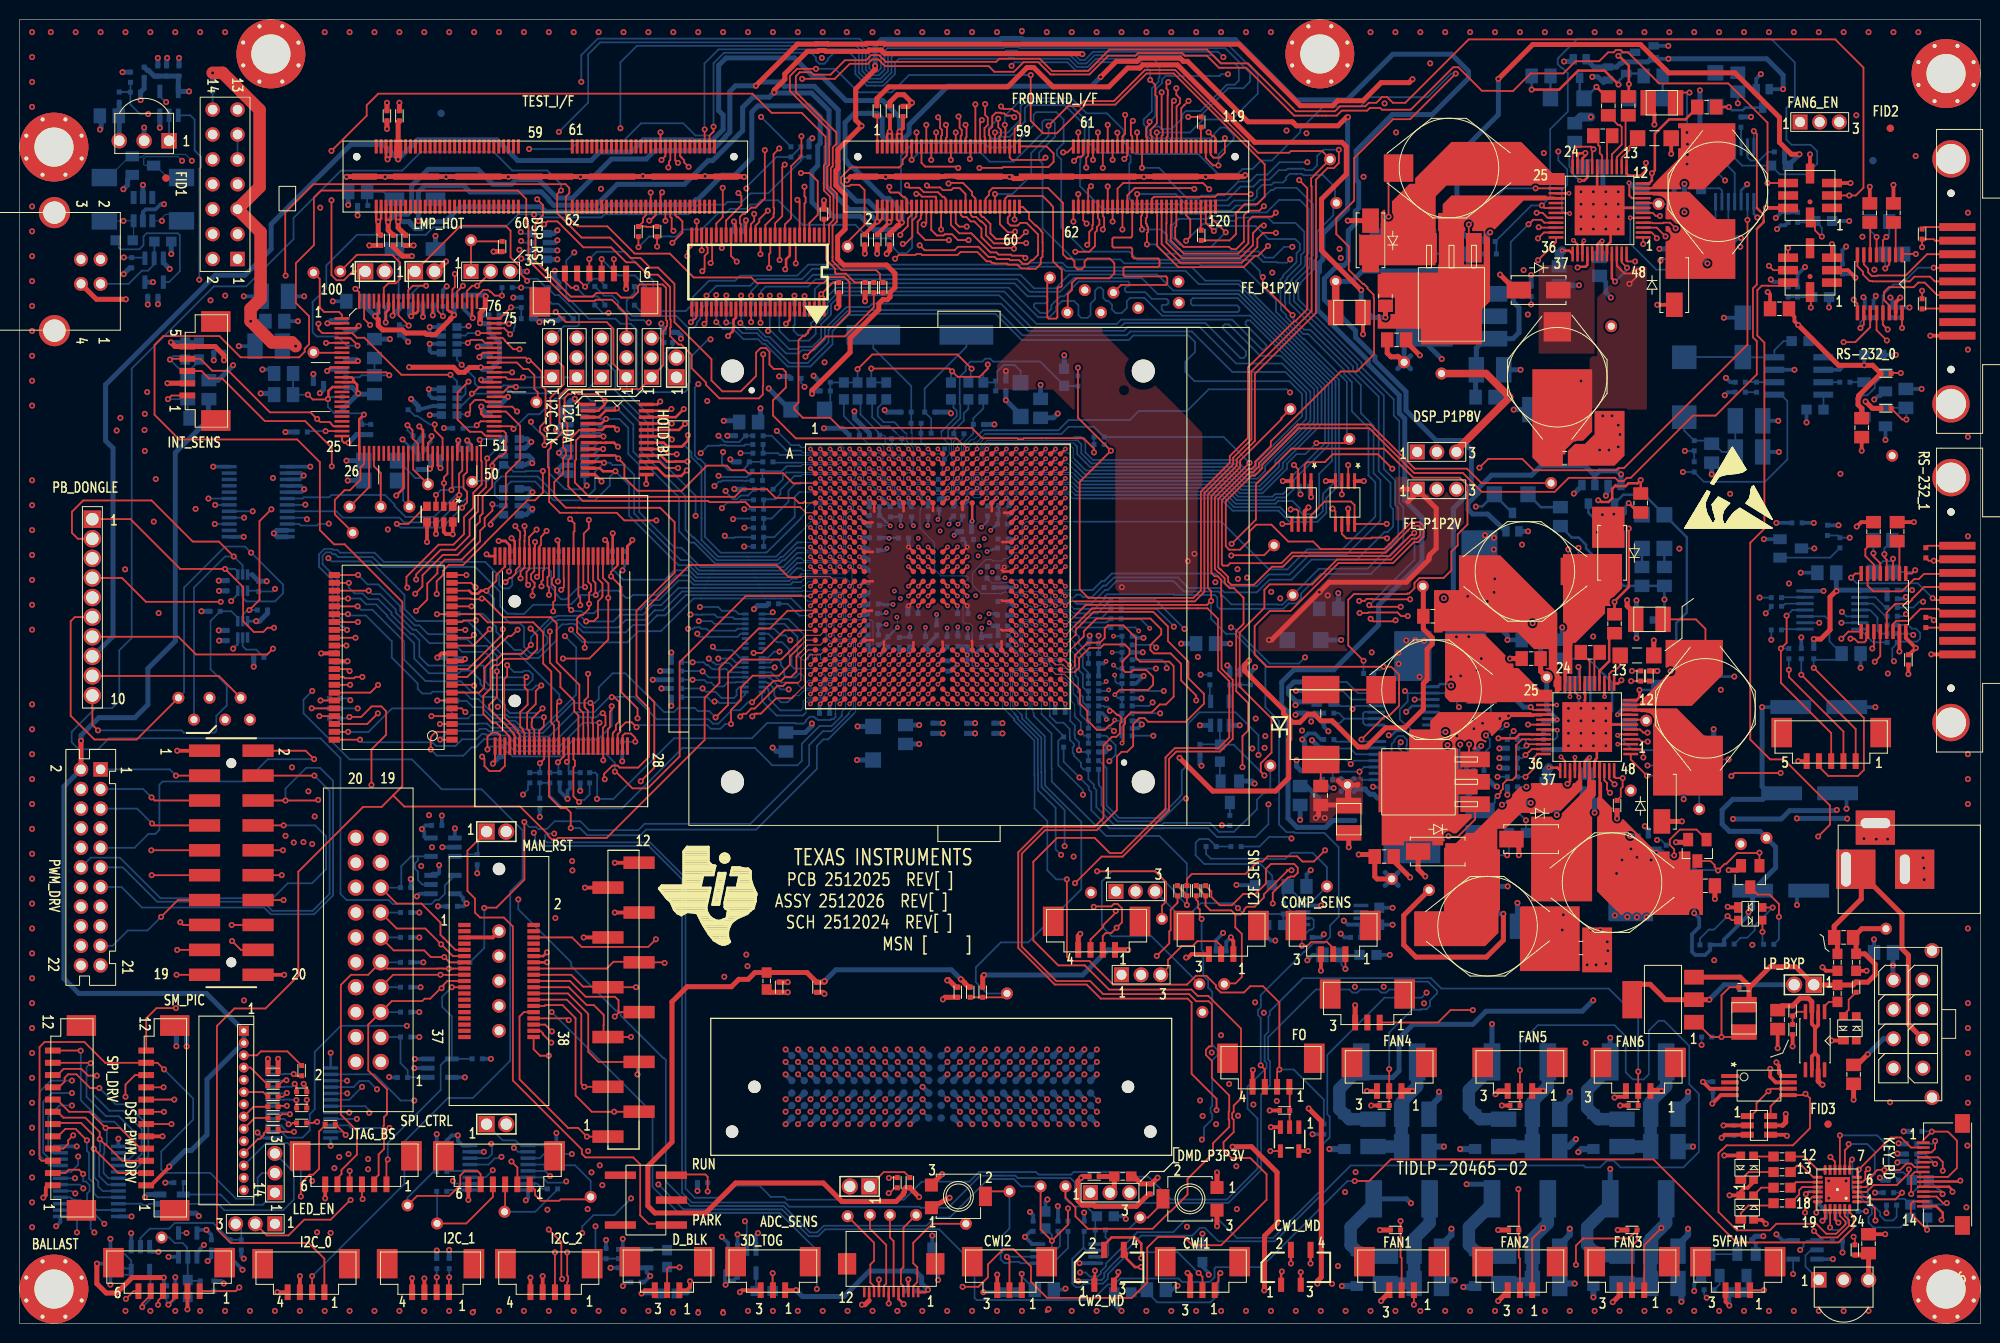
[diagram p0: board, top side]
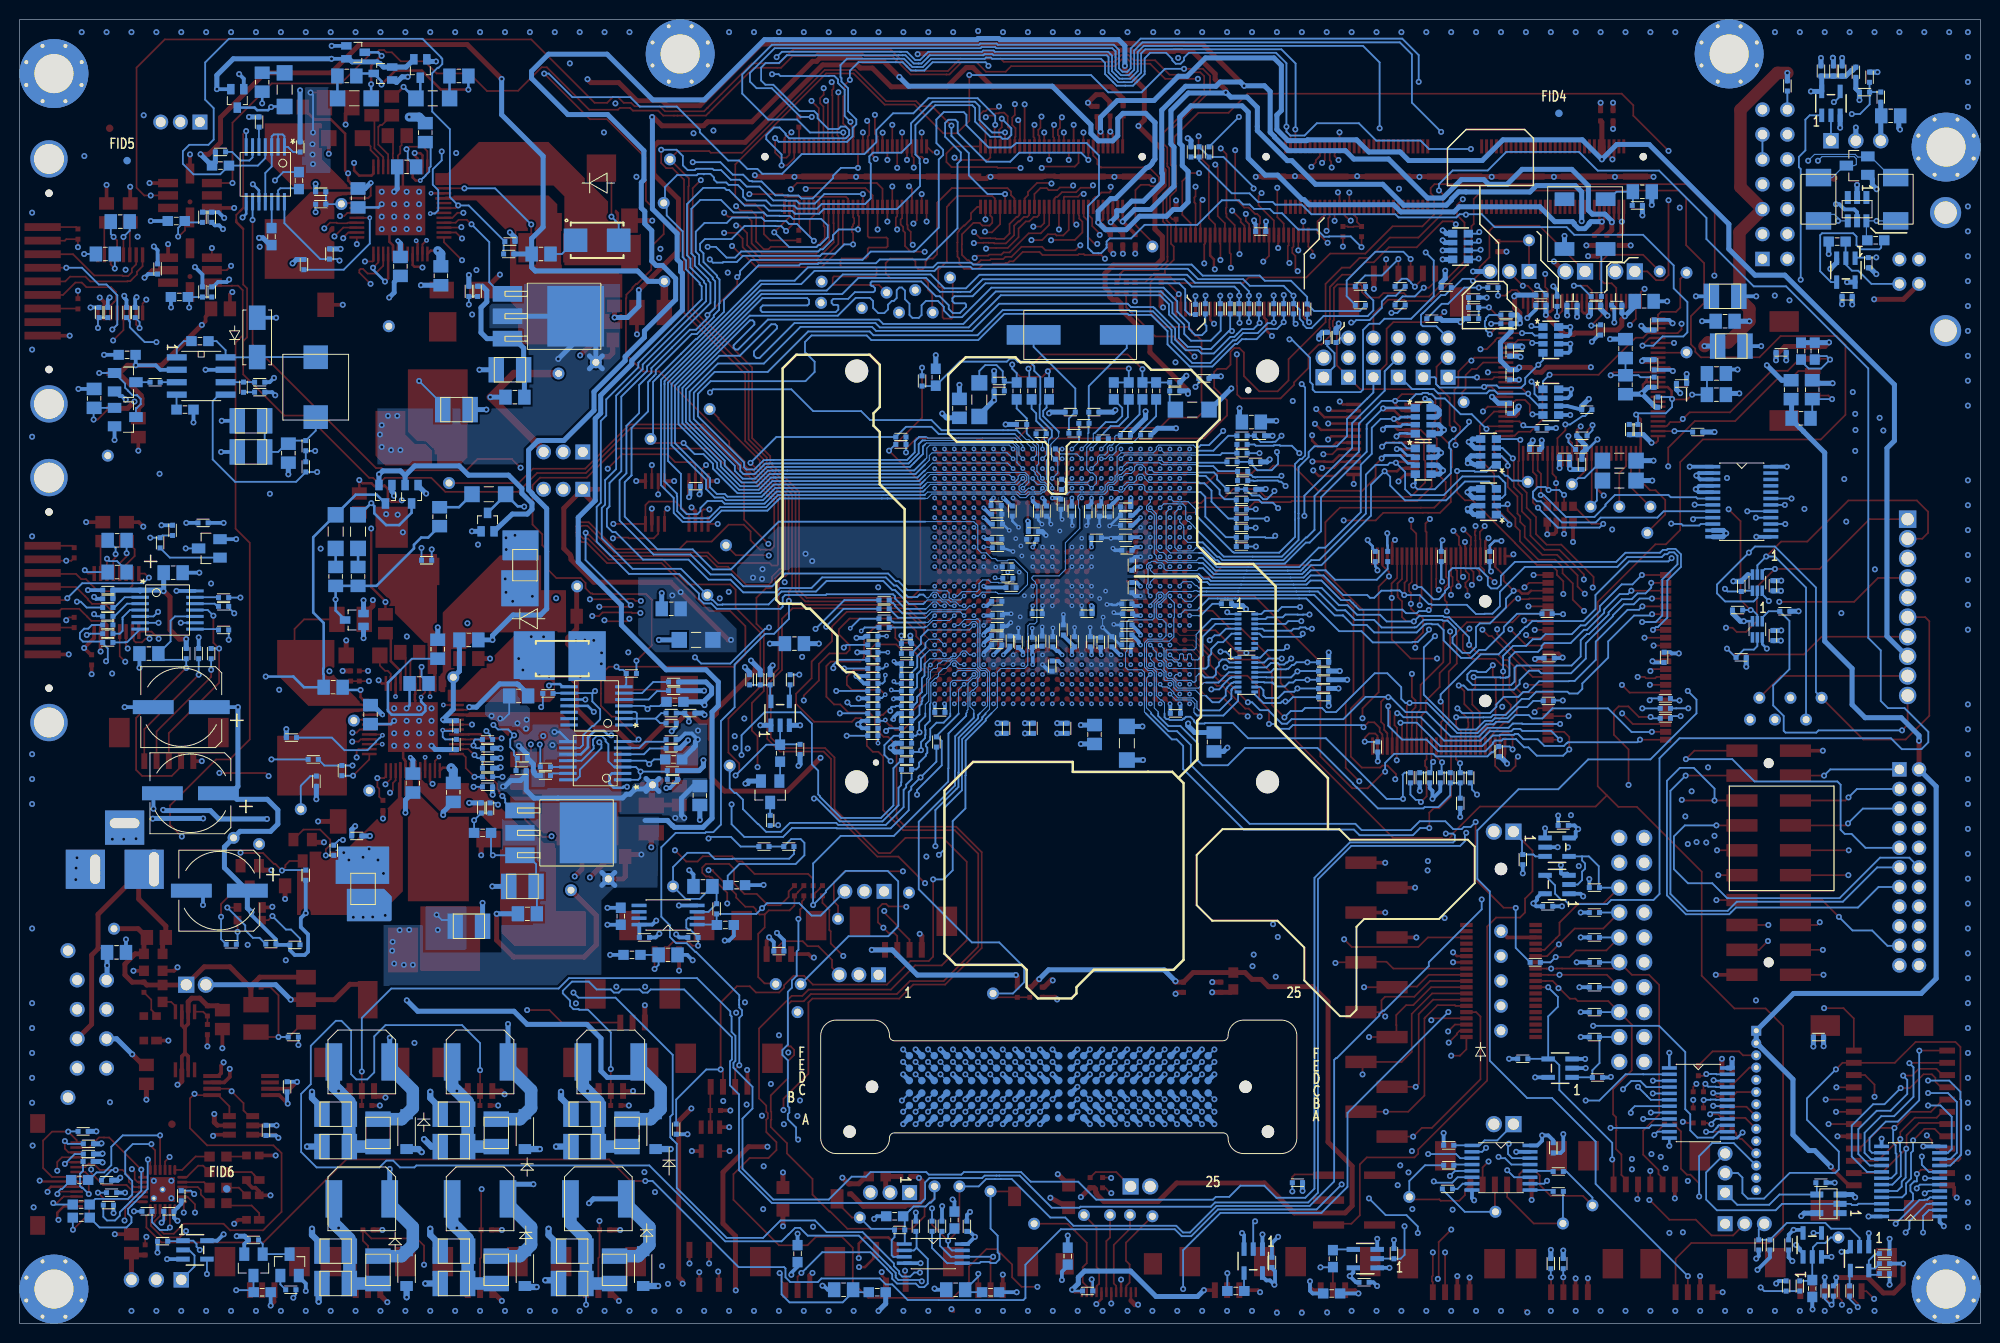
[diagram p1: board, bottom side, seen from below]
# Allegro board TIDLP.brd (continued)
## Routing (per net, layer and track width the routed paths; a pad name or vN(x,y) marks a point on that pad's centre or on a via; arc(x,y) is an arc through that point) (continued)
A1P8V_SENSE: length 52
  TOP w0.254: U15.29 v2(156.83,61.58)
  TOP w0.508: TP40.1 155.14,66.54 C23.2
  LY4 w0.508: v2(156.83,61.58) 154.54,63.88 148.84,63.88 147.83,62.87 147.83,62.85 147.57,62.59 147.57,62.55 147.12,62.1 146.49,62.1 146.49,62.1 145.15,62.1 145.15,62.1 142.19,62.1 142.19,62.06 141.74,61.61 141.12,61.61 140.82,61.92 140.66,62.08 140.66,62.1 140.64,62.1 138.5,64.24 135.68,64.24 134.51,63.07 v1(130.14,63.07)
  BOTTOM w0.508: R633.1 156.73,61.48 v2(156.83,61.58) 155.77,62.65 TP40.1 155.14,66.54 R620.2 ; R639.2 129.99,65.43 129.42,64.86 129.42,64.23 130.14,63.51 v1(130.14,63.07) 130.47,63.4 C642.2
A_BLU_PWM: length 101.3
  TOP w0.178: J24.7 13.7,50.8 v1(13.5,51)
  TOP w0.254: U8.21 v1(66.52,91.8)
  LY3 w0.171: v1(30.1,51.71) 30.1,51.98 29.85,52.23 29.85,53.84 30.05,54.03 30.05,54.53 29.36,55.21 29.36,57.88 29.94,58.45 31.68,58.45 32.49,59.26 32.49,67.39 32.42,67.46 32.42,74.47 32.89,74.95 33.97,74.95 34.29,75.26 34.69,75.26 35.05,75.62 35.05,76.05 35.07,76.05 35.12,76.1 35.12,76.59 34.62,77.1 34.62,77.62 36.08,79.08 37.91,79.08 38.85,80.02 40.38,80.02 40.63,80.27 41.49,81.13 44.51,81.13 44.87,80.77 48.9,80.77 50.61,82.49 53.33,82.49 55,84.16 59.25,84.16 61.07,85.98 61.16,85.98 62.06,86.88 62.06,88.62 62.34,88.89 62.34,88.98 63.08,89.72 63.08,90.41 64.46,91.8 v1(66.52,91.8)
  LY4 w0.171: v1(30.1,51.71) 20.74,51.71 20.02,51 v1(13.5,51)
  BOTTOM w0.178: J23.5 11.98,52.52 v1(13.5,51)
A_GRN_PWM: length 100.2
  TOP w0.178: J24.5 13.76,53.34 v1(13.45,53.65)
  TOP w0.254: v1(67.74,93.27) 66.92,92.45 U8.22
  LY3 w0.171: v1(29.45,54.28) 28.93,54.8 28.93,58.22 29.6,58.88 31.09,58.88 32.14,59.93 32.14,67.24 32.06,67.32 32.06,74.62 32.82,75.38 32.82,75.67 34.06,76.92 34.06,77.71 35.87,79.52 37.73,79.52 38.67,80.45 40.2,80.45 41.33,81.58 47.16,81.58 47.68,82.09 49.46,82.09 51.06,83.69 53.31,83.69 54.14,84.52 58.24,84.52 59.02,85.29 59.6,85.29 59.95,85.64 59.95,85.97 60.31,86.33 61.02,86.33 61.37,86.68 61.37,87.08 61.71,87.42 61.71,88.76 61.98,89.04 61.98,89.13 62.55,89.69 62.55,90.76 64.23,92.45 66.92,92.45 v1(67.74,93.27)
  LY4 w0.171: v1(29.45,54.28) 24.98,54.28 24.36,53.65 v1(13.45,53.65)
  BOTTOM w0.178: J23.3 12.59,54.52 v1(13.45,53.65)
A_LED4_PWM: length 104.1
  TOP w0.178: v1(30.04,57.56) 29.17,58.42 J24.2
  TOP w0.254: v1(67.88,91.77) 67.25,91.15 U8.20
  LY3 w0.171: v1(67.88,91.77) 67.25,91.15 65.01,91.15 62.69,88.83 62.69,88.74 62.42,88.47 62.42,86.73 61.31,85.62 61.22,85.62 59.4,83.81 57.9,83.81 56.75,82.65 56.75,81.63 56.55,81.44 55.19,81.44 54,80.25 52.89,80.25 52.82,80.31 52.03,80.31 51.2,79.49 49.94,79.49 49.31,78.87 48.13,78.87 47.88,79.12 39.17,79.12 38.27,78.22 36.93,78.22 35.83,77.12 35.83,76.39 35.83,76.1 35.83,75.8 35.76,75.73 35.76,75.34 35.85,75.34 36.2,74.99 36.2,74.5 35.85,74.15 35.35,74.15 35,74.5 35,73.73 35.17,73.57 35.17,68.71 34.6,68.14 33.2,68.14 32.85,67.79 32.85,67.3 32.86,67.29 32.86,58.52 31.78,57.44 30.15,57.44 v1(30.04,57.56)
  BOTTOM w0.178: 8.26,48.51 11.72,48.51 13.13,49.93 13.83,49.93 14.25,50.35 14.25,54.95 14.58,55.28 23.04,55.28 25.31,57.56 v1(30.04,57.56)
A_LED5_PWM: length 111.2
  TOP w0.178: J24.4 v1(30.06,55.88)
  TOP w0.254: v1(66.54,90.17) 66.21,90.5 U8.19
  LY3 w0.171: v1(30.06,55.88) 32,55.88 35.31,59.19 35.31,60.92 35.02,61.22 35.02,62.43 35.08,62.49 35.08,64.98 34.36,65.7 34.36,66.19 35.71,67.54 35.71,73.51 36.55,74.35 36.55,75.14 36.19,75.5 36.19,76.25 36.19,76.54 36.19,76.87 37.11,77.79 38.45,77.79 39.33,78.67 46.54,78.67 47.37,77.84 48.23,77.84 48.85,78.46 49.54,78.46 50.14,79.06 54.88,79.06 57.1,81.28 57.1,82.36 58.07,83.33 59.43,83.33 61.36,85.27 61.46,85.27 62.82,86.63 62.82,87.92 64.88,89.98 64.88,90.09 65.28,90.5 66.21,90.5 v1(66.54,90.17)
  BOTTOM w0.178: v1(30.06,55.88) 31.61,54.33 31.61,43.82 29.89,42.09 25.77,42.09 24.84,43.02 14.02,43.02 10.52,46.51 8.26,46.51
A_LED6_PWM: length 122.5
  TOP w0.178: J24.6 v1(27.11,53.34) 30.39,53.34 v1(30.46,53.4)
  TOP w0.254: v1(68.16,90.6) 68.16,90.06 67.54,89.44 66.1,89.44 65.7,89.84 U8.18
  LY3 w0.171: v1(68.16,90.6) 68.16,90.06 67.67,89.57 66.29,89.57 66.01,89.84 65.35,89.84 63.21,87.7 63.21,86.52 61.61,84.91 61.51,84.91 59.58,82.98 58.22,82.98 57.46,82.21 57.46,81.13 57.39,81.06 57.39,80.95 55.06,78.63 50.34,78.63 49.79,78.08 49.13,78.08 48.46,77.41 47.2,77.41 46.37,78.24 41.38,78.24 41.37,78.24 39.51,78.24 38.63,77.36 37.29,77.36 36.55,76.61 36.55,76.39 36.55,75.65 36.91,75.29 36.91,74.2 36.2,73.49 36.2,66.29 35.51,65.61 35.51,61.34 35.75,61.1 35.75,60.57 35.72,60.54 35.72,59.1 30.69,54.07 30.69,53.63 v1(30.46,53.4)
  BOTTOM w0.178: v1(27.11,53.34) 27.11,54.56 29.22,56.67 30.65,56.67 31.97,55.35 31.97,43.67 30.03,41.73 25.62,41.73 25.41,41.94 24.93,42.42 12.48,42.42 10.39,44.51 8.26,44.51
A_LED7_PWM: length 120.3
  TOP w0.178: J24.11 v1(13.46,45.72) ; v1(67.02,88.66) 66.1,88.66 65.57,89.19
  TOP w0.254: 65.57,89.19 U8.17
  LY3 w0.171: v1(67.02,88.66) 65.04,88.66 64,87.62 64,86.69 62.57,85.26 62.55,85.26 59.91,82.62 59.55,82.62 58.83,81.9 57.69,80.76 57.69,80.65 55.81,78.76 55.24,78.2 50.52,78.2 50.02,77.7 49.37,77.7 48.65,76.98 47.01,76.98 46.19,77.81 39.69,77.81 38.81,76.92 37.72,76.92 37.26,76.47 37.26,74.06 36.82,73.61 36.82,66.25 35.94,65.38 35.94,61.52 36.18,61.28 36.18,60.5 36.08,60.4 36.08,58.93 31.05,53.9 31.05,53.65 31.05,53.16 30.69,52.8 30.69,52.5 30.69,51.47 30.34,51.12 28.5,51.12 v1(27.12,49.74)
  LY4 w0.171: 8.26,40.52 11.68,40.52 12.8,39.4 16.72,39.4 17.36,40.03 17.36,41.14 16.74,41.75 16.08,41.75 15.2,40.87 13.47,40.87 12.85,41.49 12.85,45.11 v1(13.46,45.72) 16.07,45.72 17.06,44.73 23.67,44.73 25.82,42.58 27.17,42.58 27.52,42.93 27.52,48.44 27.12,48.84 v1(27.12,49.74)
A_LED8_PWM: length 108.3
  TOP w0.178: J24.13 16.14,43.18 v1(14.43,41.47)
  TOP w0.254: v1(68.13,87.92) 66.92,87.92 66.89,87.89 66.04,87.89 65.39,88.54 U8.16
  LY3 w0.171: v1(68.13,87.92) 68.07,87.98 65.99,87.98 64.61,86.6 64.61,85.41 64.11,84.9 62.7,84.9 60.06,82.27 59.7,82.27 59.19,81.75 58.05,80.61 58.05,80.39 56.24,78.58 55.42,77.76 50.7,77.76 50.25,77.32 49.6,77.32 48.83,76.55 46.84,76.55 46.01,77.37 39.87,77.37 38.99,76.49 37.97,76.49 37.62,76.14 37.62,74.2 37.62,73.91 37.17,73.46 37.17,61.78 36.73,61.34 36.73,60.54 36.43,60.25 36.43,58.78 31.41,53.75 31.41,53.01 31.05,52.65 31.05,50.61 31,50.56 28.67,50.56 27.96,49.85 v1(27.96,49.05)
  LY4 w0.171: v1(14.43,41.47) 17.08,44.12 23.55,44.12 25.45,42.23 27.32,42.23 27.96,42.87 v1(27.96,49.05)
  BOTTOM w0.178: 8.26,38.52 9.47,38.52 11.04,40.08 13.04,40.08 v1(14.43,41.47)
A_RED_PWM: length 92.2
  TOP w0.178: J24.3 v1(15.94,55.88)
  TOP w0.254: v1(66.48,93.28) 66.36,93.28 66.17,93.1 U8.23
  LY3 w0.171: v1(27.77,56.72) 28.46,57.4 28.46,58.24 29.51,59.3 30.94,59.3 31.78,60.14 31.78,67.09 31.71,67.17 31.71,74.77 32.46,75.52 32.46,75.82 33.71,77.07 33.71,77.95 35.7,79.95 37.55,79.95 38.5,80.89 39.83,80.89 40.61,81.67 40.61,81.69 40.96,82.04 46.06,82.04 46.57,82.55 49.3,82.55 50.88,84.12 53.07,84.12 53.82,84.87 58.1,84.87 58.45,85.22 58.45,86.3 58.66,86.51 58.66,86.86 59,87.2 59.86,87.2 60.21,87.55 60.21,88.22 60.82,88.83 61.27,88.83 61.63,89.19 61.63,89.27 62.11,89.76 62.11,90.94 62.14,90.96 62.14,91.1 63.98,92.94 66.15,92.94 v1(66.48,93.28)
  LY4 w0.171: v1(27.77,56.72) 27.7,56.72 27.14,56.16 26.25,56.16 25.11,55.01 16.8,55.01 v1(15.94,55.88)
  BOTTOM w0.178: v1(15.94,55.88) 15.3,56.52 J23.1
A_SPARE_1: length 38.1
  TOP w0.178: J38.2 4.65,15.33 4.99,15.67 6.06,15.67 6.39,15.34 6.39,15.33 v1(6.48,15.24)
  LY3 w0.171: v1(6.48,15.24) 5.79,15.93 5.43,15.93 4.79,16.56 4.79,19.35 5.21,19.77 5.28,19.77 6.46,20.96 6.46,26.39 5.28,27.58 5.28,39.55 6.24,40.52 J23.18
  BOTTOM w0.178: U519.23 7.88,11.55 6.87,12.56 6.87,13.24 7.13,13.5 7.13,14.1 6.74,14.48 6.48,14.48 v1(6.48,15.24)
A_SPARE_2: length 105.7
  TOP w0.178: v1(67.15,87.26) 65.9,87.26 65.27,87.89
  TOP w0.254: 65.27,87.89 U8.15
  LY3 w0.171: v1(67.15,87.26) 66.14,87.26 65.01,86.13 65.01,85.3 64.26,84.55 62.85,84.55 60.21,81.91 59.85,81.91 59.17,81.23 58.4,80.47 58.4,80.14 56.67,78.41 55.61,77.35 51.59,77.35 50.35,76.11 50.35,75.28 50.04,74.98 49.2,74.98 48.06,76.12 46.66,76.12 45.83,76.94 40.05,76.94 39.16,76.06 38.31,76.06 37.97,75.73 37.97,74.35 37.97,74.35 37.97,74.17 37.97,73.88 37.97,73.88 37.97,73.76 37.53,73.31 37.53,61.53 37.16,61.16 37.16,60.47 36.79,60.1 36.79,58.63 31.76,53.61 31.76,52.86 31.4,52.5 31.4,50.46 v1(29.84,48.9)
  LY4 w0.171: J23.22 6.87,36.51 7.85,37.49 9.88,37.49 10.69,36.68 17.54,36.68 18.39,37.53 18.39,40.78 20.23,42.62 22.81,42.62 23.91,41.52 27.61,41.52 29.84,43.75 v1(29.84,48.9)
A_SPARE_3: length 114.9
  TOP w0.254: v1(68.04,87.01) 67.48,86.45 65.84,86.45 65.04,87.24 U8.14
  LY3 w0.171: v1(68.04,87.01) 67.75,87.01 67.4,86.66 66.4,86.66 65.8,86.06 65.8,85.59 64.26,84.05 62.93,84.05 60.43,81.55 59.99,81.55 58.76,80.32 58.76,79.88 55.87,76.99 52.76,76.99 52.17,76.4 52.17,75.91 52.51,75.57 52.51,75.15 52.47,75.11 53.09,74.49 53.09,73.98 51.66,72.55 49.75,72.55 48.45,73.86 48.45,74.75 47.51,75.68 46.14,75.68 45.53,75.07 43.16,75.07 41.72,76.51 40.22,76.51 39.34,75.63 38.97,75.63 38.35,75 38.35,73.74 38.33,73.73 38.33,73.61 37.88,73.17 37.88,59.22 32.12,53.46 32.12,52.71 31.91,52.51 31.76,52.35 31.76,49.97 30.44,48.65 30.06,48.28 29.23,48.28 28.95,48.55 v1(28.95,49.1)
  LY4 w0.171: J23.20 6.87,38.52 7.85,39.49 11.69,39.49 14,37.19 17.34,37.19 17.82,37.67 17.82,41.75 19.5,43.43 23.55,43.43 24.64,42.35 25.11,41.87 27.47,41.87 28.95,43.36 v1(28.95,49.1)
A_SSP0_CLK: length 67.3
  TOP w0.178: R27.2 118.38,44.39 118.38,44.37 118.78,43.97 118.8,43.97 119.06,43.7 R28.2 v1(119.06,42.68) ; U11.AD4 v2(104.66,66.2)
  BOTTOM w0.102: 103.45,62.23 103.36,62.32 103.36,62.51 103.27,62.61 103.27,65.31 102.77,65.81 102.5,65.81 102.27,66.04 102.27,66.36 102.5,66.59 104.27,66.59 v2(104.66,66.2)
  BOTTOM w0.178: 103.45,62.23 103.45,61.98 105.26,60.17 105.26,56.64 105.28,56.62 105.28,55.28 110.83,49.73 116.25,49.73 119.06,46.92 v1(119.06,42.68) 117.77,43.97 117.77,44.13 115.74,46.16 111.46,46.16 110.38,45.09 110.38,40.51 111.4,39.49 115.45,39.49 TP56.1
A_SSP0_TXD: length 73.2
  TOP w0.178: 124,41.71 124,40.39 124.66,39.73 124.66,35.33 124.02,34.68 122.95,34.68 TP57.1 ; 124,41.71 124.54,41.71 124.91,42.09 124.91,42.24 125.17,42.5 125.98,42.5 126.91,43.44 126.91,43.76 129.29,46.14 129.29,46.23 v1(129.73,46.23) ; 124,41.71 123.59,42.13 121.46,42.13 120.97,42.62 R30.2 120.61,43.97 120.61,44.01 120.02,44.6 R29.2 ; U11.AB7 v2(102.66,69.2)
  LY3 w0.171: v1(129.73,46.23) 129.73,48.14 126.31,51.55 126.31,53.02 125.02,54.31 125.02,55.57 125.66,56.21 125.66,56.44 125.69,56.46 125.69,57.14 125.65,57.17 125.65,57.28 124.7,58.24 124.7,59.92 123.85,60.76 123.85,61.26 124.22,61.62 124.22,64.67 122.82,66.07 121.8,66.07 121.5,66.37 121.5,67.06 120.57,67.99 v1(120.18,67.99)
  LY4 w0.102: 107.3,72.25 106.95,72.59 105.5,72.59 105.27,72.36 105.27,72.25 104.83,71.81 104.5,71.81 104.49,71.81 104.18,71.81 103.96,71.59 103.5,71.59 103.19,71.28 103.19,69.72 102.66,69.2 v2(102.66,69.2)
  LY4 w0.171: 107.3,72.25 107.47,72.25 107.88,71.84 111.15,71.84 113.65,69.34 114.89,69.34 115.37,69.82 118.11,69.82 118.23,69.94 118.72,69.94 119.07,69.59 119.07,69.1 v1(120.18,67.99)
ADC_CSZ: length 149.5
  TOP w0.178: TP62.1 87.15,8.23 87.15,6.38 86.77,6 86.77,4.16 87.11,3.82 87.11,3.65 87.15,3.61 J59.10
  LY3 w0.171: v1(117.73,71.07) 118.55,70.25 119.06,70.25 119.58,69.73 119.58,68.88 119.21,68.51 119.21,68.08 120.51,66.78 120.72,66.78 121.07,66.43 121.07,66.19 121.62,65.64 122.64,65.64 123.78,64.49 123.78,61.69 123.49,61.41 123.49,60.62 124.34,59.77 124.34,57.98 125.28,57.04 125.33,56.99 125.33,56.61 125.31,56.58 125.31,56.47 124.66,55.83 124.66,54.06 125.88,52.84 125.88,51.37 126.14,51.12 129.13,48.12 129.13,47.76 129.13,45.98 129.48,45.63 129.98,45.63 130.33,45.98 130.33,48.32 131.38,49.36 133.76,49.36 135.63,47.5 135.63,47.43 137.03,46.04 137.03,44.42 139.77,41.68 140.54,41.68 141.62,40.6 141.62,32.25 141.8,32.07 141.8,24.89 141.04,24.13 141.04,23.26 131.17,13.39 125.9,13.39 v1(124.16,11.65)
  LY4 w0.171: v1(124.16,11.65) 121.36,11.65 119.67,9.96 119.67,9.61 119.32,9.26 116.23,9.26 115.7,8.73 106.43,8.73 105.53,9.63 104.36,9.63 103.9,10.09 97.65,10.09 96.87,9.31 96.17,9.31 95.3,10.18 85.2,10.18 TP62.1
  BOTTOM w0.178: R623.1 115.95,72.9 117.73,71.12 v1(117.73,71.07)
ADC_RST/COMP_PWM: length 141.8
  TOP w0.178: TP66.1 93.09,10.16 91.15,8.22 91.15,6.14 91.56,5.72 91.56,4.2 91.15,3.79 91.15,3.17
  LY3 w0.171: v1(119.07,9.86) 119.51,10.29 120.79,10.29 121.12,10.63 129.7,10.63 134.76,15.7 134.76,15.94 141.47,22.64 141.47,23.95 142.23,24.71 142.23,32.14 141.97,32.4 141.97,41.69 140.36,43.31 138.75,43.31 137.39,44.68 137.39,46.18 135.99,47.58 135.99,48.08 136.34,48.43 136.34,48.65 135.26,49.73 130.95,49.73 130.88,49.8 130.06,49.8 v1(129.73,49.47) 129.73,49.96 128.68,51.01 127.72,51.01 126.75,51.98 126.75,53.23 125.37,54.6 125.37,55.32 126.02,55.96 126.02,56.29 126.04,56.31 126.04,57.28 126.01,57.32 126.01,57.49 125.77,57.74 125.77,57.77 125.05,58.49 125.05,61.64 124.65,62.04 124.65,64.85 123,66.5 121.98,66.5 121.93,66.55 121.93,67.73 119.94,69.73 119.94,69.95 119.08,70.8 118.86,70.8 v1(118.82,70.85)
  LY4 w0.171: v1(119.07,9.86) 116.05,9.86 115.44,9.25 106.42,9.25 105.68,9.99 104.51,9.99 103.72,10.77 102.81,10.77 102.55,11.04 99.75,11.04 99.49,11.29 97.65,11.29 TP66.1
  BOTTOM w0.178: R708.2 126.45,48.64 127.44,49.62 129.57,49.62 v1(129.73,49.47) ; R622.1 115.87,73.79 118.81,70.85 v1(118.82,70.85)
ADC_SCLK: length 114.2
  TOP w0.178: J59.4 90.15,3.78 90.11,3.82 90.11,3.82 89.92,4.02 89.91,4.02 89.89,4.04 89.89,5.48 90.15,5.74 90.15,9.76 TP65.1
  LY3 w0.171: v2(115.27,70.91) 115.27,70.14 115.27,70.13 115.27,69.71 115.22,69.67 115.22,68.69 115.27,68.64 115.27,67.19 114.72,66.64 114.4,66.64 114.05,66.29 114.05,65.32 114.22,65.14 114.22,64.4 113.83,64 113.83,63.51 114.22,63.11 114.22,62.19 115.07,61.35 115.07,60.85 114.96,60.74 114.96,57.99 116.55,56.39 116.55,56.31 116.61,56.02 116.61,55.05 116.53,54.66 116.38,54.3 116.17,53.98 116.17,53.78 116.08,53.56 116.17,53.34 116.17,52.43 116.64,51.96 116.64,48.26 120.69,44.21 120.69,43.36 120.8,43.24 120.8,41.86 120.81,41.85 121.16,41.5 121.16,40.66 120.76,40.27 120.76,39.29 122.15,37.91 122.21,35.91 122.66,35.46 123.23,35.46 123.72,34.96 123.72,34.25 122.66,33.19 122.66,31.6 122.9,31.36 122.9,31.35 123.35,30.91 123.44,30.82 123.44,30.82 123.53,30.73 123.74,30.52 124.19,30.06 124.19,26.88 123.3,25.99 122.33,25.99 121.9,25.57 121.9,22.43 121.36,21.88 121.36,19.79 121.87,19.28 121.87,18.26 v1(124.11,16.02)
  LY4 w0.171: v1(124.11,16.02) 124.11,15.37 119.86,11.12 116.13,11.12 114.94,9.93 106.7,9.93 105.96,10.67 104.83,10.67 103.17,12.33 102.5,12.33 101.9,11.72 100.03,11.72 99.77,11.99 95.04,11.99 94.1,11.05 TP65.1
  BOTTOM w0.178: R624.1 114.3,71.88 v2(115.27,70.91)
ADC_SDIN: length 91.2
  TOP w0.178: J59.6 89.15,8.38 88.77,8.76 TP64.1
  LY3 w0.171: TP64.1 87.77,12.05 83.79,12.05 83.21,11.47 83.21,9.65 84.36,8.51 92.69,8.51 92.84,8.36 92.98,8.36 93.1,8.23 98.46,8.23 99.91,9.68 101.48,9.68 101.73,9.92 103.24,9.92 103.36,9.79 115.28,9.79 115.96,10.48 115.96,11.3 117.06,12.4 117.06,12.4 117.82,13.16 118.95,13.16 119.94,14.15 119.94,22.08 118.54,23.48 118.54,36.31 117.55,37.3 117.55,37.89 117.35,38.09 117.35,39.93 116.86,40.42 116.17,40.42 115.71,40.89 113.85,40.89 111.82,42.92 J26.1
ADC_SDO: length 74.9
  TOP w0.178: TP63.1 86.74,9.65 88.39,8 88.39,4.06 88.15,3.82 J59.8
  LY3 w0.171: TP63.1 88.12,9.67 93.22,9.67 93.84,9.05 97.08,9.05 98.56,10.53 109.24,10.53 110.36,11.65 115.8,11.65 117.51,13.36 117.67,13.52 118.45,13.52 119.58,14.65 119.58,21.94 118.19,23.34 118.19,36.16 117.2,37.15 117.2,37.74 116.63,38.3 115.14,38.3 J34.1
ADCINA0: length 26.1
  TOP w0.178: U7.23 32.01,91.52 31.78,91.75 31.78,91.79 31.62,91.95 30.67,91.95 v1(30.35,92.27) 30.33,92.27 29.65,92.94 25.53,92.94 21.29,97.18 19.65,97.18 18.42,98.41 J11.4 15.41,98.41 v1(15.33,98.32)
  BOTTOM w0.178: C539.1 16.54,98.68 15.68,98.68 v1(15.33,98.32) 16.24,97.41 17.51,97.41 18.29,98.18 R572.1
ADCLO: length 3.6
  TOP w0.178: U7.24 v1(31.2,91.02)
  BOTTOM w0.178: R586.2 29.44,91.02 v1(31.2,91.02)
ADCREFM: length 8.7
  TOP w0.178: U7.36 39.64,83.42 TP27.1
  BOTTOM w0.178: TP27.1 39.12,83.95 39.12,85.41 C575.1
ADCREFP: length 7.9
  TOP w0.178: U7.37 40.14,87.11 TP28.1
  BOTTOM w0.178: TP28.1 41.02,86.23 40.39,86.23 38.61,88.01 C574.1
ADCRESEXT: length 4.6
  TOP w0.178: v1(39.56,91.63) 40.07,91.12 40.07,90.3 40.64,89.73 U7.38
  BOTTOM w0.178: R583.1 39.56,91.11 v1(39.56,91.63)
AFE_CLK: length 8.1
  TOP w0.178: U11.AD12 v2(104.66,74.2)
  BOTTOM w0.102: R604.2 98.68,75.88 98.79,75.88 99.13,75.54 100.13,75.54 100.18,75.59 100.92,75.59 101.17,75.84 101.77,75.84 102.14,75.47 102.14,74.86 102.35,74.65 103.87,74.65 104.32,74.2 v2(104.66,74.2)
AFE_RSTZ: length 195.7
  TOP w0.178: v1(63.13,109.79) 63.13,109.8 63.12,109.8 R8.1 ; v1(126.81,106.74) 126.81,105.9 v1(129.84,102.86) ; U11.AC12 v2(103.66,74.2) ; v1(118.99,110.44) 119.4,110.86 119.4,112.62 118.99,113.04 J3.108
  BOTTOM w0.102: v2(103.66,74.2) 104.06,73.81 104.83,73.81 104.98,73.96 105.09,73.96 105.19,74.06 105.19,74.54 105.39,74.73 106.33,74.73 106.41,74.81 107.63,74.81
  BOTTOM w0.178: v1(118.99,110.44) 120.7,112.16 121.51,112.16 121.81,112.45 122.69,112.45 122.71,112.47 123.99,112.47 124.32,112.81 127.33,112.81 127.87,112.26 130.14,112.26 131.04,111.37 131.04,109.33 130.69,108.98 130.69,108.09 129.3,106.7 129.3,106.56 129.05,106.31 129.05,104.25 129.09,104.21 129.09,103.58 129.84,102.83 ; 129.84,102.83 129.84,102.54 130.6,101.78 131.01,101.37 131.63,101.37 133.46,99.55 135.56,97.44 135.56,96.98 136.81,95.73 136.81,92.86 138.11,91.56 138.11,86.72 138.8,86.03 138.8,81.89 135.34,78.43 131.56,78.43 129.52,76.4 127.39,76.4 126.18,75.19 123.23,75.19 122.77,75.65 121.93,76.49 111.41,76.49 110.62,75.71 110.36,75.71 109.45,74.81 107.63,74.81 ; 129.84,102.83 v1(129.84,102.86) ; v1(126.81,106.74) 126.78,106.74 126.51,107 126.51,107.35 125.37,108.49 118.68,108.49 118.67,108.5 114.02,108.5 113.19,109.34 108.79,109.34 108.73,109.39 108.64,109.39 106.25,111.78 106.25,118.74 105.8,119.19 105.8,119.72 106.49,120.41 106.49,122.15 106.49,122.16 106.49,122.81 105.74,123.56 103.7,123.56 103.42,123.29 103.42,122.23 101.16,119.96 98.88,119.96 98.33,120.41 91.17,120.41 89.9,119.14 89.9,115.11 91.03,113.98 91.03,109.73 90.68,109.38 90.47,109.17 89.98,109.17 89.68,109.17 89.13,109.73 89.13,109.77 89.13,110.37 88.81,110.68 86.64,110.68 85.25,112.07 79.87,112.07 77.37,114.57 75.62,114.57 75.19,114.14 74.54,114.14 74.09,113.7 72.49,113.7 72.04,113.25 71.23,113.25 69.57,111.59 67.67,111.59 66.93,110.86 66.44,110.86 66.41,110.89 64.23,110.89 v1(63.13,109.79)
ALF_CLAMP: length 102.5
  TOP w0.178: v1(121.82,111.44) 120.99,112.27 J3.116 ; U11.AB12 v2(102.66,74.2)
  BOTTOM w0.102: 107.63,81.79 102.68,81.79 102.43,81.53 102.4,81.53 102.3,81.43 102.3,81.39 102.27,81.36 102.27,78.99 102.26,78.98 102.26,78.95 101.91,78.6 101.4,78.6 100.82,78.02 100.47,78.02 100.33,77.88 100.26,77.79 99.27,77.79 99.16,77.9 98.53,77.9 97.19,76.57 97.19,75.37 98.12,74.44 100.18,74.44 100.19,74.44 100.26,74.51 100.32,74.55 100.39,74.58 100.42,74.59 100.44,74.59 100.46,74.59 100.46,74.59 101.83,74.59 102.22,74.2 102.32,74.2 102.35,74.2 102.35,74.2 v2(102.66,74.2)
  BOTTOM w0.178: v1(121.82,111.44) 122.31,111.93 122.9,111.93 122.92,111.95 126.06,111.95 127.39,110.61 130.12,110.61 130.59,110.14 130.59,109.51 130.25,109.17 130.25,108.27 128.86,106.89 128.86,106.74 128.61,106.49 128.61,104.06 128.65,104.02 128.65,103.39 129.2,102.84 129.2,102.65 130.93,100.92 131.45,100.92 135.11,97.26 135.11,96.84 135.29,96.67 135.29,96.65 135.74,96.2 135.74,96.17 135.9,96.01 135.9,93.04 137.59,91.35 137.59,86.51 138.28,85.81 138.28,82.3 134.93,78.95 131.34,78.95 129.31,76.92 127.44,76.92 122.57,81.79 107.63,81.79
ALF_COAST: length 106.5
  TOP w0.178: U11.AC11 v2(103.66,73.2) ; J3.118 121.49,112.84 v1(123.03,111.3)
  BOTTOM w0.102: v2(103.66,73.2) 104.11,73.2 104.51,73.6 105.02,73.6 105.22,73.81 105.83,73.81 106.27,74.25 106.27,74.36 106.5,74.59 106.83,74.59 107.06,74.36 107.06,74.28 107.32,74.02 107.49,74.02 107.63,74.16
  BOTTOM w0.178: v1(123.03,111.3) 123.01,111.3 121.5,109.8 118.72,109.8 118.51,110.01 118.36,110.01 117.57,110.81 117.57,112.01 118.24,112.68 121.12,112.68 121.41,112.97 122.47,112.97 122.49,113 123.77,113 124.1,113.33 127.18,113.33 128.46,114.61 130.57,114.61 131.48,113.7 131.48,109.14 131.13,108.8 131.13,107.9 129.75,106.52 129.75,106.37 129.54,106.17 129.54,104.09 136,97.63 136,97.16 138.63,94.54 138.63,86.94 139.83,85.73 139.83,83.34 140.1,83.08 140.1,81.3 139.53,80.73 139.22,80.73 136.41,77.91 131.77,77.91 129.73,75.87 127.49,75.87 126.19,74.57 122.88,74.57 122.44,75.01 119.23,75.01 118.14,76.1 111.64,76.1 110.81,75.27 110.54,75.27 109.37,74.1 108.45,74.1 108.2,74.35 107.82,74.35 107.63,74.16
ALF_CSYNC: length 133.2
  TOP w0.178: U11.AE11 v2(105.66,73.2) ; J3.49 v1(99.49,121.49)
  BOTTOM w0.102: 107.63,72.89 107.54,72.89 106.84,73.59 106.5,73.59 106.11,73.2 v2(105.66,73.2)
  BOTTOM w0.178: 107.63,72.89 109.64,72.89 110.71,73.95 110.71,74.18 110.91,74.38 117.7,74.38 117.77,74.3 121.91,74.3 122.17,74.05 122.17,73.13 122.4,72.9 128.91,72.9 129.45,73.44 130.21,73.44 130.71,73.94 130.71,74.45 132.72,76.46 137.85,76.46 141.14,79.75 141.14,83.29 140.72,83.71 140.72,92.06 140.16,92.62 140.16,94.26 136.89,97.53 136.89,98 130.43,104.46 130.43,105.8 130.64,106.01 130.64,106.15 132.02,107.54 132.02,108.43 132.37,108.77 132.37,111.4 134,113.03 134,113.99 TP2.1 134.17,114.43 134.17,115.91 132.94,117.14 132.09,117.14 132.07,117.13 130.93,117.13 130.79,117.27 130.26,117.27 130.21,117.22 130.16,117.27 129.54,117.27 129.17,116.89 129.17,116.68 128.87,116.39 127.93,116.39 127.68,116.15 126.75,116.15 126.21,115.6 126.21,114.93 125.83,114.56 123.86,114.56 123.34,114.04 122.06,114.04 122.04,114.01 120.98,114.01 120.69,113.72 118.67,113.72 118.2,114.19 113.76,114.19 113.18,114.77 113.18,118.32 113.33,118.46 113.33,119.06 112.95,119.43 110.07,119.43 109.07,120.43 109.07,122.43 106.87,124.63 102.55,124.63 102.09,124.17 102.09,122.78 100.8,121.49 v1(99.49,121.49)
ALF_HSYNC: length 132.4
  TOP w0.178: U11.AD11 v2(104.66,73.2) ; J3.51 99.94,120.11 99.94,121.09 100.1,121.24 100.1,121.74 99.82,122.02 v1(99.82,122.9)
  BOTTOM w0.102: 107.63,73.58 107.41,73.8 106.1,73.8 105.91,73.6 105.51,73.6 105.11,73.2 v2(104.66,73.2)
  BOTTOM w0.178: 107.63,73.58 107.82,73.39 109.29,73.39 110.73,74.82 110.99,74.82 111.91,75.74 117.69,75.74 118.77,74.66 122.29,74.66 123.61,73.34 128.3,73.34 128.32,73.32 128.82,73.32 129.3,73.8 129.36,73.8 TP32.1 132.54,76.98 137.48,76.98 140.62,80.12 140.62,83.18 140.28,83.53 140.28,86.02 139.15,87.15 139.15,94.64 136.45,97.35 136.45,97.81 129.98,104.27 129.98,105.98 130.19,106.19 130.19,106.33 131.58,107.72 131.58,108.61 131.92,108.96 131.92,114.18 130.27,115.84 128.11,115.84 127.9,115.62 127.64,115.62 126.05,114.03 124.07,114.03 123.56,113.52 122.28,113.52 122.25,113.49 121.2,113.49 120.9,113.2 118.46,113.2 117.98,113.67 110.5,113.67 108.16,116.02 108.16,118.29 108.2,118.33 108.2,118.82 108.63,119.25 108.63,122.24 106.6,124.27 102.83,124.27 102.54,123.98 102.54,122.6 100.99,121.05 99.95,121.05 99.75,120.85 99.22,120.85 98.85,121.23 98.85,121.92 v1(99.82,122.9)
ALF_VSYNC: length 111.6
  TOP w0.102: v2(106.66,73.2) 107.12,73.65 107.63,73.65
  TOP w0.178: U11.AF11 v2(106.66,73.2) ; 107.63,73.65 119.57,73.65 119.87,73.65 120.85,74.63 120.85,84.7 120.89,84.74 123.79,87.64 123.79,88.32 125.64,90.17 125.64,97.13 131.79,103.28 131.79,115.99 131.74,116.04 131.74,116.81 TP1.1 133.67,118.79 132.86,119.6 129.67,119.6 129.5,119.42 126.32,119.42 117.88,127.86 114.79,127.86 111.61,124.69 108.56,124.69 108.05,124.18 106.94,124.18 v1(104.96,122.19) ; J3.50 v1(99.49,115.21)
  BOTTOM w0.178: v1(99.49,115.21) 101.27,115.21 103.18,117.12 103.18,119.38 104.96,121.16 v1(104.96,122.19)
BLU_LED_EN: length 197.2
  TOP w0.178: U7.71 49.27,100.52 49.5,100.29 49.5,100.23 50.36,99.38 v1(50.99,99.38)
  LY3 w0.171: v1(50.99,99.38) 50.99,99.38 52.27,100.67 52.27,102.59 52.35,102.66 52.35,102.69 52.7,103.04 52.72,103.04 53.39,103.7 53.39,109.17 52.14,110.42 v1(51.15,110.42) ; J45.1 28.27,7.93 31.81,7.93 32.32,8.44 32.32,9.62 31.7,10.24 28.59,10.24 26.92,11.91 20.95,11.91 19.41,13.45 19.41,29.23 19.4,29.23 19.4,30.33 24.43,35.36 24.43,43.43 24.43,43.44 24.43,43.87 24.35,43.96 24.35,44.41 23.72,45.04 23.72,47.31 23.72,59.31 26.31,61.91 26.31,65.57 26.63,65.89 26.63,67.34 27.48,68.19 27.48,76.46 27.23,76.72 27.23,81.51 26.98,81.75 26.98,83.59 26.44,84.14 26.44,86.49 25.82,87.1 25.82,109.01 30.64,113.82 v1(30.66,113.82)
  LY4 w0.171: v1(30.66,113.82) 30.66,114.9 31.64,115.87 45.63,115.87 51.08,110.42 v1(51.15,110.42) ; J45.1 26.04,9.9 24.92,8.78 23.95,8.78 23.79,8.94 20.49,8.94 19.3,10.13 17.63,10.13 17.37,10.4 13.83,10.4 12.39,11.83 11.02,11.83 9.28,13.57 7.59,13.57 6.72,14.44 6.01,14.44 v1(5.64,14.8)
  BOTTOM w0.178: RN500.3 51.32,110.25 v1(51.15,110.42) ; U519.7 v1(5.64,14.8)
BLU_PWM: length 44
  TOP w0.178: U11.C20 v2(82.66,83.2)
  TOP w0.254: v1(59.82,92.27) 59.35,91.8 U8.4
  BOTTOM w0.102: 79.69,78.6 82.62,78.6 83.06,79.04 83.06,82.75 82.66,83.14 v2(82.66,83.2)
  BOTTOM w0.178: 79.69,78.6 79.34,78.6 77.89,77.15 74.68,77.15 74.68,77.15 70.8,77.15 69.47,77.15 67.49,79.13 66.82,79.13 63.2,82.75 63.2,87.58 62.08,88.71 62.08,91.36 61.17,92.27 v1(59.82,92.27)
  BOTTOM w0.254: v1(59.82,92.27) 59.31,92.27 59.12,92.46 58.45,92.46 58.43,92.47 RN502.2
BT656_A_CLK: length 99.9
  TOP w0.178: U4.5 80.05,111.03 80.05,114.24 80.17,114.36 80.17,114.86 80.05,114.98 v1(80.05,115.96) ; J3.94 115.49,114.71 115.71,114.93 121.94,114.93 122.21,115.2 v1(125.56,115.2)
  LY3 w0.171: v1(125.56,115.2) 125.63,115.26 125.63,118.88 124.47,120.04 124.14,120.04 124.11,120.05 123.81,120.05 123.79,120.04 122.31,120.04 121.96,120.4 121.96,121.77 120,123.72 120,124.15 120.17,124.32 120.33,124.49 120.74,124.49 124.17,121.06 124.8,121.06 125.06,121.31 125.06,121.74 123.84,122.96 123.84,122.97 117.89,128.92 108.69,128.92 108.65,128.88 108.16,128.88 107.93,129.11 85.53,129.11 79.54,123.11 79.54,122.3 79,121.76 79,117.7 78.32,117.02 78.32,114.38 78.83,113.87 79.59,113.87 80.05,114.33 v1(80.05,115.96)
BT656_A_D0: length 99.5
  TOP w0.178: v1(68.11,108.88) 68.11,109.4 68.55,109.84 68.55,111.01 U4.28 ; J3.105 118.49,123.97 118.81,124.29 118.81,124.29 v1(119.23,124.71)
  LY3 w0.171: v1(119.23,124.71) 119.23,126.26 117.62,127.87 103.45,127.87 103.38,127.94 102.88,127.94 102.81,127.87 101.61,127.87 101.43,127.69 100.93,127.69 100.75,127.87 88.7,127.87 88.11,127.28 85.1,127.28 81.46,123.63 81.46,117.49 80.99,117.02 80.99,113.92 78.45,111.38 78.06,111.38 77.38,112.07 76.99,112.07 76.71,111.79 76.71,111.4 77.4,110.72 77.4,110.33 77.18,110.11 75.1,110.11 74.54,109.55 74.54,108.66 75.01,108.18 75.01,106.29 74.43,105.71 73.09,105.71 72.76,105.38 72.76,103.96 72.5,103.71 68.11,103.71 67.37,104.44 67.37,105.23 67.91,105.77 70.59,105.77 71.77,106.95 73.23,106.95 74.17,107.89 74.17,108.74 73.57,109.35 72.72,109.35 72.05,108.68 71.14,108.68 70.88,108.94 70.3,108.94 70.04,108.68 68.8,108.68 68.59,108.88 v1(68.11,108.88)
BT656_A_D1: length 100.8
  TOP w0.178: v1(126.91,113.97) 126.46,113.52 125.35,113.52 124.88,113.04 124.88,110.37 124.09,109.58 123.61,109.58 123.37,109.83 118.73,109.83 117.88,110.69 117.88,111.85 117.99,111.96 J3.104 ; v1(69.57,109.46) 69.57,111.01 U4.26
  LY3 w0.171: v1(69.57,109.46) 71.02,109.46 71.38,109.11 71.87,109.11 72.22,109.46 72.22,109.9 73.7,111.38 75.47,111.38 77.28,113.18 77.28,118.16 76.85,118.59 76.85,121.77 85.16,130.08 86.29,130.08 86.31,130.06 87.68,130.06 87.7,130.08 88.83,130.08 88.85,130.06 90.22,130.06 90.24,130.08 91.37,130.08 91.39,130.06 92.76,130.06 92.78,130.08 93.91,130.08 93.93,130.06 95.3,130.06 95.32,130.08 96.45,130.08 96.47,130.06 97.84,130.06 97.86,130.08 98.99,130.08 99.01,130.06 100.38,130.06 100.4,130.08 104.07,130.08 104.09,130.06 105.46,130.06 105.48,130.08 106.61,130.08 106.63,130.06 108,130.06 108.02,130.08 108.65,130.08 108.84,129.89 118.25,129.89 126.91,121.23 v1(126.91,113.97)
BT656_A_D2: length 101.1
  TOP w0.178: J3.103 117.99,120.73 118.01,120.76 118.01,124.14 118.35,124.48 118.35,124.98 117.99,125.35 v1(117.99,126.01) ; v1(70.48,108.18) 70.64,108.34 70.64,109.91 70.56,109.99 70.56,111.02 U4.24
  LY3 w0.171: v1(70.48,108.18) 70.55,108.24 71.74,108.24 71.74,108.25 72.23,108.25 72.9,108.91 73.39,108.91 73.74,108.56 73.74,108.07 73.06,107.38 71.59,107.38 70.41,106.2 67.15,106.2 66.5,105.55 66.5,104.41 67.63,103.28 76.95,103.28 78.13,104.46 78.13,105.09 75.68,107.54 75.68,108.13 74.97,108.84 74.97,109.33 75.32,109.68 77.46,109.68 81.51,113.73 82.3,113.73 82.65,114.08 82.65,116.05 81.89,116.82 81.89,123.38 85.31,126.8 88.44,126.8 89.15,127.51 100.61,127.51 100.79,127.33 102.3,127.33 102.88,126.75 103.38,126.75 104.14,127.51 108.34,127.51 109.33,126.52 111.09,126.52 112.08,127.51 117.17,127.51 117.99,126.7 v1(117.99,126.01)
BT656_A_D3: length 100.6
  TOP w0.178: v1(71.63,109.71) 71.63,110.12 71.6,110.14 71.6,110.98 U4.22 ; v1(128.14,113.31) 127.73,112.9 125.77,112.9 125.34,112.47 125.34,110.18 124.28,109.13 118.76,109.13 117.42,110.47 117.42,112.04 117.49,112.1 J3.102
  LY3 w0.171: v1(128.14,113.31) 128.14,120.72 118.53,130.33 108.9,130.33 108.8,130.43 107.87,130.43 107.86,130.42 106.77,130.42 106.76,130.43 105.33,130.43 105.32,130.42 104.23,130.42 104.22,130.43 100.25,130.43 100.24,130.42 99.15,130.42 99.14,130.43 97.71,130.43 97.7,130.42 96.61,130.42 96.6,130.43 95.17,130.43 95.16,130.42 94.07,130.42 94.06,130.43 92.63,130.43 92.62,130.42 91.53,130.42 91.52,130.43 90.09,130.43 90.08,130.42 88.99,130.42 88.98,130.43 87.55,130.43 87.54,130.42 86.45,130.42 86.44,130.43 85.01,130.43 84.9,130.33 84.46,130.33 74.84,120.71 74.84,114.99 73.65,113.79 73.32,113.79 71.63,112.1 v1(71.63,109.71)
BT656_A_D4: length 100.9
  TOP w0.178: v1(117.74,124.73) 117.55,124.54 117.55,120.95 117.53,120.92 117.53,120.88 117.49,120.84 J3.101 ; U4.20 72.56,108.9 v1(73.15,108.32)
  LY3 w0.171: v1(117.74,124.73) 117.4,124.38 107.72,124.38 107.38,124.73 103.22,124.73 101.73,126.22 90.14,126.22 89.37,125.45 89.37,123.47 87.97,122.07 87.59,122.07 87.36,122.3 87.36,122.83 88.66,124.13 88.66,124.87 88.43,125.09 87.44,125.09 87.16,124.82 87.16,123.95 86.65,123.44 86.65,120.6 87.21,120.04 87.21,118.26 86.34,117.39 86.34,111.3 86.26,111.22 86.26,111.21 85.76,110.71 84.1,110.71 83.6,110.21 83.6,109.5 84.1,109 84.46,109 84.75,108.72 84.75,105.03 84.12,104.4 84.12,103.26 83.7,102.84 67.45,102.84 65.89,104.41 65.89,105.75 66.77,106.63 70.23,106.63 71.41,107.81 72.64,107.81 v1(73.15,108.32)
BT656_A_D5: length 101
  TOP w0.178: U4.16 74.57,111.04 74.57,111.71 74.58,111.73 74.58,112.13 74.92,112.47 v1(74.92,113.18) ; J3.100 116.99,112.25 116.96,112.23 116.96,110.28 118.57,108.67 124.47,108.67 125.79,109.99 125.79,111.22 126.57,112 v1(126.91,112)
  LY4 w0.171: v1(74.92,113.18) 75.25,112.86 76.7,112.86 79.13,115.29 80.38,115.29 81.47,116.38 81.47,120.73 87.96,127.21 102.42,127.21 102.88,126.75 103.38,126.75 103.84,127.21 109.34,127.21 109.88,127.75 110.51,127.75 110.86,127.4 110.86,127.33 113.74,127.33 114.99,126.07 115.54,126.07 116.8,127.33 121.2,127.33 129.3,119.23 129.3,110.87 127.72,109.3 127.1,109.3 126.74,109.66 126.74,110.15 126.89,110.3 126.89,111.97 v1(126.91,112)
BT656_A_D6: length 101.2
  TOP w0.178: U4.14 75.57,111.02 v1(75.57,109.08) ; J3.99 116.99,120.98 117.1,121.09 117.1,125.28 117.12,125.31 117.12,125.81 116.99,125.95 116.99,126.67 117.17,126.67 v1(117.17,126.63)
  LY3 w0.171: v1(75.57,109.08) 79.5,109.08 82.82,112.39 82.82,112.78 82.66,112.93 82.36,112.93 79.21,109.78 78.88,109.78 78.66,109.99 78.66,110.22 81.81,113.37 82.45,113.37 83.05,113.98 83.05,121.24 82.38,121.9 82.38,123.22 82.82,123.65 83.25,123.65 83.6,123.29 83.6,115.9 84.06,115.44 84.49,115.44 84.98,115.93 84.98,117.83 84.34,118.47 84.34,125.07 85.53,126.26 88.66,126.26 88.66,126.29 89.53,127.16 100.46,127.16 100.64,126.98 102.15,126.98 102.74,126.39 103.39,126.39 104.15,125.63 104.76,125.63 105.03,125.9 105.03,126.82 105.31,127.1 105.7,127.1 105.97,126.82 105.97,125.9 106.25,125.63 106.64,125.63 106.91,125.9 106.91,126.82 107.19,127.1 107.58,127.1 107.85,126.82 107.85,125.9 108.13,125.63 112.28,125.63 112.55,125.9 112.55,126.82 112.83,127.1 113.22,127.1 113.49,126.82 113.49,125.9 113.77,125.63 114.03,125.63 114.36,125.96 114.74,125.96 115.07,125.63 115.38,125.63 116.38,126.63 v1(117.17,126.63)
BT656_A_D7: length 101.4
  TOP w0.178: J3.98 116.49,110.11 118.38,108.21 124.66,108.21 126.25,109.8 126.25,110.65 126.85,111.25 v1(128.14,111.25) ; v1(76.45,107.68) 76.45,109.08 76.57,109.2 76.57,110.82 76.57,110.82 76.57,111.02 U4.12
  LY4 w0.171: v1(76.45,107.68) 77,107.68 78.07,106.6 78.78,106.6 79.06,106.88 79.06,107.31 78.7,107.67 78.7,107.75 78.57,107.89 78.57,107.92 78.35,108.14 78.31,108.14 78.31,108.42 78.62,108.74 78.62,110.13 82.81,114.32 82.81,121.19 88.38,126.76 102.37,126.76 102.74,126.39 103.53,126.39 103.89,126.76 109.53,126.76 109.53,126.73 109.7,126.55 110.65,126.55 110.86,126.76 113.33,126.76 115.1,124.99 116.73,124.99 117.07,125.33 122.49,125.33 128.82,119 128.82,112.56 128.14,111.88 v1(128.14,111.25)
BT656_A_D8: length 100.6
  TOP w0.178: U4.10 77.55,111.02 77.55,110.17 77.52,110.14 v1(77.52,108.48) ; v1(116.49,125.59) 116.49,121.85 116.6,121.74 116.6,121.24 116.49,121.13 J3.97
  LY3 w0.171: v1(116.49,125.59) 116.1,125.2 103.43,125.2 102.01,126.62 100.49,126.62 100.46,126.65 89.71,126.65 88.79,125.73 85.81,125.73 84.92,124.84 84.92,121.16 86.58,119.51 86.58,118.44 85.91,117.77 85.91,115.12 85.63,114.85 84.44,114.85 84.16,114.57 84.16,114.18 84.44,113.91 85.63,113.91 85.91,113.63 85.91,113.24 85.63,112.97 84.44,112.97 84.16,112.69 84.16,112.3 84.44,112.03 85.63,112.03 85.91,111.75 85.91,111.35 85.62,111.06 83.96,111.06 83.25,110.35 83.25,109.36 84.32,108.29 84.32,107.43 84.04,107.16 83.18,107.16 82.9,107.43 82.9,108.28 82.63,108.56 82.24,108.56 81.96,108.28 81.96,107.43 81.69,107.16 81.3,107.16 81.02,107.43 81.02,108.28 80.75,108.56 80.36,108.56 80.08,108.28 80.08,107.43 79.81,107.16 79.1,107.16 78.83,106.88 78.83,106.49 79.1,106.22 84.04,106.22 84.32,105.94 84.32,105.21 83.6,104.5 82.67,104.5 81.45,103.28 79.31,103.28 79.16,103.43 79.16,103.89 79.39,104.11 80.22,104.11 80.66,104.55 80.66,105.04 80.22,105.49 78.42,105.49 77.7,106.21 77.7,106.73 77.9,106.93 78.34,106.93 78.69,107.28 78.69,107.78 78.31,108.15 77.84,108.15 v1(77.52,108.48)
BT656_A_D9: length 100.1
  TOP w0.178: J3.96 116.03,113.86 116.03,109.92 118.19,107.75 124.85,107.75 126,108.9 126.31,108.9 127.32,109.91 v1(127.33,109.91) ; v1(79.17,108.14) 79.17,110.08 79.09,110.15 79.09,111 U4.7
  LY4 w0.171: v1(79.17,108.14) 79.17,109.34 79.62,109.8 80.01,109.8 80.95,108.86 81.34,108.86 81.62,109.14 81.62,109.53 80.68,110.46 80.68,110.85 83.44,113.61 83.44,114.77 83.72,115.05 85.46,115.05 85.74,115.32 85.74,115.71 85.46,115.99 83.72,115.99 83.44,116.26 83.44,120.56 87.25,124.37 87.25,124.52 88.92,126.2 102.43,126.2 102.59,126.04 103.67,126.04 103.83,126.2 113.34,126.2 115.43,124.1 122.55,124.1 127.51,119.14 127.51,111.75 127.33,111.57 v1(127.33,109.91)
BT656_B_CLK: length 27.3
  TOP w0.178: J2.94 v1(64.37,115.36) ; v1(79.69,117.35) 80.58,117.35 81.41,116.52 81.41,113.09 80.56,112.25 U4.4
  LY4 w0.171: v1(79.69,117.35) 79.36,117.02 76.77,117.02 75.93,117.86 72.12,117.86 68.77,114.5 68.14,114.5 67.7,114.95 66.73,114.95 66.28,114.5 65.23,114.5 v1(64.37,115.36)
BT656_B_D0: length 28.1
  TOP w0.178: U4.27 v1(69.06,112.42) ; J2.105 67.37,119.1 67.51,118.96 67.51,118.93 67.79,118.66 67.79,118.43 v1(68.24,117.98)
  LY3 w0.171: v1(69.06,112.42) 69.06,115.72 68.55,116.23 65.39,116.23 63.97,117.65 61.81,117.65 60.31,119.15 60.31,119.91 60.66,120.26 61.19,120.26 61.61,119.84 61.61,119.05 62.27,118.39 64.85,118.39 65.97,117.27 67.53,117.27 v1(68.24,117.98)
BT656_B_D1: length 28.9
  TOP w0.178: v1(66.59,110.24) 67.6,111.25 67.6,112.42 67.18,112.84 67.08,112.84 66.88,113.04 66.88,113.14 66.87,113.15 J2.104 ; v1(69.63,107.34) 69.87,107.58 69.87,108.9 70.18,109.21 70.18,109.72 70.06,109.84 U4.25
  LY4 w0.171: v1(66.59,110.24) 65.44,109.09 62.42,109.09 61.73,109.78 61.73,111.56 61.4,111.89 60.95,111.89 60.64,111.58 60.64,109.88 62.29,108.23 68.75,108.23 v1(69.63,107.34)
BT656_B_D2: length 28.3
  TOP w0.178: v1(71.72,115.85) 71.72,112.86 71.06,112.2 U4.23 ; J2.103 66.87,118.66 v1(67.14,118.39)
  LY3 w0.171: v1(71.72,115.85) 71.72,119.83 70.77,120.78 62.47,120.78 62.04,120.35 62.04,119.23 62.45,118.82 63.41,118.82 64.2,119.61 65.93,119.61 v1(67.14,118.39)
BT656_B_D3: length 27.3
  TOP w0.178: J2.102 66.37,112.89 66.51,112.74 66.51,111.63 v1(66.69,111.46) ; U4.21 72.06,112.51 73.62,114.07 73.62,115.01 v1(73.32,115.31)
  LY3 w0.171: v1(66.69,111.46) 67.03,111.79 69.41,111.79 69.81,112.19 69.81,116.13 69.1,116.84 69.1,119.44 69.71,120.05 70.47,120.05 71.12,119.39 71.12,115.6 71.47,115.25 71.96,115.25 72.02,115.31 v1(73.32,115.31)
BT656_B_D4: length 27.2
  TOP w0.178: v1(76.01,119.68) 76.01,114.76 75.08,113.83 74.62,113.83 73.98,113.18 73.77,113.18 73.47,112.88 73.47,112.23 73.56,112.14 U4.18 ; v1(66.17,117.92) 66.23,117.98 66.23,118.53 66.37,118.67 J2.101
  LY4 w0.171: v1(76.01,119.68) 72.53,123.16 69.35,123.16 67.33,121.14 67.33,120.81 66.83,120.31 66.5,120.31 66.15,119.96 66.15,117.93 v1(66.17,117.92)
BT656_B_D5: length 27.2
  TOP w0.178: v1(76.31,113.51) 75.45,112.64 75.45,112.36 75.06,111.98 U4.15 ; J2.100 v1(65.87,112.48)
  LY4 w0.171: v1(65.87,112.48) 66.7,113.31 69.39,113.31 69.88,113.8 70.33,113.8 70.82,113.31 71.27,113.31 71.76,113.8 72.21,113.8 72.7,113.31 73.8,113.31 74.16,113.66 74.16,114.27 73.79,114.64 73.37,114.64 73.36,114.66 73.06,114.66 72.33,115.39 72.33,116.61 72.63,116.92 73.12,116.92 73.67,116.37 76.09,116.37 76.38,116.08 77.64,116.08 77.86,115.85 77.86,115.06 v1(76.31,113.51)
BT656_B_D6: length 27.8
  TOP w0.178: v1(77.48,119.86) 76.9,119.28 76.9,113.84 76.96,113.78 76.96,113.25 76.9,113.19 76.9,112.88 76.06,112.04 U4.13 ; J2.99 65.87,119.08 v1(65.47,118.68)
  LY4 w0.171: v1(77.48,119.86) 73.6,123.75 68.69,123.75 65.47,120.52 v1(65.47,118.68)
BT656_B_D7: length 28.1
  TOP w0.178: J2.98 65.37,115.22 v1(65.53,115.38) ; v1(78.04,118.21) 77.79,117.96 77.79,112.95 77.06,112.23 U4.11
  LY4 w0.171: v1(65.53,115.38) 65.53,116.04 66.61,117.12 68.47,117.12 68.92,117.58 68.92,119.98 69.63,120.69 70.05,120.69 70.32,120.41 70.32,119.93 70.6,119.65 70.99,119.65 71.26,119.93 71.26,120.41 71.54,120.69 74.02,120.69 75.91,118.8 76.32,118.8 76.91,118.21 v1(78.04,118.21)
BT656_B_D8: length 29.1
  TOP w0.178: J2.97 v1(65.37,121.5) ; v1(79.74,121.11) 79.74,119.1 78.7,118.05 78.7,116.93 78.7,112.75 78.06,112.11 U4.9
  LY4 w0.171: v1(79.74,121.11) 76.47,124.38 68.25,124.38 v1(65.37,121.5)
BT656_B_D9: length 28.4
  TOP w0.178: v1(79.34,114.62) 79.56,114.4 U4.6 ; J2.96 64.87,113.05 64.66,112.84 64.65,112.84 64.3,112.5 v1(64.22,112.5)
  LY4 w0.171: v1(79.34,114.62) 79.34,112.9 77.76,111.33 67.82,111.33 67.06,112.09 66.33,112.09 65.06,110.82 63.23,110.82 62.83,111.23 62.83,112.65 63.13,112.95 63.77,112.95 v1(64.22,112.5)
BT656_CLK: length 2.2
  TOP w0.178: U4.52 v1(80.06,104.8)
  BOTTOM w0.178: v1(80.06,104.8) 80.07,104.79 R549.2
BT656_D0: length 2.5
  TOP w0.178: v1(68.47,102.13) 68.76,102.42 68.83,102.42 69.01,102.59 69.01,102.66 69.06,102.72 U4.30
  BOTTOM w0.178: R559.2 68.67,102.32 v1(68.47,102.13)
BT656_D1: length 2.7
  TOP w0.178: v1(69.84,101.97) 70.06,102.19 U4.32
  BOTTOM w0.178: R558.2 70.04,102.17 v1(69.84,101.97)
BT656_D2: length 2.3
  TOP w0.178: U4.34 71.06,104.9 v1(71.06,104.9)
  BOTTOM w0.178: R557.2 v1(71.06,104.9)
BT656_D3: length 2.2
  TOP w0.178: U4.36 72.06,104.83 v1(72.09,104.86)
  BOTTOM w0.178: v1(72.09,104.86) 72.07,104.84 R556.2
BT656_D4: length 2.2
  TOP w0.178: U4.39 73.56,104.81 v1(73.6,104.84)
  BOTTOM w0.178: v1(73.6,104.84) 73.6,104.84 R555.2
BT656_D5: length 2.2
  TOP w0.178: v1(74.61,102.15) 74.61,103.43 U4.41
  BOTTOM w0.178: R554.2 v1(74.61,102.15)
BT656_D6: length 2.3
  TOP w0.178: v1(75.57,102.07) 75.57,103.47 U4.43
  BOTTOM w0.178: v1(75.57,102.07) 75.57,102.92 R553.2
BT656_D7: length 2.2
  TOP w0.178: v1(76.52,104.84) 76.56,104.8 U4.45
  BOTTOM w0.178: R552.2 v1(76.52,104.84)
BT656_D8: length 2.2
  TOP w0.178: U4.47 77.56,104.81 v1(77.53,104.84)
  BOTTOM w0.178: R551.2 v1(77.53,104.84)
BT656_D9: length 2.2
  TOP w0.178: U4.50 79.06,104.81 v1(79.03,104.84)
  BOTTOM w0.178: R550.2 79.06,104.81 v1(79.03,104.84)
BUS_SELECT: length 217.3
  TOP w0.178: U20.16 182.41,13.4 v1(182.2,13.19) ; J3.89 114.49,120.07 v1(114.49,117.88)
  LY3 w0.171: v1(131.34,118.46) 134.38,121.5 v1(140.4,121.5) ; v1(187.35,123.25) 187.35,116.58 187.35,116.58 187.35,108.73 185.15,106.53 185.15,103.74 185.3,103.58 185.3,102.05 186.76,100.59 186.76,99.31 185.16,97.72 185.16,90.15 183.57,88.56 183.57,87.85 177.84,82.12 177.84,81.12 179.31,79.65 183.31,79.65 183.99,78.98 183.99,77.7 180.84,74.54 180.84,71.95 180.3,71.41 180.3,70.37 180.71,69.96 180.71,69.55 182.24,68.02 184.37,68.02 185.94,66.46 185.94,62.85 187.63,61.16 187.63,58.86 184.19,55.42 184.19,49.52 183.3,48.63 183.3,41.65 183.3,41.65 183.3,40.17 183.3,40.16 183.3,39.6 184.18,38.72 184.23,38.72 185.99,36.97 185.99,28.35 182.63,24.99 182.63,23.8 182.76,23.67 182.76,21.09 182.2,20.53 v1(182.2,13.19)
  LY4 w0.171: v1(140.4,121.5) 140.49,121.5 143.88,124.89 151.6,124.89 154.47,127.76 161.02,127.76 161.81,126.97 163.74,126.97 163.9,127.13 164.39,127.13 164.55,126.97 165.04,126.97 165.29,126.72 183.93,126.72 187.35,123.3 v1(187.35,123.25)
  BOTTOM w0.178: v1(131.34,118.46) 128.52,118.46 127.25,117.19 126.2,117.19 125.55,116.53 125.32,116.53 125.28,116.49 124.32,116.49 122.91,115.08 121.63,115.08 121.61,115.06 120.55,115.06 120.26,114.76 119.1,114.76 117.02,116.84 117.02,117.08 116.23,117.88 v1(114.49,117.88) ; v1(182.2,13.19) 182.55,13.54 R757.1
COMP_SENSE_INPUT: length 8.6
  TOP w0.178: v1(130.8,38.53) 131.37,38.53 131.75,38.91 133.35,38.91 133.99,38.28 J31.2
  BOTTOM w0.178: U515.2 131.82,41.33 132,41.15 132,40.36 131.8,40.17 131.59,40.17 R719.1 130.8,38.53 v1(130.8,38.53)
COMP_SENSE_VDD: length 5
  TOP w0.178: J31.1 v1(135.23,36.15)
  BOTTOM w0.178: C682.2 R718.1 134.82,36.57 v1(135.23,36.15)
COMP_SENSOR: length 18.2
  BOTTOM w0.178: 128.91,40.67 R720.1 124.85,41.77 v1(124.27,42.35) 123.76,42.86 120.48,42.86 119.22,41.61 118.29,41.61 J26.3 ; 128.91,40.67 R721.1 ; 128.91,40.67 128.92,40.68 U515.1
CSZ5_DAD2: length 12.2
  TOP w0.178: v1(88.66,14.83) 88.7,14.87 R57.1
  LY3 w0.171: v1(95.91,21.59) 95.17,20.85 95.17,20.24 91.57,16.64 90.47,16.64 v1(88.66,14.83)
  BOTTOM w0.178: J500.12B v1(95.91,21.59)
CW_INDEX1: length 131.5
  TOP w0.102: 107.63,70.16 107.62,70.16 v2(106.66,69.2)
  TOP w0.178: U11.AF7 v2(106.66,69.2) ; TP69.1 106.68,12.83 107.7,11.81 107.7,10.92 108.97,9.65 115.57,9.65 117.34,11.42 117.41,11.42 119.13,13.14 119.13,14.73 121.73,17.34 121.73,18.38 123.38,20.03 123.38,20.73 123.33,20.79 123.33,21.58 123.38,21.63 123.38,23.25 121.61,25.03 121.61,26.77 121,27.38 121,27.91 121.35,28.26 121.61,28.26 121.61,32.54 121.29,32.86 120.02,32.86 119.29,33.59 110.52,33.59 109.2,34.92 105.74,34.92 102.22,38.44 102.22,47.92 104.61,50.31 109.87,50.31 111.92,52.36 111.92,57.82 112.4,58.31 112.97,58.31 113.58,58.92 113.58,61.12 114.21,61.74 114.74,61.74 115.1,61.38 118.96,61.38 120.8,63.22 120.8,64.23 119.21,65.81 119.21,67.52 117.13,69.6 117.13,71.09 115.63,72.59 109.55,72.59 107.73,70.77 107.73,70.26 107.63,70.16
  BOTTOM w0.178: U521.1 109.72,8.14 R763.1 109.72,10.76 R762.1 109.81,10.92 109.18,11.55 108.81,11.92 107.58,11.92 107.18,12.32 107.05,12.32 106.68,12.69 TP69.1
CW_INDEX2: length 155.4
  TOP w0.178: v1(106.93,11.72) 106.93,10.07 v1(105.29,8.43) 104.14,9.58 TP68.1
  LY3 w0.171: v1(50.86,43.24) 51.56,43.94 51.69,43.94 52.08,44.33 52.08,45.01 52.08,46.45 52.07,46.46 52.07,48.01 53.39,49.33 53.39,50.84 53.65,51.09 53.65,54.94 54.22,55.51 55.9,55.51 57.13,56.74 57.13,63.16 59.73,65.76 59.73,67.64 59.99,68.03 60.87,68.91 60.87,70.48 60.91,70.52 62.18,71.79 63.58,73.19 63.58,75.52 64.22,76.16 65.38,76.16 66.08,76.85 67.58,76.85 67.99,77.27 69.45,77.27 70.88,78.71 71.13,78.71 72.38,79.96 73.1,79.96 73.66,80.52 74.42,80.52 75.44,81.53 75.44,87 73.66,88.77 v1(73.53,88.77)
  BOTTOM w0.178: R765.1 v1(106.93,11.72) ; TP68.1 102.17,13.97 101.42,14.72 100.51,14.72 98.79,14.72 94.87,10.79 93.34,10.79 92.51,9.96 82.02,9.96 81.34,9.27 80.62,9.27 77.91,11.98 68.41,11.98 67.71,12.69 65.91,14.48 65.91,26.87 65.74,27.05 65.66,27.05 61.3,31.41 61.3,31.55 60.95,31.9 60.81,31.9 56.26,36.45 56.26,36.84 50.86,42.23 v1(50.86,43.24) ; R767.1 105.29,9.03 v1(105.29,8.43) 105.29,7.83 104.9,7.44 U521.7 ; v1(73.53,88.77) R591.2
CW_PWM1: length 71.1
  TOP w0.178: R24.1 v1(164.46,66.56) ; U11.AD8 v2(104.66,70.2)
  LY3 w0.171: v1(123.56,71) 122.58,71.98 121.44,71.98 120.38,73.04 116.6,73.04 115.16,71.59 114.99,71.59 114.56,71.17 113.93,71.17 113.49,70.72 113.49,70.22 112.78,69.5 111.08,69.5 110.44,68.87 109.16,68.87 108.43,69.59 107.76,69.59 107.63,69.72 105.14,69.72 v2(104.66,70.2)
  LY4 w0.171: v1(131.11,67.94) 131.11,68 132.08,68.96 134.21,68.96 134.4,68.77 135.57,68.77 136,69.2 138.56,69.2 140.07,67.69 140.07,67.04 140.42,66.69 140.91,66.69 141.26,67.04 141.26,67.86 141.85,68.44 152.51,68.44 152.91,68.84 160.97,68.84 161.59,68.22 162.79,68.22 164.45,66.56 v1(164.46,66.56)
  BOTTOM w0.178: v1(123.56,71) 123.69,70.87 123.95,70.87 127.51,67.31 130.48,67.31 v1(131.11,67.94)
CW_PWM2/SPD4: length 268.4
  TOP w0.178: U11.H26 v2(87.66,89.2)
  LY3 w0.102: v2(87.66,89.2) 87.66,88.76 88.06,88.36 88.06,87.94 87.71,87.59 87.5,87.59 87.27,87.36 87.27,86.65 87.07,86.45 87.07,86.05 86.83,85.81 86.47,85.81 86.26,85.6 86.26,84.95 86.06,84.75 86.06,84.04 85.83,83.81 85.83,83.8 85.62,83.59 85.5,83.59 85.27,83.36 85.27,82.04 85.04,81.81 79.85,81.81
  LY3 w0.171: v1(35.66,21.48) 40.81,21.48 45.36,26.03 45.36,30.48 47.32,32.43 47.32,32.95 47.65,33.28 48.36,33.99 49.28,33.99 49.83,34.54 49.83,36.11 50.52,36.79 50.52,40.33 51.46,41.27 51.68,41.27 52.83,42.43 52.83,42.64 53.81,43.62 53.81,45.72 53.81,47.16 54.64,48 55.34,48 56.59,49.25 56.87,49.25 57.49,49.87 57.49,50.83 58.89,52.22 59.42,52.22 60.17,52.97 60.17,54.03 59.09,55.11 59.09,55.2 59.01,55.28 59.01,55.68 59.21,55.88 59.21,56.07 59.3,56.16 59.92,56.16 60.48,55.6 60.87,55.6 61.4,56.13 61.4,56.45 60.82,57.03 60.82,58.04 59.72,59.14 59.72,60.03 61.41,61.72 61.41,62.1 61.82,62.5 61.82,66.77 62.08,67.04 62.08,67.17 63.05,68.14 63.05,69.71 67.18,73.84 67.77,73.84 68.94,75.01 70.14,75.01 70.27,75.15 70.89,75.15 73.62,77.88 74.46,77.88 75.27,78.68 75.27,78.7 78.39,81.82 79.84,81.82 79.85,81.81
  LY4 w0.171: v1(169.81,113.36) 171.6,115.15 171.6,121.75 170.15,123.2 161.86,123.2 161.4,123.66 157.09,123.66 151.36,117.93 135.09,117.93 134.38,117.22 130.27,117.22 129.92,116.87 129.92,116.38 130.26,116.04 130.26,111.1 129.22,110.07 129.22,109.68 128.26,108.72 127.17,108.72 126.32,109.57 126.32,119.39 122.04,123.67 115.36,123.67 114.17,124.86 99.29,124.86 98.39,125.77 89.1,125.77 87.6,124.27 87.6,123.78 86.89,123.07 86.89,113.8 83.5,110.4 83.5,104.72 82.73,103.96 82.73,99.86 81.7,98.84 81.7,98.49 81.51,98.29 81.51,97.8 81.7,97.6 81.7,94.7 83.92,92.48 84.38,92.48 v2(87.66,89.2)
  BOTTOM w0.178: U517.7 35.25,22.15 35.66,21.75 v1(35.66,21.48) ; R514.1 v1(169.81,113.36)
CWCTR1: length 139.7
  TOP w0.254: v1(163.38,65.6) 163.06,65.28 U15.13 ; v1(128.75,5.29) 128.67,5.21 J63.1
  LY3 w0.254: v1(145.28,73.97) 145.28,73.79 145.41,73.65 145.41,73.49 145.38,73.46 145.38,68.42 143.57,66.61 143.57,63.96 142.61,62.99 141.73,62.99 141.7,63.02 140.91,63.02 140.06,62.17 140.06,60.49 140.29,60.26 140.29,59.73 140.06,59.5 140.06,57.83 141.17,56.72 141.17,52.58 146.63,47.12 146.63,20.89 134.34,8.61 129.74,8.61 128.75,7.62 v1(128.75,5.29) ; v1(167.78,73.85) 166.22,72.29 166.22,70.1 166.05,69.94 166.05,69.41 166.11,69.36 165.27,68.52 164.86,68.52 163.38,67.03 v1(163.38,65.6)
  LY4 w0.254: v1(167.78,73.85) 165.18,76.44 160.39,76.44 160.37,76.45 159.88,76.45 159.62,76.72 148.03,76.72 v1(145.28,73.97)
  BOTTOM w0.254: DN508.3 167.77,72.72 167.77,73.86 ; 167.77,73.86 v1(167.78,73.85) ; 167.77,73.86 C580.1 C581.1 163.6,75.23 159.78,79.06 159.78,79.43 159.04,80.16 158.33,80.16 C582.1
CWCTR2: length 237.1
  TOP w0.254: U2.13 163.92,117.29 164.11,117.09 165.37,117.09 165.89,117.62 v1(165.89,118.39) ; v1(154.23,125.86) 157.04,125.86 158.97,127.8 161.67,127.8 v1(163.09,126.38) ; v1(109.69,5.37) 109.69,4.88 109.62,4.81 J61.1
  LY3 w0.254: v1(109.69,5.37) 110.26,5.37 113.47,8.59 116.07,8.59 117.14,9.66 117.14,10.81 117.55,11.22 118.31,11.98 120.09,11.98 122.37,14.26 124.27,14.26 124.55,14.54 125.31,15.3 125.31,18.88 127.08,20.65 128.03,20.65 133.73,26.36 133.73,37.88 127.83,43.79 127.83,43.82 126.2,45.45 126.2,46.97 123.96,49.21 121.95,49.21 121.09,50.08 121.09,50.14 121.06,50.17 121.06,51.48 122.12,52.54 122.12,58.38 122.01,58.49 122.01,63.07 120.46,64.62 120.42,64.62 119.21,65.82 119.21,66.64 117.33,68.52 117.33,68.88 117.06,69.16 117.06,69.41 116.46,70.01 116.46,71.57 117.06,72.17 117.22,72.17 117.26,72.21 118.2,72.21 118.4,72.01 119.82,72.01 120.64,71.2 120.64,70.63 120.91,70.35 120.91,70.3 122.51,68.71 123.94,68.71 124.48,69.24 124.48,70.4 124.63,70.55 124.63,71.44 124.55,71.52 124.55,72.33 124.3,72.58 123.57,73.31 123.57,77.4 124.96,78.8 124.96,79.51 124.82,79.65 124.82,80.46 124.82,81.25 124.96,81.4 124.96,82.76 127.15,84.95 127.15,87.04 126.87,87.31 126.87,88.32 127.59,89.03 127.59,92.62 127.54,92.67 127.54,95.08 126.72,95.9 126.72,96.88 127.54,97.69 127.54,104.31 127.64,104.42 128.9,105.68 128.9,106.96 128.02,107.84 127.83,107.84 126.7,108.98 126.7,110.71 127.88,111.89 128.86,111.89 129.43,112.46 129.43,116.1 129.38,116.15 129.38,116.16 129.31,116.23 129.31,120.95 129.23,121.02 v1(129.23,121.69) ; v1(175.26,124.46) 175.26,123.09 174.62,122.46 169.07,122.46 166.99,124.54 164.93,124.54 v1(163.09,126.38) 162.4,125.68 162.4,121.87 v1(165.89,118.39)
  LY4 w0.254: v1(154.23,125.86) 154.23,122.47 150.62,118.87 141.09,118.87 139.84,120.12 135.07,120.12 134.83,120.36 134.3,120.36 134.06,120.12 130.8,120.12 v1(129.23,121.69)
  BOTTOM w0.254: C500.1 v1(175.26,124.46) ; v1(163.09,126.38) 163.09,126.72 DN502.3 165.4,127.51 C501.1 ; C502.1 v1(154.23,125.86)
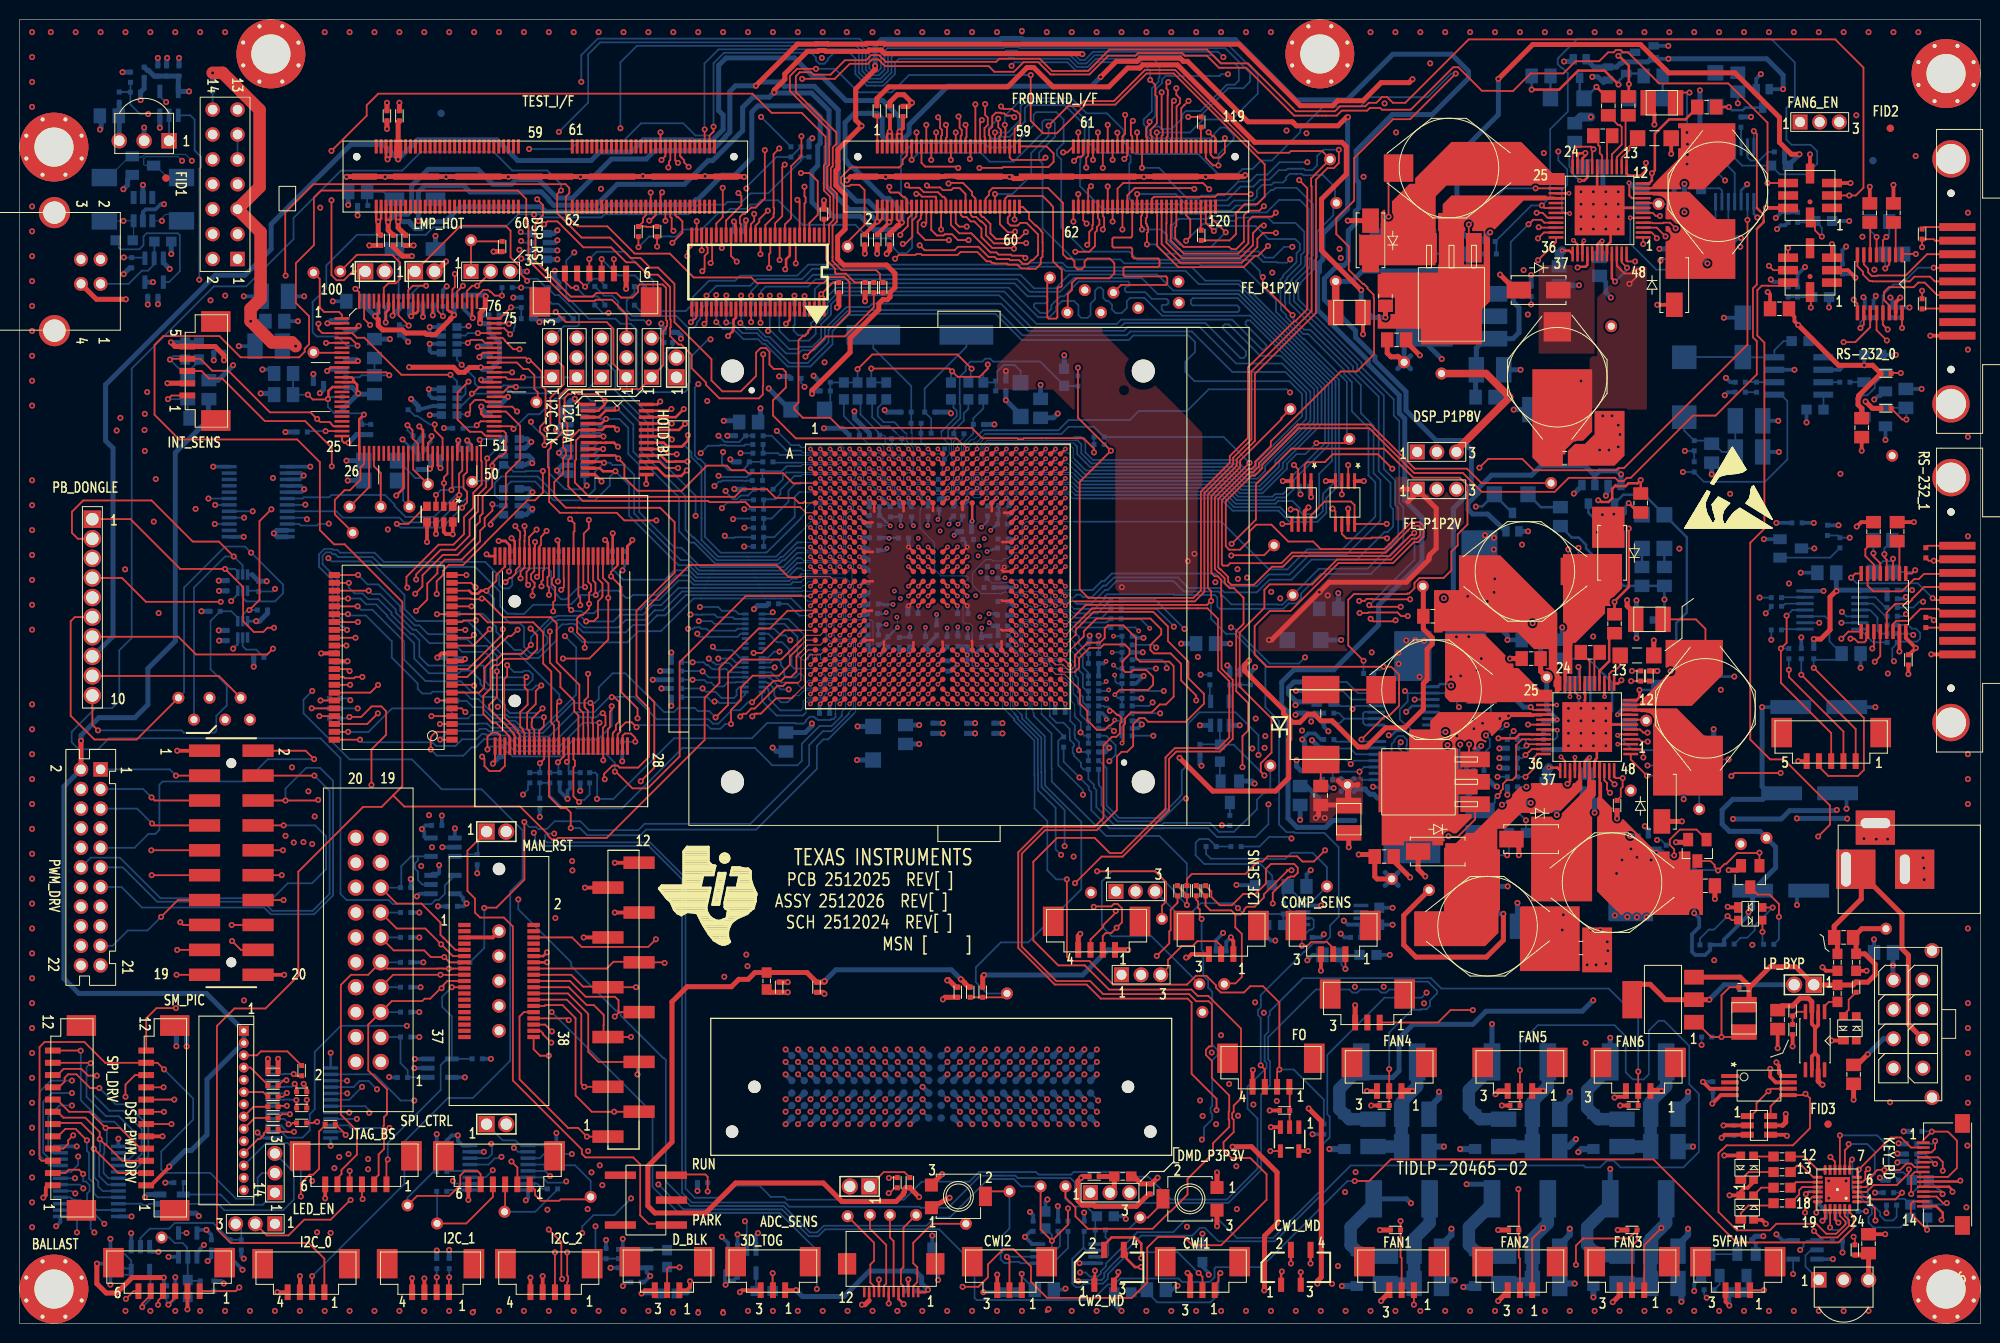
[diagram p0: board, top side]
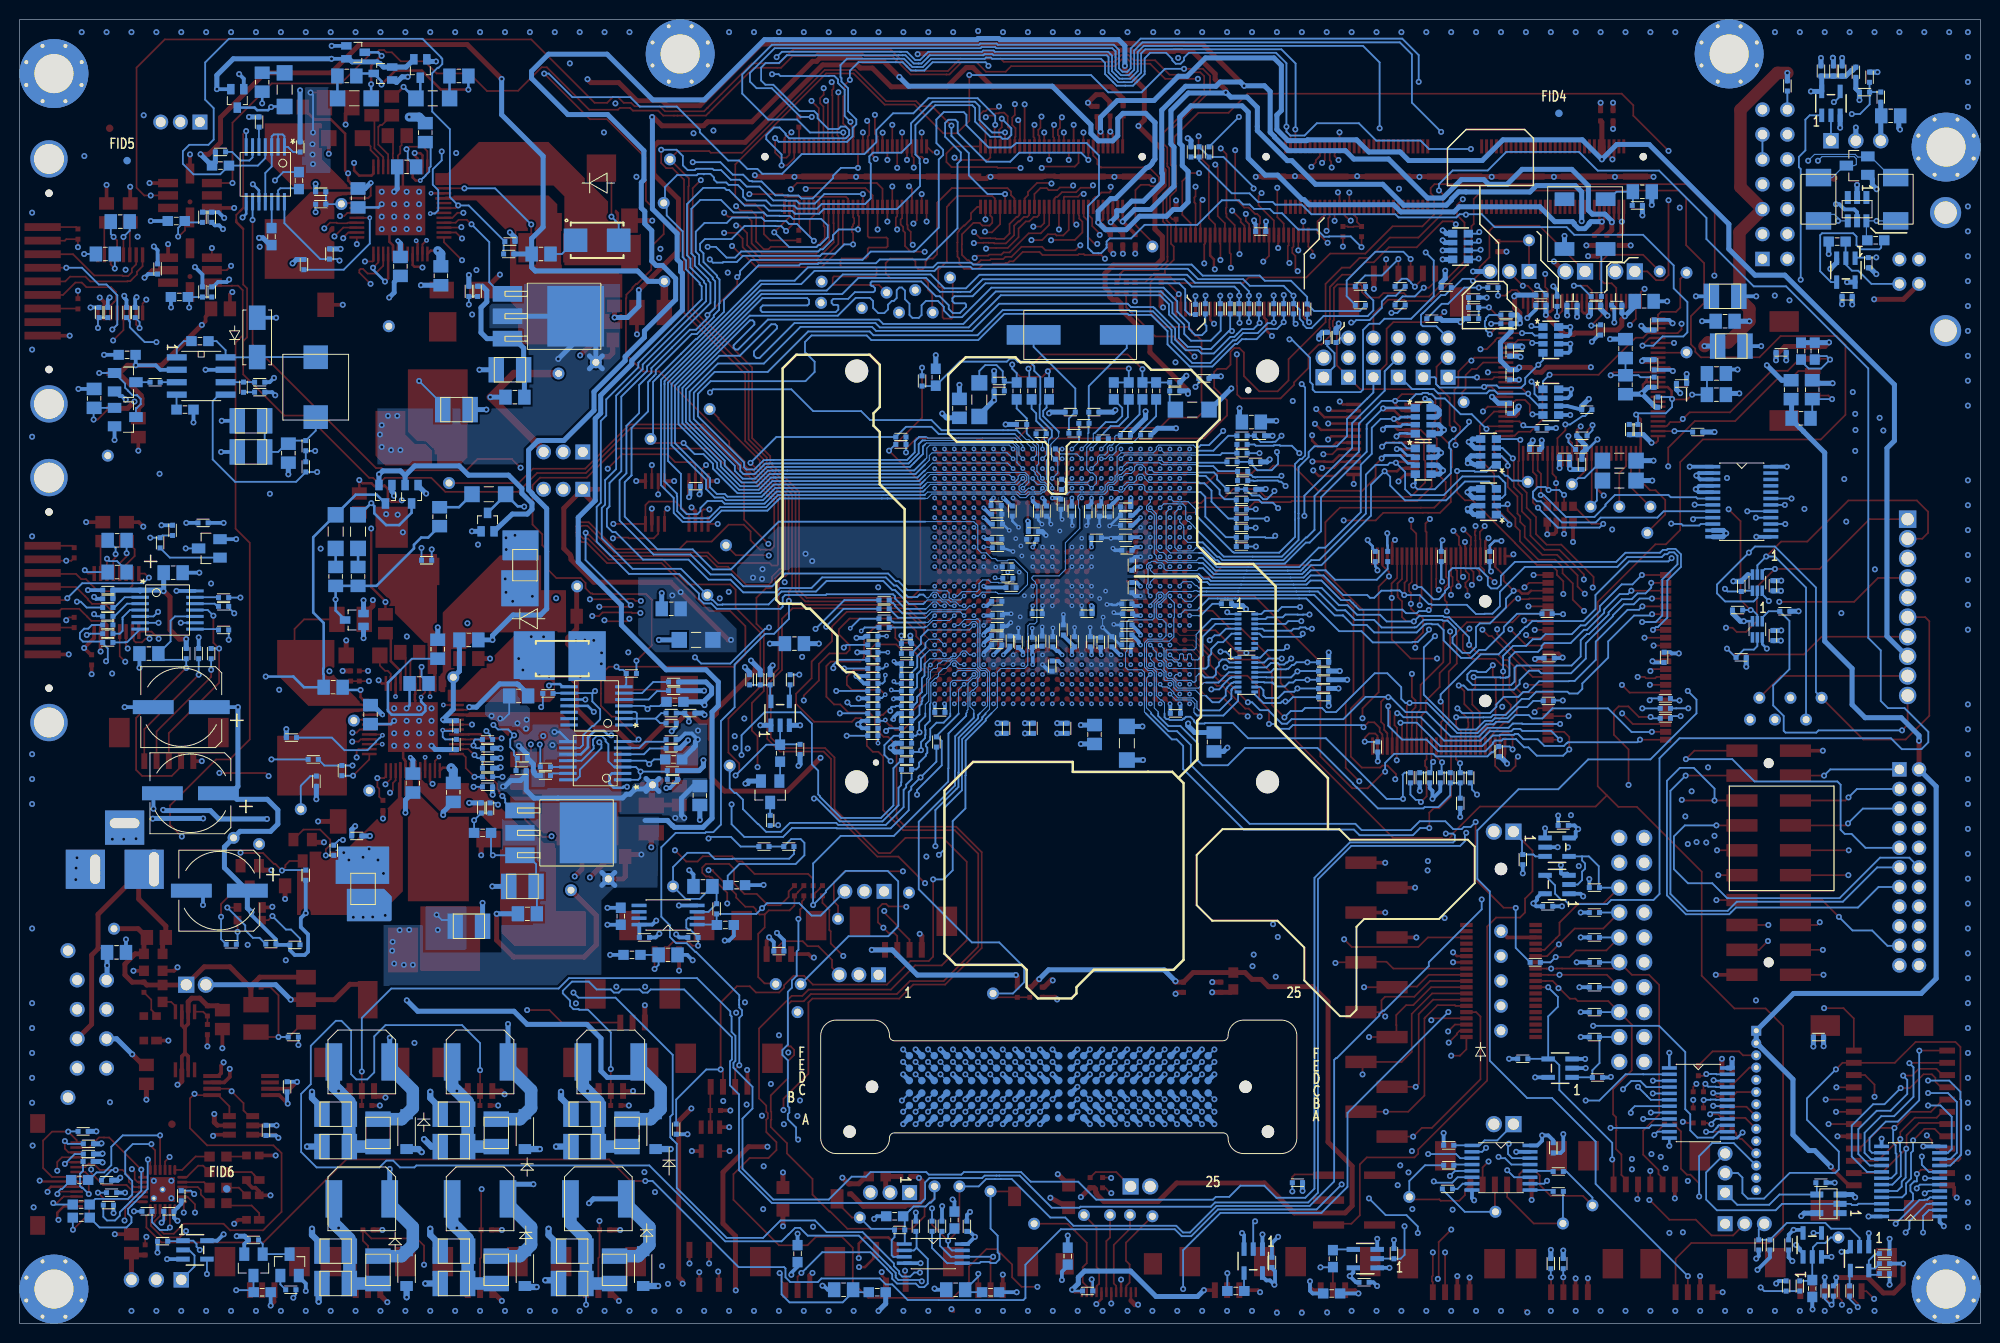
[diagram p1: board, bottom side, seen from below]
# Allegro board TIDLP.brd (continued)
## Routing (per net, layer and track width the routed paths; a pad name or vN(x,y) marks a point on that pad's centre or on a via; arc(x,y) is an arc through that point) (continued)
CWY1A: length 134.9
  TOP w0.254: J63.4 v1(131.68,6.11)
  LY3 w0.254: v1(174.9,65.98) 175.09,65.79 176.7,65.79 177.22,65.27 177.22,64.28 178.37,63.13 178.37,62.6 178,62.23 178,61.54 178.78,60.75 178.78,57.92 177.9,57.04 177.9,56.03 177.1,55.23 177.1,55.02 175.57,53.49 175.06,53.49 171.43,49.87 171.43,48.03 169.5,46.09 169.5,38.36 161.67,30.53 161.67,30.53 160.85,29.71 160.85,28.55 162.58,26.83 162.58,24.7 165.02,22.25 165.02,13.65 162.62,11.25 141.67,11.25 141.33,11.59 139.01,11.59 134.54,7.12 132.05,7.12 131.68,6.75 v1(131.68,6.11)
  BOTTOM w0.254: v1(174.9,65.98) 172.09,65.98 171,64.9 R632.2 168.99,66.21 169.04,66.26 169.04,66.79 168.99,66.84 168.99,71.45 170.06,72.52 170.06,80.2 R601.2 165.71,84.54 163.58,84.54 DN505.3
CWY1B: length 145.5
  TOP w0.254: J63.3 v1(130.68,5.22) ; R18.2 165.08,82.73 v1(164.13,83.68)
  LY3 w0.254: v1(174.48,84.63) 174.48,83.42 174.56,83.34 174.56,67.2 175.14,66.62 175.16,66.62 175.48,66.3 176.91,66.3 177.73,65.48 177.73,64.49 178.88,63.34 178.88,61.37 179.29,60.96 179.29,57.71 178.41,56.83 178.41,55.82 177.61,55.02 177.61,54.81 175.61,52.81 175.09,52.81 171.94,49.66 171.94,47.67 170.01,45.73 170.01,38.14 161.88,30.02 161.88,30.02 161.36,29.5 161.36,28.77 163.3,26.82 163.3,24.88 165.75,22.43 165.75,12.14 164.35,10.74 141.46,10.74 141.12,11.08 139.41,11.08 134.94,6.61 133.43,6.61 132.55,5.73 132.19,5.73 131.94,5.47 131.43,5.47 131.17,5.22 v1(130.68,5.22)
  LY4 w0.254: v1(174.48,84.63) 165.08,84.63 v1(164.13,83.68)
  BOTTOM w0.254: DN506.3 160.02,82.69 161.27,81.44 162.62,81.44 163.82,82.64 163.82,83.37 v1(164.13,83.68) 164.15,83.68 165.34,82.49 R602.2
CWY1C: length 126.2
  TOP w0.254: v1(164.14,81.09) 164.14,75.12 162.69,73.66 v1(162.69,73.59) R20.2 ; J63.2 v1(129.67,6.11)
  LY3 w0.254: v1(129.67,6.11) 129.67,7.04 130.29,7.66 134.11,7.66 138.55,12.1 140.35,12.1 147.52,19.27 147.52,48.29 146.75,49.06 145.48,49.06 145.11,49.43 145.11,51.08 141.8,54.39 141.8,60.46 141.8,61.2 144.34,63.73 144.34,66.66 145.88,68.21 145.88,73.25 146.82,74.18 146.82,81.61 v1(148.54,83.32)
  LY4 w0.254: v1(148.54,83.32) 148.56,83.35 159.13,83.35 161.01,81.47 162.1,81.47 162.49,81.09 v1(164.14,81.09)
  BOTTOM w0.254: v1(148.54,83.32) 148.56,83.35 149.2,83.35 R589.2 150.43,84.52 DN507.3
CWY2A: length 183.4
  TOP w0.254: v1(114.38,5.74) 113.77,5.74 112.92,6.59 112.92,7.2 J61.4 ; R6.2 174.36,124.08 174.37,124.08 v1(174.35,124.08)
  LY3 w0.254: v1(114.38,5.74) 114.66,6.02 114.67,6.02 114.84,6.19 116.22,6.19 118.16,8.13 122.35,8.13 123.85,9.62 133.92,9.62 145.52,21.22 145.52,46.54 140,52.05 140,55.26 138.38,56.88 138.38,63.16 140.84,65.62 140.84,66.32 142.15,67.63 142.55,67.63 143.93,69.02 143.93,72.82 141.92,74.83 141.92,78.98 148.46,85.52 148.46,86.84 148.27,87.03 148.27,87.56 148.58,87.87 148.58,98.97 148.46,99.1 148.46,116.26 160.08,127.89 161.12,127.89 161.38,127.63 165.23,127.63 168.78,124.08 v1(174.35,124.08)
  BOTTOM w0.254: DN500.3 176.03,124.03 175.77,123.77 174.66,123.77 v1(174.35,124.08) 174.28,124.14 R500.2
CWY2B: length 203.6
  TOP w0.254: v1(163.08,129.3) 163.08,129.37 164.15,128.3 v1(164.15,126.41) 164.15,125.23 R4.2 ; v1(112.07,5.23) 112.04,5.2 112.04,4.86 111.63,4.45 J61.3
  LY3 w0.254: v1(131.26,121.41) 129.89,120.03 129.89,116.36 130.26,115.99 130.28,115.99 130.31,115.97 130.31,112.29 128.49,110.47 128.49,108.1 130.07,106.51 130.07,106.13 129.78,105.83 128.15,104.21 128.15,97.56 127.23,96.63 127.23,96.11 128.15,95.19 128.15,88.82 128.15,88.82 128.15,85.12 125.47,82.44 125.47,81.19 125.32,81.04 125.32,80.25 125.32,79.87 126.38,78.81 126.38,76.35 125.53,75.51 125.53,75.42 125.09,74.98 125.05,74.98 124.81,74.73 124.81,72.79 125.06,72.54 125.06,72.16 125.06,72.16 125.06,72 125.09,71.97 125.13,71.65 125.13,70.34 124.98,70.19 124.98,69.03 124.15,68.2 122.3,68.2 120.41,70.09 120.41,70.14 120.13,70.42 120.13,70.62 119.25,71.51 118.19,71.51 117.99,71.7 117.47,71.7 116.99,71.23 116.99,70.19 117.56,69.62 117.56,69.37 117.84,69.09 117.84,68.78 119.01,67.61 119.84,66.79 119.84,65.92 120.63,65.13 120.67,65.13 122.52,63.28 122.52,58.7 122.63,58.59 122.63,52.33 121.56,51.27 121.56,50.38 122.23,49.72 124.17,49.72 126.71,47.18 126.71,45.66 128.33,44.03 128.33,44 131.72,40.61 133.24,40.61 133.68,40.17 133.68,39.31 134.24,38.75 134.24,25.65 130.16,21.57 130.16,21.23 128.31,19.38 126.95,19.38 125.82,18.25 125.82,15.51 125.82,15.51 125.82,15.09 124.48,13.75 122.58,13.75 120.3,11.47 118.52,11.47 117.76,10.71 117.76,10.71 117.65,10.6 117.65,9.45 116.28,8.08 113.68,8.08 112.39,6.79 112.39,5.55 v1(112.07,5.23)
  LY4 w0.254: v1(163.08,129.3) 163.08,129.37 162.98,129.47 147.12,129.47 144.24,126.59 144.24,125.98 140.85,122.59 140.24,122.59 139.06,121.41 v1(131.26,121.41)
  BOTTOM w0.254: v1(163.08,129.3) 163.44,129.67 DN501.3 ; v1(164.15,126.41) R501.2
CWY2C: length 171
  TOP w0.254: v1(114.41,6.66) 114.41,8.13 113.78,8.76 111.38,8.76 110.62,8.01 J61.2 ; v1(160.84,126.14) 161.81,125.17 R3.2
  LY3 w0.254: v1(160.84,126.14) 149.05,114.35 149.05,99.23 149.4,98.88 149.4,87.72 149.54,87.58 149.54,87.23 149.56,87.21 149.56,87.03 149.4,86.86 149.4,85.03 148.35,83.98 148.27,83.98 147.87,83.52 147.87,83.5 145.99,81.62 145.99,75.43 145.16,74.61 145.01,74.61 144.64,74.23 144.64,73.71 144.87,73.48 144.87,68.63 142.94,66.69 142.63,66.69 142.16,66.23 142.16,64.47 141.57,63.87 141.04,63.87 139.34,62.17 139.34,60.58 139.02,60.26 139.02,59.73 139.34,59.41 139.34,57.11 140.51,55.95 140.51,52.45 146.02,46.93 146.02,21 134.13,9.11 126.3,9.11 124.8,7.62 118.37,7.62 116.39,5.64 115.18,5.64 114.65,5.11 114.12,5.11 113.75,5.48 113.75,6.31 113.87,6.44 114.19,6.44 v1(114.41,6.66)
  BOTTOM w0.254: v1(160.84,126.14) 159.67,124.97 R502.2 159.13,125.41 DN503.3
D_PWM_0: length 91.4
  TOP w0.178: J24.17 v1(16.07,38.1) ; J39.6 v1(15.48,20.33)
  LY3 w0.171: v1(15.48,20.33) 15.47,20.35 14.72,20.35 13.54,21.52 13.54,24.44 ; v1(16.07,38.1) 16.07,37.87 14.67,36.47 14.67,28.96 13.54,27.83 13.54,24.44 ; v1(19.26,84.15) 19.26,83.31 15.01,79.05 15.01,72.25 12.1,69.34 12.1,25.28 12.09,25.27 12.09,24.88 12.53,24.44 13.54,24.44
  BOTTOM w0.178: U506.19 v1(19.26,84.15)
D_PWM_1: length 75.8
  TOP w0.178: J39.7 v1(14.72,21.58) ; J24.19 v1(16,35.56)
  LY3 w0.171: v1(14.72,21.58) 13.97,22.33 13.97,27.07 15.04,28.13 15.04,34.59 v1(16,35.56) 16.66,36.22 16.66,38.35 15.89,39.12 13.28,39.12 12.45,39.95 12.45,69.14 15.44,72.13 15.44,78.19 19.94,82.7 v1(19.94,83.49)
  BOTTOM w0.178: U506.18 v1(19.94,83.49)
D_PWM_2: length 78.7
  TOP w0.178: J24.16 v1(21.62,40.64) ; J39.8 v1(15.78,22.83)
  LY3 w0.171: v1(23.77,82.84) 23.8,82.84 23.8,81.93 23.47,81.6 22.63,81.6 17.6,76.57 17.6,66.51 17.55,66.46 17.55,63.03 16.65,62.13 16.65,61.15 18.23,59.56 18.23,44.03 v1(21.62,40.64)
  LY4 w0.171: v1(21.62,40.64) 18.99,38 18.99,36.93 13.53,31.47 13.53,23.55 14.25,22.83 v1(15.78,22.83)
  BOTTOM w0.178: U506.17 v1(23.77,82.84)
D_PWM_3: length 73.4
  TOP w0.178: J39.9 v1(14.68,24.08) ; J24.18 22.57,38.1 v1(21.67,39)
  LY3 w0.171: v1(22.9,82.19) 22.16,82.19 21.7,81.74 21.7,81.28 17.17,76.75 17.17,66.69 17.12,66.64 17.12,65.65 17.01,65.53 17.01,64.21 17.04,64.17 17.04,63.13 16.22,62.31 16.22,60.97 17.8,59.38 17.8,42.88 19.07,41.61 19.07,41.6 v1(21.67,39)
  LY4 w0.171: v1(14.68,24.08) 13.96,24.8 13.96,31.29 v1(21.67,39)
  BOTTOM w0.178: U506.16 v1(22.9,82.19)
D_SPARE_1: length 19
  TOP w0.178: v1(7.87,25.27) 6.97,25.27 6.29,25.96 4.48,25.96 3.85,25.33 J38.10
  BOTTOM w0.178: v1(7.87,25.27) 7.87,25.26 7.45,24.84 7.45,23.39 9.16,21.69 10.57,21.69 12.45,19.81 12.45,17.27 11.28,16.1 U519.16
D_SPARE_2: length 18
  TOP w0.178: J38.11 7.2,26.58 v1(7.24,26.54)
  BOTTOM w0.178: v1(7.24,26.54) 6.82,26.12 6.82,23.11 8.8,21.13 10.11,21.13 11.81,19.43 11.81,17.39 11.17,16.75 U519.15
DA0: length 17.7
  TOP w0.178: U11.AB8 v2(102.66,70.2)
  LY4 w0.102: 107.63,69.89 106.92,70.59 105.38,70.59 105.12,70.33 105.12,69 104.85,68.73 102.53,68.73 102.27,68.99 102.27,69.79 102.65,70.18 102.65,70.19 v2(102.66,70.2)
  LY4 w0.171: 107.63,69.89 109.09,68.43 109.09,67.72 110.4,66.41 110.49,66.41 110.5,66.42 111.24,66.42 111.62,66.04 111.7,66.11 v2(111.7,66.13)
  BOTTOM w0.178: v2(111.7,66.13) 111.7,66.11 111.76,66.05 111.76,65.49 111.97,65.28 C648.1 R646.1
DA1: length 21.9
  TOP w0.102: U11.AF4 106.42,66.44 107.6,66.44 107.63,66.47
  TOP w0.178: v2(111.71,64.13) 111.7,64.13 111.7,64.14 111.72,64.14 112.2,64.62 115.1,64.62 115.62,65.14 115.62,65.96 114.92,66.65 113.61,66.65 113.4,66.44 112.76,66.44 112.49,66.72 112.49,67.54 113.21,68.26 113.21,68.78 112.74,69.26 110.59,69.26 110.24,68.91 109.12,68.91 108.08,67.86 108.08,66.91 107.63,66.47
  BOTTOM w0.178: v2(111.71,64.13) 111.71,64.13 112.06,63.78 112.42,63.78 C649.1 R647.1
DA2: length 32.1
  TOP w0.102: 107.63,67.04 107.3,66.72 106.9,66.72 106.43,67.19 105.67,67.19 105.65,67.21
  TOP w0.178: v2(112.45,59.19) 112.6,59.35 112.6,61.03 112.75,61.18 112.75,61.72 113.35,62.32 115.48,62.32 116.3,63.14 116.93,63.14 117.71,63.93 117.71,67.05 117.26,67.51 114.28,67.51 113.86,67.93 113.86,69.94 112.59,71.21 111.01,71.21 110.68,70.88 110.68,69.93 110.19,69.44 108.93,69.44 107.63,68.14 107.63,67.04 ; 105.65,67.21 U11.AE5
  BOTTOM w0.178: C651.1 R689.1 v2(112.45,59.19)
DA3: length 9.8
  TOP w0.178: U11.AD6 v2(104.66,68.2)
  BOTTOM w0.102: 107.63,67.32 107.16,67.8 105.2,67.8 104.99,68 104.86,68 v2(104.66,68.2)
  BOTTOM w0.178: C654.1 R653.1 108.84,62.99 108.46,63.37 108.46,63.91 107.97,64.4 107.97,65.8 107.7,66.07 107.7,67.26 107.63,67.32
DADADD0: length 94.8
  LY3 w0.171: v1(126.91,31.69) 126.61,31.99 126.61,33.1 126.25,33.47 126.25,41.25 123.16,44.33 123.16,45.49 121.34,47.32 121.17,47.32 119.58,48.91 119.16,49.33 119.16,52.21 119.16,52.51 119.92,53.27 119.92,53.94 119.42,54.44 119.36,54.38 119.25,54.49 119.25,56.34 119.25,56.34 119.25,56.93 119.25,57.42 119.26,57.44 119.26,58.15 119.06,58.35 119.06,59.5 118.5,60.06 117.97,60.06 117.57,60.46 117.57,61.72 117.42,61.88 117.42,62.73 117.57,62.88 117.57,63.2 116.71,64.07 v1(116.71,64.52)
  LY4 w0.102: 97.64,19.61 97.64,25.66 97.23,26.06 95.25,26.06 v1(94.64,26.67)
  LY4 w0.171: v1(126.91,31.69) 125.77,31.69 125.67,31.79 123.82,31.79 121.83,29.81 119.54,29.81 117.86,28.12 117.86,18.7 117.55,18.39 117.55,18.38 116.76,17.59 114.95,17.59 114.54,17.18 111.28,17.18 110.02,18.44 102.67,18.44 100.31,18.44 99.74,17.87 98.81,17.87 98.24,18.44 98.03,18.44 97.62,18.85 97.64,18.86 97.64,19.61
  BOTTOM w0.178: J500.13E v1(94.64,26.67) ; R646.2 v1(116.71,64.52)
DADADD1: length 88.1
  LY3 w0.171: v1(115.57,63.35) 116.41,63.35 116.99,62.76 116.99,61.7 117.1,61.59 117.1,59.99 117.38,59.71 118.36,59.71 118.71,59.36 118.71,58.2 118.91,58 118.91,57.58 118.89,57.57 118.89,57.08 118.89,54.41 118.54,54.06 118.37,53.66 118.37,53.29 118.41,53.25 118.41,53.21 118.81,52.81 118.81,52.63 118.81,52.63 118.81,52.07 118.81,49.18 119.02,48.97 119.43,48.55 121.02,46.96 122.81,45.18 122.81,44.18 122.96,44.03 122.96,43.41 123.57,42.8 123.57,41.49 125.9,39.16 125.9,32.87 v1(126.02,32.75)
  LY4 w0.102: 99.16,19.61 98.98,19.79 98.98,27.16 98.7,27.45 95.13,27.45 v1(94.64,27.94)
  LY4 w0.171: v1(126.02,32.75) 123.52,32.75 121.48,30.7 118.36,30.7 117.14,29.48 117.14,23.42 114.45,20.73 113.87,20.73 112.38,19.24 99.38,19.24 99.16,19.46 99.16,19.61
  BOTTOM w0.178: J500.13F 94.34,27.64 ; v1(115.57,63.35) 115.21,62.99 R647.2
  BOTTOM w0.254: 94.34,27.64 v1(94.64,27.94)
DADADD2: length 87.5
  LY3 w0.171: v1(122.05,20.31) 122.81,21.08 122.81,23.17 122.59,23.39 122.59,24.76 123.14,25.31 123.58,25.31 124.87,26.6 124.87,30.35 124.77,30.45 124.22,31.01 123.86,31.36 123.83,31.39 123.68,31.55 123.59,31.64 123.51,31.71 123.34,31.88 123.34,32.91 124.41,33.97 124.41,35.24 124.01,35.65 123.89,35.76 123.89,37.14 121.45,39.58 121.45,39.98 121.85,40.38 121.85,41.79 121.49,42.14 121.49,43.53 121.37,43.64 121.37,44.5 117.33,48.54 117.33,52.24 117.06,52.51 116.86,52.71 116.86,53.48 116.82,53.56 116.86,53.64 116.86,53.77 116.99,53.98 117.19,54.46 117.26,54.8 117.3,54.83 117.3,54.98 117.34,55.19 117.3,55.26 117.3,56.38 117.24,56.67 115.64,58.27 v1(115.64,59.94)
  LY4 w0.171: v1(122.05,20.31) 121.81,20.08 121.49,20.08 120.94,20.09 119.99,19.14 119.99,17.81 118.47,16.28 118.47,15.66 118.26,15.46 115.83,15.46 115.42,15.05 110.39,15.05 109.34,16.1 109.14,16.31 101.79,16.31 101.2,16.31 100.63,15.74 99.43,15.74 99.42,15.74 98.25,15.74 97.93,15.74 97.51,16.15 97.36,16.31 95.28,16.31 95.07,16.51 94.59,17 94.59,17.83 93.3,19.12 93.3,20.68 92.39,21.59 v1(92.1,21.59)
  BOTTOM w0.178: R689.2 v1(115.64,59.94)
  BOTTOM w0.254: J500.14A v1(92.1,21.59)
DADADD3: length 106.4
  TOP w0.178: v1(122.09,21.76) 122.09,22.91 119.55,25.45 119.55,32.72 119.14,33.13 110.28,33.13 108.84,34.56 105.59,34.56 101.87,38.29 101.87,48.07 104.47,50.67 109.66,50.67 110.55,51.56 110.55,58.97 111.42,59.84 111.87,59.84 112.23,60.2 112.23,61.18 112.38,61.33 112.38,61.78 112.07,62.09 111.92,62.09 111.92,62.09 111.92,62.09 111.53,62.48 111.19,62.48 111.19,62.49 v1(111.19,62.49)
  LY4 w0.171: v1(122.09,21.76) 121.94,21.61 121.94,21.31 121.08,20.45 120.8,20.45 119.64,19.29 119.64,17.96 117.5,15.81 115.68,15.81 115.28,15.41 110.54,15.41 109.7,16.25 109.28,16.66 101.93,16.66 101.05,16.66 100.48,16.09 99.28,16.09 99.28,16.09 98.39,16.09 98.08,16.09 97.87,16.3 97.51,16.66 95.43,16.66 94.95,17.15 94.95,17.97 94.57,18.35 94.57,21.24 92.95,22.86 v1(92.1,22.86)
  BOTTOM w0.178: R653.2 110.58,62.99 110.67,62.9 111.04,62.9 111.12,62.82 111.12,62.81 111.12,62.48 111.19,62.48 111.19,62.49 v1(111.19,62.49)
  BOTTOM w0.254: J500.14B v1(92.1,22.86)
DADINTZ: length 123.3
  LY3 w0.171: v1(115.94,68.94) 116.17,68.71 116.17,68.5 117.23,67.44 117.25,67.44 117.6,67.09 117.6,66.59 118.39,65.8 118.39,65.38 119.19,64.58 119.19,63.02 119.48,62.73 119.48,61.88 119.19,61.59 119.19,60.88 120.25,59.82 120.25,58.67 121.29,57.62 121.29,52.88 120.23,51.82 120.23,49.77 121.61,48.39 123.2,48.39 125.37,46.21 125.37,43.88 129.14,40.11 129.14,36.03 130.49,34.68 130.49,25.66 130.49,25.07 130.04,24.63 129.14,23.72 129.14,23.59 v1(128.23,22.68)
  LY4 w0.171: v1(128.23,22.68) 127.32,22.68 126.87,22.23 126.87,18.92 124.66,16.71 122.6,16.71 121.16,15.27 121.16,14 119.03,11.87 117.2,11.87 117.15,11.83 114.35,11.83 114.16,11.65 113.95,11.65 113.78,11.48 112.35,11.48 111.51,10.64 106.96,10.64 106.25,11.36 105.24,11.36 103.49,13.1 102.31,13.1 101.61,12.41 100.32,12.41 98.85,13.87 92.9,13.87 91.64,15.13 91.64,16.22 90.42,17.44 88.69,17.44 86.4,19.73 86.4,23.37 87.47,24.44 89.6,24.44 90.19,25.03 90.19,26.07 90.79,26.67 v1(90.83,26.67)
  BOTTOM w0.178: v1(115.94,68.94) 115.66,69.22 R621.2
  BOTTOM w0.254: J500.15E v1(90.83,26.67)
DADMD0: length 93.9
  LY3 w0.171: v1(121.6,27.63) 121.6,27.94 120.33,29.2 119.84,29.2 118.9,30.14 118.9,34.71 119.2,35.01 119.2,36.33 119.61,36.74 119.61,37.54 119.23,37.91 118.07,37.91 117.71,38.28 117.71,40.23 117.37,40.56 117.37,41.63 117.28,41.72 117.28,45.14 111.02,51.4 111.02,54.06 109.78,55.31 109.78,63.84 110.55,64.62 v2(111.09,64.62)
  LY4 w0.171: v1(121.6,27.63) 122.09,27.14 122.09,23.45 122.68,22.85 122.68,20.05 121.19,18.55 121.19,18.5 118.82,16.13 118.82,14.97 118.06,14.21 114.56,14.21 114.07,14.69 110.24,14.69 108.99,15.95 101.64,15.95 101.34,15.95 100.78,15.38 99.57,15.38 99.57,15.38 98.1,15.38 97.78,15.38 97.21,15.95 95.14,15.95 94.72,16.37 94.2,16.89 94.2,17.71 92.93,18.99 92.93,19.93 91.26,21.59 v1(90.83,21.59)
  BOTTOM w0.178: v2(111.09,64.62) 110.99,64.52 R652.2
  BOTTOM w0.508: J500.15B v1(90.83,21.59)
DADMD1: length 104.9
  LY3 w0.171: v1(124.28,21.18) 125.09,22 125.09,22.83 126.88,24.62 129.03,24.62 129.33,24.92 129.78,25.37 129.78,32.74 127.19,35.33 127.19,37.83 126.61,38.41 126.61,38.87 126.61,38.87 126.61,39.46 126.61,41.39 123.52,44.48 123.52,44.97 124.07,45.53 124.07,46.5 122.9,47.68 121.32,47.68 119.73,49.26 119.52,49.47 119.52,52.36 120.28,53.12 120.28,54.08 119.6,54.76 119.6,56.49 119.6,57.28 119.62,57.29 119.62,58.29 119.42,58.49 119.42,59.65 118.12,60.95 118.12,61.79 117.85,62.06 117.85,62.55 118.12,62.81 118.12,64.16 115.91,66.37 v1(115.91,66.8)
  LY4 w0.171: v1(90.83,22.86) 90.14,22.17 90.14,21.12 90.36,20.9 91.37,20.9 92.22,20.05 92.22,19.06 93.85,17.44 93.85,17.03 93.85,16.74 94.36,16.22 94.78,15.8 94.99,15.6 97.06,15.6 97.63,15.03 97.66,15.03 97.95,15.03 97.95,15.02 99.72,15.02 99.72,15.03 100.92,15.03 101.49,15.6 107.04,15.6 107.21,15.43 108.51,15.43 108.94,15.01 109.43,15.01 110.1,14.33 110.8,14.33 110.8,14.34 113.93,14.34 114.41,13.86 118.21,13.86 119.18,14.82 119.18,15.98 123.04,19.85 123.04,19.94 v1(124.28,21.18)
  BOTTOM w0.178: R645.2 v1(115.91,66.8) ; J500.15C v1(90.83,22.86)
DADOEZ: length 101.2
  LY3 w0.171: v1(122.55,29.39) 122.54,29.39 122.52,29.42 120.62,29.42 120.48,29.56 120.3,29.56 119.25,30.6 119.25,33.03 119.98,33.76 120.69,33.76 121.18,34.25 121.18,34.96 120.75,35.39 120.75,37.33 120.14,37.94 119.71,37.94 118.06,39.58 118.06,40.38 118.02,40.42 118.02,43.6 117.64,43.98 117.64,45.29 111.82,51.11 111.82,54.8 110.31,56.3 110.31,62.45 110.95,63.09 111.44,63.09 111.87,62.66 112.78,62.66 112.91,62.79 112.91,64.45 111.87,65.49 v2(110.83,65.49)
  LY4 w0.102: 96.37,19.61 96.39,19.63 96.39,25.7 96.24,25.86 94.69,25.86 94.18,26.36 94.18,26.86 94.56,27.23 95.02,27.23 95.58,26.67 v1(95.91,26.67)
  LY4 w0.171: v1(122.55,29.39) 121.18,29.39 120.64,28.86 120.64,27.24 121,26.88 121,22.5 120.64,22.14 120.3,22.14 119.68,21.51 119.68,20.89 118.57,19.78 118.57,18.4 117.05,16.88 115.24,16.88 114.84,16.47 110.98,16.47 110.77,16.69 109.72,17.73 102.38,17.73 100.61,17.73 100.04,17.16 98.84,17.16 98.83,17.16 98.52,17.16 97.95,17.73 97.35,17.73 96.37,18.71 96.37,19.61
  BOTTOM w0.178: 95.28,26.04 v1(95.91,26.67) ; v2(110.83,65.49) 110.87,65.49 110.87,65.54 110.61,65.28 R651.2
DADSEL0: length 119.6
  LY3 w0.171: v1(117.01,66.84) 117.01,66.27 118.71,64.56 118.71,62.88 119.05,62.55 119.05,62.06 118.71,61.73 118.71,60.86 119.9,59.68 119.9,58.52 120.31,58.1 120.31,57.48 119.96,57.13 119.96,56.64 120.89,55.71 120.89,53.23 119.88,52.21 119.88,49.62 121.46,48.03 123.05,48.03 125.02,46.06 125.02,43.72 127.02,41.72 127.02,38.51 127.61,37.92 127.61,36.22 130.14,33.69 130.14,25.51 130.14,25.22 129.69,24.77 129.69,24.77 129.18,24.26 127.79,24.26 v1(125.85,22.32)
  LY4 w0.171: v1(92.1,25.4) 91.77,25.4 91.05,24.68 90.31,24.68 89.66,24.03 88.33,24.03 87.68,23.38 87.68,19.47 88.98,18.17 90.49,18.17 92,16.66 92,15.46 93.24,14.23 94.58,14.23 95.17,14.82 96.83,14.82 97.34,14.31 97.36,14.31 97.66,14.31 99.76,14.31 99.76,14.31 103.01,14.31 103.52,14.82 104.49,14.82 105.56,13.75 105.56,13.66 106.69,12.53 107.52,12.53 108.15,11.9 113.7,11.9 113.8,12 113.95,12 114.25,12.31 118.85,12.31 120.73,14.18 120.73,15.45 122.7,17.42 124.61,17.42 126.36,19.18 126.36,21.72 125.85,22.24 v1(125.85,22.32)
  BOTTOM w0.178: R644.2 116.48,67.69 117.01,67.17 v1(117.01,66.84)
  BOTTOM w0.254: J500.14D v1(92.1,25.4)
DADSEL1: length 111.3
  LY3 w0.171: v1(116.34,62.23) 116.34,58.32 117.67,56.99 117.73,56.7 117.73,54.74 117.58,54.59 117.54,54.36 117.31,53.81 117.21,53.66 117.21,53.57 117.21,53.56 117.21,53.55 117.21,52.86 117.73,52.34 117.73,48.65 121.73,44.65 121.73,43.79 121.92,43.6 121.92,42.22 122.32,41.82 122.32,40.35 121.98,40.01 121.98,39.7 124.37,37.31 124.37,35.79 124.56,35.6 124.76,35.39 124.76,33.82 123.94,33 123.94,31.79 124.09,31.64 124.2,31.53 124.51,31.22 124.57,31.16 124.57,31.16 125.02,30.7 125.23,30.5 125.44,30.29 125.44,30.28 125.63,30.09 125.63,26.66 124.88,25.91 124.88,24.9 124.4,24.42 v1(123.37,24.42)
  LY4 w0.171: v1(123.37,24.42) 123.37,23.64 124.44,22.57 124.76,22.57 125.41,21.92 125.41,21.91 125.86,21.46 125.86,19.56 124.91,18.62 123.28,18.62 120.29,15.63 120.29,14.36 118.67,12.74 114.04,12.74 113.64,12.33 108.36,12.33 107.82,12.87 107.82,14.26 106.9,15.18 103.37,15.18 102.87,14.67 99.87,14.67 97.8,14.67 97.49,14.67 96.98,15.18 94.91,15.18 94.35,14.62 93.86,14.62 93.51,14.97 93.51,15.15 92.45,16.21 92.45,17.27 90.71,19.02 89.66,19.02 88.98,19.7 88.98,23.18 89.39,23.59 92.41,23.59 92.85,24.03 92.85,26.31 92.49,26.67 v1(92.1,26.67)
  BOTTOM w0.178: R648.2 v1(116.34,62.23)
  BOTTOM w0.254: J500.14E v1(92.1,26.67)
DADSTB: length 87.3
  LY3 w0.171: v1(111.62,60.43) 112.33,60.43 113.59,59.17 113.59,57.08 112.62,56.12 112.62,51.31 119.8,44.13 119.8,39.28 120.44,38.65 120.44,38.65 121.46,37.62 121.46,35.69 121.89,35.25 121.89,32.99 TP55.1 120.65,30.76 121.06,30.34 122.94,30.34 123.26,30.03 123.5,29.78 123.5,27.3 122.88,26.68 122.15,26.68 122.12,26.68 121.62,26.68 121.15,26.21 121.15,22.64 120.63,22.13 120.63,21.17 120.65,21.15 v1(120.66,21.15)
  LY4 w0.171: v1(94.64,22.86) 94.77,22.86 95.4,22.23 95.4,17.8 96.18,17.02 97.65,17.02 97.81,16.86 98.22,16.45 98.25,16.45 98.54,16.45 99.13,16.45 99.13,16.45 100.33,16.45 100.9,17.02 102.08,17.02 109.43,17.02 110.05,16.39 110.69,15.76 115.13,15.76 115.54,16.17 117.35,16.17 119.28,18.1 119.28,19.44 119.93,20.08 120.63,20.78 120.63,21.12 v1(120.66,21.15)
  BOTTOM w0.178: v1(111.62,60.43) 111.35,60.71 R654.2
  BOTTOM w0.254: J500.13C v1(94.64,22.86)
DASYNC: length 7.1
  TOP w0.178: J9.4 v1(59.36,108.58)
  BOTTOM w0.178: R531.2 63.76,105.9 62.75,106.9 61.03,106.9 v1(59.36,108.58)
DB/RED_PWM: length 221.9
  TOP w0.178: v1(50.38,91.24) 50.38,91.39 50.25,91.52 U7.53 ; v1(59.68,55.51) 59.65,55.51 59.61,55.54 59.61,56.04 60.47,56.9 61,56.9 61.2,56.7 63.09,56.7 64.21,57.82 64.21,62.72 62.92,64.02 62.92,72.69 66.81,76.59 66.81,81.73 65.33,83.21 57.09,83.21 57.08,83.22 55.7,83.22 54.53,84.39 54.53,85.83 55.44,86.73 55.44,88.28 55.71,88.55 55.71,89.08 55.44,89.35 55.44,90.24 55.87,90.67 55.87,91.81 55.59,92.09 55.59,93.88 55.59,93.88 55.59,94.41 55.96,94.79 56.25,94.79 56.38,94.92 56.88,94.92 57.01,94.79 59.01,94.79 v1(59.69,94.11) ; U11.B19 v2(81.66,82.2)
  TOP w0.254: U8.2 59.03,93.1 59.69,93.76 v1(59.69,94.11)
  LY3 w0.171: v1(58.74,9.91) 58.51,10.13 54.25,10.13 54.22,10.17 53.72,10.17 53.69,10.13 52.95,10.13 52.63,10.46 44.7,10.46 37.13,18.03 37.13,18.27 36.63,18.77 36.63,19.69 37.89,20.95 42.56,20.95 46.76,25.14 46.76,31.36 47.68,32.28 47.68,32.8 48.01,33.13 48.5,33.63 49.43,33.63 50.19,34.39 50.19,34.89 51.21,35.91 51.21,37.56 52.58,38.93 52.58,41.67 53.19,42.28 53.19,42.49 54.16,43.47 54.16,45.87 54.16,46.91 54.9,47.64 55.49,47.64 56.74,48.89 57.02,48.89 57.85,49.72 57.85,49.85 57.85,50.59 59.12,51.86 59.56,51.86 60.52,52.82 60.52,54.18 59.68,55.02 v1(59.68,55.51) ; v1(50.38,91.24) 52.26,91.24 53.56,92.54 53.56,94.33 52.7,95.18 52.7,100.98 53.27,101.54 53.27,101.54 53.62,101.89 53.62,101.89 53.98,102.26 53.98,109.46 52.11,111.34 v1(51.11,111.34)
  BOTTOM w0.102: v2(81.66,82.2) 81.66,81.76 81.27,81.36 81.27,81.22 81.25,81.2 81.25,80.07 80.85,79.67 79.69,79.67
  BOTTOM w0.178: v1(50.38,91.24) 51.88,92.75 53.01,92.75 54.62,94.35 55.53,94.35 55.96,94.79 56.25,94.79 56.38,94.92 56.88,94.92 57.01,94.79 57.57,94.79 58.25,94.11 v1(59.69,94.11) 61.06,94.11 63.39,91.78 63.39,88.92 67.92,84.4 67.92,80.95 68.7,80.17 68.79,80.17 71.1,77.86 74.38,77.86 74.38,77.86 77.32,77.86 77.66,78.21 77.86,78.21 79.32,79.67 79.69,79.67 79.69,79.67 ; v1(51.11,111.34) 51.12,111.34 51.29,111.17 RN500.4 ; v1(58.74,9.91) 58.74,6.99 59.13,6.59 R769.2 59.83,6.6 U523.2
DCLKA_N: length 51.3
  TOP w0.178: U11.V3 v2(98.66,65.2)
  LY4 w0.102: v2(98.66,65.2) 98.59,65.27 98.59,65.49 98.73,65.64 98.91,65.64 99.06,65.48 99.06,62.8 99.04,62.78 99.04,62.75
  LY4 w0.105: v1(104.8,22.86) 104.68,22.74 104.68,22.48 104.88,22.29 105.14,22.29 105.28,22.43 105.28,30.09 105.91,30.72 105.91,35.32 105.81,35.42 105.39,35.42 105.01,35.81 105.01,36.38 105.31,36.68 105.62,36.68 105.62,36.68 105.87,36.68 106.01,36.82 106.01,37.22 105.03,38.2 105.03,38.2 104.88,38.35 104.88,41.16 101.75,44.28 101.75,57.33 99.26,59.82 99.26,61.87 99.04,62.09 99.04,62.75
  BOTTOM w0.178: 104.17,23.5 v1(104.8,22.86)
DCLKA_P: length 51.3
  TOP w0.178: U11.V4 v2(98.66,66.2)
  LY4 w0.102: v2(98.66,66.2) 99.27,65.59 99.27,62.8 99.29,62.78 99.29,62.75
  LY4 w0.105: 99.29,62.75 99.29,62.2 99.52,61.98 99.52,59.92 102.01,57.43 102.01,44.39 105.13,41.26 105.13,38.46 105.14,38.46 106.27,37.32 106.27,36.71 105.98,36.43 105.51,36.43 105.51,36.43 105.41,36.43 105.26,36.27 105.26,35.91 105.5,35.67 105.92,35.67 106.17,35.42 106.17,30.62 105.54,29.99 105.54,22.32 104.81,21.59 v1(104.8,21.59)
  BOTTOM w0.178: v1(104.8,21.59) J500.5B
DCLKB_N: length 49.4
  TOP w0.178: U11.J4 v2(88.66,66.2)
  LY3 w0.102: v2(88.66,66.2) 88.66,65.92 88.78,65.8 89.07,65.8 89.26,65.61 89.26,62.79 89.05,62.58 89.05,61.69
  LY3 w0.105: 82.72,22.51 82.71,22.51 82.71,28.73 85.93,31.94 85.93,31.94 86.08,32.09 86.08,32.17 86.08,32.17 86.08,55.25 88.38,57.55 88.38,60.73 88.38,60.74 88.38,61.02 89.05,61.69
  LY3 w0.108: 82.72,22.51 82.87,22.36 83.1,22.36 83.21,22.47 v1(83.21,22.86)
  BOTTOM w0.108: J500.21C v1(83.21,22.86)
DCLKB_P: length 49.5
  TOP w0.178: U11.J3 v2(88.66,65.2)
  LY3 w0.102: 88.85,61.84 88.85,61.84 88.85,62.66 89.06,62.88 89.06,65.52 88.98,65.6 88.76,65.6 88.66,65.5 v2(88.66,65.2)
  LY3 w0.105: 88.85,61.84 88.13,61.13 88.13,60.63 88.13,60.63 88.13,57.66 85.83,55.36 85.83,32.28 85.83,32.28 85.83,32.2 85.82,32.2 82.46,28.83 82.46,22.4
  LY3 w0.108: v1(83.21,21.59) 83.21,21.96 83.07,22.1 82.76,22.1 82.46,22.4
  BOTTOM w0.108: J500.21B v1(83.21,21.59)
DDA00_N: length 51.2
  TOP w0.178: U11.P3 v2(93.66,65.2)
  LY3 w0.102: v2(93.66,65.2) 93.61,65.26 93.61,65.56 93.72,65.67 93.92,65.67 94.06,65.52 94.06,62.87 94.04,62.84 94.04,62.82
  LY3 w0.105: v1(98.45,26.67) 98.45,26.16 98.52,26.09 98.71,26.09 98.95,26.33 98.95,28.24 98.96,28.24 98.96,28.36 98.76,28.55 98.76,28.55 93.48,28.55 90.96,31.08 90.96,53.47 94.74,57.25 94.74,61.84 94.04,62.55
  LY3 w0.108: 94.04,62.82 94.04,62.55
  BOTTOM w0.108: 97.82,26.04 v1(98.45,26.67)
DDA00_P: length 51.3
  TOP w0.178: U11.P4 v2(93.66,66.2)
  LY3 w0.102: v2(93.66,66.2) 93.67,66.2 93.72,66.14 93.73,66.14 94.26,65.61 94.26,62.87 94.29,62.84 94.29,62.82 94.29,62.82
  LY3 w0.105: v1(98.45,25.4) 98.89,25.84 98.89,25.91 99.21,26.23 99.21,28.14 99.21,28.14 99.21,28.46 98.87,28.81 98.65,28.81 98.65,28.81 93.59,28.81 91.21,31.18 91.21,53.36 94.99,57.14 94.99,61.95 94.29,62.65 94.29,62.65
  LY3 w0.108: 94.29,62.82 94.29,62.65
  BOTTOM w0.108: J500.10D v1(98.45,25.4)
DDA01_N: length 51.1
  TOP w0.178: U11.P1 v2(94.66,63.2)
  LY4 w0.102: v2(94.66,63.2) 94.59,63.27 94.59,63.55 94.67,63.63 94.9,63.63 95.06,63.46 95.06,62.79 95.04,62.76 95.04,62.75 95.03,62.75 95.03,62.74
  LY4 w0.105: 95.03,62.74 95.03,62.52 94.75,62.24 94.75,58.72 95.88,57.6 95.88,55.64 95.06,54.83 95.06,40.08 97.16,37.99 97.16,36.93 97.08,36.85 95.62,36.85 95.33,36.56 95.33,35.96 95.6,35.69 97.06,35.69 97.15,35.59 97.15,33.06 99.54,30.67 99.54,29.93 100.27,29.2 100.27,22.51 100.04,22.27 99.8,22.27 99.64,22.44 99.64,22.78 v1(99.72,22.86)
  BOTTOM w0.178: 99.09,23.5 v1(99.72,22.86)
DDA01_P: length 51.1
  TOP w0.178: U11.P2 v2(94.66,64.2)
  LY4 w0.102: 95.29,62.74 95.29,62.75 95.27,62.77 95.27,63.6 v2(94.66,64.2)
  LY4 w0.105: 95.29,62.74 95.29,62.41 95.01,62.13 95.01,58.83 96.13,57.71 96.13,55.54 95.32,54.72 95.32,40.19 97.41,38.09 97.41,36.82 97.18,36.6 95.72,36.6 95.58,36.45 95.58,36.07 95.7,35.94 97.16,35.94 97.41,35.7 97.41,33.16 99.79,30.78 99.79,30.04 100.53,29.3 100.53,22.4 100.14,22.02 100.14,22.01 v1(99.72,21.59)
  BOTTOM w0.178: v1(99.72,21.59) J500.9B
DDA02_N: length 52.2
  TOP w0.178: U11.R3 v2(95.66,65.2)
  LY3 w0.102: v2(95.66,65.2) 95.51,65.35 95.51,65.55 95.64,65.68 95.9,65.68 96.06,65.52 96.06,62.82 96.04,62.79 96.04,62.77 96.03,62.77
  LY3 w0.105: 100.12,27.45 100.22,27.55 100.22,28.51 100.47,28.75 100.47,29.26 100.29,29.44 94,29.44 91.83,31.61 91.83,32.57 92.13,32.87 92.61,32.87 92.8,33.06 92.8,33.33 92.61,33.52 92.13,33.52 91.87,33.77 91.87,52.95 95.71,56.78 95.71,62.15 95.76,62.21 95.76,62.21 96.03,62.48 96.03,62.77
  LY3 w0.108: 100.12,27.45 100.04,27.36 99.87,27.36 99.72,27.52 99.72,27.93 v1(99.72,27.94)
  BOTTOM w0.108: J500.9F v1(99.72,27.94)
DDA02_P: length 52.2
  TOP w0.178: U11.R4 v2(95.66,66.2)
  LY3 w0.102: v2(95.66,66.2) 95.69,66.2 96.07,65.82 96.07,65.82 96.26,65.62 96.26,62.82 96.29,62.79 96.29,62.77
  LY3 w0.105: 100.32,27.26 100.48,27.42 100.48,28.4 100.72,28.65 100.72,29.37 100.4,29.69 94.11,29.69 92.08,31.71 92.08,32.46 92.24,32.61 92.71,32.61 93.05,32.95 93.05,33.43 92.71,33.77 92.23,33.77 92.13,33.88 92.13,52.84 95.96,56.68 95.96,61.97 95.96,61.98 95.96,62.05 96.29,62.37 96.29,62.77
  LY3 w0.108: 100.32,27.26 99.73,26.67 v1(99.72,26.67)
  BOTTOM w0.108: 99.09,26.04 v1(99.72,26.67)
DDA03_N: length 50.6
  TOP w0.178: U11.R1 v2(95.66,63.2)
  LY4 w0.102: 96.04,62.79 96.04,62.8 96.06,62.83 96.06,63.46 95.89,63.64 95.72,63.64 95.6,63.52 95.6,63.27 v2(95.66,63.2)
  LY4 w0.105: v1(100.99,21.59) 100.97,21.57 100.97,21.1 101.11,20.96 101.27,20.96 101.51,21.2 101.51,30.43 99.14,32.8 99.14,40.36 98.92,40.57 98.1,40.57 97.81,40.86 97.81,41.43 98.09,41.71 98.99,41.71 99.14,41.85 99.14,42.28 97.51,43.91 97.51,55.12 97.17,55.47 97.17,55.48 97.17,55.48 97.17,57.82 95.76,59.23 95.76,61.98 95.76,61.99 95.76,62.08 96.04,62.35 96.04,62.79
  BOTTOM w0.108: J500.8B v1(100.99,21.59)
DDA03_P: length 50.7
  TOP w0.178: U11.R2 v2(95.66,64.2)
  LY4 w0.102: 96.29,62.79 96.29,62.81 96.27,62.84 96.27,63.6 v2(95.66,64.2)
  LY4 w0.105: 96.29,62.79 96.29,62.25 96.02,61.98 96.02,61.88 96.02,61.87 96.02,59.33 97.42,57.93 97.42,55.58 97.42,55.58 97.42,55.57 97.77,55.23 97.77,44.01 99.39,42.38 99.39,41.75 99.1,41.45 98.2,41.45 98.07,41.32 98.07,40.97 98.21,40.83 99.03,40.83 99.39,40.46 99.39,32.91 101.77,30.54 101.77,21.1 101.38,20.71 v1(100.99,20.32)
  BOTTOM w0.178: v1(100.99,20.32) J500.8A
DDA04_N: length 51.9
  TOP w0.178: U11.T3 v2(96.66,65.2)
  LY3 w0.102: 97.04,62.77 97.04,62.79 97.06,62.82 97.06,65.52 96.9,65.68 96.61,65.68 96.49,65.56 96.49,65.38 v2(96.66,65.2)
  LY3 w0.105: v1(100.99,26.67) 100.99,26.29 101.12,26.16 101.39,26.16 101.5,26.27 101.5,29.67 100.87,30.3 95.51,30.3 94.89,30.92 94.89,33.35 94.34,33.9 93.61,33.9 92.86,34.65 92.86,52.64 96.59,56.36 96.59,61.72 97.04,62.17 97.04,62.77
  BOTTOM w0.108: 100.36,26.04 v1(100.99,26.67)
DDA04_P: length 51.9
  TOP w0.178: U11.T4 v2(96.66,66.2)
  LY3 w0.102: 97.29,62.77 97.29,62.79 97.26,62.82 97.26,65.61 96.67,66.2 v2(96.66,66.2)
  LY3 w0.105: 97.29,62.77 97.29,62.06 96.84,61.61 96.84,56.26 93.11,52.53 93.11,34.75 93.71,34.15 94.44,34.15 95.14,33.45 95.14,31.03 95.62,30.55 100.97,30.55 101.75,29.77 101.75,26.16 v1(100.99,25.4)
  BOTTOM w0.108: J500.8D v1(100.99,25.4)
DDA05_N: length 51.3
  TOP w0.178: U11.T1 v2(96.66,63.2)
  LY4 w0.102: 97.04,62.74 97.04,62.76 97.06,62.79 97.06,63.49 96.93,63.63 96.65,63.63 96.58,63.56 96.58,63.28 v2(96.66,63.2)
  LY4 w0.105: 97.04,62.74 97.04,62.1 96.64,61.71 96.64,59.72 99.66,56.71 99.66,54.81 99.48,54.64 98.75,54.64 98.47,54.36 98.47,53.74 98.75,53.46 99.55,53.46 99.55,53.46 99.67,53.34 99.67,52.98 99.54,52.85 98.76,52.85 98.48,52.58 98.48,52 98.76,51.72 99.55,51.72 99.6,51.67 99.6,51.67 99.66,51.61 99.66,51.61 99.66,43.35 101.52,41.49 101.52,38.61 102.51,37.62 102.51,33.34 102.81,33.04 102.81,22.5 102.58,22.27 102.34,22.27 102.25,22.36 102.25,22.84 v1(102.26,22.86)
  BOTTOM w0.178: 101.63,23.5 v1(102.26,22.86)
DDA05_P: length 51.3
  TOP w0.178: U11.T2 v2(96.66,64.2)
  LY4 w0.102: 97.29,62.74 97.29,62.76 97.27,62.79 97.27,63.6 v2(96.66,64.2)
  LY4 w0.105: v1(102.26,21.59) 103.07,22.39 103.07,33.14 102.76,33.44 102.76,37.72 101.77,38.71 101.77,41.6 99.91,43.46 99.91,51.51 99.91,51.51 99.91,51.72 99.86,51.78 99.86,51.78 99.66,51.98 98.86,51.98 98.73,52.1 98.73,52.47 98.86,52.6 99.65,52.6 99.93,52.88 99.93,53.44 99.91,53.46 99.65,53.72 98.85,53.72 98.73,53.84 98.73,54.26 98.85,54.38 99.59,54.38 99.91,54.71 99.91,54.8 99.91,54.8 99.91,56.81 96.9,59.83 96.9,61.6 97.29,62 97.29,62.74
  BOTTOM w0.178: v1(102.26,21.59) J500.7B
DDA06_N: length 51.8
  TOP w0.178: U11.U3 v2(97.66,65.2)
  LY3 w0.102: v2(97.66,65.2) 97.58,65.28 97.58,65.59 97.69,65.7 97.88,65.7 98.06,65.52 98.06,62.82 98.04,62.79 98.04,62.77
  LY3 w0.105: 98.04,62.77 98.04,61.5 98.43,61.1 98.43,59.88 97.78,59.23 97.78,56.13 93.9,52.26 93.9,37.9 94.24,37.56 94.24,37.4 94.52,37.13 94.52,36.92 94.34,36.74 94.16,36.74 93.83,36.42 93.83,35.91 94.15,35.59 95,35.59 95.13,35.46 95.13,35.46 95.18,35.4 95.18,35.4 95.18,34.7 95.82,34.06 95.82,31.93 96.53,31.22 101.83,31.22 102.99,30.06 102.99,28.41 102.77,28.19 102.77,27.53 102.63,27.4 102.36,27.4 102.27,27.49 102.27,27.93 v1(102.26,27.94)
  BOTTOM w0.108: J500.7F v1(102.26,27.94)
DDA06_P: length 51.9
  TOP w0.178: U11.U4 v2(97.66,66.2)
  LY3 w0.102: v2(97.66,66.2) 97.67,66.2 97.72,66.14 97.73,66.14 98.26,65.61 98.26,62.82 98.29,62.79 98.29,62.78 98.29,62.78 98.29,62.77
  LY3 w0.105: 98.29,62.77 98.29,61.6 98.69,61.21 98.69,59.78 98.03,59.12 98.03,56.03 94.15,52.15 94.15,38.01 94.5,37.66 94.5,37.51 94.77,37.23 94.77,36.82 94.44,36.49 94.27,36.49 94.09,36.31 94.09,36.01 94.26,35.84 95.1,35.84 95.38,35.57 95.38,35.57 95.44,35.51 95.44,35.3 95.44,34.8 96.08,34.16 96.08,32.04 96.63,31.48 101.94,31.48 103.25,30.17 103.25,28.31 103.02,28.08 103.02,27.43 102.74,27.15 v1(102.26,26.67)
  BOTTOM w0.108: 101.63,26.04 v1(102.26,26.67)
DDA07_N: length 51
  TOP w0.178: U11.U1 v2(97.66,63.2)
  LY4 w0.102: 98.04,62.77 98.06,62.79 98.06,63.49 97.93,63.62 97.77,63.62 97.66,63.51 v2(97.66,63.2)
  LY4 w0.105: 98.04,62.77 98.04,61.73 98.1,61.66 98.1,59.57 100.57,57.1 100.57,43.84 103.68,40.74 103.68,40.36 103.47,40.15 102.73,40.15 102.41,39.83 102.41,39.27 102.72,38.96 103.51,38.96 103.6,38.87 103.6,35.45 104.7,34.35 104.7,34.35 104.75,34.29 104.75,34.29 104.75,31.18 104.06,30.48 104.06,21.21 103.8,20.94 103.63,20.94 103.45,21.12 103.45,21.51 v1(103.53,21.59)
  BOTTOM w0.108: J500.6B v1(103.53,21.59)
DDA07_P: length 51.1
  TOP w0.178: U11.U2 v2(97.66,64.2)
  LY4 w0.102: 98.3,62.74 98.3,62.75 98.29,62.75 98.29,62.76 98.27,62.79 98.27,63.6 v2(97.66,64.2)
  LY4 w0.105: 98.3,62.74 98.29,62.74 98.29,61.83 98.36,61.77 98.36,59.67 100.83,57.21 100.83,43.95 103.93,40.84 103.93,40.25 103.58,39.9 102.84,39.9 102.66,39.72 102.66,39.37 102.82,39.21 103.62,39.21 103.85,38.98 103.85,35.56 104.95,34.46 104.95,34.45 105.01,34.4 105.01,34.19 105.01,34.18 105.01,31.07 104.31,30.38 104.31,21.1 103.9,20.69 103.9,20.69 103.9,20.69 v1(103.53,20.32)
  BOTTOM w0.178: v1(103.53,20.32) J500.6A
DDA08_N: length 52.2
  TOP w0.178: U11.W3 v2(99.66,65.2)
  LY3 w0.102: v2(99.66,65.2) 99.54,65.32 99.54,65.6 99.65,65.71 99.88,65.71 100.06,65.52 100.06,62.82 100.04,62.79 100.04,62.77
  LY3 w0.105: 100.04,62.26 100.83,61.47 100.83,59.54 99.78,58.49 99.78,55.34 95.76,51.32 95.76,43.29 96.47,42.58 96.47,42.27 96.47,42.27 96.47,42.15 95.76,41.44 95.76,41.08 95.82,41.02 95.82,41.02 96.05,40.79 96.82,40.79 97.07,40.53 97.07,38.93 96.34,38.2 96.34,36.91 96.49,36.76 96.49,36.75 97.48,35.77 97.48,35.25 98,34.72 98.04,34.72 98.04,34.72 98.38,34.72 99.07,34.03 99.67,34.03 100.11,34.47 101.17,34.47 104.46,31.18 104.89,31.18 105.49,30.58 105.49,28.37 105.31,28.19 105.31,27.54 105.19,27.42 104.92,27.42 104.82,27.51 104.82,27.92 v1(104.8,27.94)
  LY3 w0.108: 100.04,62.26 100.04,62.77
  BOTTOM w0.108: J500.5F v1(104.8,27.94)
DDA08_P: length 52.2
  TOP w0.178: U11.W4 v2(99.66,66.2)
  LY3 w0.102: 100.29,62.77 100.29,62.77 100.29,62.79 100.26,62.82 100.26,65.61 100.07,65.8 100.07,65.81 99.68,66.2 v2(99.66,66.2)
  LY3 w0.105: v1(104.8,26.67) 105.56,27.43 105.56,28.08 105.74,28.27 105.74,30.69 105,31.43 104.56,31.43 101.27,34.73 101.16,34.73 101.15,34.73 100.94,34.73 100.94,34.73 100.01,34.73 99.57,34.29 99.17,34.29 98.48,34.97 98.15,34.97 98.14,34.98 98.11,34.98 97.73,35.35 97.73,35.87 96.74,36.86 96.74,36.86 96.59,37.01 96.59,38.1 97.33,38.83 97.33,40.64 96.92,41.04 96.16,41.04 96.07,41.13 96.07,41.13 96.02,41.18 96.02,41.34 96.72,42.04 96.72,42.38 96.72,42.38 96.72,42.69 96.01,43.39 96.01,51.22 100.03,55.24 100.03,58.39 101.08,59.44 101.08,61.36 101.09,61.36 101.09,61.57 101.03,61.63 101.03,61.63 100.29,62.37
  LY3 w0.108: 100.29,62.37 100.29,62.77
  BOTTOM w0.108: 104.17,26.04 v1(104.8,26.67)
DDA09_N: length 51.5
  TOP w0.178: U11.W1 v2(99.66,63.2)
  LY4 w0.102: v2(99.66,63.2) 99.6,63.26 99.6,63.48 99.75,63.63 99.89,63.63 100.06,63.46 100.06,62.79 100.04,62.76 100.04,62.74
  LY4 w0.105: v1(106.07,21.59) 106.01,21.53 106.01,21.1 106.13,20.98 106.37,20.98 106.58,21.19 106.58,29.7 107.72,30.84 107.72,31.99 107.1,32.6 107.1,38.74 106.97,38.87 106.27,38.87 105.99,39.15 105.99,39.71 106.12,39.84 106.12,39.84 106.27,39.99 106.35,39.99 106.35,40 107,40 107.14,40.14 107.14,40.73 103.14,44.72 103.05,44.72 102.9,44.87 102.9,59.52 100.04,62.38 100.04,62.74
  BOTTOM w0.108: J500.4B v1(106.07,21.59)
DDA09_P: length 51.6
  TOP w0.178: U11.W2 v2(99.66,64.2)
  LY4 w0.102: v2(99.66,64.2) 100.27,63.6 100.27,62.79 100.29,62.76 100.29,62.74
  LY4 w0.105: v1(106.07,20.32) 106.83,21.08 106.83,29.59 107.97,30.73 107.97,32.09 107.36,32.71 107.36,38.84 107.07,39.13 106.38,39.13 106.25,39.26 106.25,39.61 106.38,39.74 106.38,39.74 106.46,39.74 106.46,39.74 107.1,39.74 107.39,40.03 107.39,40.83 103.25,44.98 103.16,44.98 103.16,59.62 100.29,62.49 100.29,62.74
  BOTTOM w0.178: v1(106.07,20.32) J500.4A
DDA10_N: length 52
  TOP w0.178: U11.Y1 v2(100.66,63.2)
  LY3 w0.102: 101.04,62.86 101.04,62.88 101.07,62.91 101.07,63.47 100.8,63.73 100.66,63.73 100.52,63.6 100.52,63.34 v2(100.66,63.2)
  LY3 w0.105: 101.04,62.49 101.74,61.79 101.74,58.94 100.82,58.01 100.82,54.96 96.72,50.87 96.72,50.07 96.96,49.83 97.96,49.83 98.07,49.73 98.07,49.31 97.96,49.21 96.99,49.21 96.72,48.94 96.72,43.7 97.59,42.83 97.59,41.45 98.11,40.93 98.11,38.53 98.11,38.53 98.06,38.47 98.06,38.47 97.97,38.39 97.97,36.94 99.41,35.51 101.53,35.51 101.59,35.45 101.59,35.45 104.86,32.18 106.22,32.18 106.79,31.6 106.79,28.59 106.59,28.39 106.59,26.29 106.5,26.2 106.2,26.2 106.07,26.32 v1(106.07,26.67)
  LY3 w0.108: 101.04,62.86 101.04,62.49
  BOTTOM w0.108: 105.44,26.04 v1(106.07,26.67)
DDA10_P: length 52
  TOP w0.178: U11.Y2 v2(100.66,64.2)
  LY3 w0.102: 101.3,62.86 101.29,62.86 101.29,62.88 101.27,62.91 101.27,63.59 v2(100.66,64.2)
  LY3 w0.105: v1(106.07,25.4) 106.6,25.93 106.6,25.94 106.85,26.18 106.85,28.29 107.05,28.49 107.05,31.7 106.32,32.43 104.97,32.43 101.7,35.7 101.7,35.7 101.63,35.77 99.51,35.77 98.23,37.05 98.23,38.29 98.31,38.37 98.31,38.37 98.37,38.43 98.37,38.64 98.36,38.64 98.36,41.03 97.85,41.55 97.85,42.93 96.97,43.81 96.97,48.84 97.09,48.95 98.07,48.95 98.32,49.21 98.32,49.83 98.07,50.08 97.07,50.08 96.97,50.18 96.97,50.76 101.07,54.85 101.07,57.91 101.99,58.83 101.99,61.89 101.94,61.95 101.94,61.95 101.3,62.59
  LY3 w0.108: 101.3,62.86 101.3,62.59
  BOTTOM w0.108: J500.4D v1(106.07,25.4)
DDA11_N: length 50.9
  TOP w0.178: U11.Y3 v2(100.66,65.2)
  LY4 w0.102: 101.33,62.32 101.06,62.59 101.06,65.49 100.92,65.63 100.77,65.63 100.66,65.52 v2(100.66,65.2)
  LY4 w0.105: v1(107.34,22.86) 107.25,22.77 107.25,22.34 107.34,22.26 107.65,22.26 107.82,22.43 107.82,28.77 107.83,28.77 107.83,29.3 108.67,30.15 108.67,32.92 108.11,33.48 108.11,36.18 108.9,36.97 108.9,40.4 103.87,45.43 103.87,59.78 101.33,62.32
  BOTTOM w0.178: 106.71,23.5 v1(107.34,22.86)
DDA11_P: length 50.9
  TOP w0.178: U11.Y4 v2(100.66,66.2)
  LY4 w0.102: 101.51,62.5 101.27,62.74 101.27,65.59 v2(100.66,66.2)
  LY4 w0.105: 101.51,62.5 104.12,59.89 104.12,45.53 109.15,40.51 109.15,36.86 108.36,36.08 108.36,33.59 108.93,33.03 108.93,30.04 108.08,29.2 108.08,28.67 108.08,28.66 108.08,22.33 v1(107.34,21.59)
  BOTTOM w0.178: v1(107.34,21.59) J500.3B
DDA12_N: length 52.1
  TOP w0.178: U11.AA1 v2(101.66,63.2)
  LY3 w0.102: v2(101.66,63.2) 101.54,63.33 101.54,63.6 101.66,63.72 101.83,63.72 102.07,63.49 102.07,62.91
  LY3 w0.105: v1(107.34,27.94) 107.34,27.58 107.47,27.45 107.76,27.45 107.88,27.58 107.88,31.88 106.75,33.01 105.5,33.01 101.98,36.53 99.66,36.53 99.13,37.06 99.13,37.43 99.13,37.43 99.13,41.25 98.71,41.67 98.71,41.72 98.7,41.72 98.7,41.94 98.7,43.2 97.65,44.25 97.65,46.37 97.91,46.63 99.24,46.63 99.4,46.8 99.4,47.14 99.3,47.25 97.91,47.25 97.65,47.51 97.65,47.99 97.99,48.33 98.54,48.33 98.88,48.67 99.06,48.67 99.2,48.81 99.2,50.14 98.72,50.62 98.72,51.36 101.85,54.49 101.85,57.36 102.63,58.13 102.63,58.41 102.63,58.41 102.63,62.09 102.07,62.66 102.07,62.91
  BOTTOM w0.108: J500.3F v1(107.34,27.94)
DDA12_P: length 52.2
  TOP w0.178: U11.AA2 v2(101.66,64.2)
  LY3 w0.102: v2(101.66,64.2) 102.27,63.59 102.27,62.99 102.27,62.99 102.27,62.97 102.32,62.92 102.32,62.91
  LY3 w0.105: 102.32,62.91 102.32,62.76 102.88,62.2 102.88,58.52 102.89,58.51 102.89,58.03 102.11,57.25 102.11,54.39 98.97,51.25 98.97,50.72 99.45,50.25 99.45,48.7 99.16,48.42 98.99,48.42 98.65,48.08 98.1,48.08 97.91,47.89 97.91,47.61 98.01,47.5 99.4,47.5 99.66,47.25 99.66,46.69 99.34,46.38 98.02,46.38 97.91,46.27 97.91,44.36 98.96,43.31 98.96,41.83 98.96,41.83 98.96,41.78 99.39,41.35 99.39,37.33 99.38,37.33 99.38,37.17 99.77,36.79 102.08,36.79 105.6,33.27 106.86,33.27 108.14,31.99 108.14,27.47 107.86,27.2 107.86,27.19 v1(107.34,26.67)
  BOTTOM w0.108: 106.71,26.04 v1(107.34,26.67)
DDA13_N: length 52.2
  TOP w0.178: U11.AA3 v2(101.66,65.2)
  LY4 w0.102: 103.03,62.9 103.03,62.92 103.06,62.95 103.06,63.41 102.87,63.6 102.34,63.6 102.06,63.88 102.06,65.49 101.91,65.64 101.71,65.64 101.66,65.6 v2(101.66,65.2)
  LY4 w0.105: 103.03,62.76 105.03,60.77 105.03,45.91 105.03,45.91 105.03,45.83 105.18,45.68 105.18,45.68 110.22,40.64 110.22,30.14 109.11,29.03 109.11,21.22 108.91,21.01 108.64,21.01 108.51,21.14 108.51,21.49 v1(108.61,21.59)
  LY4 w0.108: 103.03,62.9 103.03,62.76
  BOTTOM w0.108: J500.2B v1(108.61,21.59)
DDA13_P: length 52.3
  TOP w0.178: U11.AA4 v2(101.66,66.2)
  LY4 w0.102: 103.29,62.9 103.29,62.9 103.29,62.92 103.26,62.95 103.26,63.5 102.96,63.8 102.43,63.8 102.27,63.96 102.27,65.59 v2(101.66,66.2)
  LY4 w0.105: v1(108.61,20.32) 108.62,20.33 108.62,20.36 109.01,20.75 109.01,20.76 109.37,21.11 109.37,28.93 110.47,30.03 110.47,40.75 105.28,45.93 ; 105.28,45.93 105.28,45.93 105.28,45.93 ; 105.28,45.93 105.28,45.93 105.28,45.91 105.28,45.91 105.28,60.87 103.29,62.86 103.29,62.87
  LY4 w0.108: 103.29,62.87 103.29,62.9
  BOTTOM w0.178: v1(108.61,20.32) J500.2A
DDA14_N: length 52
  TOP w0.178: U11.AB1 v2(102.66,63.2)
  LY3 w0.102: 103.04,62.87 103.04,62.88 103.07,62.91 103.07,63.48 102.82,63.72 102.64,63.72 102.53,63.61 102.53,63.33 v2(102.66,63.2)
  LY3 w0.105: v1(108.61,26.67) 108.61,26.31 108.74,26.18 109.03,26.18 109.14,26.29 109.14,32.09 107.28,33.94 105.96,33.94 102.34,37.57 102.33,37.57 102.25,37.57 100.8,37.57 100.28,38.09 100.28,38.57 100.68,38.97 101.48,38.97 101.64,39.13 101.64,39.35 101.48,39.51 100.61,39.51 100.22,39.91 100.22,40.31 100.62,40.71 101.45,40.71 101.61,40.87 101.61,41.06 101.36,41.32 100.65,41.32 100.28,41.69 100.28,51.26 102.99,53.98 102.99,57.3 103.52,57.82 103.52,62.28 103.52,62.28
  LY3 w0.108: 103.52,62.28 103.04,62.76 103.04,62.87
  BOTTOM w0.108: 107.98,26.04 v1(108.61,26.67)
DDA14_P: length 52
  TOP w0.178: U11.AB2 v2(102.66,64.2)
  LY3 w0.102: 103.29,62.87 103.29,62.88 103.27,62.91 103.27,63.59 v2(102.66,64.2)
  LY3 w0.105: v1(108.61,25.4) 109.13,25.92 109.13,25.93 109.39,26.18 109.39,32.19 107.39,34.2 106.07,34.2 102.59,37.68 102.59,37.68 102.44,37.83 102.36,37.83 102.36,37.83 100.9,37.83 100.54,38.19 100.54,38.46 100.79,38.72 101.59,38.72 101.9,39.02 101.9,39.46 101.59,39.77 100.72,39.77 100.47,40.01 100.47,40.2 100.73,40.46 101.56,40.46 101.86,40.76 101.86,41.17 101.46,41.57 100.75,41.57 100.53,41.79 100.53,51.16 103.25,53.87 103.25,57.19 103.77,57.72 103.77,62.39 103.72,62.44 103.72,62.45 103.7,62.46
  LY3 w0.108: 103.29,62.87 103.7,62.46
  BOTTOM w0.108: J500.2D v1(108.61,25.4)
DDA15_N: length 52.6
  TOP w0.178: U11.AC1 v2(103.66,63.2)
  LY3 w0.102: v2(103.66,63.2) 103.53,63.33 103.53,63.61 103.65,63.73 103.84,63.73 103.98,63.6 104.92,63.6 105.06,63.46 105.06,62.97 105.03,62.94 105.03,62.61
  LY3 w0.105: 105.03,62.61 105.03,61.71 104.67,61.35 104.67,53.15 103.13,51.61 103.13,47.82 103.13,47.82 103.07,47.76 103.07,47.76 102.88,47.57 101.94,47.57 101.53,47.16 101.53,46.59 101.94,46.19 102.87,46.19 103.14,45.91 103.14,45.59 102.88,45.33 101.95,45.33 101.68,45.06 101.68,45.06 101.53,44.92 101.53,44.34 101.93,43.94 102.87,43.94 103.13,43.68 103.13,38.63 103.13,38.63 106.54,35.22 109.12,35.22 111.94,32.39 111.94,28.26 111.11,27.43 109.99,27.43 109.88,27.54 v1(109.88,27.94)
  BOTTOM w0.178: v1(109.88,27.94) J500.1F
DDA15_P: length 52.6
  TOP w0.178: U11.AC2 v2(103.66,64.2)
  LY3 w0.102: 105.29,62.61 105.29,62.64 105.29,62.94 105.26,62.97 105.26,63.54 105,63.8 104.06,63.8 v2(103.66,64.2)
  LY3 w0.105: v1(109.88,26.67) 110.39,27.18 111.22,27.18 112.2,28.16 112.2,32.5 109.22,35.47 106.65,35.47 103.38,38.74 103.38,38.74 103.38,43.79 102.98,44.2 102.04,44.2 101.78,44.45 101.78,44.81 101.79,44.81 102.05,45.08 103,45.08 103.07,45.15 103.07,45.16 103.13,45.21 103.13,45.22 103.4,45.49 103.4,46.02 102.97,46.44 102.04,46.44 101.79,46.7 101.79,47.06 102.05,47.32 102.99,47.32 103.33,47.66 103.33,47.66 103.38,47.72 103.38,47.93 103.38,47.93 103.38,51.51 104.92,53.05 104.92,61.24 105.29,61.6 105.29,62.61
  BOTTOM w0.178: 109.25,26.04 v1(109.88,26.67)
DDB00_N: length 48.8
  TOP w0.178: U11.N2 v2(92.66,64.2)
  LY4 w0.102: v2(92.66,64.2) 92.66,63.9 92.76,63.8 93.01,63.8 93.26,63.55 93.26,62.9 93.28,62.89 93.28,62.88 93.28,62.87 93.28,62.85 93.33,62.8 93.33,62.79
  LY4 w0.105: 93.33,62.79 93.33,62.45 93.47,62.31 93.47,62.06 93.59,61.93 93.59,57.73 93.47,57.61 93.47,53.19 91.97,51.69 88.89,51.69 88.6,51.4 88.6,44.21 88.09,43.7 87.41,43.7 87.35,43.64 87.35,32.21 88.01,31.55 89.68,31.55 90.32,30.91 90.32,27.61 90.09,27.38 90.09,27.37 89.94,27.22 89.44,27.22 89.05,26.84 89.05,26.37 89.26,26.16 89.43,26.16 89.56,26.29 v1(89.56,26.67)
  BOTTOM w0.178: J500.16E v1(89.56,26.67)
DDB00_P: length 48.9
  TOP w0.178: U11.N1 v2(92.66,63.2)
  LY4 w0.102: 93.07,62.79 93.07,62.8 93.06,62.81 93.06,63.47 92.93,63.6 92.75,63.6 92.66,63.51 v2(92.66,63.2)
  LY4 w0.105: 93.07,62.79 93.07,62.34 93.21,62.2 93.21,61.95 93.34,61.83 93.34,57.84 93.21,57.71 93.21,53.29 91.86,51.94 88.78,51.94 88.35,51.5 88.35,44.32 87.98,43.95 87.3,43.95 87.1,43.75 87.1,32.11 87.91,31.3 89.57,31.3 90.07,30.8 90.07,27.71 89.84,27.48 89.84,27.48 89.33,27.48 88.8,26.94 88.8,26.26 89.15,25.91 89.4,25.91 89.56,25.75 v1(89.56,25.4)
  BOTTOM w0.178: J500.16D v1(89.56,25.4)
DDB01_N: length 49.2
  TOP w0.178: U11.N4 v2(92.66,66.2)
  LY3 w0.102: v2(92.66,66.2) 92.66,65.92 92.78,65.8 93.07,65.8 93.26,65.61 93.26,62.87 93.29,62.84 93.29,62.82 93.29,62.82
  LY3 w0.105: 87.82,28.25 87.82,28.26 90.19,30.63 90.19,53.65 93.56,57.02 93.56,61.85 93.56,61.85 93.56,62.29 93.56,62.29 93.56,62.34 93.29,62.61 93.29,62.61
  LY3 w0.108: 87.82,28.25 87.82,22.49 87.95,22.36 88.18,22.36 88.29,22.47 v1(88.29,22.86) ; 93.29,62.82 93.29,62.61
  BOTTOM w0.108: J500.17C v1(88.29,22.86)
DDB01_P: length 49.3
  TOP w0.178: U11.N3 v2(92.66,65.2)
  LY3 w0.102: v2(92.66,65.2) 92.66,65.5 92.76,65.6 92.98,65.6 93.06,65.52 93.06,62.87 93.04,62.84 93.04,62.82
  LY3 w0.105: 87.56,28.36 89.93,30.73 89.93,53.75 93.31,57.13 93.31,61.96 93.31,61.96 93.31,62.18 93.31,62.19 93.31,62.23 93.04,62.5
  LY3 w0.108: 93.04,62.82 93.04,62.5 ; 87.56,28.36 87.56,22.38 87.84,22.1 88.2,22.1 88.29,22 v1(88.29,21.59)
  BOTTOM w0.108: J500.17B v1(88.29,21.59)
DDB02_N: length 49
  TOP w0.178: U11.M1 v2(91.66,63.2)
  LY4 w0.102: v2(91.66,63.2) 91.54,63.32 91.54,63.66 91.6,63.72 91.84,63.72 92.06,63.5 92.06,62.84 92.04,62.81 92.04,62.79
  LY4 w0.105: v1(88.29,27.94) 88.29,27.55 88.38,27.46 88.59,27.46 88.81,27.67 88.81,28.74 85.71,31.83 85.71,44.77 85.97,45.02 87.23,45.02 87.34,45.13 87.34,45.55 87.23,45.66 86.15,45.66 85.75,46.06 85.75,46.67 86.15,47.07 87.03,47.07 87.18,47.23 87.18,52.64 87.64,53.1 91.13,53.1 92.07,54.04 92.07,57.76 92.07,57.76 92.07,58.15 92.34,58.43 92.34,61.57 92.04,61.87 92.04,62.79
  BOTTOM w0.178: J500.17F v1(88.29,27.94)
DDB02_P: length 49.1
  TOP w0.178: U11.M2 v2(91.66,64.2)
  LY4 w0.102: v2(91.66,64.2) 91.66,64.2 92.27,63.6 92.27,62.84 92.29,62.81 92.29,62.79
  LY4 w0.105: v1(88.29,26.67) 88.29,26.8 88.69,27.2 88.7,27.2 88.7,27.21 89.06,27.57 89.06,28.84 85.97,31.93 85.97,44.66 86.07,44.77 87.34,44.77 87.59,45.02 87.59,45.66 87.34,45.91 86.25,45.91 86,46.17 86,46.56 86.25,46.82 87.13,46.82 87.43,47.12 87.43,52.54 87.75,52.85 91.24,52.85 92.33,53.94 92.33,57.86 92.32,57.86 92.32,58.05 92.6,58.32 92.6,61.67 92.29,61.98 92.29,62.79
  BOTTOM w0.178: J500.17E v1(88.29,26.67)
DDB03_N: length 50.7
  TOP w0.178: U11.M4 v2(91.66,66.2)
  LY3 w0.102: v2(91.66,66.2) 91.66,65.92 91.78,65.8 92.07,65.8 92.26,65.61 92.26,62.87 92.29,62.84 92.29,62.82
  LY3 w0.105: 92.29,62.82 92.29,62.04 92.67,61.66 92.67,57.4 89.26,53.99 89.26,30.98 86.55,28.27 86.55,28.27
  LY3 w0.108: 86.55,28.27 86.55,21.22 86.68,21.09 86.91,21.09 87.02,21.2 v1(87.02,21.59)
  BOTTOM w0.108: J500.18B v1(87.02,21.59)
DDB03_P: length 50.8
  TOP w0.178: U11.M3 v2(91.66,65.2)
  LY3 w0.102: 92.04,62.82 92.04,62.84 92.06,62.87 92.06,65.52 91.98,65.6 91.76,65.6 91.66,65.5 v2(91.66,65.2)
  LY3 w0.105: 86.29,28.37 89,31.08 89,54.09 92.41,57.5 92.41,61.56 92.04,61.93 92.04,62.82
  LY3 w0.108: v1(87.02,20.32) 87.02,20.73 86.93,20.83 86.57,20.83 86.29,21.11 86.29,28.37
  BOTTOM w0.108: J500.18A v1(87.02,20.32)
DDB04_N: length 48.9
  TOP w0.178: U11.L2 v2(90.66,64.2)
  LY4 w0.102: 91.29,62.79 91.29,62.81 91.27,62.84 91.27,63.55 91.01,63.8 90.76,63.8 90.66,63.9 v2(90.66,64.2)
  LY4 w0.105: 91.29,62.79 91.29,61.52 91.14,61.37 91.14,55.13 89.73,53.71 86.59,53.71 86.37,53.49 86.37,50.06 86.12,49.81 85.18,49.81 85.08,49.7 85.08,49.1 85.18,49 86.09,49 86.35,48.74 86.35,48.12 86.09,47.87 85.2,47.87 85.06,47.73 85.06,36.79 84.67,36.4 84.67,34.04 85.09,33.62 85.09,31.49 86.52,30.06 86.52,26.37 86.72,26.17 86.89,26.17 87.02,26.29 v1(87.02,26.67)
  BOTTOM w0.178: J500.18E v1(87.02,26.67)
DDB04_P: length 48.9
  TOP w0.178: U11.L1 v2(90.66,63.2)
  LY4 w0.102: v2(90.66,63.2) 90.66,63.51 90.75,63.6 90.93,63.6 91.06,63.46 91.06,62.84 91.04,62.81 91.04,62.79
  LY4 w0.105: v1(87.02,25.4) 87.02,25.75 86.86,25.91 86.61,25.91 86.26,26.26 86.26,29.95 84.83,31.38 84.83,33.52 84.42,33.93 84.42,36.5 84.81,36.89 84.81,47.84 85.09,48.12 85.99,48.12 86.09,48.23 86.09,48.64 85.99,48.74 85.08,48.74 84.82,49 84.82,49.81 85.08,50.06 86.01,50.06 86.12,50.17 86.12,53.59 86.49,53.96 89.62,53.96 90.89,55.23 90.89,61.48 91.04,61.62 91.04,62.79
  BOTTOM w0.178: J500.18D v1(87.02,25.4)
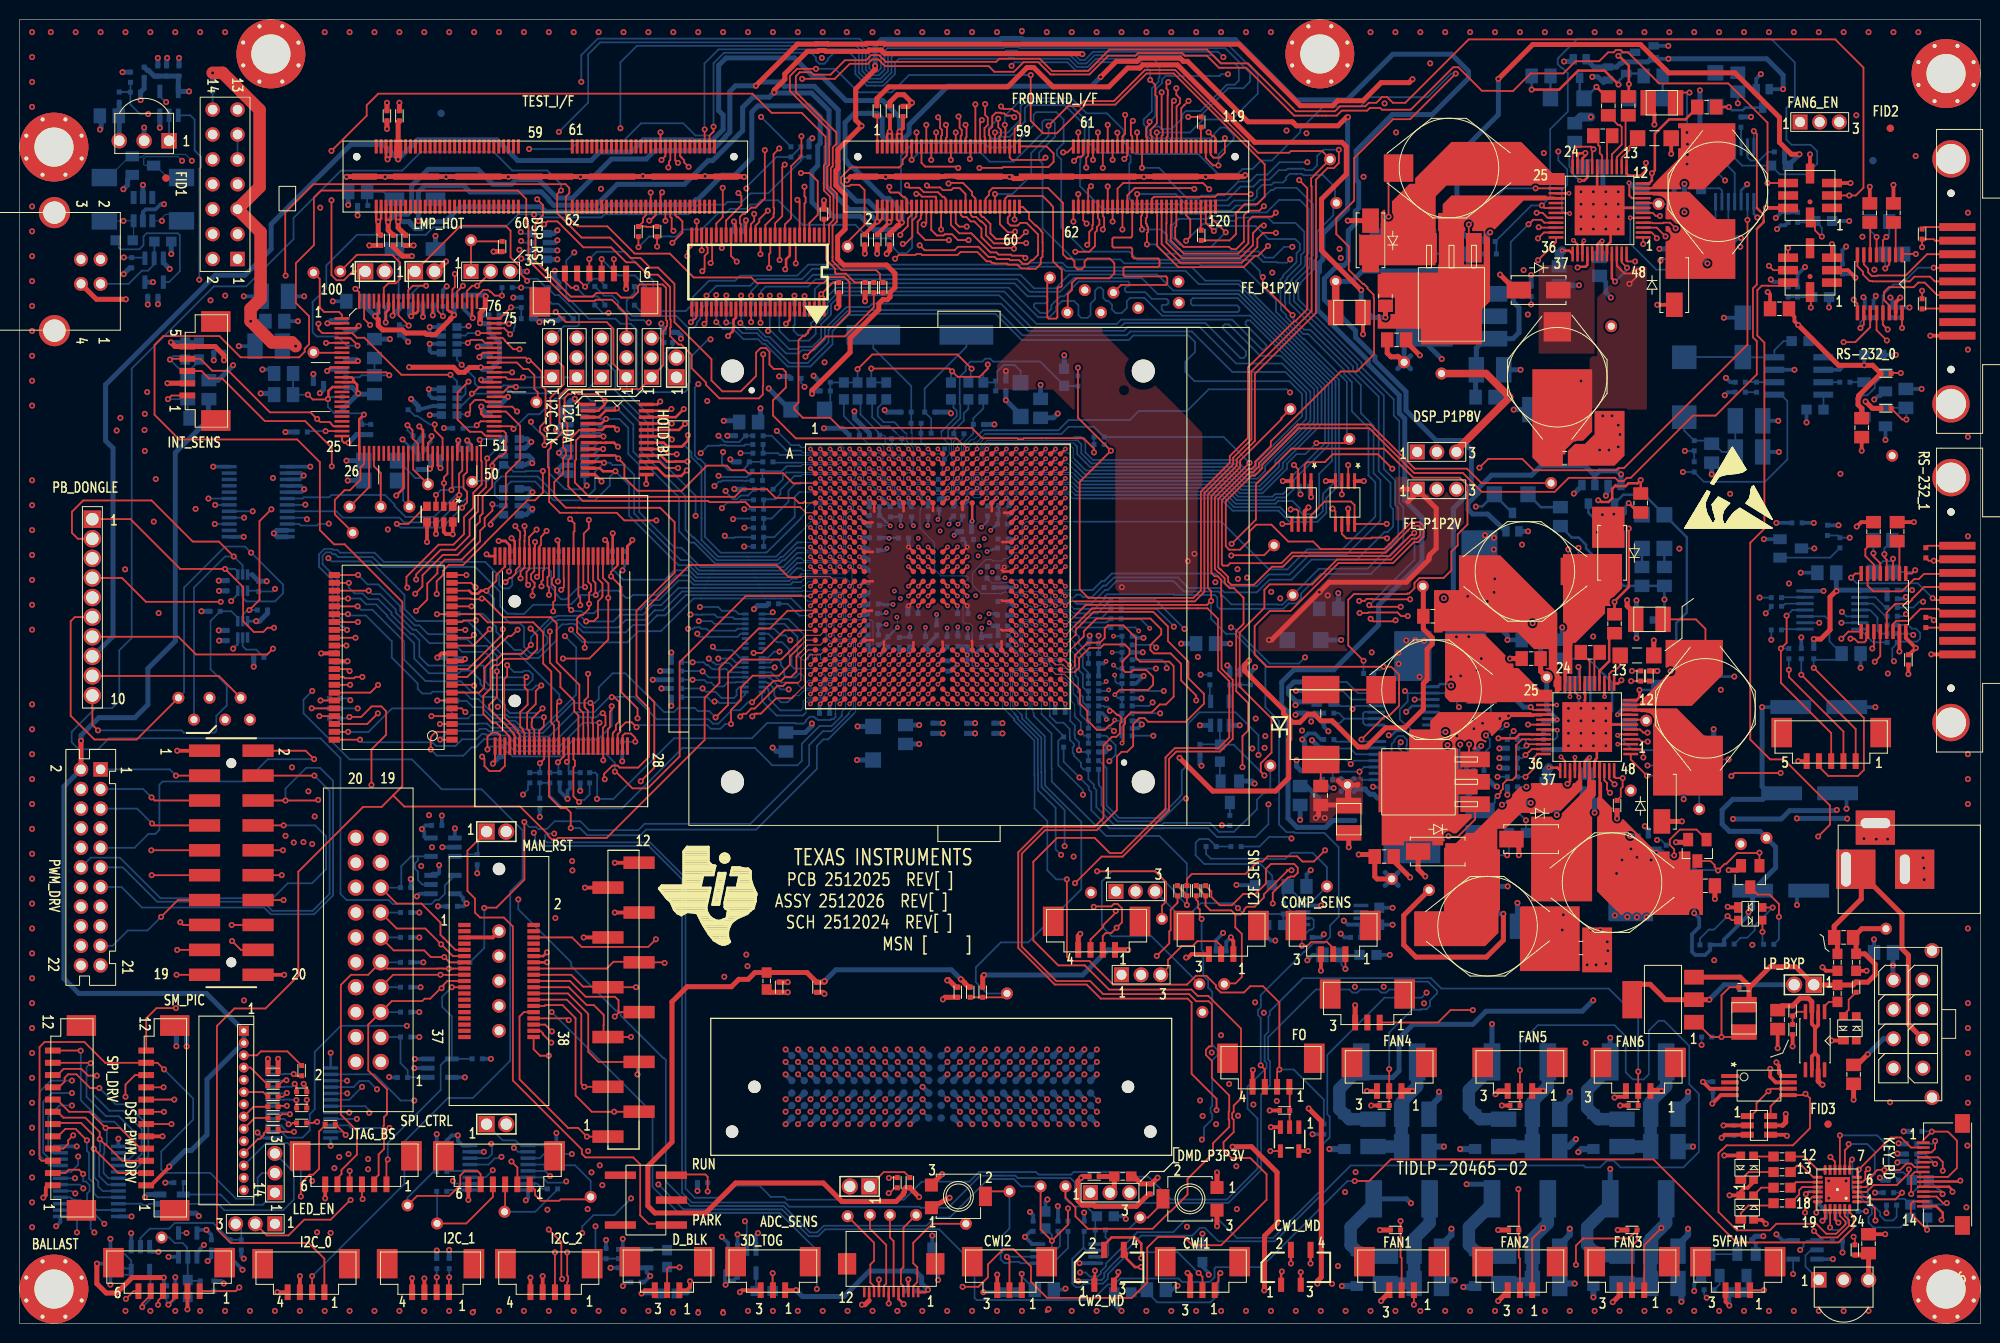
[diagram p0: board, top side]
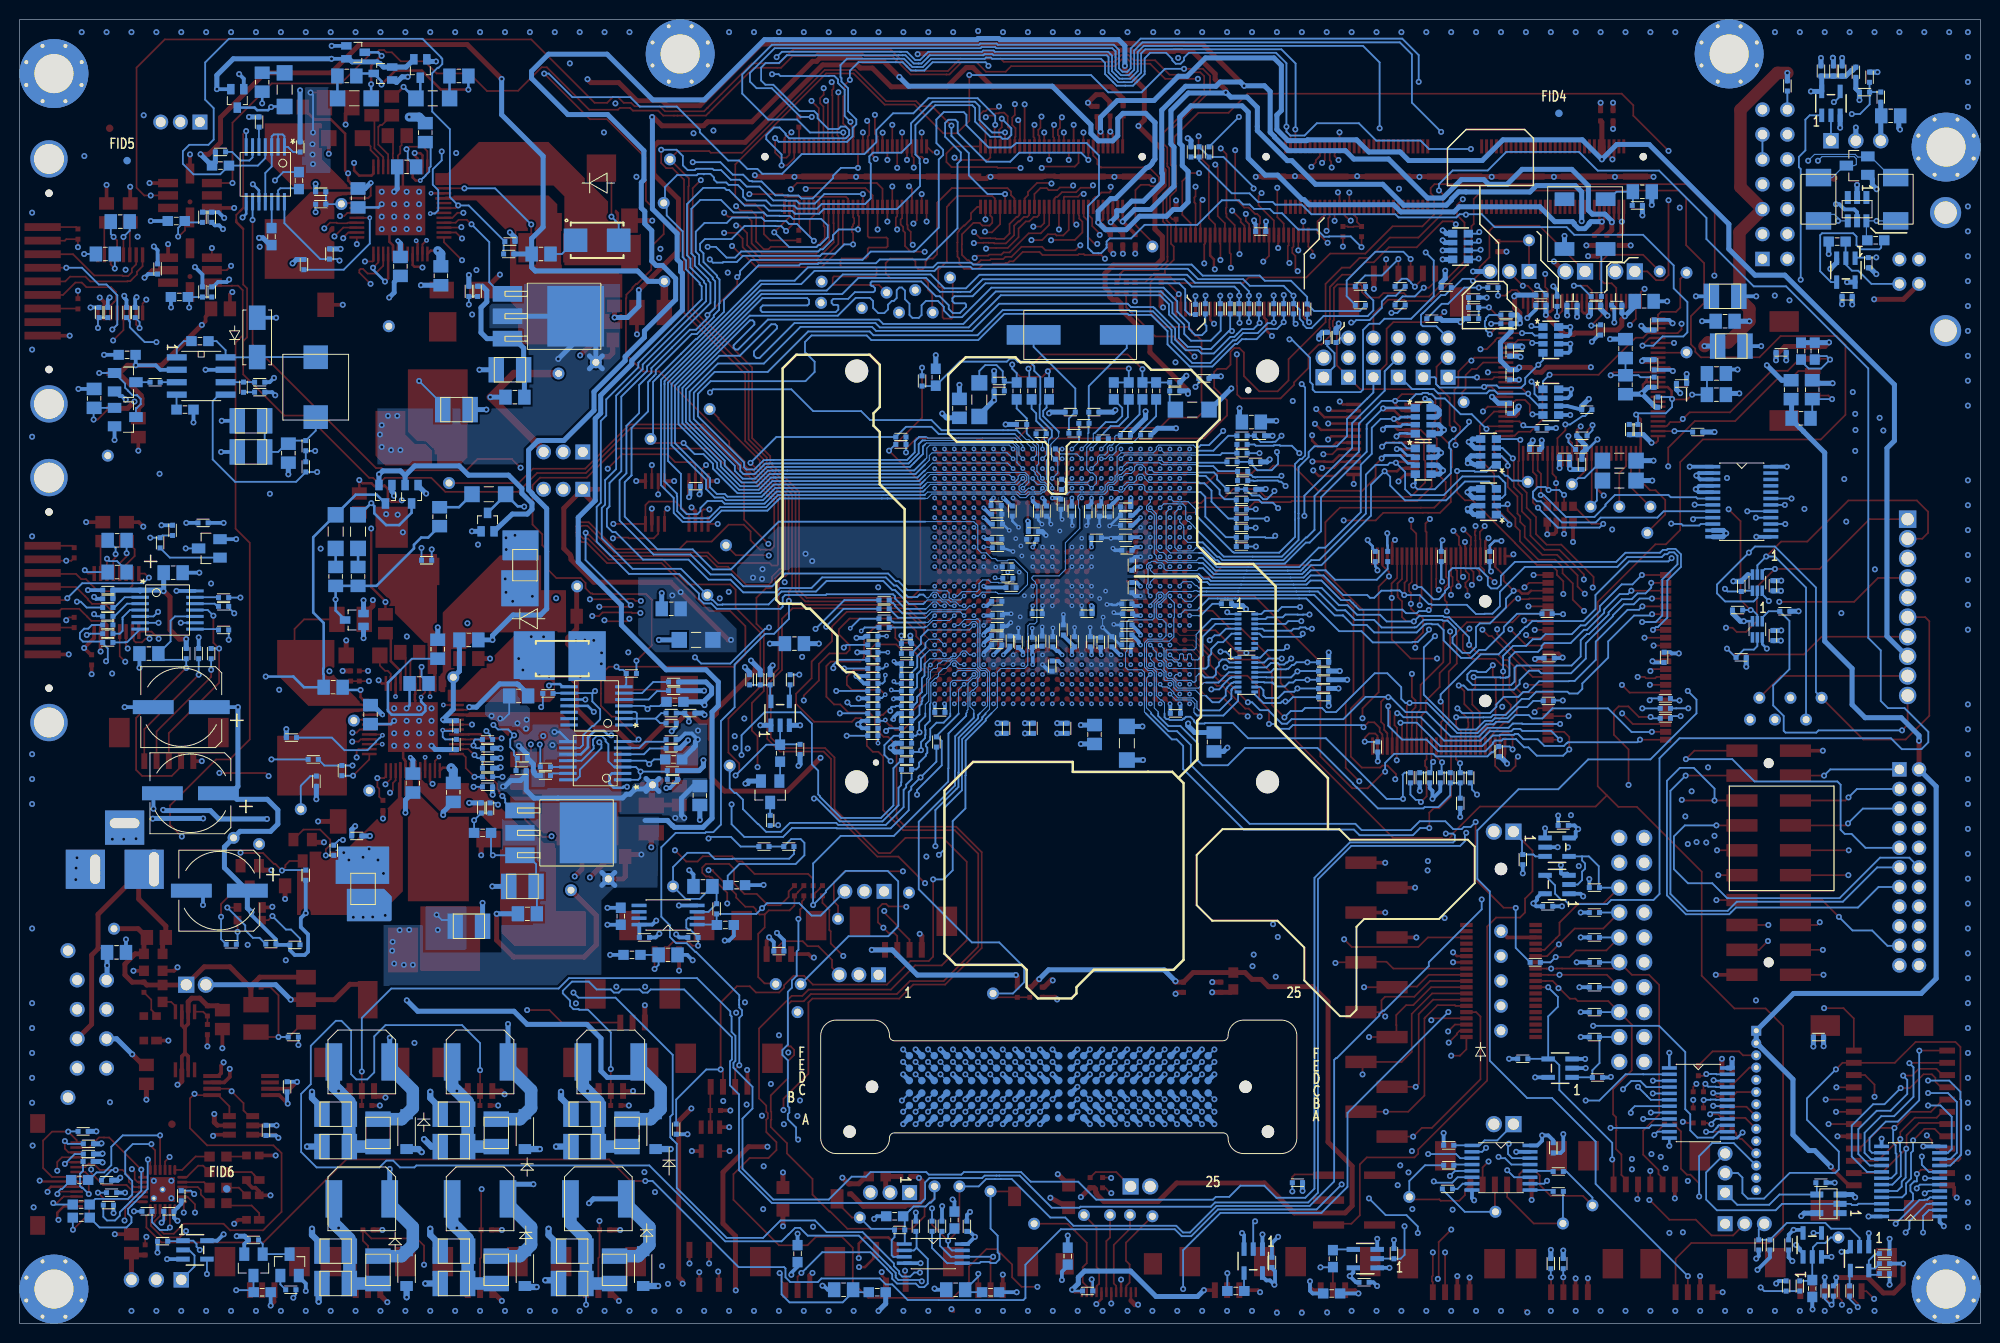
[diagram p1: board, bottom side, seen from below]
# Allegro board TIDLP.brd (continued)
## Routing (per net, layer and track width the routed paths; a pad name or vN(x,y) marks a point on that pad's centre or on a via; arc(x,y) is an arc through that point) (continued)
DDB05_N: length 49.2
  TOP w0.178: U11.L4 v2(90.66,66.2)
  LY3 w0.102: 91.29,62.82 91.29,62.84 91.26,62.87 91.26,65.61 91.07,65.8 90.78,65.8 90.66,65.92 v2(90.66,66.2)
  LY3 w0.105: 91.29,62.82 91.29,62.06 91.23,62 91.23,61.56 91.23,61.56 91.23,61.35 91.17,61.29 91.17,57.34 88.28,54.45 88.28,31.3 85.28,28.3 85.28,28.3
  LY3 w0.108: v1(85.75,22.86) 85.75,22.47 85.64,22.36 85.41,22.36 85.28,22.49 85.28,28.3
  BOTTOM w0.108: J500.19C v1(85.75,22.86)
DDB05_P: length 49.3
  TOP w0.178: U11.L3 v2(90.66,65.2)
  LY3 w0.102: v2(90.66,65.2) 90.66,65.5 90.76,65.6 90.98,65.6 91.06,65.52 91.06,62.95 91.04,62.92 91.04,62.82
  LY3 w0.105: 91.04,62.82 91.04,62.17 90.98,62.11 90.98,61.45 90.92,61.39 90.92,57.44 88.03,54.55 88.03,31.41 85.02,28.4
  LY3 w0.108: v1(85.75,21.59) 85.75,22 85.66,22.1 85.3,22.1 85.02,22.38 85.02,28.4
  BOTTOM w0.108: J500.19B v1(85.75,21.59)
DDB06_N: length 49
  TOP w0.178: U11.K2 v2(89.66,64.2)
  LY4 w0.102: 90.29,62.79 90.29,62.81 90.27,62.84 90.27,63.55 90.01,63.8 89.76,63.8 89.66,63.9 v2(89.66,64.2)
  LY4 w0.105: 90.29,62.79 90.29,56.06 88.94,54.71 84.66,54.71 84.66,54.71 84.6,54.65 84.6,54.65 84.17,54.22 84.17,53.68 84.28,53.56 85.01,53.56 85.34,53.24 85.34,52.78 85.01,52.45 84.36,52.45 84.18,52.27 84.18,52.01 84.36,51.83 85.08,51.83 85.34,51.58 85.34,51.05 85.08,50.8 84.36,50.8 84.22,50.66 84.22,50.66 84.17,50.6 84.17,37.58 83.78,37.19 83.78,32.56 83.99,32.34 83.99,31.18 85.25,29.92 85.25,27.63 85.45,27.43 85.62,27.43 85.75,27.56 v1(85.75,27.94)
  BOTTOM w0.178: J500.19F v1(85.75,27.94)
DDB06_P: length 49.1
  TOP w0.178: U11.K1 v2(89.66,63.2)
  LY4 w0.102: 90.04,62.79 90.04,62.81 90.06,62.84 90.06,63.46 89.93,63.6 89.75,63.6 89.66,63.51 v2(89.66,63.2)
  LY4 w0.105: 90.04,62.79 90.04,56.16 88.84,54.96 84.77,54.96 84.77,54.96 84.56,54.96 84.5,54.91 84.5,54.91 83.91,54.32 83.91,53.58 84.18,53.31 84.91,53.31 85.09,53.13 85.09,52.88 84.91,52.7 84.26,52.7 83.93,52.37 83.93,51.91 84.26,51.58 84.98,51.58 85.08,51.47 85.08,51.16 84.98,51.05 84.26,51.05 83.97,50.77 83.97,50.76 83.91,50.71 83.91,37.69 83.52,37.3 83.52,32.45 83.74,32.24 83.74,31.07 85,29.81 85,27.53 85.34,27.18 85.59,27.18 85.75,27.02 v1(85.75,26.67)
  BOTTOM w0.178: J500.19E v1(85.75,26.67)
DDB07_N: length 50.6
  TOP w0.178: U11.K4 v2(89.66,66.2)
  LY3 w0.102: 90.18,62.47 90.18,62.47 90.27,62.55 90.27,63.36 90.26,63.36 90.26,65.61 90.07,65.8 89.78,65.8 89.66,65.92 v2(89.66,66.2)
  LY3 w0.105: 90.18,62.47 90.18,61.17 89.55,60.53 89.55,60.27 89.55,60.27 89.55,57.1 87.24,54.79 87.24,31.71 87.24,31.71 87.24,31.63 87.09,31.48 87.08,31.48 83.98,28.38 83.98,21.24 83.98,21.24
  LY3 w0.108: 83.98,21.24 84.14,21.09 84.37,21.09 84.48,21.2 v1(84.48,21.59)
  BOTTOM w0.108: J500.20B v1(84.48,21.59)
DDB07_P: length 50.7
  TOP w0.178: U11.K3 v2(89.66,65.2)
  LY3 w0.102: 89.93,62.5 90.07,62.64 90.07,63.27 90.06,63.28 90.06,65.52 89.98,65.6 89.76,65.6 89.66,65.5 v2(89.66,65.2)
  LY3 w0.105: 83.73,21.13 83.73,28.48 86.98,31.73 86.98,31.73 86.98,31.81 86.98,31.82 86.98,54.89 89.29,57.2 89.29,60.17 89.29,60.17 89.29,60.64 89.93,61.27 89.93,62.5
  LY3 w0.108: 83.73,21.13 84.03,20.83 84.38,20.83 84.48,20.72 v1(84.48,20.32)
  BOTTOM w0.178: v1(84.48,20.32) J500.20A
DDB08_N: length 48.8
  TOP w0.178: U11.H2 v2(87.66,64.2)
  LY3 w0.102: 87.66,61.92 87.67,61.93 87.67,62.08 88.07,62.48 88.07,62.69 88.27,62.89 88.27,63.61 88.07,63.8 87.79,63.8 87.66,63.93 v2(87.66,64.2)
  LY3 w0.105: 87.66,61.92 87.19,61.45 87.19,57.98 84.88,55.68 84.88,32.54 81.46,29.12 81.46,21.22
  LY3 w0.108: 81.46,21.22 81.6,21.08 81.83,21.08 81.94,21.19 v1(81.94,21.59)
  BOTTOM w0.108: J500.22B v1(81.94,21.59)
DDB08_P: length 48.9
  TOP w0.178: U11.H1 v2(87.66,63.2)
  LY3 w0.102: 87.47,62.09 87.47,62.09 87.47,62.17 87.86,62.56 87.86,62.78 88.06,62.98 88.06,63.52 87.98,63.6 87.82,63.6 87.66,63.44 v2(87.66,63.2)
  LY3 w0.105: 81.28,21.03 81.26,21.05 81.26,21.05 81.21,21.11 81.21,21.32 81.21,21.32 81.21,29.23 84.63,32.65 84.63,55.78 86.93,58.09 86.93,61.55 87.47,62.09
  LY3 w0.108: v1(81.94,20.32) 81.94,20.71 81.82,20.82 81.49,20.82 81.28,21.03
  BOTTOM w0.178: v1(81.94,20.32) J500.22A
DDB09_N: length 48.9
  TOP w0.178: U11.H4 v2(87.66,66.2)
  LY4 w0.102: 88.29,62.76 88.29,62.79 88.27,62.81 88.27,65.55 88.01,65.8 87.76,65.8 87.66,65.9 v2(87.66,66.2)
  LY4 w0.105: 88.29,62.76 88.29,58.26 87.17,57.14 86.81,57.14 86.29,56.62 83.67,56.62 81.96,54.9 81.96,43.64 80.78,42.47 80.78,41.95 80.89,41.84 81.53,41.84 81.85,41.52 81.85,41.07 81.53,40.75 80.93,40.75 80.78,40.6 80.78,40.6 80.78,36.12 81.25,35.65 81.25,32.69 81.79,32.15 81.79,30.23 82.7,29.32 82.7,27.64 82.91,27.43 83.08,27.43 83.21,27.56 v1(83.21,27.94)
  BOTTOM w0.178: J500.21F v1(83.21,27.94)
DDB09_P: length 48.9
  TOP w0.178: U11.H3 v2(87.66,65.2)
  LY4 w0.102: v2(87.66,65.2) 87.66,65.51 87.75,65.6 87.93,65.6 88.06,65.46 88.06,62.81 88.04,62.79 88.04,62.76
  LY4 w0.105: 88.04,62.76 88.04,58.36 87.07,57.39 86.7,57.39 86.18,56.87 83.56,56.87 81.7,55.01 81.7,43.75 80.53,42.57 80.53,41.84 80.78,41.58 81.42,41.58 81.59,41.41 81.59,41.17 81.42,41 80.82,41 80.53,40.71 80.53,40.5 80.53,36.01 81,35.54 81,32.58 81.53,32.04 81.53,30.13 82.45,29.22 82.45,27.54 82.8,27.18 83.05,27.18 83.21,27.02 v1(83.21,26.67)
  BOTTOM w0.178: J500.21E v1(83.21,26.67)
DDB10_N: length 49
  TOP w0.178: U11.G2 v2(86.66,64.2)
  LY4 w0.102: v2(86.66,64.2) 86.66,63.9 86.76,63.8 87.01,63.8 87.27,63.55 87.27,62.84 87.29,62.81 87.29,62.79
  LY4 w0.105: 87.29,62.79 87.29,59.14 86.56,58.41 83.87,58.41 80.48,55.02 80.48,49.8 80.91,49.37 80.91,45.51 80.48,45.09 79.76,45.09 79.6,44.92 79.6,44.69 79.76,44.53 80.17,44.53 80.5,44.19 80.5,43.69 80.25,43.44 79.72,43.44 79.62,43.34 79.62,35.94 80.16,35.4 80.16,32.94 79.54,32.32 79.54,30.73 81.28,28.98 81.29,28.98 81.43,28.84 81.43,26.37 81.64,26.17 81.81,26.17 81.94,26.29 v1(81.94,26.67)
  BOTTOM w0.178: J500.22E v1(81.94,26.67)
DDB10_P: length 49
  TOP w0.178: U11.G1 v2(86.66,63.2)
  LY4 w0.102: v2(86.66,63.2) 86.66,63.51 86.75,63.6 86.93,63.6 87.06,63.46 87.06,62.84 87.04,62.81 87.04,62.79
  LY4 w0.105: 87.04,62.79 87.04,59.24 86.45,58.66 83.77,58.66 80.23,55.12 80.23,49.69 80.66,49.27 80.66,45.62 80.38,45.34 79.66,45.34 79.35,45.03 79.35,44.58 79.66,44.27 80.06,44.27 80.25,44.09 80.25,43.8 80.14,43.69 79.62,43.69 79.37,43.44 79.37,35.84 79.91,35.3 79.91,33.05 79.29,32.43 79.29,30.62 81.18,28.73 81.18,26.27 81.54,25.91 81.77,25.91 81.94,25.75 v1(81.94,25.4)
  BOTTOM w0.178: J500.22D v1(81.94,25.4)
DDB11_N: length 49.7
  TOP w0.178: U11.G4 v2(86.66,66.2)
  LY3 w0.102: v2(86.66,66.2) 86.66,65.92 86.78,65.8 87.07,65.8 87.27,65.61 87.27,62.68
  LY3 w0.105: 87.27,62.68 87.05,62.46 87.05,62.46 86.95,62.36 86.95,62.2 86.3,61.54 86.3,60.55 83.8,58.06 83.8,32.92 80.2,29.31 80.2,22.49
  LY3 w0.108: v1(80.67,22.86) 80.67,22.4 80.63,22.36 80.33,22.36 80.2,22.49
  BOTTOM w0.108: J500.23C v1(80.67,22.86)
DDB11_P: length 49.8
  TOP w0.178: U11.G3 v2(86.66,65.2)
  LY3 w0.102: v2(86.66,65.2) 86.66,65.5 86.76,65.6 86.98,65.6 87.06,65.52 87.06,63.03 87.03,62.99 87.03,62.8
  LY3 w0.105: 87.03,62.8 86.7,62.47 86.7,62.3 86.04,61.65 86.04,60.66 83.55,58.16 83.55,33.02 79.94,29.41 79.94,22.6 79.94,22.6 79.94,22.38 80,22.33 80,22.32 80.01,22.31
  LY3 w0.108: v1(80.67,21.59) 80.67,22 80.58,22.1 80.22,22.1 80.01,22.31
  BOTTOM w0.108: J500.23B v1(80.67,21.59)
DDB12_N: length 49.6
  TOP w0.178: U11.F2 v2(85.66,64.2)
  LY4 w0.102: v2(85.66,64.2) 85.66,63.9 85.76,63.8 86.01,63.8 86.27,63.55 86.27,62.84 86.29,62.81 86.29,62.79
  LY4 w0.105: 86.29,62.79 86.29,60.06 85.79,59.56 83.6,59.56 79.57,55.53 79.57,50.78 78.7,49.91 78.7,49.27 78.7,49.27 78.8,49.17 79.67,49.17 80,48.84 80,48.37 79.67,48.04 78.67,48.04 78.56,47.93 78.56,47.53 78.67,47.42 79.66,47.42 79.99,47.09 79.99,46.55 79.74,46.3 78.81,46.3 78.62,46.11 78.62,35.69 79.17,35.14 79.17,33.18 78.6,32.61 78.6,30.23 80.01,28.81 80.02,28.81 80.17,28.66 80.17,27.64 80.37,27.44 80.54,27.44 80.67,27.56 v1(80.67,27.94)
  BOTTOM w0.178: J500.23F v1(80.67,27.94)
DDB12_P: length 49.7
  TOP w0.178: U11.F1 v2(85.66,63.2)
  LY4 w0.102: v2(85.66,63.2) 85.66,63.51 85.75,63.6 85.93,63.6 86.06,63.46 86.06,62.84 86.04,62.81 86.04,62.79
  LY4 w0.105: v1(80.67,26.67) 80.67,27.02 80.5,27.18 80.27,27.18 79.91,27.53 79.91,28.56 79.91,28.56 78.35,30.12 78.35,32.72 78.92,33.29 78.92,35.03 78.36,35.59 78.36,46.21 78.7,46.55 79.63,46.55 79.74,46.66 79.74,46.99 79.55,47.17 78.56,47.17 78.31,47.42 78.31,48.04 78.56,48.29 79.56,48.29 79.74,48.48 79.74,48.73 79.56,48.92 78.69,48.92 78.45,49.17 78.45,49.38 78.45,49.38 78.45,50.02 79.31,50.88 79.31,55.63 83.5,59.82 85.69,59.82 86.04,60.17 86.04,62.79
  BOTTOM w0.178: J500.23E v1(80.67,26.67)
DDB13_N: length 51
  TOP w0.178: U11.F4 v2(85.66,66.2)
  LY3 w0.102: 86.27,62.7 86.27,65.61 86.07,65.8 85.8,65.8 85.66,65.94 v2(85.66,66.2)
  LY3 w0.105: 86.27,62.7 86.26,62.7 82.91,59.34 82.91,33.25 78.92,29.27 78.92,21.22 78.92,21.22
  LY3 w0.108: v1(79.4,21.59) 79.4,21.2 79.29,21.09 79.06,21.09 78.92,21.22
  BOTTOM w0.108: J500.24B v1(79.4,21.59)
DDB13_P: length 51.1
  TOP w0.178: U11.F3 v2(85.66,65.2)
  LY3 w0.102: v2(85.66,65.2) 85.66,65.45 85.82,65.6 85.98,65.6 86.06,65.52 86.06,62.91 85.87,62.72 85.87,62.66
  LY3 w0.105: 85.87,62.66 82.65,59.45 82.65,33.36 78.67,29.37 78.67,21.11
  LY3 w0.108: 78.67,21.11 78.95,20.83 79.31,20.83 79.4,20.73 v1(79.4,20.32)
  BOTTOM w0.178: v1(79.4,20.32) J500.24A
DDB14_N: length 49
  TOP w0.178: U11.E2 v2(84.66,64.2)
  LY4 w0.102: v2(84.66,64.2) 84.66,63.9 84.76,63.8 85.01,63.8 85.27,63.55 85.27,62.84 85.29,62.81 85.29,62.79
  LY4 w0.105: v1(79.4,26.67) 79.4,26.29 79.27,26.17 79.22,26.17 78.9,26.49 78.9,28.58 77.38,30.1 77.38,50.93 77.53,51.07 78.22,51.07 78.55,51.4 78.55,51.87 78.22,52.2 77.42,52.2 77.31,52.3 77.31,52.63 77.39,52.72 77.39,52.72 77.49,52.81 78.23,52.81 78.56,53.14 78.56,53.61 78.23,53.94 77.58,53.94 77.38,54.14 77.38,55.18 83.52,61.32 84.65,61.32 85.29,61.96 85.29,62.79
  BOTTOM w0.178: J500.24E v1(79.4,26.67)
DDB14_P: length 49.1
  TOP w0.178: U11.E1 v2(84.66,63.2)
  LY4 w0.102: 85.04,62.79 85.04,62.81 85.06,62.84 85.06,63.46 84.93,63.6 84.75,63.6 84.66,63.51 v2(84.66,63.2)
  LY4 w0.105: v1(79.4,25.4) 79.4,25.75 79.23,25.91 79.12,25.91 78.64,26.38 78.64,28.48 78.64,28.48 77.13,29.99 77.13,51.03 77.42,51.33 78.11,51.33 78.29,51.51 78.29,51.76 78.11,51.94 77.31,51.94 77.06,52.2 77.06,52.74 77.31,52.99 77.38,53.07 78.12,53.07 78.3,53.25 78.3,53.5 78.12,53.68 77.48,53.68 77.13,54.03 77.13,55.29 83.41,61.57 84.55,61.57 85.04,62.06 85.04,62.79
  BOTTOM w0.178: J500.24D v1(79.4,25.4)
DDB15_N: length 49.7
  TOP w0.178: U11.D2 v2(83.66,64.2)
  LY4 w0.102: 83.03,62.85 83.03,62.85 83.03,62.87 83.06,62.9 83.06,63.56 83.31,63.81 83.57,63.81 83.66,63.9 v2(83.66,64.2)
  LY4 w0.105: 83.03,62.85 83.03,62.48 75.43,54.88 75.37,54.83 75.37,54.62 75.37,54.61 75.37,28.19 77.64,25.92 77.72,25.92 77.72,25.92 78.27,25.92 78.66,25.53 78.66,22.5 78.62,22.46 78.51,22.35 78.25,22.35 78.13,22.47 v1(78.13,22.86)
  BOTTOM w0.108: J500.25C v1(78.13,22.86)
DDB15_P: length 49.8
  TOP w0.178: U11.D1 v2(83.66,63.2)
  LY4 w0.102: 83.66,63.21 83.66,63.52 83.58,63.61 83.4,63.61 83.26,63.47 83.26,62.88 83.28,62.86 83.28,62.85
  LY4 w0.105: 83.28,62.85 83.28,62.38 75.68,54.78 75.68,54.78 75.63,54.72 75.63,54.72 75.63,28.29 77.75,26.17 77.83,26.17 77.83,26.17 78.38,26.17 78.92,25.63 78.92,22.4 78.87,22.35 78.62,22.1 78.62,22.09 78.24,22.09 78.13,21.99 v1(78.13,21.59)
  LY4 w0.108: v2(83.66,63.2) 83.66,63.21
  BOTTOM w0.108: J500.25B v1(78.13,21.59)
DINTZ: length 12.1
  TOP w0.178: U11.AC8 v2(103.66,70.2)
  LY4 w0.102: 107.63,71.48 107.3,71.81 105.11,71.81 104.9,71.59 104.5,71.59 104.06,71.15 104.06,71.04 103.66,70.64 v2(103.66,70.2)
  LY4 w0.171: 107.63,71.48 107.7,71.4 110.27,71.4 v2(111.57,70.1)
  BOTTOM w0.178: R621.1 C611.1 v2(111.57,70.1)
DM0: length 8.2
  TOP w0.178: U11.AE6 v2(105.66,68.2)
  BOTTOM w0.102: v2(105.66,68.2) 106.16,68.7 107.18,68.7 107.63,68.24
  BOTTOM w0.178: C653.1 R652.1 108.84,64.52 108.46,64.9 108.46,66.23 108.07,66.62 108.07,67.8 107.63,68.24
DM1: length 13.3
  TOP w0.178: U11.AD7 v2(104.66,69.2)
  LY4 w0.102: v2(104.66,69.2) 104.66,69.21 104.27,69.61 104.27,70.46 104.42,70.6 104.91,70.6 105.11,70.81 107.2,70.81 107.2,70.79 107.45,70.54 107.63,70.54
  LY4 w0.171: 107.63,70.54 108.08,70.1 108.08,70.05 110.28,67.85 110.28,67.32 110.6,67.01 111.04,67.01 111.18,67.15 v2(111.58,67.15)
  BOTTOM w0.178: C647.1 R645.1 111.93,66.8 v2(111.58,67.15)
DMD_P3P3V: length 111.8
  TOP w0.508: R35.1 96.81,34.3 96.41,34.71 96.41,34.75 96.14,35.01 96.1,35.01 v1(96,35.11) ; C35.2 FB10.1 111.66,13.77 J51.2 ; v1(82.09,34.9) 82.17,34.9 82.17,34.87 82.11,34.81 C31.2 80.3,35.79 FB9.1 75,35.79 74.3,35.09 73.36,35.09 72.61,34.34 68.08,34.34 66.54,32.8 66.54,18.49 64.08,16.03 64.08,11.98 64.8,11.26 69.98,11.26 73.03,14.32 81.98,14.32 83.87,12.42 89.4,12.42 90.14,13.16 90.14,13.28 90.25,13.39 90.25,13.69 90.39,13.83 R58.1 90.81,13.83 v1(91.76,12.88)
  LY3 w0.508: J51.2 109.66,14.9 109.28,14.9 108.58,15.6 106.81,15.6 106.4,16 100.97,16 98.79,13.83 92.7,13.83 v1(91.76,12.88)
  BOTTOM w0.508: v1(96,35.11) 95.04,36.07 83.26,36.07 v1(82.09,34.9)
DMDP3P3VA: length 15.7
  TOP w0.508: FB10.2 113.67,14.99 114.41,14.24 C36.2 115.46,14.24 v1(116.08,14.86)
  LY3 w0.102: v1(110.01,22.73) 109.88,22.61 v1(109.88,21.59) 110.87,20.6
  LY3 w0.508: v1(116.08,14.86) 113.79,17.14 113.79,17.68 110.87,20.6
  BOTTOM w0.178: v1(109.88,21.59) J500.1B ; v1(110.01,22.73) 109.25,23.5
DMDP3P3VB: length 11.8
  TOP w0.508: v1(78.36,33.77) C30.2 76.49,33.77 FB9.2
  LY3 w0.102: v1(78.13,26.67) v1(78.13,27.94) 77.6,28.47
  LY3 w0.508: 77.6,28.47 77.47,28.6 77.47,32.88 v1(78.36,33.77)
  BOTTOM w0.178: J500.25F v1(78.13,27.94) ; J500.25E v1(78.13,26.67)
DMDSPARE0: length 13.6
  TOP w0.508: R34.1 94.39,33.26 v1(94.17,33.05)
  LY4 w0.508: v1(95.91,25.4) 95.02,24.51 94.49,24.51 93.47,25.53 93.47,32.36 94.16,33.05 v1(94.17,33.05)
  BOTTOM w0.508: J500.12D v1(95.91,25.4)
DOEZ: length 7.8
  TOP w0.178: U11.AE7 v2(105.66,69.2)
  BOTTOM w0.102: 107.61,69.43 107.25,69.79 106.25,69.79 v2(105.66,69.2)
  BOTTOM w0.178: 107.61,69.43 107.61,68.91 108.44,68.08 108.44,66.94 109.02,66.37 C652.1 R651.1
DRV_RST: length 64.3
  TOP w0.178: J39.12 12.91,31.11 13.96,32.16 v1(15.94,32.16)
  LY3 w0.171: v1(15.94,32.16) 17.09,33.31 17.09,38.42 16.03,39.48 13.42,39.48 12.81,40.09 12.81,68.51 15.87,71.57 15.87,77.52 v1(19.9,81.54)
  BOTTOM w0.178: U506.15 v1(19.9,81.54)
DRV_RST/SSP2_CSZ_1: length 109.6
  TOP w0.178: U11.K22 v2(89.66,85.2)
  LY3 w0.102: v2(89.66,85.2) 89.66,85.04 90.26,84.45 90.26,83.95 89.91,83.6 89.25,83.6 89.01,83.36 88.3,83.36 88.09,83.16 87.96,83.16 87.52,82.72 87.52,80.08 86.03,78.59 80.46,78.59 79.69,77.83 79.69,77.63
  LY3 w0.171: 79.69,77.63 78.64,76.58 76.8,74.74 75.33,73.27 75.15,73.46 74.65,73.46 74.35,73.16 73.47,73.16 73.16,72.85 73.16,71.4 75.46,69.1 75.46,68.15 75.11,67.8 75.01,67.8 74.53,67.32 74.53,65 76.45,63.08 76.45,61.51 77.44,60.52 77.44,59.55 77.83,59.16 77.83,58.31 77.68,58.15 77.68,53.13 76.31,51.77 76.31,46.32 76.31,45.4 74.03,43.12 74.03,40.17 74.03,39.01 73.08,38.05 73.08,35.66 71.92,34.5 71.92,29.4 71.79,29.27 71.79,29.19 64.98,22.38 64.98,20.02 61.09,16.12 v1(59.17,16.12)
  LY4 w0.171: v1(49.15,16.98) 49.47,17.31 55.24,17.31 56.1,18.17 58.23,18.17 59.17,17.23 v1(59.17,16.12)
  BOTTOM w0.178: U518.13 47.83,16.2 48.48,16.85 49.01,16.85 v1(49.15,16.98)
DS0: length 13.9
  TOP w0.178: U11.AC7 v2(103.66,69.2)
  LY4 w0.102: 107.2,71.3 107.2,71.3 107.12,71.3 106.83,71.59 105.45,71.59 105.06,71.2 105.06,71.04 104.83,70.81 104.24,70.81 104.06,70.62 104.06,69.59 v2(103.66,69.2)
  LY4 w0.171: v2(111.44,68.45) 111.44,69.48 111.04,69.88 111.04,70.03 110.09,70.97 107.53,70.97 107.2,71.3
  BOTTOM w0.178: R644.1 C646.1 v2(111.44,68.45)
DS1: length 12.5
  TOP w0.102: U11.AE4 105.2,66.7 105.69,66.22 106.57,66.22 107.63,65.16
  TOP w0.178: 107.63,65.16 108.15,64.64 108.15,63.23 108.92,62.46 108.92,61.51 109.89,60.54 110.68,60.54 111.12,60.99 111.25,60.99 111.61,61.34 111.61,61.47 111.7,61.56 v2(111.7,61.55)
  BOTTOM w0.178: v2(111.7,61.55) 111.7,61.55 111.79,61.47 C650.1 R648.1
DSP_A1P8V: length 28.2
  TOP w0.178: U7.40 41.64,89.8 42.02,90.18 v1(42.02,90.51) ; v1(37.71,96.72) 37.41,97.02 U7.12
  LY3 w0.171: v1(37.71,96.72) 37.71,94.57 38.96,93.32 40.79,93.32 41.37,93.89 42.9,93.89 43.88,92.9 43.88,91.09 43.53,90.74 43.31,90.51 v1(42.02,90.51)
  BOTTOM w0.178: v1(42.02,90.51) 42.02,89.88 C573.1 ; C561.1 33.29,96.52 34.67,96.52 34.87,96.72 C558.1 ; C558.1 v1(37.71,96.72) ; C558.1 FB501.1
DSP_A3P3V: length 20.8
  TOP w0.178: v1(29.4,94.74) 29.89,94.25 31.4,94.25 v1(31.44,94.3)
  TOP w0.254: U7.26 34.64,92.23 v1(35.12,92.71) ; v1(31.44,94.3) 31.5,94.35 31.5,95.12 31.89,95.52 U7.15
  BOTTOM w0.178: C562.1 31.65,94.5 v1(31.44,94.3) 31.44,93.49 32.09,92.84 34.99,92.84 v1(35.12,92.71) 34.92,92.52 C560.1 C559.1 ; v1(29.4,94.74) C563.1 FB503.1
DSP_EMU0: length 39.7
  TOP w0.178: U7.80 44.64,105.28 v1(45.21,105.85)
  LY4 w0.171: v1(45.21,105.85) 45.03,106.03 45.03,110.95 41.17,114.81 33.29,114.81 31.52,113.04 30.1,113.04 25.29,117.85 25.29,120.83 22.3,123.83 J1.13
  BOTTOM w0.178: R535.2 44.31,104.95 v1(45.21,105.85)
DSP_EMU1: length 41.5
  TOP w0.178: v1(44.39,107.06) 44.39,105.73 44.14,105.48 U7.81
  LY4 w0.171: v1(44.39,107.06) 44.39,110.49 40.88,114 34.38,114 32.91,112.53 29.57,112.53 24.47,117.63 24.47,120.8 22.78,122.49 21.02,122.49 19.68,123.83
  BOTTOM w0.178: R503.2 19.68,123.83
DSP_GPIO11: length 4.1
  TOP w0.178: v1(45.71,100.02) 46.01,100.32 47.16,100.32 47.46,100.02 U7.70
  BOTTOM w0.178: RN501.3 44.7,100.02 v1(45.71,100.02)
DSP_GPIO12: length 6.8
  TOP w0.178: U7.1 32.88,102.89 32.58,103.19 31.05,103.19 30.61,103.63 30.61,106.55 TP4.1
DSP_GPIO13: length 12.2
  TOP w0.178: U7.95 37.14,105.64 37.15,105.64 37.61,106.1 38.36,106.1 38.79,106.53 38.79,108.22 38,109.01 34.4,109.01 TP5.1
DSP_GPIO14: length 2.9
  TOP w0.178: U7.8 30.01,99.02 TP18.1
DSP_GPIO23: length 137.4
  TOP w0.178: U7.72 v1(46.74,101.02)
  LY3 w0.171: v1(20.97,104.85) 16.9,100.79 16.9,98.45 14.96,96.5 14.82,96.5 14.47,96.15 14.47,94.37 13.64,93.54 5.78,93.54 4.05,91.8 4.05,27.18 5.33,25.9 v1(5.33,24.77)
  LY4 w0.171: v1(20.97,104.85) 21.49,105.37 27.23,105.37 28.97,103.63 31.89,103.63 33.99,101.54 33.99,101.52 34.33,101.17 37.1,101.17 37.2,101.27 38.27,101.27 38.8,100.74 39.87,100.74 39.99,100.62 42.79,100.62 43.27,101.1 45.87,101.1 45.95,101.02 v1(46.74,101.02)
  BOTTOM w0.178: RN501.2 44.66,100.77 45.47,100.77 45.71,101.02 v1(46.74,101.02) ; v1(5.33,24.77) 3.17,24.77 2.03,23.62 2.03,22.85 1.96,22.78 1.96,17.22 2.03,17.15 2.03,17.12 3.05,16.1 U519.9
DSP_GPIO26: length 139.4
  TOP w0.178: v1(35.75,101.85) 35.14,102.46 U7.99
  LY3 w0.171: v1(19.47,104.37) 18.33,104.37 13.61,99.65 13.61,94.76 12.97,94.12 5.86,94.12 3.52,91.77 3.52,26.95 4.48,25.98 4.48,24.31 5.3,23.5 v1(5.33,23.5)
  LY4 w0.171: v1(19.47,104.37) 21.15,106.05 31.1,106.05 33.62,103.53 34.07,103.53 v1(35.75,101.85) 36.23,101.85 37.81,103.43 38.49,103.43 38.9,103.02 38.9,101.63 39.33,101.19 40.47,101.19 40.65,101.02 42.48,101.02 43.68,102.21 45.35,102.21 45.79,101.77 v1(45.79,101.75)
  BOTTOM w0.178: v1(45.79,101.75) 45.74,101.75 45.64,101.64 RN501.1 ; U519.10 3.05,16.75 2.4,17.41 2.4,22.59 3.3,23.5 v1(5.33,23.5)
DSP_INTZ: length 18.9
  TOP w0.178: U7.61 46.88,95.52 46.2,94.84 v1(46.12,94.84)
  BOTTOM w0.178: RN503.3 45.04,93.58 46.12,94.66 v1(46.12,94.84) 49.23,94.84 49.55,95.16 50.08,95.16 50.37,94.88 55.31,94.88 55.75,95.31 57.96,95.31 59.17,96.52 J14.1
DSP_P1P8V: length 263.4
  TOP w0.203: v1(46.9,98.58) 46.9,98.65 47.27,99.02 U7.68
  TOP w0.254: v1(34.51,98.17) 34.35,98.02 U7.10 ; U7.59 v1(49.82,94.52) ; J2.6 37.37,112.55 v1(37.59,112.33) 37.87,112.61 J2.8 ; U7.42 42.64,87.54 v1(42.93,87.25) ; J3.6 88.49,112.55 v1(88.71,112.33) 88.99,112.61 J3.8 ; U7.85 v1(42.14,102.83) ; v1(38.04,102.81) 38.14,102.91 U7.93
  TOP w0.381: v1(88.71,112.33) 87.48,111.1 C13.1
  TOP w0.508: v1(37.59,112.33) 37.59,111.52 C10.1 ; v1(142.08,126.92) 141.73,126.58 138.88,126.58 137.03,124.73 134.44,124.73 133.94,124.22 130.63,124.22 124.35,130.5 88.24,130.5 88.16,130.59 86.37,130.59 86.29,130.5 82.47,130.5 82.43,130.55 81.23,130.55 81.19,130.5 79.34,130.5 v1(75.09,126.25)
  LY3 w0.508: J18.2 144.56,93.74 146.58,95.76 146.58,98.36 145.76,99.19 145.76,123.24 v1(142.08,126.92) ; v1(38.04,102.81) 38.04,102.49 38.1,102.42 38.1,100.74 v1(37.77,100.41) 35.53,98.17 v1(34.51,98.17) ; v1(38.04,102.81) 38.04,105.88 38.69,106.54 38.69,109.88 37.59,110.98 v1(37.59,112.33) ; v1(38.04,102.81) 38.93,102.81 39.63,103.5 41.4,103.5 42.07,102.83 v1(42.14,102.83) 42.42,102.55 42.42,102.25 44.95,99.72 44.95,99.7 45.39,99.26 45.41,99.26 45.81,98.86 46.62,98.86 v1(46.9,98.58) 47.95,98.58 48.31,98.22 48.31,96.08 49.82,94.57 v1(49.82,94.52) 48.46,93.16 48.46,89.28 48.18,89 48.01,89 48,89.01 47.46,89.01 47.45,89 47.33,89 45.58,87.25 v1(42.93,87.25)
  BOTTOM w0.508: v1(88.71,112.33) 88.1,112.94 88.1,113.51 87.53,113.51 86.56,114.48 85.36,114.48 83.44,116.4 83.44,117.28 83.5,117.35 83.5,123.77 81.07,126.2 77.97,126.2 77.53,126.64 75.48,126.64 v1(75.09,126.25) 73.03,126.25 72.44,125.67 72.44,121.51 71.99,121.06 71.99,121.02 70.61,119.63 64.76,119.63 63.91,118.78 60.36,118.78 56.38,114.8 54.81,114.8 52.94,116.68 50.64,116.68 50.16,116.2 48.27,116.2 46.74,117.73 41.67,117.73 39.98,116.04 39.98,113.56 39.58,113.16 38.29,113.16 37.59,112.46 v1(37.59,112.33) ; C530.1 46.99,98.67 v1(46.9,98.58) ; v1(38.04,102.81) 38.72,103.49 C533.1 ; C537.1 34.37,98.31 v1(34.51,98.17) ; v1(42.14,102.83) 42.18,102.87 C532.1 ; FB501.2 v1(37.77,100.41) ; v1(42.93,87.25) 42.94,87.26 C572.1 ; C557.1 49.16,93.87 v1(49.82,94.52)
DSP_P3P3V: length 123.2
  TOP w0.254: v1(44.32,102.87) 44.01,103.18 43.94,103.18 43.93,103.19 43.88,103.19 43.68,103.38 43.68,103.39 43.64,103.39 U7.82 ; v1(36.26,102.74) 36.64,103.12 U7.96 ; U7.46 44.64,89.6 44.68,89.65 44.68,89.66 44.74,89.72 v1(44.74,90.08) ; U7.3 34.34,101.52 v1(34.58,101.77) ; U7.65 v1(47.04,97.52)
  TOP w0.508: v1(44.32,102.87) 43.94,102.49 43.94,102.43 42.4,100.88 41.51,100.88 41.36,101.03 39.37,101.03 39.05,101.35 37.02,101.35 36.58,101.79 36.58,102.43 v1(36.26,102.74) ; v1(47.04,97.52) 45.89,97.52 45.4,97.03 44.77,97.03 44.25,97.54 v1(39.73,97.54) ; v1(46.96,102.04) 46.96,102.23 46.97,102.25 46.97,103.08 47.5,103.6 47.5,104.73 v1(47.54,104.78)
  TOP w1.27: v1(28.14,99.69) 27.76,100.08 25.72,100.08 v1(23.56,102.23) 23.56,103.5 24.57,104.52 24.57,111.32 J1.5 24.47,115.91 24.47,123.8 20.7,127.57 v1(19.68,127.57)
  LY3 w0.508: v1(44.32,102.87) 46.23,104.78 v1(47.54,104.78) ; v1(44.74,90.08) 44.74,90.04 44.82,90.12 44.82,92.89 42.86,94.84 42.86,95.38 42.08,96.16 41.11,96.16 v1(39.73,97.54) ; v1(36.26,102.74) 35.56,102.74 v1(34.58,101.77) 32.97,103.38 30.67,103.38 28.14,100.85 v1(28.14,99.69)
  LY4 w0.508: v1(53.02,102.14) 51.02,100.14 48.86,100.14 v1(46.96,102.04)
  BOTTOM w0.508: R566.1 52.67,102.49 v1(53.02,102.14) 53.2,102.31 54.88,102.31 55.06,102.49 R564.1 ; FB502.1 v1(23.56,102.23) ; C535.1 35.26,103.75 v1(36.26,102.74) 36.56,103.05 C534.1 ; C536.1 34.15,101.33 v1(34.58,101.77) ; C571.1 44.74,89.36 v1(44.74,90.08) ; R535.1 47.42,104.9 v1(47.54,104.78) ; v1(44.32,102.87) 44.31,102.88 C531.1 ; v1(47.04,97.52) 47.26,97.29 C556.1 48.96,98.24 48.96,100.09 47.87,101.18 R568.1 47.02,101.98 v1(46.96,102.04) 46.97,102.05 46.97,102.61 47.24,102.87 R567.1 ; R503.1 v1(19.68,127.57) ; C538.1 v1(28.14,99.69)
DSP_PWM_0: length 25.5
  TOP w0.178: RN1.1 44.18,83.84 v1(44.84,84.5) 44.82,84.53 44.82,86.68 45.15,87.01 45.15,88.75 U7.47
  BOTTOM w0.178: v1(44.84,84.5) 44.51,84.5 42.28,82.27 39.36,82.27 38.24,83.39 38.24,83.54 37.27,84.51 31.81,84.51 31.58,84.28 28.99,84.28 28.86,84.15 U506.6
DSP_PWM_1: length 26.2
  TOP w0.178: U7.44 43.64,86.67 43.28,86.31 v1(43.28,85.72) 43.26,85.7 RN1.2
  LY4 w0.171: v1(29.14,83.52) 29.66,83.01 29.68,83.01 30.75,81.94 30.75,81.33 31.09,80.99 32.12,80.99 32.93,81.79 35.49,81.79 36.09,82.4 37.25,82.4 37.62,82.77 38.89,82.77 39.31,82.35 40.27,82.35 41.52,83.59 42.79,83.59 43.28,84.08 v1(43.28,85.72)
  BOTTOM w0.178: U506.7 29.12,83.49 v1(29.14,83.52)
DSP_PWM_2: length 29.1
  TOP w0.178: v1(44.04,85.02) 44.14,85.12 U7.45 ; RN1.3 v1(42.46,84.52)
  BOTTOM w0.178: v1(42.46,84.52) 42.96,85.02 v1(44.04,85.02) 44.06,85.02 44.36,85.32 45.15,85.32 45.63,84.84 45.63,84.25 45.24,83.86 44.83,83.86 42.68,81.71 39.22,81.71 38.73,82.2 32.95,82.2 32.31,82.84 U506.8
DSP_PWM_3: length 31.7
  TOP w0.178: v1(38.47,81.56) 39.65,81.56 41.45,83.35 RN1.4 ; v1(45.13,83.21) 45.13,83.24 45.64,83.75 45.64,84.84 45.28,85.2 45.28,86.49 45.64,86.85 U7.48
  LY4 w0.171: v1(29.3,82.03) 29.93,81.4 29.93,80.11 30.34,79.7 32.17,79.7 32.59,79.28 32.6,79.28 32.71,79.17 34.37,79.17 36.79,81.59 38.44,81.59 v1(38.47,81.56)
  BOTTOM w0.178: v1(29.3,82.03) 29.14,82.19 U506.9 ; v1(38.47,81.56) 38.85,81.18 43.1,81.18 v1(45.13,83.21)
DSP_RDY: length 17.9
  TOP w0.178: U7.60 49.36,95.02 49.88,95.53 v1(50.62,95.53)
  BOTTOM w0.178: J13.1 55.66,96.52 55.53,96.39 55.53,95.83 55.34,95.64 55.17,95.47 50.68,95.47 v1(50.62,95.53) 50.44,95.53 50.3,95.68 49.33,95.68 49.09,95.44 46.84,95.44 46.42,95.86 46.42,96.45 v1(45.09,97.79) 44.62,98.26 RN501.4
DSP_RSTZ: length 4.3
  TOP w0.178: J8.2 48.04,107.22 v1(46.67,105.85) 46.16,105.85 45.64,105.33 U7.78
DSP_TCK: length 46
  TOP w0.178: v1(50.12,103.65) 49.92,103.44 49.91,103.44 48.99,102.52 U7.75
  LY4 w0.171: v1(50.12,103.65) 47.71,103.65 46.66,104.7 43.31,104.7 43.1,104.9 40.35,104.9 38.6,106.65 38.6,108.5 36.36,110.74 26.8,110.74 22.64,114.9 21.45,114.9 20.8,115.55 20.8,117.3 22.23,118.73 J1.9
  BOTTOM w0.178: J1.11 J1.9 ; R566.2 R565.1 50.14,103.63 v1(50.12,103.65)
DSP_TDI: length 42.2
  TOP w0.178: v1(50.04,100.9) 49.42,101.52 U7.73
  LY4 w0.171: J1.3 23.47,109.88 32.37,109.88 33.79,108.46 33.79,106.68 33.15,106.03 33.15,105.66 34.04,104.78 34.92,104.78 35.61,105.46 38.09,105.46 38.52,105.46 39.79,104.19 42.81,104.19 42.87,104.13 43.01,103.99 46.36,103.99 47.73,102.62 50.11,102.62 50.69,102.04 50.69,101.55 v1(50.04,100.9)
  BOTTOM w0.178: R567.2 50.1,102.87 50.42,102.55 50.42,102.36 50.54,102.23 50.54,101.7 50.42,101.58 50.42,101.28 v1(50.04,100.9)
DSP_TDO: length 4.4
  TOP w0.178: U7.76 46.64,104.78 47.28,105.42 47.81,105.42 47.98,105.25 48.06,105.25 48.45,104.85 v1(49.2,104.85)
  BOTTOM w0.178: R534.1 v1(49.2,104.85)
DSP_TDO_OUT: length 42.8
  LY4 w0.171: v1(51.16,105.66) 47.35,105.66 46.74,105.05 43.45,105.05 43.25,105.26 40.63,105.26 39.03,106.85 39.03,109.35 36.83,111.56 26.87,111.56 J1.7
  BOTTOM w0.178: R534.2 v1(51.16,105.66) 52.64,105.66 54.29,104.01 54.94,104.01 R564.2
DSP_TMS: length 34.7
  TOP w0.178: v1(49.9,101.97) 49.85,102.02 U7.74
  LY4 w0.171: J1.1 22.29,108.58 23,109.3 30.01,109.3 31.69,107.62 31.69,106.93 32.79,105.83 32.79,105.52 33.89,104.42 35.07,104.42 35.4,104.75 35.9,104.75 36.26,105.11 38.24,105.11 39.51,103.84 42.66,103.84 42.72,103.77 42.86,103.63 46.22,103.63 46.69,103.16 46.69,103.16 47.83,102.02 49.85,102.02 v1(49.9,101.97)
  BOTTOM w0.178: v1(49.9,101.97) 49.85,102.02 48.95,102.02 R568.2
DSP_TRSTZ: length 30.3
  TOP w0.178: U7.84 42.64,103.28 v1(43.18,102.74)
  LY4 w0.171: v1(43.18,102.74) 42.44,103.48 39.26,103.48 38.44,104.29 35.45,104.29 35.22,104.06 33.74,104.06 31.05,106.75 31.05,107.57 30.26,108.36 25.31,108.36 24.12,107.16 21.18,107.16 19.76,108.58 19.68,108.58
  BOTTOM w0.178: R569.1 v1(43.18,102.74)
DSTB: length 8.5
  TOP w0.178: v2(107.1,67.17) 106.56,67.7 U11.AF5
  BOTTOM w0.102: v2(107.1,67.17) 107.1,67.17 107.33,66.95 107.33,65.88 107.47,65.74 107.47,64.25 107.63,64.09
  BOTTOM w0.178: R654.1 C655.1 108.84,61.47 108.21,62.1 108.21,62.97 108,63.18 108,63.43 107.92,63.51 107.92,63.8 107.63,64.09
DYN_BLK_BUF: length 2.1
  BOTTOM w0.178: R768.2 65.96,7.54 U523.4
EXT_ARSTZ: length 483.2
  TOP w0.178: U11.T24 v2(96.66,87.2) ; J8.1 TP6.1 46.15,110.38 R7.2 ; R9.1 v1(65.02,109.86)
  LY3 w0.171: J8.1 46.06,107.31 47.27,106.1 47.27,106.08 48.31,105.05 48.31,104.47 49.01,103.76 49.01,97.05 50.02,96.05 50.02,95.29 50.37,94.94 51.13,94.94 51.44,94.62 51.44,92.89 50.98,92.43 50.22,92.43 49.42,91.64 49.42,87.79 45.91,84.28 45.46,84.28 45.09,83.91 44.6,83.91 44.25,84.26 43.04,84.26 42.71,83.92 42.13,83.92 40.81,85.25 40.81,85.27 40.04,86.04 37.35,86.04 35.47,84.16 33.3,84.16 32.8,83.66 32.8,79.71 33.35,79.16 33.35,77.21 32.41,76.27 31.22,76.27 29.76,74.81 29.76,68.33 29.76,67.45 29.62,67.31 28.76,66.45 28.76,61.16 28.55,60.95 25.85,58.25 25.85,48.19 25.87,48.18 27.59,46.45 27.59,45.78 27.59,45.78 27.59,34.45 24.32,31.18 24.32,21.14 25.64,19.82 26.74,19.82 30.13,16.43 32.35,16.43 32.85,15.93 32.85,15.11 33.16,14.81 33.16,13.64 32.81,13.29 32.81,12.19 33.49,11.5 36.84,11.5 37.15,11.81 37.84,11.81 40.52,9.13 53.25,9.13 53.33,9.21 53.48,9.21 53.72,8.97 54.22,8.97 54.46,9.21 v1(57.38,9.21) ; v1(65.02,109.86) 65.02,108.16 64.13,107.27 64.13,104.4 65.31,103.22 65.82,103.22 69.26,99.78 69.32,99.78 69.32,97.4 75.67,91.05 v1(77.23,91.05) ; v1(97.18,27.94) 96.52,27.28 96.52,24.64 95.25,23.37 95.25,21.8 90.81,17.36 81.45,17.36 80.1,16 69.44,16 66.19,12.75 v1(62.36,12.75)
  LY4 w0.102: 99.52,19.61 99.19,19.94 99.19,28.19 98.91,28.47 ; v1(97.18,27.94) 97.18,27.97 97.69,28.47
  LY4 w0.171: 99.52,19.61 99.53,19.6 112.05,19.6 113.54,21.08 114.3,21.08 116.71,23.5 116.71,31.2 119.03,33.52 140.1,33.52 141.28,34.69 143.9,34.69 144.46,34.13 144.46,28.49 145.92,27.03 154.61,27.03 157.31,29.73 165.85,29.73 168.55,27.03 174.9,27.03 177.04,24.89 183.6,24.89 183.65,24.94 189.81,24.94 193.68,21.08 195.58,21.08 196.6,20.07 196.6,18.54 195.05,16.99 192.96,16.99 192.14,16.17 192.14,16.16 191.79,15.81 191.78,15.81 191.39,15.42 191.39,12.33 192.42,11.3 192.42,6.24 188.8,2.62 v1(172.09,2.62) ; TP6.1 48.34,110.49 50.95,107.88 51.51,107.88 52.2,108.57 52.2,111.25 48.6,114.85 48.6,119.31 50.39,121.1 53.15,121.1 53.57,120.68 53.57,116.3 52.2,114.92 52.2,114.43 52.55,114.08 53.04,114.08 53.07,114.11 54.57,114.11 54.94,113.74 60.45,113.74 62.4,111.79 62.4,111.05 63.05,110.39 64.49,110.39 v1(65.02,109.86) ; 97.69,28.47 97.82,28.6 98.78,28.6 98.91,28.47
  BOTTOM w0.102: 79.69,89.42 79.74,89.36 80.03,89.36 80.26,89.59 83.83,89.59 84.06,89.36 84.06,89.12 84.37,88.81 87.65,88.81 88.06,88.4 88.06,86.65 88.26,86.45 88.26,86.02 88.49,85.8 88.98,85.8 89.27,85.51 89.27,85.04 89.5,84.81 91.5,84.81 91.5,84.81 91.83,84.81 92.95,84.81 93.16,84.59 94.39,84.59 94.56,84.76 94.78,84.76 95.06,85.04 95.06,85.21 95.07,85.22 95.07,85.45 95.42,85.81 95.83,85.81 96.15,86.13 96.15,86.36 96.41,86.63 96.41,86.8 96.66,87.04 v2(96.66,87.2)
  BOTTOM w0.178: J500.11F v1(97.18,27.94) ; v1(77.23,91.05) 78.68,89.59 79.51,89.59 79.69,89.42 ; v1(57.38,9.21) 57.38,9.89 58.54,11.04 60.66,11.04 v1(62.36,12.75) ; R776.1 171.82,2.93 172.09,2.67 v1(172.09,2.62)
EXT_CLK: length 69.5
  TOP w0.178: J3.52 99.99,112.13 100.82,111.3 101.46,111.3 v1(101.54,111.38)
  LY3 w0.102: 107.43,81.03 107.21,80.81 106.45,80.81 106.27,80.98 106.27,86.16 106.26,86.17 106.26,86.45 105.9,86.81 105.5,86.81 105.5,86.81 104.39,86.81 104.27,86.68 104.27,80.72 104.14,80.6 103.19,80.6 103.07,80.47 103.07,76.6 102.54,76.07 100.52,76.07 v2(100.51,76.06)
  LY3 w0.171: v1(101.54,111.38) 102.05,110.87 102.05,109.78 102.42,109.42 103.13,109.42 104,108.55 104,107.8 104.22,107.58 104.22,105.87 105.92,104.16 105.92,103.07 106.02,102.97 106.02,102.77 106.52,102.27 107.82,102.27 108.56,101.53 109.26,100.83 110.28,100.83 111.54,99.58 111.54,95.99 111.9,95.62 111.9,94.58 112.08,94.4 113.12,94.4 113.55,93.98 114,93.98 114.24,93.74 114.24,86.19 109.08,81.03 107.43,81.03
  BOTTOM w0.102: R604.1 100.39,75.95 v2(100.51,76.06)
FAN1_LOCKD: length 314.4
  TOP w0.178: J64.2 140.97,6.65 140.86,6.77 R63.1 v1(140.86,10.45) ; U11.B24 v2(81.66,87.2) ; v1(53.51,112.12) 53.51,112.09 53.84,112.42 54.85,112.42 57.5,109.77 60.34,109.77 61.87,108.24 62.82,108.24 64.08,106.98 65.09,106.98 66.08,105.99 66.35,105.73 66.35,102.45 66.4,102.39 66.4,101.6 66.35,101.55 66.35,100.72 67.21,99.86 67.49,99.86 68.54,98.81 68.54,97.45 70.01,95.98 70.01,95.74 71.39,94.36 75.41,94.36 75.81,94.75 75.81,95.62 75.85,95.66 v1(75.85,98.86)
  LY3 w0.171: v1(81.32,3.5) 81.44,3.62 91.54,3.62 92.93,5.02 93.94,5.02 94.49,4.46 98.83,4.46 99.87,3.42 105.71,3.42 106.43,4.14 106.93,4.14 107.41,3.66 112.93,3.66 113.04,3.55 113.35,3.24 114.56,3.24 115.42,3.24 115.95,3.77 117.2,3.77 117.86,4.44 120.96,4.44 121.04,4.36 121.53,4.36 121.61,4.44 126.72,4.44 127.39,3.77 127.8,3.29 127.99,3.1 135.37,3.1 140.86,8.58 v1(140.86,10.45) ; v1(22.89,32.95) 24.79,34.85 24.79,43.29 24.79,43.58 24.79,43.58 24.79,44.02 24.71,44.1 24.71,45.46 24.07,46.09 24.07,47.46 24.07,59.05 26.67,61.65 26.67,65.43 26.98,65.74 26.98,67.19 27.63,67.84 27.84,68.04 27.84,78.89 27.58,79.15 27.58,81.66 27.34,81.9 27.34,83.74 26.8,84.28 26.8,86.64 26.18,87.25 26.18,107.78 30.92,112.52 32.96,112.52 34.47,114.03 48.06,114.03 49.97,112.12 v1(53.51,112.12) ; v2(81.66,87.2) 81.16,87.71 81.16,90.06 81.05,90.17 81.05,90.46 80.73,90.77 80.73,90.85 76.8,94.78 76.16,94.78 75.81,95.13 75.81,98.82 v1(75.85,98.86)
  LY4 w0.171: v1(22.89,32.95) 25.19,30.64 38.56,30.64 38.87,30.95 52.09,30.95 52.9,31.76 v1(54.27,31.76)
  BOTTOM w0.178: v1(81.32,3.5) 81.32,7.46 79.86,8.92 78.37,10.41 77.51,11.27 67.21,11.27 64.55,13.93 64.55,21.47 v1(54.27,31.76)
FAN1_SW: length 86
  TOP w0.254: U15.40 v2(158.64,57.75)
  LY3 w0.508: v1(141.93,12.25) 160.59,12.25 163.7,15.37 163.7,18.67 161.42,20.95 161.42,25.27 155.96,30.73 155.96,41.78 159.51,45.34 159.51,52.58 159.96,53.02 159.96,56.45 158.68,57.73 158.62,57.73 v2(158.64,57.75)
  BOTTOM w0.508: v1(141.93,12.25) 141.48,12.7 L506.2
  BOTTOM w1.27: L506.2 138.12,12.18 135.76,9.82 135.76,8 D508.1 136.91,6.86 R779.1
FAN2_LOCKD: length 149.5
  TOP w0.178: U11.D21 v2(83.66,84.2) ; J65.2 153.03,6.61 152.92,6.72 R64.1 152.92,13.65 v1(152.87,13.69)
  LY3 w0.171: v1(136.27,15.43) 143.09,22.25 143.09,31.19 143.6,31.69 143.65,31.69 144.21,32.25 144.21,32.3 144.54,32.63 144.54,35.17 143.59,36.12 143.59,42.48 141.24,44.83 141.24,45.87 139.09,48.02 139.09,48.48 135.58,51.99 134.84,51.99 132.75,54.08 132.75,54.25 131.95,55.06 130.16,55.06 128.85,56.36 128.85,57.43 128.54,57.74 128.54,73.96 v1(128.59,73.96)
  LY4 w0.102: v2(83.66,84.2) 84,84.2 84.61,83.59 84.83,83.59 85.06,83.36 85.06,83.14 85.61,82.59 85.83,82.59 86.06,82.36 86.06,82.07 88.49,79.63 88.6,79.63 89.38,78.85 89.38,78.64 90.34,77.69 96.73,77.69 97.06,77.36 97.06,76.65 98.67,75.04 99.2,75.04 99.43,74.81 107.15,74.81 107.4,74.56
  LY4 w0.171: v1(128.59,73.96) 128.54,73.96 128.54,73.99 128.21,73.99 128.04,73.81 127.54,73.81 127.37,73.99 122.12,73.99 122.12,74.03 121.77,74.38 121.28,74.38 120.93,74.03 120.93,73.99 119.61,73.99 119.04,74.56 114.11,74.56 113.56,74 111.93,74 111.37,74.56 107.4,74.56 ; v1(152.87,13.69) 151.14,15.43 v1(136.27,15.43)
FAN2_SW: length 60
  TOP w0.254: U15.39 158.14,55.3 v1(157.88,55.04)
  LY3 w0.508: v1(157.88,55.04) 154.56,51.72 154.56,45.97 153.8,45.21 153.8,20.4 v1(147.59,14.19)
  BOTTOM w0.508: v1(147.59,14.19) 149.61,14.19 150.19,13.61 L505.2
  BOTTOM w1.27: L505.2 150.19,12.18 147.83,9.82 147.83,8 D507.1 148.97,6.86 R778.1
FAN3_LOCKD: length 259.1
  TOP w0.102: U11.C23 v2(82.66,86.2)
  TOP w0.178: v1(158.75,5.98) 158.75,7.92 159.48,8.66 164.12,8.66 R65.1 164.99,8.44 164.47,7.91 J66.2
  LY3 w0.171: v1(57.94,11.65) 57.28,11 53.59,11 53.18,11.41 53.18,12.88 54.17,13.87 55.99,13.87 56.35,14.23 56.35,14.73 56,15.07 55.42,15.07 54.86,15.64 53.64,15.64 52.52,16.76 52.52,19.95 50.61,21.86 50.17,21.86 49.43,22.61 49.43,27 51.24,28.81 51.24,33.66 53.81,36.23 54.03,36.23 54.38,36.58 54.38,38.09 54.1,38.37 54.1,40.3 54.65,40.84 v1(54.65,41.35) ; v2(82.66,86.2) 83.19,85.68 83.19,84.96 82.93,84.71 80.13,84.71 79.69,85.15 79.52,85.15 74.77,89.89 72.19,89.89 72.15,89.85 71.36,89.85 70.8,89.29 70.8,87.52 70.24,86.96 70.24,86.75 69.42,85.93 69.42,85.92 68.64,85.14 67.51,85.14 64.94,82.58 64.24,82.58 62.52,80.87 62.1,80.87 61.84,80.61 61.84,79.22 61.54,78.92 60.56,78.92 59.86,78.22 59.49,78.22 58.31,77.04 58.31,74.9 57.92,74.51 57.16,74.51 55.66,73.02 55.66,72.19 56.84,71.02 56.84,70.53 56.22,69.91 56.22,69.86 55.39,69.02 54.42,69.02 53.34,67.94 51.44,67.94 47.48,63.99 47.48,62.23 49.23,60.48 49.23,56.34 46.66,53.77 45.9,53.77 42.47,50.34 42.47,49.96 40.96,48.46 v1(40.96,46.65)
  LY4 w0.171: v1(40.96,46.65) 43.68,43.93 52.06,43.93 v1(54.65,41.35) ; v1(158.75,5.98) 158.29,6.44 145.32,6.44 142.83,8.93 122.51,8.93 121.06,7.48 104.9,7.48 104.5,7.87 92.82,7.87 92.44,8.26 91.59,9.11 85.89,9.11 85.88,9.11 81.74,9.11 78.86,11.99 58.27,11.99 v1(57.94,11.65)
FAN3_SW: length 61.7
  TOP w0.178: U15.38 157.64,57.37 v2(157.23,57.78)
  LY3 w0.508: v1(162.25,15.75) 162.25,15.8 160.02,18.03 160.02,23.75 154.94,28.83 154.94,43.48 156.63,45.17 156.63,50.08 157.73,51.18 157.73,52.45 158.9,53.62 158.9,55.6 157.23,57.28 v2(157.23,57.78)
  BOTTOM w0.508: L504.2 v1(162.25,15.75)
  BOTTOM w1.27: R777.1 161.04,6.86 D506.1 159.89,8 159.89,9.82 162.25,12.18 L504.2
FAN4_LOCKD: length 209.5
  TOP w0.178: R49.1 139.7,22.24 J42.2 v1(139.7,25.94)
  LY3 w0.171: v1(73.93,81.17) 71.57,81.17 70.01,79.61 67.76,79.61 66.12,77.97 66.12,77.9 65.08,76.87 63.92,76.87 62.43,75.37 62.43,73.05 62.02,72.63 60.2,70.81 60.16,70.77 60.16,69.2 59.3,68.35 59.3,68.28 59.18,68.09 59.02,67.93 59.02,66.06 56.13,63.17 56.13,57.81 56.42,57.53 56.42,57.03 56.07,56.68 55.2,56.68 54.75,56.23 53.23,56.23 52.08,55.08 52.08,50.54 52.44,50.18 v1(52.44,50.05)
  BOTTOM w0.178: v1(139.7,25.94) 139.7,29.67 142.02,31.99 142.92,31.99 143,32.07 143.01,32.05 143.51,32.05 143.86,32.4 143.86,32.89 143.84,32.91 144.6,33.67 144.6,33.92 143.66,34.86 141.94,34.86 141.15,34.06 139.7,34.06 139.38,33.74 138.89,33.74 138.57,34.06 136.77,34.06 136.45,33.74 135.95,33.74 135.63,34.06 132.22,34.06 127.35,29.19 127.35,26.92 127.54,26.72 127.54,24.28 126.62,23.36 126.62,15.62 123.28,12.28 108.08,12.28 107.64,12.72 107.64,14.38 107.2,14.82 101.82,14.82 101.57,15.07 100.36,15.07 100.07,15.07 100.07,15.07 97.99,15.07 94.71,11.79 91.9,11.79 91.79,11.9 78.49,11.9 78.06,12.33 68.56,12.33 67.57,13.33 67.57,45.3 64.16,48.71 53.06,48.71 52.58,49.19 52.58,49.91 v1(52.44,50.05) ; v1(73.93,81.17) 73.95,81.15 R605.2
FAN4_SW: length 148.3
  TOP w0.254: U2.40 159.91,107.98 159.73,107.8 159.06,107.8 159.05,107.79 158.98,107.79 v1(158.91,107.72)
  LY3 w0.508: v1(160.51,32.96) 168.55,40.99 168.55,46.41 170.55,48.41 170.55,50.24 174.69,54.38 175.2,54.38 176.21,55.39 176.21,55.6 177.01,56.4 177.01,57.4 177.89,58.29 177.89,60.38 176.33,61.95 176.33,64.4 175.82,64.9 174.48,64.9 174.15,65.49 173.77,65.86 173.77,65.9 173.67,66 173.67,82.97 173.59,83.05 173.59,85.73 174.47,86.62 174.47,90.47 175.75,91.74 175.75,109.6 v1(175.51,109.83)
  LY4 w0.508: v1(158.91,107.72) 158.94,107.68 159.81,107.68 160.84,106.64 162.02,106.64 162.42,107.04 163.05,107.04 163.45,106.64 163.73,106.64 163.89,106.81 164.52,106.81 164.69,106.64 172.22,106.64 175.5,109.92 175.5,109.83 v1(175.51,109.83)
  BOTTOM w0.508: 136.85,26.15 136.85,25.57 137.33,25.09 140.05,25.09 140.7,25.74 140.7,29.07 142.13,30.5 148.24,30.5 149.57,31.84 159.4,31.84 v1(160.51,32.96)
  BOTTOM w1.27: L503.2 136.85,26.15 134.62,23.92 134.62,21.85 D505.1 135.64,20.83 R744.1
FAN5_LOCKD: length 313.3
  TOP w0.178: v1(153.03,25.83) J43.2 153.03,22.24 R50.1 ; v1(55.34,4.53) 55.25,4.62 55.25,8.28 v1(53.97,9.57)
  LY3 w0.171: v1(55.34,4.53) 60.19,4.53 60.31,4.41 61.78,4.41 62.14,4.05 63.52,4.05 65,2.56 66.85,2.56 67.04,2.36 72.32,2.36 72.53,2.58 73.72,2.58 74.83,3.69 77.59,3.69 79.27,5.38 96.11,5.38 96.67,4.81 98.98,4.81 100.02,3.77 104.78,3.77 105.51,4.5 107.07,4.5 107.28,4.3 107.97,4.3 v1(107.98,4.29) ; v1(53.97,9.57) 53.01,9.57 52.48,10.1 44.27,10.1 40.7,13.68 38.51,13.68 36.7,11.86 33.8,11.86 33.68,11.99 33.51,11.99 33.16,12.34 33.16,13.14 34.54,14.52 35.44,14.52 36.42,15.5 36.42,17.98 33.49,20.91 33.37,20.91 32.1,22.17 32.1,23.29 32.05,23.34 32.05,24.26 33.12,25.33 33.14,25.33 33.15,25.35 33.81,25.35 34.29,24.87 34.29,24.29 34.06,24.05 33.11,24.05 32.82,23.75 32.82,23.15 33.11,22.86 34.65,22.86 34.93,23.14 36.97,23.14 39.26,25.44 40.51,25.44 40.86,25.79 40.86,26.68 41.58,27.4 41.58,36.38 41.78,36.58 41.78,37.48 42.36,38.06 43.67,38.06 44.58,38.97 44.58,43.03 45.46,43.92 49.53,43.92 50.17,44.57 50.4,44.57 51.01,45.18 51.01,46.01 50.89,46.14 50.89,46.55 50.81,46.94 50.73,47.14 50.73,50.56 50.53,50.76 50.53,51.82 49.78,52.57 49.78,53.79 52.12,56.12 52.12,57.53 52.4,57.82 52.4,60.68 52.96,61.24 53.72,61.24 54.07,61.59 54.07,63.77 57.51,67.21 57.67,67.21 58.31,67.86 58.31,68.23 58.59,68.51 58.59,68.64 59.45,69.5 59.45,71.07 59.78,71.4 59.78,72.02 60.09,72.33 60.71,72.33 61.72,73.34 61.72,76.22 61.75,76.22 62.1,76.57 62.1,76.76 63.23,77.89 63.33,77.89 63.26,77.92 65.02,77.92 68.06,80.96 70.36,80.96 72.45,83.06 v1(73.91,83.06)
  BOTTOM w0.178: v1(153.03,25.83) 153.03,28.58 154.87,30.42 162.69,30.42 163.83,29.28 163.83,25.61 164.55,24.89 165.66,24.89 166.19,25.41 166.19,29.88 167.18,30.87 167.75,30.87 170.3,28.31 170.3,24.39 171.28,23.41 171.28,17.48 169.71,15.91 163.3,15.91 162.6,16.6 161.9,16.6 161.2,15.91 159.73,15.91 159.54,16.11 135.77,16.11 128.03,8.36 122.28,8.36 121.57,9.07 121.56,9.07 120.9,9.74 120.4,9.74 119.61,8.95 114.4,8.95 111.18,5.73 111.18,5.69 110.64,5.15 110.64,4.86 110.64,4.7 110.36,4.42 108.11,4.42 107.98,4.29 v1(107.98,4.29) ; R595.2 v1(73.91,83.06)
FAN5_SW: length 157.3
  TOP w0.254: U2.39 159.41,110.17 159.5,110.26 159.5,110.4 v2(159.55,110.45)
  LY3 w0.508: v1(150.19,30.54) 150.19,47.26 142.69,54.75 142.69,60.83 144.71,62.84 145.23,63.36 145.23,66.29 148.66,69.72 148.66,75.5 148.53,75.63 148.53,81.31 149.64,82.43 149.64,83.43 151.21,85 151.21,90.96 153.16,92.9 153.16,95.44 151.29,97.31 151.29,105.33 v1(153.41,107.45)
  LY4 w0.508: J4.1 176.02,116.97 175.9,116.97 175.45,116.52 175.45,116.4 172.54,113.48 172.54,112.32 173.36,111.5 175.89,111.5 176.53,110.87 176.53,109.41 175.94,108.81 175.82,108.81 172.53,105.52 164.76,105.52 164.52,105.29 163.89,105.29 163.66,105.52 160.53,105.52 159.38,106.67 158.75,106.67 158.13,106.05 153.81,106.05 153.33,106.53 153.33,107.37 v1(153.41,107.45) 153.33,107.53 153.33,108.82 154.09,109.58 154.81,109.58 155.17,109.22 155.19,109.22 155.76,108.65 157.91,108.65 159.55,110.29 v2(159.55,110.45)
  BOTTOM w0.508: L502.2 v1(150.19,30.54)
  BOTTOM w1.27: L502.2 150.19,26.15 147.83,23.79 147.83,21.97 D504.1 148.97,20.83 R743.1
FAN6_LOCKD: length 220.3
  TOP w0.178: R51.1 165.1,22.24 J44.2 v1(165.1,25.69)
  LY3 w0.171: v1(73.9,79.25) 72.67,79.25 72.37,78.94 72.37,78.69 71.63,77.95 71.13,77.95 69.57,76.38 68.18,76.38 67.94,76.14 67.54,76.14 63.85,72.46 61.58,70.18 61.58,68.62 60.71,67.74 60.71,67.6 60.44,67.34 60.44,64.77 59.31,63.63 59.31,62.92 58.88,62.49 58.88,61.88 58.35,61.34 58.35,57.15 57.84,56.64 57.84,56.44 54.53,53.13 v1(54.53,49.96)
  BOTTOM w0.178: v1(165.1,25.69) 165.1,31.15 162.1,34.15 145.02,34.15 143.96,35.22 130.91,35.22 127.51,31.82 127.51,31.44 127.38,31.31 127.38,29.73 126.99,29.34 126.99,26.77 127.19,26.57 127.19,26.08 125.25,24.14 125.25,21.91 126.27,20.89 126.27,15.77 123.13,12.63 117.46,12.63 115.13,14.96 113.67,14.96 113.21,15.43 107.52,15.43 107.26,15.18 103.94,15.18 103.69,15.43 97.84,15.43 96.87,14.45 92.02,14.45 90.19,12.62 78.28,12.62 77.99,12.9 76.62,12.9 75.47,14.05 73.04,14.05 71.81,12.81 68.86,12.81 67.92,13.75 67.92,45.45 64.31,49.06 53.78,49.06 53.6,49.24 53.6,49.79 53.78,49.96 v1(54.53,49.96) ; R607.2 v1(73.9,79.25)
FAN6_SW: length 122.6
  LY3 w0.508: J4.3 185.61,119.2 182.52,116.11 182.52,110.21 183.65,109.09 183.65,91.47 175.45,83.27 175.45,67.6 175.85,67.19 177.28,67.19 178.62,65.85 178.62,64.86 179.77,63.71 179.77,61.74 180.18,61.33 180.18,57.1 180.82,56.46 180.82,56.09 180.02,55.29 179.41,55.29 178.5,54.38 178.5,53.66 175.5,50.66 174.2,50.66 172.83,49.29 172.83,47.14 172,46.31 172,43.89 172,43.88 172,38.88 162.25,29.13 v1(162.25,29.13)
  BOTTOM w0.508: L501.2 v1(162.25,29.13)
  BOTTOM w1.27: R742.1 161.04,20.83 D503.1 159.89,21.97 159.89,23.79 162.25,26.15 L501.2
FAN6_SW_JUMP: length 40.6
  TOP w0.203: U2.38 158.91,110.07 v2(158.5,110.49)
  LY3 w0.508: v2(158.5,110.49) 158.79,110.2 158.79,110.13 159.56,109.36 162.51,109.36 165.2,112.05 165.2,114.21 168.21,117.22 172.07,117.22 174.31,119.46 176.14,119.46 178.47,121.79 178.47,125.98 179.41,126.92 180.3,126.92 181.41,125.81 181.41,124.75 J4.2
FE_P1P2V: length 205.7
  TOP w0.254: J3.2 v1(87.49,112.4) 87.7,112.4 87.99,112.69 J3.4 ; J2.2 36.37,112.6 v1(36.58,112.39) 36.87,112.69 J2.4
  TOP w0.381: v1(87.49,112.4) 86.21,111.12 C12.1
  TOP w0.508: v1(36.58,112.39) 36.58,111.26 C9.1 ; v1(76.97,125.57) 76.97,125.83 78.05,126.91 78.05,127.47 80.35,129.76 81.41,129.76 81.51,129.86 82.14,129.86 82.24,129.76 86.52,129.76 86.65,129.9 87.87,129.9 87.96,129.82 88.24,129.54 108.35,129.54 v1(108.4,129.48)
  LY3 w0.508: v1(143.88,128.54) 143.88,127.15 146.98,124.05 146.98,99.68 147.95,98.71 147.95,88.13 146.84,87.02 145.15,87.02 144.56,86.43 J19.2
  LY4 w0.508: v1(36.58,112.39) 36.58,112.51 37.37,113.3 39.8,113.3 v1(40.67,112.44) ; v1(143.88,128.54) 143.25,127.91 143.25,126.39 140.44,123.58 136.05,123.58 135.81,123.82 135.18,123.82 134.63,123.27 130.1,123.27 123.34,130.03 121.98,130.03 121.43,129.48 v1(108.4,129.48)
  BOTTOM w0.508: v1(40.67,112.44) 40.67,115.42 41.31,116.07 45.29,116.07 45.94,115.42 52.46,115.42 52.48,115.44 53.21,115.44 53.96,114.69 53.96,114.58 54.47,114.07 58.82,114.07 60.95,116.2 67.82,116.2 70.23,118.62 70.69,118.62 73.75,121.68 73.75,122.11 73.75,122.11 73.75,124.04 74.8,125.09 76.45,125.09 76.93,125.57 ; 76.93,125.57 v1(76.97,125.57) ; 76.93,125.57 76.98,125.52 80.78,125.52 82.56,123.74 82.56,120.3 82.25,120 82.25,116 84.62,113.63 86.26,113.63 v1(87.49,112.4)
FE_RST: length 4.1
  TOP w0.178: U18.2 129.54,21.7 R48.2 129.55,24.09 J41.1
FIELD: length 172
  TOP w0.102: 107.63,72.17 v2(106.66,71.2)
  TOP w0.178: v1(126.59,26.33) 127.01,25.91 J41.3 ; U11.AF9 v2(106.66,71.2) ; v1(134.56,119.73) 134.56,118.37 134.04,117.85 133.4,117.85 132.23,116.68 132.23,103.09 126,96.85 126,90.02 124.15,88.17 124.15,87.49 121.21,84.55 121.21,75.03 121.54,74.69 v1(121.54,73.71) 121.13,73.3 120.02,73.3 108.76,73.3 107.63,72.17 ; J3.88 113.99,114.24 113.99,114.24 v1(113.99,115.21)
  LY3 w0.171: v1(121.54,73.71) 121.53,73.71 121.53,73.78 117.33,73.78 117.18,73.62 116.15,73.62 114.09,71.56 109.73,71.56 109.37,71.2 v2(106.66,71.2)
  BOTTOM w0.178: v1(121.54,73.71) 121.53,73.71 121.53,71.87 123.05,70.34 123.94,70.34 127.07,67.22 127.07,62.85 128.47,61.45 128.47,50.88 129.24,50.11 129.99,50.11 130.07,50.03 133.09,50.03 134.55,48.57 134.55,41.47 133.67,40.6 133.67,39.42 133.03,38.78 131.96,38.78 131.07,37.89 131,37.89 126.59,33.48 126.59,33.02 126.61,32.99 126.61,32.5 126.59,32.48 126.59,32.21 126.32,31.94 126.32,31.44 126.59,31.17 v1(126.59,26.33) ; v1(113.99,115.21) 117.92,115.21 118.89,114.24 120.47,114.24 120.77,114.53 121.82,114.53 121.85,114.56 123.13,114.56 124.54,115.97 125.84,115.97 126.54,116.67 127.47,116.67 128.45,117.65 129.19,117.65 129.33,117.79 131,117.79 131.14,117.65 131.85,117.65 132.35,118.14 132.35,119.08 133,119.73 v1(134.56,119.73)
FLASH_A19_A21: length 3.9
  TOP w0.178: U14.11 53.49,57.56 v1(53.07,57.14)
  BOTTOM w0.178: v1(53.07,57.14) 53.07,56.19 R702.2 R704.2
FLASH_A21_VPP: length 4.1
  TOP w0.178: U14.15 55.49,57.82 v1(54.91,57.24)
  BOTTOM w0.178: R701.2 R700.1 54.96,56.31 54.96,57.21 54.93,57.24 v1(54.91,57.24)
FLASH_CSSZ: length 4.2
  TOP w0.254: v1(60.49,80.6) U14.32
  BOTTOM w0.254: v1(60.49,80.6) 60.49,79.38 60.45,79.34 R609.2
FLASH_CSZ: length 31.9
  TOP w0.178: U11.E12 v2(84.66,74.2)
  BOTTOM w0.102: v2(84.66,74.2) 84.66,74.27 84.9,74.51 84.9,74.88 85.06,75.04 85.06,75.36 84.9,75.52 84.9,76.88 85.06,77.04 85.06,77.36 84.83,77.59 84.69,77.59 84.55,77.73 84.15,77.73 84.01,77.59 83.5,77.59 83.27,77.36 83.27,77.03 83.05,76.81 79.92,76.81 79.69,77.03
  BOTTOM w0.178: R609.1 60.45,76.97 61.56,75.86 65.81,75.86 66.78,76.82 68.29,76.82 68.4,76.71 68.61,76.5 69.03,76.09 70.36,76.09 70.36,76.08 75.12,76.08 75.12,76.09 78.34,76.09 79.28,77.03 79.69,77.03
FLASH_RSTZ: length 206.3
  TOP w0.178: v1(109.59,88.85) 109.59,89.23 108.52,90.3 104.76,90.3 104.76,90.29 104.26,90.29 104.26,90.3 102.44,90.3 102.36,90.21 101.86,90.21 101.77,90.3 98.17,90.3 97.11,91.36 83.71,91.36 82.68,92.39 79.89,92.39 79.02,93.26 79.02,93.51 79.44,93.94 79.44,100.29 79.88,100.73 80.08,100.73 80.43,101.08 80.43,101.09 80.43,101.28 80.81,101.65 83.22,101.65 84.66,103.09 84.66,106.21 84.14,106.73 83.94,106.73 83.94,106.73 82.6,106.73 82,106.13 75.2,106.13 74.63,106.7 68.76,106.7 66.32,109.13 62.74,109.13 59.96,111.91 56.92,111.91 55.71,113.12 55.71,114.94 56.07,115.29 56.07,115.82 55.68,116.21 29.97,116.21 27.09,113.34 27.09,106.93 v1(27.13,106.89) ; U14.14 55,61.34 54.8,61.53 54.8,63.18 v1(55.05,63.44)
  LY3 w0.171: v1(31.49,78.06) 29.38,78.06 28.91,78.53 28.91,79.62 28.65,79.88 28.65,82.1 28.41,82.34 28.41,84.18 27.86,84.72 27.86,87.08 27.25,87.69 27.25,88.96 28.21,89.92 28.21,90.17 28.42,90.39 28.42,94.61 28.68,94.86 28.68,98.26 29.12,98.71 29.12,99.41 30.25,100.54 30.25,100.6 30.84,101.19 32.15,101.19 32.73,100.62 35.85,100.62 36.74,101.51 36.74,102.38 36.86,102.5 36.86,103.26 35.31,104.81 35.31,105.54 34.53,106.32 27.7,106.32 v1(27.13,106.89)
  BOTTOM w0.178: R577.1 R578.1 v1(109.59,88.85) ; v1(55.05,63.44) 55.05,64.15 50.95,68.25 49.15,68.25 46.97,70.43 46.97,70.5 46.4,71.07 46.28,71.07 45.7,71.65 40.48,71.65 39.26,72.87 39.26,74.31 35.84,77.73 31.82,77.73 v1(31.49,78.06)
FREQ_SENSOR: length 9.1
  TOP w0.178: J30.2 122.56,38.51 122.08,38.99 120.13,38.99 119.62,38.48 118.53,38.48 117.13,37.08 117.13,36.3 J34.3
FSD12: length 12.4
  TOP w0.178: J9.3 v1(58.11,108.58)
  BOTTOM w0.178: R562.2 63.76,103.91 64.64,104.79 64.64,106.39 61.7,109.32 58.86,109.32 v1(58.11,108.58)
GPIO_09: length 34.5
  TOP w0.178: U11.B21 v2(81.66,84.2)
  LY4 w0.171: v1(68.95,82.38) 72.26,82.38 72.52,82.64 73.02,82.64 73.28,82.38 74.08,82.38 75.42,83.72 81.18,83.72 v2(81.66,84.2)
  BOTTOM w0.178: J14.2 60.76,97.13 60.76,95.15 64.08,91.82 64.08,89.3 68.95,84.43 v1(68.95,82.38)
GPIO_10: length 44.8
  TOP w0.178: U11.A22 v2(80.66,85.2)
  LY3 w0.171: v2(80.66,85.2) 80.26,85.2 78.98,86.47 78.98,86.5 72.77,92.71 72.77,92.94 70.48,95.23 66.7,95.23 65.93,96 65.93,100.68 64.78,101.83 64.78,102.46 64.4,102.85 63.76,102.85 63.25,102.33 63.25,95.63 62.32,94.7 59.31,94.7 58.13,95.89 58.13,97.23 J13.2
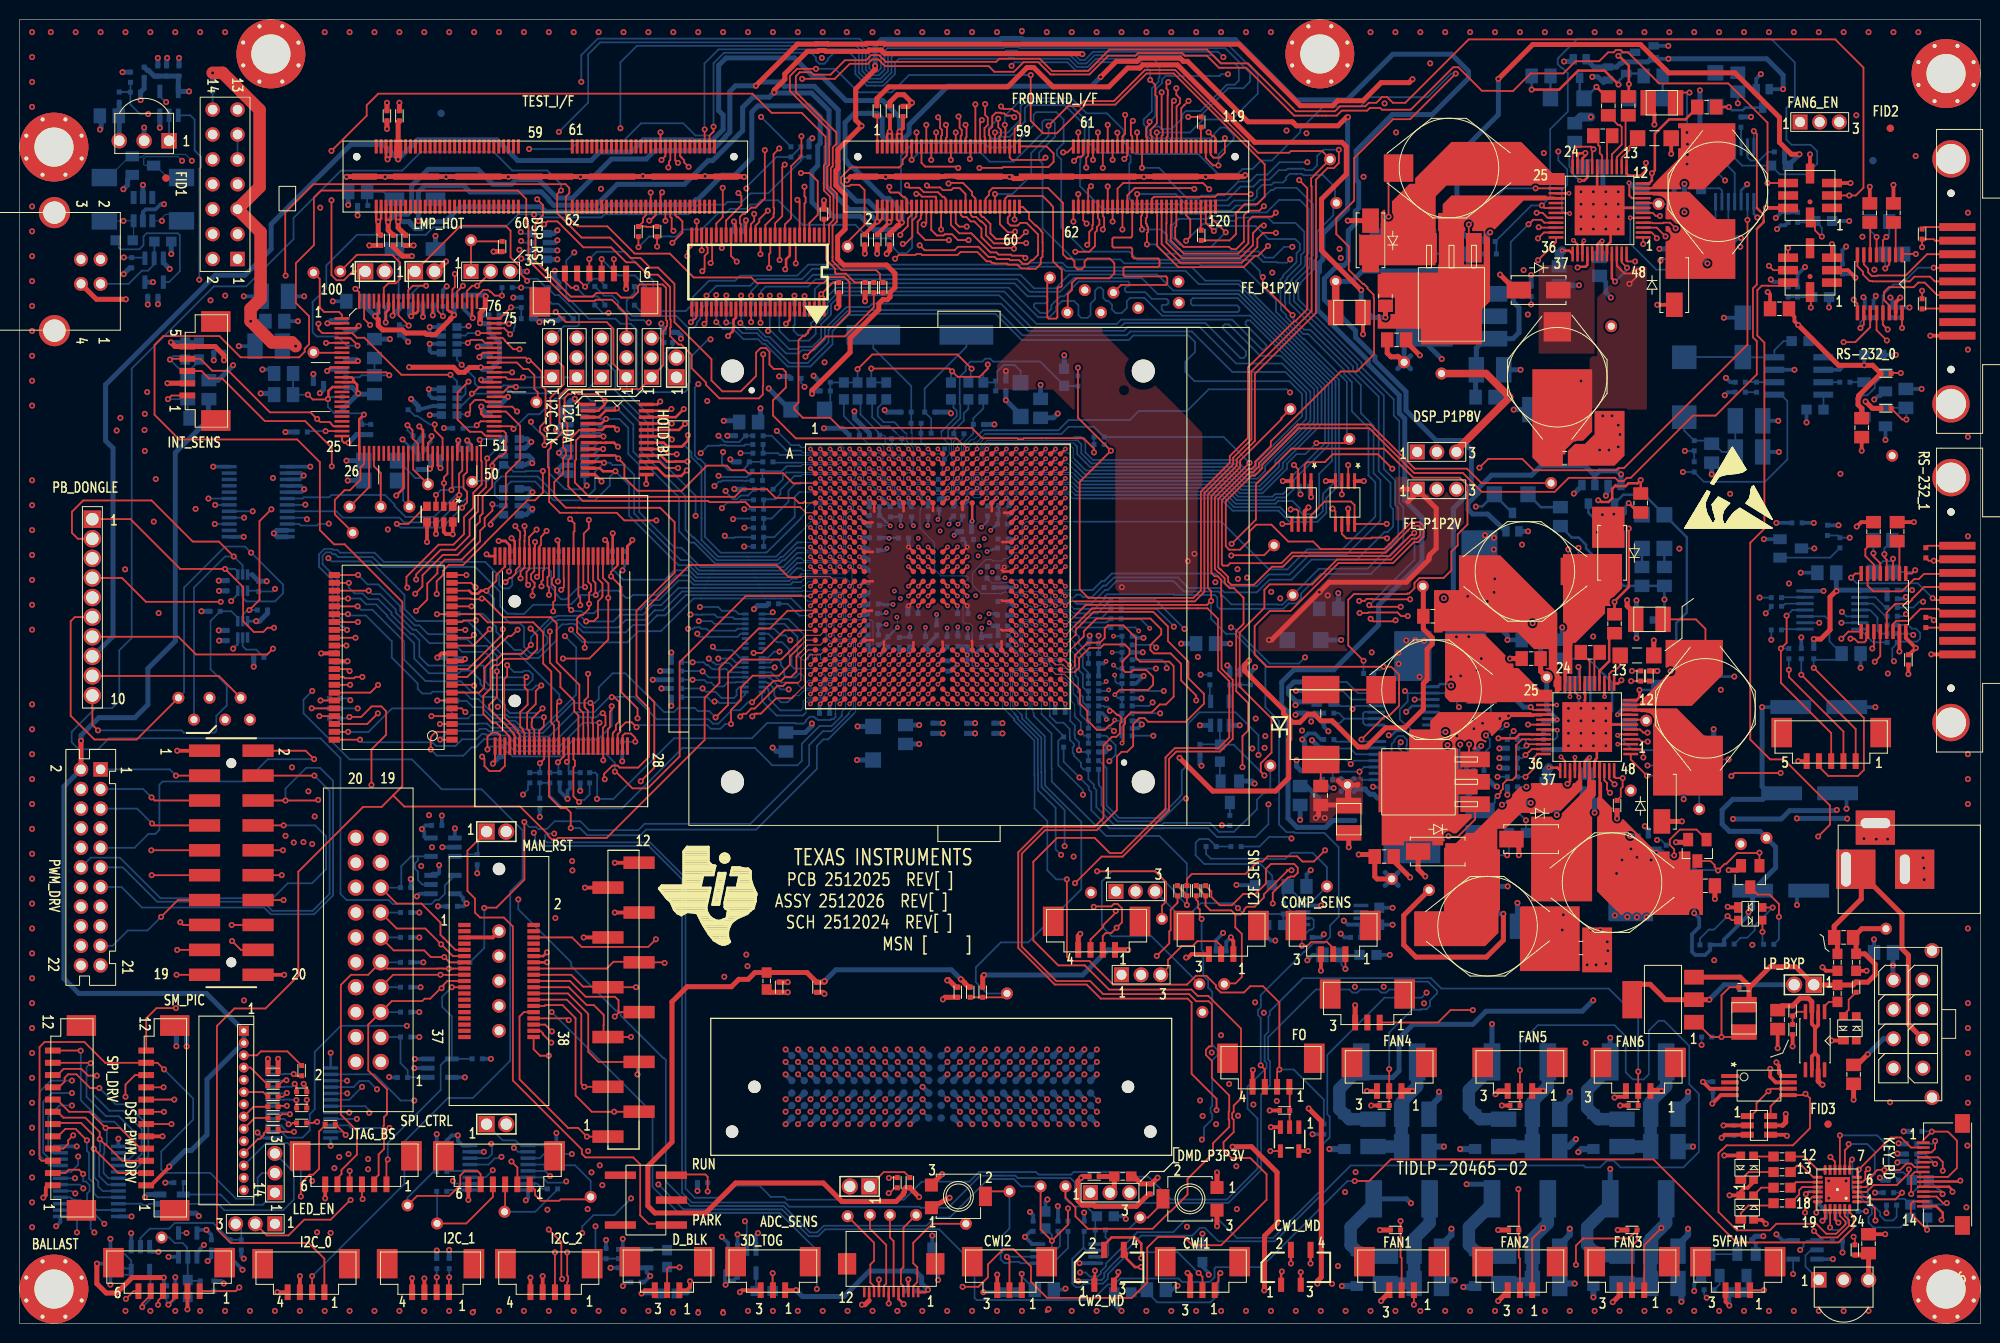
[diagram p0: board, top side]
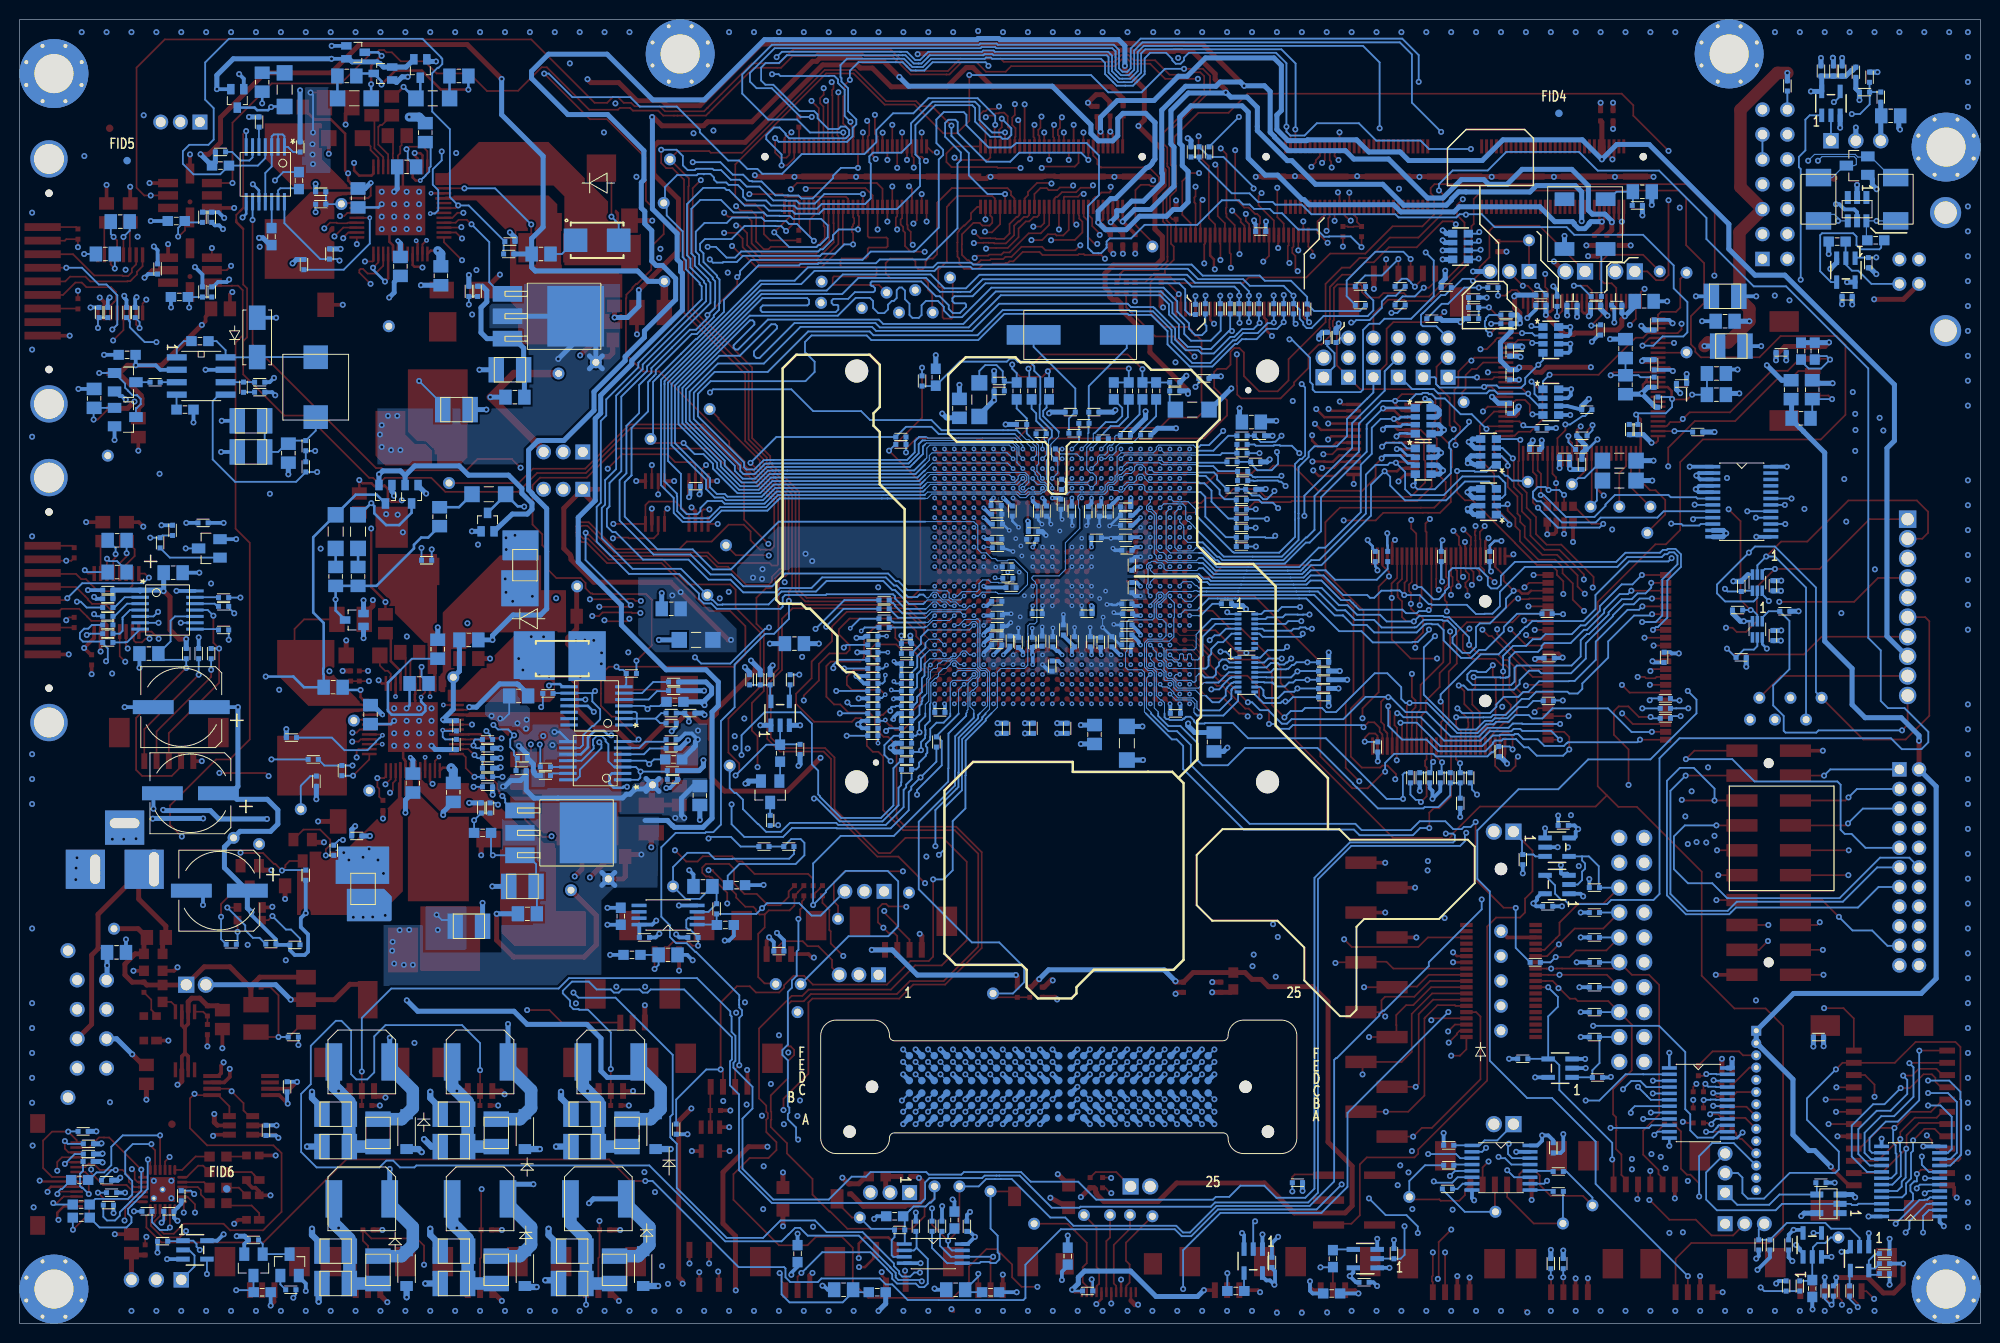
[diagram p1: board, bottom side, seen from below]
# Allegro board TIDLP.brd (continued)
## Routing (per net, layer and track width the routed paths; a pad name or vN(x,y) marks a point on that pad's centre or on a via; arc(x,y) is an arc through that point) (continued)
GPIO_12: length 56.2
  TOP w0.178: U11.B22 v2(81.66,85.2)
  LY3 w0.102: 81.53,90.17 81.53,89.92 82.06,89.39 82.06,85.61 81.66,85.22 v2(81.66,85.2)
  LY3 w0.171: 81.53,90.17 81.53,90.47 81.09,90.92 81.09,91 77.43,94.65 77.43,95.31 76.33,96.41 76.33,97.54 76.57,97.78 76.57,99.05 76.16,99.45 75.6,99.45 75.59,99.44 70.61,99.44 70.27,99.79 70.23,99.79 69.88,100.14 69.41,100.14 65.97,103.58 65.46,103.58 64.77,104.27 64.77,106.23 65.52,106.98 67.11,106.98 67.69,107.57 67.69,107.95 67.31,108.33 67.31,109.35 68.33,110.36 69.22,110.36 70.87,112.01 70.87,112.39 72.9,114.43 73.66,114.43 74.13,114.9 v1(74.13,115.77)
  BOTTOM w0.178: R545.1 78.68,119.01 R528.1 77.2,118.99 74.13,115.91 v1(74.13,115.77)
GPIO_13: length 58.8
  TOP w0.178: R529.1 R546.1 87.12,103.64 84.17,100.69 82.27,100.69 80.21,98.63 v1(80.16,98.63) ; U11.C21 v2(82.66,84.2)
  LY4 w0.171: v1(69.23,95.82) 69.23,97.58 71.57,99.92 78.06,99.92 79.35,98.63 v1(80.16,98.63)
  BOTTOM w0.102: v2(82.66,84.2) 82.28,83.82 81.84,83.82 81.83,83.81 81.5,83.81 81.49,83.82 80.8,83.82 80.04,83.06 80.04,82.54 79.69,82.19 79.69,82.12
  BOTTOM w0.178: v1(69.23,95.82) 68.87,95.47 68.87,88.53 69.22,88.18 69.4,88.18 69.9,87.67 69.9,82.77 69.9,82.77 69.9,81.98 69.9,81.98 69.9,80.23 71.51,78.62 76.12,78.62 76.2,78.7 76.27,78.7 79.69,82.12
GPIO_21: length 56.3
  TOP w0.178: U11.E20 v2(84.66,83.2)
  TOP w0.254: v1(59.62,87.8) 59.52,87.89 U8.10
  BOTTOM w0.102: v2(84.66,83.2) 84.06,82.59 84.06,78.97 83.73,78.64 83.34,78.64 83.06,78.36 83.06,78.04 82.83,77.81 79.97,77.81 79.69,78.08
  BOTTOM w0.178: 79.69,78.08 79.33,78.08 78.25,77.01 78.04,76.8 74.82,76.8 70.66,76.8 69.32,76.8 69.11,77 68.25,77.86 67.43,77.86 62.68,82.61 62.68,86.58 61.69,87.57 60.45,87.57 60.22,87.8 v1(59.62,87.8) 58.67,86.86 58.67,85.09 58.08,84.5 54.74,84.5 52.83,86.4 49.13,86.4 48.68,85.95 48.67,85.95 48.45,85.73 48.45,84.55 48.79,84.22 RN506.3
GPIO_23: length 54.9
  TOP w0.178: U11.E21 v2(84.66,84.2)
  TOP w0.254: v1(60.77,86.93) 59.5,86.93 59.19,87.24 U8.11
  BOTTOM w0.102: 79.69,77.56 79.73,77.6 82.91,77.6 83.11,77.81 83.83,77.81 84.06,78.04 84.06,78.3 84.26,78.51 84.26,82.45 84.62,82.81 84.83,82.81 85.06,83.04 85.06,83.36 84.66,83.76 v2(84.66,84.2)
  BOTTOM w0.178: RN506.4 50.11,85.88 52.58,85.88 54.49,83.96 58.69,83.96 60.2,85.47 60.2,86.36 v1(60.77,86.93) 62.16,85.54 62.16,82.4 67.22,77.34 68.27,77.34 68.76,76.86 68.96,76.65 69.17,76.44 70.51,76.44 70.51,76.44 74.97,76.44 74.97,76.44 78.19,76.44 78.4,76.65 78.6,76.86 79.31,77.56 79.69,77.56
GPIO_24: length 40.5
  TOP w0.178: v1(53.72,91.2) 54.14,91.62 54.14,94.43 55.47,95.77 55.47,97.58 54.53,98.52 J12.2 ; U11.B26 v2(81.66,89.2)
  LY4 w0.171: v1(53.72,91.2) 54.58,92.07 59.15,92.07 59.55,91.67 60.06,91.67 60.18,91.78 61.19,91.78 61.78,91.19 66.96,91.19 67.56,90.59 67.56,90.35 67.91,90 68.41,90 68.76,90.35 68.76,90.41 68.78,90.44 69.99,90.44 70.71,91.15 72.89,91.15 73.39,91.65 77.64,91.65 78.77,90.52 80.34,90.52 v2(81.66,89.2)
GPIO_26: length 122.7
  TOP w0.178: U11.D24 v2(83.66,87.2) ; v1(33.76,12.58) 33.73,12.58 31.72,10.58 29.02,10.58 27.42,8.97 25.23,8.97 J45.2
  LY3 w0.102: 79.69,83.28 79.98,83.28 80.01,83.25 81.06,83.25 81.5,82.81 84.01,82.81 84.27,83.07 84.27,83.36 84.5,83.59 84.69,83.59 85.06,83.96 85.06,84.63 85.23,84.8 85.23,85.32 85.71,85.81 85.83,85.81 86.06,86.04 86.06,86.36 85.61,86.81 84.06,86.81 v2(83.66,87.2)
  LY3 w0.171: v1(33.76,12.58) 35.34,14.16 35.58,14.16 36.77,15.35 36.77,18.13 35.06,19.84 35.06,21.76 35.37,22.07 37.41,22.07 37.67,22.34 38.84,22.34 40.46,23.95 41.08,23.95 43.66,26.53 43.66,30.71 45.95,33 45.95,33.52 46.28,33.85 46.28,36.2 46.33,36.25 46.33,39.22 49.68,42.57 50.82,42.57 50.9,42.65 51.11,42.65 51.46,43 51.46,43.21 52.44,44.19 52.44,45.16 52.44,45.16 52.44,46.6 52.43,46.61 52.43,47.86 54.04,49.47 54.04,49.56 53.75,49.85 53.75,50.69 54.14,51.08 54.14,53.24 57.48,56.59 57.48,61.71 58.82,63.05 58.82,64.35 60.09,65.62 60.09,67.49 60.35,67.75 60.35,67.89 61.23,68.76 61.23,70.33 61.27,70.37 62.33,71.44 64.63,73.73 64.63,74.9 66.22,76.5 67.72,76.5 68.14,76.92 69.6,76.92 70.99,78.3 71.23,78.3 72.53,79.6 73.41,79.6 73.65,79.84 74.43,79.84 77.86,83.28 79.69,83.28
GPIO_30: length 7.7
  TOP w0.178: U11.D25 v2(83.66,88.2)
  BOTTOM w0.102: v2(83.66,88.2) 83.27,87.81 79.69,87.81
  BOTTOM w0.178: 79.69,87.81 76.93,87.81 R796.2
GPIO_32: length 9.6
  TOP w0.178: U11.E24 v2(84.66,87.2)
  BOTTOM w0.102: 79.69,86.81 84.27,86.81 v2(84.66,87.2)
  BOTTOM w0.178: 79.69,86.81 78.17,86.81 77.85,86.49 77.85,86.09 R795.2
GPIO_33: length 9.4
  TOP w0.178: U11.D26 v2(83.66,89.2)
  BOTTOM w0.102: v2(83.66,89.2) 83.27,88.81 79.91,88.81 79.69,89.03
  BOTTOM w0.178: 79.69,89.03 78.23,89.03 76.71,90.55 R794.2
GPIO_40: length 136.5
  TOP w0.178: U11.T23 v2(96.66,86.2)
  BOTTOM w0.102: 107.63,84.15 107.41,84.15 106.96,84.6 99.91,84.6 99.91,84.6 99.41,84.6 99.41,84.6 98.3,84.6 97.94,84.24 97.36,84.24 97,84.6 96.42,84.6 96.4,84.62 95.83,84.62 95.64,84.81 95.5,84.81 95.27,85.04 95.27,85.36 95.5,85.59 96.19,85.59 96.66,86.07 v2(96.66,86.2)
  BOTTOM w0.178: 107.63,84.15 111.47,84.15 122.48,84.15 122.68,83.95 123.72,82.91 128.4,82.91 129.55,81.77 132.37,81.77 133.28,82.68 133.28,84.21 134.58,85.5 134.58,95.68 134.58,96.27 124.47,106.37 120.94,106.37 119.58,107.73 106.83,107.73 106.36,108.2 102.93,108.2 102.74,108.01 80.45,108.01 79.32,106.89 73.51,106.89 72.99,106.37 70.32,106.37 68.67,104.71 R559.1 67.94,103.27 63.31,103.27 R562.1
GPIO_41: length 138
  TOP w0.178: U11.R22 v2(95.66,85.2)
  BOTTOM w0.102: 107.63,84.56 107.39,84.81 99.83,84.81 98.18,84.81 97.95,84.57 97.38,84.57 97.14,84.81 96.5,84.81 96.48,84.82 95.91,84.82 95.81,84.93 95.81,85.06 v2(95.66,85.2)
  BOTTOM w0.178: R531.1 62.72,105.15 61.92,104.36 61.92,103.33 62.5,102.76 67,102.76 68.22,101.53 68.72,101.53 69.07,101.88 69.07,102.11 69.43,102.47 69.43,103.41 R558.1 70.04,104.82 v1(70.06,104.84) 71.07,105.85 74.52,105.85 75.19,106.52 79.79,106.52 80.85,107.58 102.82,107.58 103.03,107.79 106.26,107.79 106.68,107.37 118.92,107.37 120.28,106.02 124.33,106.02 134.22,96.12 134.22,95.83 134.22,95.83 134.22,85.91 132.97,84.65 132.97,84.39 132.93,84.35 132.93,82.87 132.2,82.14 129.68,82.14 128.55,83.27 123.87,83.27 123.04,84.1 122.63,84.51 111.91,84.51 107.69,84.51 107.63,84.56
GPIO_42: length 113.9
  TOP w0.178: U11.U26 v2(97.66,89.2)
  BOTTOM w0.102: 107.63,90.43 107.49,90.43 107.37,90.32 98.44,90.32 97.66,89.54 v2(97.66,89.2)
  BOTTOM w0.178: 107.63,90.43 108.25,90.43 108.7,89.98 108.7,88.85 109.47,88.08 123.1,88.08 123.4,88.08 123.77,88.08 123.79,88.06 124.1,88.06 125.06,87.11 125.86,87.11 126.1,87.35 126.1,87.83 130.81,92.54 130.81,94.83 129.52,96.12 119.85,96.12 118.91,97.06 118.91,98.11 119.89,99.09 119.89,100.11 119.22,100.78 113.59,100.78 113.13,100.31 102.22,100.31 99.54,102.99 86.99,102.99 86.87,102.87 84.57,102.87 82.91,101.22 82.91,99.88 80.65,97.61 78.33,97.61 76.02,99.93 75.8,99.93 75.32,100.4 74.91,100.4 73.83,100.4 72.77,101.46 71.74,101.46 v1(71.06,102.14) 71.06,102.15 R557.1
GPIO_43: length 127.5
  TOP w0.178: U11.U25 v2(97.66,88.2)
  LY4 w0.171: v1(64.17,102.1) 65.08,103.01 71.17,103.01 v1(72.07,102.11)
  BOTTOM w0.102: 107.63,90.08 98.69,90.08 98.07,89.45 98.07,88.6 v2(97.66,88.2)
  BOTTOM w0.178: R532.1 59.61,104.84 60.45,104.84 61.05,104.23 61.05,103.59 62.31,102.34 63.66,102.34 63.91,102.1 v1(64.17,102.1) ; 107.63,90.08 107.9,90.08 108.29,89.69 108.29,88.76 109.12,87.93 109.32,87.73 123.25,87.73 123.54,87.73 123.56,87.71 123.96,87.71 125.02,86.64 126.17,86.64 126.5,86.96 126.5,87.52 131.23,92.25 131.23,94.94 129.12,97.06 123.69,97.06 119.56,101.19 113.29,101.19 112.9,100.8 102.3,100.8 99.73,103.37 86.84,103.37 86.72,103.24 84.4,103.24 82.5,101.35 82.5,100.09 80.4,97.98 78.53,97.98 76.23,100.28 75.95,100.28 75.21,101.02 73.71,101.02 72.7,102.03 72.15,102.03 v1(72.07,102.11) R556.1
GPIO_44: length 127.8
  TOP w0.178: U11.U24 v2(97.66,87.2)
  LY4 w0.171: v1(73.52,102.06) 71.82,103.76 60.71,103.76 60.07,103.12 v1(60.07,103.09)
  BOTTOM w0.102: v2(97.66,87.2) 98.27,87.81 98.27,89.36 98.71,89.81 107.5,89.81 107.63,89.68
  BOTTOM w0.178: 107.63,89.68 107.86,89.45 107.86,88.69 108.76,87.79 109.18,87.37 123.4,87.37 123.42,87.35 123.81,87.35 124.99,86.17 126.24,86.17 127.05,86.98 127.05,87.49 131.66,92.1 131.66,95.04 128.78,97.92 124.08,97.92 120.35,101.66 113.05,101.66 112.64,101.25 102.87,101.25 100.1,104.02 86.97,104.02 86.63,103.68 86.49,103.68 86.48,103.67 85.99,103.67 85.98,103.68 84.36,103.68 84.27,103.6 84.25,103.6 82.15,101.49 82.15,101.47 82.14,101.46 82.14,100.36 81.05,99.27 79.78,99.27 79.45,98.94 78.19,98.94 76.5,100.64 76.09,100.64 75.83,100.9 75.3,101.43 74.15,101.43 v1(73.52,102.06) 73.6,102.14 R555.1 ; v1(60.07,103.09) 59.46,103.09 R563.1
GPIO_45: length 118.1
  TOP w0.178: U11.U23 v2(97.66,86.2)
  BOTTOM w0.102: 107.63,85.06 107.1,85.59 98.27,85.59 v2(97.66,86.2)
  BOTTOM w0.178: 107.63,85.06 107.83,84.86 122.78,84.86 123.39,84.25 124.02,83.62 128.09,83.62 128.37,83.9 129.83,83.9 130.56,83.17 130.56,82.86 130.87,82.55 131.96,82.55 132.55,83.15 132.55,86.67 133.87,87.98 133.87,95.97 124.48,105.36 117.67,105.36 116.03,107 107.07,107 105.65,105.59 103.47,105.59 102.09,106.97 80.92,106.97 80.11,106.16 75.48,106.16 74.61,105.29 v1(74.61,104.84) R554.1
GPIO_46: length 116
  TOP w0.178: U11.T22 v2(96.66,85.2)
  BOTTOM w0.102: 107.63,85.57 107.56,85.63 107.4,85.8 98.51,85.8 98.5,85.81 98.27,86.04 98.27,86.04 98.15,86.16 98.15,86.39 97.95,86.59 97.5,86.59 97.27,86.36 97.27,86.04 97.5,85.81 97.51,85.81 97.73,85.59 97.83,85.59 98.06,85.36 98.06,85.04 97.83,84.81 97.5,84.81 97.4,84.9 97.4,84.9 97.1,85.2 v2(96.66,85.2)
  BOTTOM w0.178: 107.63,85.57 107.77,85.43 107.98,85.22 122.92,85.22 123.75,84.39 124.16,83.98 127.95,83.98 128.22,84.25 129.11,84.25 129.98,85.13 129.98,86.05 133.51,89.58 133.51,95.83 124.33,105.01 117.82,105.01 116.09,105.01 114.45,106.65 107.53,106.65 106.12,105.23 104.33,105.23 103.05,105.23 101.77,106.51 81.18,106.51 80.43,105.76 76.09,105.76 75.6,105.28 v1(75.6,104.84) 75.6,104.05 R553.1
GPIO_47: length 116.8
  TOP w0.178: U11.V26 v2(98.66,89.2)
  BOTTOM w0.102: v2(98.66,89.2) 99.07,89.6 107.15,89.6 107.47,89.28 107.47,88.3 107.63,88.14
  BOTTOM w0.178: R552.1 76.52,101.41 v1(76.34,101.23) 76.65,101.23 78.48,99.4 79.36,99.4 79.58,99.62 80.85,99.62 81.75,100.53 81.75,101.91 82.77,102.92 82.77,103.21 82.77,103.96 83.68,104.88 99.92,104.88 103.19,101.6 112.26,101.6 112.7,102.04 120.97,102.04 124.53,98.48 124.85,98.48 125.1,98.74 125.1,99.15 122.75,101.5 122.75,101.74 122.92,101.92 123.33,101.92 126.54,98.71 128.61,98.71 132.04,95.28 132.04,91.98 128.08,88.02 128.08,87.51 126.36,85.79 124.87,85.79 123.66,87 123.18,87 123.17,87.01 122.88,87.01 122.58,87.01 121.7,87.01 108.76,87.01 107.63,88.14
GPIO_48: length 114.7
  TOP w0.178: U11.V25 v2(98.66,88.2)
  BOTTOM w0.102: 107.63,87.63 107.21,88.06 107.21,88.53 106.93,88.81 99.27,88.81 v2(98.66,88.2)
  BOTTOM w0.178: 107.63,87.63 108.61,86.65 121.85,86.65 122.73,86.65 123.02,86.65 123.04,86.64 123.51,86.64 124.75,85.4 126.48,85.4 128.49,87.41 128.49,87.92 132.4,91.83 132.4,95.43 125.5,102.32 125.23,102.32 125.06,102.15 125.06,101.9 127.17,99.78 127.17,99.53 126.99,99.35 126.73,99.35 123.67,102.4 112.36,102.4 111.92,101.96 103.73,101.96 100.43,105.27 83.57,105.27 82.41,104.11 82.41,103.07 81.21,101.86 81.21,100.94 80.52,100.25 78.5,100.25 77.49,101.26 77.49,102.94 R551.1
GPIO_49: length 114.4
  TOP w0.178: U11.V24 v2(98.66,87.2)
  BOTTOM w0.102: v2(98.66,87.2) 99.22,87.76 106.9,87.76 107.63,87.03
  BOTTOM w0.178: 107.63,87.03 107.73,86.93 107.78,86.93 108.41,86.3 121.99,86.3 122.88,86.3 122.89,86.28 123.07,86.28 123.37,86.28 124.61,85.04 126.62,85.04 128.85,87.27 128.85,87.77 132.8,91.73 132.8,95.53 125.53,102.8 116.53,102.8 114.72,104.62 113.27,104.62 112.94,104.3 112.94,103.59 112.41,103.06 111.8,103.06 111.43,103.44 111.43,103.92 111.04,104.31 110.83,104.31 110.54,104.6 110.54,105.41 110.28,105.67 110,105.67 109.69,105.36 109.69,104.48 109.23,104.02 109.23,102.87 108.93,102.58 108.29,102.58 108,102.86 108,103.86 107.55,104.31 106.33,104.31 105.73,103.7 105.73,103.34 105.04,102.65 103.89,102.65 100.87,105.66 83.31,105.66 81.92,104.27 81.92,103.23 80.72,102.02 80.72,101.46 80.07,100.81 79.4,100.81 78.95,101.26 78.95,101.77 79.06,101.88 R550.1
GPIO_50: length 125.3
  TOP w0.178: U11.V23 v2(98.66,86.2)
  BOTTOM w0.102: v2(98.66,86.2) 99.07,86.6 103.41,86.6 103.41,86.6 103.91,86.6 103.91,86.6 105.41,86.6 105.41,86.6 105.91,86.6 105.91,86.6 107.1,86.6 107.63,86.07
  BOTTOM w0.178: R549.1 80.68,102.92 81.11,103.35 81.11,105.49 81.72,106.1 101.48,106.1 102.8,104.78 104.66,104.78 104.86,104.58 104.86,104.28 104.64,104.06 103.58,104.06 103.45,103.94 103.45,103.71 104.09,103.08 104.81,103.08 105.23,103.49 105.23,103.86 106.14,104.78 106.52,104.78 108.04,106.29 113.07,106.29 113.2,106.17 113.2,105.91 113.09,105.81 112.95,105.81 112.75,105.61 112.75,105.36 112.91,105.2 114.81,105.2 115.49,104.51 117,104.51 117.17,104.34 117.17,104.09 116.99,103.9 116.58,103.9 116.49,103.81 116.49,103.43 116.75,103.17 124.24,103.17 124.42,103.34 124.42,103.63 124.2,103.85 119.65,103.85 119.47,104.02 119.47,104.4 119.66,104.59 124.24,104.59 133.15,95.68 133.15,89.8 129.58,86.22 129.58,85.31 128.88,84.61 128.07,84.61 127.8,84.33 124.31,84.33 124.1,84.54 123.07,85.57 108.13,85.57 107.92,85.78 107.63,86.07
GPIO_54: length 201.9
  TOP w0.178: U11.F26 v2(85.66,89.2)
  LY3 w0.171: v1(17.95,83.08) 17.95,83.74 18.94,84.73 19.01,84.73 19.01,84.74 19.75,84.74 20.54,83.95 20.54,81.34 16.3,77.11 16.3,67.58 14.75,66.03 14.75,63.15 14.99,62.91 14.99,60.82 16.91,58.9 16.91,41.93 18.21,40.64 18.21,33.49 15.39,30.68 15.39,23.29 15.18,23.08 15.18,22.27 16.37,21.08 16.37,19.36 13.96,16.94 13.96,15.04 9.34,10.43 9.34,9.85 9.06,9.56 8.39,9.56 7.79,10.16 6.74,10.16 5.85,9.27 v1(5.84,9.27) ; v1(57.85,85.47) 51.61,85.47 49.07,82.93 46.44,82.93 45.99,82.47 42.31,82.47 40.45,84.33 39.37,84.33 38.35,83.31 38.35,82.55 37.55,81.75 v1(37.55,80.99)
  LY4 w0.102: v2(85.66,89.2) 85.62,89.2 85.23,88.81 84.5,88.81 84.26,89.05 84.26,89.53 83.62,90.17
  LY4 w0.171: 83.62,90.17 83.62,90.18 82.64,91.16 82.64,91.56 82.29,91.91 81.89,91.91 81.57,92.24 78.79,92.24 78.28,92.74 74.49,92.74 73.78,93.46 71.35,93.46 70.6,92.7 69.65,92.7 68.13,94.22 66.7,94.22 66.28,94.64 63.58,94.64 63.48,94.54 60.62,94.54 60.36,94.79 58.63,94.79 58.35,95.08 55.26,95.08 52.17,91.98 v1(52.16,91.98) ; v1(17.95,83.08) 18.45,82.58 20.4,82.58 24.66,86.84 26.09,86.84 26.81,86.12 26.81,85.07 25.08,83.34 25.08,82.8 25.43,82.45 26.42,82.45 27.01,81.86 27.01,80.92 28.11,79.83 29.35,79.83 29.84,79.34 32.02,79.34 32.44,78.92 32.46,78.92 32.59,78.79 36.21,78.79 37.55,80.14 v1(37.55,80.99)
  BOTTOM w0.178: v1(57.85,85.47) 57.78,85.47 57.4,85.09 55.65,85.09 54.02,86.72 54.02,89.17 54.18,89.33 54.18,89.86 53.8,90.24 53.67,90.24 52.16,91.75 v1(52.16,91.98) ; v1(5.84,9.27) 5.84,10.96 5.25,11.55 U519.2
  BOTTOM w0.254: RN504.4 57.63,85.69 v1(57.85,85.47)
GPIO_60: length 16.9
  TOP w0.178: U11.H22 v2(87.66,85.2)
  BOTTOM w0.102: 79.69,85.79 79.7,85.8 84.82,85.8 85.23,86.21 85.23,86.38 85.48,86.63 85.84,86.63 86.09,86.38 86.09,86.02 86.32,85.8 87.07,85.8 v2(87.66,85.2)
  BOTTOM w0.178: 79.69,85.79 79.6,85.7 79.16,85.7 78.43,84.96 78.43,83.82 76.71,82.11 R596.1 R605.1
GPIO_61: length 16.2
  TOP w0.178: U11.H23 v2(87.66,86.2)
  BOTTOM w0.102: 79.69,86.45 79.84,86.6 84.96,86.6 85.15,86.79 85.15,87.24 85.5,87.59 86.05,87.59 86.27,87.37 86.27,87.04 86.61,86.7 87.16,86.7 v2(87.66,86.2)
  BOTTOM w0.178: 79.69,86.45 79.02,86.45 77.6,85.03 77.6,84.58 77.09,84.07 75.96,84.07 R594.1 R595.1
GPIO_62: length 14.2
  TOP w0.178: U11.H24 v2(87.66,87.2)
  BOTTOM w0.102: 79.69,87.45 79.84,87.6 83.51,87.6 83.71,87.8 87.07,87.8 v2(87.66,87.2)
  BOTTOM w0.178: 79.69,87.45 78.24,87.45 77.72,86.93 R592.1 R593.1
GPIO_63: length 13.7
  TOP w0.178: U11.H25 v2(87.66,88.2)
  BOTTOM w0.102: 79.69,88.59 79.72,88.57 80.48,88.57 80.5,88.59 87.27,88.59 v2(87.66,88.2)
  BOTTOM w0.178: 79.69,88.59 77.52,88.59 77.34,88.77 R591.1 R590.1
GPIO_65: length 18.6
  TOP w0.178: U11.J22 v2(88.66,85.2)
  BOTTOM w0.102: v2(88.66,85.2) 88.43,84.96 87.98,84.96 87.83,84.81 87.5,84.81 87.27,85.04 87.27,85.15 86.83,85.59 85.45,85.59 85.23,85.38 85.23,85 85.04,84.81 79.69,84.81
  BOTTOM w0.178: 79.69,84.81 79.54,84.81 79.06,84.32 79.06,82.3 76.96,80.2 R606.1 R607.1
GPIO_74: length 47.8
  TOP w0.178: U11.AE10 v2(105.66,72.2)
  LY3 w0.102: 106.94,68.8 104.45,68.8 104.27,68.98 104.27,70.36 104.5,70.59 106.11,70.59 106.29,70.77 106.29,71.02 106.27,71.04 106.27,71.4 106.08,71.59 102.56,71.59 102.27,71.89 102.27,72.36 102.5,72.59 104.83,72.59 105.22,72.2 v2(105.66,72.2)
  LY3 w0.171: v1(107.51,47.62) 107.6,47.53 107.85,47.53 108.62,48.31 108.62,51.78 106.59,53.81 106.59,59.07 106.59,59.28 106.8,59.49 106.8,59.87 108.19,61.26 108.19,67.55 106.94,68.8
  LY4 w0.171: J26.2 110.27,47.62 v1(107.51,47.62)
GPIO_75: length 48.6
  LY3 w0.171: J34.2 113.28,34.45 111.91,34.45 111.37,34.99 111.37,38.59 110.17,39.78 110.17,41.67 110.61,42.11 110.61,42.96 110.17,43.4 110.17,44.49 109.31,45.36 109.31,46.66 109.97,47.32 109.97,47.34 109.99,47.36 109.99,52.06 109.74,52.32 109.23,52.83 109.23,54.08 108.75,54.56 108.75,57.16 108.04,57.87 107.81,57.87 107.46,58.22 107.46,58.71 107.88,59.14 108.61,59.14 108.98,59.5 108.98,64.72 110.28,66.02 110.28,68.1 111.26,69.07 113.71,69.07 113.92,69.29 113.92,70.4 v2(114.15,70.63)
  BOTTOM w0.178: R625.1 113.79,70.99 v2(114.15,70.63)
GPIOX_11: length 4.1
  TOP w0.178: U20.12 183.42,15.65 182.05,17.02 R59.1
GPIOX_12: length 3.5
  TOP w0.178: R60.1 181.29,16.08 181.79,16.08 182.97,14.9 U20.13
GPIOX_13: length 3
  TOP w0.178: U20.14 181.19,14.4 R61.1
GPIOX_14: length 3.7
  TOP w0.178: U20.15 181.84,13.9 181.52,13.58 181.52,13.14 R62.1
GPIOX_INT: length 203.4
  TOP w0.178: U20.24 186.67,11.32 187.07,10.92 187.07,9.78 185.55,8.26 175.13,8.26 166.66,16.72 139.87,16.72 137.66,14.52 v1(136.18,14.52) ; U11.E3 v2(84.66,65.2)
  LY3 w0.102: 81.25,62.23 82.06,63.04 82.06,63.75 82.26,63.95 82.26,64.42 82.44,64.6 82.91,64.6 83.11,64.81 84.27,64.81 v2(84.66,65.2)
  LY3 w0.171: 81.25,62.23 81.1,62.08 81.1,61.74 81.4,61.44 81.4,60.86 80.29,59.75 80.29,52.67 78.49,50.87 78.49,44.02 76.94,42.46 76.94,37.73 73.14,33.93 73.14,28.89 73.08,28.83 73.08,28.29 66.54,21.76 66.54,18.82 65.15,17.43 v1(65.15,14.17)
  BOTTOM w0.178: v1(136.18,14.52) 135.44,14.52 126.66,5.73 122.02,5.73 121.88,5.6 121.88,4.71 121.39,4.21 118.59,4.21 118.22,4.58 112.26,4.58 111.65,3.98 111,3.98 109.41,2.38 106.25,2.38 106.24,2.37 97.62,2.37 97.41,2.59 97.41,5.98 93.79,9.6 82.17,9.6 81.46,8.89 80.5,8.89 77.77,11.62 67.7,11.62 v1(65.15,14.17)
GPIOX_RST: length 180.4
  TOP w0.178: U20.20 v1(184.67,9.78) ; U11.G22 v2(86.66,85.2)
  LY3 w0.171: v1(127.67,74.62) 127.67,73.82 128.06,73.42 128.06,57.61 128.42,57.25 128.42,55.82 129.69,54.54 131.79,54.54 132.4,53.94 132.4,53.93 135.33,51 135.96,51 138.44,48.52 138.44,48.06 140.8,45.69 140.8,44.65 143.16,42.3 143.16,35.65 144.11,34.7 144.11,32.81 143.86,32.56 143.86,32.4 143.51,32.05 143.35,32.05 142.66,31.36 142.66,23.23 135.2,15.76 v1(135.2,13.39)
  LY4 w0.102: v2(86.66,85.2) 86.66,84.76 87.06,84.36 87.06,84.04 86.98,83.96 86.98,82.08 88.51,80.54 88.87,80.54 89.14,80.28 89.14,79.91 90.26,78.79 96.64,78.79 96.78,78.66 96.85,78.66 97.12,78.39 97.12,78.01 97.12,78.01 97.5,77.63 97.5,76.51 98.72,75.28 100.83,75.28 101.14,75.59 106.83,75.59 107.43,74.99
  LY4 w0.171: v1(184.67,9.78) 184.67,11.42 183.75,12.33 144.77,12.33 143.71,13.39 v1(135.2,13.39) ; v1(127.67,74.62) 127.6,74.69 122.07,74.69 121.95,74.81 121.1,74.81 120.98,74.69 119.85,74.69 119.52,75.02 118.86,75.02 118.83,74.99 114.04,74.99 113.41,74.36 112.08,74.36 111.44,74.99 107.43,74.99
  BOTTOM w0.178: R755.1 186.49,10.32 185.69,9.53 184.91,9.53 184.67,9.77 v1(184.67,9.78)
GRN_LED_EN: length 187.8
  TOP w0.178: v1(53.54,89.6) 53.54,90.5 53.08,90.96 53.08,91.47 53.65,92.04 53.65,95.24 53.24,95.64 53.24,97.09 52.12,98.21 v1(51.92,98.21) 51.61,98.52 U7.67 ; U11.C25 v2(82.66,88.2)
  LY3 w0.171: v1(50.98,109.52) 51.89,109.52 52.89,108.53 52.89,104.07 51.82,103 51.82,101.2 50.11,99.5 50.11,99.09 50.71,98.49 51.64,98.49 v1(51.92,98.21) ; v1(6.49,13.77) 6.57,13.84 8.07,13.84 12.1,17.88 12.1,23.32 11.03,24.39 11.03,75.2 12.1,76.27 12.1,78.89 13.68,80.47 v1(13.68,81.79)
  LY4 w0.171: v1(13.68,81.79) 13.68,81.79 17.15,85.26 19.59,85.26 21.52,87.19 25.94,87.19 26.24,87.19 27.17,86.27 27.17,84.77 27.82,84.12 29.53,84.12 31.47,82.19 35.04,82.19 35.9,83.04 35.9,83.75 37.62,85.48 38.93,85.48 41.57,88.11 46.72,88.11 47.44,88.84 47.69,88.84 47.97,89.13 49.97,89.13 50.17,89.33 52.86,89.33 53.1,89.57 53.51,89.57 v1(53.54,89.6) 53.97,89.6 54.32,89.94 54.88,89.94 55.04,90.1 55.8,90.1 56.3,89.6 59.08,89.6 59.27,89.79 59.74,89.79 60.01,90.07 61.65,90.07 62.5,89.21 65.63,89.21 66.77,88.07 67.27,88.07 67.62,88.41 67.62,88.91 68,89.29 68.7,89.29 69.14,89.73 69.86,89.73 70.08,89.51 70.12,89.56 70.31,89.56 70.66,89.92 71.3,89.92 71.32,89.94 72.18,89.94 72.21,89.92 72.88,89.92 73.96,91 76.3,91 78.36,88.94 79.55,88.94 79.82,88.67 82.19,88.67 82.66,88.2 v2(82.66,88.2)
  BOTTOM w0.178: U519.6 6.17,14.15 6.49,13.83 v1(6.49,13.77) ; v1(50.98,109.52) 51.05,109.46 RN500.2
GRN_PWM: length 44
  TOP w0.178: U11.B20 v2(81.66,83.2)
  TOP w0.254: v1(60.92,93.34) 60.7,93.12 59.78,93.12 59.1,92.45 U8.3
  BOTTOM w0.102: v2(81.66,83.2) 81.69,83.2 82.16,82.73 82.16,79.14 81.83,78.81 80.31,78.81 79.99,79.13 79.84,79.13 79.69,79.13
  BOTTOM w0.178: 79.69,79.13 79.28,79.13 78.21,78.06 78,77.85 77.81,77.85 77.67,77.72 77.46,77.51 74.53,77.51 70.95,77.51 68.8,79.65 68.41,79.65 67.26,80.8 67.26,84.26 62.6,88.92 62.6,91.25 62.6,91.68 60.94,93.34 v1(60.92,93.34)
  BOTTOM w0.254: v1(60.92,93.34) 60.88,93.39 RN502.1
HBT_CLK_IN1: length 6.1
  TOP w0.178: J9.1 55.56,107.06 55.56,106.33 56.24,105.65 56.8,105.65 56.8,105.65 v1(56.77,105.65)
  BOTTOM w0.178: v1(56.77,105.65) 56.8,105.65 56.8,105.65 57.68,104.77 58.93,104.77 59.7,104 R563.2
HBT_DI1: length 4.4
  TOP w0.178: J9.2 56.86,106.58 v1(57.68,105.76)
  BOTTOM w0.178: v1(57.68,105.76) 58.07,106.15 58.07,106.18 58.27,106.38 58.3,106.38 58.49,106.57 59.02,106.57 59.7,105.88 R532.2
HDMI_CEC: length 47.4
  TOP w0.178: J3.13 90.49,119.13 90.07,118.71 90.07,118.27 89.73,117.93 89.69,117.92 85.36,117.92 85.32,117.93 84.8,117.93 83.78,116.91 83.78,116.36 84.13,116.01 84.63,116.01 84.77,116.15 85.64,116.15 86.18,115.61 86.18,112.05 84.45,110.32 TP7.1 ; U11.G23 v2(86.66,86.2)
  LY3 w0.102: 85.07,90.17 85.28,89.96 87.04,89.96 87.27,89.73 87.27,87.65 87.07,87.45 87.07,86.73 86.66,86.33 v2(86.66,86.2)
  LY3 w0.171: v1(82.1,98.04) 82.1,93.14 85.07,90.17
  LY4 w0.171: TP7.1 84.45,100.4 v1(82.1,98.04)
HDMI_HPD: length 200.3
  TOP w0.178: U20.10 185.17,16.51 v1(184.71,16.97) ; J3.90 114.49,113.9 114.49,113.03 114.39,112.93 114.39,112.02 114.49,111.92 v1(114.49,111.59)
  LY3 w0.171: v1(184.71,16.97) 183.13,18.54 183.13,24.86 183.2,24.93 183.21,24.93 186.58,28.3 186.58,36.99 184.41,39.15 184.38,39.15 183.73,39.81 183.73,40.34 183.73,40.34 183.73,41.47 183.73,41.47 183.73,48.52 184.66,49.46 184.66,55.11 188.06,58.51 188.06,61.34 186.37,63.03 186.37,66.64 184.55,68.45 182.42,68.45 181.14,69.73 181.14,71.64 181.27,71.77 181.27,74.18 184.43,77.34 184.43,79.5 183.84,80.09 179.49,80.09 178.27,81.3 178.27,81.95 183.93,87.6 183.93,88.42 185.52,90.01 185.52,97.37 187.52,99.37 187.52,100.78 185.66,102.64 185.66,103.73 185.5,103.88 185.5,106.27 187.97,108.74 v1(187.97,110.86) ; v1(129.82,109.82) 132.32,109.82 132.52,109.62 v1(134.64,109.62)
  LY4 w0.171: v1(187.97,110.86) 184.77,110.86 183.92,110.01 181.81,110.01 181.21,110.6 179,110.6 177.57,109.17 177.5,109.17 176.29,107.96 176.17,107.96 173.38,105.17 172.88,104.67 165.11,104.67 164.88,104.44 163.54,104.44 163.44,104.53 162.96,104.05 157.02,104.05 155.89,105.18 140.14,105.18 135.71,109.62 v1(134.64,109.62)
  BOTTOM w0.178: v1(114.49,111.59) 116.45,111.59 117.05,111 117.05,110.59 118.07,109.57 118.32,109.57 118.54,109.35 126.4,109.35 127.02,108.73 127.89,108.73 128.98,109.82 v1(129.82,109.82)
HDMI_INT: length 169.3
  TOP w0.178: J3.91 114.99,120.07 114.99,120.96 114.9,121.04 114.9,121.94 115.26,122.3 v1(115.26,122.57) ; U11.AB13 v2(102.66,75.2) ; v1(107.65,44.9) 110.36,47.62 112.52,47.62 117.24,52.34 117.24,57.58 117.99,58.33 122.44,58.33 123.74,59.63 123.74,65.66 122.6,66.8 122.6,74.16 122.56,74.2 122.56,75.86 122.21,76.21 121.9,76.21 121.56,76.55 121.56,84.41 124.5,87.35 124.5,87.64 124.5,88.03 128.71,92.24 128.71,92.36 TP20.1
  LY3 w0.171: TP20.1 128.65,94.23 128.65,96.28 128.79,96.41 128.79,96.91 128.65,97.04 128.65,104.05 129.97,105.36 130.54,105.94 130.54,106.7 128.96,108.29 128.96,110.27 131.12,112.43 131.12,116.97 130.58,117.51 130.58,118.62 131.08,119.12 131.08,119.75 132.01,120.69 132.01,122.16 131.19,122.98 127.71,122.98 v1(123.25,127.43) ; v2(102.66,75.2) 102.66,75.08 102.24,74.66 101.37,74.66 101.05,74.34 101.05,68.59 101.13,68.51 101.13,67 101.42,66.71 105.4,66.71 106.22,65.89 106.22,62.89 105.94,62.61 105.94,59.85 105.73,59.64 105.73,59.43 105.52,59.22 105.52,48.54 105.2,48.22 105.2,47.37 105.52,47.05 105.52,44.76 108.65,41.63 109.54,41.63 109.8,41.9 109.81,41.9 110.16,42.25 110.16,42.25 110.18,42.28 110.18,42.78 109.87,43.09 108.73,43.09 108.24,43.59 108.24,44.28 107.61,44.9 v1(107.65,44.9)
  BOTTOM w0.178: v1(123.25,127.43) 122.58,127.43 122.4,127.25 117.45,127.25 117.43,127.27 116.9,127.27 116.53,126.89 116.53,126.53 115.85,125.85 115.85,123.16 v1(115.26,122.57)
HOLD_BOOTZ: length 30.3
  TOP w0.178: U11.F24 v2(85.66,87.2)
  LY4 w0.102: 85.22,90.17 85.8,89.59 85.83,89.59 86.06,89.36 86.06,89.04 85.99,88.97 85.99,88.43 86.06,88.36 86.06,88.04 85.66,87.64 v2(85.66,87.2)
  LY4 w0.171: J17.1 68.33,95.18 68.33,95.03 68.43,94.93 69.95,93.42 70.3,93.42 71.06,94.17 72.86,94.17 73.02,94.33 77.92,94.33 78.78,93.46 79.15,93.1 82.3,93.1 85.22,90.17
  BOTTOM w0.178: J17.1 65.88,97.63 65.88,98.98 66.61,99.71 R560.2
I2C_BUSY: length 107.4
  TOP w0.178: v1(106.82,45.29) 106.82,37.41 107.27,36.96 109.13,36.96 111.53,34.56 119.08,34.56 119.98,35.46 121.05,35.46 122.02,34.49 122.02,34.25 122.52,33.76 124.89,33.76 125.52,34.39 126.83,34.39 128.5,32.73 v1(128.5,25.9) 128.26,25.66 J41.2 ; U11.G24 v2(86.66,87.2)
  BOTTOM w0.102: 100.88,62.23 100.27,62.84 100.27,66.46 99.93,66.81 97.5,66.81 97.17,67.14 97.17,69.29 97.16,69.29 97.16,69.65 97.17,69.65 97.17,70.33 97.16,70.33 97.16,71.15 96.95,71.37 96.45,71.37 96.24,71.57 96.24,75.34 96.38,75.48 96.38,75.6 96.75,75.96 96.75,76.11 96.6,76.25 93.98,76.25 93.33,76.9 93.33,79.63 92.37,80.59 91.86,81.09 91.86,81.14 91.86,81.14 91.86,82.99 91.88,83 91.88,83.03 91.92,83.13 91.99,83.22 92,83.24 92,83.98 92.06,84.04 92.06,84.36 92,84.42 92,84.43 91.83,84.59 89.33,84.59 89.06,84.86 89.06,85.36 88.83,85.59 88.37,85.59 88.06,85.9 88.06,86.36 87.83,86.59 87.66,86.59 87.06,87.2 v2(86.66,87.2)
  BOTTOM w0.178: R745.2 133.03,20.4 133.03,20.4 133.03,22.83 129.96,25.9 v1(128.5,25.9) ; 100.88,62.23 101.45,61.66 101.45,61.5 103.5,59.45 103.5,55.91 103.53,55.89 103.53,52.54 104.83,51.24 104.83,46.21 105.75,45.29 v1(106.82,45.29)
ICE_RSTZ: length 23.8
  TOP w0.178: J32.9 44.46,38.1 43.64,38.92 43.64,38.93 43.26,39.3 43.25,39.3 42.93,39.63 42.93,40.88 40.99,42.82 38.46,42.82 J28.15
  BOTTOM w0.178: U513.2 41.07,44.77 40.63,45.21 40.63,46.08 40.32,46.38 40.32,46.92 40.63,47.22 40.63,47.64 ; J28.15 R712.1 38.93,44.53 38.93,46.63 39.93,47.64 40.63,47.64 ; 40.63,47.64 U514.4
ICTSEN: length 24.2
  TOP w0.178: U11.M24 v2(91.66,87.2)
  LY3 w0.102: 91.07,90.17 91.27,89.97 91.27,87.59 v2(91.66,87.2)
  LY3 w0.171: 91.07,90.17 90.93,90.32 86.21,90.32 82.7,93.83 82.7,98.42 82.48,98.64 81.86,98.64 80.06,96.84 v1(80.06,95.54)
  BOTTOM w0.178: v1(80.06,95.54) 80.06,95.6 79.71,95.95 R597.1
INDEX1_SENSE_INPUT: length 24.8
  TOP w0.178: v1(120.26,5.14) 120.65,4.75 J62.2
  BOTTOM w0.178: 108.51,7.71 108.51,9.31 R764.1 ; 108.51,7.71 107.37,6.57 107.37,4.06 107.73,3.69 108.23,3.69 108.59,4.06 110.5,4.06 111,4.55 111,5.01 111.53,5.54 111.53,5.58 113.21,7.25 118.13,7.25 119.81,5.58 120.24,5.14 v1(120.26,5.14) ; 108.51,7.71 108.78,7.44 U521.2
INDEX2_SENSE_INPUT: length 11
  TOP w0.178: J60.2 100.97,6.53 v1(100.7,6.79)
  BOTTOM w0.178: R766.1 105.92,9.28 106.12,9.08 106.12,7.92 104.99,6.79 U521.6 103.84,6.79 v1(100.7,6.79)
IR0: length 121
  TOP w0.178: U11.C26 v2(82.66,89.2)
  LY3 w0.171: v1(13.01,95.01) 9.61,98.4 9.61,109.02 11.67,111.07 11.67,122.99 13.28,124.59 v1(14.94,124.59)
  LY4 w0.171: v2(82.66,89.2) 80.91,90.95 79.46,90.95 78.85,90.95 77.78,92.02 73.82,92.02 73.12,92.72 71.62,92.72 70.89,91.99 68.5,91.99 67.93,92.56 66.44,92.56 66.27,92.38 60.54,92.38 60.06,92.86 54.45,92.86 53.19,91.6 53.19,91.48 52.66,90.95 51.65,90.95 51.12,90.42 48.15,90.42 47.28,89.55 47.15,89.55 47.13,89.54 46.52,89.54 46.25,89.8 46.25,90.33 45.9,90.68 45.33,90.68 42.28,93.73 41.47,93.73 39.15,96.04 37.45,96.04 37.25,96.24 28.64,96.24 24.59,100.29 21.83,100.29 21.54,100.29 20.33,101.5 13.6,101.5 13.01,100.91 v1(13.01,95.01)
  BOTTOM w0.178: U500.4 14.3,125.18 14.89,124.59 v1(14.94,124.59)
IR1: length 272.4
  TOP w0.178: U11.E23 v2(84.66,86.2)
  LY3 w0.171: v1(42.06,48.57) 42.96,49.47 42.96,50.14 46.1,53.28 47.06,53.28 49.61,55.83 49.61,60.88 48.13,62.36 48.13,64.01 51.56,67.44 53.59,67.44 54.83,68.67 55.53,68.67 56.57,69.71 56.57,69.76 57.19,70.38 57.19,71.17 56.98,71.38 56.98,72.16 57.39,72.56 58.09,72.56 59.36,73.84 59.36,74.54 58.66,75.25 58.66,76.89 59.64,77.86 60,77.86 60.71,78.57 61.89,78.57 62.67,79.34 62.77,79.34 63.41,79.34 65.69,81.62 65.69,82.58 67.82,84.71 68.71,84.71 70.59,86.6 70.59,86.81 71.15,87.37 71.15,89.15 71.5,89.49 74.66,89.49 80.41,83.75 83.86,83.75 84.12,84.01 84.12,85.66 v2(84.66,86.2) ; v1(53.84,11.6) 54.23,11.99 54.23,13.12 54.54,13.44 56.17,13.44 56.78,14.05 56.78,14.9 56.18,15.51 55.6,15.51 54.97,16.14 53.89,16.14 52.95,17.08 52.95,20.13 50.79,22.3 50.35,22.3 50,22.65 50,26.96 51.67,28.63 51.67,33.1 54.74,36.17 54.74,38.24 54.53,38.44 54.53,40.12 55.24,40.83 55.24,41.6 54.92,41.92 54.92,42.72 55.23,43.03 55.23,45.05 v1(56.38,46.21)
  LY4 w0.171: v1(180.9,5.03) 180.15,5.78 159.4,5.78 159,5.38 151.59,5.38 150.96,6.01 145.14,6.01 142.65,8.5 122.58,8.5 121.2,7.12 116.8,7.12 115.09,5.41 114.89,5.41 114.63,5.15 114.14,5.15 113.79,5.49 113.79,5.65 112.31,7.12 104.75,7.12 104.35,7.52 92.68,7.52 92.19,8.01 91.44,8.75 85.74,8.75 85.74,8.76 81.59,8.76 78.71,11.63 59.42,11.63 58.84,11.05 56.67,11.05 56.13,11.6 v1(53.84,11.6) ; v1(56.38,46.21) 53.9,46.21 51.57,48.53 47.88,48.53 47.33,47.98 42.65,47.98 v1(42.06,48.57)
  BOTTOM w0.178: U520.4 v1(180.9,5.03)
KEYPD_DOWN: length 14
  TOP w0.178: J52.4 195.68,16.94 196.16,16.46 v1(196.16,15.57) ; v1(192.02,13.33) 191.33,12.64 188.92,12.64 188.66,12.9 U20.2
  LY4 w0.171: v1(196.16,15.57) 195.88,15.29 193.9,15.29 192.79,14.19 192.79,14.11 v1(192.02,13.33)
  BOTTOM w0.178: R741.1 191.97,13.33 191.97,13.33 v1(192.02,13.33)
KEYPD_LED_HOT: length 13.9
  TOP w0.178: U20.9 v1(185.67,19.18)
  BOTTOM w0.178: R739.2 192.92,14.63 192.15,15.4 191.38,15.4 190.65,16.13 190.65,18.01 189.48,19.18 v1(185.67,19.18)
KEYPD_LED_LMP: length 15.2
  TOP w0.178: U20.8 186.18,15.66 186.18,17.65 186.56,18.03 v1(186.56,18.29)
  BOTTOM w0.178: R738.2 192.28,12.7 188.95,12.7 188.52,13.13 188.52,14.53 189.23,15.24 189.23,17.53 188.47,18.29 v1(186.56,18.29)
KEYPD_LED_PWR: length 13.5
  TOP w0.178: v1(186.92,16.71) 186.67,16.46 U20.7
  BOTTOM w0.178: v1(186.92,16.71) 186.94,16.69 186.94,13.72 187.24,13.42 187.24,13.37 188.58,12.03 188.59,12.03 188.94,11.68 188.94,11.18 188.59,10.84 188.59,10.29 189.1,9.78 191.84,9.78 R737.2
KEYPD_LEFT: length 13
  TOP w0.178: J52.5 195.07,16.44 195.24,16.27 v1(195.39,16.27) ; U20.3 188.39,13.4 189.1,14.11 191.48,14.11 192.71,15.34 v1(192.71,15.7)
  LY4 w0.171: v1(195.39,16.27) 195.35,16.27 195.35,16.29 195.1,16.05 193.06,16.05 v1(192.71,15.7)
  BOTTOM w0.178: R736.1 194.38,17.27 v1(195.39,16.27)
KEYPD_PWR: length 82.8
  TOP w0.178: U20.1 188.56,12.4 189.24,11.72 189.24,10.56 v1(189.3,10.49) ; v1(192.95,13.19) 192.95,15.08 193.31,15.44 J52.7
  LY3 w0.171: v1(194.16,73.62) 193.87,73.33 193.87,70.97 194.46,70.38 194.46,68.83 193.98,68.35 193.98,55.81 197.11,52.68 197.11,19.44 196.39,18.72 196.39,18.71 193.57,15.9 193.57,13.82 v1(192.95,13.19) 192.16,12.4 190.02,12.4 189.3,11.68 v1(189.3,10.49)
  BOTTOM w0.178: R735.1 193.54,15.56 193.84,15.26 193.84,14 193.67,13.83 193.58,13.83 v1(192.95,13.19) ; v1(194.16,73.62) 193.76,73.62 193.17,73.03 R612.1
KEYPD_RIGHT: length 10.1
  TOP w0.178: J52.6 193.31,15.94 193.31,15.94 192.96,16.29 192.46,16.29 191.81,15.64 v1(190.21,15.64) 190.19,15.66 189.51,15.66 188.92,15.07 188.86,15.01 188.86,14.45 188.31,13.9 U20.4
  BOTTOM w0.178: v1(190.21,15.64) 190.62,15.64 R740.1
KEYPD_SEL: length 18.1
  TOP w0.178: J52.2 192.92,17.94 191.9,18.96 191.41,18.96 191.4,18.95 190.86,18.95 v1(187.59,15.68) 187.42,15.51 U20.6
  BOTTOM w0.178: R754.1 191.47,10.87 191.09,10.49 190.27,10.49 189.78,10.99 189.78,11.33 189.29,11.82 189.29,11.82 188.74,12.38 188.73,12.38 187.59,13.52 v1(187.59,15.68)
KEYPD_UP: length 15.1
  TOP w0.178: J52.3 195.01,17.44 195.39,17.82 v1(195.39,18.59) ; U20.5 187.42,14.41 187.98,14.41 188.26,14.7 188.26,15.44 v1(188.55,15.73)
  LY4 w0.171: v1(188.55,15.73) 190.17,17.35 190.17,18.08 191.06,18.97 194.9,18.97 195.33,18.55 195.33,18.59 v1(195.39,18.59)
  BOTTOM w0.178: R752.1 195.11,18.31 v1(195.39,18.59)
LAMPLITZ: length 59.9
  TOP w0.178: J53.1 22.03,3.28 v1(22.41,3.66) ; J39.10 11.77,25.33 10.79,24.35 v1(10.79,23.11) ; J38.4 4.46,17.83 4.95,18.33 4.95,18.67 v1(5.46,19.18)
  LY3 w0.171: v1(10.79,23.11) 11.67,22.24 11.67,18.06 9.98,16.36 7.57,16.36 ; v1(5.46,19.18) 5.46,18.54 5.23,18.3 5.23,16.74 5.6,16.36 7.57,16.36 ; 7.57,16.36 7.57,15.19 7.02,14.64 6.33,14.64 5.89,14.21 5.74,14.21 4.99,13.46 4.99,9.04 5.63,8.4 8.03,8.4 12.37,4.06 16.98,4.06 18.31,5.4 19.57,5.4 19.61,5.44 20.61,5.44 22.39,3.66 v1(22.41,3.66)
  BOTTOM w0.178: R784.1 R783.1 22.04,3.29 v1(22.41,3.66)
LAMPLITZ_FLTR: length 7.7
  BOTTOM w0.178: TP71.1 15.25,8.76 15.81,8.2 16.63,8.2 17.08,7.75 17.08,6.85 U524.2 C708.2 17.23,4.33 R784.2
LED1_GRN: length 3.7
  TOP w0.178: D11.1 176.08,15.14 176.08,15.16 176.35,15.43 R60.2
LED1_RED: length 2.1
  TOP w0.178: D11.4 176.97,17.02 R59.2
LED2_GRN: length 4.4
  TOP w0.178: D12.1 175.56,11.24 176.34,12.02 178.67,12.02 R62.2
LED2_RED: length 2.4
  TOP w0.178: D12.4 177.64,13.84 R61.2
LED4_PWM: length 40.2
  TOP w0.102: 79.69,83.2 80.19,82.7 U11.A20
  TOP w0.178: 79.69,83.2 79.62,83.27 74.51,83.27 74.51,83.31 74.03,83.78 70.35,83.78 70.24,83.9 57.44,83.9 55.96,85.38 55.96,88.06 56.23,88.33 56.23,90.29 57.08,91.15 U8.5
  TOP w0.254: U8.5 59.42,91.15 59.77,91.5 60.63,91.5 v1(60.94,91.19)
  BOTTOM w0.254: RN502.3 58.43,91.68 58.45,91.69 58.93,91.69 59.12,91.5 60.63,91.5 v1(60.94,91.19)
LED5_PWM: length 35.6
  TOP w0.102: 80.06,83.83 80.19,83.7 U11.A21
  TOP w0.178: 80.06,83.83 79.91,83.68 79.5,83.68 78.98,84.2 77.12,84.2 76.22,85.1 73.73,85.1 72.95,84.32 58.09,84.32 56.63,85.78 56.63,88 56.75,88.12 56.75,90.08 57.17,90.49 58,90.49 U8.6
  TOP w0.254: v1(59.55,90.48) 59.54,90.5 U8.6
  BOTTOM w0.254: RN502.4 58.43,90.76 58.48,90.81 59.2,90.81 59.55,90.45 v1(59.55,90.48)
LED6_PWM: length 31.6
  TOP w0.254: U8.7 59.26,89.84 59.28,89.83 59.79,89.83 59.8,89.82 59.82,89.82 59.84,89.84 60.62,89.84 v1(61.03,89.43)
  LY3 w0.171: J14.3 58.33,100.52 57.16,101.69 53.96,101.69 53.14,100.86 53.14,95.25 56.27,92.12 56.27,90.7 58.45,88.53 59.87,88.53 60.77,89.43 v1(61.03,89.43)
  BOTTOM w0.178: v1(61.03,89.43) 60.63,89.84 59.26,89.84 59.25,89.84 59.05,89.84 58.47,89.26 RN504.1
LED7_PWM: length 17.3
  TOP w0.254: U8.8 v1(59.52,89.19)
  LY3 w0.171: J13.3 55.64,99.33 55.64,95.88 56.6,94.92 56.88,94.92 57.23,94.57 57.23,94.3 57.32,94.21 57.32,91.4 v1(59.52,89.19)
  BOTTOM w0.254: RN504.2 57.82,88.54 58.47,88.54 59.13,89.19 v1(59.52,89.19)
LED8_PWM: length 31.3
  TOP w0.102: U11.A23 79.69,85.7
  TOP w0.178: 61.07,88.22 60.75,88.54 60.49,88.54 ; 61.07,88.22 v1(61.07,88.23) ; 61.07,88.22 61.07,88.22 61.68,87.6 61.68,86.28 63.03,84.94 67.54,84.94 70.11,87.5 72.14,87.5 72.58,87.06 72.58,87.03 74.01,87.03 74.32,86.72 77.87,86.72 78.89,85.7 79.69,85.7
  TOP w0.254: U8.9 60.49,88.54
  BOTTOM w0.254: v1(61.07,88.23) 61.07,88.22 60.75,88.54 59.2,88.54 58.39,87.74 57.82,87.74 RN504.3
LED_DIR: length 15.5
  TOP w0.178: J49.5 47.02,15.22 46.72,15.52 45.38,15.52 44.95,15.09 44.95,14.12 43.83,13 40.54,13 TP58.1
  BOTTOM w0.178: TP58.1 39.57,12.84 42.23,15.49 R749.2
LED_DOUT: length 9.2
  TOP w0.178: TP60.1 49.52,11.44 J49.3
  BOTTOM w0.178: R746.2 54.88,13.67 52.59,11.38 TP60.1
LED_DRV_DIR: length 140
  TOP w0.178: v1(39.54,75.07) 39.45,75.15 39.45,76.15 42.74,79.44 44.24,79.44 45.33,80.52 45.33,82.25 46.27,83.2 46.27,84.74 47.13,85.6 47.13,87.94 47.07,88 47.07,89.99 v1(46.93,90.13) ; U7.6 v1(31.25,100.02)
  LY3 w0.171: v1(46.93,90.13) 46.93,90.93 47.26,91.26 47.26,91.92 46.55,92.63 46.55,93.21 46.2,93.56 45.59,93.56 44.84,94.31 44.84,94.96 40.86,98.93 37.6,98.93 36.02,97.35 33.92,97.35 v1(31.25,100.02) ; v1(39.54,75.07) 40.51,75.07 40.55,75.03 40.6,75.03 41.02,74.61 41.02,73.79 40.51,73.28 39,73.28 38.59,72.87 38.59,58.93 38.18,58.51 32.83,53.16 32.83,52.36 32.47,52 32.47,49.65 28.3,45.48 28.3,34.06 25.04,30.79 25.04,27.96 25.41,27.59 26.61,27.59 26.96,27.24 26.96,26.74 26.52,26.3 26.52,24.65 27.07,24.1 27.5,24.1 27.78,23.82 29.61,23.82 30.24,23.19 30.24,22.4 29.68,21.84 29.67,21.84 29.55,21.72 29.55,18.3 30.33,17.51 32.29,17.51 32.35,17.57 33.25,17.57 v1(33.55,17.27)
  LY4 w0.171: v1(48.1,18.32) 34.6,18.32 v1(33.55,17.27)
  BOTTOM w0.178: RN505.4 47.01,90.21 v1(46.93,90.13) ; U518.14 47.75,16.85 48.18,17.28 48.18,18.24 v1(48.1,18.32)
LED_DRV_DOUT: length 124.9
  TOP w0.178: U7.52 49.38,91.02 49.59,90.81 49.59,88.9 49.15,88.46 48.9,88.46 48.21,87.77 v1(48.21,87.49) 48.2,87.48 48.2,85.32 47.22,84.34 47.22,82.61 46.94,82.33 46.94,81.77 46.48,81.31 46.48,80.2 44.67,78.4 43.17,78.4 41.09,76.31 41.09,75.17 v1(40.35,74.43)
  LY3 w0.171: v1(32.6,16.98) 30.22,16.98 28.57,18.62 28.57,20.01 28.16,20.42 28.16,21.88 28.48,22.2 29.53,22.2 29.88,22.55 29.88,23.04 29.53,23.39 27.99,23.39 27.39,22.79 25.28,22.79 24.68,23.39 24.68,30.94 27.94,34.2 27.94,45.65 30.21,47.92 32.11,49.82 32.11,52.17 32.47,52.53 32.47,53.31 38.03,58.87 38.24,59.07 38.24,73.02 38.68,73.47 38.68,73.58 38.74,73.63 39.55,73.63 v1(40.35,74.43)
  LY4 w0.171: v1(32.6,16.98) 33.43,16.15 33.91,16.15 35.27,14.79 40.13,14.79 40.67,15.33 41.71,15.33 42.91,14.13 43.77,14.13 43.95,13.94 44.44,13.94 44.63,14.13 46.87,14.13 47.33,14.59 49.87,14.59 50.31,15.03 v1(54.1,15.03)
  BOTTOM w0.178: U518.5 53.3,15.55 53.31,15.54 53.61,15.54 54.1,15.05 v1(54.1,15.03) ; v1(48.21,87.49) 48.21,87.86 48.85,88.5 RN505.2
LED_DRV_OE: length 118
  TOP w0.178: v1(47.69,88.24) 47.59,88.14 47.59,85.34 46.76,84.52 46.76,82.84 45.9,81.97 45.9,80.36 44.46,78.92 42.96,78.92 40.44,76.41 v1(40.44,75.89) ; v1(50.74,93.03) 50.24,93.52 U7.57
  LY3 w0.171: v1(35.54,15.71) 35.54,15.7 34.34,16.9 34.34,17.32 33.8,17.87 33.79,17.87 33.46,18.2 32.49,18.2 30.94,19.75 30.94,23.3 27.32,26.93 27.32,27.38 26.76,27.94 26.3,27.94 25.39,28.85 25.39,30.65 28.66,33.91 28.66,45.33 32.83,49.5 32.83,51.85 33.19,52.21 33.19,53.02 34.5,54.33 36.13,54.33 36.48,54.68 36.48,56.02 36.48,56.31 38.32,58.16 38.95,58.78 38.95,70 41.61,72.66 41.61,72.74 41.94,73.07 41.94,75.18 41.24,75.89 v1(40.44,75.89) ; v1(50.74,93.03) 49.77,93.03 48.98,92.23 48.98,88.67 48.55,88.24 v1(47.69,88.24)
  LY4 w0.171: v1(35.54,15.71) 35.87,15.38 40.04,15.38 40.6,15.95 42.76,15.95 43.1,15.62 v1(48.26,15.62)
  BOTTOM w0.178: v1(48.26,15.62) 47.54,14.9 U518.11 ; RN505.3 48.75,89.3 v1(47.69,88.24)
LED_DRV_SCLK: length 208.8
  TOP w0.178: v1(46.62,91.62) 47.02,92.02 U7.54
  LY3 w0.171: v1(12.74,91.14) 17.39,86.49 18.89,86.49 21.03,84.35 21.03,81.22 16.74,76.93 16.74,66.87 15.18,65.31 15.18,63.32 15.61,62.89 15.61,60.96 17.37,59.2 17.37,42.7 18.64,41.43 18.64,32.24 17.62,31.22 17.62,28.5 17.63,28.49 17.63,28 17.62,27.99 17.62,26.58 16.81,25.76 16.81,12.79 17.46,12.14 17.46,10.05 18.88,8.63 19.33,8.63 19.71,8.25 25.01,8.25 27.58,5.68 39.95,5.68 40.63,5 40.63,4.35 41.06,3.93 44.48,3.93 47.19,6.64 56.1,6.64 58.01,8.55 58.23,8.55 59.33,9.66 59.33,10.15 58.98,10.5 58.07,10.5 58.01,10.57 53.02,10.57 52.77,10.81 51.93,10.81 50.42,12.33 50.42,15.92 50.76,16.26 50.76,16.76 50.42,17.1 v1(50.42,17.91)
  LY4 w0.171: v1(12.74,91.14) 12.06,91.81 12.06,100.32 12.06,100.96 13.31,102.21 13.6,102.21 20.97,102.21 22.17,101 25.3,101 28.16,98.15 33.52,98.15 34.25,97.41 35.22,97.41 35.6,97.79 38.47,97.79 39.38,96.88 41.01,96.88 45.09,92.8 45.09,92.49 45.96,91.62 v1(46.62,91.62)
  BOTTOM w0.178: v1(46.62,91.62) 46.44,91.44 45.35,91.44 R582.1 ; U518.2 50.83,17.5 v1(50.42,17.91)
LED_EN: length 54.5
  TOP w0.178: J38.3 2.25,16.58 2.03,16.79 2.03,28.19 2.54,28.7 6.6,28.7 8.73,26.58 J39.11 14.06,26.58 v1(14.73,25.91)
  BOTTOM w0.178: v1(14.73,25.91) 17.69,22.95 17.69,20.78 14.44,17.53 14.44,15.7 14.79,15.35 15.11,15.35 15.11,15.35 19.44,15.35 22.06,12.73 23.72,12.73 24.27,13.27 24.27,14.87 24.73,15.33 J46.2
LED_OE: length 11.4
  TOP w0.178: TP59.1 45.56,10.19 48.27,12.9 J49.4
  BOTTOM w0.178: R750.2 42.58,13.42 TP59.1
LED_SCLK: length 13.2
  TOP w0.178: TP61.1 57.99,12.64 55.18,12.64 55.05,12.51 53.15,12.51 52.58,13.08 52.58,13.62 J49.1
  BOTTOM w0.178: R748.2 56.64,16.13 58.25,14.52 TP61.1
LMP_HOT: length 29
  TOP w0.178: v1(51.76,106.35) 51.76,106.4 51.09,107.08 51.09,107.75 50.55,108.28 50.08,108.76 50.08,111.46 49.56,111.98 44.99,111.98 J7.1
  BOTTOM w0.178: v1(51.76,106.35) 51.97,106.56 52.81,106.56 53.71,105.66 R533.2 53.96,105.53 54.6,104.9 55.02,104.9 56.84,103.08 56.86,103.08 57.05,102.88 57.05,101.9 56.88,101.72 55.49,101.72 J12.3
LMP_TXD: length 14.4
  BOTTOM w0.178: U526.2 12.32,8.7 13.28,9.66 15.23,9.66 15.81,10.24 19.74,10.24 R773.2 R772.1 22.61,9.59 J45.3
LMP_TXD_BUF: length 3.5
  TOP w0.178: v1(12.5,1.65) 12.5,2.03 13.36,2.89 J53.5
  BOTTOM w0.178: v1(12.5,1.65) 12.51,1.65 12.51,1.65 13.34,2.48 R787.1
LMPCTRL: length 379.4
  TOP w0.178: v1(126.97,55.89) 126.6,56.27 126.6,57.13 127.7,58.23 127.7,61.71 124.45,64.96 124.45,66.34 124.45,66.34 124.45,66.89 124.45,70.47 126.97,72.99 126.97,74.84 127.51,75.39 131.84,75.39 134.38,77.92 139.9,77.92 142.03,80.05 142.51,80.05 142.86,80.4 142.86,80.88 142.87,80.89 142.87,81.19 142.68,81.37 142.09,81.37 141.59,80.86 141.59,80.86 140.44,79.72 140.44,79.69 139.88,79.13 139.85,79.13 139.36,78.63 129.79,78.63 128.7,77.55 123.48,77.55 123.24,77.3 122.74,77.3 122.63,77.42 122.63,83.96 125.5,86.84 125.84,86.84 126.4,87.4 126.4,87.74 130.13,91.46 130.37,91.7 137.75,91.7 137.78,91.67 137.82,91.67 142.3,87.19 147.64,87.19 149.11,85.72 TP31.1 ; U11.AC9 v2(103.66,71.2)
  LY3 w0.171: v1(108.16,5.19) 107.87,4.89 105.01,4.89 104.25,4.14 101.05,4.14 100.31,4.88 100.31,5.22 99.96,5.57 96.42,5.57 96.26,5.73 93.68,5.73 93.52,5.89 79.27,5.89 77.58,4.21 73.66,4.21 72.17,2.72 67.19,2.72 66.13,3.78 64.28,3.78 63.61,4.46 63.61,5.47 62.56,6.52 59.01,6.52 57.95,5.46 47.94,5.46 45.06,2.58 26.04,2.58 25.69,2.93 25.69,3.42 24.49,4.63 22.37,4.63 20.64,6.36 20.03,6.36 19.42,5.75 18.93,5.75 18.58,6.1 17.47,6.1 17.04,5.67 11.37,5.67 7.77,9.27 v1(7.62,9.27) ; v1(143.51,33.74) 142.73,34.52 142.73,42.12 140.74,44.11 139.51,44.11 139.1,44.52 139.1,44.94 138.1,45.95 138.1,47.9 138.01,47.99 138.01,48.35 135.79,50.57 131.7,50.57 131.22,51.05 131.22,51.61 130.87,51.96 130.86,51.96 126.97,55.85 v1(126.97,55.89)
  LY4 w0.171: v1(126.97,55.89) 126.89,55.81 126.89,54.71 124.39,52.22 124.39,49.13 124.14,48.88 124.14,48.77 122.49,47.12 118.19,47.12 116.62,48.68 v1(106.59,48.68)
  BOTTOM w0.102: 102.05,62.23 101.27,63.01 101.27,66.36 101.5,66.59 101.92,66.59 102.27,66.94 102.27,71.36 102.5,71.59 102.83,71.59 103.22,71.2 v2(103.66,71.2)
  BOTTOM w0.178: U519.3 5.17,12.2 5.17,12.2 5.2,12.2 5.23,12.17 5.48,12.17 7.24,10.41 7.24,9.65 v1(7.62,9.27) ; R687.2 122.39,59.07 R688.1 ; R687.2 U511.2 ; R687.2 123.83,59.03 v1(126.97,55.89) ; v1(143.51,33.74) 143,33.23 139.22,33.23 133.39,27.39 133.39,21.34 133.63,21.09 133.63,18.98 133.58,18.93 133.58,18.92 133.41,18.75 133.4,18.75 132.97,18.32 132.97,13.81 127.88,8.72 124.16,8.72 122.38,10.5 118.87,10.5 117.67,9.3 114.01,9.3 110.82,6.11 110.82,5.84 110.28,5.3 110.28,5.08 109.98,4.78 109.16,4.78 108.75,5.19 v1(108.16,5.19) ; v1(106.59,48.68) 106.59,52.37 104.45,54.51 104.24,54.72 104.24,56.19 104.22,56.21 104.22,59.74 102.23,61.73 102.23,62.05 102.05,62.23
LMPCTRL_BUF: length 246.2
  TOP w0.178: J53.6 11.62,3.28 10.84,2.5 v1(10.84,2.5)
  LY3 w0.171: v1(133.87,4.03) 133.25,4.65 132.62,4.65 132.62,4.65 132.13,4.65 132.13,4.65 131.87,4.65 131.49,4.27 130.28,4.27 130.23,4.32 128.34,4.32 125.86,6.79 118.71,6.79 116.73,4.81 115.52,4.81 114.99,4.28 113.78,4.28 112.86,5.2 112.86,6.59 113.88,7.61 116.47,7.61 118.12,9.26 118.12,10.41 118.72,11 120.49,11 122.77,13.28 124.68,13.28 126.29,14.89 126.29,15.7 126.29,18.06 126.5,18.26 127.14,18.91 128.85,18.91 130.36,20.42 131.53,20.42 134.71,23.61 134.71,34.79 135.83,35.91 135.83,36.4 134.71,37.52 134.71,38.94 134.15,39.5 134.15,40.36 133.43,41.08 131.92,41.08 128.8,44.19 128.8,44.23 127.18,45.85 127.18,48.16 125.14,50.19 122.42,50.19 122.03,50.58 122.03,51.07 123.1,52.13 123.1,58.78 122.99,58.89 122.99,61.62 123.35,61.98 123.35,64.32 122.46,65.21 121.44,65.21 v1(120.47,66.18)
  LY4 w0.171: v1(133.87,4.03) 133.01,4.89 132.11,4.89 131.25,4.03 125.51,4.03 123.78,2.3 98.88,2.3 98.72,2.15 97.87,2.15 97.72,2.3 91.6,2.3 90.73,3.18 90.42,3.18 81.84,3.18 81.56,2.9 81.07,2.9 80.72,3.25 80.72,3.32 79.63,4.41 72.99,4.41 72.44,4.97 72.08,4.97 71.32,4.97 70.05,3.69 67.11,3.69 65.21,5.59 63.6,5.59 62.42,4.41 61.28,4.41 60.37,3.5 51.01,3.5 50,4.51 45.8,4.51 44.78,3.5 27.42,3.5 26.72,4.2 25.71,4.2 25.22,4.69 22.02,4.69 19.51,7.2 18.85,7.2 17.78,6.14 13.11,6.14 10.84,3.87 v1(10.84,2.5)
  BOTTOM w0.178: R643.1 v1(120.47,66.18)
LMPCTRL_Z: length 228.5
  TOP w0.178: v1(14.12,1.89) 14.12,2.32 14.61,2.82 J53.4
  LY3 w0.171: v1(122.63,50.82) 125.12,50.82 128.37,47.57 128.37,45.52 132.37,41.51 133.61,41.51 134.78,40.35 134.99,40.35 135.34,40 135.34,37.5 136.26,36.58 136.26,35.73 135.14,34.61 135.14,23.43 131.78,20.07 131.06,20.07 129.55,18.55 127.29,18.55 126.64,17.91 126.64,15.85 126.64,14.75 124.83,12.93 122.92,12.93 120.64,10.65 118.87,10.65 118.48,10.26 118.48,9.11 117.96,8.6 116.62,7.25 114.02,7.25 113.28,6.51 113.28,5.28 113.92,4.64 114.84,4.64 115.37,5.17 116.58,5.17 118.56,7.15 126.05,7.15 128.5,4.69 128.86,4.69 128.86,4.69 130.36,4.69 130.43,4.62 131.32,4.62 131.7,5 131.98,5 131.98,5 132.93,5 133.77,5.84 v1(134.48,5.84)
  LY4 w0.171: v1(134.48,5.84) 135.53,4.79 135.53,3.57 133.83,1.87 107.07,1.87 106.05,0.85 104.53,0.85 103.51,1.87 99.06,1.87 98.9,1.71 97.69,1.71 97.54,1.87 91.12,1.87 90.24,2.75 82.02,2.75 81.74,2.47 80.89,2.47 80.29,3.07 80.29,3.14 79.45,3.98 74.51,3.98 74.47,3.94 72.85,3.94 72.56,4.23 72.26,4.53 71.5,4.53 70.3,3.33 65.44,3.33 64.94,3.83 62.77,3.83 62,3.07 50.32,3.07 49.36,4.02 46.2,4.02 45.24,3.07 27.24,3.07 26.54,3.77 25.53,3.77 25.05,4.26 21.47,4.26 21.08,4.66 19.42,4.66 18.37,5.71 14.67,5.71 14.11,5.15 14.11,4.42 14.12,4.41 v1(14.12,1.89)
  BOTTOM w0.178: v1(122.63,50.82) 122.66,50.82 122.7,50.79 R686.1
LMPSTAT: length 243.3
  TOP w0.102: v2(106.66,70.2) 107.63,71.17
  TOP w0.178: U11.AF8 v2(106.66,70.2) ; v1(96.18,3.73) 97.8,3.73 98.77,4.7 98.77,6.01 100.33,7.57 101.38,7.57 103.16,5.79 103.16,4.24 104.81,2.6 113.44,2.6 115.02,4.18 115.02,7.72 116.12,8.82 118.78,8.82 119.63,7.96 122.55,7.96 127.19,12.6 127.19,15.21 125.54,16.87 123.62,16.87 122.8,17.68 122.8,18.48 123.84,19.52 123.84,20.78 123.68,20.94 123.68,21.43 123.84,21.59 123.84,22.21 124.58,22.95 124.58,30.07 121.24,33.41 120.16,33.41 119.52,34.05 111.12,34.05 108.65,36.52 105.94,36.52 103.4,39.07 103.4,47.1 105.83,49.53 109.65,49.53 111.2,47.97 112.37,47.97 116.88,52.49 116.88,57.73 117.84,58.69 122.3,58.69 123.38,59.77 123.38,65.51 122.24,66.65 122.24,71.87 121.17,72.94 120.16,72.94 120.16,72.94 119.28,72.94 109.4,72.94 107.63,71.17
  LY4 w0.171: v1(96.18,3.73) 93.19,3.73 92.89,4.03 92.4,4.03 92.1,3.73 87.05,3.73 83.93,6.85 64.06,6.85 62.18,4.96 61.02,4.96 60.04,3.99 55.64,3.99 55.59,3.94 55.09,3.94 55.05,3.99 51.18,3.99 50.16,5.01 45.44,5.01 44.42,3.99 39.81,3.99 39.75,4.04 28.07,4.04 23.61,8.51 19.71,8.51 19.28,8.94 18.8,8.94 18.52,9.22 v1(17.02,9.22)
  BOTTOM w0.178: U524.4 v1(17.02,9.22)
LP_DRIVE: length 12.9
  LY3 w0.171: v1(185.88,72.59) 185.88,72.59 187.41,74.12 187.41,76.32 187.26,76.48 187.26,79.57 v1(186.68,80.15)
  BOTTOM w0.178: U508.5 186.34,72.12 v1(185.88,72.59) ; v1(186.68,80.15) R599.1 185.45,80.38 R600.2
LP_IR0: length 265.4
  LY3 w0.171: v1(193.4,119.09) 193.4,115.46 196.03,112.83 196.03,104.26 193.98,102.21 193.98,99.87 194.73,99.13 194.73,95.81 194.6,95.68 194.6,95.08 194.35,94.83 194.35,77.29 194.39,77.26 194.39,74.69 193.43,73.74 193.43,72.78 193.44,72.78 193.44,70.79 193.75,70.48 193.75,69.98 193.4,69.63 193.19,69.63 192.34,68.79 192.34,68.3 191.99,67.95 191.59,67.95 v1(191.19,67.54)
  LY4 w0.171: U1.1 15.24,121.86 18.7,125.32 22.63,125.32 24.2,123.75 31.62,123.75 36.41,128.54 73.81,128.54 75.54,130.28 106.07,130.28 107.53,128.81 120.99,128.81 121.26,128.54 122.52,128.54 122.63,128.44 123.12,128.44 123.22,128.54 123.4,128.54 129.53,122.41 139.04,122.41 139.69,123.06 140.65,123.06 143.77,126.18 143.77,127.14 146.9,130.26 164.59,130.26 167.43,127.42 172.02,127.42 173.31,128.7 186.97,128.7 193.4,122.27 v1(193.4,119.09)
  BOTTOM w0.178: U500.2 U1.1 ; v1(191.19,67.54) 191.1,67.54 191.01,67.63 191.01,68.85 191.53,69.37 R616.1 191.61,69.55 193.54,69.55 193.86,69.87 193.86,70.44 193.42,70.87 193,70.87 192.63,71.25 R614.1
LP_IR1: length 101.7
  LY3 w0.171: v1(178.68,69.74) 179.06,69.35 179.06,68.6 179.41,68.25 179.9,68.25 181.14,67.01 181.14,65.92 181.49,65.57 182.68,65.57 183.2,65.05 183.2,51.28 179.93,48.01 179.93,42.5 182.04,40.39 182.04,38.95 182.44,38.55 182.44,36.9 184.21,35.12 184.21,29.78 181.21,26.78 179.89,26.78 179.44,27.23 178.87,27.23 177.44,25.8 177.44,23.24 177.8,22.88 177.8,13.04 180.8,10.04 180.8,7.16 U21.1
  LY4 w0.171: v1(193.16,70.23) 189.44,70.23 188.77,70.9 186.72,70.9 186.26,70.44 185.16,70.44 183.9,69.19 182.57,69.19 182.38,69.38 181.49,69.38 180.75,70.12 179.06,70.12 v1(178.68,69.74)
  BOTTOM w0.178: R619.1 v1(178.68,69.74) ; U21.1 182.16,5.8 182.16,6.93 182.73,7.49 U520.2 ; R615.1 192.78,70.36 192.79,70.35 193.05,70.35 193.16,70.24 v1(193.16,70.23)
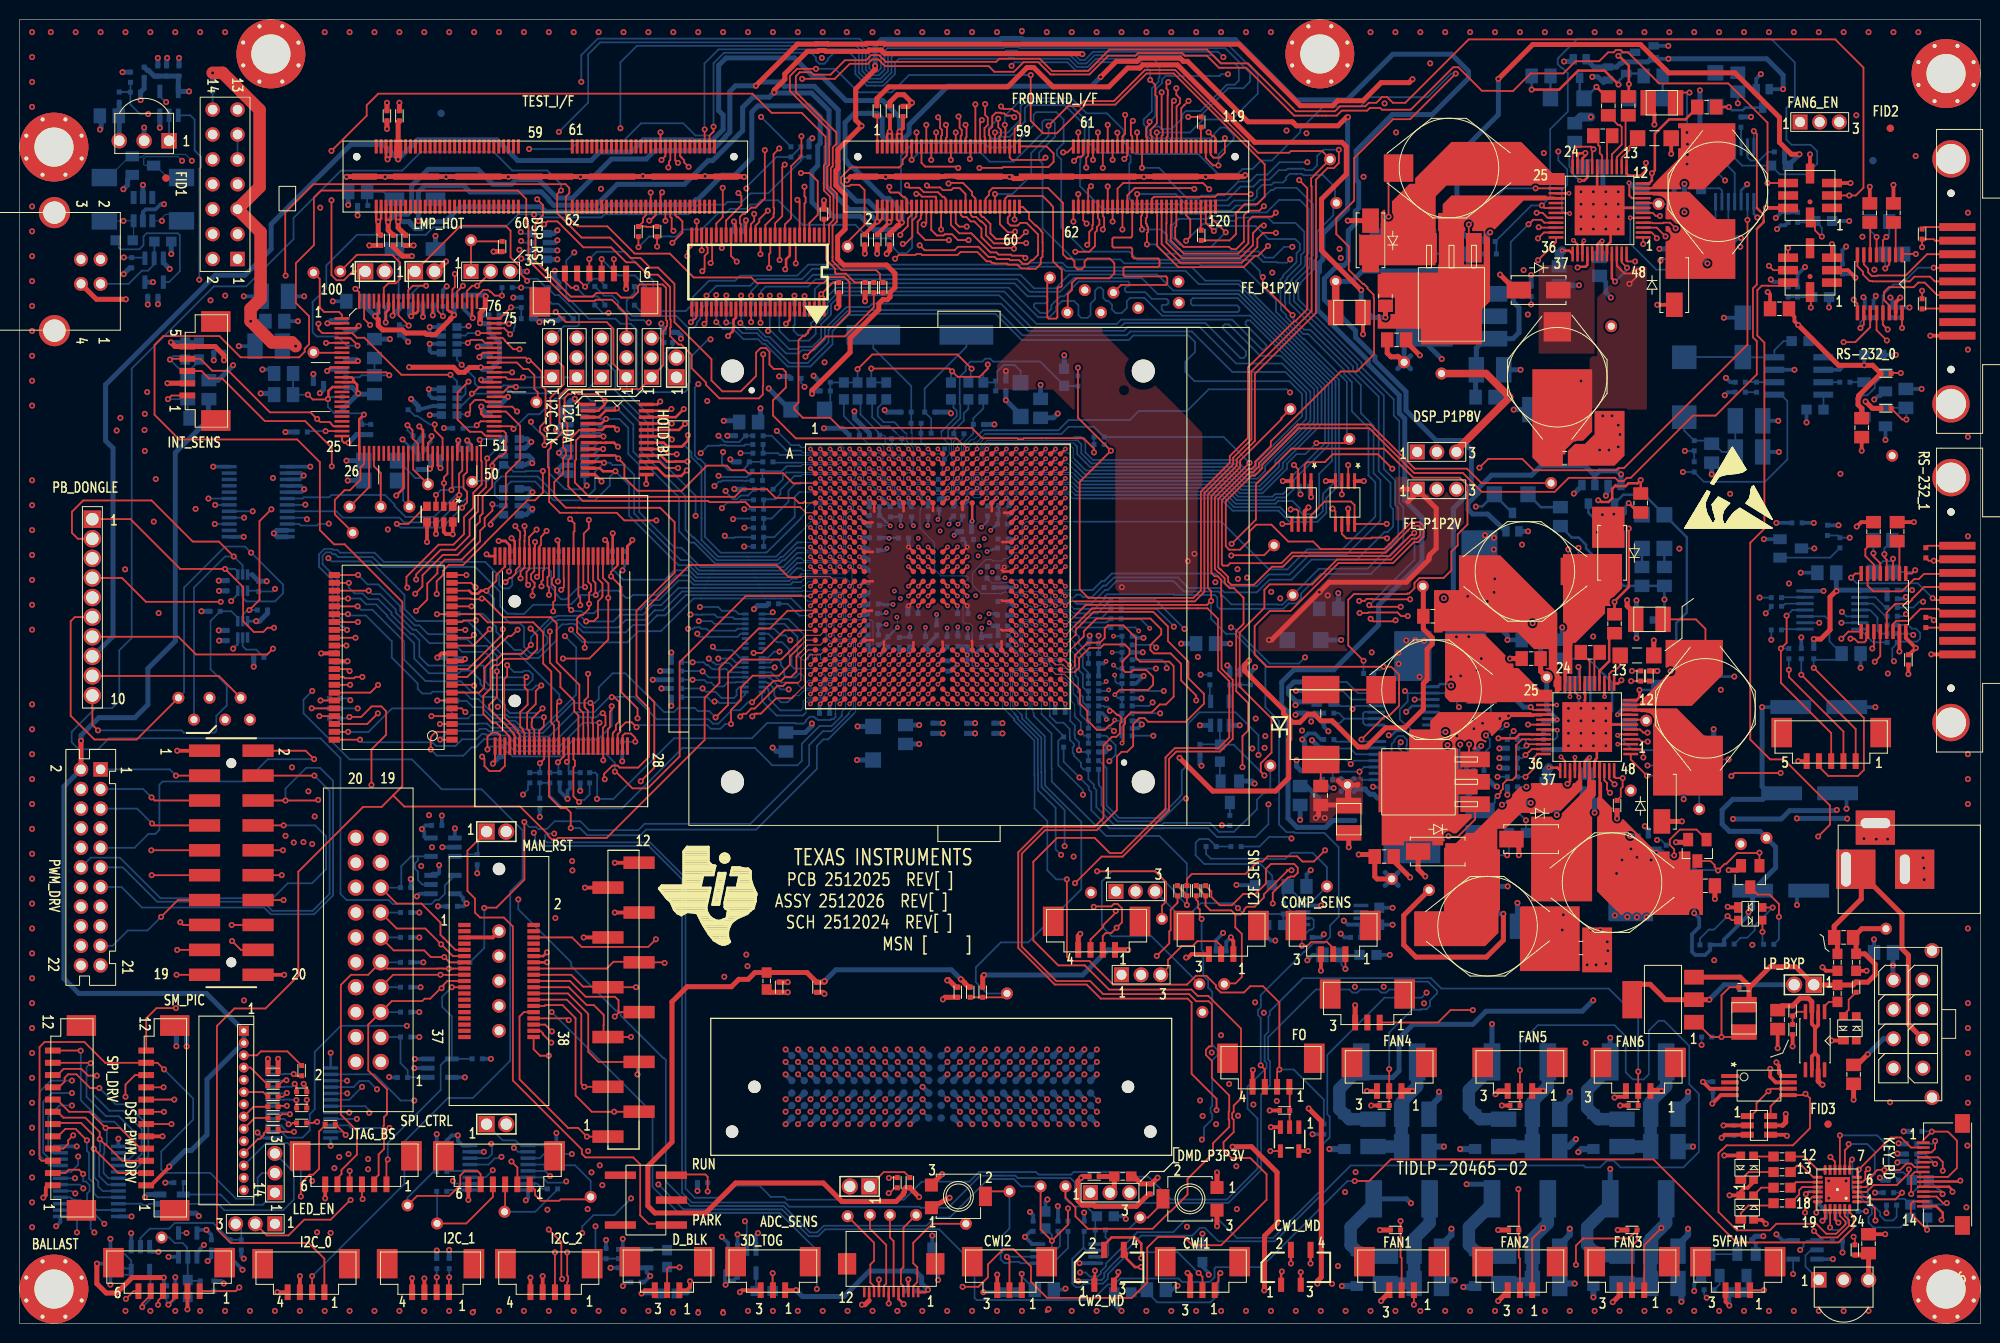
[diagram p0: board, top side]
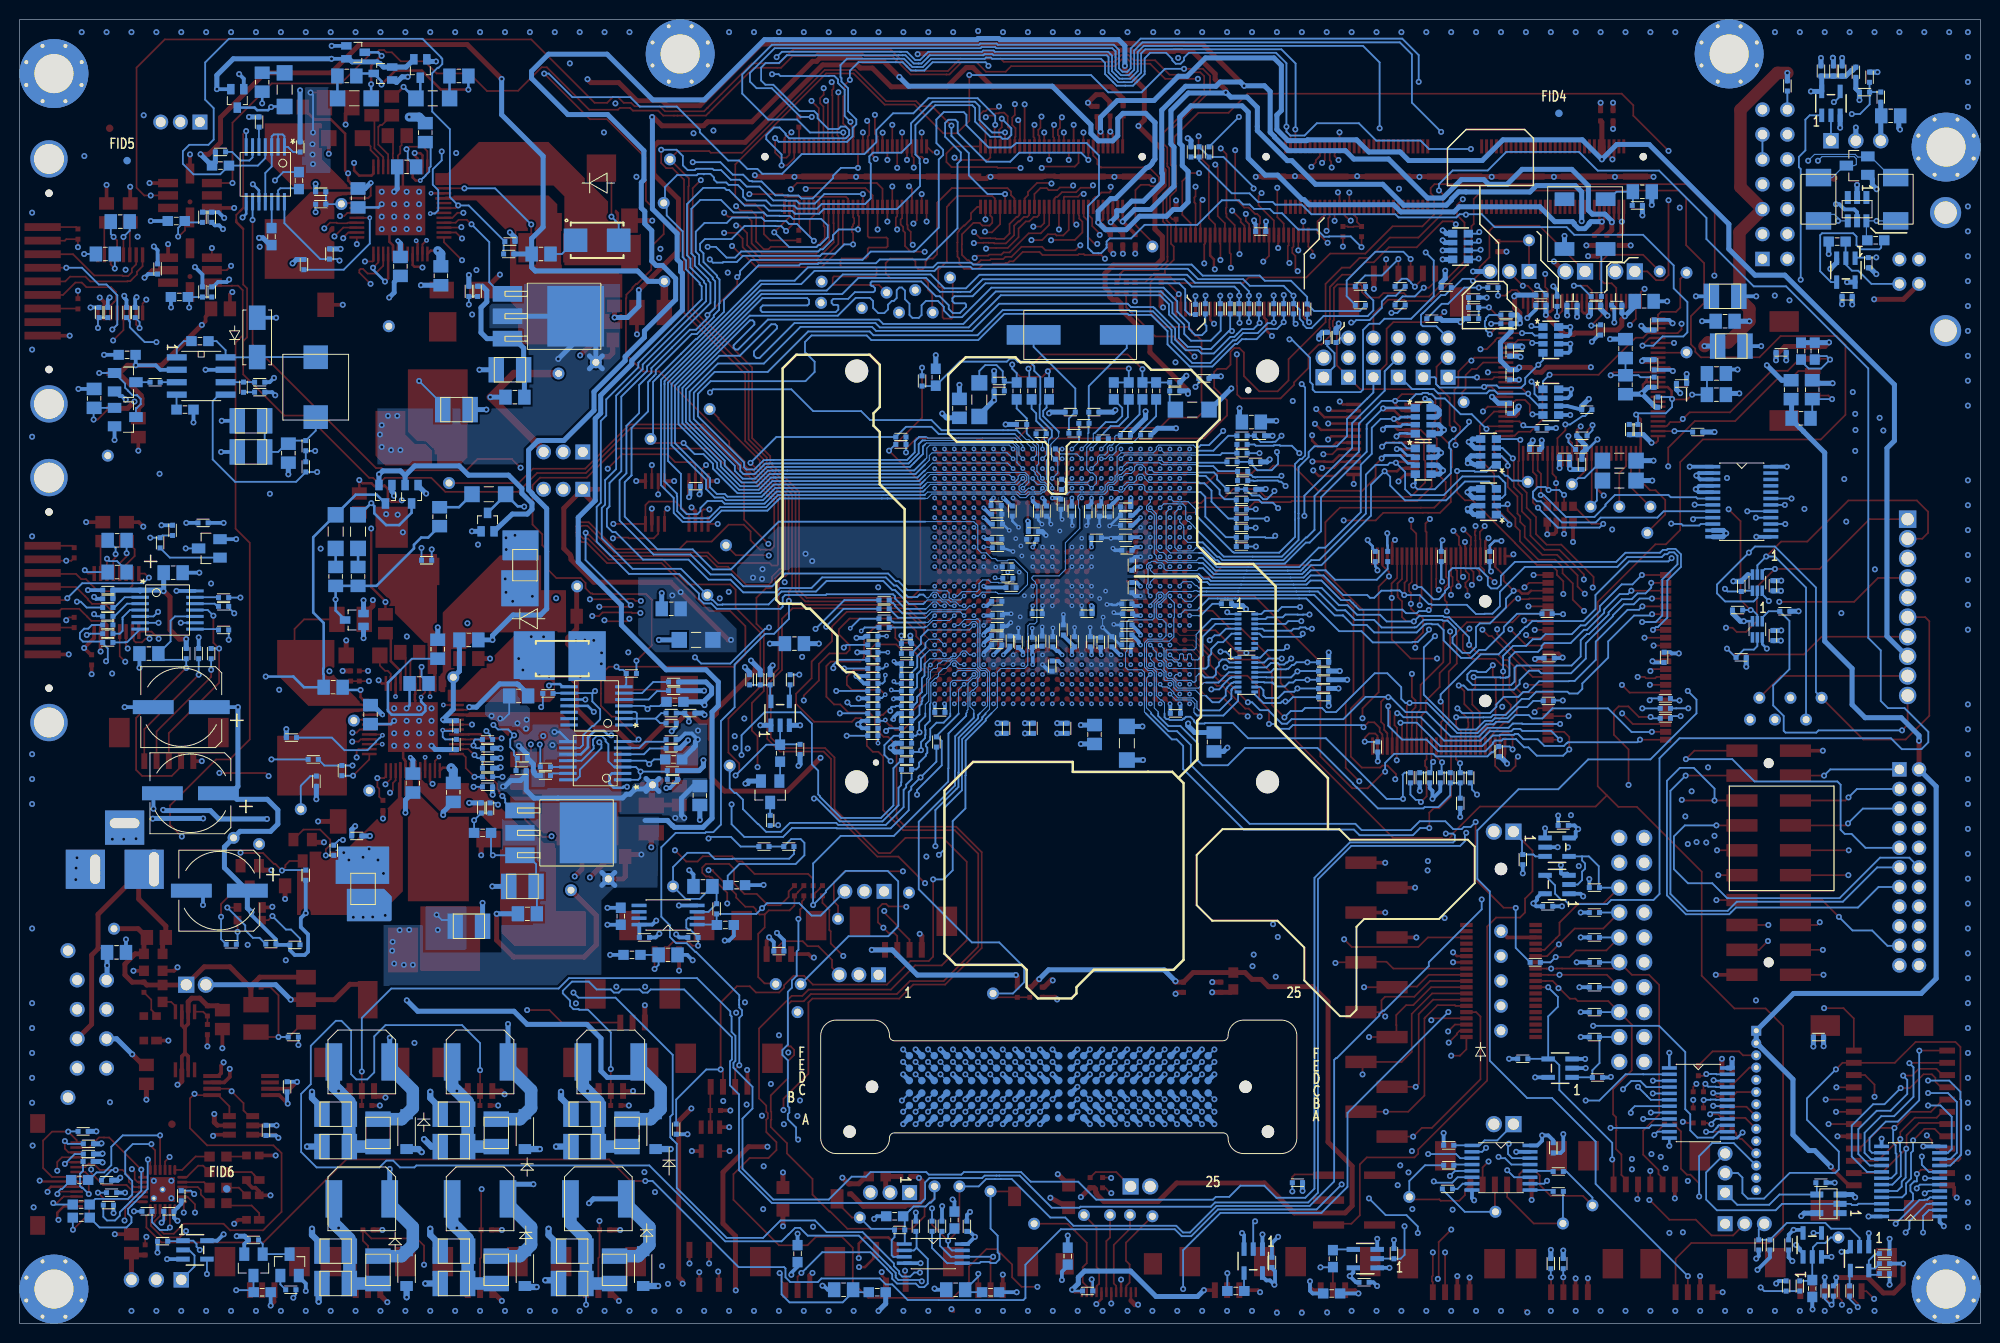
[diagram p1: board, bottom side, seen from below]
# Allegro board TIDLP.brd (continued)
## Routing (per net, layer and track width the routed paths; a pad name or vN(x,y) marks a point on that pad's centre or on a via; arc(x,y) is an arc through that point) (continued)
LP_P1_0: length 3.2
  BOTTOM w0.178: R612.2 190.33,73.03 189.29,74.07 U508.2
LP_P1_5: length 3.3
  BOTTOM w0.178: R616.2 189.25,69.47 189.23,69.49 189.04,69.49 U508.7
LP_P1_6: length 2.4
  BOTTOM w0.178: R619.2 179.8,70.82 U508.8
LP_P2_6: length 2.4
  BOTTOM w0.178: R617.2 179.75,74.07 U508.13
LP_P2_7: length 2.5
  BOTTOM w0.178: R618.2 179.85,73.15 180.12,73.42 U508.12
LP_P3P3V: length 321.3
  LY3 w0.508: v1(17.28,125.68) 11.4,125.68 9.63,123.91 9.63,121.81 8.97,121.14 8.97,121.14 8.88,121.05 8.88,114.7 4.96,110.78 4.96,104.49 6.22,103.23 6.22,99.19 2.62,95.59 2.62,22.98 3.88,21.72 3.88,12.13 2.74,11 2.74,9.38 4.18,7.94 5.25,7.94 5.39,7.8 7.73,7.8 12.39,3.14 21.02,3.14 22.13,2.04 66.63,2.04 66.83,1.84 72.53,1.84 72.73,2.04 81.22,2.04 82.28,3.1 90.64,3.1 91.64,2.1 104.53,2.1 104.64,2.21 105.27,2.21 105.38,2.1 112.78,2.1 112.85,2.03 115.92,2.03 116.16,2.28 137.79,2.28 143.27,7.76 161.08,7.76 161.84,7 178.3,7 179.19,7.89 179.19,9.07 v1(179.2,9.08)
  BOTTOM w0.381: v1(179.2,9.08) 179.84,8.43 U520.5
  BOTTOM w0.508: v1(17.28,125.68) U500.5 16.18,127.17 C503.2 R504.1 C504.2 13.73,127.24 13.14,127.83 13.03,127.83 R505.1
LP_TA0: length 4.2
  BOTTOM w0.178: R614.2 R613.2 190.33,72.14 189.04,73.42 U508.3
LP_TA1: length 4.6
  BOTTOM w0.178: U508.4 188.74,72.77 189.51,72.01 189.51,71.84 189.5,71.83 189.5,70.64 189.79,70.36 R615.2
LP_TCK: length 12.8
  TOP w0.178: J22.2 186.03,60.38 180.47,65.95 v1(180.47,66.67)
  BOTTOM w0.178: R631.1 v1(180.47,66.67)
LP_TDO_TDI: length 29
  TOP w0.178: J22.4 183.53,56.8 184.49,55.85 187.51,55.85 188.12,56.46 188.12,61.76 183.02,66.87 v1(183.01,66.87)
  BOTTOM w0.178: v1(183.01,66.87) R629.1 183.12,67.69 185.29,67.69 185.85,68.25 C637.2 184.6,69.57 184.6,71.67 184.16,72.12 U508.10
LP_TEST_VPP: length 20.1
  TOP w0.178: J22.3 184.78,60.22 179.65,65.35 v1(179.65,68.85) 180.24,69.43 v1(180.24,72.19)
  BOTTOM w0.178: v1(180.24,72.19) 180.81,72.77 U508.11 ; R631.2 v1(179.65,68.85)
M_FUT_0: length 43.6
  TOP w0.178: v1(45.68,92.74) 45.96,93.01 45.96,93.71 46.45,94.2 47.23,94.2 47.24,94.19 47.36,94.19 47.5,94.06 47.56,94.06 47.59,94.02 U7.58
  LY3 w0.171: v1(31.54,81.59) 31.05,81.59 30.26,82.38 30.26,83.76 29.65,84.36 29.65,86.19 29.99,86.53 29.99,86.89 30.25,87.15 30.25,89.03 29.13,90.14 29.13,92.36 30.32,93.55 31.79,93.55 35.24,96.99 36.17,96.99 36.18,97 36.67,97 37.97,98.3 40.86,98.3 44.48,94.67 44.48,94.16 45.68,92.96 v1(45.68,92.74)
  BOTTOM w0.178: U506.10 28.53,81.54 28.68,81.39 30.34,81.39 30.49,81.54 31.49,81.54 v1(31.54,81.59) ; v1(45.68,92.74) 44.68,92.74 RN503.4
MAN_RSTZ: length 60.2
  TOP w0.178: J25.1 45.68,48.22 45.68,44.09 46.44,43.33 46.44,41.91 46.95,41.4 49.39,41.4 50.31,40.49 50.31,24.78 57.34,17.74 57.34,17.31 57.72,16.93 62.58,16.93 63.3,16.22 63.3,11.02 64.16,10.16 66.34,10.16 66.48,10.03
  BOTTOM w0.178: U514.3 45.39,47.64 45.58,47.83 R711.1 46.75,47.9 46.75,49.23 47.62,50.1 J25.1
MC_VCC: length 15.4
  TOP w0.508: v1(183.01,69.81) 183.73,69.81 184.66,70.75 184.66,74.1 185.33,74.76 v1(185.33,74.7)
  BOTTOM w0.508: C578.1 185.31,74.72 v1(185.33,74.7) 185.43,74.8 187.62,74.8 U508.1 187.79,74.8 C607.2 R611.2 ; R629.2 v1(183.01,69.81)
MODEB: length 20
  TOP w0.178: R58.2 90.25,15.43 88.14,15.43 J50.1
  LY3 w0.171: J50.1 88.18,13.97 88.27,13.88 89.82,13.88 91.66,15.72 92.02,15.72 96.61,20.31 96.61,21.05 v1(97.16,21.59)
  BOTTOM w0.178: J500.11B 96.55,22.2 v1(97.16,21.59)
MTR_ARSTZ: length 147.7
  TOP w0.178: U2.48 163.92,108.39 163.98,108.33 v1(164.78,108.33) ; U11.T25 v2(96.66,88.2) ; R26.2 162.95,53.35 163.32,53.72 163.32,54.54 163.51,54.73 v1(163.51,55.63) 162.83,55.63 162.65,55.81 U15.48
  LY3 w0.171: v1(163.51,55.63) 163.51,56.27 164.51,57.26 164.51,58.2 164.53,58.22 164.53,61.51 165.22,62.19 165.22,62.76 163.93,64.04 163.93,64.52 163.44,65.01 163.14,65.01 162.79,65.36 162.79,67.79 163.37,68.38 163.37,85 164.39,86.02 164.39,92.5 162.33,94.56 162.33,101.71 TP17.1 163.18,102.56 163.18,102.61 164.78,104.22 164.78,105.78 164.8,105.8 164.8,106.3 164.78,106.32 v1(164.78,108.33)
  LY4 w0.171: TP17.1 143.13,101.73 141.35,103.5 136.98,103.5 135.8,104.69 135.8,106.41 134.79,107.42 132.25,107.42 131.46,106.63 131.46,96.85 v1(129.58,94.97)
  BOTTOM w0.102: 97.99,90.83 97.3,90.14 97.05,90.14 96.27,89.36 96.27,88.59 v2(96.66,88.2)
  BOTTOM w0.178: v1(129.58,94.97) 129.26,95.29 121.28,95.29 119.06,93.06 114.16,93.06 113.25,92.15 106.99,92.15 105.96,91.11 99.68,91.11 99.68,91.11 99.18,91.11 99.18,91.11 98.27,91.11 97.99,90.83
NC0198: length 0.7
  TOP w0.178: U11.A13 v2(80.66,75.2)
OCLKA: length 74.6
  TOP w0.178: U2.6 166.57,113.29 166.89,112.97 v1(167.32,112.97) ; U15.6 165.3,60.58 165.62,60.26 v1(166.05,60.26)
  LY3 w0.171: v1(166.05,60.26) 166.52,60.26 166.78,60.52 166.78,66 166.46,66.31 166.46,67.44 169.3,70.28 v1(169.3,79.03) ; v1(167.32,112.97) 158.37,104.01 158.37,95.63 160.01,93.99 160.01,81.71 160.04,81.68 160.04,80.14 v1(159.01,79.11)
  LY4 w0.171: v1(159.01,79.11) 169.22,79.11 v1(169.3,79.03)
  BOTTOM w0.178: R603.1 v1(159.01,79.11)
OCLKA_RES: length 79.7
  TOP w0.102: v2(106.66,68.2) 107.63,69.17
  TOP w0.178: 107.63,69.17 108.55,70.08 108.55,70.61 108.99,71.05 109.84,71.9 115.35,71.9 116.45,70.8 116.45,70.3 115.34,69.19 115.34,68.7 115.69,68.35 117.41,68.35 118.47,67.28 118.47,65.59 120.01,64.04 v1(120.01,63.55) ; U11.AF6 v2(106.66,68.2)
  LY3 w0.171: v1(157.97,78.95) 157.97,72.61 159.02,71.57 159.02,70.63 159.58,70.07 v1(160.51,70.07)
  LY4 w0.171: v1(160.51,70.07) 159.5,70.07 159.29,70.28 153.45,70.28 153.41,70.32 148.39,70.32 148.06,70.65 147.57,70.65 147.56,70.64 146.31,70.64 146.12,70.44 138.68,70.44 138.48,70.24 137.13,70.24 136.96,70.41 135.67,70.41 134.9,71.17 134.08,71.17 133.07,70.15 131.29,70.15 129.62,68.48 129.62,68.11 128.67,67.16 127.08,67.16 126.27,66.35 124.54,66.35 121.74,63.55 v1(120.01,63.55)
  BOTTOM w0.178: R603.2 v1(157.97,78.95)
OUT1A: length 3.7
  TOP w0.254: v1(165.23,64.62) 165.23,63.88 164.93,63.59 U15.12
  BOTTOM w0.254: v1(165.23,64.62) 166.78,64.62 R632.1
OUT1A_SNUB: length 1.9
  BOTTOM w0.254: R601.1 C580.2
OUT1B: length 29.3
  TOP w0.254: U15.15 161.64,63.96 v2(161.66,63.94) ; v1(161.02,83.97) 161.12,83.97 161.12,84.03 161.35,83.79 162.07,83.79 162.44,84.17 162.44,85.14 162.79,85.49 162.87,85.42 163.83,85.42 164.11,85.7 165.03,85.7 v1(165.35,86.03) R18.1
  LY3 w0.254: v2(161.66,63.94) 161.66,81.08 160.74,82.01 160.74,83.6 161.05,83.97 v1(161.02,83.97)
OUT1B_SNUB: length 1.9
  BOTTOM w0.254: R602.1 C581.2
OUT1C: length 5.8
  TOP w0.254: U15.16 161.14,66.56 162.14,67.55 162.14,69.86 R20.1
OUT1C_SNUB: length 3.8
  BOTTOM w0.254: R589.1 155.18,83.26 157.16,83.26 C582.2
OUT2A: length 11.4
  TOP w0.254: R6.1 171.12,124.02 169.92,122.82 168.26,122.82 166.8,121.37 166.8,117.62 v1(166.5,117.32) 166.5,116.59 166.2,116.29 U2.12
OUT2A_SNUB: length 2.3
  BOTTOM w0.254: C500.2 175.25,127.57 R500.1
OUT2B: length 5.7
  TOP w0.178: U2.15 162.91,118.97 163.81,119.87 163.81,122.97 R4.1
OUT2B_SNUB: length 2.3
  BOTTOM w0.254: R501.1 167.59,124.98 C501.2
OUT2C: length 6.3
  TOP w0.178: R3.1 163.04,122.26 163.22,122.26 163.42,122.06 163.42,120.26 162.41,119.25 U2.16
OUT2C_SNUB: length 2.3
  BOTTOM w0.254: R502.1 156.15,127.24 C502.2
P1_A0: length 77.8
  TOP w0.178: J3.85 113.49,121.09 113.35,121.23 113.35,122.48 v1(113.55,122.68) ; U11.AE12 v2(105.66,74.2)
  LY3 w0.102: 107.63,73.33 107.15,73.33 106.82,73.66 106.2,73.66 v2(105.66,74.2)
  LY3 w0.171: 107.63,73.33 113.28,73.33 124.52,84.58 124.52,91.8 123.94,92.38 123.94,94.05 125.62,95.73 125.62,102.01 124.57,103.06 124.57,114.25 124.19,114.63 124.19,114.69 123.97,114.91 123.97,116.64 123.08,117.53 122.04,117.53 121.69,117.88 121.69,118.07 121.56,118.19 121.56,118.86 118.49,121.93 116.4,121.93 116.27,122.06 116.27,122.38 116.4,122.51 117.43,122.51 117.56,122.64 117.56,122.86 117.23,123.19 114.49,123.19 113.98,122.68 v1(113.55,122.68)
P1_A1: length 78.4
  TOP w0.178: J3.84 112.99,115.07 113.73,115.82 119.6,115.82 119.69,115.73 v1(119.82,115.73) ; U11.AF12 v2(106.66,74.2)
  LY3 w0.102: v2(106.66,74.2) 107.1,73.76 107.63,73.76
  LY3 w0.171: 107.63,73.76 113.21,73.76 124.17,84.72 124.17,91.47 123.51,92.13 123.51,94.23 125.26,95.98 125.26,101.86 124.13,102.99 124.13,109.2 123.28,110.06 123.28,110.55 124.13,111.41 124.13,114.08 123.92,114.29 123.75,114.29 123.53,114.07 123.53,112.31 123.41,112.19 123.15,112.19 123.02,112.31 123.02,114.42 123.54,114.94 123.54,116.46 122.9,117.1 121.86,117.1 121.13,117.83 121.13,118.56 120.77,118.92 120.25,118.92 119.87,118.54 119.87,115.78 v1(119.82,115.73)
P1_A2: length 78
  TOP w0.178: v1(112.68,118.79) 112.68,118.8 112.67,118.8 112.99,119.12 J3.83 ; U11.AF13 v2(106.66,75.2)
  LY3 w0.102: 107.45,74.83 107.08,75.2 v2(106.66,75.2)
  LY3 w0.171: 107.45,74.83 110.5,74.83 111.37,75.69 113.63,75.69 120.05,82.12 123.1,85.17 123.1,90.66 121.38,92.39 121.38,93.29 122.21,94.12 122.21,94.81 123.02,95.62 123.02,100.38 122.36,101.04 122.36,101.54 122.97,102.14 122.97,102.65 122.68,102.94 121.94,102.94 121.78,103.1 121.78,103.33 121.94,103.5 122.68,103.5 122.84,103.66 122.84,103.89 122.68,104.06 121.94,104.06 121.78,104.22 121.78,104.45 121.94,104.61 122.68,104.61 122.84,104.78 122.84,105.29 121.82,106.31 121.82,109.99 120.79,111.02 120.79,112.32 121.4,112.93 121.4,114.12 120.97,114.54 119.55,114.54 118.79,115.3 118.79,119.08 119.12,119.41 119.12,119.99 118.65,120.46 115.13,120.46 114.74,120.85 113.59,120.85 113.29,121.15 113.29,121.45 113.11,121.63 112.85,121.63 112.7,121.47 112.7,121.17 112.53,121 112.53,120.38 112.7,120.21 113.29,120.21 113.45,120.05 113.45,119.82 113.29,119.65 112.7,119.65 112.53,119.49 112.53,118.94 v1(112.68,118.79)
P1_A3: length 77.9
  TOP w0.178: v1(112.49,111.59) 112.49,113.9 J3.82 ; U11.AF14 v2(106.66,77.2)
  LY3 w0.102: v2(106.66,77.2) 106.38,77.2 105.83,76.65 105.83,76.5 106,76.33 107.41,76.33 107.63,76.56
  LY3 w0.171: 107.63,76.56 109.66,76.56 110.22,77.11 112.85,77.11 118.33,82.59 118.33,84.09 119.69,85.45 120.13,85.45 120.47,85.79 120.47,90.85 119.65,91.67 119.65,94 120.47,94.82 120.47,95.63 121.11,96.27 121.11,100.28 120.94,100.45 120.94,101.5 120.05,102.39 120.05,108.85 119.58,109.32 118.55,109.32 117.89,109.98 117.89,111.84 118.42,112.37 118.42,113.12 117.54,114.01 117.12,114.42 114.94,114.42 114.78,114.26 114.76,114.26 114.53,114.03 112.83,114.03 112.7,114.15 112.7,114.49 112.83,114.61 113.74,114.61 113.74,114.61 114.23,114.61 114.63,115 116.8,115 117.07,115.26 117.07,115.7 116.94,115.83 112.98,115.83 112.05,114.9 112.05,113.68 112.22,113.51 113.59,113.51 113.72,113.38 113.72,113.1 113.62,113 113.24,113 113.21,112.97 112.41,112.97 112.08,112.65 112.08,112 v1(112.49,111.59)
P1_A4: length 79.6
  TOP w0.178: v1(112.76,123.29) 112.76,121.36 112.49,121.08 J3.81 ; U11.AC13 v2(103.66,75.2)
  LY3 w0.102: 107.61,72.8 105.51,72.8 105.27,73.04 105.27,73.14 105.06,73.35 105.06,73.36 104.83,73.59 104.82,73.59 104.6,73.81 104.5,73.81 104.27,74.04 104.27,74.53 103.66,75.14 v2(103.66,75.2)
  LY3 w0.171: v1(112.76,123.29) 113.98,123.29 114.29,123.6 117.44,123.6 121.02,120.02 121.02,120.01 121.92,119.1 122.16,119.1 124.43,116.82 124.43,116.78 124.63,116.59 124.63,114.81 125,114.43 125,107.75 126.04,106.71 126.04,85.6 113.22,72.77 107.63,72.77 107.61,72.8
P1_A5: length 78.6
  TOP w0.178: v1(121.34,115.7) 120.7,116.34 112.57,116.34 111.99,115.76 J3.80 ; U11.AD13 v2(104.66,75.2)
  LY3 w0.102: 107.47,74.12 107.35,74.23 107.32,74.23 106.95,74.6 105.5,74.6 104.9,75.2 v2(104.66,75.2)
  LY3 w0.171: 107.47,74.12 113.06,74.12 123.81,84.87 123.81,91.29 123.08,92.02 123.08,94.45 124.91,96.28 124.91,101.71 123.7,102.92 123.7,109.02 123.52,109.21 123.38,109.21 123.2,109.02 123.2,106.67 123.07,106.54 122.81,106.54 122.68,106.67 122.68,109.72 122.84,109.88 122.84,110.49 122.42,110.91 122.42,112.05 122.59,112.22 122.59,114.68 123.11,115.2 123.11,116.28 122.85,116.53 121.54,116.53 121.27,116.27 121.27,115.76 v1(121.34,115.7)
P1_A6: length 78.4
  TOP w0.178: J3.79 111.99,120.07 111.99,121.46 v1(111.97,121.47) ; U11.AE13 v2(105.66,75.2)
  LY3 w0.102: v2(105.66,75.2) 105.66,75.12 105.98,74.8 107.08,74.8 107.41,74.47
  LY3 w0.171: v1(111.97,121.47) 111.89,121.55 111.89,122.07 111.58,122.37 111.58,122.52 111.57,122.53 111.57,123.52 111.74,123.69 111.99,123.69 112.17,123.52 112.17,122.69 112.78,122.07 113.72,122.07 113.74,122.09 114.27,122.09 115.25,121.11 115.53,121.11 115.74,120.9 118.89,120.9 119.69,120.1 119.69,119.23 119.23,118.77 119.23,115.98 119.23,115.97 119.23,115.48 119.63,115.08 121.85,115.08 122.15,114.78 122.15,112.56 121.94,112.35 121.43,112.35 121.22,112.14 121.22,111.2 122.28,110.13 122.28,109.93 122.25,109.9 122.25,106.49 122.74,106 123.14,106 123.27,105.86 123.27,102.84 123.91,102.2 123.91,100.99 123.38,100.46 123.38,95.36 122.64,94.63 122.64,93.94 121.81,93.11 121.81,92.56 123.46,90.92 123.46,85.02 112.91,74.47 107.41,74.47
P1_A7: length 77.8
  TOP w0.178: U11.AE14 v2(105.66,77.2) ; v1(111.49,112.4) 111.49,113.9 J3.78
  LY3 w0.102: v2(105.66,77.2) 105.66,77.02 105.44,76.8 104.89,76.8 104.74,76.64 104.74,76.28 104.9,76.12 107.63,76.12
  LY3 w0.171: 107.63,76.12 109.87,76.12 110.5,76.76 113.11,76.76 118.76,82.41 118.76,83.91 119.87,85.02 120.45,85.02 120.91,85.47 120.91,91.03 120.08,91.85 120.08,93.82 120.91,94.64 120.91,95.45 121.54,96.09 121.54,100.35 121.3,100.6 121.3,101.75 120.48,102.56 120.48,109.03 119.76,109.75 118.73,109.75 118.39,110.09 118.39,110.69 118.75,111.05 119.11,111.05 119.47,111.41 119.47,112.68 117.97,114.18 117.5,114.66 117.5,116.1 117.33,116.26 116.12,116.26 115.99,116.39 115.99,116.69 116.12,116.82 117.33,116.82 117.5,116.98 117.5,117.21 117.33,117.38 116.49,117.38 116.33,117.54 116.33,117.77 116.49,117.94 117.33,117.94 117.5,118.1 117.5,118.55 117.12,118.92 116.56,118.92 116.08,118.45 116.08,118.44 115.73,118.09 115.73,118.09 115.28,117.64 115.28,116.72 114.93,116.37 114.43,116.37 114.43,116.38 112.88,116.38 111.62,115.11 111.62,113.13 111.49,113 v1(111.49,112.4)
P1_A8: length 77.4
  TOP w0.178: U11.AE15 v2(105.66,78.2) ; J3.77 111.49,120.07 v1(111.49,118.69)
  LY3 w0.102: 107.63,77.8 106.08,77.8 105.68,78.2 v2(105.66,78.2)
  LY3 w0.171: 107.63,77.8 107.66,77.83 112.3,77.83 117.46,82.99 117.46,84.45 119.61,86.6 119.61,90.49 119.44,90.66 119.2,90.66 119.05,90.51 119.05,87.59 118.92,87.46 118.62,87.46 118.49,87.59 118.49,91.02 118.79,91.31 118.79,94.36 119.61,95.18 119.61,95.99 120.25,96.62 120.25,100.14 120.23,100.16 120.23,100.99 119.19,102.03 119.19,107.46 117.03,109.62 117.03,110.5 116.58,110.95 115.4,110.95 115.35,111 113.88,111 112.89,110.01 112.48,110.01 112.36,109.88 110.6,109.88 109.18,111.3 109.18,111.69 109.46,111.97 109.46,112.96 109.18,113.23 109.18,114.94 108.3,115.81 108.3,116.06 108.9,116.66 110.53,116.66 111.32,117.45 111.32,117.94 110.84,118.42 110.84,120.22 111.05,120.43 111.4,120.43 111.65,120.19 111.65,118.85 v1(111.49,118.69)
P1_A9: length 78.6
  TOP w0.102: U11.AD15 v2(104.66,78.2)
  TOP w0.178: J3.76 110.99,114.17 110.99,114.17 v1(110.99,115.98)
  LY4 w0.102: 107.63,77.6 107.11,77.6 106.91,77.8 104.99,77.8 104.66,78.13 v2(104.66,78.2)
  LY4 w0.171: 107.63,77.6 116.28,77.6 124.85,86.17 124.85,88.04 125.36,88.55 125.36,91.31 124.37,92.3 124.37,94.6 125.97,96.2 125.97,101.23 125.84,101.36 125.84,105.55 125.84,105.85 125.5,106.2 125.5,106.98 125.5,108.89 125.25,109.13 125.25,110.74 125.25,111.31 125.25,111.45 122.03,114.67 120.91,114.67 120.45,115.13 119.57,115.13 119.23,115.48 119.23,116.58 115.9,119.9 111.42,119.9 110.93,120.39 110.15,120.39 109.89,120.13 109.89,119.5 110.15,119.25 110.15,118.51 109.88,118.24 109.88,117.65 110.24,117.28 110.76,117.28 110.99,117.06 v1(110.99,115.98)
P1_B0: length 79.6
  TOP w0.178: J3.75 110.99,120.07 v1(110.99,122.27) ; U11.AD14 v2(104.66,77.2)
  LY3 w0.102: v2(104.66,77.2) 104.22,77.2 103.83,77.59 103.5,77.59 103.27,77.36 103.27,76.4 103.8,75.87 104.36,75.87 104.51,75.72 107,75.72 107.45,75.26
  LY3 w0.171: v1(110.99,122.27) 111.34,121.92 111.34,121.31 111.37,121.28 111.37,121.22 112.08,120.51 112.08,118.44 112.33,118.19 112.93,118.19 113.28,118.54 113.28,118.78 113.58,119.08 113.6,119.08 114.54,120.01 117.65,120.01 118.36,119.3 118.36,115.12 119.37,114.11 120.59,114.11 120.88,113.82 120.88,113.02 120.36,112.5 120.36,110.84 121.35,109.85 121.35,102.92 121.76,102.51 121.76,102.51 122.01,102.26 122.01,100.9 122.36,100.54 122.36,95.68 121.77,95.09 121.77,94.29 120.95,93.46 120.95,92.21 122.75,90.41 122.75,85.32 119.62,82.19 119.62,82.19 113.48,76.05 111.14,76.05 110.35,75.26 107.45,75.26
P1_B1: length 78.3
  TOP w0.178: v1(110.49,111.59) 110.49,111.76 110.62,111.9 110.62,112.81 110.49,112.95 J3.74 ; U11.AC14 v2(103.66,77.2)
  LY3 w0.102: 107.49,75.69 107.33,75.85 107.15,75.85 107.08,75.92 104.61,75.92 104.43,76.1 104.13,76.1 103.66,76.56 v2(103.66,77.2)
  LY3 w0.171: 107.49,75.69 110.1,75.69 110.81,76.4 113.33,76.4 119.19,82.26 119.19,83.73 120.04,84.58 120.89,84.58 122.39,86.08 122.39,90.15 120.52,92.03 120.52,93.64 121.34,94.47 121.34,95.27 121.98,95.91 121.98,100.42 121.65,100.75 121.65,102.01 120.91,102.74 120.91,109.67 119.93,110.66 119.93,112.68 120.35,113.1 120.35,113.5 120.17,113.68 119.19,113.68 119,113.87 118.97,113.87 118.27,114.57 118.27,114.6 117.93,114.94 117.93,118.94 117.44,119.43 114.78,119.43 113.11,117.76 112.25,117.76 111.71,117.22 111.71,115.83 111.19,115.31 111.19,113.77 110.58,113.16 110.58,112.04 110.49,111.95 v1(110.49,111.59)
P1_B2: length 77.4
  TOP w0.178: U11.AF15 v2(106.66,78.2) ; J3.73 v1(110.49,117.88)
  LY3 w0.171: v1(110.49,117.88) 110.49,118.11 110.27,118.33 110.27,120.51 110.64,120.88 110.64,121.78 110.39,122.02 110.39,123.56 110.26,123.69 109.8,123.69 109.43,123.31 109.43,122.83 109.68,122.59 109.68,122.05 109.31,121.69 109.31,121.18 108.85,120.72 108.85,118.96 108.03,118.13 108.03,117.56 107.39,116.93 107.39,114.96 108.08,114.26 108.08,112.16 107.88,111.95 107.88,111.16 108.37,110.67 108.9,110.67 108.94,110.63 109.15,110.63 109.5,110.28 109.5,110.07 110.12,109.45 110.99,109.45 112.54,109.45 112.56,109.48 113.31,109.48 113.62,109.79 113.62,110.09 113.94,110.41 114.19,110.41 114.33,110.27 114.33,109.66 114.52,109.48 114.74,109.48 114.74,109.47 115.4,109.47 115.62,109.7 115.62,110.28 115.77,110.43 116.33,110.43 116.59,110.17 116.59,109.44 117.35,108.69 117.35,103.58 118.44,102.49 118.44,102.16 119.82,100.79 119.82,96.8 119.18,96.17 119.18,95.36 118.36,94.54 118.36,91.49 118.06,91.19 118.06,87.41 118.19,87.28 118.19,85.79 117.03,84.63 117.03,83.21 112.02,78.2 v2(106.66,78.2)
P1_B3: length 79
  TOP w0.178: J3.72 109.99,112.76 110.13,112.61 110.13,112.1 109.88,111.85 109.88,111.47 109.69,111.28 109.69,109.91 109.11,109.32 v1(107.68,109.32) ; U11.AF16 v2(106.66,79.2)
  LY3 w0.171: v1(107.68,109.32) 108.8,108.2 108.8,107.47 109.23,107.04 109.97,107.04 110.5,107.57 110.5,108.13 110.96,108.58 112.89,108.58 112.9,108.59 116.12,108.59 116.48,108.22 116.48,103.22 117.58,102.12 117.58,101.74 117.64,101.69 117.64,97.65 117.21,97.22 117.21,96.3 116.34,95.43 116.34,92.1 116.04,91.8 116.04,87.54 116.17,87.41 116.48,87.41 116.61,87.54 116.61,91.29 116.79,91.47 116.97,91.47 117.12,91.32 117.12,86.04 116.04,84.96 115.55,84.96 110.58,79.98 110.58,79.78 110.73,79.63 111.05,79.63 115.59,84.17 115.85,84.17 116.02,83.99 116.02,83.66 111.59,79.22 111.59,79.2 v2(106.66,79.2)
P1_B4: length 79.9
  TOP w0.178: U11.AE16 v2(105.66,79.2) ; v1(109.99,121.49) 109.99,120.07 J3.71
  LY4 w0.102: 107.22,76.73 104.74,76.73 104.66,76.81 104.5,76.81 104.27,77.04 104.27,77.2 103.66,77.81 103.5,77.81 103.21,78.09 103.21,79.32 103.48,79.59 104.98,79.59 105.37,79.2 v2(105.66,79.2)
  LY4 w0.171: v1(109.99,121.49) 111.11,121.49 111.72,120.88 112.22,120.88 112.22,120.88 116.14,120.88 120.66,116.36 121.56,116.36 125.96,111.96 125.96,109.43 126.21,109.18 126.21,106.49 126.56,106.14 126.56,105.26 126.56,101.65 126.68,101.53 126.68,92.93 126.17,92.42 126.17,89.12 126.43,88.86 126.43,86.74 116.42,76.73 107.22,76.73
P1_B5: length 78.8
  TOP w0.178: U11.AD16 v2(104.66,79.2) ; J3.70 109.49,112.1 109.42,112.04 109.42,111.67 109.11,111.35 109.11,110.24 v1(108.9,110.03)
  LY3 w0.102: v2(104.66,79.2) 104.2,79.67 103.44,79.67 103.27,79.49 103.27,78.8 103.4,78.67 104.04,78.67 104.17,78.55 104.17,77.98 104.34,77.8 105.06,77.8 105.21,77.95 105.21,78.46 105.39,78.64 107.28,78.64
  LY3 w0.171: v1(108.9,110.03) 108.9,109.69 109.57,109.02 112.71,109.02 112.72,109.02 116.31,109.02 116.92,108.42 116.92,103.39 118.01,102.3 118.01,101.92 118.07,101.86 118.07,97.47 117.64,97.04 117.64,96.12 116.77,95.26 116.77,92.28 116.9,92.16 117.27,92.16 117.4,92.28 117.4,95.07 118.21,95.88 118.21,96.74 118.67,97.2 118.67,100.54 118.92,100.79 119.15,100.79 119.39,100.55 119.39,96.98 118.75,96.34 118.75,95.54 117.92,94.72 117.92,91.69 117.63,91.39 117.63,87.23 117.76,87.1 117.76,85.97 116.6,84.81 116.6,83.39 111.85,78.64 107.28,78.64
P1_B6: length 77.7
  TOP w0.178: U11.AC16 v2(103.66,79.2) ; J3.69 v1(109.49,118.69)
  LY4 w0.102: 107.63,77.17 107.25,77.17 106.83,77.59 104.3,77.59 104.06,77.84 104.06,78.36 104.01,78.41 104.01,78.44 103.66,78.78 v2(103.66,79.2)
  LY4 w0.171: 107.63,77.17 116.35,77.17 126.05,86.86 126.05,88.71 125.82,88.94 125.82,88.97 125.82,95.5 126.33,96.01 126.33,101.38 126.2,101.51 126.2,105.41 126.2,106 125.85,106.34 125.85,109.03 125.61,109.28 125.61,110.59 125.61,111.71 122.21,115.1 121.09,115.1 120.74,115.45 120.74,115.67 116.08,120.33 111.64,120.33 111.08,120.89 109.58,120.89 109.29,120.6 109.29,118.89 v1(109.49,118.69)
P1_B7: length 77.4
  TOP w0.178: v1(109.28,116) 108.99,115.71 J3.68 ; U11.AC15 v2(103.66,78.2)
  LY3 w0.102: 107.63,77.37 107.21,77.37 106.98,77.6 104.15,77.6 103.66,78.09 v2(103.66,78.2)
  LY3 w0.171: 107.63,77.37 109.97,77.37 110.08,77.47 112.58,77.47 117.89,82.79 117.89,84.27 120.04,86.42 120.04,90.67 119.22,91.49 119.22,94.18 120.04,95 120.04,95.81 120.68,96.45 120.68,100.21 120.58,100.31 120.58,101.24 119.62,102.21 119.62,107.64 117.46,109.8 117.46,111.21 117.28,111.38 115.84,111.38 115.71,111.51 115.71,111.89 115.84,112.02 117.46,112.02 117.85,112.41 117.85,113.08 117.11,113.83 114.94,113.83 114.77,113.65 114.77,113.34 114.9,113.2 116.75,113.2 116.88,113.07 116.88,112.79 116.75,112.66 114.66,112.66 113.58,111.58 113.58,111.31 112.71,110.44 110.8,110.44 109.89,111.35 109.89,111.84 110.06,112.01 110.06,112.13 110.15,112.22 110.15,114.52 110.58,114.96 110.58,115.45 110.21,115.82 109.46,115.82 v1(109.28,116)
P1_B8: length 79.7
  TOP w0.178: v1(108.8,117.91) 108.8,118.91 108.99,119.1 108.99,120.07 J3.67 ; U11.AB18 v2(102.66,81.2)
  LY4 w0.102: 107.63,78.03 107.39,78.03 106.83,78.59 106.28,78.59 106.06,78.82 106.06,79.36 105.83,79.59 105.69,79.59 105.68,79.6 105.42,79.6 105.22,79.8 103.51,79.8 103.27,80.04 103.27,80.31 102.66,80.92 v2(102.66,81.2)
  LY4 w0.171: v1(108.8,117.91) 109.26,117.45 109.26,117.09 110.39,115.96 110.39,115.74 110.74,115.39 111.23,115.39 111.58,115.74 111.58,115.75 111.88,116.04 111.88,117.46 112.4,117.99 112.95,117.99 113.51,118.54 116.65,118.54 118.79,116.4 118.79,115.3 119.4,114.7 120.27,114.7 120.74,114.24 121.62,114.24 124.85,111 124.85,108.99 125.14,108.7 125.14,106.84 125.14,106.84 125.14,106.05 125.35,105.84 125.49,105.7 125.49,101.21 125.62,101.08 125.62,96.37 123.94,94.69 123.94,92.12 124.83,91.23 124.83,88.52 124.5,88.18 124.5,86.32 116.21,78.03 107.63,78.03
P1_B9: length 78.1
  TOP w0.178: J3.66 108.49,112.54 v1(108.83,112.2) ; U11.AF18 v2(106.66,81.2)
  LY4 w0.102: 107.57,79.33 107.36,79.54 107.36,80.99 107.15,81.2 v2(106.66,81.2)
  LY4 w0.171: v1(108.83,112.2) 108.83,113.48 109.19,113.84 110.73,113.84 110.93,114.05 112.06,114.05 112.1,114.09 112.17,114.09 112.62,114.54 114.19,114.54 115.16,115.51 115.42,115.51 115.96,116.04 117.13,116.04 117.5,115.67 117.5,114.76 117.51,114.76 117.51,114.73 118.88,113.36 119.78,113.36 120.2,112.94 120.91,112.94 121.21,112.64 121.21,111.29 121.22,111.29 121.22,111.16 121.89,110.49 121.89,110.33 122.41,109.81 122.41,109.7 123.56,108.56 123.56,100.35 123.94,99.97 123.94,96.72 123.56,96.33 123.56,96.01 122.64,95.1 122.64,93.91 121.81,93.07 121.81,92.41 122.24,91.99 122.24,89.83 122.39,89.68 122.39,89.19 122.24,89.03 122.24,87.17 122.42,87 122.69,87 122.87,87.17 122.87,90.51 123.19,90.83 123.39,90.83 123.51,90.72 123.51,88.71 123.43,88.63 123.43,86.76 121.28,84.61 120.07,84.61 119.19,83.73 119.19,82.52 116,79.33 107.57,79.33
P1_C0: length 78.8
  TOP w0.178: J3.65 108.49,119.52 108.48,119.51 108.48,119.21 108.28,119.01 107.98,119.01 v1(107.56,118.59) ; U11.AE18 v2(105.66,81.2)
  LY4 w0.102: 107.63,78.89 107.33,78.89 107.08,79.14 107.08,80.41 106.9,80.59 105.98,80.59 105.66,80.91 v2(105.66,81.2)
  LY4 w0.171: v1(107.56,118.59) 107.56,118.59 108.18,117.96 108.18,116.32 107.39,115.53 107.39,114.87 107.89,114.37 110.65,114.37 110.8,114.52 111.99,114.52 112.86,115.39 112.86,116.34 113.04,116.53 113.53,116.53 113.74,116.32 113.74,116.3 114.1,115.94 115.19,115.94 116.22,116.97 116.93,116.97 117.93,115.97 117.93,114.94 119.08,113.79 119.96,113.79 120.38,113.37 121.47,113.37 122.42,112.42 122.42,110.3 124.4,108.33 124.4,108.27 124.43,108.24 124.43,105.75 124.78,105.41 124.78,100.92 124.91,100.79 124.91,96.75 124.42,96.26 123.08,94.92 123.08,91.76 123.99,90.85 123.99,88.68 123.78,88.48 123.78,86.61 121.35,84.18 120.25,84.18 119.62,83.55 119.62,82.45 116.07,78.89 107.63,78.89
P1_C1: length 79
  TOP w0.178: J3.64 107.99,115.21 v1(107.99,115.21) ; U11.AC19 v2(103.66,82.2)
  LY4 w0.102: 107.63,78.46 107.24,78.46 106.91,78.8 106.46,78.8 106.26,79 106.26,79.59 106.04,79.81 105.5,79.81 105.27,80.04 105.27,80.16 104.81,80.62 104.33,80.62 104.06,80.89 104.06,81.68 103.66,82.08 v2(103.66,82.2)
  LY4 w0.171: v1(107.99,115.21) 110.31,115.21 110.56,114.95 111.81,114.95 112.43,115.57 112.43,117.23 112.7,117.51 113.72,117.51 113.96,117.26 113.96,116.73 114.32,116.37 115.01,116.37 115.35,116.71 115.35,117.47 115.53,117.65 116.93,117.65 118.36,116.22 118.36,115.12 119.22,114.27 120.09,114.27 120.56,113.8 121.54,113.8 123.72,111.63 123.72,110.99 123.28,110.55 123.28,109.95 124.75,108.48 124.75,108.43 124.79,108.4 124.79,106.69 124.79,105.9 125.13,105.55 125.13,101.07 125.26,100.94 125.26,96.57 124.7,96.01 123.58,94.89 123.58,94.82 123.51,94.74 123.51,91.94 124.42,91.03 124.42,88.61 124.14,88.33 124.14,86.46 121.42,83.75 120.43,83.75 120.05,83.37 120.05,82.38 116.14,78.46 107.63,78.46
P1_C2: length 77.8
  TOP w0.178: J3.63 107.99,120.07 v1(107.99,121.49) ; U11.AF20 v2(106.66,83.2)
  LY4 w0.171: v2(106.66,83.2) 106.66,82.89 107.01,82.54 107.94,82.54 108.71,81.77 108.71,80.97 108.93,80.76 109.9,80.76 110.1,80.96 110.1,81.41 110.57,81.87 116.93,81.87 117.89,82.83 117.89,84.27 120.83,87.21 120.83,88.54 120.48,88.89 120.48,89.19 120.48,89.98 120.83,90.33 120.83,91.56 120.52,91.88 120.52,93.61 121.35,94.44 121.35,96.11 122.87,97.64 122.87,99.53 121.65,100.75 121.65,101.83 122.11,102.29 122.11,108.17 119.92,110.36 119.92,111.35 119.65,111.62 119.35,111.62 118.73,111 118.24,111 117.89,111.35 117.89,111.84 117.92,111.87 117.92,112.49 116.37,114.03 115.51,114.03 114.73,113.25 113.3,113.25 112.34,112.29 112.33,112.29 110.77,110.74 107.31,110.74 106.54,111.51 106.54,112.32 106.53,112.33 106.53,117.98 106.01,118.5 106.01,119.04 105.84,119.21 105.84,119.7 106.19,120.05 106.75,120.05 107.99,121.29 v1(107.99,121.49)
P1_C3: length 78.1
  TOP w0.178: J3.62 v1(107.49,112.4) ; U11.AF19 v2(106.66,82.2)
  LY4 w0.171: v2(106.66,82.2) 107.52,82.2 107.63,82.09 107.63,82.04 108.26,81.41 108.26,80.43 108.5,80.19 115.85,80.19 116.1,80.43 116.1,80.59 115.9,80.79 110.75,80.79 110.62,80.91 110.62,81.31 110.75,81.44 117.1,81.44 118.33,82.66 118.33,84.09 119.72,85.48 120.85,85.48 121.19,85.82 121.19,88.69 120.84,89.04 120.84,89.83 121.19,90.18 121.19,91.81 120.95,92.05 120.95,93.43 121.78,94.26 121.78,95.55 122.52,96.29 122.52,96.3 123.23,97.01 123.23,99.67 122.01,100.9 122.01,101.69 122.52,102.2 122.52,108.38 120.35,110.54 120.35,111.56 119.41,112.5 118.52,112.5 116.51,114.51 115.38,114.51 114.55,113.68 112.98,113.68 112.48,113.18 112.33,113.18 111.29,113.18 111.02,112.91 110.11,112.91 109.94,112.74 109.94,111.83 109.28,111.17 108.28,111.17 107.49,111.96 v1(107.49,112.4)
P1_C4: length 78.4
  TOP w0.178: J3.61 106.87,119.46 v1(106.44,119.46) ; U11.AE19 v2(105.66,82.2)
  LY4 w0.171: v2(105.66,82.2) 105.66,82.06 106.08,81.64 107.43,81.64 107.83,81.23 107.83,79.94 108.01,79.76 115.92,79.76 118.76,82.59 118.76,83.91 119.94,85.09 120.97,85.09 121.55,85.67 121.55,88.84 121.2,89.19 121.2,89.68 121.6,90.09 121.6,92.08 121.38,92.3 121.38,93.25 122.21,94.09 122.21,95.28 122.87,95.94 122.87,96.15 123.58,96.86 123.58,99.82 122.36,101.04 122.36,101.54 122.87,102.05 122.87,108.63 120.78,110.72 120.78,112.24 120.51,112.51 120.01,112.51 119.59,112.93 118.7,112.93 117.07,114.56 117.07,115.3 116.76,115.61 116.13,115.61 115.6,115.07 115.33,115.07 114.37,114.11 112.8,114.11 112.3,113.61 111.11,113.61 110.91,113.41 109.62,113.41 109.46,113.25 109.46,111.98 109.08,111.6 108.58,111.6 108.23,111.95 108.23,113.45 107.84,113.84 107.53,113.84 106.96,114.42 106.96,115.71 107.75,116.5 107.75,117.37 106.44,118.68 v1(106.44,119.46)
P1_C5: length 77.4
  TOP w0.178: U11.AD19 v2(104.66,82.2) ; J3.60 102.32,113.9 102.96,113.26 102.96,112.66 103.62,111.99 103.7,111.99 104.21,111.48 104.21,111.41 104.34,111.28 104.34,110.27 104.35,110.26 104.35,109.37 104.34,109.36 104.34,108.81 104.16,108.63 104.16,108.08 103.65,107.58 102.94,107.58 102.89,107.63 102.14,107.63 101.92,107.85 101.91,107.85 101.76,108.01 100.84,108.01 100.74,108.12 99.48,108.12 99.42,108.18 99.2,108.18 99.04,108.34 98.64,108.34 97.69,109.3 95.97,109.3 95.67,108.99 92.05,108.99 91.96,109.08 91.45,109.08 91.37,108.99 89.67,108.99 v1(89.29,108.61)
  LY4 w0.102: 89.02,90.17 89.26,89.93 89.26,89.04 89.5,88.81 89.92,88.81 90.27,88.46 90.27,88.04 90.5,87.81 90.92,87.81 91.27,87.46 91.27,87.04 91.5,86.81 92.83,86.81 92.93,86.91 93.25,86.91 93.86,86.29 93.86,85.44 94.5,84.81 94.92,84.81 95.27,84.46 95.27,84.04 95.5,83.81 96.21,83.81 96.42,83.6 96.98,83.6 98.2,82.38 100.81,82.38 101.38,81.81 101.86,81.81 102.27,82.22 102.27,82.36 102.5,82.59 103.83,82.59 104.22,82.2 v2(104.66,82.2)
  LY4 w0.171: 89.02,90.17 88.49,90.7 87.17,90.7 86.71,91.16 86.71,91.58 87.31,92.18 87.31,93.49 87.31,93.49 87.31,93.57 86.68,94.2 83.99,94.2 83.3,94.89 83.3,97.73 85.52,99.95 85.52,100.33 85.8,100.6 86.49,100.6 86.77,100.88 86.77,101.27 86.49,101.54 85.8,101.54 85.52,101.82 85.52,104.88 85.8,105.16 86.89,105.16 87.17,105.43 87.17,105.82 86.89,106.1 85.8,106.1 85.52,106.37 85.52,106.99 86.5,107.98 88.66,107.98 v1(89.29,108.61)
P1_C6: length 77.6
  TOP w0.178: J3.59 104.75,120.07 105.47,119.35 105.47,118.48 104.95,117.96 100.32,117.96 100.24,117.88 98.02,117.88 98.01,117.87 v1(97.9,117.87) ; U11.AF21 v2(106.66,84.2)
  LY4 w0.102: v2(106.66,84.2) 106.36,84.2 105.76,83.6 104.42,83.6 104.06,83.96 104.06,84.36 103.62,84.8 101.39,84.8 101.06,84.46 101.06,84.04 100.83,83.81 100.2,83.81 100,83.6 98.7,83.6 98.27,84.04 98.27,84.17 98.07,84.38 98.07,85.38 97.84,85.6 97.42,85.6 97.07,85.95 97.07,86.38 96.84,86.6 96.42,86.6 96.19,86.83 95.85,86.83 95.83,86.81 95.5,86.81 95.27,87.04 95.27,87.46 94.84,87.89 94.84,88.99 94.22,89.61 94.1,89.61 94.05,89.67 94.04,89.67 93.89,89.81 93.73,89.81 93.58,89.96 93.53,89.96 93.32,90.17
  LY4 w0.171: v1(97.9,117.87) 96.71,116.67 96.71,115.37 95.46,114.12 94.91,114.12 94.15,113.37 94.15,112.89 93.27,112.01 93.27,111.15 93.76,110.66 93.76,110.07 94.38,109.44 95.29,109.44 96.12,108.61 96.12,108.57 96.2,108.49 96.2,107.41 96.49,107.13 96.49,107.1 96.89,107.1 97.38,106.62 97.38,106.08 97.65,105.81 98.87,105.81 99.14,105.53 99.14,105.14 98.87,104.87 97.65,104.87 97.38,104.59 97.38,104.21 97.65,103.93 98.87,103.93 99.14,103.65 99.14,103.27 98.87,102.99 97.65,102.99 97.38,102.71 97.38,102.33 97.65,102.05 98.87,102.05 99.14,101.77 99.14,101.39 98.87,101.11 97.65,101.11 97.38,100.84 97.38,100.3 95.83,98.75 94.28,98.75 93.84,98.31 93.84,95.58 93.33,95.07 93.33,92.37 93,92.04 92.92,92.04 92.92,91.52 92.38,90.98 92.38,90.48 92.69,90.17 93.32,90.17
P1_C7: length 77.5
  TOP w0.178: U11.AE21 v2(105.66,84.2) ; J3.58 v1(101.49,112.62)
  LY4 w0.102: v2(105.66,84.2) 105.22,84.2 104.83,83.81 104.5,83.81 104.27,84.04 104.27,84.58 104.5,84.81 104.83,84.81 105.06,85.04 105.06,85.56 105.26,85.76 105.26,86.49 105.16,86.59 101.5,86.59 101.26,86.35 101.26,85.95 100.91,85.6 100.51,85.6 100.27,85.36 100.27,85.25 99.83,84.81 99.5,84.81 99.27,85.04 99.27,85.46 98.92,85.81 98.5,85.81 98.27,86.04 98.27,86.46 97.92,86.81 97.5,86.81 97.27,87.04 97.27,87.46 96.92,87.81 96.5,87.81 96.27,88.04 96.27,88.27 96.07,88.48 96.07,89.37 95.7,89.74 95.38,89.74
  LY4 w0.171: v1(101.49,112.62) 102.18,113.31 102.18,115.57 102.05,115.7 100.54,115.7 100.41,115.57 100.41,115.21 100.58,115.04 101.43,115.04 101.6,114.88 101.6,114.65 101.43,114.49 100.58,114.49 100.41,114.32 100.41,114.09 100.58,113.93 101.43,113.93 101.6,113.76 101.6,113.53 101.43,113.37 100.58,113.37 100.41,113.2 100.41,111.41 100.24,111.23 100.24,111.22 99.48,110.46 99.48,109.15 100.04,108.59 100.51,108.59 100.98,108.12 100.98,106.03 102.92,104.09 102.92,103.06 102.84,102.98 102.84,102.34 102.98,102.19 102.98,97.43 103.11,97.3 103.39,97.3 103.51,97.43 103.51,101.1 103.66,101.25 103.93,101.25 104.1,101.08 104.1,97.58 104.34,97.34 104.34,96.54 104.18,96.39 103.7,96.39 103.47,96.15 103.47,95.06 103.24,94.83 101.29,94.83 100.99,95.13 100.83,95.13 100.43,95.13 99.41,96.15 98.21,96.15 97.97,95.91 97.97,95.62 97.74,95.39 96.5,95.39 95.42,94.31 95.42,93.79 95.06,93.43 94.75,93.43 94.4,93.08 94.4,92.59 94.74,92.25 94.74,90.38 95.38,89.74
P1_C8: length 78.4
  TOP w0.178: J3.57 101.49,121.84 102.06,122.41 102.06,123.3 101.7,123.66 101.49,123.66 101.25,123.89 100.36,123.89 v1(100.1,124.15) ; U11.AE20 v2(105.66,83.2)
  LY4 w0.102: v2(105.66,83.2) 105.31,83.2 104.91,82.8 104.36,82.8 104.2,82.95 104.2,83.22 103.83,83.59 102.5,83.59 102.06,83.15 102.06,83.04 101.83,82.81 100.35,82.81 100.34,82.79 98.37,82.79 97.25,83.9 97.25,84.19 96.84,84.6 96.42,84.6 96.21,84.81 95.5,84.81 95.27,85.04 95.27,85.46 94.92,85.81 94.5,85.81 94.27,86.04 94.27,86.46 93.25,87.48 93.25,87.7 93.15,87.81 91.5,87.81 91.27,88.04 91.27,88.65 91.11,88.81 90.5,88.81 90.27,89.04 90.27,89.66
  LY4 w0.171: v1(100.1,124.15) 100.1,124.14 100.1,124.13 99.17,124.13 98.82,123.78 97.72,123.78 97.54,123.6 96.84,123.6 96.51,123.93 96.51,123.93 96.48,123.95 91.91,123.95 91.45,123.49 90.92,123.49 90.35,122.92 90.35,121.33 90.31,121.3 90.31,118.08 91.24,117.15 91.24,116.1 91.12,115.98 91.12,115.85 90.87,115.6 90.87,108.01 90.6,107.75 90.6,107.34 90.33,107.06 90.1,107.06 89.82,106.79 89.82,106.4 90.1,106.12 90.33,106.12 90.6,105.85 90.6,105.46 90.33,105.18 90.1,105.18 89.82,104.91 89.82,104.52 90.1,104.24 90.33,104.24 90.6,103.97 90.6,102.28 90.33,102.01 89.86,102.01 89.58,101.73 89.58,101.34 89.86,101.07 90.33,101.07 90.6,100.79 90.6,100.4 90.33,100.13 89.86,100.13 89.58,99.85 89.58,99.46 89.86,99.19 90.33,99.19 90.6,98.91 90.6,98.52 90.33,98.25 89.86,98.25 89.58,97.97 89.58,97.58 89.86,97.31 90.33,97.31 90.6,97.03 90.6,96.57 89.74,95.7 89.74,93 90.27,92.46 90.27,89.66
P1_C9: length 77.5
  TOP w0.178: J3.56 100.99,113.01 100.79,112.81 100.79,112.28 101.07,111.99 101.81,111.99 102.08,112.26 102.08,112.27 102.7,112.27 103.88,111.09 103.88,110.08 103.89,110.07 103.89,109.56 103.88,109.55 103.88,109 103.33,108.45 103.2,108.45 102.84,108.09 102.33,108.09 102.11,108.31 102.1,108.31 101.95,108.46 101.03,108.46 100.93,108.57 99.67,108.57 99.44,108.8 98.83,108.8 97.8,109.83 95.72,109.83 95.36,109.47 92.32,109.47 v1(91.81,109.98) ; U11.AD20 v2(104.66,83.2)
  LY4 w0.102: 90.7,89.72 91.27,89.15 91.27,89.04 91.5,88.81 92.21,88.81 92.42,88.6 93.82,88.6 94.06,88.36 94.06,88 93.92,87.86 93.92,87.1 94.42,86.6 94.84,86.6 95.07,86.38 95.07,85.95 95.42,85.6 96.05,85.6 96.27,85.38 96.27,85.04 96.5,84.81 96.92,84.81 97.46,84.27 97.46,83.99 98.45,82.99 100.25,82.99 100.42,83.16 101.04,83.16 101.48,83.6 102.04,83.6 102.24,83.81 103.92,83.81 104.53,83.2 v2(104.66,83.2)
  LY4 w0.171: 90.7,89.72 90.7,92.78 90.31,93.17 90.31,95.16 91.25,96.1 91.25,96.27 91.53,96.55 92.42,96.55 92.69,96.83 92.69,97.21 92.42,97.49 91.53,97.49 91.25,97.76 91.25,98.15 91.53,98.43 92.42,98.43 92.69,98.7 92.69,99.09 92.42,99.37 91.53,99.37 91.25,99.64 91.25,100.03 91.53,100.31 92.42,100.31 92.69,100.58 92.69,100.97 92.42,101.25 91.53,101.25 91.25,101.52 91.25,101.91 91.53,102.19 92.42,102.19 92.69,102.46 92.69,102.85 92.42,103.13 91.53,103.13 91.25,103.4 91.25,103.79 91.53,104.07 92.42,104.07 92.69,104.34 92.69,104.73 92.42,105.01 91.53,105.01 91.25,105.28 91.25,105.67 91.53,105.95 92.42,105.95 92.69,106.22 92.69,106.61 92.42,106.89 91.53,106.89 91.25,107.16 91.25,107.55 91.53,107.83 92.42,107.83 92.69,108.1 92.69,108.49 92.42,108.77 91.53,108.77 91.25,109.04 91.25,109.43 v1(91.81,109.98)
P1_HSYNC: length 78.8
  TOP w0.178: TP12.1 112.35,105.94 116.94,105.94 117.06,106.07 117.06,106.68 116.94,106.81 112.72,106.81 112.59,106.93 112.59,107.64 112.72,107.77 116.14,107.77 116.27,107.9 116.27,108.51 116.14,108.64 113.68,108.64 113.49,108.83 113.49,109.63 113.36,109.75 111.59,109.75 111.46,109.88 111.46,110.65 111.59,110.77 113.36,110.77 113.49,110.9 113.49,113.9 J3.86 ; U11.AD21 v2(104.66,84.2)
  LY4 w0.102: v2(104.66,84.2) 105.26,84.8 105.26,85.47 105.39,85.6 105.93,85.6 106.06,85.72 106.06,86.44 106.16,86.54 106.16,87.27 106.48,87.59 106.83,87.59 106.85,87.57 107.45,87.57
  LY4 w0.171: 107.45,87.57 107.63,87.75 108.41,87.75 109.22,86.94 113.09,86.94 113.34,87.18 113.34,91.94 113.63,92.23 113.91,92.23 114.16,91.97 114.16,88.11 114.54,87.73 114.77,87.73 114.93,87.89 114.93,94.88 115.35,95.3 116.5,95.3 116.83,95.63 116.83,100.1 115.3,101.63 113.21,101.63 112.22,102.62 112.22,103.69 111.9,104 109.84,104 109.64,104.21 109.64,105.6 109.76,105.72 110.22,105.72 110.35,105.6 110.35,104.81 110.47,104.69 111.1,104.69 TP12.1
P1_VSYNC: length 78
  TOP w0.178: U11.AC20 v2(103.66,83.2) ; J3.55 100.99,118.94 101.23,118.69 104.41,118.69 v1(104.64,118.92)
  LY4 w0.102: 107.63,83.31 107.29,83.31 106.95,83.66 106.56,83.66 106.27,83.36 106.27,83.22 105.64,82.59 104.27,82.59 104,82.87 104,82.88 103.68,83.2 v2(103.66,83.2)
  LY4 w0.171: v1(104.64,118.92) 106.01,117.56 106.01,117.02 106.11,116.92 106.11,111.21 107.34,109.97 108.12,109.97 108.66,109.44 110.08,109.44 111.65,111 114.73,111 114.74,111 116.79,111 117.16,110.63 117.16,107.31 TP14.1 118.82,106.89 118.82,109.15 119.21,109.55 120,109.55 120.87,108.69 120.87,101.55 120.1,100.79 120.1,87.09 116.33,83.31 107.63,83.31
P1P1V: length 144.7
  TOP w0.178: U11.N21 v2(92.66,84.2) ; U11.F13 v2(85.66,75.2) ; U11.AA8 v2(101.66,70.2) ; U11.K21 v2(89.66,84.2) ; U11.H6 v2(87.66,68.2) ; U11.U6 v2(97.66,68.2) ; U11.F7 v2(85.66,69.2) ; U11.F10 v2(85.66,72.2) ; U11.G21 v2(86.66,84.2) ; U11.AA11 v2(101.66,73.2) ; U11.Y6 v2(100.66,68.2) ; U11.F19 v2(85.66,82.2) ; U11.P6 v2(93.66,68.2) ; U11.F16 v2(85.66,79.2) ; U11.L6 v2(90.66,68.2)
  TOP w0.254: U11.T16 v2(96.66,79.2) ; 93.18,82.88 93.16,82.9 U11.N21 ; 88.16,69.54 88.16,69.54 U11.H6 ; U11.K21 90.16,82.86 90.17,82.86 ; U11.F13 86.99,75.7 87.02,75.72 ; U11.L16 v2(90.66,79.2) ; 100.16,69.58 100.16,69.58 U11.Y6 ; U11.L11 v2(90.66,73.2) ; U11.T11 v2(96.66,73.2) ; 87.02,78.69 87.01,78.7 U11.F16 ; U11.AA11 100.25,73.7 100.18,73.77 ; 87.04,69.7 U11.F7 ; 87.15,82.82 87.16,82.83 U11.G21 ; 100.24,79.71 100.25,79.7 U11.AA17 v2(101.66,80.2) ; 86.99,81.71 86.97,81.7 U11.F19 ; 99.15,82.86 99.16,82.87 U11.W21 v2(99.66,84.2) ; U11.AA8 100.19,70.7 100.11,70.78 ; U11.U6 97.16,69.58 97.11,69.63 ; 100.17,76.86 100.33,76.7 U11.AA14 v2(101.66,77.2) ; 96.22,82.95 96.16,83.01 U11.T21 v2(96.66,84.2) ; v2(101.66,83.2) U11.AA20 100.45,82.7 100.41,82.66 ; U11.L6 91.16,69.47 91.17,69.48 ; U11.F10 86.94,72.7 86.94,72.7 ; U11.P6 94.16,69.51 94.11,69.56
  TOP w0.508: TP43.1 135.45,53.72 135.57,53.59 ; TP43.1 135.57,54.8 135.57,53.59 ; TP43.1 134.94,54.93 134.49,55.37 ; TP43.1 136.46,54.93 136.53,54.99 ; 141.6,83.82 142.56,84.77 J19.1 ; 135.57,53.59 C27.2 135.52,52.88 R25.2 132.5,52.67 132.5,51.85 v1(132.21,51.56) ; J19.1 140.97,85.09 ; J19.1 144.49,83.16 144.49,79.05 143.89,78.46 143.83,78.36 143.78,78.25 143.75,78.13 143.75,78.07 143.75,77.92 141.44,75.61 133.59,75.61 v1(132.58,74.6) 127.7,69.72 v1(127.44,69.72)
  LY5PWR w0.508: 134.15,53.67 134.18,53.67 TP43.1 ; 141.79,84.32 J19.1 ; J19.1 143.33,85.86 ; J19.1 143.33,84.32 ; J19.1 141.79,85.86 ; 136.71,53.7 136.67,53.7 TP43.1 ; TP43.1 133.88,56.49 133.87,56.49 ; TP43.1 136.18,55.66 136.2,55.66
  BOTTOM w0.254: C592.1 96.24,79.97 96.48,79.73 96.48,79.38 v2(96.66,79.2) ; C620.1 96.72,73.14 v2(96.66,73.2)
  BOTTOM w0.381: v2(85.66,79.2) 86.2,79.2 C604.1 ; C596.1 92.67,84.12 92.66,84.13 v2(92.66,84.2) ; C591.1 98.83,83.39 99.48,84.04 99.5,84.04 v2(99.66,84.2) ; C587.1 101.47,80.01 v2(101.66,80.2) ; v2(96.66,84.2) 96.66,83.85 C594.1 ; v2(85.66,75.2) 86.04,75.58 C634.1 ; v2(87.66,68.2) 87.77,68.2 C628.1 ; v2(85.66,72.2) 86.28,72.2 C633.1 ; v2(90.66,68.2) 90.66,68.87 C626.1 ; v2(101.66,83.2) 101.51,83.05 101.51,83.04 101.02,82.55 C586.1 ; C602.1 86.46,81.41 v2(85.66,82.2) ; v2(101.66,70.2) 101.66,70.35 101.25,70.76 101.14,70.76 C616.1 ; C618.1 97.66,68.5 v2(97.66,68.2) ; C598.1 90.69,79.23 v2(90.66,79.2) ; v2(85.66,69.2) 85.85,69.39 85.85,69.55 C631.1 ; v2(101.66,73.2) 101.31,73.2 C612.1 ; C599.1 89.66,83.58 v2(89.66,84.2) ; v2(100.66,68.2) 99.81,69.05 C614.1 ; R682.2 132.73,59.56 132.11,60.18 131.44,60.18 v1(130.82,59.56) ; C622.1 94.18,68.58 94.04,68.58 v2(93.66,68.2)
  BOTTOM w0.508: C570.1 86.66,84.2 v2(86.66,84.2) ; 134.78,55.59 TP43.1 ; TP43.1 136.11,55.59 ; TP43.1 136.11,54.27 ; TP43.1 134.78,54.27 ; TP43.1 135.85,54.93 136.26,54.51 137.29,54.51 137.29,54.43 137.73,53.98 138.12,53.98 138.5,53.59 145.1,53.59 145.11,53.58 147.52,53.58 148.32,54.38 148.32,55.97 ; C625.1 90.6,73.14 v2(90.66,73.2) ; C667.2 131.25,58.7 131.25,58.74 131.06,58.93 131.06,59.32 v1(130.82,59.56) ; 148.32,55.97 R678.2 ; 148.32,55.97 148.92,55.37 149.91,55.37 150.52,54.76 v1(150.7,54.76) ; R526.1 v1(100.6,97.16) ; v1(132.21,51.56) 132.5,51.85 132.5,53.57 131.25,54.81 C668.1
  vias: v1(112.42,75.1) v1(119.16,77.76) v1(119.84,78.51) v1(124.23,76.94) v1(124.27,75.95) v1(125.2,76.07) v1(130.81,60.48) v1(133.12,51.56) v1(133.43,74.26) v2(100.44,77.15)
P1P2V_PMD2: length 114.1
  TOP w0.508: v1(181.55,119.27) 180.72,119.27 179.51,120.48 179.51,123.03 174.97,127.57 168.22,127.57 165.33,130.46 154.35,130.46 v1(150.84,126.95)
  TOP w0.762: C17.2 TP16.1
  LY4 w0.508: J19.3 144.88,83.41 140.77,83.41 138.59,85.6 138.59,86.48 137.6,87.47 137.6,92.04 134.24,95.4 TP16.1
  BOTTOM w0.508: R525.2 147.78,107.73 147.41,107.36 136.96,107.36 135.9,106.3 TP16.1 ; R525.2 R523.2 ; R525.2 147.78,110.67 146.6,111.84 146.6,119.07 150.84,123.3 v1(150.84,126.95) ; v1(181.55,119.27) 180.39,118.11 C510.2 180.04,118.45 R509.2
P1P8V: length 118.9
  TOP w0.178: U11.P5 v2(93.66,67.2) ; v2(85.66,67.23) 86.14,67.7 U11.F5 ; U11.G6 v2(86.66,68.2) ; U11.N6 v2(92.66,68.2) ; U11.H21 v2(87.66,84.2) ; U11.AA13 v2(101.66,75.2) ; U11.T5 v2(96.66,67.2) ; U11.W6 v2(99.66,68.2) ; U11.F14 v2(85.66,77.2) ; U11.H5 v2(87.66,67.2) ; U11.M5 v2(91.66,67.2) ; U11.AA5 v2(101.66,67.2) ; U11.K6 v2(89.66,68.2) ; U11.C1 v2(82.66,63.2) ; U11.T6 v2(96.66,68.2) ; U11.AE1 v2(105.66,63.2)
  TOP w0.254: U11.U21 v2(97.16,81.84) ; v2(94.66,84.2) U11.P21
  TOP w0.508: TP48.1 141.19,41.62 141.19,38.61 142.43,37.36 149.62,37.36 151.35,39.09 v1(151.35,41.78)
  LY3 w0.508: TP48.1 143.76,44.24 144.38,44.86 144.38,46.49 137.29,53.59 137.29,55.06 137.43,55.2 137.43,59.04 137.63,59.25 137.63,64.22 139.9,66.5 139.9,68.06 139.88,68.09 139.88,69.16 139.52,69.52 139.52,74.1 140.63,75.2 140.63,85.5 142.56,87.43 J18.1
  LY5PWR w0.508: J18.1 143.33,88.13 ; J18.1 141.79,89.67 ; J18.1 141.79,88.13 ; J18.1 143.33,89.67
  BOTTOM w0.381: C661.1 82.63,63.16 v2(82.66,63.2) ; C605.1 86.17,77.2 v2(85.66,77.2) ; C569.1 93.9,84.2 v2(94.66,84.2) ; C623.1 93.54,70.15 C624.1 92.66,68.74 v2(92.66,68.2) ; v2(89.66,68.2) 89.73,68.26 C627.1 ; v2(93.66,67.2) 94.04,67.58 C659.1 ; C656.1 105.61,63.15 v2(105.66,63.2) ; v2(99.66,68.2) 99,68.87 C617.1 ; C589.1 99.4,75.07 101.38,75.07 101.61,75.15 v2(101.66,75.2) ; C632.1 86.66,69.09 v2(86.66,68.2) ; v2(87.66,84.2) 87.91,84.2 88.44,83.67 88.49,83.67 C600.1 ; v2(96.66,67.2) v2(96.66,68.2) 96.71,68.25 C619.1 96.58,69.08 C621.1
  BOTTOM w0.508: C658.1 v1(97.46,61.23) ; C670.1 v1(85.47,60.9) ; R717.1 v1(151.35,41.78) ; C593.1 97.1,81.79 v2(97.16,81.84) ; v1(80.81,61.19) 80.8,61.19 v1(80.81,61.19) ; v1(80.81,61.19) 80.81,61.2 80.8,61.2 80.8,61.2 80.84,61.2 80.84,60.98 80.13,60.27 C671.1 ; C669.1 v1(91.76,61.04) ; C657.1 v1(100.25,61.23) ; C660.1 v1(94.17,61.23)
  vias: v2(93.66,63.2)
P1P8V_PMD2: length 17.3
  TOP w0.762: TP22.1 149.57,96.9 v1(151.99,94.49) 146.56,89.06 J18.3
  BOTTOM w0.508: R576.1 v1(151.99,94.49)
P2_A0: length 78.6
  TOP w0.178: v1(98.49,124.38) 98.49,123.28 98.76,123.01 98.76,122.27 98.42,121.93 98.42,121.05 98.49,120.98 J3.45 ; U11.AB19 v2(102.66,82.2)
  LY4 w0.102: 88.39,90.17 89.06,89.51 89.06,88.96 89.42,88.6 89.84,88.6 90.07,88.38 90.07,87.95 90.42,87.6 90.84,87.6 91.07,87.38 91.07,86.95 91.42,86.6 92.91,86.6 93.01,86.7 93.17,86.7 93.66,86.21 93.66,85.36 94.42,84.6 94.84,84.6 95.07,84.38 95.07,83.95 95.42,83.6 96.13,83.6 96.33,83.4 96.89,83.4 98.11,82.18 100.72,82.18 101.3,81.6 101.94,81.6 102.54,82.2 v2(102.66,82.2)
  LY4 w0.171: v1(98.49,124.38) 98.31,124.38 97.57,125.12 89.54,125.12 89.02,124.6 88.97,124.6 87.37,122.99 87.37,113.54 86.87,113.04 86.87,108.84 85.17,107.14 85.17,100.1 82.95,97.88 82.95,97.55 82.48,97.08 82.48,94.42 83.06,93.85 86.53,93.85 86.95,93.42 86.95,93.34 86.96,93.34 86.96,92.84 86.95,92.84 86.95,92.56 86.65,92.26 86.07,92.26 85.9,92.08 85.9,91.47 86.63,90.74 87.03,90.34 88.23,90.34 88.39,90.17
P2_A1: length 78.2
  TOP w0.178: v1(102.64,111.33) 102,110.69 101.88,110.69 101.87,110.71 100.98,110.71 100.97,110.69 100.45,110.69 100.39,110.63 99.59,110.63 99.02,111.19 99.02,112.16 98.31,112.87 98.21,112.87 98.03,113.05 98.03,113.15 97.99,113.2 J3.44 ; U11.AE23 v2(105.66,86.2)
  LY3 w0.102: v2(105.66,86.2) 105.66,86.17 105.06,85.57 105.06,79.93 105.37,79.61 107.15,79.61
  LY3 w0.171: 107.15,79.61 109.6,79.61 115.37,85.39 115.86,85.39 116.39,85.91 116.39,86.58 115.61,87.36 115.61,91.98 115.91,92.28 115.91,95.61 116.78,96.48 116.78,97.4 117.15,97.77 117.15,101.94 115.75,103.34 115.75,105.87 116.05,106.17 116.05,107.76 115.66,108.16 113.07,108.16 113.07,108.15 111.75,108.15 111.54,107.95 111.54,106.38 112.42,105.51 112.42,104.71 111.31,103.6 111.31,102.58 110.93,102.2 109.87,102.2 108.87,103.2 108.87,103.29 108.17,103.99 108.05,103.99 107.48,104.56 107.47,104.56 106.67,105.36 106.67,105.38 106.4,105.64 106.4,107.33 105.37,108.36 105.37,109.5 105.37,110.82 104.86,111.33 v1(102.64,111.33)
P2_A2: length 78.9
  TOP w0.178: U11.AD22 v2(104.66,85.2) ; v1(98.15,122.75) 98.15,122.74 97.96,122.56 97.96,120.86 97.99,120.84 J3.43
  LY4 w0.102: 94.34,90.17 95.27,89.24 95.27,88.04 95.5,87.81 96.21,87.81 96.42,87.6 96.84,87.6 97.07,87.38 97.07,86.95 97.42,86.6 97.84,86.6 98.07,86.38 98.07,85.95 98.42,85.6 98.84,85.6 99.07,85.38 99.07,84.95 99.41,84.6 99.91,84.6 100.11,84.81 100.83,84.81 101.06,85.04 101.06,85.46 101.4,85.81 102.83,85.81 102.85,85.83 103.19,85.83 103.42,85.59 103.83,85.59 104.22,85.2 v2(104.66,85.2)
  LY4 w0.171: 94.34,90.17 94.31,90.2 94.31,92.18 94.04,92.44 94.04,93.23 94.91,94.1 94.91,94.5 96.32,95.91 97.18,95.91 97.35,96.09 97.64,96.09 98.06,96.51 99.67,96.51 100.69,95.49 101.14,95.49 101.37,95.26 102.83,95.26 103.04,95.47 103.04,96.77 102.55,97.25 102.55,102.01 102.41,102.16 102.41,103.99 100.44,105.96 100.44,107.57 99.05,108.97 99.05,110.73 99.98,111.66 99.98,114.24 99.79,114.43 99.07,114.43 98.86,114.23 98.86,113.54 97.3,111.97 97.3,110.85 97.39,110.76 97.39,110.09 97.19,109.89 96.57,109.89 95.58,110.89 95.58,113.02 97.57,115.01 97.57,116.08 98.93,117.44 98.93,120.23 99.58,120.88 99.75,120.88 99.91,121.05 100.8,121.05 100.92,121.17 100.92,121.54 100.8,121.66 100.22,121.66 99.74,122.14 98.83,122.14 98.22,122.75 v1(98.15,122.75)
P2_A3: length 77.5
  TOP w0.178: U11.AC21 v2(103.66,84.2) ; J3.42 97.49,114.76 97.15,115.1 97.15,115.42 96.22,116.34 94.81,116.34 v1(94.75,116.28)
  LY4 w0.102: 92.51,89.74 92.64,89.61 93.81,89.61 94.5,88.92 94.5,87.83 94.73,87.6 94.84,87.6 95.07,87.38 95.07,86.95 95.42,86.6 95.93,86.6 96.27,86.27 96.27,86.04 96.5,85.81 96.92,85.81 97.27,85.46 97.27,85.04 97.86,84.44 97.86,84.16 98.62,83.4 100.08,83.4 100.29,83.6 100.91,83.6 101.26,83.95 101.26,84.35 101.5,84.59 102.3,84.59 102.32,84.58 102.49,84.58 102.5,84.59 102.83,84.59 103.22,84.2 v2(103.66,84.2)
  LY4 w0.171: 92.51,89.74 91.95,90.3 91.95,91.36 92.33,91.74 92.33,92.39 92.85,92.39 92.98,92.52 92.98,95.22 93.48,95.73 93.48,98.46 94.13,99.1 95.37,99.1 95.85,99.59 95.85,99.89 96.12,100.17 96.75,100.17 97.02,100.44 97.02,100.83 96.75,101.11 96.12,101.11 95.85,101.38 95.85,101.77 96.12,102.05 96.75,102.05 97.02,102.32 97.02,102.71 96.75,102.99 96.12,102.99 95.85,103.26 95.85,103.65 96.12,103.93 96.75,103.93 97.02,104.2 97.02,104.59 96.75,104.87 96.12,104.87 95.85,105.14 95.85,105.53 96.12,105.81 96.75,105.81 97.02,106.08 97.02,106.47 96.75,106.75 96.12,106.75 95.85,107.02 95.85,108.34 95.18,109.01 94.2,109.01 94.04,109.17 93.33,109.89 93.33,110.45 92.81,110.97 92.81,112.16 93.72,113.07 93.72,113.54 94.78,114.6 95.33,114.6 96.27,115.55 96.27,117.55 96.34,117.62 96.34,118.12 96.27,118.18 96.27,119.18 96.48,119.38 96.48,120.6 96.23,120.85 95.98,120.85 95.85,120.72 94.52,120.72 94.23,120.43 93.87,120.43 93.61,120.18 93.61,119.93 93.81,119.73 94.23,119.73 94.54,120.04 95.69,120.04 95.82,119.91 95.82,119.48 95.69,119.35 94.71,119.35 94.49,119.14 93.83,119.14 93.61,118.92 93.61,118.69 94.75,117.55 v1(94.75,116.28)
P2_A4: length 79.6
  TOP w0.178: U11.AB20 v2(102.66,83.2) ; J3.41 v1(97.49,124.36)
  LY4 w0.102: v2(102.66,83.2) 102.52,83.2 101.92,82.6 100.44,82.6 100.42,82.59 98.28,82.59 97.06,83.81 96.5,83.81 96.27,84.04 96.27,84.42 96.09,84.6 95.42,84.6 95.07,84.95 95.07,85.35 94.82,85.6 94.42,85.6 94.07,85.95 94.07,86.38 92.84,87.6 91.42,87.6 91.07,87.95 91.07,88.35 90.82,88.6 90.42,88.6 90.06,88.96 90.06,89.37 89.73,89.7 89.73,89.94
  LY4 w0.171: 89.73,89.94 89.73,91.91 89.13,92.5 89.13,94.56 88.86,94.84 87.78,94.84 87.51,95.11 87.51,95.5 87.78,95.78 88.86,95.78 89.13,96.05 89.13,96.44 88.86,96.72 87.78,96.72 87.51,96.99 87.51,97.38 87.78,97.66 88.86,97.66 89.13,97.93 89.13,98.32 88.86,98.6 87.78,98.6 87.51,98.87 87.51,99.26 87.78,99.54 88.86,99.54 89.13,99.81 89.13,107.15 89.94,107.97 89.94,109.42 89.24,110.13 89.24,111.29 89.39,111.44 89.39,112.74 89.93,113.28 89.93,115.85 89.88,115.9 89.88,120.63 89.58,120.94 89.3,120.94 89.09,120.72 89.09,119.16 88.96,119.03 88.67,119.03 88.54,119.16 88.54,120.94 88.15,121.33 88.15,121.83 88.81,122.49 88.81,123.34 89.71,124.24 90.47,124.24 90.78,123.93 91.28,123.93 91.81,124.46 96.58,124.46 96.69,124.36 v1(97.49,124.36)
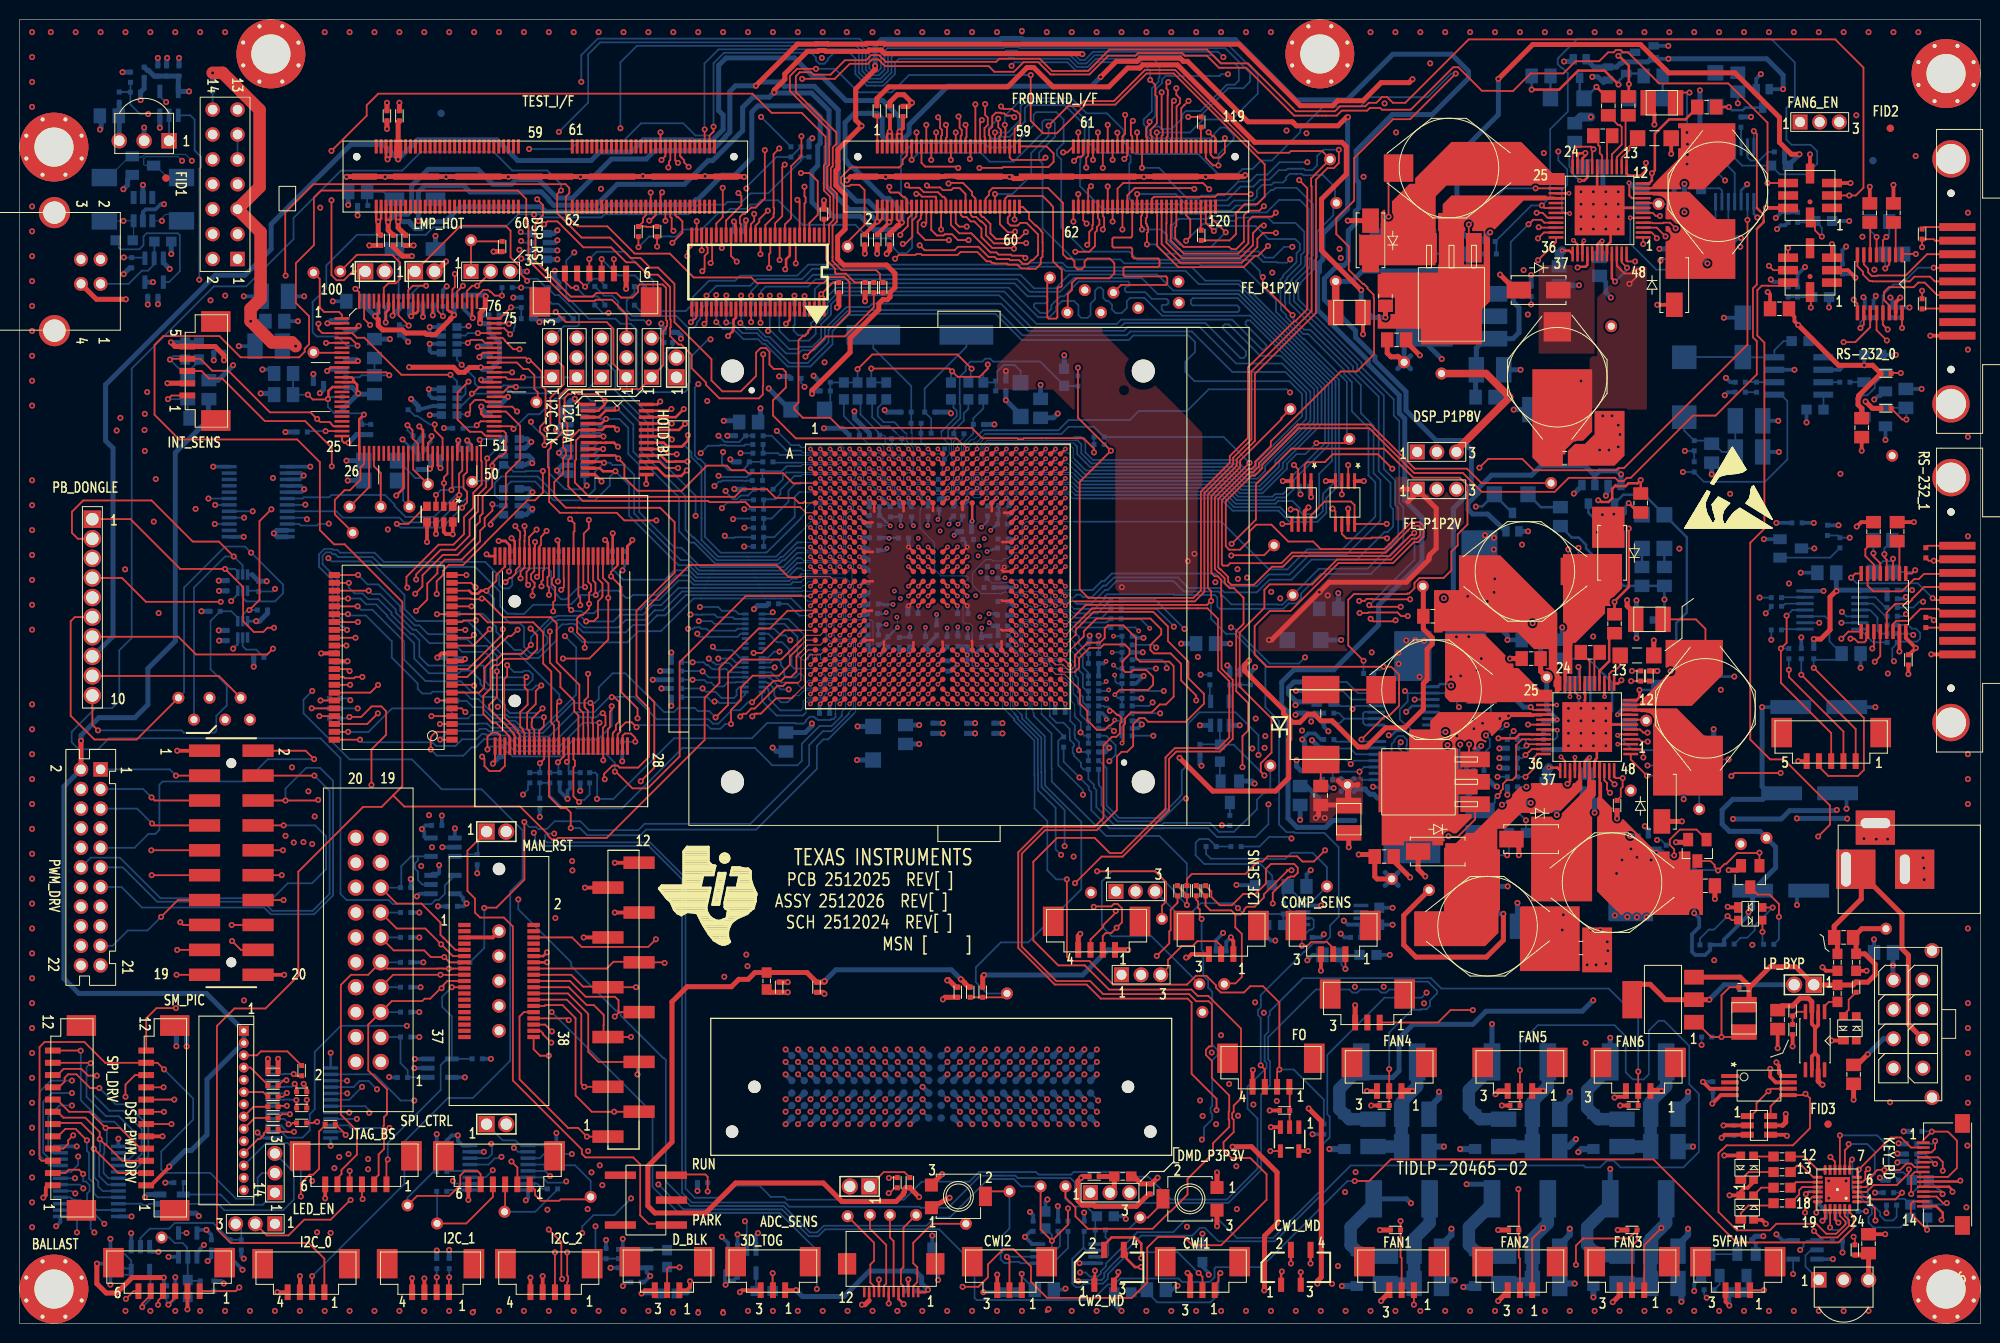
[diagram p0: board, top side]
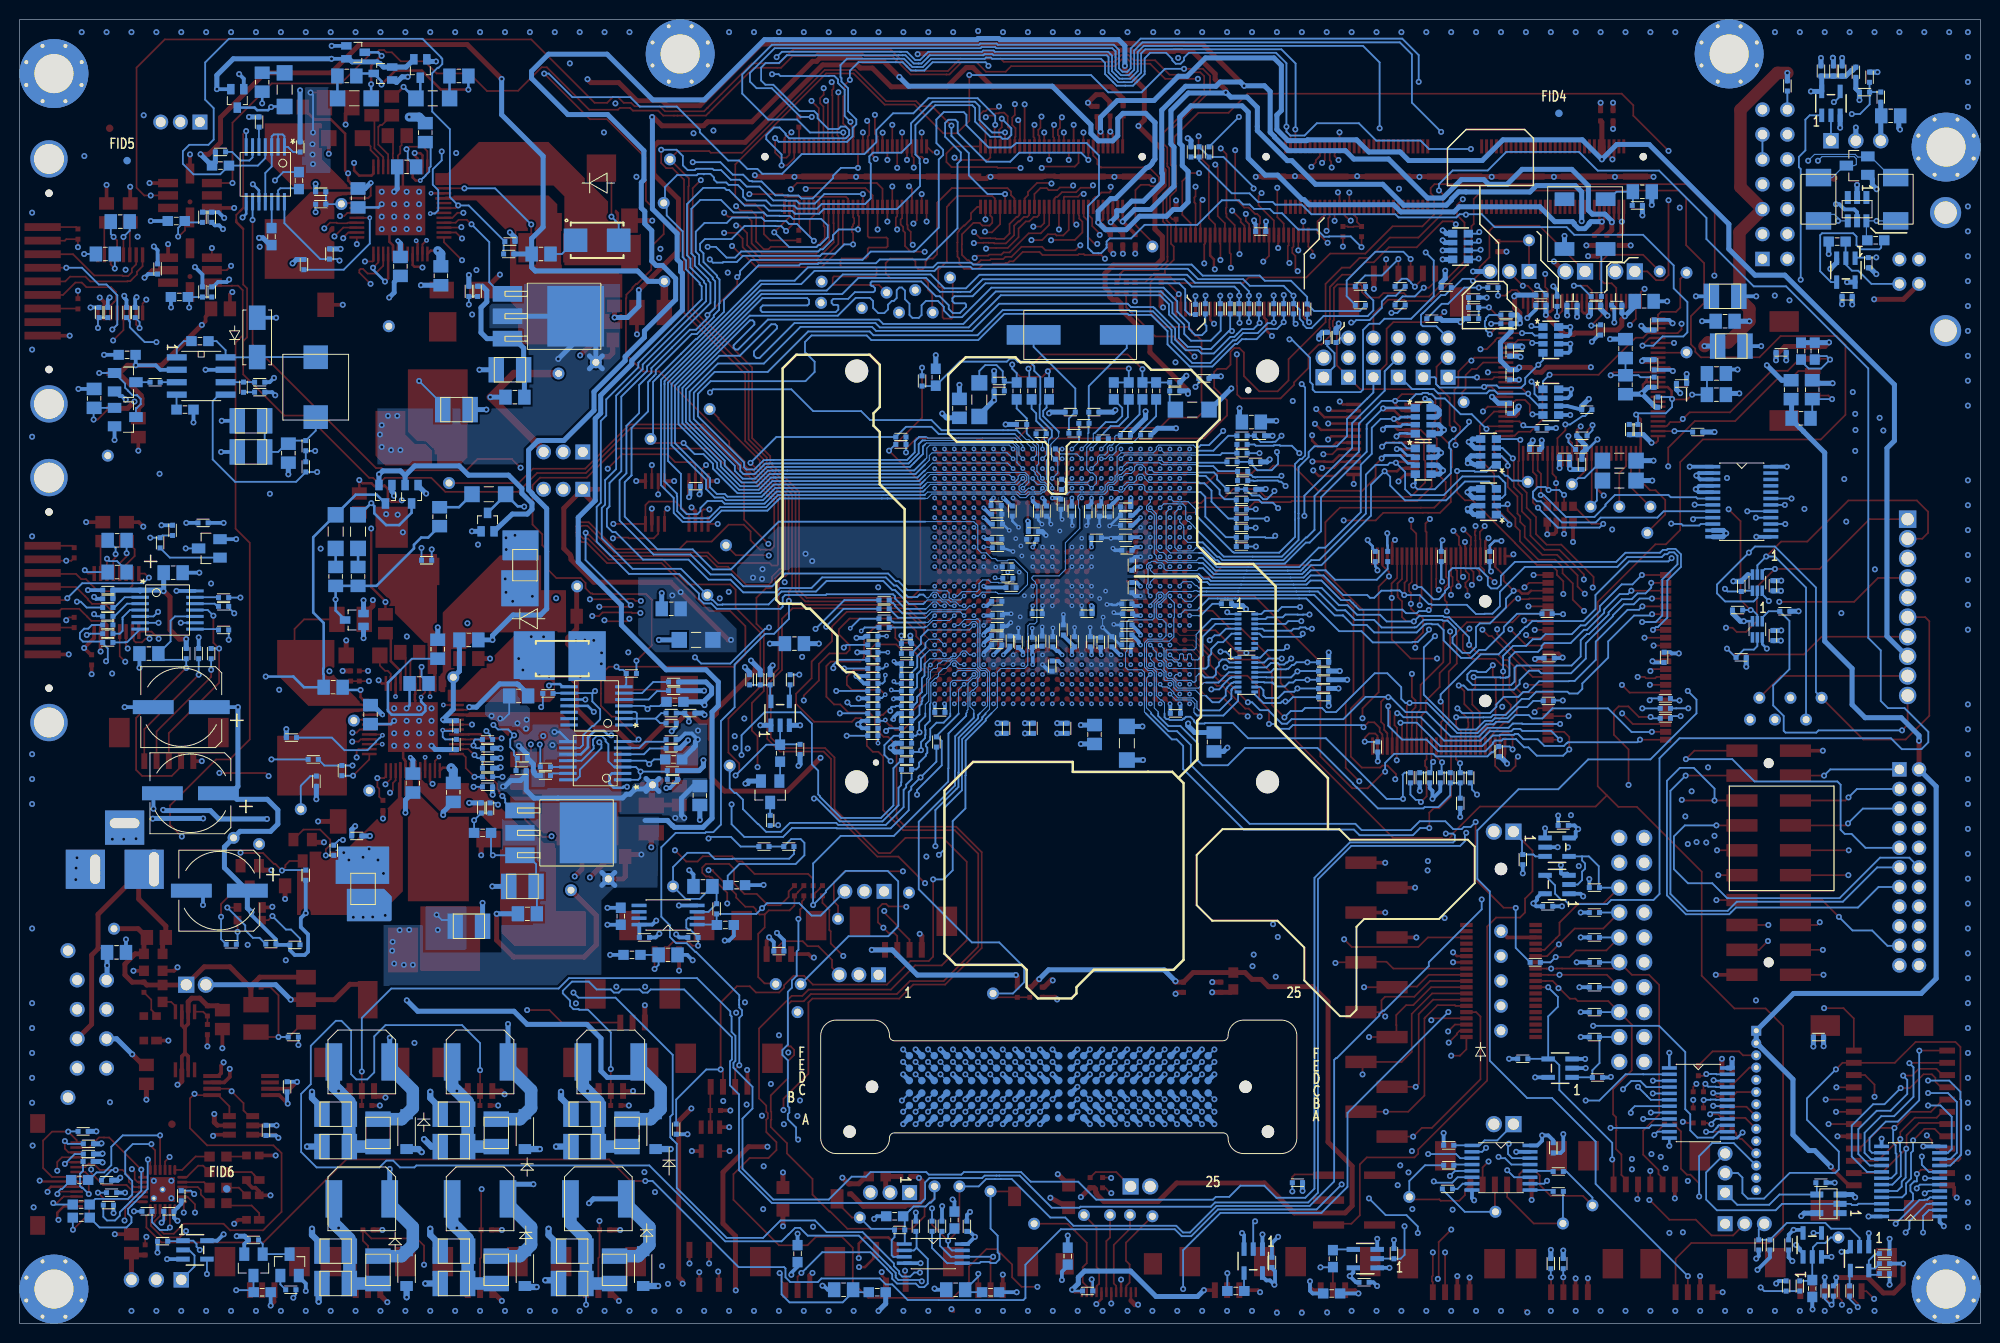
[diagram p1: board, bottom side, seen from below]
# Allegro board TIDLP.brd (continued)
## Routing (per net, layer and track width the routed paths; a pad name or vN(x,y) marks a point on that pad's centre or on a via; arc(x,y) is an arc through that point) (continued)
P2_A5: length 77.7
  TOP w0.178: U11.AD23 v2(104.66,86.2) ; v1(102.67,110.2) 102.64,110.23 101.7,110.23 101.68,110.25 101.17,110.25 101.15,110.23 100.64,110.23 100.58,110.17 99.4,110.17 98.56,111.01 98.56,111.97 98.12,112.42 98.02,112.42 97.56,112.87 97.21,112.87 97.03,113.05 97.03,113.51 96.99,113.55 J3.40
  LY3 w0.102: 107.35,80.05 107.06,80.33 107.06,80.48 106.94,80.6 106.29,80.6 106.06,80.83 106.06,86.36 105.83,86.59 105.06,86.59 v2(104.66,86.2)
  LY3 w0.171: 107.35,80.05 109.42,80.05 115.37,85.99 115.37,86.99 115.18,87.18 115.18,92.16 115.48,92.46 115.48,94.7 115.26,94.92 113.93,94.92 112.48,96.38 112.48,98.18 113.54,99.24 116.44,99.24 116.72,99.51 116.72,101.76 115.32,103.16 115.32,107.02 115.19,107.14 112.98,107.14 112.85,107.02 112.85,104.54 111.74,103.43 111.74,102.4 111.11,101.77 109.65,101.77 108.19,103.23 108.19,103.24 107.3,104.13 107.29,104.13 106.24,105.18 106.24,105.2 105.97,105.46 105.97,107 105.83,107.15 105.83,107.19 105.18,107.83 105.18,107.94 104.94,108.19 104.94,109 104.48,109.46 104.48,109.6 103.88,110.2 v1(102.67,110.2)
P2_A6: length 77.9
  TOP w0.178: U11.AC22 v2(103.66,85.2) ; J3.39 96.99,118.92 96.93,118.86 v1(96.93,118.79)
  LY4 w0.102: v2(103.66,85.2) 103.22,85.2 102.83,85.59 101.5,85.59 101.27,85.36 101.27,84.96 100.91,84.6 100.31,84.6 100.06,84.35 100.06,84.04 99.83,83.81 99.5,83.81 99.27,84.04 99.27,84.46 98.92,84.81 98.5,84.81 98.27,85.04 98.27,85.46 97.92,85.81 97.5,85.81 97.27,86.04 97.27,86.46 96.92,86.81 96.5,86.81 96.27,87.04 96.27,87.44 96.1,87.6 95.42,87.6 95.07,87.95 95.07,89.09 94.35,89.81 94.19,89.81 94.16,89.84 94.16,89.86 93.88,90.15
  LY4 w0.171: v1(96.93,118.79) 96.93,121.18 97.05,121.31 97.37,121.31 97.5,121.43 97.5,121.83 97.63,121.96 98.37,121.96 98.5,121.83 98.5,117.62 97.14,116.26 97.14,115.19 95.64,113.69 95.09,113.69 94.58,113.19 94.58,111.14 94.19,110.74 94.19,110.25 94.54,109.9 95.95,109.9 96.39,109.46 97.37,109.46 97.82,109.91 97.82,111.88 98.3,112.36 99.01,112.36 99.35,112.02 99.35,111.66 98.54,110.85 98.54,108.91 98.62,108.83 98.62,108.74 100.01,107.35 100.01,105.78 101.97,103.81 101.97,101.98 102.12,101.83 102.12,98.2 101.81,97.89 101.47,97.89 101.26,97.68 101.26,97 101.69,96.57 102.29,96.57 102.46,96.4 102.46,95.96 102.25,95.75 101.38,95.75 101.29,95.84 100.94,95.84 99.92,96.86 97.92,96.86 97.49,96.44 97.1,96.44 97.08,96.42 96.27,96.42 95.66,95.81 94.85,95.81 94.34,95.31 94.34,94.03 93.69,93.38 93.69,92.3 93.72,92.26 93.59,92.13 93.59,90.88 93.88,90.59 93.88,90.15
P2_A7: length 77.4
  TOP w0.178: v1(92.54,116.08) 92.74,115.88 93.9,115.88 94.16,115.62 95.04,115.62 95.23,115.82 95.88,115.82 96.49,115.21 J3.38 ; U11.AB21 v2(102.66,84.2)
  LY4 w0.102: 91.52,90.17 92.27,89.42 92.27,89.04 92.5,88.81 93.9,88.81 94.26,88.45 94.26,87.92 94.2,87.86 94.2,87.1 94.5,86.81 94.92,86.81 95.27,86.46 95.27,86.04 95.5,85.81 96.21,85.81 96.42,85.6 96.84,85.6 97.07,85.38 97.07,84.95 97.66,84.36 97.66,84.07 98.53,83.2 100.17,83.2 100.37,83.4 100.99,83.4 101.4,83.81 101.83,83.81 102.22,84.2 v2(102.66,84.2)
  LY4 w0.171: 91.52,90.17 91.52,91.74 91.78,92.01 91.78,93.81 92.48,94.51 92.48,95.55 93.11,96.18 93.11,99.18 93.38,99.46 95.22,99.46 95.49,99.74 95.49,100.12 95.22,100.4 93.38,100.4 93.11,100.67 93.11,101.06 93.38,101.34 95.22,101.34 95.49,101.61 95.49,102 95.22,102.28 93.38,102.28 93.11,102.55 93.11,102.94 93.38,103.22 95.22,103.22 95.49,103.49 95.49,103.88 95.22,104.16 93.38,104.16 93.11,104.43 93.11,104.82 93.38,105.1 95.22,105.1 95.49,105.37 95.49,105.76 95.22,106.04 93.38,106.04 93.11,106.31 93.11,106.7 93.38,106.98 95.22,106.98 95.49,107.25 95.49,107.64 95.22,107.92 93.38,107.92 93.11,108.19 93.11,109.5 92.89,109.71 92.89,110.27 92.37,110.79 92.37,111.09 91.61,111.85 91.61,112.56 91.84,112.79 92.74,112.79 93.18,113.23 93.18,113.72 94.52,115.06 94.52,115.58 94.16,115.95 94.16,116.53 94.23,116.6 94.23,117.44 93.7,117.96 92.8,117.96 92.59,117.75 92.59,116.12 v1(92.54,116.08)
P2_A8: length 77.4
  TOP w0.178: U11.AD25 v2(104.66,88.2) ; J3.37 96.49,120.94 96.59,121.04 96.59,121.95 96.49,122.05 v1(96.49,122.27)
  LY3 w0.102: 101.45,90.02 101.27,89.84 101.27,89.04 101.5,88.81 101.64,88.81 102.06,88.39 102.06,87.94 102.39,87.6 103.54,87.6 103.75,87.81 104.27,87.81 v2(104.66,88.2)
  LY3 w0.171: v1(96.49,122.27) 96.58,122.17 96.58,121.53 96.83,121.28 98.21,121.28 99.03,120.46 100.11,120.46 100.32,120.68 102.03,120.68 102.43,120.28 102.43,119.91 102.3,119.79 100.82,119.79 100.69,119.66 100.69,119.29 100.82,119.16 102.3,119.16 102.43,119.03 102.43,117.2 103.32,116.3 103.32,114.38 103.07,114.12 100.93,114.12 100.03,113.22 100.03,112.68 99.59,112.24 99.59,111.67 99.04,111.13 99.04,109.63 99.48,109.19 99.48,108.49 101.04,106.92 101.04,105.88 103.69,103.23 103.69,101.94 105.59,100.04 106.71,100.04 107.99,98.76 108.15,98.59 108.91,98.59 109.3,98.2 109.3,93.82 110.85,92.27 110.85,90.18 111.25,89.78 111.83,89.78 111.91,89.69 111.91,87.37 111.39,86.85 108.39,86.85 108.11,87.13 108.11,89.58 107.1,90.59 105.61,90.59 105.21,90.99 105.21,91.07 104.58,91.7 102.41,91.7 102.17,91.46 102.17,91.09 101.57,90.49 101.57,90.22 101.45,90.09 101.45,90.02
P2_A9: length 77.8
  TOP w0.178: U11.AD26 v2(104.66,89.2) ; v1(101.42,109.64) 101.35,109.71 100.39,109.71 99.21,109.71 98.11,110.82 98.11,111.68 97.37,112.42 97.02,112.42 96.56,112.87 96.21,112.87 96.03,113.05 96.03,113.86 J3.36
  LY4 w0.102: v2(104.66,89.2) 104.68,89.2 105.06,88.83 105.06,87.93 104.93,87.8 104.27,87.8 104.15,87.93 104.15,88.65 104.02,88.78 103.4,88.78 103.27,88.65 103.27,88.24 103.19,88.16 103.19,88.04 102.74,87.59 101.5,87.59 101.27,87.36 101.27,86.94 100.92,86.59 100.5,86.59 100.27,86.36 100.27,86.08 99.99,85.81 99.5,85.81 99.27,86.04 99.27,86.46 98.92,86.81 98.5,86.81 98.27,87.04 98.27,87.46 97.92,87.81 97.5,87.81 97.27,88.04 97.27,89.5 97.05,89.72 96.62,89.72
  LY4 w0.171: 96.62,89.72 95.76,90.58 95.76,91.75 95.95,91.94 95.95,92.85 96.59,93.49 96.59,93.87 97,94.29 97.36,94.29 97.57,94.5 99.66,94.5 100,94.16 100,93.93 100.35,93.58 101.17,93.58 101.33,93.42 101.89,93.42 102.38,93.92 103.26,93.92 103.85,93.34 105.57,93.34 105.64,93.41 105.94,93.41 106.05,93.52 106.05,94.04 105.96,94.13 105.96,94.62 106.51,95.18 106.51,97.96 105.96,98.52 105.96,99.02 106.31,99.36 106.34,99.36 106.52,99.54 106.52,100.41 106.29,100.64 105.94,100.64 105.82,100.52 105.82,99.66 105.47,99.31 105.47,98.23 106,97.7 106,95.47 105.47,94.94 105.47,94.08 105.33,93.94 105.08,93.94 104.95,94.08 104.95,95.1 105.42,95.57 105.42,97.48 104.96,97.94 104.96,99.65 105.25,99.94 105.25,101.39 104.72,101.92 104.72,103.52 102.81,105.43 102.81,107.69 102.55,107.95 102.02,107.95 101.83,108.14 101.83,108.94 102.12,109.23 102.12,109.91 102.07,109.96 102.07,110.49 101.85,110.71 101.11,110.71 100.92,110.52 100.92,109.86 101.14,109.64 v1(101.42,109.64)
P2_B0: length 78.1
  TOP w0.178: J3.35 95.99,121.13 96.1,121.24 96.1,121.74 95.88,121.96 95.88,123.01 v1(95.77,123.11) ; U11.AC24 v2(103.66,87.2)
  LY3 w0.102: v2(103.66,87.2) 104.07,87.6 104.75,87.6 105.08,87.94 105.08,88.35 104.84,88.6 103.45,88.6 103.09,88.23 103.09,88.06 102.83,87.81 102.5,87.81 102.27,88.04 102.27,88.64 102.06,88.85 102.06,89.71 102.51,90.16
  LY3 w0.171: 102.51,90.16 106.92,90.16 107.68,89.4 107.68,86.89 108.21,86.36 111.74,86.36 112.34,86.96 112.34,92.08 111.91,92.52 111.21,92.52 110.06,93.67 110.06,94.89 109.73,95.21 109.73,98.65 109.36,99.02 108.33,99.02 108.21,99.15 106.89,100.47 105.77,100.47 104.12,102.12 104.12,103.41 102.41,105.12 102.41,106.8 101.18,108.03 100.66,108.03 99.91,108.78 99.91,109.37 99.48,109.81 99.48,110.95 100.02,111.49 100.02,112.06 100.46,112.5 100.46,113.05 101.11,113.69 102.04,113.69 102.05,113.69 103.51,113.69 103.76,113.93 103.76,116.48 102.86,117.38 102.86,120.82 102.57,121.11 100.14,121.11 99.93,120.9 99.24,120.9 98.89,121.24 98.89,121.32 98.49,121.72 97.67,121.72 97.08,122.3 97.08,122.52 96.49,123.11 v1(95.77,123.11)
P2_B1: length 77.6
  TOP w0.178: U11.AC25 v2(103.66,88.2) ; J3.34 95.49,112.24 95.84,111.89 v1(96.6,111.89)
  LY4 w0.102: v2(103.66,88.2) 103.7,88.17 103.7,87.73 103.83,87.59 105.13,87.59 105.26,87.47 105.26,86.92 105.13,86.8 101.42,86.8 101.06,86.44 101.06,86.04 100.83,85.81 100.3,85.81 100.08,85.59 99.73,85.59 99.72,85.6 99.42,85.6 99.07,85.95 99.07,86.38 98.84,86.6 98.42,86.6 98.07,86.95 98.07,87.37 97.84,87.6 97.42,87.6 97.07,87.95 97.07,88.57 96.83,88.81 96.5,88.81 96.27,89.04 96.27,89.46 95.56,90.17
  LY4 w0.171: v1(96.6,111.89) 97.95,113.23 97.95,113.53 98.43,114.01 98.43,115.54 99.26,116.37 99.26,116.55 99.79,117.08 99.79,119.67 100.24,120.11 100.75,120.11 101.19,119.67 101.19,118.03 100.37,117.21 100.37,116.71 100.7,116.37 102.02,116.37 102.66,115.74 102.66,112.38 102.21,111.94 101.82,111.94 101.78,111.98 101.29,111.98 100.94,111.63 100.94,111.31 99.91,110.28 99.91,109.32 100.22,109.02 101.07,109.02 101.4,108.69 101.4,107.96 102.38,106.98 102.38,105.24 104.17,103.45 104.17,103.13 104,102.97 103.43,102.97 103.27,102.8 103.27,102.57 103.43,102.41 104,102.41 104.17,102.24 104.17,101.62 104.53,101.26 104.53,97.76 104.99,97.3 104.99,95.75 104.51,95.27 104.51,94.44 104.18,94.11 103.68,94.11 103.32,94.47 101.15,94.47 100.84,94.78 100.39,94.78 100,94.78 99.81,94.96 96.95,94.96 96,94.01 96,93.41 95.59,93 95.59,92.09 95.27,91.76 95.27,90.46 95.56,90.17
P2_B2: length 79.9
  TOP w0.178: J3.33 v1(95.49,121.49) ; U11.AB23 v2(102.66,86.2)
  LY3 w0.102: 99.06,90.17 99.27,89.96 99.27,89.36 99.27,89.36 99.27,89.04 99.27,89.04 99.27,88.36 99.27,88.36 99.27,88.04 99.27,88.03 99.5,87.8 100.1,87.8 100.29,87.6 100.84,87.6 101.1,87.33 101.1,86.84 101.31,86.64 101.97,86.64 102.41,86.2 v2(102.66,86.2)
  LY3 w0.171: v1(95.49,121.49) 95.53,121.45 95.53,120.1 95.29,119.86 93.56,119.86 93.21,119.51 93.21,119.31 93.58,118.94 93.58,118.44 93.39,118.25 93.39,117.68 94.19,116.88 95,116.88 95.05,116.83 96.86,116.83 97.19,116.5 97.19,114.53 97.43,114.28 98.07,114.28 98.22,114.14 98.22,113.31 97.42,112.51 97.03,112.51 97,112.48 96.36,112.48 96.01,112.13 96.01,110.45 96.55,109.91 96.95,109.91 97.23,109.63 97.23,109.07 97.38,108.91 97.38,108.68 97.16,108.46 96.88,108.46 96.75,108.59 96.75,108.75 96.52,108.98 96.21,108.98 95.98,108.76 95.98,108.21 96.4,107.79 97.73,107.79 99.24,106.28 99.24,105.24 101.96,102.52 101.96,101.23 101.63,100.9 101.63,98.04 101.76,97.92 101.99,97.92 102.12,98.04 102.12,100.16 102.36,100.41 102.78,100.41 103.51,99.68 103.51,96.7 103.66,96.55 103.91,96.55 104.05,96.69 104.05,98.54 104.24,98.73 104.46,98.73 104.66,98.53 104.66,97.99 104.84,97.81 104.84,95.1 104.46,94.72 103.51,94.72 103.22,95.01 103.22,96.03 103.08,96.17 103.08,99.35 102.96,99.48 102.68,99.48 102.55,99.35 102.55,94.91 100.86,93.21 98.55,93.21 98.34,92.99 98.34,92.21 98.83,91.71 98.83,91.46 99.01,91.28 99.01,90.22 99.06,90.17
P2_B3: length 77.7
  TOP w0.178: U11.AC26 v2(103.66,89.2) ; v1(102.59,108.7) 102.36,108.92 101.22,108.92 101.11,109.03 99.86,109.03 99.63,109.26 99.02,109.26 97.07,111.2 95.84,111.2 94.99,112.06 J3.32
  LY4 w0.102: v2(103.66,89.2) 103.39,89.2 102.79,88.59 102.5,88.59 102.27,88.36 102.27,88.24 101.84,87.81 101.42,87.81 101.06,87.44 101.06,87.01 100.84,86.8 100.42,86.8 100.21,86.59 99.42,86.59 99.07,86.95 99.07,87.47 98.93,87.6 98.42,87.6 98.06,87.96 98.06,89.36 97.5,89.92 97.03,89.92 96.78,90.17
  LY4 w0.171: 96.78,90.17 96.27,90.68 96.27,91.76 96.3,91.79 96.3,92.7 96.65,93.05 96.88,93.05 97.11,93.28 97.11,93.43 97.74,94.06 98.38,94.06 98.39,94.07 99.48,94.07 99.64,93.91 99.64,93.78 100.2,93.23 100.82,93.23 101.33,92.72 101.79,92.72 102.56,93.48 103.09,93.48 103.67,92.9 104.98,92.9 105.3,92.59 105.3,92.57 105.64,92.22 105.66,92.22 105.71,92.17 108.74,92.17 108.96,92.38 108.96,92.99 108.09,93.86 108.09,96.54 107.85,96.78 107.74,96.78 107.53,96.57 107.53,92.94 107.34,92.75 107.11,92.75 106.95,92.92 106.95,93.92 107.15,94.13 107.15,94.62 106.95,94.82 106.95,96.63 107.3,96.98 107.3,97.89 107.06,98.13 107.06,98.43 107.15,98.52 107.15,99.02 107.02,99.15 107.02,100.48 107.14,100.61 107.51,100.61 107.63,100.48 107.63,98.29 107.82,98.11 107.92,98.11 108.15,98.34 108.15,100.72 107.65,101.21 106.04,101.21 105.16,102.1 105.16,104.43 104.79,104.8 104.06,104.8 103.24,105.61 103.24,107.56 103.53,107.85 103.53,108.59 103.4,108.71 103.4,109.39 103.25,109.54 102.69,109.54 102.55,109.4 102.55,108.73 v1(102.59,108.7)
P2_B4: length 77.5
  TOP w0.178: J3.31 v1(94.99,118.69) ; U11.AB24 v2(102.66,87.2)
  LY3 w0.102: v2(102.66,87.2) 102.51,87.2 101.9,87.81 101.5,87.81 101.27,88.04 101.27,88.7 101.06,88.91 101.06,90.13
  LY3 w0.171: 101.06,90.13 101.09,90.17 101.09,91.03 102.27,92.21 104.57,92.21 105.76,91.02 107.28,91.02 108.54,89.76 108.54,87.61 108.87,87.28 111.04,87.28 111.43,87.67 111.43,88.17 111.3,88.31 110.85,88.31 110.64,88.52 110.64,89.76 110.32,90.07 110.32,92.18 108.87,93.64 108.87,94.9 108.71,95.06 107.4,95.06 107.24,95.22 107.24,95.46 107.4,95.62 108.71,95.62 108.87,95.78 108.87,96.01 108.71,96.18 107.4,96.18 107.24,96.34 107.24,96.57 107.4,96.74 108.71,96.74 108.87,96.9 108.87,97.96 108.67,98.16 106.32,98.16 105.96,98.52 105.96,98.53 105.95,98.54 105.95,99.07 103.26,101.76 103.26,103.06 100.61,105.7 100.61,106.74 99.05,108.31 99.05,109.01 98.51,109.55 98.51,111.2 99.15,111.85 99.15,112.41 99.59,112.86 99.59,113.4 100.75,114.56 102.61,114.56 102.85,114.8 102.85,116.16 102,117.02 102,118.38 101.7,118.68 100.66,118.68 100.22,119.11 100.22,119.13 99.5,119.85 99.02,119.85 98.03,120.85 96.78,120.85 96.61,120.69 96.61,119.63 95.68,118.69 v1(94.99,118.69)
P2_B5: length 79.5
  TOP w0.178: v1(90.52,116.1) 90.77,115.85 91.78,115.85 92.23,115.4 93.67,115.4 94.14,114.93 94.27,114.93 94.44,114.75 94.44,114.62 94.49,114.58 J3.30 ; U11.AA22 v2(101.66,85.2)
  LY3 w0.102: v2(101.66,85.2) 101.66,85.09 101.23,84.66 101.23,84.42 101.06,84.25 101.06,84.04 100.83,83.81 94.3,83.81 94.01,84.1 94.01,86.37 94.23,86.59 95.83,86.59 96.06,86.82 96.06,87.6 95.85,87.81 94.7,87.81 94.54,87.97 94.54,88.91 94.67,89.03 94.75,89.03 94.88,89.16 94.88,89.45 94.43,89.9 94.43,90.01 94.27,90.17
  LY3 w0.171: v1(90.52,116.1) 90.2,116.1 90.07,115.97 90.07,115.4 89.94,115.28 87.77,115.28 87.64,115.4 87.64,117.09 87.51,117.22 86.9,117.22 86.77,117.09 86.77,111.77 86.9,111.64 90.36,111.64 90.83,111.17 90.83,110.93 91.22,110.55 91.22,110.24 91.21,110.23 91.21,109.6 90.34,108.73 90.34,108.58 90.25,108.48 90.25,108.22 89.69,107.66 89.52,107.66 89.52,103.1 89.29,102.87 88.92,102.87 88.66,102.61 88.66,99.25 88.88,99.04 89.56,99.04 89.78,98.82 89.78,98.52 89.61,98.35 88.77,98.35 88.6,98.19 88.6,97.96 88.77,97.79 89.61,97.79 89.78,97.63 89.78,97.4 89.61,97.24 88.77,97.24 88.6,97.07 88.6,96.84 88.77,96.68 89.61,96.68 89.78,96.51 89.78,96.28 89.61,96.12 88.77,96.12 88.6,95.95 88.6,95.72 88.77,95.56 89.61,95.56 89.78,95.4 89.78,95.16 89.61,95 88.77,95 88.6,94.84 88.6,94.6 88.77,94.44 89.61,94.44 89.78,94.28 89.78,94.11 89.51,93.85 87.66,93.85 87.37,93.55 87.37,91.81 87.79,91.38 93.06,91.38 94.27,90.17
P2_B6: length 78
  TOP w0.178: v1(94.49,122.27) 94.49,122.05 94.59,121.95 94.59,121.04 94.49,120.94 J3.29 ; U11.AB25 v2(102.66,88.2)
  LY3 w0.102: 107.63,86.14 107.26,86.52 107.26,88.76 107.08,88.94 107.08,89.38 106.76,89.7 102.5,89.7 102.27,89.47 102.27,89.04 102.47,88.83 102.47,88.39 v2(102.66,88.2)
  LY3 w0.171: 107.63,86.14 107.86,85.92 112.02,85.92 112.78,86.67 112.78,92.57 112.32,93.03 111.51,93.03 110.53,94.01 110.53,95.05 110.16,95.42 110.16,98.98 109.69,99.46 108.51,99.46 108.13,99.83 107.06,100.9 105.95,100.9 104.55,102.3 104.55,103.59 102.85,105.3 102.85,106.98 101.26,108.56 100.79,108.56 100.34,109.01 100.34,109.55 99.95,109.94 99.95,110.75 100.22,111.02 100.22,111.02 100.51,111.31 100.51,111.81 100.89,112.19 100.89,112.87 101.28,113.26 101.86,113.26 102.11,113.02 102.11,112.64 102.32,112.43 103.19,112.43 103.27,112.35 104.5,112.35 104.72,112.56 104.72,113.39 104.26,113.84 104.26,116.72 103.29,117.69 103.29,121.14 102.89,121.54 100.28,121.54 99.42,122.4 98.75,122.4 98.5,122.15 97.9,122.15 97.55,122.5 97.55,122.89 97.1,123.33 97.06,123.33 96.48,123.91 95.04,123.91 94.49,123.35 v1(94.49,122.27)
P2_B7: length 79.1
  TOP w0.178: J3.28 v1(93.99,111.59) ; U11.AA23 v2(101.66,86.2)
  LY3 w0.102: 98.02,90.17 98.27,89.92 98.27,88.04 98.5,87.81 98.92,87.81 99.27,87.45 99.27,87.04 99.5,86.81 100.66,86.81 101.26,86.2 v2(101.66,86.2)
  LY3 w0.171: v1(93.99,111.59) 94.02,111.62 94.02,113.21 94.25,113.44 94.25,115.42 94.44,115.6 94.69,115.6 94.89,115.4 94.89,114.96 95.18,114.67 95.18,113.22 94.63,112.66 94.63,111.18 94.19,110.74 94.19,110.25 94.39,110.05 94.39,107.7 95.17,106.91 95.74,106.91 95.87,106.79 95.87,104.46 95.99,104.34 96.4,104.34 96.52,104.46 96.52,106.79 96.65,106.91 97.03,106.91 97.36,106.58 97.36,105.44 97.96,104.84 98.4,104.84 98.96,104.27 98.96,103.33 98.6,102.96 98.6,102.31 98.37,102.08 97.79,102.08 97.55,101.83 97.55,100.84 97.77,100.61 98.38,100.61 98.6,100.4 98.6,98.51 98.15,98.06 98.15,97.57 98.5,97.22 98.99,97.22 99.21,97 99.21,96.72 98.95,96.46 98.26,96.46 98.02,96.22 98.02,95.38 98.37,95.03 99.07,95.03 99.21,94.89 99.21,94.36 99.02,94.17 97.75,94.17 97.47,94.45 97.47,96.8 97.81,97.13 97.81,99.94 97.68,100.06 97.36,100.06 97.12,100.31 97.12,101.12 97.16,101.16 97.16,102.16 97.53,102.53 97.53,104.44 97.4,104.56 97.12,104.56 96.99,104.44 96.99,102.69 95.96,101.66 95.96,101.16 96.43,100.69 96.43,100.06 97.16,99.33 97.16,97.99 96.85,97.99 96.5,97.64 96.5,97.15 96.85,96.8 96.92,96.8 96.92,94.1 97.25,93.76 97.25,92.95 97.5,92.7 97.5,92.21 97.25,91.96 97.25,91.95 96.79,91.49 96.79,90.83 97.21,90.4 97.79,90.4 98.02,90.17
P2_B8: length 79.7
  TOP w0.178: U11.AB26 v2(102.66,89.2) ; v1(93.69,123.04) 93.88,122.85 93.88,121.96 94.1,121.74 94.1,121.24 93.99,121.13 J3.27
  LY3 w0.102: 107.58,83.8 107.06,84.33 107.06,88.63 106.88,88.81 103.5,88.81 103.11,89.2 v2(102.66,89.2)
  LY3 w0.171: 107.58,83.8 110.52,83.8 113.3,86.58 113.3,92.7 112.53,93.46 111.69,93.46 110.96,94.19 110.96,95.23 110.6,95.6 110.6,99.19 109.9,99.89 108.69,99.89 108.44,100.14 107.24,101.33 106.13,101.33 104.98,102.48 104.98,103.77 103.28,105.48 103.28,107.16 101.44,108.99 101.06,108.99 100.77,109.28 100.77,110.96 100.94,111.13 100.94,111.13 100.94,111.63 101.29,111.98 101.54,111.98 101.56,112 103.01,112 103.16,111.84 104.98,111.84 105.24,112.11 105.24,113.69 104.7,114.23 104.7,116.89 103.73,117.87 103.73,121.56 103.31,121.98 101.44,121.98 101.08,122.33 101.08,122.52 100.85,122.75 100.85,122.83 100.13,123.55 99.86,123.55 99.64,123.76 97.24,123.76 96.66,124.34 94.43,124.34 93.69,123.6 v1(93.69,123.04)
P2_B9: length 77.4
  TOP w0.178: v1(91.47,115.22) 91.76,115.22 92.04,114.94 93.43,114.94 93.49,114.88 J3.26 ; U11.Y22 v2(100.66,85.2)
  LY3 w0.102: 94.77,90.17 95.12,89.82 95.12,88.99 95.11,88.99 94.81,88.68 94.81,88.34 94.94,88.21 95.14,88.21 95.27,88.34 95.27,88.59 95.47,88.79 95.91,88.79 96.06,88.64 96.06,87.95 96.26,87.74 96.26,86.95 96.43,86.79 97.12,86.79 97.21,86.7 97.21,85.98 97.04,85.81 94.37,85.81 94.25,85.69 94.25,85 94.65,84.6 99.62,84.6 100.22,85.2 v2(100.66,85.2)
  LY3 w0.171: v1(91.47,115.22) 91.73,115.49 91.73,117.65 91.35,118.03 90.11,118.03 89.92,117.85 89.92,117.35 90.12,117.15 91.02,117.15 91.15,117.03 91.15,115.89 90.75,115.48 90.75,114.71 87.52,114.71 87.4,114.58 87.4,114.27 87.52,114.15 90.6,114.15 90.72,114.02 90.72,113.73 90.6,113.6 87.51,113.6 87.38,113.47 87.38,113.23 87.61,113 90.39,113 90.75,112.64 90.75,111.86 91.26,111.34 91.26,111.11 91.8,110.58 92.06,110.58 92.41,110.23 92.41,109.73 92.3,109.63 92.3,109.61 91.77,109.07 91.46,109.07 91.11,108.72 91.11,108.69 90.6,108.18 90.6,108.07 90.01,107.47 90.01,102.42 89.83,102.25 89.35,102.25 89.12,102.02 89.12,100.99 89.38,100.73 90.36,100.73 90.54,100.56 90.54,100.23 90.37,100.07 89.42,100.07 89.26,99.9 89.26,99.67 89.42,99.51 90.37,99.51 90.54,99.34 90.54,93.89 90.18,93.53 90.18,92.4 90.85,91.74 93.21,91.74 94.77,90.17
P2_C0: length 78
  TOP w0.178: U11.AA24 v2(101.66,87.2) ; J3.25 v1(93.49,121.49)
  LY3 w0.102: v2(101.66,87.2) 101.53,87.2 100.92,87.81 100.45,87.81 100.06,88.2 100.06,89.73 99.71,90.07
  LY3 w0.171: 99.71,90.07 99.71,90.77 100.23,91.28 100.23,91.94 102.58,94.29 103.92,94.29 104.21,94 104.21,93.26 104.4,93.07 104.8,93.07 105.3,92.58 105.3,92.57 105.64,92.22 105.65,92.22 105.99,91.88 107.64,91.88 108.82,90.7 109.08,90.7 109.44,91.07 109.44,91.84 108.26,93.03 108.21,93.03 107.46,93.78 107.24,93.78 107.05,93.59 107.05,92.62 106.9,92.46 106.65,92.46 106.51,92.6 106.51,93.57 106.27,93.81 105.01,93.81 104.84,93.99 104.84,94.25 105.08,94.49 105.79,94.49 106.37,95.08 106.37,96.88 106.18,97.08 105.98,97.08 105.83,96.93 105.83,95.38 105.7,95.26 105.47,95.26 105.34,95.38 105.34,97.91 105.09,98.17 105.09,98.71 102.39,101.41 102.39,102.7 99.72,105.37 99.72,106.41 98.18,107.95 98.18,108.65 97.58,109.26 97.58,111.5 98.29,112.21 98.29,112.77 98.73,113.21 98.73,113.76 98.84,113.87 98.84,117.08 98.66,117.26 98.35,117.26 98.19,117.1 98.19,115.06 98.03,114.89 97.8,114.89 97.63,115.06 97.63,117.1 97.47,117.26 95.49,117.26 95.15,117.6 95.15,117.68 94.39,118.44 94.39,118.94 94.74,119.29 95.47,119.29 96.08,119.9 96.08,121.74 95.73,122.09 95.15,122.09 94.73,121.67 93.67,121.67 v1(93.49,121.49)
P2_C1: length 79.1
  TOP w0.178: U11.AA25 v2(101.66,88.2) ; J3.24 92.99,111.55 93.55,110.98 94.24,110.98 94.36,111.11 95.11,111.11 95.71,110.51 v1(96.79,110.51)
  LY4 w0.102: 97.64,90.17 98.27,89.54 98.27,88.04 98.5,87.81 99.01,87.81 99.27,87.55 99.27,87.04 99.5,86.81 99.75,86.81 99.76,86.8 99.99,86.8 100.27,87.07 100.27,87.36 100.5,87.59 100.92,87.59 101.34,88.01 101.47,88.01 v2(101.66,88.2)
  LY4 w0.171: v1(96.79,110.51) 96.01,111.3 96.01,112.84 98,114.83 98,115.9 99.36,117.26 99.36,119.86 100.09,120.59 101.29,120.59 101.62,120.25 101.62,117.64 103.44,115.82 103.44,109.99 103.84,109.6 103.84,108.89 104.18,108.55 104.18,107.75 103.68,107.25 103.68,105.83 104.27,105.23 105.34,105.23 105.59,104.99 105.59,102.27 106.22,101.65 107.83,101.65 108.59,100.89 108.59,93.97 109.02,93.55 109.34,93.55 109.57,93.32 109.57,92.14 109.16,91.73 105.64,91.73 105.51,91.86 105.5,91.86 104.94,92.42 104.94,92.44 104.9,92.47 104.01,92.47 103.65,92.11 101.32,92.11 100.57,92.87 100.05,92.87 99.29,93.63 98.57,93.63 97.9,92.97 97.9,92.42 97.15,91.67 97.14,91.67 96.79,91.32 96.79,90.77 97.21,90.35 97.46,90.35 97.64,90.17 97.64,90.17
P2_C2: length 78.1
  TOP w0.178: J3.23 v1(92.99,118.69) ; U11.AA26 v2(101.66,89.2)
  LY4 w0.102: v2(101.66,89.2) 101.66,89.21 101.28,89.59 100.5,89.59 100.26,89.35 100.26,88.03 100.04,87.81 99.3,87.81 99.06,88.05 99.06,89.36 98.54,89.88
  LY4 w0.171: 98.54,89.88 98.54,92.05 98.34,92.25 98.34,92.79 98.69,93.14 98.73,93.14 98.8,93.2 99.13,93.2 99.81,92.52 100.31,92.52 100.7,92.13 100.7,91.72 101,91.41 101.37,91.41 101.71,91.76 102.5,91.76 102.77,91.49 103.64,91.49 104.19,92.04 104.8,92.04 105.54,91.3 109.52,91.3 110.11,91.89 110.11,94.02 109.94,94.19 109.24,94.19 109.02,94.4 109.02,101.11 108.06,102.08 106.4,102.08 106.02,102.45 106.02,103.48 106.03,103.49 106.03,105.33 105.69,105.66 104.45,105.66 104.15,105.96 104.15,107.07 104.7,107.62 104.7,107.62 104.88,107.8 104.88,108.45 104.27,109.07 104.27,109.78 103.87,110.17 103.87,116 102.05,117.82 102.05,119.86 103.59,121.4 103.59,123.2 102.97,123.82 100.65,123.82 100.32,123.49 99.57,123.49 99.42,123.34 97.9,123.34 97.08,122.53 97.08,122.02 96.73,121.67 96.15,121.67 95.73,122.09 95.15,122.09 93.96,120.9 93.5,120.9 92.98,120.37 92.98,118.7 v1(92.99,118.69)
P2_C3: length 77.7
  TOP w0.178: J3.22 92.49,112.28 92.36,112.15 92.27,112.15 v1(92.21,112.1) ; U11.W22 v2(99.66,85.2)
  LY3 w0.102: v2(99.66,85.2) 99.64,85.22 99.64,85.59 99.51,85.72 99.2,85.72 99.07,85.59 99.07,84.95 98.93,84.81 95.2,84.81 95.07,84.93 95.07,85.47 95.2,85.59 97.89,85.59 98.07,85.76 98.07,86.59 97.88,86.78 97.47,86.78 97.27,86.98 97.27,87.46 96.92,87.81 96.5,87.81 96.27,88.04 96.27,89.18 95.28,90.17
  LY3 w0.171: 95.28,90.17 93.36,92.09 93.36,93.81 93.23,93.94 91.09,93.94 90.97,94.07 90.97,94.31 91.09,94.43 93.17,94.43 93.3,94.56 93.3,94.82 93.17,94.95 92.52,94.95 92.25,95.23 92.25,98.77 92.02,98.99 91.78,98.99 91.78,98.98 91.62,98.83 91.62,95.09 91.5,94.97 91.17,94.97 91.04,95.09 91.04,101.88 91.23,102.06 91.7,102.06 91.85,102.21 91.85,105.47 91.65,105.67 91.29,105.67 91.17,105.55 91.17,102.71 91.04,102.58 90.61,102.58 90.48,102.71 90.48,107.37 90.79,107.68 91.08,107.68 91.21,107.55 91.21,106.71 91.34,106.58 91.65,106.58 91.78,106.71 91.78,107.55 91.9,107.68 92.74,107.68 92.98,107.92 92.98,109.63 92.89,109.71 92.89,110.17 92.84,110.22 92.84,110.41 92.21,111.04 92.21,111.23 91.2,112.24 91.2,114.28 91.41,114.5 91.61,114.5 91.74,114.38 91.74,112.98 91.87,112.86 92.08,112.86 92.2,112.98 92.2,114.79 92.32,114.91 92.49,114.91 92.61,114.79 92.61,112.49 v1(92.21,112.1)
P2_C4: length 78
  TOP w0.178: U11.Y23 v2(100.66,86.2) ; J3.21 v1(92.49,122.27)
  LY3 w0.102: 96.28,90.17 96.72,90.17 97.05,89.84 97.83,89.84 98.07,89.6 98.07,89.31 98.06,89.3 98.06,88.88 97.88,88.71 97.45,88.71 97.27,88.52 97.27,88.04 97.5,87.81 97.91,87.81 98.27,87.45 98.27,87.04 98.71,86.59 99.83,86.59 99.83,86.59 100.01,86.59 100.4,86.2 v2(100.66,86.2)
  LY3 w0.171: v1(92.49,122.27) 91.83,122.27 91.67,122.43 91.67,122.66 92.66,123.66 92.9,123.66 93.09,123.47 93.09,122.79 93.18,122.7 93.18,122.04 92.69,121.55 92.69,121.17 92.97,120.9 93.73,120.9 93.84,121 94.86,121 95.06,120.8 95.06,120.48 94.8,120.23 93,120.23 92.27,119.49 92.27,118.52 92.75,118.03 92.75,117.67 93.75,116.67 93.75,113.89 93.58,113.73 93.58,112.04 93.39,111.84 93.39,111.17 93.76,110.81 93.76,110.07 93.84,109.99 93.84,106.56 94.2,106.2 94.2,102.36 93.72,101.88 93.72,100.64 94.58,99.77 94.58,98.87 94.21,98.49 94.21,97.97 94.46,97.72 94.65,97.72 94.91,97.98 95.17,97.98 95.44,97.72 95.65,97.72 95.82,97.89 95.82,99.04 95.22,99.64 95.22,100.06 94.34,100.95 94.34,101.59 94.87,102.13 94.87,106.23 95.06,106.41 95.24,106.41 95.42,106.23 95.42,104.22 96.47,103.17 96.47,102.77 95.53,101.84 95.53,100.98 96,100.51 96,99.88 96.61,99.27 96.61,98.25 96.15,97.79 96.15,97 96.49,96.66 96.49,93.97 95.95,93.43 95.95,92.29 95.46,91.8 95.46,91.6 95.62,91.44 95.74,91.44 96.05,91.75 96.26,91.75 96.43,91.57 96.43,91.39 95.91,90.86 95.91,90.55 96.28,90.17
P2_C5: length 78.8
  TOP w0.178: J3.20 91.99,113.08 91.92,113.01 91.92,112.71 91.6,112.39 91.6,111.29 92.36,110.53 94.75,110.53 v1(94.79,110.5) ; U11.Y24 v2(100.66,87.2)
  LY3 w0.102: v2(100.66,87.2) 100.24,87.2 99.85,87.59 99.42,87.59 99.07,87.95 99.07,89.68 98.58,90.17
  LY3 w0.171: 98.58,90.17 98.58,90.25 98.25,90.57 98.25,91.72 97.85,92.12 97.85,92.85 97.83,92.87 97.83,93.53 98,93.7 99.49,93.7 99.65,93.86 99.65,96.67 99.78,96.8 100.09,96.8 100.21,96.67 100.21,94.96 100.39,94.78 100.86,94.78 101.17,94.46 101.44,94.46 102.07,95.09 102.07,96.32 101.84,96.55 101.67,96.55 101.53,96.42 101.53,95.26 101.4,95.14 101.15,95.14 101.05,95.24 101.05,96.59 101.2,96.74 101.2,96.99 101.2,96.99 101.2,97.57 101.2,97.58 101.2,99.69 101.04,99.86 100.8,99.86 100.64,99.69 100.64,98.04 100.48,97.88 100.25,97.88 100.08,98.04 100.08,100.25 100.25,100.42 101.04,100.42 101.2,100.58 101.2,101.1 101.4,101.3 101.4,102.47 100.92,102.95 100.15,102.95 99.64,102.44 99.64,98.57 99.52,98.45 99.26,98.45 99.13,98.57 99.13,102.78 99.51,103.16 99.51,104.36 98.81,105.06 98.81,106.11 97.55,107.36 95.23,107.36 94.74,107.85 94.74,108.09 94.99,108.34 95.42,108.34 95.61,108.52 95.61,108.93 95.47,109.07 94.93,109.07 94.74,109.25 94.74,109.41 95.55,110.22 95.55,112.29 96.23,112.97 96.87,112.97 97.21,113.31 97.21,113.9 96.75,114.35 96.75,116.2 96.55,116.4 96.3,116.4 96.17,116.27 96.17,113.6 95.06,112.48 95.06,110.77 v1(94.79,110.5)
P2_C6: length 77.5
  TOP w0.178: U11.Y25 v2(100.66,88.2) ; J3.19 91.99,118.39 92.37,118.01 95.52,118.01 95.66,117.87 v1(95.75,117.87)
  LY3 w0.102: v2(100.66,88.2) 100.64,88.2 100.3,88.54 100.3,89.01 100.27,89.04 100.27,89.36 100.3,89.39 100.3,89.69 100.66,90.05
  LY3 w0.171: v1(95.75,117.87) 96.01,118.13 97.22,118.13 97.61,118.51 97.61,119.2 97.83,119.42 99.32,119.42 99.79,118.95 99.79,115.82 99.92,115.69 101.33,115.69 101.45,115.82 101.45,116.17 101.33,116.3 100.5,116.3 100.37,116.43 100.37,117.89 100.73,118.25 101.25,118.25 101.57,117.93 101.57,116.78 102.41,115.93 102.41,115.21 102.19,114.99 100.57,114.99 99.16,113.58 99.16,113.03 98.72,112.59 98.72,112.03 98.01,111.32 98.01,109.44 98.62,108.83 98.62,108.13 100.15,106.59 100.18,106.56 100.18,105.52 102.82,102.88 102.82,101.58 105.52,98.89 105.52,98.34 106.8,97.06 106.8,95.05 108.39,93.46 108.44,93.46 109.89,92 109.89,89.89 110.21,89.58 110.21,88 109.92,87.71 109.22,87.71 108.97,87.96 108.97,89.94 107.46,91.45 105.86,91.45 104.67,92.64 104.06,92.64 103.76,92.95 103.76,93.48 103.5,93.74 102.74,93.74 100.66,91.66 100.66,90.05
P2_C7: length 77.4
  TOP w0.178: J3.18 91.49,113.23 91.46,113.2 91.46,112.92 91.05,112.51 91.05,110.84 90.34,110.13 v1(90.08,110.13) ; U11.Y26 v2(100.66,89.2)
  LY3 w0.102: v2(100.66,89.2) 100.66,88.76 101.06,88.36 101.06,87.96 101.42,87.59 101.83,87.59 102.06,87.36 102.06,87.25 102.71,86.59 102.83,86.59 103.06,86.36 103.06,86.04 102.61,85.59 102.5,85.59 102.27,85.36 102.27,83.76 102.1,83.59 101.19,83.59 100.7,83.11 94.12,83.11 93.59,83.64 93.59,86.86 94.06,87.33 94.06,89.39 93.69,89.76 93.11,89.76 92.69,90.17
  LY3 w0.171: v1(90.08,110.13) 90.04,110.09 89.27,110.09 89.04,110.32 89.04,110.97 88.85,111.17 86.83,111.17 85.37,109.71 85.37,108.92 85.1,108.65 85.1,104.88 84.48,104.25 84.48,103.11 83.85,102.49 83.4,102.49 83.13,102.21 83.13,101.69 82.85,101.41 82.46,101.41 82.19,101.69 82.19,102.21 81.91,102.49 81.52,102.49 81.25,102.21 81.25,101.69 80.97,101.41 80.58,101.41 80.31,101.69 80.31,102.21 80.03,102.49 79.6,102.49 79.25,102.14 79.25,101.45 78.9,101.1 78.03,101.1 77.61,100.68 77.61,99.74 77.99,99.36 78.28,99.36 78.41,99.23 79.48,99.23 79.75,99.51 79.75,99.88 80.03,100.15 80.42,100.15 80.69,99.88 80.69,99.51 80.97,99.23 81.92,99.23 82.15,99 82.63,99 83.05,98.57 83.05,93.98 86.36,90.67 91.12,90.67 91.31,90.48 92.38,90.48 92.69,90.17
P2_C8: length 77.5
  TOP w0.178: U11.V22 v2(98.66,85.2) ; J3.17 v1(91.49,121.49)
  LY3 w0.102: v2(98.66,85.2) 98.66,85.64 98.27,86.04 98.27,86.36 98.27,86.36 98.27,86.73 98.06,86.94 98.06,87.36 97.82,87.6 97.42,87.6 97.07,87.95 97.07,89.35 96.78,89.64 96.31,89.64 95.78,90.17
  LY3 w0.171: 95.78,90.17 95.11,90.84 95.11,91.95 95.59,92.43 95.59,93.58 96.13,94.12 96.13,96.28 95.95,96.46 95.59,96.46 95.39,96.26 95.39,95.65 95.24,95.49 94.6,95.49 94.32,95.22 94.32,94.85 94.55,94.62 95.13,94.62 95.39,94.37 95.39,93.89 95.03,93.53 94.83,93.53 94.4,93.1 94.4,92.81 94.19,92.6 93.94,92.6 93.79,92.76 93.79,98.57 94.23,99.01 94.23,99.63 93.28,100.57 93.28,102.06 93.64,102.41 93.64,105.93 93.41,106.16 93.41,106.36 93.24,106.52 93.01,106.52 92.85,106.36 92.85,99.89 93.26,99.48 93.26,95.66 93.13,95.53 92.8,95.53 92.68,95.66 92.68,99.04 92.29,99.43 92.29,106.92 92.45,107.08 93.24,107.08 93.41,107.25 93.41,109.81 93.33,109.89 93.33,110.63 92.81,111.15 92.81,111.9 93.15,112.24 93.15,116.48 92.16,117.47 92.16,117.83 92.14,117.85 92.14,117.93 91.61,118.47 91.61,121.37 v1(91.49,121.49)
P2_C9: length 77.4
  TOP w0.178: v1(89.83,111.04) 89.83,111.18 90.6,111.95 90.6,112.7 90.99,113.09 J3.16 ; U11.W23 v2(99.66,86.2)
  LY3 w0.102: 93.19,90.17 93.69,90.17 93.79,90.07 93.79,90 94.3,89.49 94.3,87.76 94.47,87.59 95.08,87.59 95.2,87.47 95.2,86.93 95.08,86.8 94.12,86.8 93.8,86.47 93.8,83.89 94.37,83.32 100.63,83.32 101.1,83.8 101.91,83.8 102.07,83.95 102.07,85.45 101.86,85.65 99.89,85.65 99.66,85.87 v2(99.66,86.2)
  LY3 w0.171: 93.19,90.17 92.34,91.03 86.68,91.03 85.81,91.9 85.81,92.8 85.96,92.94 85.96,93.47 85.48,93.95 84.35,93.95 83.41,94.89 83.41,95.32 83.69,95.59 84.6,95.59 84.87,95.87 84.87,96.26 84.6,96.53 83.69,96.53 83.41,96.81 83.41,98.71 82.77,99.35 82.3,99.35 82.06,99.59 81.68,99.59 81.36,99.9 81.36,100.37 81.5,100.5 81.5,100.86 81.81,101.17 82.2,101.17 82.31,101.06 83.04,101.06 83.98,100.12 83.98,97.99 84.28,97.69 84.77,97.69 85,97.92 85,97.94 85.28,98.22 86.03,98.22 86.3,98.49 86.3,98.88 86.03,99.16 85.28,99.16 85,99.43 85,100.65 84.73,100.92 84.12,100.92 83.84,101.2 83.84,101.59 84.11,101.86 84.73,101.86 85,102.14 85,104.28 85.46,104.73 85.46,107.22 86.87,108.63 86.87,109.75 87.35,110.24 88.39,110.24 89.1,109.53 90.33,109.53 90.68,109.88 90.68,110.37 90.23,110.82 89.96,110.82 89.83,110.95 v1(89.83,111.04)
P2_HSYNC: length 77.4
  TOP w0.178: U11.W26 v2(99.66,89.2) ; TP9.1 106.91,103.17 106.91,105 107.33,105.42 107.33,106.14 107.8,106.61 111.15,106.61 111.66,107.12 111.66,108.17 111.21,108.62 108.93,108.62 108.62,108.32 108.62,107.83 108.32,107.53 107.9,107.53 107.6,107.83 107.6,108.32 107.29,108.62 106.85,108.62 106.42,109.06 106.42,114.31 104.91,115.82 99.23,115.82 98.88,115.46 98.88,115.1 98.53,114.75 98.53,113.95 J3.46
  LY4 w0.102: v2(99.66,89.2) 99.66,89.6
  LY4 w0.171: 99.66,89.6 99.01,90.25 99.01,90.73 99.24,90.96 99.57,90.96 100.07,91.46 100.39,91.46 100.69,91.16 100.69,90.96 100.8,90.85 101.31,90.85 101.86,91.4 102.36,91.4 103.01,90.74 103.5,90.74 104.37,91.61 104.68,91.61 105.47,90.82 109.66,90.82 110.54,91.71 110.54,100.23 110.33,100.43 110.15,100.43 109.97,100.25 109.97,94.88 109.84,94.75 109.59,94.75 109.46,94.88 109.46,101.3 108.42,102.35 108.42,102.77 107.71,103.47 107.71,105.02 107.71,105.02 107.71,105.47 107.59,105.6 106.99,105.6 106.87,105.47 106.87,103.13 TP9.1
P2_VSYNC: length 119.4
  TOP w0.178: v1(132.28,89.81) 135.23,89.81 TP23.1 ; U11.U22 v2(97.66,85.2) ; J3.15 v1(90.99,118.69)
  BOTTOM w0.102: 107.63,86.57 107.4,86.81 105.83,86.81 105.5,86.81 105.5,86.81 103.83,86.81 103.5,86.81 103.5,86.81 97.42,86.81 97.07,86.45 97.07,86.24 97.06,86.24 97.06,85.8 v2(97.66,85.2)
  BOTTOM w0.178: v1(90.99,118.69) 91.73,119.43 98.04,119.43 98.96,118.51 101.39,118.51 104.31,121.43 104.31,122.55 104.55,122.79 105.27,122.79 105.6,122.46 105.6,121.05 104,119.45 104,118.66 104.34,118.32 104.34,111.72 107.52,108.53 112.27,108.53 112.65,108.15 118.52,108.15 118.59,108.08 120.34,108.08 120.5,107.93 124.64,107.93 128.16,104.41 128.16,103.19 130.95,100.4 131.04,100.4 132.52,98.92 132.53,98.92 134.93,96.52 134.93,96.5 135.38,96.05 135.38,90.56 135.64,90.31 TP23.1 ; 107.63,86.57 108.27,85.93 123.22,85.93 124.46,84.69 126.77,84.69 129.28,87.2 129.28,87.7 130.25,88.68 131.14,88.68 v1(132.28,89.81)
P2P5V: length 258.9
  TOP w0.254: J3.10 89.49,112.63 89.81,112.31 v1(89.99,112.31) 89.99,112.31 J3.12 ; J2.12 38.87,112.66 v1(38.61,112.39) 38.37,112.63 J2.10
  TOP w0.508: C14.1 88.75,111.19 89.54,111.99 89.66,111.99 v1(89.99,112.31) ; v1(136.58,47.83) 138.02,47.83 R31.1 138.23,45.58 138.47,45.34 TP47.1 ; v1(38.61,112.39) 38.61,111.77 C11.1 ; v1(110.26,127.15) 111.86,128.75 113.97,128.75 114.29,129.07 118.38,129.07 118.7,128.75 119.13,128.75 125.3,122.58 129.83,122.58 129.95,122.45 130.23,122.17 134.48,122.17 135.37,123.06 v1(135.49,123.06)
  BOTTOM w0.508: v1(38.61,112.39) 39.74,112.39 39.9,112.23 39.9,112.12 40.35,111.68 40.98,111.68 41.43,112.12 41.43,112.23 41.59,112.39 43.42,112.39 44.94,113.91 53.16,113.91 53.68,113.39 59.11,113.39 59.84,114.12 68.47,114.12 69,114.65 69.18,114.65 71.67,117.14 72.94,117.14 74.68,118.87 74.68,123.57 75.31,124.21 80.52,124.21 81.66,123.06 81.66,120.37 81.41,120.12 81.41,118.11 80.82,117.52 80.82,114.38 81.57,113.63 82.33,113.63 83.02,112.94 85.76,112.94 87.13,111.57 89.25,111.57 v1(89.99,112.31) 89.99,113.45 88.7,114.74 88.21,114.74 85.09,117.86 84.92,117.93 84.73,118.06 84.57,118.22 84.44,118.41 84.37,118.58 84.19,118.76 84.19,122.5 85.14,123.44 87.46,123.44 87.99,122.92 87.99,121.15 88.5,120.64 89.97,120.64 90.72,121.39 90.72,122.27 94.66,126.21 109.32,126.21 v1(110.26,127.15) ; TP47.1 140.62,44.68 ; TP47.1 139.29,46 ; TP47.1 140.62,46 ; TP47.1 139.29,44.68 ; 136.21,51.31 133.92,51.31 133.88,51.27 133.88,51.25 133.44,50.8 133.41,50.8 133.21,50.6 130.3,50.6 129.37,51.53 129.37,62.37 128.74,63.01 128.74,65.43 129.98,66.67 134.05,66.67 138.62,71.25 138.62,73.28 143.02,77.68 143.02,82.21 141.29,83.95 141.29,92.29 140.73,92.85 140.73,94.68 137.55,97.85 137.55,98.22 132.4,103.37 132.4,107.11 132.59,107.3 132.59,108.2 132.93,108.54 132.93,111.17 135.46,113.69 135.46,123.02 v1(135.49,123.06)
  vias: v1(159.89,36.58) v1(160.26,40.14) v1(160.81,36.58) v1(161.24,40.11) v1(161.8,36.7) v1(161.95,38.93) v1(162,38.01)
P2P5V_CONN: length 140.3
  TOP w0.508: R31.2 140.16,47.17 v1(141.83,45.49) ; v1(142.83,98.75) 141.43,100.15 R14.2
  LY3 w0.508: v1(142.83,98.75) 142.83,98.67 142.36,98.2 142.36,97.17 138.96,93.77 138.96,83.46 138.26,82.76 138.26,74.41 138.76,73.92 138.76,67.7 138.04,66.99 138.04,65.91 136.78,64.64 136.78,61.53 133.27,58.03 133.27,54.29 135.06,52.51 136.01,52.51 140.95,47.58 140.95,47 141.83,46.12 v1(141.83,45.49)
  LY4 w0.508: J37.8 194.13,35.04 192.35,36.82 192.35,40.34 191.07,41.62 187.71,41.62 185.8,39.71 179.62,39.71 178.35,40.98 176.77,40.98 174.33,38.53 172.92,38.53 167.95,33.57 162.2,33.57 160.83,32.19 160.2,32.19 159.31,33.08 146.22,33.08 145.67,33.63 145.67,34.63 144.4,35.9 143.15,35.9 141.1,37.95 141.1,44.7 141.83,45.44 v1(141.83,45.49)
P2P5V_PMD2: length 24.8
  TOP w0.508: TP21.1 140.67,98.6 139.88,98.6 139.5,98.99 R14.1
  BOTTOM w0.508: Q500.4 141.22,100.69 TP21.1 ; Q500.4 Q500.2 ; Q500.4 143.28,100.16 v1(145.06,98.38) ; TP21.1 141.89,98.71 ; TP21.1 141.89,97.38 ; TP21.1 140.56,97.38 ; TP21.1 140.56,98.71
  vias: v1(161.16,89.09) v1(161.48,92.58) v1(162.12,89.09) v1(162.43,92.58) v1(163.07,91.63) v1(163.07,89.41) v1(163.25,90.68)
P3P3V: length 301.6
  TOP w0.178: U11.F17 v2(85.66,80.2) ; U11.F8 v2(85.66,70.2) ; U11.L21 v2(90.66,84.2) ; U11.AA10 v2(101.66,72.2) ; U11.AA7 v2(101.66,69.2) ; U11.F11 v2(85.66,73.2) ; U11.F20 v2(85.66,83.2)
  TOP w0.254: U20.21 185.17,10.63 v1(185.52,10.27) ; v1(65.34,94.04) 65.04,93.74 U8.24 ; U11.AA19 v2(101.66,82.2) ; J32.12 53.4,37.47 v1(53.78,37.85) ; U4.17 74.06,111.89 74.08,111.91 v1(74.08,112.52) ; v1(54.86,79.88) 55,79.75 U14.43 ; v1(53.78,36.84) 53.78,36.83 J32.14 ; J3.5 88.49,121.32 v1(88.75,121.58) 88.99,121.34 J3.7 ; v2(95.66,84.2) U11.R21 ; v2(100.66,84.2) U11.Y21 ; U11.AA16 v2(101.66,79.2) ; U11.AE26 v2(105.66,89.2)
  TOP w0.279: J2.5 37.37,118.9 v1(37.53,118.75) 37.87,119.09 J2.7
  TOP w0.381: U3.4 v1(182.63,119.25) ; D11.2 v1(173.88,17.12) ; D11.3 176.86,14.43 176.27,13.84 175.95,13.84 175.56,13.45 D12.2 v1(174.41,13.06) ; U10.7 v1(135.52,83.11) ; D12.3 177.72,10.56 v1(178.12,10.16) ; U13.33 v1(30.75,68.34) ; R48.1 v1(127.51,21.72) ; R49.2 v1(137.86,22.23) ; v1(45.43,67.77) 45.21,67.55 U13.11 ; J54.3 v1(28.58,4.82) ; v1(131.47,83.24) 131.07,82.85 U9.7 ; C4.1 88.77,121.6 v1(88.75,121.58) ; U10.1 v1(137.11,85.93) ; v1(173.61,18.92) 173.93,19.24 U19.3 ; U12.16 192.39,69.92 v1(193.42,68.9) 192.74,68.21 C26.2 ; v1(171.7,24.64) 172.41,23.93 U16.3 ; U16.8 179.75,25.23 179.45,25.53 179.45,26.29 179.2,26.54 v1(179.2,26.63) ; R51.2 v1(163.26,22.23) ; J55.3 v1(41.28,4.58) ; R50.2 v1(151.19,22.23) ; 179.83,20.19 U19.5 ; U18.5 v1(131.43,17.58) ; U9.1 v1(131.72,84.29) ; U19.4 180.15,19.24 v1(180.27,19.13) ; J56.3 v1(53.35,4.82)
  TOP w0.508: R547.1 v1(86.23,104.27) ; v1(188.29,94.04) 188.29,94.04 188.29,94.04 188.99,93.34 R16.2 ; C34.2 v1(25.32,26.99) ; R53.1 v1(187.07,22.82) ; VR1.3 93,14.14 94.08,15.21 v1(94.11,15.21) ; v1(180.15,21.36) 180.15,20.51 179.83,20.19 ; R530.1 v1(82.04,114.55) ; C2.1 v1(37.47,121.86) ; v1(83.36,103.64) 83.4,103.64 83.4,103.6 83.57,103.77 R548.1 ; R64.2 v1(150.81,9.53) ; R26.1 v1(162.94,51.5) ; R32.2 v1(172.92,43.29) ; R65.2 v1(163,9.53) ; R7.1 v1(48.34,109.33) ; J29.1 v1(113.08,38.1) ; VR2.3 v1(122.14,9.9) ; R36.2 98.23,35.4 v1(98.37,35.54) ; R63.2 v1(138.75,9.53)
  LY5PWR w0.508: TP50.1 176.24,49.56 ; TP50.1 174.92,48.23 ; TP50.1 176.24,48.23 ; TP50.1 174.92,49.56 ; v1(109.14,70.15) 109.14,69.35 109.16,69.34 ; 109.35,15.24 109.35,13.46 J51.1 ; 33.48,27.48 J28.2 ; J28.2 33.48,25.86 ; J28.2 35.1,27.48 ; J28.2 35.1,25.86 ; J28.1 38.49,26.67 38.55,26.61 ; J28.1 35.68,26.67 35.67,26.68 ; J28.1 36.83,25.3 36.63,25.1 ; J51.1 109.09,13.21 107.7,13.21 ; J51.1 109.22,11.81
  BOTTOM w0.102: v2(101.66,79.2) 101.31,79.2 C588.1
  BOTTOM w0.203: U507.6 22.25,74.38 21.58,73.71 v1(21.58,73.69)
  BOTTOM w0.254: U509.6 22.25,69.3 v1(21.78,68.83) ; R610.1 50.04,76.83 v1(49.91,76.71) ; v1(61.5,76.82) 61.5,77.01 61.72,77.23 R608.1 ; v1(185.52,10.27) 185.52,10.27 185.31,10.49 C693.2 ; C606.2 54.99,79.76 v1(54.86,79.88)
  BOTTOM w0.381: R783.2 20.56,4.33 v1(20.83,4.06) ; R700.2 55.09,54.31 v1(55.89,53.51) 55.89,54.33 56.17,54.61 R699.1 ; C516.2 185.93,109.47 v1(186.31,109.86) ; v2(85.66,80.2) 86.6,80.2 C603.1 ; R780.2 117.57,3.43 117.98,3.84 v1(118.11,3.84) ; U523.5 63.96,5.19 v1(64.33,4.83) 63.69,4.19 C707.2 ; v1(74.08,112.52) 74.08,112.3 73.93,112.14 C523.2 ; R512.2 v1(186.63,112.46) ; v1(14.86,14.35) R751.2 ; R785.1 v1(15.88,4.7) ; RN503.7 42.09,94.38 41.78,94.69 41.78,95.26 v1(41.74,95.29) RN503.8 ; v1(22.86,6.6) 22.61,6.86 R772.2 ; C613.1 101.21,69.81 101.25,69.81 101.66,69.4 v2(101.66,69.2) ; RN503.6 42.13,93.58 R584.2 ; C590.1 100.95,81.53 101.57,82.15 101.61,82.15 v2(101.66,82.2) ; v2(101.66,72.2) 100.85,72.2 C615.1 ; R728.2 v1(40.77,31.75) ; v2(100.66,84.2) 100.91,83.95 C568.1 ; v1(173.61,18.92) 173.85,19.16 C688.2 ; U506.24 v1(19.74,87.39) ; R718.2 131.9,37.59 v1(131.35,37.04) ; R727.2 v1(40.89,34.29) ; C629.1 86.33,73.2 v2(85.66,73.2) ; U524.5 18.08,9.43 18.2,9.54 v1(19.05,9.54) 19.55,9.04 19.55,8.53 C698.2 ; R541.2 191.01,104.46 190.82,104.65 v1(190.82,104.65) ; R723.2 v1(40.77,41.91) ; v2(85.66,83.2) 86.44,82.42 C601.1 ; v1(184.56,103.64) 184.57,103.65 R517.1 ; v2(90.66,84.2) 90.66,83.66 C597.1 ; C694.2 v1(120.65,9.14) ; U521.8 103.29,8.09 v1(102.55,8.83) 103.11,9.39 C695.2 ; v1(171.7,24.64) 171.72,24.65 C687.2 ; R543.2 188.21,104.54 v1(188.07,104.68) ; R724.2 v1(40.77,39.37) ; C692.2 43.56,18.67 44.07,19.18 44.69,19.18 v1(44.7,19.17) 44.7,18.64 45.18,18.15 U518.16 ; R725.2 v1(41.18,36.83) ; R733.2 v1(48.07,26.99) ; U516.5 v1(45.42,25.1) ; v1(30.75,68.34) 31.49,68.34 31.61,68.47 C662.2 ; R729.2 v1(40.77,29.21) ; R764.2 v1(108.58,11.3) ; U513.5 44.82,43.83 45.21,43.43 45.21,43.22 v1(45.59,42.84) 45.3,42.55 C685.2 ; FB503.2 25.96,96.96 25.62,97.31 v1(24.77,97.31) ; R570.2 38.94,100.83 v1(39.62,100.14) ; C697.2 72.26,5.65 71.95,5.33 71.95,4 v1(72.01,3.94) 72.45,4.38 72.83,4.38 73.23,4.78 U522.5 ; U519.24 v1(11.41,10.9) ; R754.2 v1(190.42,11.25) ; C595.1 95.44,83.58 95.44,83.98 v2(95.66,84.2) ; R774.1 v1(9.26,8.62) ; R582.2 43.31,91.31 v1(43.29,91.34) ; R741.2 v1(189.25,13.34) ; U514.5 41.41,49.52 41.27,49.66 41.27,50.16 v1(41.02,50.42) 41.4,50.8 C679.2 ; C567.2 131.58,84.42 v1(131.72,84.29) ; R696.1 v1(61.47,57.34) ; R762.2 112.57,10.92 v1(112.83,10.65) ; v1(128.08,39.05) 127.64,39.05 127.15,39.54 R721.2 ; C681.2 v1(140.04,40.67) ; R712.2 v1(39.89,45.33) ; R711.2 v1(46.67,45.91) ; v2(85.66,70.2) 85.66,70.33 85.88,70.55 85.88,70.59 C630.1 ; R756.2 v1(185.94,7.23) ; v1(135.06,41.08) 135.47,40.68 U515.8 136.79,40.65 C683.2 ; v1(93.69,4.42) 93.69,5.26 93.09,5.85 C696.2 ; R719.2 132.72,39.37 v1(133.03,39.69) ; C663.2 45.33,67.87 v1(45.43,67.77) ; R781.2 106.62,3.43 106.62,3.55 v1(106.68,3.55) ; R767.2 104.65,12.45 v1(104.84,12.64) ; v1(105.9,11.96) 105.9,11.71 105.92,11.69 R766.2 ; R747.2 v1(54.75,19.42) ; C509.2 180.39,112.32 180.09,112.01 179.64,112.01 v1(179.26,111.63) ; C525.1 v1(22.86,104.78) ; FB502.2 v1(28.38,102.23) ; R745.1 v1(131.88,19.29)
  BOTTOM w0.508: v1(113.08,38.1) 111,38.1 108.43,35.54 v1(98.37,35.54) ; R560.1 67.13,101.1 67.46,100.78 v1(67.46,100.46) ; v1(65.45,102) 65.45,101.74 65.72,101.47 R561.1 ; C552.1 105.46,92.38 v1(105.89,92.82) ; RN506.7 51.76,83.42 52.29,82.89 v1(52.29,83.1) 52.29,83.12 51.68,82.51 RN506.8 ; v1(25.32,26.99) 25.32,26.18 25.45,26.05 U517.24 ; C636.2 v1(20.35,69.65) ; v1(109.14,70.15) 109.14,69.47 R626.2 ; R692.2 110.72,58.29 v1(111.15,58.72) 110.69,59.18 R691.2 ; v1(191.54,17.32) 191.59,17.27 R736.2 ; v1(39.93,94.3) 40.66,93.57 R584.2 ; FB500.2 v1(33.52,114.1) ; R659.1 v1(66.47,63) ; v1(10.58,115.7) 11.01,116.13 11.01,116.7 DN504.3 ; C635.2 v1(20.33,74.73) ; R658.1 v1(65.47,64.77) ; R752.2 191.71,18.31 v1(191.66,18.36) ; RN505.7 51.94,88.5 52.29,88.15 52.29,88.1 ; v1(172.16,108.13) 171.76,108.53 R519.1 ; R740.2 189.99,14.61 v1(189.74,14.86) ; U525.5 17.97,11.24 v1(18.27,10.95) ; R627.1 76.19,73.22 75.26,73.22 v1(74.9,72.86) ; RN505.8 51.54,87.59 51.94,87.75 52.29,88.1 ; RN505.5 51.8,90.21 52.09,89.93 v1(52.19,89.93) 51.56,89.3 RN505.6 ; v1(54.58,107.39) 54.58,106.58 55,106.16 R533.1 ; C526.2 v1(13.07,103.94) ; v1(165.77,50.72) 166.13,50.37 C673.2 ; R770.1 v1(42.55,7.43) ; v1(150.94,58.65) 151.09,58.65 151.11,58.67 R672.1 ; R504.2 14.99,129.1 15.05,129.16 v1(15.05,129.1) ; R656.1 v1(65.34,66.55) ; R657.1 v1(64.58,65.66) ; R538.2 11.25,107.68 v1(10.61,107.04) ; v1(191.54,16.41) 191.64,16.51 R735.2 ; R665.1 v1(172.8,60.62) ; R753.2 v1(192.18,19.58) ; v1(150.94,56.72) 150.94,56.72 151.09,56.72 151.17,56.64 R674.1 ; U504.5 v1(13.6,106.22) ; C555.1 75.56,92.19 v1(75.56,93.34) ; R507.2 v1(10.49,127.65) ; 52.29,88.1 v1(52.29,87.75) ; R642.1 123.44,66.87 123.19,67.12 v1(123.19,67.12) ; RN506.5 51.97,85.13 v1(52.31,84.79) 51.75,84.22 RN506.6 ; v1(80.86,120.9) 80.77,120.9 80.52,120.65 R544.1 ; v1(151.75,53.92) R676.1 ; R667.2 v1(169.74,53.47) ; C610.1 v1(118.48,69.34) ; C686.2 v1(15.99,28.27) ; R655.1 v1(66.47,68.44) ; R771.1 v1(43.81,7.49)
P3P3V_CONN: length 105.8
  TOP w0.508: R53.2 187.43,26.37 v1(188.51,27.44)
  LY3 w0.508: v1(188.51,27.44) 188.51,34.77 187.63,35.65 187.63,37.29 184.33,40.59 184.33,48.15 185.36,49.18 v1(185.36,52.38)
  LY4 w0.508: v1(174.77,51.46) 173.36,50.04 173.36,50.04 168.25,44.94 159.04,44.94 153.67,39.57 151.19,39.57 149.68,41.08 149.68,43.78 140.93,52.52 135.62,52.52 134.04,54.11 v1(134.04,54.61) 134.03,54.61 134.03,59.86 v1(133.49,60.4)
  BOTTOM w0.381: R685.2 132.78,55.5 133.67,54.61 v1(134.04,54.61) ; R638.2 133.02,60.87 v1(133.49,60.4)
  BOTTOM w0.508: v1(188.51,27.44) 188.51,27.44 190.1,29.03 J37.2 ; v1(174.77,51.46) 179.69,51.46 180.54,52.31 185.29,52.31 v1(185.36,52.38)
P3P3V_EX: length 185.2
  LY3 w0.508: v1(190.79,22.56) 192.37,22.56 194.33,24.51 195.33,24.51 196.4,25.57 196.4,51.79 190.32,57.87 190.32,64.26 189.74,64.84 189.74,66.93 189.99,67.18 189.99,68.98 190.32,69.31 190.32,74.15 187.85,76.62 187.85,79.31 189.12,80.58 189.63,80.58 190.14,81.09 190.14,86.16 189.63,86.67 v1(185.73,86.67)
  LY4 w0.508: J51.3 118.43,13.34 119.7,14.61 119.7,15.77 123.06,19.14 124.18,19.14 125.04,20 125.04,21.5 124.6,21.95 124.33,21.95 122.61,23.66 122.61,24.74 123.06,25.19 123.69,25.19 125.25,23.63 128.65,23.63 129.79,22.48 129.79,22.11 131.22,20.69 172.36,20.69 173.58,21.91 178.52,21.91 179.83,20.6 180.46,20.6 181.77,21.91 190.14,21.91 v1(190.79,22.56) ; v1(172.59,86.61) 172.65,86.67 v1(185.73,86.67)
  BOTTOM w0.508: R587.2 v1(172.59,86.61)
P3P3V_LP: length 464.3
  TOP w0.381: U17.2 183.46,30.42 183.2,30.16 ; U17.7 183.46,27.23 183.13,27.56 ; 183.2,30.16 182.81,30.55 U17.3 ; 183.2,30.16 183.13,30.1 183.13,27.56 ; 183.13,27.56 182.81,27.23 U17.6
  TOP w0.508: U17.3 182.81,32.81 182.45,33.17 181.62,33.17 R38.1 179.77,32.4 C33.2 ; U17.7 183.46,24.7 183.81,24.35 v1(183.9,24.35)
  LY3 w0.508: v1(179.2,81.66) 180.09,80.77 183.33,80.77 183.51,80.95 184,80.95 185.13,79.82 185.13,77.12 182.99,74.98 182.99,72.25 181.74,71 v1(181.74,69.98) 182.67,69.05 184.8,69.05 186.96,66.88 186.96,63.28 188.69,61.55 188.69,56.38 ; v1(192.41,74.1) 192.4,74.1 191.82,74.68 191.82,77.04 192.2,77.42 192.2,87.32 TP500.1 191.01,88.67 191.69,89.35 191.69,92.52 192.76,93.58 192.76,101.22 192.78,101.23 192.78,101.86 192.77,101.86 v1(192.77,103.63) 192.77,104.52 192.6,104.69 192.6,107.6 192,108.2 192,121.75 184.8,128.96 175.55,128.96 172.39,125.79 v1(171.39,125.79) 169.82,127.36 168.04,127.36 165.07,130.34 141.36,130.34 139.23,128.21 v1(139.23,124.45) ; v1(186.42,51.49) 188.22,53.29 188.22,55.92 188.69,56.38 ; 188.69,56.38 189.75,56.38 195.43,50.7 195.43,42.35 193.49,40.41 193.49,37.6 195.56,35.53 195.56,28.06 195,27.5 190.18,27.5 187.01,24.34 183.91,24.34 v1(183.9,24.35)
  LY4 w0.508: v1(181.28,51.51) 180.5,50.73 176.89,50.73 176.59,50.43 176.59,48.47 176,47.88 172.54,47.88 171.71,47.04 171.71,44.46 169.92,42.67 160.12,42.67 159.77,42.32 159.77,42.29 158.02,40.54 158.12,40.45 158.12,39.82 157.67,39.37 157.04,39.37 156.94,39.47 155.81,38.34 150.39,38.34 148.01,40.71 148.01,44.16 140.96,51.21 134.72,51.21 130.25,55.68 v1(130.25,57.45) 130.97,58.17 132.01,58.17 132.8,58.95 132.8,59.8 131.74,60.86 v1(131.74,61.39) ; v1(139.23,124.45) 136.15,124.45 136.09,124.51 134.89,124.51 134.84,124.45 130.48,124.45 124.08,130.86 36.73,130.86 30.78,124.91 23.92,124.91 22.28,126.55 14.08,126.55 12.33,124.8 v1(12.33,124.79) ; v1(192.41,74.1) 186.01,74.1 184.51,72.61 183.62,72.61 182.69,71.67 182.69,70.57 182.1,69.98 v1(181.74,69.98)
  BOTTOM w0.381: v1(192.77,103.63) 192.77,103.64 R540.2 ; R630.1 v1(181.74,69.98) ; v1(192.41,74.1) 192.21,73.91 R611.1 ; R637.2 C643.2 132.16,62.17 131.74,61.75 v1(131.74,61.39) ; C579.2 v1(179.2,81.66)
  BOTTOM w0.508: v1(130.25,57.45) 130.25,56.82 130.68,56.39 R684.2 ; R505.2 12.7,125.97 R506.2 v1(12.33,124.79) ; v1(186.42,51.49) 186.4,51.51 v1(181.28,51.51) ; R511.2 171.39,120.54 v1(171.39,125.79)
P_CLK1: length 77.6
  TOP w0.178: U11.AE22 v2(105.66,85.2) ; J3.54 100.53,113.95 100.53,114.75 100.78,115 104.36,115 105.23,114.13 105.23,114.09 105.42,113.89 105.42,108.34 106.13,107.63 106.16,107.63 106.3,107.48 106.3,105.83 106.17,105.7 105.98,105.7 105.85,105.57 105.85,102.63 105.73,102.5 104.95,102.5 104.82,102.63 104.82,106.55 104.95,106.68 TP8.1
  LY4 w0.102: v2(105.66,85.2) 105.89,85.2 106.27,85.58 106.27,86.36 106.71,86.81 107.63,86.81
  LY4 w0.171: TP8.1 111.82,106.68 113.16,105.35 113.16,103.01 113.6,102.57 115.69,102.57 117.87,100.39 117.87,89.71 117.59,89.43 117.16,89.43 116.9,89.69 116.9,94.06 116.62,94.34 116.09,94.34 115.87,94.12 115.87,87.34 114.54,86 108.83,86 108.02,86.81 107.63,86.81
P_CLK2: length 79.3
  TOP w0.178: v1(88.71,115.95) 88.71,115.49 88.84,115.37 89.66,115.37 90.09,114.93 90.27,114.93 90.49,114.71 J3.14 ; U11.W25 v2(99.66,88.2)
  LY3 w0.171: v1(88.71,115.95) 88.98,116.22 88.98,119.3 90.55,120.86 90.55,122.87 92.95,125.28 101.34,125.28 102.83,123.79 106.99,123.79 107.33,123.45 107.33,119.21 106.94,118.83 106.94,117.91 106.45,117.41 106.45,114.57 106.89,114.13 106.89,112.16 106.94,112.1 106.94,109.91 106.74,109.71 106.74,108.93 107.78,107.9 107.78,106.28 TP10.1
  LY4 w0.102: 100.05,89.7 100.05,89.37 100.06,89.36 100.06,89.04 99.66,88.64 v2(99.66,88.2)
  LY4 w0.171: 100.05,89.7 100.4,90.05 107.47,90.05 107.63,89.88 110.17,89.88 111.49,91.21 111.49,101.1 110.41,102.18 109.91,102.18 109.36,102.73 109.36,103.16 108.65,103.86 108.65,105.4 TP10.1
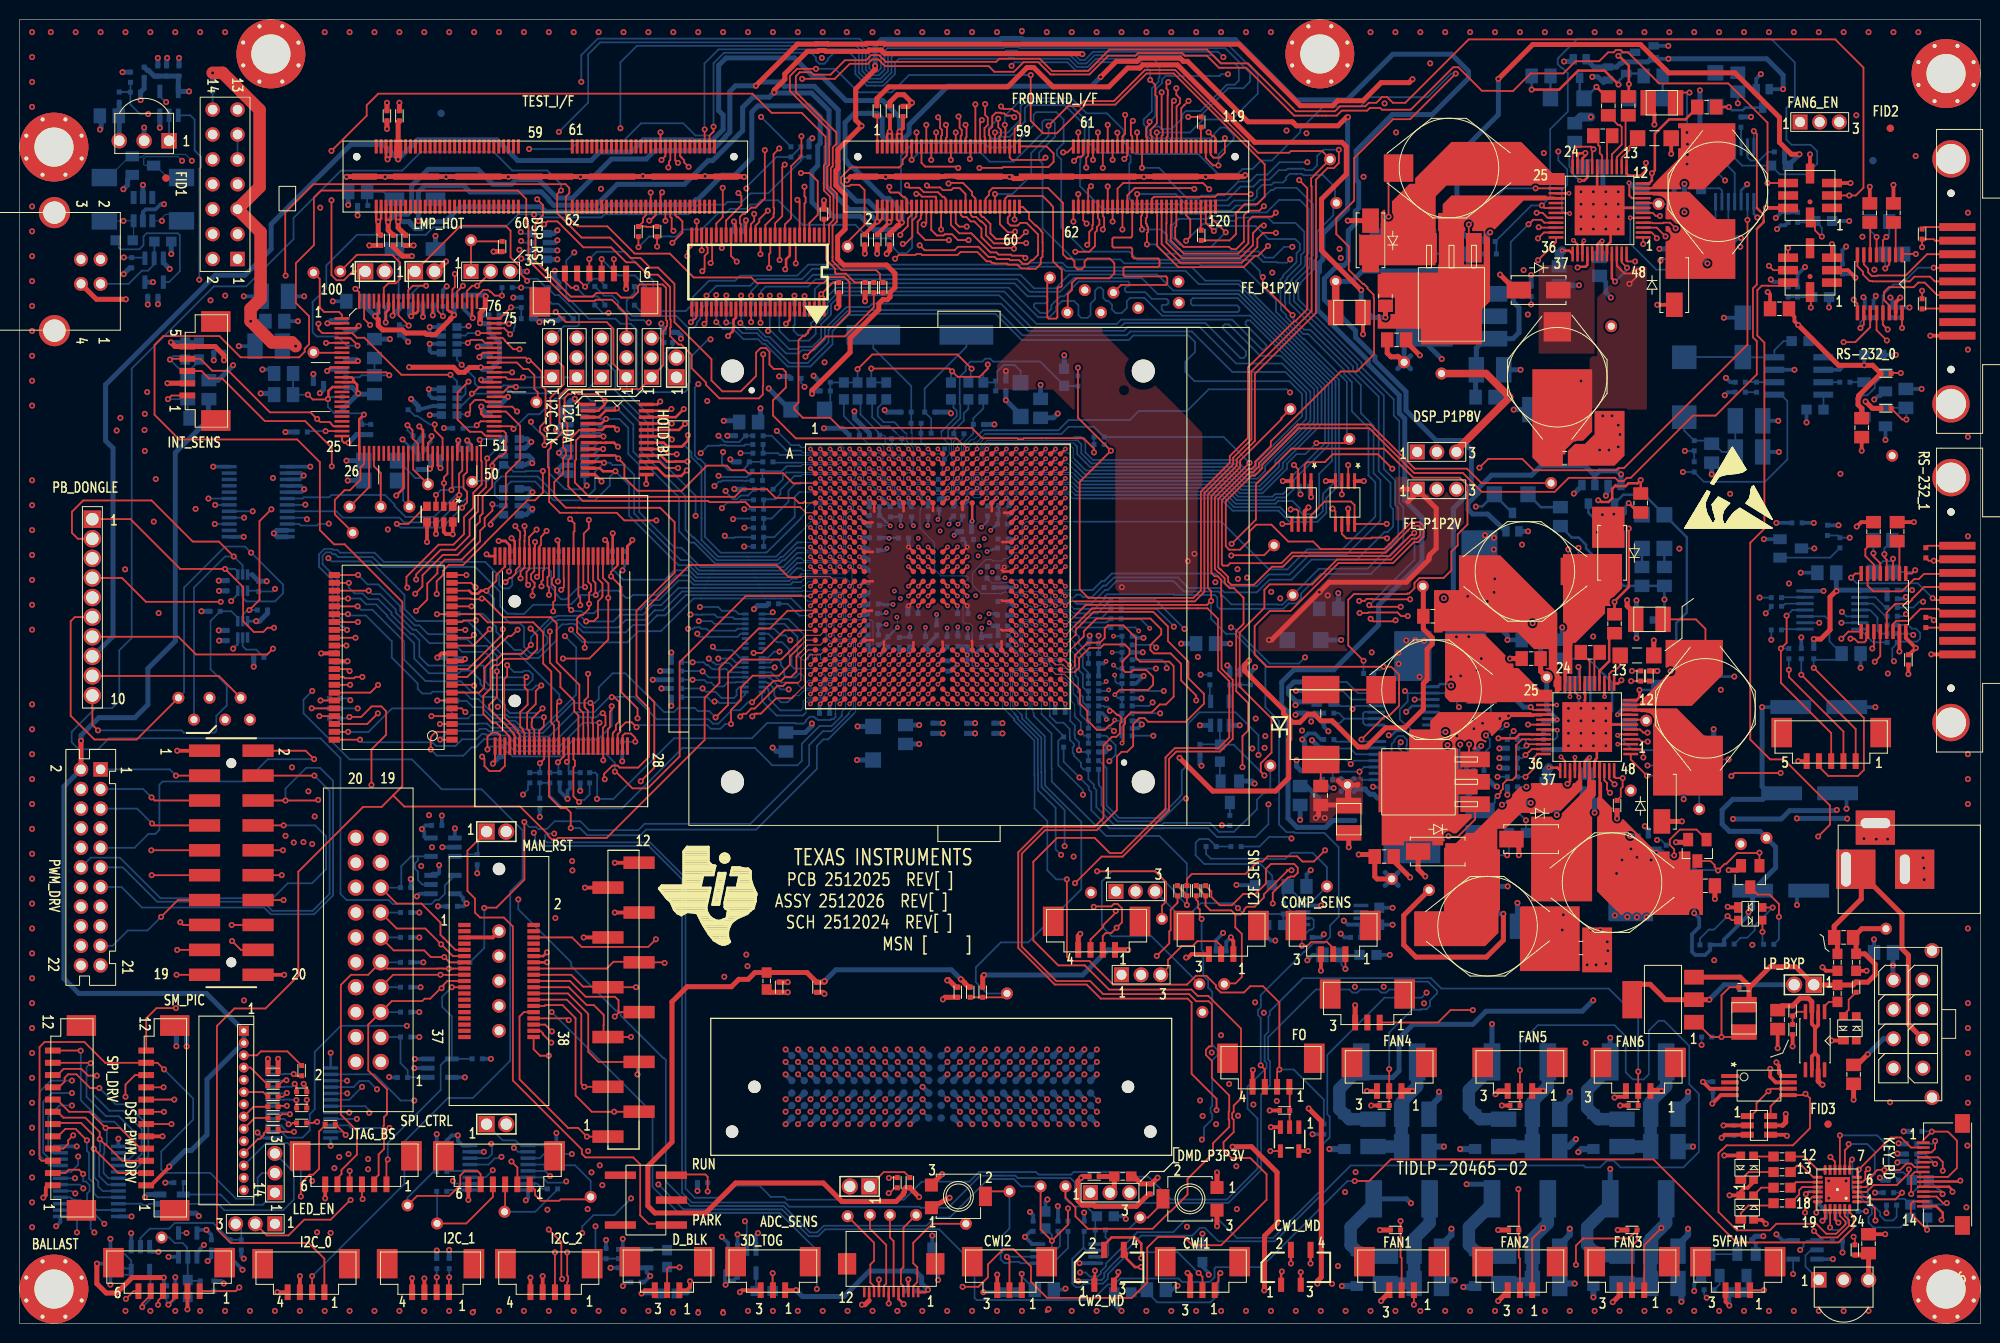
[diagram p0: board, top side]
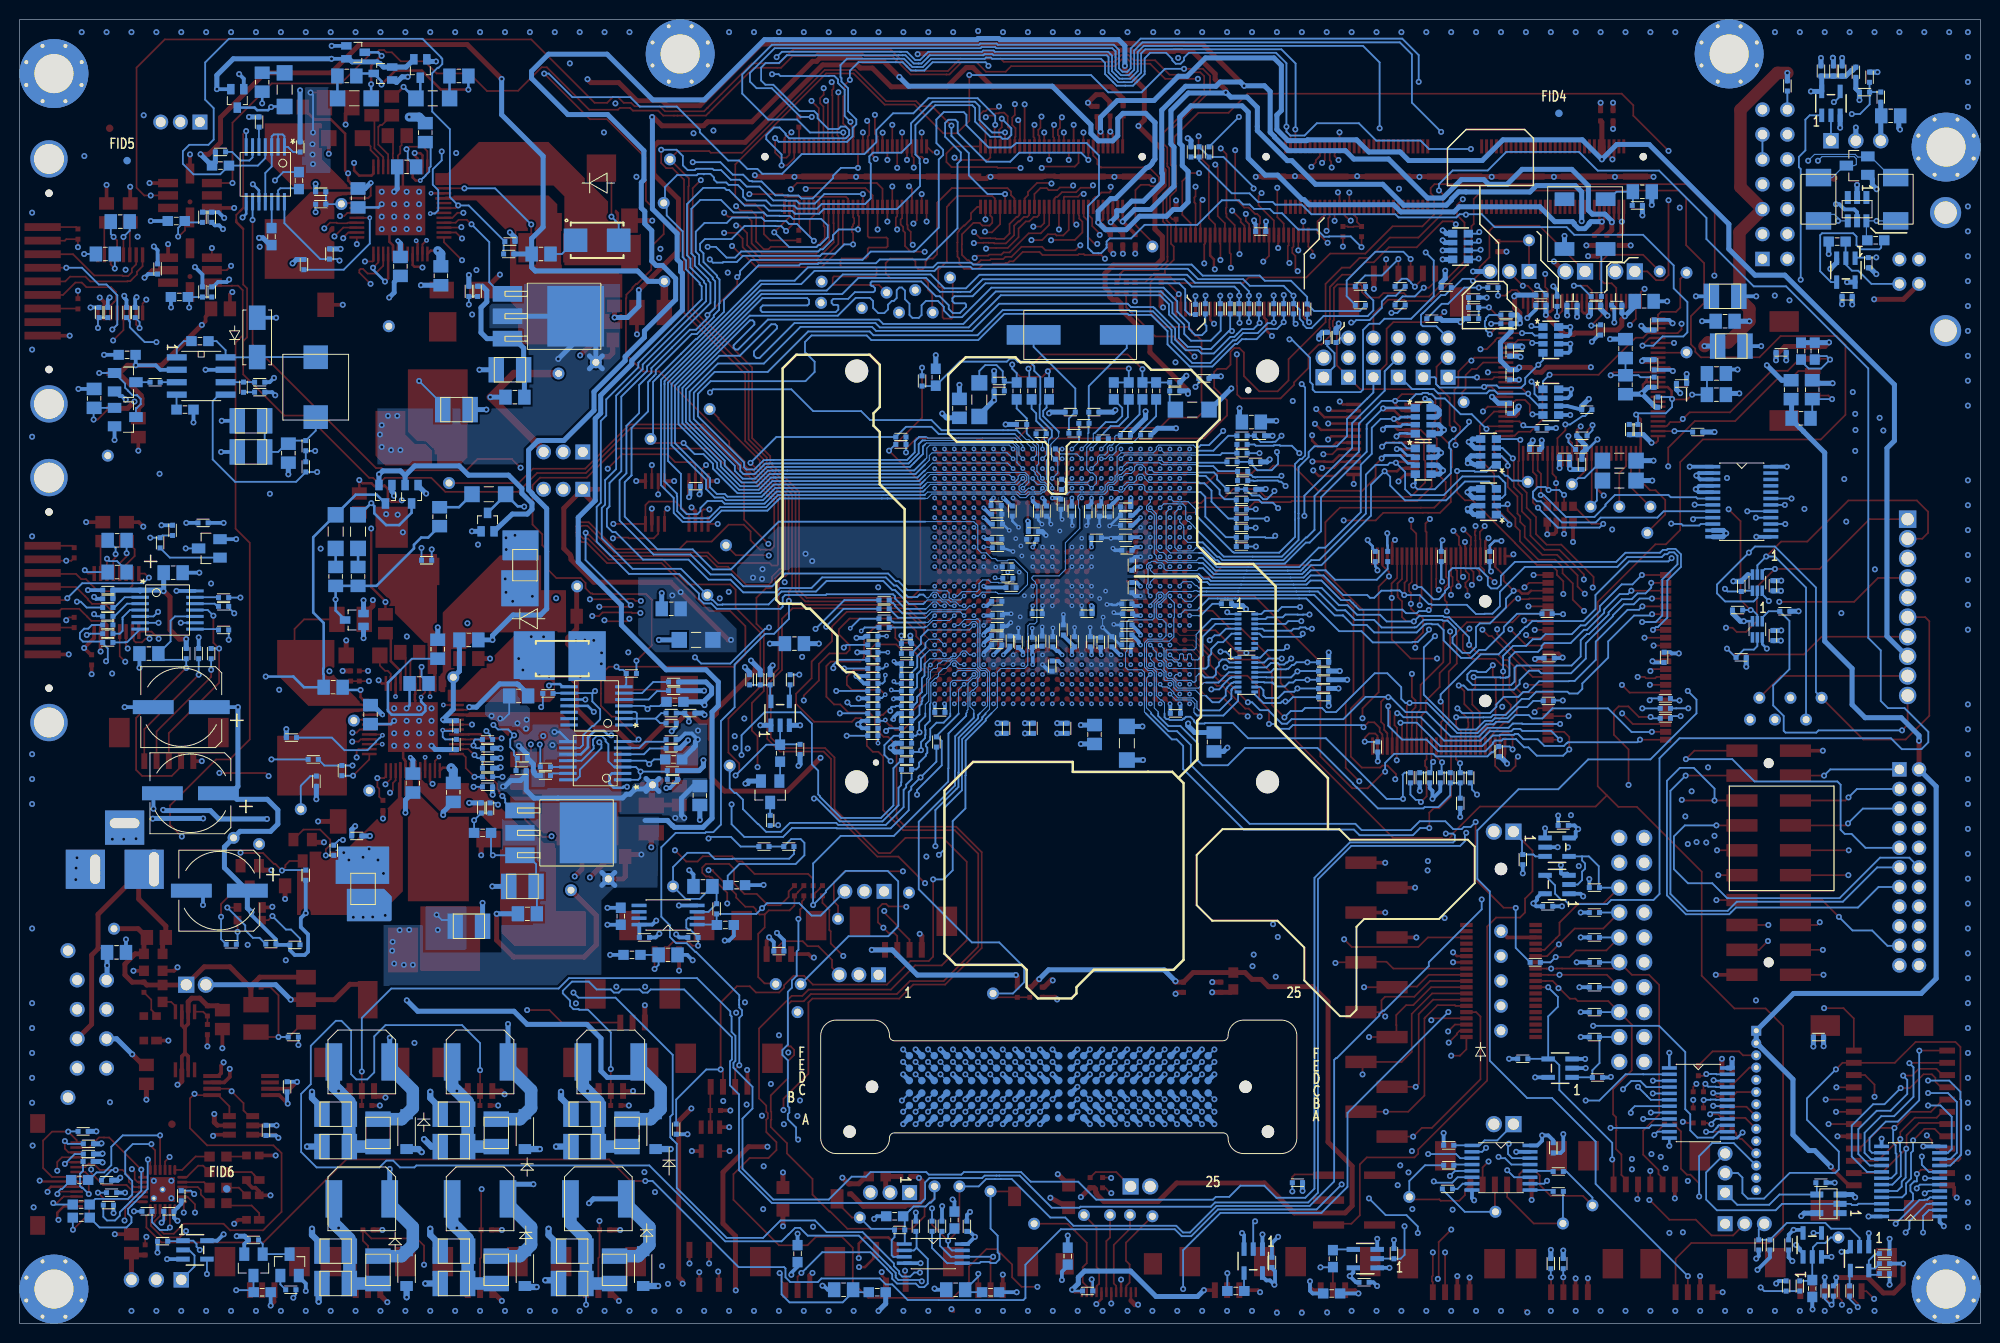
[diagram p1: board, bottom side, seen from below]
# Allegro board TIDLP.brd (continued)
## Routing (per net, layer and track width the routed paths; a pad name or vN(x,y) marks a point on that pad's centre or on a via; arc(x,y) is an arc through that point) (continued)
P_CLK3: length 79.4
  TOP w0.178: J3.119 121.99,120.79 121.98,120.8 121.98,120.94 121.78,121.13 121.65,121.13 v1(121.27,121.5) ; U11.AF23 v2(106.66,86.2)
  LY4 w0.171: v1(121.27,121.5) 118.29,121.5 117.6,122.2 115.72,122.2 115.5,121.98 114.83,121.98 114.15,122.66 114.15,123.08 113.3,123.92 108.19,123.92 105.04,120.78 104.29,120.78 103.09,119.57 103.09,118.11 104.81,116.39 104.81,110.56 105.21,110.17 105.21,109.61 107.12,107.7 112.15,107.7 114.11,105.74 114.11,104.58 114.1,104.57 TP13.1 116,103.58 118.81,100.77 118.81,88.9 114.97,85.06 107.8,85.06 v2(106.66,86.2)
P_DATAEN1: length 78.1
  TOP w0.178: v1(113.99,121.49) 113.99,120.07 J3.87 ; U11.AF22 v2(106.66,85.2)
  LY4 w0.171: v2(106.66,85.2) 106.69,85.17 106.69,84.84 107.41,84.12 107.51,84.12 107.76,83.87 115.28,83.87 119.75,88.34 119.75,101.55 120.36,102.16 120.36,104.88 119.88,105.36 119.49,105.36 TP15.1 117.34,104.11 116.8,104.65 116.8,109.13 116.46,109.47 114.44,109.47 113.55,110.36 111.98,110.36 110.33,108.71 107.45,108.71 106.52,109.64 106.52,110.18 106.15,110.56 106.15,110.56 105.75,110.95 105.75,116.77 105.56,116.97 105.56,117.16 104.4,118.33 104.39,118.33 104.04,118.68 104.04,119.2 104.66,119.81 105.4,119.81 108.5,122.91 112.3,122.91 113.13,122.09 113.39,122.09 v1(113.99,121.49)
P_DATAEN2: length 77.5
  TOP w0.178: U11.W24 v2(99.66,87.2) ; v1(101.45,123.05) 101.29,123.21 100.66,123.21 100.43,123.43 100.15,123.43 100.07,123.51 99.57,123.51 99.21,123.15 99.21,122.08 98.88,121.74 98.88,121.24 98.99,121.13 J3.47
  LY3 w0.171: v1(101.45,123.05) 101.65,122.85 103.14,122.85 105.84,120.15 105.84,118.14 105.51,117.81 105.51,114.18 105.8,113.89 105.8,109.32 105.8,108.54 106.84,107.51 106.84,105.82 107.1,105.55 107.1,105.54 107.65,104.99 107.66,104.99 108.23,104.42 109.09,104.42 109.59,104.92 109.59,106.18 109.72,106.3 110.39,106.3 110.52,106.18 110.52,104.72 110.33,104.53 110.33,103.16 TP11.1
  LY4 w0.102: 107.45,88.18 107.07,87.8 106.33,87.8 106.15,87.62 105.49,87.62 105.26,87.85 105.26,89.49 105.12,89.62 102.48,89.62 102.2,89.34 102.2,88.87 101.94,88.62 101.53,88.62 101.27,88.36 101.27,88.23 100.84,87.8 100.42,87.8 99.82,87.2 v2(99.66,87.2)
  LY4 w0.171: TP11.1 110.32,103.14 111.48,103.14 111.74,102.89 111.74,102.21 112.45,101.5 112.72,101.5 113.03,101.19 115.12,101.19 115.82,100.5 115.82,99.91 115.29,99.38 113.18,99.38 112.45,98.64 112.45,96.38 114.44,94.39 114.44,93.24 114.06,92.86 113.12,92.86 112.76,92.51 112.76,87.73 112.44,87.41 109.36,87.41 108.59,88.18 107.45,88.18
P_INTZ: length 62.2
  TOP w0.178: v1(154.88,108.46) 156.72,110.3 U2.36
  LY3 w0.171: v1(154.88,108.46) 154.88,107.71 155.21,107.38 155.21,106.52 154.88,106.19 154.88,78.19 152.92,76.23 152.92,72.41 151.7,71.18 151.16,71.18 150.3,70.33 150.3,67.22 150.16,67.08 150.16,65.78 149.55,65.17 149.55,64.28 147.62,62.35 147.62,60.17 148.46,59.34 148.46,58.82 148.43,58.79 148.43,58.38 148.5,58.31 148.5,57.2 149.95,55.75 v1(150.75,55.75)
  BOTTOM w0.178: R675.1 v1(150.75,55.75)
PACKET_RDY: length 114
  TOP w0.178: U11.F25 v2(85.66,88.2) ; v1(25.68,83.05) 24.46,81.84 24.46,73.8 v1(23.43,72.77) ; TP38.1 20.31,66.05 J20.9
  LY3 w0.171: v1(23.43,72.77) 24,72.77 25.15,71.62 25.15,70.12 24.52,69.49 24.52,65.8 TP38.1
  LY4 w0.102: 80.07,87.42 80.24,87.59 84.02,87.59 84.23,87.81 84.83,87.81 85.22,88.2 v2(85.66,88.2)
  LY4 w0.171: v1(25.68,83.05) 26.89,83.05 27.29,82.65 29.53,82.65 30.39,81.79 30.39,80.37 30.7,80.05 32.32,80.05 32.74,79.63 32.75,79.63 32.78,79.6 34.28,79.6 36.64,81.97 37.6,81.97 37.86,82.22 38.65,82.22 38.98,81.89 40.66,81.89 42.01,83.24 44.31,83.24 44.88,83.81 44.99,83.81 45.44,84.26 45.44,84.75 45.31,84.88 45.31,86.2 46,86.89 48.46,86.89 49.24,87.68 51.37,87.68 52.04,88.35 52.71,88.35 53.18,88.82 54.17,88.82 54.76,89.41 55.25,89.41 55.26,89.41 55.34,89.41 55.69,89.06 55.69,88.98 55.84,88.82 57.18,88.82 57.61,88.4 60.39,88.4 60.82,88.83 64.07,88.83 65.34,87.56 65.91,86.99 66.52,86.38 68.26,86.38 68.64,86.76 68.64,87.3 69.52,88.18 69.72,88.18 70.07,88.53 70.07,88.73 70.23,88.89 70.27,88.89 70.27,89.02 70.78,89.53 71.42,89.53 71.47,89.58 72.04,89.58 72.08,89.53 73.75,89.53 74.29,89 75.76,89 77.34,87.42 80.07,87.42
  BOTTOM w0.178: R788.2 v1(23.43,72.77) 23.24,72.77 22.75,72.27 U509.2
PB_INDEX: length 44.4
  TOP w0.178: U11.AE9 v2(105.66,71.2) ; J29.2 110.48,39.52 110.79,39.82 111.36,39.82 v1(111.9,40.36) 112.44,40.91 112.44,42.34 111.99,42.79 111.61,42.79 111.36,42.54 109.6,42.54 v1(109.56,42.49)
  LY3 w0.102: v2(105.66,71.2) 105.27,70.81 104.28,70.81 104.06,70.58 104.06,67.9 104.3,67.65
  LY3 w0.171: v1(109.56,42.49) 109.39,42.66 108.24,42.66 105.96,44.94 105.96,47.23 105.63,47.55 105.63,48.04 105.96,48.37 105.96,59.04 106.16,59.25 106.16,59.46 106.37,59.67 106.37,60.05 107.76,61.44 107.76,64.26 107.23,64.79 107.23,65.46 105.03,67.65 104.3,67.65
PB_IR_ENABLE: length 44.4
  TOP w0.178: J29.3 109.23,39.14 110.54,40.45 110.54,40.63 111.8,41.9 v1(111.8,42.07) ; U11.AD9 v2(104.66,71.2)
  LY4 w0.171: v1(111.8,42.07) 111.49,42.39 111.15,42.39 110.13,43.4 110.13,45.17 109.79,45.52 109.66,45.52 109.31,45.87 109.31,46 108.57,46.74 107.29,46.74 106.23,47.8 v1(106.23,47.8)
  BOTTOM w0.102: 101.49,62.23 101.07,62.65 101.07,66.45 101.42,66.8 101.84,66.8 102.06,67.01 102.06,70.36 102.04,70.38 102.04,71.02 102.06,71.04 102.06,71.66 102.26,71.87 102.41,71.87 102.48,71.8 103.62,71.8 104.22,71.2 v2(104.66,71.2)
  BOTTOM w0.178: 101.49,62.23 101.49,62.16 101.78,61.86 101.78,61.83 101.81,61.8 101.81,61.65 103.86,59.59 103.86,56.06 103.88,56.04 103.88,54.38 105.67,52.59 105.67,48.35 v1(106.23,47.8)
PB_SPARE: length 172.1
  TOP w0.178: v1(123.59,78.33) 123.59,78.36 126.94,78.36 TP30.1 ; v1(7.99,60.49) 7.42,61.06 J20.10 ; U11.AB10 v2(102.66,72.2)
  LY3 w0.102: 107.63,71.81 103.5,71.81 103.11,72.2 v2(102.66,72.2)
  LY3 w0.171: 107.63,71.81 107.74,71.91 113.94,71.91 116.24,74.21 119.43,74.21 123.59,78.36 v1(123.59,78.33)
  LY4 w0.102: v2(102.66,72.2) 102.18,71.71 101.43,71.71 100.18,70.46 89.42,70.46 89.24,70.64 85.55,70.64 85.27,70.36 85.27,70.18 84.68,69.59 84.5,69.59 84.27,69.36 84.27,68.19 84.06,67.97 84.06,66.04 83.83,65.81 82.6,65.81 82.06,65.26 82.06,65.04 81.83,64.81 81.59,64.81 81.06,64.27 81.06,64.04 80.61,63.59 80.5,63.59 80.27,63.36 80.27,62.8 79.7,62.23
  LY4 w0.171: v1(7.99,60.49) 8.78,59.7 26.67,59.7 29.68,56.7 30.85,56.7 34.29,53.26 49.32,53.26 49.82,52.76 50.72,52.76 52.08,51.4 52.08,51.36 52.6,50.84 54.73,50.84 55.02,51.13 65.21,51.13 71.4,57.32 73.69,57.32 75.7,59.33 77.34,59.33 79.58,61.57 79.58,62.11 79.7,62.23
  BOTTOM w0.178: U509.1 22.25,71.99 21.59,72.64 R793.2 19.47,71.66 19.47,66.73 21.13,65.08 21.13,63.04 20.06,61.97 20.06,60.45 19.87,60.27 16.73,60.27 16.51,60.49 v1(7.99,60.49)
PGOOD: length 60.8
  TOP w0.178: v1(154.88,110.68) 155.48,111.29 U2.35
  LY3 w0.171: v1(154.88,110.68) 155.82,109.73 155.82,86.81 155.31,86.29 155.31,79.79 156.24,78.86 156.24,78.37 155.89,78.02 155.32,78.02 154.01,76.71 154.01,74.72 153.35,74.07 153.35,72.23 151.88,70.75 151.34,70.75 150.74,70.15 150.74,69.3 150.89,69.15 150.89,65.9 149.98,64.99 149.98,64.1 149.92,64.04 149.92,61.17 150.13,60.96 150.13,60.26 150.34,60.05 150.34,60.03 150.24,59.93 150.24,59.44 150.34,59.34 150.34,58.26 v1(150.94,57.66)
  BOTTOM w0.483: R673.1 151.09,57.66 151.09,57.66 v1(150.94,57.66)
PIPESTAT0: length 81.1
  TOP w0.178: J32.38 52.43,27.97 53.09,27.3 v1(53.98,27.3)
  LY3 w0.171: v1(69.27,71.64) 69.2,71.57 67.22,71.57 66.86,71.21 66.8,71.21 64.62,69.04 64.62,67.49 64.62,67.49 63.65,66.52 63.65,66.38 63.39,66.12 63.39,64.27 63.65,64.02 63.91,63.76 63.91,62.91 64.49,62.33 64.49,62.15 65.28,61.36 65.28,60.82 65.28,54.58 64.87,54.17 64.2,54.17 63.77,53.75 63.77,51.21 63.44,50.88 62.77,50.88 62.52,50.63 62.52,44.76 62.34,44.58 61.3,44.58 61.12,44.4 61.12,44.07 61.3,43.89 62.34,43.89 62.52,43.71 62.52,43.38 62.34,43.21 61.3,43.21 61.12,43.03 61.12,42.7 61.3,42.52 62.34,42.52 62.52,42.34 62.52,37.7 62.34,37.52 62.01,37.52 61.84,37.7 61.84,41.46 61.71,41.58 61.28,41.58 61.15,41.46 61.15,37.01 61.33,36.83 62.34,36.83 62.52,36.66 62.52,36.05 62.4,35.92 60.48,35.92 59.65,35.1 59.65,32.62 58.82,31.79 56.03,31.79 55.41,31.17 55.41,30.49 55.74,30.16 56.06,30.16 56.19,30.03 56.19,29.58 56.06,29.45 55.62,29.45 55.41,29.25 55.41,28.74 v1(53.98,27.3)
  BOTTOM w0.178: RN507.14 70.87,71.36 70.59,71.64 v1(69.27,71.64)
PIPESTAT0R: length 12.4
  TOP w0.178: U11.C6 v2(82.66,68.2)
  BOTTOM w0.102: 79.69,67.82 79.82,67.69 80.37,67.69 80.47,67.79 80.47,68.2 80.57,68.3 80.78,68.3 80.88,68.2 80.88,67.79 80.98,67.69 81.18,67.69 81.29,67.79 81.29,68.2 81.39,68.3 81.59,68.3 81.69,68.2 81.69,67.79 81.79,67.69 82.15,67.69 v2(82.66,68.2)
  BOTTOM w0.178: 79.69,67.82 79.34,68.17 79.34,70.03 78.01,71.36 RN507.3
PIPESTAT1: length 80.3
  TOP w0.178: v1(54.23,28.64) 53.4,29.47 53.4,29.57 53.12,29.84 J32.36
  LY3 w0.171: v1(68.43,72.31) 68.37,72.26 67.47,72.26 67.22,72 66.98,72 64.19,69.22 64.19,67.67 63.22,66.7 63.22,66.56 62.96,66.3 62.96,64.1 63.47,63.58 63.47,62.63 64.85,61.25 64.85,58.27 64.67,58.09 63.65,58.09 63.47,57.91 63.47,57.58 63.65,57.4 64.67,57.4 64.85,57.22 64.85,56.89 64.67,56.72 63.65,56.72 63.47,56.54 63.47,56.21 63.65,56.03 64.67,56.03 64.85,55.85 64.85,55.25 64.48,54.88 63.77,54.88 63.6,54.7 63.54,54.7 63.34,54.51 63.34,51.58 63.22,51.46 62.83,51.46 62.7,51.58 62.7,54.87 62.58,55 62.19,55 62.06,54.87 62.06,50.3 61.89,50.12 60.93,50.12 60.76,49.94 60.76,49.61 60.93,49.44 61.89,49.44 62.06,49.26 62.06,48.93 61.89,48.75 60.5,48.75 60.37,48.62 60.37,48.19 60.5,48.06 61.89,48.06 62.06,47.89 62.06,45.48 61.76,45.17 60.9,45.17 60.42,44.68 60.42,42.73 59.99,42.3 59.99,41.69 60.57,41.11 60.57,36.87 59.14,35.44 59.14,33.81 58.09,32.75 55.62,32.75 54.98,32.11 54.98,29.39 v1(54.23,28.64)
  BOTTOM w0.178: RN507.15 72.91,71.86 72.74,72.03 71.17,72.03 70.88,72.31 69.64,72.31 69.63,72.29 69.1,72.29 69.08,72.31 v1(68.43,72.31)
PIPESTAT1R: length 12.6
  TOP w0.178: U11.B5 v2(81.66,67.2)
  BOTTOM w0.102: 79.69,70.57 79.99,70.28 79.99,68.92 80.2,68.71 82.99,68.71 83.07,68.64 83.07,67.89 82.87,67.69 82.44,67.69 82.24,67.49 81.95,67.49 v2(81.66,67.2)
  BOTTOM w0.178: RN507.2 78.4,71.86 79.69,70.57
PIPESTAT2: length 81.1
  TOP w0.178: v1(54.29,29.78) 53.59,30.48 J32.34
  LY3 w0.171: v1(69.39,73.08) 69.26,72.95 67.29,72.95 63.76,69.41 63.76,67.85 63.76,67.84 62.79,66.88 62.79,66.74 62.53,66.48 62.53,63.92 62.77,63.68 62.77,62.83 64.38,61.21 64.38,59.06 63.99,58.66 63.25,58.66 62.83,58.23 62.83,55.97 62.37,55.52 61.79,55.52 61.46,55.18 61.46,50.94 61.09,50.57 60.66,50.57 59.67,49.58 59.67,48.26 59.49,48.08 58.76,48.08 58.59,47.9 58.59,47.57 58.76,47.39 59.49,47.39 59.67,47.21 59.67,46.88 59.49,46.71 58.33,46.71 58.2,46.58 58.2,46.15 58.33,46.02 59.49,46.02 59.67,45.84 59.67,45.05 59.56,44.94 59.56,38 59.38,37.82 59.05,37.82 58.87,38 58.87,43.81 58.75,43.93 58.31,43.93 58.19,43.81 58.19,37.32 58.36,37.14 59.38,37.14 59.56,36.96 59.56,36.53 58.59,35.56 58.59,34.53 57.24,33.18 54.85,33.18 53.67,32.01 53.67,31.46 54.29,30.84 v1(54.29,29.78)
  BOTTOM w0.178: v1(69.39,73.08) 69.39,72.96 69.5,73.08 71.25,73.08 71.63,72.69 73.01,72.69 73.34,72.36 RN507.16
PIPESTAT2R: length 11
  TOP w0.178: U11.A4 v2(80.66,66.2)
  LY3 w0.171: v2(80.66,66.2) 80.09,66.77 78.17,66.77 77.69,67.25 77.69,67.49 76.9,68.29 76.9,72.47 v1(76.82,72.55)
  BOTTOM w0.178: RN507.1 76.63,72.36 v1(76.82,72.55)
PLLD_VAD: length 10.3
  TOP w0.178: U11.K25 v2(89.66,88.2)
  BOTTOM w0.102: 85.66,90.83 C550.1 86.5,89.78 87.8,89.78 88.16,89.42 88.16,88.92 88.49,88.59 88.83,88.59 89.22,88.2 v2(89.66,88.2)
  BOTTOM w0.178: 85.66,90.83 85.66,90.96 84.07,92.55 FB1.2
PLLD_VDD: length 16.5
  TOP w0.178: U11.L22 v2(90.66,85.2)
  BOTTOM w0.102: C546.1 93.19,85.6 91.06,85.6 v2(90.66,85.2) 90.17,85.69 90.17,86.4 90.54,86.77 90.78,86.77 90.82,86.81 90.83,86.81 91.06,87.04 91.06,87.04 91.15,87.14 91.15,89.34 90.53,89.97 90.53,89.97 90.49,90.02 90.49,90.76 90.41,90.83 90.32,90.83
  BOTTOM w0.178: 90.32,90.83 89.22,91.94 88.14,91.94 87.53,92.55 87.53,93.4 FB5.2
PLLM1_VAD: length 10.6
  TOP w0.178: U11.L24 v2(90.66,87.2)
  BOTTOM w0.102: 87.57,90.83 87.57,90.76 C548.1 88.16,90.6 88.29,90.47 88.29,89.88 88.58,89.59 88.83,89.59 89.06,89.36 89.06,88.85 89.31,88.59 89.83,88.59 90.06,88.36 90.06,87.81 v2(90.66,87.2)
  BOTTOM w0.178: 87.57,90.83 87.57,90.93 85.76,92.73 85.76,93.97 FB2.2
PLLM1_VDD: length 7.8
  TOP w0.178: U11.L26 v2(90.66,89.2)
  BOTTOM w0.102: v2(90.66,89.2) 89.99,89.87 C547.1 89.41,90.83
  BOTTOM w0.178: 89.41,90.83 88.71,91.53 87.88,91.53 86.96,92.45 86.96,94.17 FB4.2
PLLM2_VAD: length 7.7
  TOP w0.178: U11.R25 v2(95.66,88.2)
  BOTTOM w0.102: v2(95.66,88.2) 95.25,88.61 95.25,89.93 95.49,90.17 95.49,90.54 C549.1 95.28,90.83
  BOTTOM w0.178: FB3.2 96.77,93.31 96.3,92.84 96.3,92.07 95.28,91.04 95.28,90.83
PLLM2_VDD: length 10.5
  TOP w0.178: U11.P23 v2(94.66,86.2)
  BOTTOM w0.102: v2(94.66,86.2) 94.11,86.75 94.11,87.93 C645.1 94.82,88.64 94.82,89.67 94.02,90.47 94.02,90.83
  BOTTOM w0.178: 94.02,90.83 94.02,90.98 95.59,92.55 95.59,93.08 95.25,93.43 95.25,94.01 FB6.2
PLLS_VAD: length 10
  TOP w0.178: U11.R23 v2(95.66,86.2)
  BOTTOM w0.102: 97,90.51 96.07,89.58 96.07,87.69 96.23,87.53 96.23,86.9 95.86,86.53 95.86,86.4 v2(95.66,86.2) ; 97.28,90.79 97.28,90.83
  BOTTOM w0.178: 97,90.51 97.28,90.79 ; 97.28,90.83 C584.1 97.28,92.32 98.3,93.34 FB7.2
PLUG_DETECT: length 132.6
  TOP w0.178: U11.F23 v2(85.66,86.2) ; v1(25.84,68.83) 25.25,68.24 18,68.24 16.18,70.05 J20.7
  LY3 w0.171: v1(25.84,86.24) 25.79,86.19 25.79,84.28 26.63,83.44 26.63,81.61 26.87,81.36 26.87,76.57 27.13,76.32 27.13,70.12 v1(25.84,68.83) 25.84,63.94 TP39.1
  LY4 w0.102: 79.74,85.8 85.01,85.8 85.41,86.2 v2(85.66,86.2)
  LY4 w0.171: 79.74,85.8 79.35,85.8 79.12,86.03 76.38,86.03 75.74,86.68 73.41,86.68 72.92,87.16 71.14,87.16 70.37,86.39 70.37,85.76 69.15,84.55 65.75,84.55 65.26,85.03 64.67,85.03 64.31,84.68 63.27,84.68 62.78,85.17 59,85.17 58.1,86.07 57.6,86.07 56.76,85.22 55.52,85.22 55.4,85.11 54.02,85.11 53.22,85.9 51.83,85.9 50.84,84.91 47.46,84.91 46.81,84.27 46.81,83.08 45.44,81.71 42.42,81.71 38.55,77.84 37.28,77.84 36.73,77.29 33.39,77.29 32.8,76.71 31.08,76.71 30.68,77.1 24.16,77.1 22.92,78.34 22.92,78.91 24.55,80.54 24.55,83.64 25.96,85.05 25.96,86.12 v1(25.84,86.24)
  BOTTOM w0.178: U509.5 22.75,69.09 23.1,68.73 24.13,68.73 R664.2 24.96,67.94 v1(25.84,68.83)
PM_ADR_0: length 63.4
  TOP w0.178: U14.31 61,77.32 60.77,77.09 60.75,77.09 60.33,76.66 v1(60.33,76.2) 61.38,75.15 61.38,64.38 63.03,62.74 v1(63.03,61.73) ; U11.C7 v2(82.66,69.2) ; v1(45.47,62.36) 45.08,62.75 U13.5
  LY4 w0.171: v2(82.66,69.2) 81,69.2 76.38,64.58 73.48,64.58 72.19,63.29 72.19,62.9 71.58,62.29 71.58,61.57 71.24,61.22 70.74,61.22 70.23,61.73 v1(63.03,61.73) 61.67,61.73 59.75,59.81 52.65,59.81 51.07,61.4 46.43,61.4 v1(45.47,62.36)
PM_ADR_1: length 53.2
  TOP w0.102: 79.69,69.15 80.25,69.7 U11.A7
  TOP w0.178: U14.26 61,60.06 61.06,60.12 61.06,60.16 61.27,60.36 61.27,60.76 61.82,61.31 62.43,61.31 62.92,60.83 v1(62.92,60.82) ; 79.69,69.15 78.56,68.02 78.56,67.18 77.45,66.07 74.77,66.07 73.57,64.87 73.57,63.59 72.56,62.58 v1(72.56,61.15) ; U13.4 v1(42.01,61.95)
  LY4 w0.171: v1(42.01,61.95) 42.08,62.02 44.15,62.02 45.21,60.96 50.61,60.96 52.24,59.33 59.99,59.33 61.48,60.82 v1(62.92,60.82)
  BOTTOM w0.178: v1(62.92,60.82) 62.92,60.83 63.12,61.03 70.13,61.03 70.51,60.65 71.47,60.65 71.96,61.15 v1(72.56,61.15)
PM_ADR_2: length 54.1
  TOP w0.102: U11.B7 81.66,69.2 80.39,69.2 79.69,68.51
  TOP w0.178: v1(74.72,63.36) 76.91,65.55 77.67,65.55 78.05,65.94 78.69,65.94 79.24,66.48 79.24,68.05 79.69,68.51 ; U14.25 60.49,60.2 60.6,60.31 60.6,60.35 60.81,60.55 60.81,61.05 61.13,61.37 61.13,63.42 60.67,63.88 v1(60.39,63.88) ; U13.3 v1(42.87,61.14)
  BOTTOM w0.178: v1(74.72,63.36) 74.29,63.36 73.48,62.55 72.63,62.55 71.25,61.17 70.72,61.17 70.27,61.63 64.99,61.63 62.7,63.91 60.67,63.91 60.63,63.88 v1(60.39,63.88) 60.14,63.88 58.62,62.35 56.5,62.35 54.01,59.87 51.14,59.87 50.25,60.76 48.12,60.76 47.71,61.17 47.7,61.17 47.68,61.19 46.74,61.19 46.7,61.14 v1(42.87,61.14)
PM_ADR_3: length 57.7
  TOP w0.178: v1(41.93,58.55) 41.93,59.82 42.45,60.35 U13.2 ; U14.24 60,60.61 60.21,60.83 60.21,62.43 60.39,62.61 v1(60.39,62.96) ; U11.C8 v2(82.66,70.2)
  LY4 w0.102: 79.96,70.2 v2(82.66,70.2)
  LY4 w0.171: v1(60.39,62.96) 61.34,63.91 65.45,63.91 65.72,64.17 68.91,64.17 69.26,63.82 70.05,63.82 70.61,64.38 70.61,64.88 71.53,65.8 72.1,65.8 73.41,67.11 75.12,67.11 77.25,69.24 77.4,69.24 77.41,69.24 78.02,69.24 78.17,69.09 78.86,69.09 79.96,70.2
  BOTTOM w0.178: v1(60.39,62.96) 60.39,60.96 58.98,59.55 56.49,59.55 55.3,58.36 50.49,58.36 49.72,59.13 49.72,59.24 49.51,59.46 48.83,59.46 48.69,59.59 47.4,59.59 47.38,59.61 47.37,59.61 46.53,58.76 46.1,58.76 45.25,57.91 42.56,57.91 41.93,58.54 v1(41.93,58.55)
PM_ADR_4: length 55.5
  TOP w0.178: v1(59.53,57.44) 59.53,58.85 U14.23 59.49,60.76 59.76,61.02 59.76,61.97 v1(59.48,62.24) ; U11.D8 v2(83.66,70.2) ; U13.1 v1(42.88,59.54)
  LY4 w0.102: v2(83.66,70.2) 83.66,69.97 83.22,69.52 83.22,69.11 82.85,68.75 81.83,68.75
  LY4 w0.171: 81.83,68.75 81.34,68.75 77.42,64.83 77.15,64.83 76.36,64.04 74.48,64.04 71.94,61.5 71.94,61.42 71.17,60.65 64.06,60.65 63.75,60.34 63.4,60 62.32,60 59.76,57.44 v1(59.53,57.44)
  BOTTOM w0.178: v1(59.48,62.24) 59.25,62.24 58.84,61.83 57.07,61.83 54.69,59.45 50.99,59.45 50.04,60.4 47.85,60.4 47.6,60.65 46.94,60.65 46.73,60.44 43.77,60.44 v1(42.88,59.54)
PM_ADR_5: length 60.8
  TOP w0.102: 79.69,70.7 79.77,70.7 U11.A8
  TOP w0.178: v1(59.15,61.27) 59,61.12 U14.22 ; U13.44 v1(34.72,59.54) ; 79.69,70.7 78.01,70.7 75.7,68.39 v1(74.87,68.39)
  LY4 w0.171: v1(59.15,61.27) 58.83,61.59 58.83,63.15 60.56,64.89 64.65,64.89 65.13,65.37 65.72,65.37 66.02,65.06 67.89,65.06 68.25,64.71 68.88,64.71 69.41,64.17 69.91,64.17 70.26,64.52 70.26,65.13 71.29,66.16 71.95,66.16 72.93,67.13 72.93,67.42 73.94,68.43 74.83,68.43 v1(74.87,68.39)
  BOTTOM w0.178: v1(34.72,59.54) 34.98,59.28 42.05,59.28 42.14,59.19 42.2,59.19 42.48,58.9 44.46,58.9 45.15,59.59 46.61,59.59 47.15,60.13 47.49,60.13 47.58,60.04 48.98,60.04 49.04,59.98 49.73,59.98 50.24,59.46 50.82,58.88 55.09,58.88 57.47,61.27 v1(59.15,61.27)
PM_ADR_6: length 68
  TOP w0.102: U11.B8 81.66,70.19 80.17,70.19 79.69,69.72
  TOP w0.178: U14.21 58.49,61.15 58.43,61.22 58.43,61.72 58.49,61.78 58.49,63.03 58.23,63.3 v1(58.22,63.3) ; 79.69,69.72 77.69,67.71 73.65,67.71 72.26,66.32 72.26,63.09 v1(70.99,61.82) ; U13.43 v1(33.51,60.35)
  BOTTOM w0.178: v1(70.99,61.82) 70.34,62.46 69.19,62.46 68.87,62.78 67.16,62.78 66.74,62.36 65.73,62.36 61.78,66.32 60.49,66.32 59.07,64.9 59.07,63.71 58.65,63.3 v1(58.22,63.3) 56.43,63.3 53.36,60.22 51.29,60.22 50.4,61.11 49.64,61.11 49.38,61.37 48.11,61.37 47.43,62.05 46.07,62.05 45.73,61.72 44.67,61.72 43.65,62.74 37.99,62.74 35.57,60.33 33.53,60.33 v1(33.51,60.35)
PM_ADR_7: length 72.1
  TOP w0.178: U13.42 35.45,61.14 v1(36.54,62.23) ; v1(57.99,66.26) 57.99,63.92 57.61,63.55 57.61,63.04 57.62,63.04 57.62,62.84 57.95,62.51 57.95,61 58,60.96 U14.20 ; U11.C9 v2(82.66,71.2)
  LY4 w0.102: 79.69,72.49 80.37,71.81 81.15,71.81 81.36,71.6 81.91,71.6 82.31,71.2 v2(82.66,71.2)
  LY4 w0.171: v1(36.54,62.23) 37.22,62.92 42.94,62.92 43.61,63.59 47.02,63.59 48.31,62.3 48.32,62.31 49.02,62.31 49.37,62.66 49.37,64.09 48.08,65.37 48.08,66.76 49.27,67.94 49.78,67.94 51.19,66.53 51.94,66.53 52.2,66.26 v1(57.99,66.26) 59.43,67.7 62.87,67.7 65.05,69.88 66.53,69.88 67.42,68.99 69.69,68.99 70.46,69.76 70.46,70.48 71.25,71.27 74.13,71.27 74.21,71.2 76.02,71.2 76.42,71.59 77.21,71.59 78.11,72.49 79.69,72.49
PM_ADR_8: length 68.7
  TOP w0.178: U11.D9 v2(83.66,71.2) ; v1(53.47,61.83) 53.47,61.83 53.47,60.92 53,60.45 U14.10 ; U13.28 v1(33.48,72.34)
  LY4 w0.102: 80.18,69.81 82.83,69.81 83.07,70.05 83.07,70.45 83.66,71.04 v2(83.66,71.2)
  LY4 w0.171: 80.18,69.81 78.21,67.84 76.93,67.84 74.54,65.45 71.79,65.45 70.97,64.62 70.97,64.2 71.48,63.69 71.48,63.19 71.13,62.84 70.64,62.84 70.02,63.46 69.12,63.46 68.84,63.74 65.96,63.74 64.97,62.76 61.47,62.76 59.39,60.68 54.64,60.68 53.47,61.85 53.47,61.83 v1(53.47,61.83)
  BOTTOM w0.178: v1(33.48,72.34) 33.62,72.21 35.32,72.21 37.96,69.57 37.96,67.92 40.6,65.28 40.6,64.72 41.07,64.26 41.93,64.26 42.12,64.44 45.3,64.44 46.04,63.7 46.78,63.7 48.41,62.08 49.68,62.08 49.93,61.82 50.69,61.82 50.7,61.82 53.43,61.82 53.47,61.85 53.47,61.84 v1(53.47,61.83)
PM_ADR_9: length 72.5
  TOP w0.178: v1(53.34,62.74) 53.34,62.76 52.26,61.68 52.26,61.38 52.22,61.34 52.22,60.83 52.49,60.56 U14.9 ; U11.E9 v2(84.66,71.2) ; U13.27 v1(34.47,73.14)
  LY4 w0.102: v2(84.66,71.2) 84.06,70.59 83.5,70.59 83.27,70.36 83.27,69.96 82.91,69.6 80.71,69.6 80.37,69.26
  LY4 w0.171: 80.37,69.26 76.16,65.04 73.33,65.04 71.84,63.55 71.84,63.05 71.28,62.49 69.71,62.49 69.55,62.32 61.65,62.32 59.57,60.24 52.83,60.24 52.24,60.84 52.24,61.65 53.34,62.76 v1(53.34,62.74)
  BOTTOM w0.178: v1(34.47,73.14) 34.82,72.8 35.98,72.8 39.23,69.55 39.23,67.69 41.39,65.53 41.4,65.54 41.93,65.54 41.97,65.51 45,65.51 46.09,64.42 46.62,64.42 47.13,63.91 48.61,63.91 49.37,63.15 49.37,62.9 50.01,62.26 52.85,62.26 53.34,62.76 v1(53.34,62.74)
PM_ADR_10: length 66.4
  TOP w0.178: U14.8 52,60.42 51.77,60.65 51.77,62.31 52.64,63.18 52.64,64.51 v1(53.21,65.07) ; U11.A9 v2(80.66,71.2) ; U13.26 v1(33.5,73.94)
  LY4 w0.171: v1(53.21,65.07) 59.04,65.07 60.96,66.99 63.72,66.99 64.58,67.86 65.99,67.86 66,67.84 66.72,67.84 67.15,68.28 68.99,68.28 70.04,67.22 71.51,67.22 71.86,67.57 71.86,69.33 73.09,70.56 73.84,70.56 73.91,70.49 76.31,70.49 76.71,70.88 77.51,70.88 78.17,71.54 79.69,71.54 80.03,71.2 v2(80.66,71.2)
  BOTTOM w0.178: v1(53.21,65.07) 52.7,65.07 52.28,64.65 47.57,64.65 47,65.23 47,65.61 46.02,66.59 45.06,66.59 44.79,66.32 41.74,66.32 40.25,67.82 40.25,69.37 37.48,72.13 37.48,72.23 36.36,73.36 35.34,73.36 34.75,73.94 v1(33.5,73.94)
PM_ADR_11: length 67.7
  TOP w0.178: v1(51.69,65.93) 51.52,65.76 51.52,64.87 51.82,64.56 51.82,63.13 51.06,62.36 51.06,60.85 51.31,60.6 51.31,60.46 51.49,60.27 U14.7 ; U13.25 v1(35.6,74.75) ; U11.B9 v2(81.66,71.2)
  LY4 w0.102: v2(81.66,71.2) 81.33,71.2 80.92,71.6 80.14,71.6 79.69,72.05
  LY4 w0.171: 79.69,72.05 78.18,72.05 77.36,71.24 76.56,71.24 76.16,70.84 74.06,70.84 73.99,70.92 72.73,70.92 71.31,69.49 71.31,68.78 70.96,68.43 70.46,68.43 70.26,68.63 67.27,68.63 66.38,69.52 65.19,69.52 63.02,67.35 60.54,67.35 58.8,65.61 53.52,65.61 53.45,65.67 52.96,65.67 52.93,65.64 51.98,65.64 v1(51.69,65.93)
  BOTTOM w0.178: v1(35.6,74.75) 35.95,74.4 36.79,74.4 38.37,72.82 38.37,72.5 40.11,70.76 40.43,70.76 41.8,69.39 44.46,69.39 44.75,69.1 44.75,68.88 45.13,68.5 47.43,68.5 48.04,67.9 48.04,66.07 48.2,65.91 48.38,65.91 48.41,65.87 48.94,65.87 48.98,65.91 51.66,65.91 v1(51.69,65.93)
PM_ADR_12: length 81
  TOP w0.178: U11.C10 v2(82.66,72.2) ; U13.24 v1(33.57,75.54) ; U14.6 51,60.12 50.85,60.27 50.85,60.41 49.46,61.8 49.46,63.1 49.43,63.17 49.38,63.39 49.38,63.61 49.43,63.83 49.43,65.73 49.73,66.04 v1(49.73,67.14)
  LY4 w0.102: v2(82.66,72.2) 82.66,71.76 83.06,71.36 83.06,71.04 82.83,70.81 79.92,70.81 79.69,71.04
  LY4 w0.171: 79.69,71.04 78.16,71.04 77.26,70.13 74.42,70.13 72.22,67.93 72.22,67.43 71.66,66.87 70.86,66.87 69.91,65.91 69.41,65.91 69.06,66.26 67.52,66.26 66.29,67.49 65.86,67.49 65.84,67.5 64.95,67.5 64.08,66.63 61.22,66.63 59.82,65.24 59.06,64.47 51.75,64.47 50.86,65.36 50.86,66.01 v1(49.73,67.14)
  BOTTOM w0.178: v1(49.73,67.14) 50.43,66.44 51.29,66.44 51.42,66.57 51.95,66.57 52.33,66.2 52.33,65.66 51.8,65.13 47.86,65.13 47.52,65.47 47.52,66.87 47.28,67.11 41.69,67.11 40.77,68.03 40.77,69.68 40.14,70.31 39.93,70.31 37.93,72.32 37.93,72.53 36.58,73.88 35.56,73.88 34.97,74.47 34.16,74.47 33.57,75.05 v1(33.57,75.54)
PM_ADR_13: length 74.6
  TOP w0.178: v1(48.68,66.51) 48.68,63.88 47.9,63.1 47.9,62.71 50.39,60.22 50.39,60.08 50.49,59.98 U14.5 ; U11.D10 v2(83.66,72.2) ; U13.23 v1(34.53,76.35)
  LY4 w0.102: 79.69,70.59 81.83,70.59 82.01,70.41 82.31,70.41 82.5,70.59 82.92,70.59 83.27,70.94 83.27,71.36 83.66,71.76 v2(83.66,72.2)
  LY4 w0.171: 79.69,70.59 78.22,70.59 77.3,69.67 74.57,69.67 72.57,67.67 72.57,67.28 71.81,66.51 71.01,66.51 70.05,65.56 69.39,65.56 68.89,65.06 68.4,65.06 67.55,65.91 66.93,65.91 65.7,67.14 65.09,67.14 63.27,65.32 60.49,65.32 59.21,64.04 57.66,64.04 56.45,62.84 54.25,62.84 53.59,63.5 52.11,63.5 49.1,66.51 v1(48.68,66.51)
  BOTTOM w0.178: v1(48.68,66.51) 48.68,68.09 47.66,69.11 46.33,69.11 45.66,69.79 44.88,69.79 44.36,70.31 41.67,70.31 40.77,71.2 40.3,71.2 38.81,72.69 38.81,73.16 36.59,75.39 35.48,75.39 v1(34.53,76.35)
PM_ADR_14: length 75.9
  TOP w0.178: v1(52.11,70.88) 52.79,70.2 52.79,68.76 51.82,67.79 49.47,67.79 48.83,67.15 48.41,67.15 48.04,66.78 48.04,64.76 47.29,64.02 47.29,62.18 48.2,61.27 48.59,61.27 49.95,59.91 49.95,59.83 50,59.78 U14.4 ; U11.E10 v2(84.66,72.2) ; U13.22 v1(45.57,76.35)
  LY4 w0.102: v2(84.66,72.2) 84.2,72.66 84.2,75.56 83.95,75.82 80.39,75.82
  LY4 w0.171: 80.39,75.82 79.6,75.03 78.85,75.03 78.59,74.78 75.8,74.78 75.76,74.74 74.62,74.74 74.38,74.5 68.88,74.5 68.48,74.9 63.12,74.9 59.19,70.97 56.9,70.97 56.41,71.46 56.01,71.46 55.73,71.18 53.37,71.18 53.07,70.88 v1(52.11,70.88) 51.41,70.17 47.37,70.17 46.79,69.59 45.74,69.59 44.85,70.47 44.85,71.23 45.98,72.36 46.65,72.36 48.21,73.93 48.21,74.98 47.86,75.33 47.86,75.33 47.85,75.33 47.23,75.33 46.4,76.16 45.76,76.16 v1(45.57,76.35)
PM_ADR_15: length 82.6
  TOP w0.178: U13.21 46.03,75.54 46.49,75.09 v1(46.5,75.09) ; U11.C11 v2(82.66,73.2) ; v1(47.17,57.82) 47.41,57.58 47.41,56.86 47.92,56.35 48.97,56.35 49.49,56.88 U14.3
  LY3 w0.171: v1(47.17,57.82) 46.01,58.97 46.01,59.53 43.87,61.68 43.87,70.03 44.89,71.06 44.89,73.48 v1(46.5,75.09)
  LY4 w0.102: 79.76,73.31 80.26,72.81 81.83,72.81 82.22,73.2 v2(82.66,73.2)
  LY4 w0.171: 79.76,73.31 79.69,73.31 79.69,73.31 76.19,73.31 75.85,72.97 75.85,72.47 75.29,71.91 74.5,71.91 73.72,72.7 71.72,72.7 71.03,72.01 70.49,72.01 70.22,71.74 70.22,71.25 69.72,70.74 69.72,70.11 69.37,69.76 67.96,69.76 67.06,70.66 64.82,70.66 63.7,69.55 57.37,69.55 57.07,69.24 57.07,69.19 56.3,68.42 54.67,68.42 54.2,67.95 51.55,67.95 50.46,69.04 48.35,69.04 46.44,67.13 44.5,67.13 43.56,68.08 43.56,71.83 43.93,72.2 43.93,72.44 44.94,73.45 44.94,73.52 v1(46.5,75.09)
PM_ADR_16: length 54.7
  TOP w0.178: 49.49,77.19 49.2,76.9 49.2,76.9 48.63,76.33 48.63,75.76 v1(47.61,74.74) ; U13.20 45.84,74.75 ; U11.D11 v2(83.66,73.2)
  TOP w0.254: 49.49,77.19 U14.54 ; v1(47.61,74.74) 47.6,74.75 47.06,74.75 46.77,74.45 46.13,74.45 45.84,74.75
  BOTTOM w0.102: v2(83.66,73.2) 83.66,73.36 83.07,73.95 83.07,74.36 82.76,74.67 80.26,74.67 80.19,74.75 79.92,74.75 79.84,74.66 79.69,74.66
  BOTTOM w0.178: v1(47.61,74.74) 47.6,74.74 47.6,74.71 48.39,73.93 48.39,73.04 50.02,71.41 51.06,71.41 51.45,71.02 51.45,69.01 52.06,68.4 52.83,68.4 53.84,69.41 53.84,69.98 53.49,70.33 53.49,70.83 54.34,71.69 54.82,71.69 54.9,71.76 56.78,71.76 57.54,71.01 57.68,71.01 57.69,70.99 61.06,70.99 61.84,71.77 63.79,71.77 64.76,72.74 64.82,72.74 65.64,72.74 67.33,74.43 67.56,74.66 68.43,74.66 68.44,74.66 69.77,74.66 69.77,74.66 75.71,74.66 75.71,74.66 78.92,74.66 78.93,74.66 79.69,74.66
PM_ADR_17: length 76.1
  TOP w0.178: U11.A11 v2(80.66,73.2) ; U13.19 46,73.94 46.07,73.87 47.03,73.87 47.1,73.94 v1(47.15,73.94) 47.44,73.94 49.34,72.04 54.15,72.04 54.78,71.41 54.78,67.45 57.09,65.14 57.09,62.66 57.49,62.26 U14.19
  LY4 w0.171: v2(80.66,73.2) 80.06,73.8 79.69,73.8 79.6,73.71 76.24,73.71 76.21,73.67 75.87,73.67 75.5,73.3 75.5,72.61 75.15,72.26 74.65,72.26 73.79,73.13 71.11,73.13 69.86,71.89 69.86,71.39 69.51,71.04 68.85,71.04 66.91,72.98 63.32,72.98 60.66,70.32 60.24,69.9 57.22,69.9 56.71,69.39 56.71,69.33 56.27,68.9 54.49,68.9 53.98,68.39 52.16,68.39 52.16,68.38 51.62,68.38 51.23,68.77 50.61,69.39 48.2,69.39 47.29,68.48 44.82,68.48 43.99,69.31 43.99,71.65 44.36,72.03 44.36,72.26 46.05,73.94 v1(47.15,73.94)
PM_ADR_18: length 61.8
  TOP w0.178: v1(54.08,70.58) 54.08,67.41 55.16,66.34 55.16,64.91 56.57,63.5 56.57,62.45 57,62.02 U14.18 ; U13.18 v1(46.09,73.14) ; U11.B11 v2(81.66,73.2)
  LY4 w0.102: v2(81.66,73.2) 81.63,73.2 81.02,73.81 80.5,73.81 80.05,74.25
  LY4 w0.171: v1(46.09,73.14) 44.42,71.47 44.42,69.83 45.17,69.09 47.18,69.09 47.85,69.75 50.75,69.75 50.77,69.74 51.82,69.74 51.9,69.82 52.4,69.82 52.48,69.74 53.24,69.74 v1(54.08,70.58) 55.41,69.25 56.13,69.25 56.36,69.48 56.36,69.54 57.08,70.26 60.09,70.26 60.3,70.46 63.39,73.56 68.06,73.56 69.14,72.48 69.64,72.48 70.71,73.56 74.15,73.56 74.44,73.56 74.91,74.03 76.06,74.03 76.1,74.07 79.19,74.07 79.38,74.25 80.05,74.25
PM_ADR_19: length 58.3
  TOP w0.178: U11.C12 v2(82.66,74.2)
  LY4 w0.171: v1(51.34,53.94) 51.45,53.83 53.31,53.83 54.56,52.59 57.97,52.59 v1(58.88,53.5)
  BOTTOM w0.102: v2(82.66,74.2) 82.66,73.95 82.21,73.51 82.21,72.04 82.27,71.98 82.27,70.04 82.71,69.59 84.83,69.59 85.06,69.36 85.06,67.04 84.82,66.8 84.36,66.8 84.06,66.49 84.06,64.04 83.61,63.59 83.5,63.59 83.22,63.31 83.22,62.23
  BOTTOM w0.178: 83.22,62.23 83.22,61.84 83.02,61.64 82.78,61.64 82.69,61.55 81.44,61.55 81.3,61.69 81.21,61.69 81.05,61.86 81.05,61.88 80.57,61.88 80.2,61.51 80.2,61.4 79.99,61.19 79.13,61.19 79.07,61.25 76.25,61.25 74.69,59.69 66.75,59.69 60.56,53.5 v1(58.88,53.5) 58.91,53.52 58.91,55.93 58.94,55.97 58.73,56.18 R697.1 ; v1(51.34,53.94) 51.85,54.45 51.85,54.9 52.04,55.09 R704.1
PM_ADR_20: length 62.6
  TOP w0.178: v1(56.21,50.53) 56.21,52.1 55.77,52.54 55.2,52.54 54,53.75 U14.12 ; U11.D12 v2(83.66,74.2)
  BOTTOM w0.102: 85.12,62.23 85.27,62.38 85.27,66.42 85.52,66.67 86.94,66.67 87.19,66.93 87.19,68.46 87.06,68.6 87.06,71.56 86.85,71.77 84.46,71.77 84.27,71.96 84.27,73.44 83.66,74.04 v2(83.66,74.2)
  BOTTOM w0.178: v1(56.21,50.53) 57.14,50.53 57.88,49.8 63.32,49.8 63.9,50.37 75.13,50.37 81.32,56.55 81.32,58.91 81.97,59.57 82.46,59.57 85.12,62.23
PM_ADR_21: length 59.7
  TOP w0.178: U11.E11 v2(84.66,73.2)
  BOTTOM w0.102: 83.86,62.23 83.86,62.39 84.26,62.78 84.26,66.35 84.5,66.59 84.9,66.59 85.26,66.95 85.26,69.45 84.91,69.8 83.42,69.8 83.07,70.15 83.07,71.45 83.42,71.8 83.82,71.8 84.06,72.04 84.06,73.36 83.83,73.59 83.71,73.59 83.27,74.04 83.27,74.36 83.5,74.59 83.83,74.59 84.06,74.36 84.06,73.96 84.66,73.36 v2(84.66,73.2)
  BOTTOM w0.178: 83.86,62.23 83.86,61.98 82.82,60.93 81.59,60.93 79.79,59.13 79.79,57.38 79.34,56.93 76.76,56.93 74.99,58.7 67.62,58.7 63.99,55.07 63.99,55.04 63.62,54.66 63.58,54.66 61.45,52.54 56.82,52.54 56.69,52.66 55.29,52.66 54.07,53.88 R701.1 R702.1 R703.1
PM_ADR_22: length 54
  TOP w0.102: 79.69,74.2 v2(80.66,74.2)
  TOP w0.178: U11.A12 v2(80.66,74.2) ; U14.2 49,60.07 48.91,60.07 48.73,60.25 48.15,60.25 47.71,59.82 47.71,58.55 v1(47.72,58.55) ; 79.69,74.2 74.07,74.2 67.32,67.45 67.32,57.83 64.07,54.58 62.5,54.58 60.8,56.29 v1(60.71,56.29)
  BOTTOM w0.178: v1(60.71,56.29) 60.71,57.17 59.78,58.1 55.8,58.1 55.54,57.84 50.28,57.84 49.87,58.25 49.73,58.25 R705.1 48.02,58.85 47.71,58.55 v1(47.72,58.55)
PM_BLS0: length 58.4
  TOP w0.102: U11.A6 80.46,68.7 79.69,67.94 79.69,65.63 79.42,65.35
  TOP w0.178: 79.42,65.35 78.2,65.35 77.88,65.03 77.29,65.03 74.98,62.72 74.63,62.72 74.1,62.19 73.79,62.19 v1(73.51,61.91)
  LY4 w0.171: v1(73.51,61.91) 73.51,61.19 72.16,59.84 64.3,59.84 62.66,58.2 61.28,58.2 59.77,56.7 59.2,56.7 57.54,58.36 52.12,58.36 49.98,60.49 37.43,60.49 35.94,61.98 35.94,62.32 34.69,63.57 v1(33.73,63.57)
  BOTTOM w0.178: v1(33.73,63.57) 33.55,63.75 R661.1
PM_BLS0S: length 2.4
  TOP w0.178: U13.39 v1(30.69,63.55)
  BOTTOM w0.178: R661.2 31.4,63.55 v1(30.69,63.55)
PM_BLS1: length 59.5
  TOP w0.102: U11.B6 81.66,68.2 80.66,68.2 80.11,67.65 80.11,65.12 78.99,64.01
  TOP w0.178: 78.99,64.01 78.75,63.77 77.17,63.77 75.61,62.21 75.21,62.21 75.2,62.2 75.01,62.2 v1(74.74,61.92)
  LY4 w0.171: v1(74.74,61.92) 73.94,61.13 73.94,61.02 72.33,59.41 64.74,59.41 62.7,57.37 62.34,57.37 61.72,56.74 61.22,56.74 61.08,56.88 60.46,56.88 59.81,56.23 58.91,56.23 57.24,57.9 51.87,57.9 50.3,59.47 43.65,59.47 43.13,58.95 42.63,58.95 42.15,59.43 37.79,59.43 v1(34.48,62.74)
  BOTTOM w0.178: R662.1 v1(34.48,62.74)
PM_BLS1S: length 4.1
  TOP w0.178: U13.40 v1(29.79,62.75)
  BOTTOM w0.178: R662.2 31.02,62.74 31.01,62.75 v1(29.79,62.75)
PM_DAT_0: length 53.3
  TOP w0.178: U13.7 46.88,64.35 47.38,64.85 47.38,66.86 48.2,67.67 48.61,67.67 49.25,68.31 51.24,68.31 v1(52.15,69.22) ; v1(57.78,71.61) 57.81,71.63 58.57,71.63 59,72.06 59,73.67 59.43,74.1 59.43,74.26 59.45,74.28 59.45,75.48 59,75.94 U14.35 ; U11.B13 v2(81.66,75.2)
  BOTTOM w0.102: 79.69,75.02 79.93,75.26 80.06,75.26 80.46,75.66 81.33,75.66 81.66,75.33 v2(81.66,75.2)
  BOTTOM w0.178: v1(52.15,69.22) 52.15,69.99 53.5,71.34 54.2,72.04 54.67,72.04 54.8,72.17 57.22,72.17 57.78,71.6 v1(57.78,71.61) 57.79,71.6 60.56,71.6 61.24,72.29 63.58,72.29 64.55,73.26 65.42,73.26 67.18,75.02 68.58,75.02 68.58,75.02 69.92,75.02 69.92,75.02 75.56,75.02 75.56,75.02 78.78,75.02 78.78,75.02 79.69,75.02
PM_DAT_1: length 55.6
  TOP w0.178: v1(46.35,65.06) 46.27,65.14 U13.8 ; U11.C14 v2(82.66,77.2) ; v1(57.64,68.93) 57.64,69.7 56.86,70.48 56.86,71.93 57.21,72.28 57.45,72.28 58.09,72.92 v1(58.09,73.41) 58.09,74.51 58.12,74.55 58.12,74.56 58.28,74.72 58.28,75.36 58,75.64 U14.37
  LY4 w0.171: v1(58.09,73.41) 57.98,73.41 57.98,73.39 58.95,73.39 59.44,73.88 59.44,74.3 60.02,74.88 61.04,74.88 61.44,75.27 62.18,75.27 62.67,75.76 68.84,75.76 69.23,75.36 73.7,75.36 73.82,75.49 78.22,75.49 78.64,75.91 79.43,75.91 80.16,76.64 81.98,76.64 82.54,77.2 v2(82.66,77.2) ; v1(46.35,65.06) 47.14,65.85 47.14,67.33 48.49,68.68 50.31,68.68 51.71,67.28 53.8,67.28 54.03,67.06 55.77,67.06 v1(57.64,68.93)
PM_DAT_2: length 51.3
  TOP w0.178: U11.D14 v2(83.66,77.2) ; U13.9 45.66,65.95 49.83,70.12 50.15,70.12 v1(50.79,70.76) ; v1(57.19,73.26) 57.19,74.05 57,74.24 U14.39
  LY4 w0.171: v2(83.66,77.2) 83.66,77.19 82.73,76.25 80.43,76.25 79.65,75.48 79.44,75.48 79.35,75.39 78.65,75.39 78.4,75.13 75.65,75.13 75.62,75.1 74.47,75.1 74.31,74.93 69.05,74.93 68.66,75.33 62.85,75.33 60.01,72.49 57.95,72.49 v1(57.19,73.26) 56.86,72.93 56.86,72.36 56.32,71.82 55.87,71.82 55.83,71.79 55.2,71.79 55.03,71.61 53.19,71.61 53.06,71.47 51.87,71.47 51.2,70.8 50.79,70.8 v1(50.79,70.76)
PM_DAT_3: length 52.3
  TOP w0.178: v1(56.26,72.77) 56,73.04 U14.41 ; U11.E13 v2(84.66,75.2) ; U13.10 45.73,66.75 49.28,70.3 v1(49.28,70.8)
  LY4 w0.171: v1(56.26,72.77) 56.26,72.66 55.81,72.22 55.02,72.22 54.85,72.04 52.92,72.04 52.78,71.9 51.69,71.9 51.15,71.37 50.45,71.37 49.88,70.8 v1(49.28,70.8)
  BOTTOM w0.102: v2(84.66,75.2) 84.66,75.63 84.25,76.05 80.11,76.05 79.69,75.63
  BOTTOM w0.178: 79.69,75.63 79.68,75.62 78.87,75.62 78.84,75.58 78.63,75.37 75.41,75.37 70.07,75.37 68.73,75.37 68.32,75.78 67.21,75.78 65.21,73.78 64.33,73.78 64.03,73.48 64.03,73.48 63.72,73.17 63.36,72.81 58.95,72.81 58.6,72.46 58.57,72.46 58.56,72.45 57.49,72.45 57.28,72.66 56.37,72.66 v1(56.26,72.77)
PM_DAT_4: length 46.9
  TOP w0.178: v1(54.42,72.64) 54.42,73.57 54.63,73.77 54.63,75.08 54.63,75.09 54.29,75.43 54.29,75.94 54.49,76.14 U14.44 ; U13.13 46.28,69.14 v1(47.94,70.8) ; U11.A14 v2(80.66,77.2)
  LY4 w0.171: v2(80.66,77.2) 80.11,77.2 79.71,76.79 79.69,76.79 79.24,76.34 77.24,76.34 77.02,76.12 75.64,76.12 75.36,75.84 73.67,75.84 73.64,75.81 73.53,75.81 73.52,75.8 69.41,75.8 69.02,76.19 62.49,76.19 62,75.7 61.26,75.7 60.86,75.31 58.93,75.31 58.02,74.39 57.15,74.39 56.12,73.37 56.01,73.37 55.66,73.02 55.66,72.91 55.39,72.64 v1(54.42,72.64) 52.91,72.64 52.6,72.34 51.51,72.34 50.9,71.72 50.3,71.72 50.29,71.72 49.27,71.72 48.36,70.8 v1(47.94,70.8)
PM_DAT_5: length 49.9
  TOP w0.178: U13.14 46.04,69.94 v1(46.33,70.23) ; v1(53.23,75.19) 53.23,75.69 53.38,75.84 53.38,76.79 53.49,76.9 U14.46 ; U11.B14 v2(81.66,77.2)
  LY4 w0.102: 79.69,77.39 79.95,77.65 81.23,77.65 81.66,77.21 v2(81.66,77.2)
  LY4 w0.171: v1(46.33,70.23) 46.82,70.23 47.35,70.75 47.35,71.05 48.45,72.15 50.72,72.15 51.33,72.77 52.34,72.77 52.91,73.34 52.91,74.88 v1(53.23,75.19) 53.4,75.02 53.4,73.93 53.85,73.48 55.62,73.48 57.07,74.93 57.07,76.35 57.69,76.98 60.48,76.98 61.33,76.13 61.82,76.13 62.31,76.62 69.2,76.62 69.66,76.16 73.49,76.16 73.53,76.2 75.21,76.2 75.57,76.56 76.84,76.56 77.08,76.8 79.03,76.8 79.62,77.39 79.69,77.39
PM_DAT_6: length 49
  TOP w0.178: v1(52.32,74.24) 52.32,74.92 52.49,75.1 52.49,75.11 52.52,75.14 52.52,75.55 52.52,75.55 52.16,75.9 52.16,76.41 52.49,76.74 U14.48 52.54,78.31 52.54,79.29 52.57,79.32 v1(52.57,79.72) ; U13.15 v1(45.46,70.75) ; U11.C15 v2(82.66,78.2)
  LY4 w0.102: v2(82.66,78.2) 82.47,78.2 81.91,78.76 81.46,78.76 81.41,78.81 80.34,78.81 80.29,78.85 79.69,78.85
  LY4 w0.171: v1(45.46,70.75) 45.78,71.07 46.75,71.07 49.21,73.53 49.21,73.93 50.04,74.76 51.59,74.76 51.62,74.74 51.82,74.74 v1(52.32,74.24) ; 79.69,78.85 79.25,78.85 78.49,78.09 76.54,78.09 76.3,77.85 75.36,77.85 74.77,77.27 73.08,77.27 73.05,77.24 72.53,77.76 69.62,77.76 69.47,77.92 62.93,77.92 62.49,78.36 53.93,78.36 v1(52.57,79.72)
PM_DAT_7: length 53.5
  TOP w0.178: U11.D15 v2(83.66,78.2) ; v1(51.49,81.34) 51.49,80.85 51.56,80.79 51.56,80.44 51.51,80.39 51.51,79.85 51.49,79.83 U14.50 51.49,77.1 51.09,76.69 v1(51.09,76.01) ; v1(46.55,71.71) 45.29,71.71 45.12,71.54 U13.16
  LY4 w0.102: 79.69,81.6 80.82,81.6 80.88,81.54 81.45,81.54 81.5,81.59 81.83,81.59 82.06,81.36 82.06,80.77 82.23,80.59 82.83,80.59 83.06,80.36 83.06,80.2 83.67,79.59 83.83,79.59 84.06,79.36 84.06,79.04 83.66,78.64 v2(83.66,78.2)
  LY4 w0.171: 79.69,81.6 76.01,81.6 74.98,80.57 73.68,80.57 73.17,81.09 72.38,81.09 72.16,81.31 70.3,81.31 69.72,80.74 64.69,80.74 62.13,83.3 56.23,83.3 55.93,83.01 55.75,83.01 55.05,82.31 53.14,82.31 52.85,82.01 52.3,82.01 51.81,81.52 51.67,81.52 v1(51.49,81.34) ; v1(46.55,71.71) 46.63,71.71 48.86,73.94 48.86,74.42 49.47,75.02 49.8,75.02 49.98,75.2 50.29,75.2 v1(51.09,76.01)
PM_DAT_8: length 76.9
  TOP w0.178: U14.36 58.49,75.79 58.73,75.55 58.73,74.33 v1(58.77,74.3) ; U13.29 v1(34.5,71.54) ; U11.E14 v2(84.66,77.2)
  BOTTOM w0.102: 79.69,76.42 79.73,76.45 84.28,76.45 84.66,76.83 v2(84.66,77.2)
  BOTTOM w0.178: v1(34.5,71.54) 34.49,71.55 33.11,71.55 32.45,72.21 32.45,75.89 30.9,77.44 30.9,78.31 31.24,78.66 31.74,78.66 31.93,78.46 32.2,78.46 32.49,78.17 36.02,78.17 37.03,77.17 46.47,77.17 49.01,74.62 49.01,73.15 49.76,72.4 50.56,72.4 50.59,72.36 51.45,72.36 52.39,73.3 55.95,73.3 56.01,73.37 56.26,73.37 57.19,74.3 v1(58.77,74.3) 59.24,74.77 60.11,74.77 60.13,74.74 61.1,74.74 61.82,74.02 62.26,74.02 62.54,74.3 64.99,74.3 66.99,76.3 68.31,76.3 68.88,75.73 70.21,75.73 75.27,75.73 78.48,75.73 78.72,75.97 79.25,75.97 79.69,76.42
PM_DAT_9: length 79.2
  TOP w0.178: v1(58.05,81.97) 58.05,81.09 57.54,80.57 57.54,78.31 U14.38 57.49,75.28 v1(57.67,75.11) ; U13.30 v1(33.39,70.75) ; U11.C16 v2(82.66,79.2)
  LY4 w0.102: v2(82.66,79.2) 82.22,79.2 81.82,79.6 81.42,79.6 81.22,79.8 80.44,79.8 80.09,80.15
  LY4 w0.171: 80.09,80.15 76.77,80.15 75.66,79.05 75.04,79.05 74.38,78.38 73.41,78.38 72.97,78.83 70.07,78.83 69.68,79.21 64.24,79.21 62.25,81.2 58.82,81.2 v1(58.05,81.97)
  BOTTOM w0.178: v1(33.39,70.75) 33.11,71.03 32.89,71.03 31.93,72 31.93,75.78 30.54,77.17 30.54,78.45 31.1,79.01 31.89,79.01 31.99,78.91 32.39,78.91 32.68,78.62 36.2,78.62 37.14,77.69 47.47,77.69 48.91,76.25 48.91,75.35 49.29,74.98 49.91,74.98 50.24,75.31 50.24,76.13 51.14,77.03 52.68,77.03 52.69,77.05 53.85,77.05 54.22,76.68 54.22,75.11 54.6,74.73 54.6,74.57 54.86,74.3 54.86,74.24 55.24,73.87 55.77,73.87 57.01,75.11 v1(57.67,75.11)
PM_DAT_10: length 70.7
  TOP w0.178: U11.D16 v2(83.66,79.2) ; U14.40 56.49,80.72 56.6,80.82 56.6,81.61 v1(56.15,82.05) ; U13.31 v1(34.26,69.94)
  LY3 w0.171: v1(56.15,82.05) 52.96,82.05 52.09,81.18 52.09,81.09 51.7,80.7 49.92,80.7 49.64,80.42 48.61,80.42 48.04,79.85 42.26,79.85 41.8,80.31 41.28,80.31 40.56,79.58 39.02,79.58 38.09,78.65 36.26,78.65 35.48,77.87 35.48,76.25 35.48,76.24 35.48,75.95 35.4,75.88 35.4,75.47 34.84,74.91 34.44,74.91 34.12,74.59 33.83,74.59 33.3,74.59 32.89,74.18 32.89,72.04 33.53,71.39 33.65,71.39 34.18,70.87 34.18,70.03 v1(34.26,69.94)
  LY4 w0.102: v2(83.66,79.2) 83.22,79.2 82.61,79.81 81.5,79.81 81.06,80.25 81.06,80.36 80.83,80.59 80.5,80.59 80.42,80.52 79.94,80.52 79.87,80.58
  LY4 w0.171: v1(56.15,82.05) 56.6,82.05 57.1,82.56 61.54,82.56 64.23,79.87 69.52,79.87 70.21,79.18 72.99,79.18 73.65,79.84 74.14,79.84 74.41,79.58 75.59,79.58 76.59,80.58 79.87,80.58
PM_DAT_11: length 64.6
  TOP w0.178: v1(55.24,74.83) 55.51,75.11 55.51,75.94 55.49,75.95 U14.42 ; U11.B15 v2(81.66,78.2) ; U13.32 v1(33.33,69.14)
  LY4 w0.102: 79.72,78.42 80.33,78.42 80.5,78.59 80.83,78.59 81.22,78.2 v2(81.66,78.2)
  LY4 w0.171: v1(33.33,69.14) 33.35,69.13 35.15,69.13 39.48,73.45 40.48,73.45 41.51,74.49 41.51,76.26 44.3,79.04 44.74,79.04 44.94,79.24 48.59,79.24 48.61,79.22 49.1,79.22 49.12,79.24 51.13,79.24 53.18,77.19 53.2,77.19 54.31,76.07 54.31,75.44 54.91,74.83 v1(55.24,74.83) 55.5,75.09 55.5,76.29 57.14,77.92 62.2,77.92 62.64,77.49 69.4,77.49 69.48,77.41 72.38,77.41 72.91,76.87 73.19,76.87 73.23,76.91 74.92,76.91 75.43,77.42 76.48,77.42 76.72,77.66 78.67,77.66 79.41,78.4 79.69,78.4 79.72,78.42
PM_DAT_12: length 66
  TOP w0.178: U14.45 54,76.28 53.84,76.12 53.84,75.24 54,75.08 v1(54,74.32) ; U13.35 33.46,66.75 v1(33.66,66.55) ; U11.A15 v2(80.66,78.2)
  LY4 w0.171: v1(33.66,66.55) 33.98,66.87 35.09,66.87 36.92,68.7 37.34,68.7 41.1,72.46 41.1,72.95 41.94,73.79 41.94,75.47 44.85,78.38 46.68,78.38 47.2,77.86 48.02,77.86 48.18,78.02 51.74,78.02 53,76.75 53.02,76.75 53.87,75.9 53.87,75.26 54,75.14 v1(54,74.32) 54.4,73.91 55.44,73.91 56.55,75.02 56.55,76.73 57.32,77.5 61.95,77.5 62.4,77.06 69.37,77.06 69.48,76.95 72.33,76.95 72.77,76.52 73.34,76.52 73.38,76.56 75.07,76.56 75.5,76.99 76.66,76.99 76.9,77.23 78.85,77.23 79.59,77.97 80.21,77.97 80.44,78.2 v2(80.66,78.2)
PM_DAT_13: length 63.8
  TOP w0.178: U13.36 33.03,65.95 33.17,65.81 34.12,65.81 34.25,65.95 v1(34.96,65.95) ; v1(52.77,76.16) 53,76.38 U14.47 53,79.1 53.03,79.13 53.03,79.29 53.18,79.44 53.18,80.24 53.42,80.48 53.42,80.52 v1(53.75,80.84) ; U11.A16 v2(80.66,79.2)
  LY4 w0.171: v2(80.66,79.2) 80.23,79.2 80.15,79.29 78,79.29 77.43,78.71 76.55,78.71 76.12,78.28 75.28,78.28 74.62,77.62 73.17,77.62 72.67,78.12 69.77,78.12 69.54,78.35 63.11,78.35 62.67,78.79 54.91,78.79 53.75,79.95 v1(53.75,80.84) ; v1(52.77,76.16) 52.77,76.16 51.27,77.66 48.51,77.66 48.28,77.43 47.02,77.43 46.5,77.94 45.03,77.94 43.48,76.39 43.48,73.86 42.99,73.37 42.14,73.37 41.53,72.77 41.53,72.25 37.37,68.09 37.1,68.09 v1(34.96,65.95)
PM_DAT_14: length 67.3
  TOP w0.178: U11.B16 v2(81.66,79.2) ; v1(51.87,75.34) 51.7,75.5 51.7,76.66 52,76.95 U14.49 52.02,78.29 52.02,79.38 51.96,79.44 51.96,80.2 52.02,80.25 52.02,80.27 52.72,80.98 v1(52.73,80.98) ; U13.37 v1(33.71,65.14)
  LY4 w0.102: 79.69,79.72 80.12,79.72 80.25,79.59 80.83,79.59 81.22,79.2 v2(81.66,79.2)
  LY4 w0.171: v1(52.73,80.98) 53.04,80.98 53.5,81.44 54,81.44 54.25,81.19 55,81.19 56.84,79.34 59.45,79.34 59.57,79.22 62.89,79.22 63.32,78.78 69.61,78.78 69.92,78.47 72.82,78.47 73.32,77.98 74.48,77.98 75.19,78.69 75.92,78.69 76.95,79.72 79.69,79.72 ; v1(51.87,75.34) 51.87,76.35 50.91,77.3 49.01,77.3 48.46,76.75 47.08,76.75 46.32,77.51 45.21,77.51 44,76.3 44,73.73 43.21,72.94 42.32,72.94 41.97,72.59 41.97,71.62 35.54,65.19 33.76,65.19 v1(33.71,65.14)
PM_DAT_15: length 68.6
  TOP w0.178: v1(50.56,81.34) 50.56,81.24 51.05,80.75 51.05,80.04 51,79.98 U14.51 51,77.24 50.61,76.86 50.61,76.5 50.16,76.05 49.99,76.05 v1(49.55,75.62) ; U13.38 35.78,64.35 v1(36.56,65.13) ; U11.C17 v2(82.66,80.2)
  LY4 w0.102: v2(82.66,80.2) 82.22,80.2 81.61,80.81 80.23,80.81 79.87,81.17
  LY4 w0.171: v1(36.56,65.13) 37.14,65.71 37.14,65.94 41.7,70.49 41.7,70.58 43.5,72.38 43.5,72.62 44.43,73.55 44.43,76.12 45.25,76.94 46.29,76.94 47.54,75.69 48,75.69 48.01,75.68 48.01,75.68 48.17,75.53 49.46,75.53 v1(49.55,75.62) ; 79.87,81.17 76.26,81.17 75.1,80.01 74.48,80.01 74.29,80.2 73.55,80.2 73.27,80.49 72.77,80.49 72.52,80.24 72.52,80.1 72.17,79.75 71.68,79.75 71.12,80.3 64.51,80.3 61.9,82.92 56.35,82.92 56.08,82.65 55.9,82.65 55.12,81.87 53.32,81.87 53.02,81.57 52.48,81.57 52.13,81.22 52.13,81.08 51.79,80.74 51.24,80.74 50.64,81.34 v1(50.56,81.34)
PM_OESZ: length 45.8
  TOP w0.178: U14.34 59.49,76.04 60.06,75.48 60.06,74.03 v1(60.04,74.01) 60.04,69.75 58.11,67.82 v1(55.42,67.82) ; U13.41 v1(30.57,61.95)
  LY3 w0.171: v1(55.42,67.82) 54.43,66.84 51.75,66.84 48.77,63.85 v1(48.77,62.9)
  LY4 w0.171: v1(48.77,62.9) 48.58,62.9 47.37,64.11 45.96,64.11 45.9,64.17 33.48,64.17 33.47,64.16 32.79,64.16 v1(30.57,61.95)
  BOTTOM w0.178: R663.2 31.58,61.95 v1(30.57,61.95)
PM_OEZ: length 85.7
  TOP w0.102: 79.69,76.13 79.77,76.21 82.66,76.21 U11.C13
  TOP w0.178: v1(35.89,54.93) 35.89,58.55 37.38,60.04 37.38,62.46 36.89,62.94 35.9,62.94 34.83,61.86 v1(33.64,61.86) ; 79.69,76.13 78.44,76.13 77.21,77.35 68.31,77.35 63.94,72.98 63.94,64.2 64.74,63.4 64.74,56.69 v1(63.35,55.3) ; U11.C13 v2(82.66,75.2)
  LY4 w0.171: v1(63.35,55.3) 63.35,53.79 62.23,52.68 59.35,52.68 58.55,51.88 54.36,51.88 53.06,53.19 50,53.19 49.31,53.88 46.69,53.88 45.64,54.93 v1(35.89,54.93)
  BOTTOM w0.178: v1(33.64,61.86) 33.5,61.72 R663.1
PM_SRAM_CSSZ: length 2.5
  TOP w0.178: U13.6 v1(42.59,63.55)
  BOTTOM w0.178: R660.2 43.5,63.55 v1(42.59,63.55)
PM_SRAM_CSZ: length 52.7
  TOP w0.178: U11.D13 v2(83.66,75.2)
  LY4 w0.171: v2(83.66,75.2) 83.66,75.15 83.19,74.68 79.15,74.68 78.89,74.42 75.95,74.42 75.91,74.38 74.76,74.38 74.3,73.91 63.25,73.91 59.94,70.61 56.93,70.61 56.18,69.86 55.86,69.86 55.86,70.1 v1(55.62,70.1)
  BOTTOM w0.178: R660.1 45.59,63.5 46.23,62.87 47.12,62.87 48.26,61.72 49.53,61.72 49.78,61.47 50.55,61.47 51.44,60.58 53.21,60.58 56.77,64.14 56.77,68.95 55.86,69.86 55.86,70.1 v1(55.62,70.1)
PM_WESZ: length 24.8
  TOP w0.178: v1(42.56,72.34) U13.17 46.28,72.34 46.28,72.35 46.81,72.35 46.82,72.34 46.91,72.34 47.74,71.52 52.38,71.52 53.4,70.49 53.4,67.31 54.23,66.49 54.23,61.28 54.49,61.01 U14.13
  BOTTOM w0.178: R628.2 43.63,72.34 v1(42.56,72.34)
PM_WEZ: length 44.3
  TOP w0.178: U11.B12 v2(81.66,74.2)
  BOTTOM w0.102: v2(81.66,74.2) 81.12,73.66 80.39,73.66 79.74,74.31 79.69,74.31
  BOTTOM w0.178: R628.1 47.26,72.39 48.61,71.04 48.61,70.56 50.47,68.7 51.14,68.7 51.95,67.88 52.96,67.88 54.74,69.66 54.74,70.72 55.34,71.31 55.94,71.31 55.99,71.37 56.49,71.37 56.54,71.31 56.66,71.31 57.49,70.48 61.83,70.48 62.59,71.25 64.04,71.25 65.01,72.22 65.03,72.22 65.86,72.22 67.94,74.31 68.29,74.31 69.62,74.31 69.62,74.31 75.85,74.31 75.86,74.31 79.69,74.31
PMD1K2_CP1: length 3.5
  TOP w0.178: U2.18 161.41,119.13 161.18,119.36 161.18,120.05 161.04,120.19 161.04,120.64 C6.1
PMD1K2_CP2: length 3.4
  TOP w0.178: C6.2 161.91,120.63 161.91,119.37 161.93,119.35 161.93,118.91 161.91,118.89 U2.17
PMD1K2_FB_P2P5V: length 25.2
  TOP w0.178: L3.2 156.64,91.17 R17.1 ; U2.46 162.91,107.89 163.71,107.1 164.5,107.1 164.97,107.57 165.23,107.57 165.35,107.44 165.35,107.19 v1(164.21,106.05)
  LY3 w0.171: v1(164.21,106.05) 163.19,105.04 163.19,104.27 159.26,100.33 v1(159.26,96.14)
  BOTTOM w0.178: v1(159.26,96.14) 156.84,93.73 C545.2
PMD1K2_GD_CORE: length 13
  TOP w0.178: v1(147.82,112.11) 147.82,110.25 Q1.1 ; U2.26 v1(154.63,115.79)
  BOTTOM w0.178: v1(154.63,115.79) 151.5,115.79 v1(147.82,112.11)
PMD1K2_VCP: length 6.6
  TOP w0.254: v2(159.13,116.59) 159.6,116.59 159.91,116.9 U2.21
  BOTTOM w0.178: C505.1 158.08,119.96 158.08,118.02 158.22,117.88 158.22,117.5 158.59,117.13 158.59,117.08 158.79,116.88 158.83,116.88 v2(159.13,116.59)
PMD1K2_VREG: length 37.2
  TOP w0.178: U2.31 158.05,113.29 v2(158.12,113.22) ; U2.24 158.41,119.58 158.87,120.04 160.28,120.04 v1(160.54,119.78) 160.41,119.78 U2.20 ; U2.47 163.41,108.24 v1(163.96,107.7)
  TOP w0.254: v1(162.74,106.28) 162.41,106.61 U2.45
  LY4 w0.171: v1(156.95,119.55) 157.78,120.39 159.93,120.39 v1(160.54,119.78) ; v2(158.12,113.22) 158.12,112.55 158.44,112.23 159.51,112.23 159.93,111.8 159.93,111.27 160.4,110.8 160.4,109.9 160.83,109.48 162.41,107.89 163.41,107.89 163.6,107.7 v1(163.96,107.7)
  BOTTOM w0.178: v1(156.95,119.55) 156.95,118.64 157.86,117.73 157.86,116.17 157.3,115.61 157.3,113.55 157.63,113.22 v2(158.12,113.22) ; C513.1 160.41,118.83 160.41,119.78 v1(160.54,119.78)
  BOTTOM w0.254: v1(162.74,106.28) 163.96,107.5 v1(163.96,107.7)
PMD1K_CP1: length 3.5
  TOP w0.178: U15.18 160.14,67.56 C24.1
PMD1K_CP2: length 3.4
  TOP w0.178: U15.17 160.64,65.89 160.63,65.9 160.63,67.91 C24.2
PMD1K_FB_LIN1: length 33.3
  TOP w0.178: U15.31 156.78,60.58 v2(156.84,60.52)
  LY4 w0.171: v2(156.84,60.52) 155.54,60.52 153.85,62.2 153.12,62.2 152.38,62.95 151.08,62.95 150.38,62.25 148.11,62.25 147.61,61.75 147.61,61.67 147.45,61.51 146.24,61.51 146.24,61.51 145.39,61.51 145.39,61.51 142.48,61.51 141.99,61.02 140.86,61.02 140.4,61.51 137.11,61.51 v1(135.95,62.66)
  BOTTOM w0.178: U510.4 136.28,62.99 v1(135.95,62.66) 135.65,62.97 134.71,62.97 134.28,63.4 C642.1 ; R669.1 156.6,59.58 156.84,59.82 v2(156.84,60.52) 156.77,60.44 R633.2
PMD1K_FB_MOT1: length 7.7
  TOP w0.178: L6.1 171.96,70.85 170.99,71.82 C22.2
PMD1K_FB_MOT2: length 6.5
  TOP w0.178: C1.2 168.94,124.55 168.94,125.3 169.21,125.56 v1(170.33,125.56)
  BOTTOM w0.178: v1(170.33,125.56) 170.08,125.31 v1(170.08,121.49)
  vias: v1(170.13,120.3) v1(170.12,119.24) v1(170.08,118.27)
PMD1K_FB_P2P5V: length 20.5
  TOP w0.178: v1(162.22,54.13) 161.93,54.43 161.93,55.12 161.64,55.4 U15.46
  LY3 w0.171: v1(162.22,54.13) 162.22,54.06 163.7,52.58 163.7,50.67 162.39,49.36 162.39,46.61 v1(157.47,41.68)
  BOTTOM w0.178: v1(157.47,41.68) 156.93,41.15 156.21,41.15 C680.2
  vias: v1(157.35,40.13)
PMD1K_FB_P3P3V:
  vias: v1(162.89,45.9) v1(163.45,47.27) v1(164.35,48.4) v1(164.97,47.55) v1(166.42,47.27) v1(166.94,48.02)
PMD1K_FB_P5V: length 1.9
  TOP w0.178: 156.87,65.74 157.14,65.47 U15.24
  BOTTOM w0.381: 147.98,76.02 149.21,76.02 149.29,75.95
  vias: v1(147.7,74.17) v1(149.71,73.66) v1(150.39,74.57) v1(150.47,75.95)
PMD1K_GD_CORE: length 34.9
  TOP w0.178: 148.46,52.96 148.46,51.41 146.69,49.64 145.75,49.64 v1(145.75,49.7) ; U15.26 v2(156.78,63.08)
  LY4 w0.171: v1(145.75,49.7) 145.82,49.77 154.04,49.77 155.44,51.18 155.44,53.39 154.7,54.14 153.45,54.14 153.01,54.58 153.01,56.27 154.49,57.76 155.33,57.76 157.1,59.52 158.39,59.52 158.64,59.78 158.64,61.66 158.24,62.06 157.8,62.06 v2(156.78,63.08)
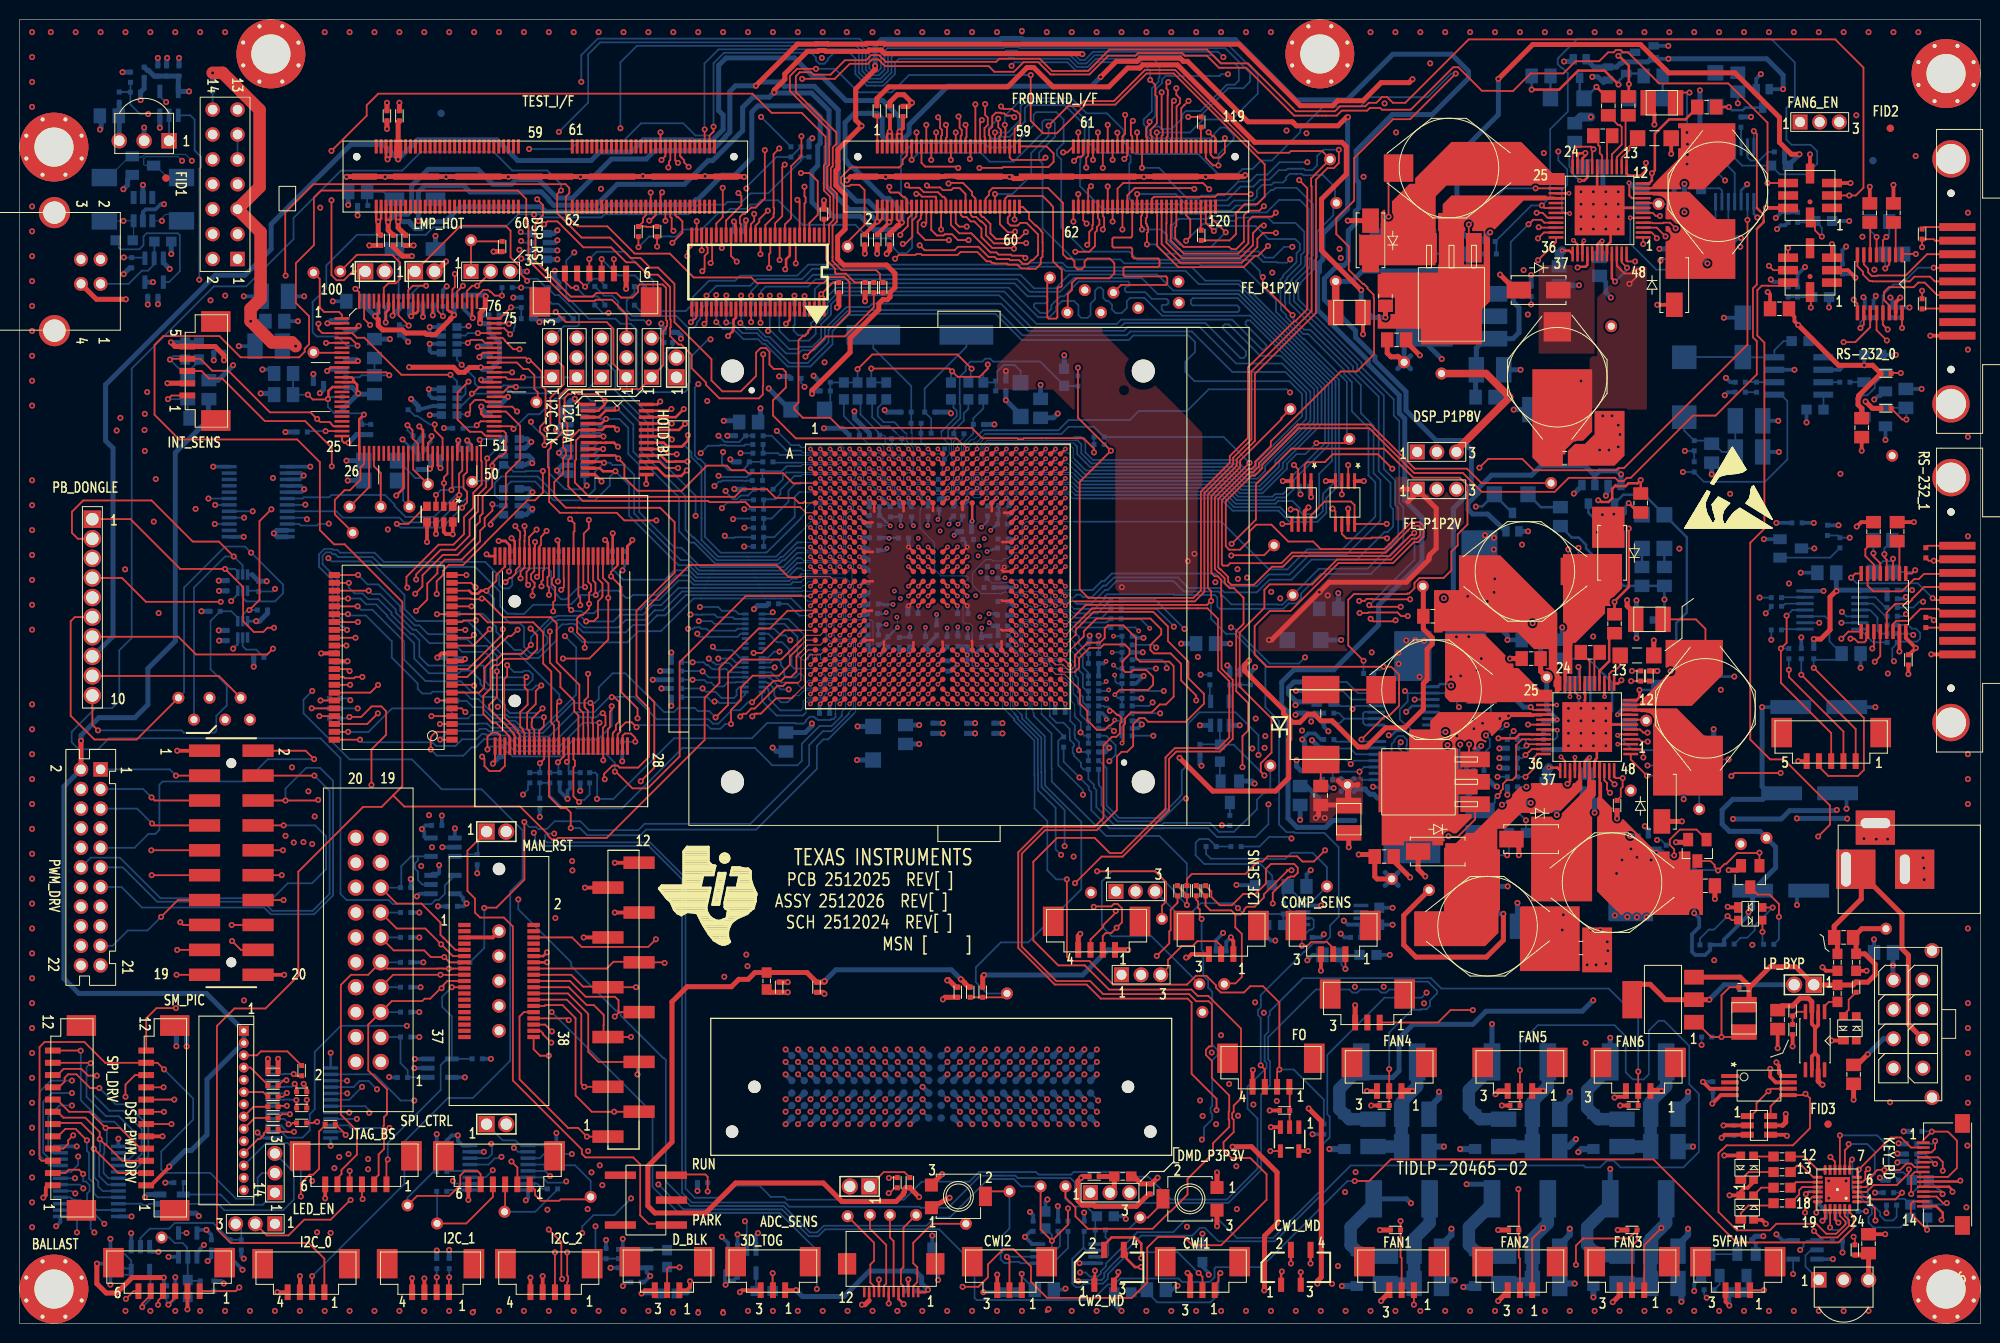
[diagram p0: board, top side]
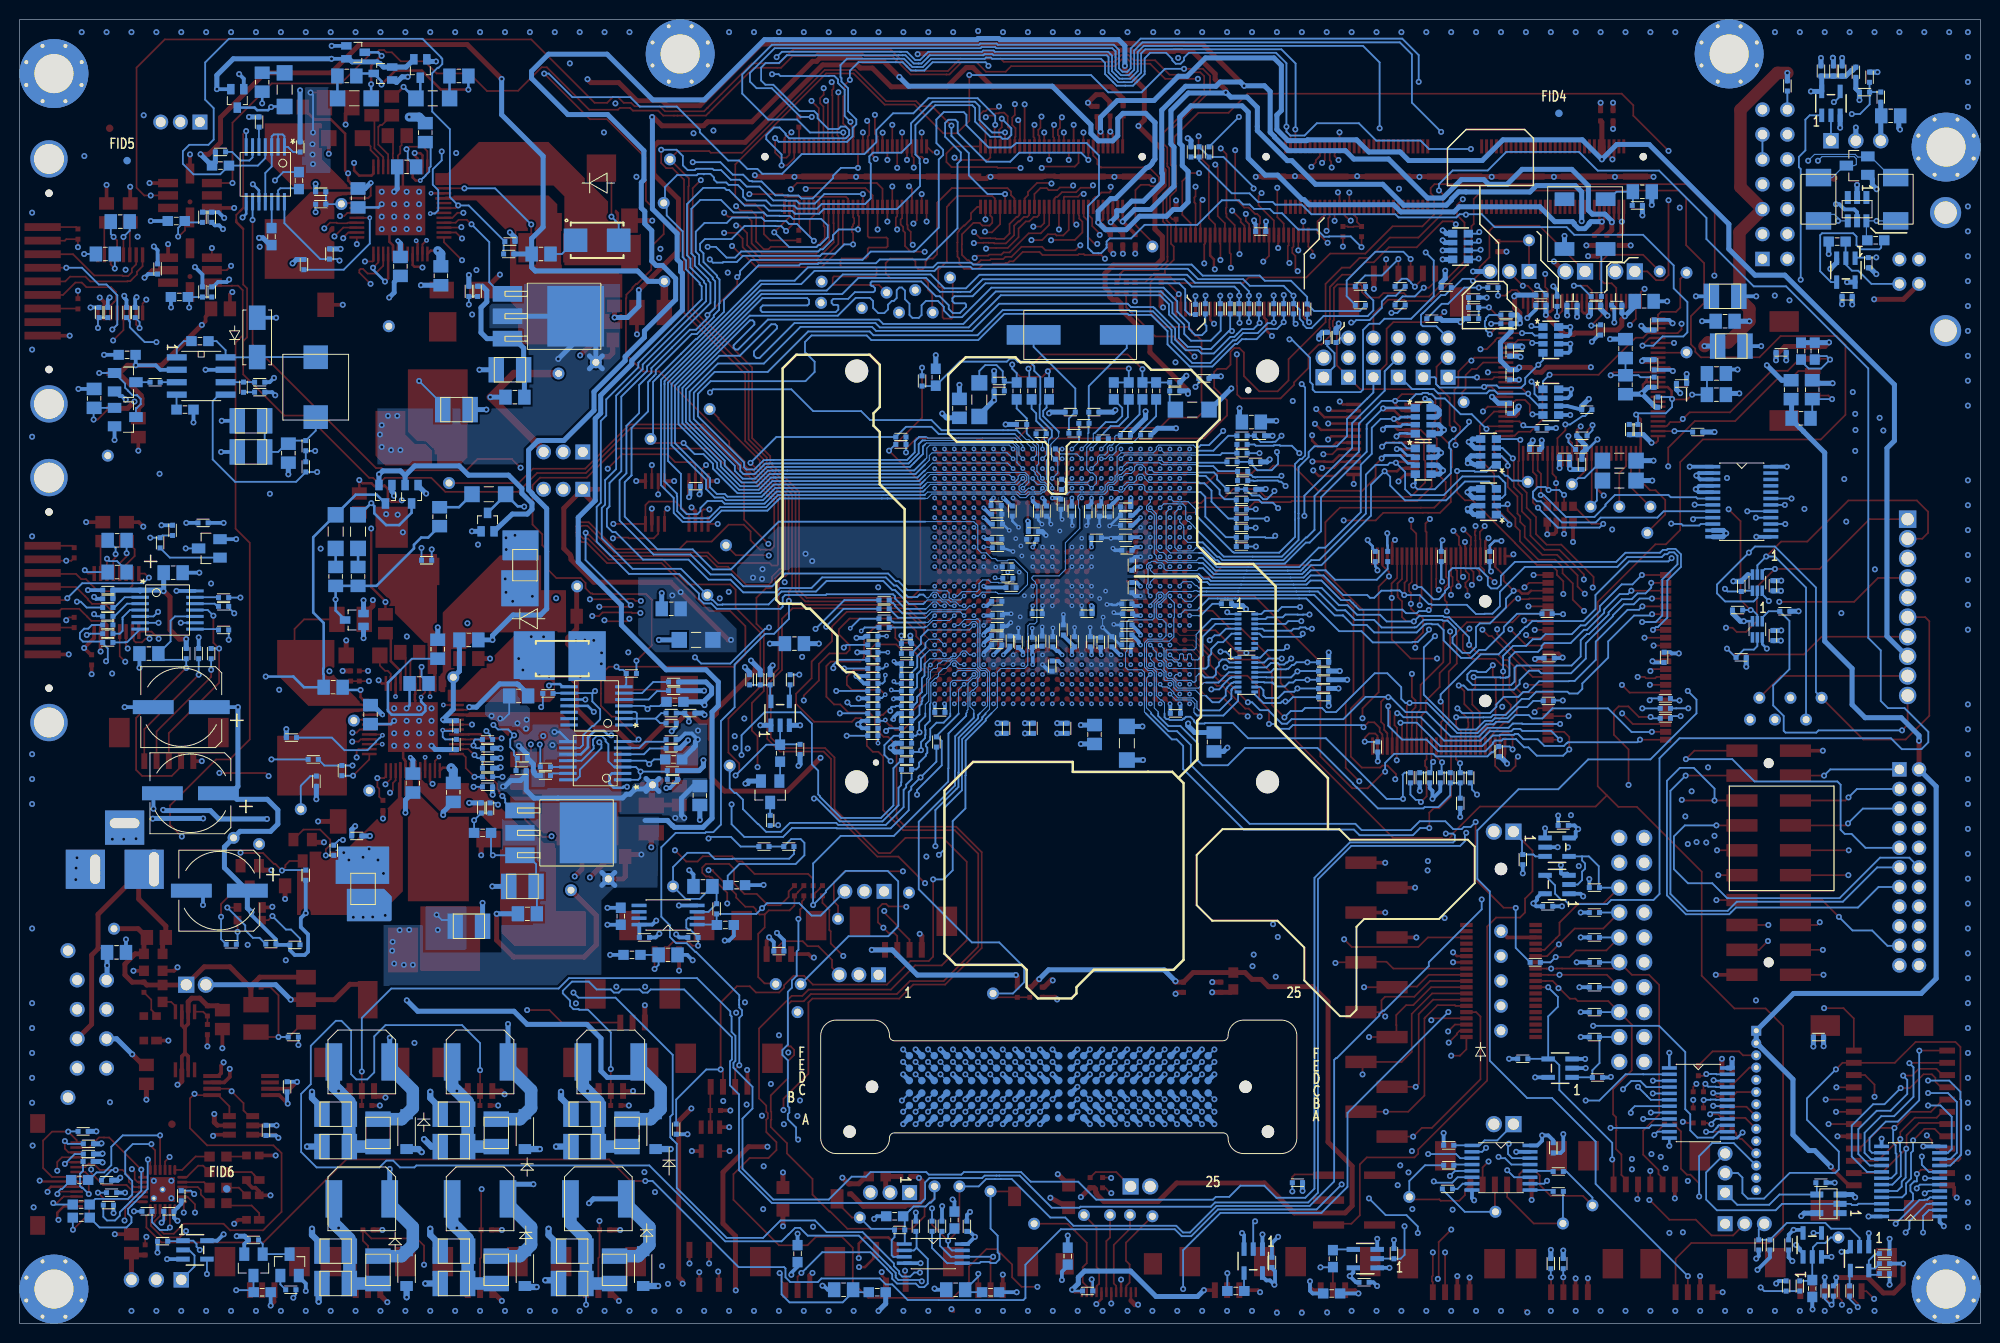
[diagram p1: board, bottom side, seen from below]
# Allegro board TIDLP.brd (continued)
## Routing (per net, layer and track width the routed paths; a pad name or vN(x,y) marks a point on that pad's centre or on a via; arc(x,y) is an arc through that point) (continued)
PMD1K_GM_IN1: length 8.1
  TOP w0.178: C25.2 R24.2 v1(164.37,65.52) ; TP41.1 165.82,61.58 U15.8
  LY3 w0.171: v1(164.37,65.52) 164.37,64.63 164.98,64.02 164.99,64.02 165.91,63.09 TP41.1
PMD1K_GM_IN2: length 4.5
  TOP w0.178: U2.8 167.09,114.29 TP3.1
  BOTTOM w0.178: C511.2 R514.2 167.21,114.17 TP3.1
PMD1K_SENSE_MOT1: length 3.5
  TOP w0.178: U15.14 162.14,66.26 162.46,66.57 162.73,66.57 163.26,67.1 R23.1
PMD1K_SENSE_MOT2: length 3.6
  TOP w0.178: U2.14 163.41,118.9 164.2,119.69 164.2,120.07 R5.1
PMD1K_VCP: length 16.3
  TOP w0.178: U15.21 158.64,64.37 159.05,63.96 v2(159.05,63.88)
  BOTTOM w0.178: C641.1 160,67.81 161.19,66.61
  BOTTOM w0.254: v2(159.05,63.88) 159.05,63.43 158.62,63 158.62,62.47 158.99,62.1 162.06,62.1 162.43,62.47 162.43,62.61 162.43,62.62 162.43,65.37 161.19,66.61
PMD1K_VREG: length 20.8
  TOP w0.178: v1(162.69,54.99) 162.14,55.53 U15.47 ; v1(159,66.96) 159.14,66.83 U15.20
  LY3 w0.171: v1(159,66.96) 158.86,66.96 158.86,66.91 161.07,64.7 161.07,63.69 161.42,63.34 162.69,63.34 163.83,62.2 163.83,57.98 162.69,56.84 v1(162.69,54.99)
  BOTTOM w0.178: C640.1 159,65.99 v1(159,66.96)
PMD_INTZ: length 96.5
  TOP w0.178: U11.AE8 v2(105.66,70.2) ; U15.36 154.82,58.08 154.5,57.76 154.5,56.64 v1(153.61,55.75)
  LY3 w0.171: v1(153.61,55.75) 152.45,56.91 152.45,59.64 152.99,60.18 152.99,60.67 152.45,61.21 152.45,61.71 152.46,61.73 152.46,62.22 152.45,62.24 152.45,65.48 152.53,65.56 152.53,66.23 153.91,67.62 153.91,71.01 v1(154.32,71.42)
  LY4 w0.102: 107.63,69.26 107.08,69.81 106.5,69.81 106.11,70.2 v2(105.66,70.2)
  LY4 w0.171: v1(154.32,71.42) 153.92,71.02 148.67,71.02 148.35,71.34 147.28,71.34 147.27,71.32 146.03,71.32 145.83,71.13 138.4,71.13 138.2,70.93 137.41,70.93 137.24,71.09 135.95,71.09 135.19,71.86 133.8,71.86 132.78,70.84 131,70.84 128.93,68.77 128.93,68.39 128.39,67.85 126.01,67.85 126,67.86 125.65,68.21 125.15,68.21 124.8,67.86 124.8,67.85 123.02,67.85 122.13,66.96 119.26,66.96 117.62,65.32 111.78,65.32 111.5,65.6 111.48,65.6 111.16,65.91 111.16,65.99 111.09,66.07 110.65,66.07 110.64,66.06 109.83,66.06 108.66,67.23 108.66,68.23 107.63,69.26 ; v1(153.61,55.75) 153.7,55.66 v1(153.7,54.74) 155.64,54.74 157.18,53.2 162.2,53.2 166.08,49.31 v1(167.03,49.31)
  BOTTOM w0.178: R675.2 v1(153.61,55.75) ; R707.1 167.41,49.32 167.04,49.32 v1(167.03,49.31) ; R676.2 v1(153.7,54.74)
POSENSE: length 183.4
  TOP w0.178: U15.34 154.75,59.08 154.75,59.08 153.82,59.08 153.73,58.99 153.73,58.98 v1(153.71,58.95) ; v1(107.95,97.5) 107.95,92.39 v1(111.32,89.03) 108.13,85.84 108.13,74.89 109.01,74.01 119.72,74.01 120.49,74.78 120.49,84.85 120.75,85.1 123.43,87.79 123.43,88.47 125.28,90.32 125.28,97.51 129.99,102.22 130.11,102.22 131.34,103.46 131.34,115.8 v1(130.52,116.63)
  LY3 w0.171: v1(155.47,119.39) 156.69,118.17 156.69,109.21 158.05,107.85 158.05,104.66 157.68,104.3 157.68,95.35 158.05,94.98 158.05,93.27 159.18,92.14 159.18,83.81 157.26,81.88 157.26,73.86 156.38,72.99 156.38,68.69 153.21,65.52 153.21,62.81 154.58,61.43 154.58,60.49 153.71,59.61 v1(153.71,58.95)
  LY4 w0.171: v1(155.47,119.39) 152.22,116.14 131.01,116.14 v1(130.52,116.63)
  BOTTOM w0.178: R579.1 v1(107.95,97.5) ; R578.2 110.68,89.66 v1(111.32,89.03) ; R671.2 153.55,59.56 153.67,59.44 153.67,58.98 v1(153.71,58.95) 153.43,58.67 R672.2
POSENSE_FIL: length 27.3
  TOP w0.254: v2(94.66,85.2) U11.P22
  BOTTOM w0.102: 95.05,90.11 95.05,88.27 95.26,88.05 95.26,86.12 94.66,85.51 v2(94.66,85.2)
  BOTTOM w0.178: R579.2 106.59,95.62 C551.2 104.1,98.11 99.3,98.11 99,98.41 98.5,98.41 98.2,98.11 96.97,98.11 96.5,97.64 96.5,97.17 95.89,96.55 95.89,93.79 95.95,93.73 95.95,92.34 94.71,91.1 94.71,90.44 95.05,90.11
PROG_0: length 271.4
  TOP w0.178: U7.43 43.14,90.3 42.33,91.1 v1(42.33,91.7) ; v1(182.12,11.3) 182.12,12.15 182.87,12.9 U20.17
  LY3 w0.171: v1(42.33,91.7) 41.86,91.7 40.86,92.69 38.21,92.69 37.57,93.34 33.99,93.34 32.22,91.57 32.22,90.49 30.83,89.1 30.83,83.58 32.45,81.96 32.45,79.56 32.99,79.01 32.99,77.36 32.26,76.63 31.07,76.63 29.4,74.96 29.4,68.18 29.4,67.59 29.26,67.45 28.41,66.6 28.41,61.31 25.5,58.4 25.5,48.34 25.5,48.05 25.72,47.82 26.13,47.41 26.13,44.69 26.21,44.61 26.21,44.17 26.24,44.15 26.24,33.62 23.96,31.34 23.96,20.8 25.44,19.32 26.65,19.32 28.22,17.75 28.22,17.16 29.55,15.84 v1(32.11,15.84)
  LY4 w0.171: v1(32.11,15.84) 32.11,15.43 33.98,13.56 35.27,13.56 39.49,9.34 43.77,9.34 47.33,12.9 47.98,12.9 48.78,13.7 56.27,13.7 57.19,14.62 58.63,14.62 59.08,15.07 65.16,15.07 67.77,12.46 78.89,12.46 81.88,9.47 86.03,9.47 86.04,9.46 91.74,9.46 92.97,8.23 104.64,8.23 105.04,7.83 120.91,7.83 122.88,9.81 125.9,9.81 127.13,11.04 141.94,11.04 145.64,7.34 178.63,7.34 181.17,9.88 181.17,10.34 182,11.18 182,11.19 v1(182.12,11.3)
  BOTTOM w0.178: R584.1 39.8,93.09 40.32,92.57 40.57,92.57 41.85,91.7 v1(42.33,91.7)
PSENS: length 62.9
  TOP w0.178: U2.34 154.99,111.79 v1(154.95,111.83)
  LY3 w0.171: v1(154.95,111.83) 156.26,110.52 156.26,108.88 156.91,108.22 156.91,92.19 157.97,91.13 157.97,84.93 157.94,84.9 157.94,84.62 156.35,83.04 156.35,79.35 156.67,79.04 156.67,78.19 156.06,77.58 155.5,77.58 154.44,76.53 154.44,74.55 153.79,73.89 153.79,72.05 152.06,70.32 151.52,70.32 151.17,69.97 151.17,69.48 152.23,68.41 152.27,68.41 152.62,68.07 152.62,67.57 152.27,67.22 151.93,67.22 151.72,67.01 151.72,66.61 152.1,66.24 152.1,65.74 150.41,64.06 150.41,63.92 150.36,63.86 150.36,61.35 151.32,60.38 152.35,60.38 v1(152.39,60.43)
  BOTTOM w0.178: R671.1 151.79,59.56 152.04,59.81 152.04,60.08 v1(152.39,60.43)
PWR_OFF_RDY: length 280.3
  TOP w0.178: U11.B23 v2(81.66,86.2)
  LY3 w0.171: v1(190.56,66.29) 190.56,66.91 190.59,66.94 190.59,68.73 193.01,71.15 193.01,72.6 193,72.6 193,73.92 193.95,74.87 193.95,77.08 193.61,77.43 193.61,81.29 193.81,81.49 193.81,93.52 193.36,93.98 193.36,100.97 193.37,100.98 193.37,104.76 193.19,104.94 193.19,108.32 192.72,108.79 192.72,122.63 184.42,130.94 141.03,130.94 134.68,124.59 129.98,124.59 125.52,129.05 122.91,129.05 v1(122.79,129.18) ; v2(81.66,86.2) 80.01,86.2 73.18,93.02 73.18,93.03 70.25,95.96 69.97,95.96 68.33,97.61 68.33,99.19 67.65,99.86 67.14,99.86 66.35,100.65 66.35,102.19 65.68,102.87 65.1,102.87 64.4,103.56 63.18,103.56 61.81,104.94 61.62,104.94 59.96,106.6 59.96,113.01 58.7,114.27 58.7,115.99 59.31,116.6 59.31,120.31 60.59,121.59 60.95,121.59 v1(61.28,121.92)
  LY4 w0.171: v1(183.57,71.47) 184.99,71.47 185.58,70.87 186.08,70.87 186.92,71.72 188.57,71.72 189.42,70.87 193.23,70.87 193.27,70.83 193.4,70.83 194.12,70.11 194.12,68.07 192.87,66.83 192.41,66.83 191.88,66.29 v1(190.56,66.29)
  BOTTOM w0.178: U508.9 v1(183.57,71.47) ; v1(122.79,129.18) 122.24,129.72 110.19,129.72 110.19,129.72 110.08,129.72 109.49,129.72 108.65,128.88 108.16,128.88 107.73,129.3 107.32,129.72 101.85,129.72 101.72,129.85 100.64,129.85 100.51,129.72 88.96,129.72 88.75,129.51 88.57,129.33 88.57,127.74 88.16,127.33 87.81,126.98 87.51,126.98 86.72,126.98 85.96,127.74 85.96,129.7 85.33,130.33 62.97,130.33 61.28,128.64 v1(61.28,121.92)
PWR_ON_AC: length 81.8
  TOP w0.178: v1(148.24,31.96) 145.95,31.96 144.68,30.69 J35.1
  LY3 w0.171: v1(178.11,72.43) 176.35,70.68 176.35,69.32 179.47,66.2 179.47,65.21 180.62,64.06 180.62,62.1 181.03,61.68 181.03,58.59 182.02,57.6 182.02,55.82 180.64,54.44 179.77,54.44 179.38,54.06 179.38,53.32 175.86,49.8 175.08,49.8 174.54,49.27 174.54,47.53 175.21,46.86 175.21,45.85 173.78,44.42 173.78,43.23 173.48,42.93 173.48,37.66 v1(172.85,37.04)
  LY4 w0.171: v1(172.85,37.04) 167.41,31.6 150.68,31.6 150.32,31.96 v1(148.24,31.96)
  BOTTOM w0.178: R618.1 178.68,73.01 178.11,72.45 v1(178.11,72.43)
PWR_ON_RDY: length 280.1
  TOP w0.178: U11.C22 v2(82.66,85.2)
  LY3 w0.102: 82.04,90.17 82.26,89.95 82.26,85.6 v2(82.66,85.2)
  LY3 w0.171: v1(70.47,100.38) 71.36,100.38 71.94,99.81 76.56,99.81 77.38,98.99 77.38,98.69 77.41,98.66 77.41,98.55 77.78,98.17 78.86,98.17 79.07,97.96 79.07,94.4 81.45,92.03 81.45,91.06 82.04,90.47 82.04,90.17 ; v1(56.58,109.25) 56.58,121.7 64.73,129.85 80.16,129.85 81.34,131.04 84.61,131.04 84.71,131.14 86.73,131.14 86.75,131.13 87.24,131.13 87.26,131.14 89.27,131.14 89.29,131.13 89.78,131.13 89.8,131.14 91.81,131.14 91.83,131.13 92.32,131.13 92.34,131.14 94.35,131.14 94.37,131.13 94.86,131.13 94.88,131.14 96.89,131.14 96.91,131.13 97.4,131.13 97.42,131.14 99.43,131.14 99.45,131.13 99.94,131.13 99.96,131.14 104.51,131.14 104.53,131.13 105.02,131.13 105.04,131.14 107.05,131.14 107.07,131.13 107.56,131.13 107.58,131.14 109.09,131.14 109.2,131.04 119.1,131.04 121.91,128.23 123.93,128.23 128.31,123.85 136.66,123.85 137.18,123.34 139.31,123.34 140.26,124.28 140.26,128.08 141.39,129.21 146.42,129.21 147.66,127.97 157.82,127.97 158.38,128.53 162.36,128.53 162.62,128.27 165.86,128.27 169.2,124.93 172.87,124.93 175.99,128.04 183.98,128.04 189.71,122.31 189.71,115.6 191.18,114.13 191.18,107.15 189.59,105.56 187.26,105.56 186.49,104.79 186.49,104.19 188.75,101.92 188.75,99.39 186.23,96.87 186.23,89.71 184.64,88.12 184.64,86.59 186.13,85.1 186.13,81.17 186.08,81.12 186.08,77.83 186.22,77.69 186.22,75.83 186.46,75.59 186.46,74.4 185.28,73.22 185.28,72.34 185.83,71.79 v1(185.83,71.47)
  BOTTOM w0.178: U508.6 v1(185.83,71.47) ; v1(56.58,109.25) 55.76,108.43 55.76,104.79 58.06,102.49 60.78,102.49 61.29,101.98 62.33,101.98 62.96,101.34 62.96,95.27 63.23,95 67.84,95 68.1,95.27 68.1,95.78 68.37,96.04 68.37,98.5 70.25,100.38 v1(70.47,100.38)
PWRGOOD: length 407.4
  TOP w0.102: 95.69,90.17 v2(96.66,89.2)
  TOP w0.178: v1(153.61,57.98) 153.95,58.32 153.98,58.32 154.25,58.58 U15.35 ; v1(55.22,115.57) 55.21,115.57 54.83,115.19 54.83,113.26 57.32,110.77 60.24,110.77 62.32,108.69 63.32,108.69 64.31,107.7 65.13,107.7 66.79,106.05 66.79,102.14 70.57,98.36 70.57,96.2 71.68,95.08 73.56,95.08 75.12,96.64 75.12,99.03 75.58,99.5 76.11,99.5 76.49,99.12 76.49,97.8 76.92,97.37 77.84,97.37 78.15,97.06 78.15,95.47 76.84,94.16 76.84,92.62 79.18,90.28 95.58,90.28 95.69,90.17 ; v1(125.45,87.79) 121.92,84.26 121.92,76.95 122.3,76.56 122.36,76.56 122.92,76.01 122.92,75.5 123.43,74.99 123.87,74.99 124.84,74.03 124.84,71.37 124.09,70.61 124.09,66.89 124.09,66.67 124.09,66.2 124.09,66.19 124.09,64.5 125.31,63.29 125.31,60.48 124.73,59.91 124.73,56.75 v1(124.73,56.74) ; U18.4 v1(127.58,17.58) ; U11.T26 v2(96.66,89.2)
  LY3 w0.171: v1(124.73,56.74) 124.31,56.32 124.31,52.34 125.96,50.69 128.78,47.87 128.78,45.83 129.41,45.2 130.16,45.2 130.76,45.8 130.76,46.84 130.91,46.99 135.53,46.99 136.67,45.84 136.67,44.17 139.42,41.42 139.42,40.3 141.26,38.46 141.26,32.1 141.37,32 141.37,25.07 140.61,24.31 140.61,23.6 133.5,16.5 130.48,16.5 129.4,17.58 v1(127.58,17.58)
  LY4 w0.171: v1(153.61,57.98) 152.57,56.94 152.57,54.06 153.28,53.35 153.28,52.53 154.24,51.57 154.24,50.59 153.86,50.21 147.6,50.21 144.04,53.77 139.25,53.77 138.88,54.15 137.8,54.15 136.39,55.56 136.02,55.56 134.89,56.69 134.89,61.65 134.22,62.32 131.19,62.32 130.73,61.86 130.73,61.41 125.98,56.65 124.83,56.65 124.73,56.74 v1(124.73,56.74)
  BOTTOM w0.102: 98.49,90.73 97.65,89.89 97.36,89.89 v2(96.66,89.2)
  BOTTOM w0.178: v1(153.61,57.98) 153.29,57.66 R673.2 R674.2 ; v1(55.22,115.57) 55.22,116.21 53.82,117.62 50.25,117.62 48.35,119.51 40.94,119.51 39.03,117.6 32.77,117.6 27.94,112.77 27.94,110.62 23.11,105.79 19.81,105.79 11.43,97.41 11.43,69.93 10.16,68.66 10.16,63.5 9.42,62.76 7.72,62.76 5.31,60.34 5.31,59.28 6.01,58.57 8,58.57 9.12,59.69 30.69,59.69 32.73,57.65 32.73,43.81 33.34,43.19 37.65,43.19 38.07,42.77 41.99,42.77 42.41,43.19 42.74,43.19 43.38,43.83 43.38,44.68 U513.4 ; 98.49,90.73 106.25,90.73 106.99,91.46 109.59,91.46 R577.2 122.81,90.42 v1(125.45,87.79)
REAL_CWTACH1: length 11.3
  TOP w0.178: v2(162.99,60) 163.08,60.08 U15.5
  BOTTOM w0.178: v2(162.99,60) 163.27,59.72 163.28,59.72 163.66,59.35 163.66,59.33 164.52,58.47 166.87,58.47 168.15,59.75 R665.2
REAL_CWTACH2: length 11.8
  TOP w0.178: U2.5 v2(164.29,112.79)
  BOTTOM w0.178: v2(164.29,112.79) 164.29,110.15 166.94,107.49 R519.2
RED_LED_EN: length 165.3
  TOP w0.178: U7.63 49.58,96.52 49.79,96.31 51.15,96.31 v1(51.35,96.5)
  LY3 w0.171: v1(51.17,108.63) 51.17,108.63 51.23,108.57 51.95,108.57 52.46,108.07 52.46,105.02 51.14,103.7 51.14,101.13 49.5,99.49 49.5,98.8 51.35,96.94 v1(51.35,96.5) ; v1(13.88,86.13) 14.58,85.43 14.58,80.66 12.59,78.66 12.59,76.17 11.38,74.96 11.38,24.55 12.63,23.3 12.63,17.39 8.45,13.21 6.78,13.21 6.74,13.17 6.24,13.17 6.2,13.21 5.73,13.21 v1(5.68,13.26)
  LY4 w0.171: v1(13.88,86.13) 11.29,88.72 11.29,101.2 13.01,102.92 13.9,102.92 25.92,102.92 27.62,101.22 29.1,101.22 29.63,100.69 32.32,100.69 33.88,99.12 34.61,99.12 36.2,99.12 36.7,98.63 40.88,98.63 45.5,94.01 46.39,94.01 47.74,95.35 49.44,95.35 50.59,96.5 v1(51.35,96.5)
  BOTTOM w0.178: RN500.1 51.26,108.54 v1(51.17,108.63) ; J12.1 51.76,96.52 51.74,96.5 v1(51.35,96.5) ; U519.5 5.29,13.5 5.68,13.12 v1(5.68,13.26)
RTCK: length 13.4
  TOP w0.178: J32.13 43.85,36.83 v1(43.32,37.37) 41.94,37.37 41.26,38.05 38.15,38.05 J28.11
  BOTTOM w0.178: v1(43.32,37.37) 43.85,36.83 R722.1 ; R724.1 J28.11
RTCKR: length 62.6
  TOP w0.178: v1(51.48,51.15) 51.48,45.26 48.63,42.41 47.42,42.41 v1(47.39,42.38) ; U11.E4 v2(84.66,66.2)
  BOTTOM w0.102: v2(84.66,66.2) 85.06,65.8 85.06,62.81 84.58,62.33 84.58,62.23
  BOTTOM w0.178: v1(47.39,42.38) 47.39,42.38 47.39,38.3 R722.2 ; v1(51.48,51.15) 51.99,50.64 52.69,50.64 52.91,50.42 53.77,50.42 54.57,51.22 57.19,51.22 58.09,50.32 63.11,50.32 63.75,50.96 74.54,50.96 80.54,56.96 80.54,59 81.95,60.41 82.8,60.41 84.58,62.19 84.58,62.23
SCI_RXD: length 3.9
  TOP w0.178: U7.92 38.64,102.84 v1(39.69,101.79)
  BOTTOM w0.178: v1(39.69,101.79) 38.81,101.79 R570.1
SCI_TXD/PROG_1: length 298.1
  TOP w0.178: v1(30.48,101.98) 30.48,101.41 30.87,101.02 U7.4 33.93,101.02 34.4,100.55 35.16,100.55 38.94,96.77 v1(43.94,96.77) ; v1(183.26,11.3) 183.26,12.24 U20.18
  LY3 w0.171: v1(29.84,14.53) 27.87,14.53 27.3,15.1 27.3,17.67 26.54,18.42 25.2,18.42 24.67,17.89 24.67,13.55 23.9,12.77 22.07,12.77 21.63,13.22 21.63,30.96 22.53,31.86 23.48,31.86 25.52,33.9 25.52,43.86 25.5,43.88 25.5,44.32 25.42,44.4 25.42,47.12 24.78,47.75 24.78,48.64 24.79,48.64 24.79,58.69 25.2,59.11 27.7,61.6 27.7,66.9 27.92,67.12 28.69,67.89 28.69,77.37 28.55,77.51 28.55,79.48 28.3,79.73 28.3,81.95 28.05,82.2 28.05,84.03 27.51,84.58 27.51,86.93 26.89,87.55 26.89,89.11 27.85,90.07 27.85,90.32 28.07,90.54 28.07,94.76 28.32,95.01 28.32,98.68 28.77,99.12 28.77,99.56 29.12,99.92 29.12,100.62 v1(30.48,101.98)
  LY4 w0.171: v1(29.84,14.53) 29.84,15.15 32.77,18.08 33.21,18.08 34.63,19.51 36.08,19.51 36.87,20.29 37.23,20.29 37.47,20.54 37.97,20.54 38.21,20.29 44.84,20.29 46.09,19.05 48.58,19.05 49.12,18.5 55.05,18.5 56.2,19.65 61.57,19.65 68.36,12.86 79,12.86 82.03,9.82 86.18,9.82 86.19,9.82 95.16,9.82 96.02,8.95 97.02,8.95 97.8,9.73 103.75,9.73 104.21,9.28 105.38,9.28 106.28,8.38 116.95,8.38 117.48,8.9 119.47,8.9 120.03,9.46 120.03,9.81 121.26,11.05 126.53,11.05 126.95,11.48 142.12,11.48 142.55,11.04 145.65,7.94 174.68,7.94 178.64,11.9 182.66,11.9 v1(183.26,11.3)
  BOTTOM w0.178: v1(43.94,96.77) 44.62,96.1 RN503.1
SCL: length 137.6
  TOP w0.178: v1(69.88,121.8) 69.87,121.79 J2.115 ; v1(122.28,118.13) 121.73,118.13 120.99,118.88 J3.115
  LY3 w0.171: J15.2 61.91,98.52 60.7,99.74 60.7,104.15 57.4,107.44 57.4,116.08 57.91,116.59 57.91,121.33 60.57,123.99 67.69,123.99 v1(69.88,121.8)
  BOTTOM w0.178: v1(69.88,121.8) 69.85,121.83 69.85,128.53 71.29,129.97 85.18,129.97 85.6,129.55 85.6,127.6 86.37,126.83 86.57,126.62 87.36,126.62 87.95,126.62 88.3,126.97 88.93,127.6 88.93,129.18 89.11,129.37 100.66,129.37 100.79,129.49 101.58,129.49 101.7,129.37 107.17,129.37 107.38,129.16 107.38,129.16 108.01,128.53 108.3,128.53 108.3,128.53 108.8,128.53 109.64,129.37 109.93,129.37 110.34,129.37 110.34,129.37 121.75,129.37 122.54,128.58 123.9,128.58 124.37,128.11 124.37,126.79 123.93,126.36 123.13,126.36 120.44,123.67 118.95,123.67 118.61,123.32 118.61,122.94 117.51,121.85 116.48,121.85 116.23,122.09 115.74,122.09 115.39,121.74 115.39,121.24 115.74,120.9 121.51,120.9 121.87,121.26 121.87,121.38 122.49,122 123.05,122 123.84,121.21 123.84,120.8 122.28,119.25 v1(122.28,118.13)
SCL0: length 574.7
  TOP w0.102: 79.69,72.7 U11.A10
  TOP w0.178: U16.6 178.63,23.93 v1(178.38,23.68) 177.16,22.46 177.16,21.72 176.59,21.14 U19.1 ; 38.1,53.86 39.03,54.8 39.03,73.59 33.15,79.47 32.07,79.47 30.62,80.92 30.62,87.86 28.31,90.17 16.27,90.17 13.76,92.69 13.76,99.82 14.65,100.72 20.38,100.72 22.54,98.55 28.51,98.55 29.08,99.12 29.08,99.43 29.53,99.88 29.53,102.75 28.18,104.09 28.18,108.16 30.01,109.99 30.01,114.83 30.75,115.57 50.81,115.57 51.68,114.71 51.68,112.17 51.9,111.94 51.9,108.44 56.04,104.31 58.64,104.31 58.76,104.43 60.41,104.43 61.91,102.93 J15.3 ; 38.1,53.86 36.93,52.69 35.04,52.69 28.42,46.08 28.42,35.46 25.08,32.12 21.9,32.12 20.12,30.34 20.12,9.61 21.53,8.2 29.48,8.2 31.09,6.59 31.09,3.17 ; 38.1,53.86 39.24,52.72 51.05,52.72 53.93,49.84 53.93,49.72 54.28,49.37 54.77,49.37 54.94,49.53 59.89,49.53 69.87,59.51 69.87,63.82 71.38,65.33 71.38,66.88 75.39,70.89 76.53,70.89 78.34,72.7 79.69,72.7 ; U5.6 178.88,107.44 v1(178.44,107.89) ; U20.23 186.17,10.97 186.6,10.54 186.6,9.95 185.41,8.76 183.68,8.76 v1(183.03,9.41) ; U11.A10 v2(80.66,72.2)
  LY3 w0.171: v1(183.03,9.41) 183.03,9.48 181.23,11.28 181.23,19.95 180.74,20.44 180.74,21.61 180.39,21.96 179.45,21.96 178.38,23.03 v1(178.38,23.68) 181.13,26.43 181.47,26.43 184.9,29.86 184.9,36.25 184.05,37.1 183.56,37.1 183.21,37.45 183.21,38.28 182.4,39.1 182.4,40.55 180.55,42.4 180.55,48.03 183.63,51.11 183.63,65.31 182.1,66.84 182.1,67.55 180.28,69.37 180.28,69.78 179.72,70.34 179.72,70.59 179.87,70.73 179.87,71.72 179.64,71.95 179.64,72.44 179.87,72.67 179.87,74.87 v1(180.47,75.48) ; v1(153.84,102.92) 153.84,95.96 154.01,95.79 154.01,81.56 153.84,81.4 153.62,81.4 153.27,81.05 153.27,80.55 153.62,80.2 153.84,80.2 153.84,80.04 v1(153.25,79.44) 152.45,78.65 152.45,73.52 149.73,70.8 149.73,65.96 147.55,63.78 147.55,63.61 v1(146.81,62.87)
  LY4 w0.102: v2(80.66,72.2) 81.11,72.2 81.5,71.81 81.97,71.81 82.17,72.01 82.17,72.34 82.42,72.59 83.83,72.59 84.27,72.15 84.27,72.04 84.5,71.81 88.55,71.81 89.25,72.5 92.59,72.5 92.95,72.86 94.45,72.86 94.5,72.81 96.82,72.81 96.88,72.86 99.21,72.86 99.47,72.59 102.83,72.59 103.06,72.36 103.06,71.85 102.8,71.59 102.5,71.59 102.07,71.16 102.07,67.92 102.25,67.74 102.83,67.74 103.16,67.41 103.16,66.98 103.44,66.7 106.79,66.7 107.63,65.86
  LY4 w0.171: v1(180.47,75.48) 179.76,75.48 177.73,73.44 177.24,73.44 175.2,75.48 169.84,75.48 166.96,78.36 157.72,78.36 156.15,79.93 155.08,79.93 154.59,79.44 v1(153.25,79.44) ; v1(146.81,62.87) 141.86,62.87 141.67,63.06 140.83,63.06 138.84,65.05 132.6,65.05 131.74,65.05 130.57,63.88 128.63,63.88 127.34,62.59 125.04,62.59 121.33,58.88 121.33,53.3 119.93,51.89 109.26,51.89 109.08,52.07 109.08,52.47 107.87,53.68 107.87,54.18 108.22,54.53 111.06,54.53 113.9,57.38 113.9,58.88 112.95,59.84 111.37,59.84 111.02,60.18 111.02,60.58 110.25,61.35 110.25,63.03 109.95,63.33 109.95,63.54 107.63,65.86 ; v1(153.84,102.92) 165.33,102.92 165.94,102.31 172.13,102.31 173.16,103.34 173.89,103.34 v1(178.44,107.89)
  BOTTOM w0.102: 79.69,72.2 v2(80.66,72.2)
  BOTTOM w0.178: v1(146.81,62.87) 146.63,62.87 R635.2 ; 79.69,72.2 79.53,72.2 78.33,73.41 R627.2
SCL1: length 373.5
  TOP w0.178: J15.1 60.56,97.87 60.56,101.46 59.88,102.14 55.72,102.14 v1(54.68,103.18) ; 43.79,3.17 43.79,4.67 v1(43.81,4.7) ; U11.D20 v2(83.66,83.2) ; v1(115.99,121.49) 115.99,120.07 J3.95
  LY3 w0.171: v1(9.89,91.08) 9.93,91.08 11.04,92.19 17.28,92.19 24.72,84.75 24.72,77.68 22.9,75.85 22.48,75.44 22.48,73.67 22.12,73.31 22.12,72.23 22.48,71.87 22.48,66.93 20.83,65.28 20.83,64.01 19.18,62.36 19.18,46.48 23.36,42.3 23.36,35.95 18.33,30.93 18.33,28.79 18.34,28.79 18.34,27.7 18.33,27.7 18.33,12.4 21.72,9.02 25.65,9.02 25.86,8.81 27.94,6.73 41.78,6.73 v1(43.81,4.7) ; v1(57.29,126.66) 56.37,125.74 56.37,122 55.88,121.51 55.88,107.57 54.56,106.25 54.56,103.3 v1(54.68,103.18)
  LY4 w0.171: J15.1 60.58,97.85 60.58,101.35 59.79,102.13 59.41,102.13 59.31,102.23 53.99,102.23 52.67,100.91 52.67,100.21 51.24,98.78 49.03,98.78 47.59,100.23 46.34,100.23 45.95,100.62 43.99,100.62 42.68,99.31 41.2,99.31 41.18,99.34 37.73,99.34 36.36,100.71 34.18,100.71 31.61,103.28 28.56,103.28 27.94,103.9 21.42,103.9 20.37,103.9 20.04,103.9 19.8,103.66 17.36,103.66 16.07,104.95 12.49,104.95 10.81,103.28 9.54,102 9.54,91.47 9.89,91.11 v1(9.89,91.08)
  BOTTOM w0.102: v2(83.66,83.2) 83.66,83.24 83.29,83.61 81.95,83.61 81.93,83.59 81.35,83.59 81.06,83.3 81.06,82.04 80.83,81.81 80.71,81.81 80.27,81.36 80.27,81.32 79.69,80.74
  BOTTOM w0.178: J15.1 61.91,94.96 62.53,94.34 62.54,94.34 63.71,93.18 63.71,93.17 64.6,92.27 64.6,90.51 65.64,89.47 67.93,89.47 68.52,88.88 68.52,88.38 69.55,87.35 69.55,82.63 69.55,82.63 69.55,82.13 69.55,82.13 69.55,79.92 71.24,78.22 74.23,78.22 74.24,78.22 77.17,78.22 79.69,80.74 ; v1(57.29,126.66) 57.29,129.39 58.97,131.06 85.65,131.06 86.67,130.05 86.67,128.04 87.02,127.69 87.51,127.69 87.86,128.04 87.86,129.04 87.86,129.62 87.86,129.63 87.86,129.91 88.39,130.44 100.23,130.44 100.34,130.56 102.02,130.56 102.13,130.44 123.26,130.44 126.29,127.41 126.29,125.45 123.65,122.81 120.71,122.81 119.39,121.49 v1(115.99,121.49) ; R771.2 v1(43.81,4.7)
SCL2: length 312.7
  TOP w0.178: U7.5 33.66,100.52 33.7,100.48 33.78,100.48 34.46,99.8 v1(34.46,99.74) ; v1(55.85,7.24) 55.85,4.87 55.94,4.78 55.94,4.29 55.85,4.2 55.85,3.17 ; R2.1 v1(119.2,123.08)
  LY3 w0.171: v1(55.85,7.24) 54.58,8.51 39.75,8.51 37.85,10.41 33.91,10.41 32.13,12.19 32.13,13.11 29.9,15.34 28.16,15.34 27.87,15.63 27.87,17.6 26.69,18.78 24.92,18.78 24.63,18.49 23.9,18.49 23.61,18.78 23.61,31.49 25.88,33.76 25.88,44 25.85,44.03 25.85,44.46 25.77,44.55 25.77,47.27 25.57,47.47 25.14,47.9 25.14,48.49 25.14,58.54 25.35,58.75 28.05,61.46 28.05,66.75 28.07,66.77 29.04,67.74 29.04,68.03 29.04,68.04 29.04,75.11 30.92,76.98 32.11,76.98 32.64,77.51 32.64,78.87 32.14,79.37 29.95,79.37 29.01,80.31 29.01,80.89 29.9,81.79 29.9,83.61 29.39,84.12 29.23,84.12 28.86,84.49 28.78,84.49 28.22,85.06 28.22,87.22 27.6,87.84 27.6,88.81 28.56,89.77 28.56,90.03 28.78,90.24 28.78,92.51 30,93.73 30,94.99 29.24,95.75 29.24,97.52 29.61,97.9 30.33,97.9 30.85,98.42 30.85,99.58 30.61,99.82 30.61,100.46 30.99,100.84 32,100.84 33.1,99.74 v1(34.46,99.74) ; v1(52.47,113.11) 52.11,113.47 52.11,118.66 v1(55,121.55)
  BOTTOM w0.178: v1(119.2,123.08) 120.35,123.08 123.28,126.01 124.83,126.01 125.51,126.68 125.51,127.57 122.99,130.09 101.99,130.09 101.87,130.2 100.49,130.2 100.37,130.09 88.54,130.09 88.22,129.76 88.22,129.48 88.22,127.89 88.01,127.68 87.66,127.33 86.87,127.33 86.31,127.89 86.31,129.85 85.48,130.68 59.22,130.68 57.98,129.45 57.98,124.53 v1(55,121.55) ; 52.47,113.15 50.86,113.15 49.54,111.83 42.2,111.83 41.43,111.05 34.41,111.05 31.28,107.92 31.28,105.59 29.88,104.2 29.88,101.1 30.3,100.68 32.42,100.68 33.36,99.74 v1(34.46,99.74) ; 52.47,113.15 v1(52.47,113.11) ; 52.47,113.15 53.12,113.15 53.44,112.82 59.34,112.82 59.66,113.15 68.23,113.15 69.21,114.13 71.91,114.13 72.19,114.41 73.67,114.41 74.55,115.28 76.36,115.28 79.69,118.62 R545.2 R544.2
SCL2_C: length 2
  TOP w0.178: R2.2 120.5,122.01 120.5,120.08 J3.113
SCL_VMON: length 87
  TOP w0.178: v1(176.24,112.57) 176.24,99.85 163.63,87.24 163.61,87.26 163.08,87.26 162.86,87.03 154.43,87.03 153.27,88.19 149.8,88.19 v1(148.9,87.29)
  LY3 w0.171: v1(141.31,64.51) 141.31,66.13 142.34,67.16 142.74,67.16 144.4,68.82 144.4,73.29 144.17,73.51 144.17,73.9 144.17,74.44 144.75,75.02 144.75,75.94 144.76,75.95 144.76,81.06 147.4,83.7 147.4,83.7 148.06,84.45 148.16,84.45 148.93,85.22 148.93,87.29 v1(148.9,87.29)
  BOTTOM w0.178: 141.52,64.29 141.59,64.23 141.59,63.44 140.78,62.64 140.78,61.62 141.45,60.95 141.57,60.95 142.54,59.97 142.54,58.99 142.83,58.7 U512.9 ; 141.52,64.29 v1(141.31,64.51) ; 141.52,64.29 U510.9 145.56,64.29 R635.1 ; U501.9 v1(176.24,112.57)
SCTRLA_N: length 51.9
  TOP w0.178: U11.V1 v2(98.66,63.2)
  LY3 w0.102: 99.04,62.86 99.04,62.88 99.07,62.91 99.07,63.5 98.85,63.72 98.62,63.72 98.51,63.61 98.51,63.35 v2(98.66,63.2)
  LY3 w0.105: 99.04,62.86 99.04,61.89 99.31,61.61 99.31,59.4 98.74,58.83 98.74,55.8 94.8,51.86 94.8,40.33 95.21,39.92 95.95,39.92 96.22,39.65 96.22,39.49 96.03,39.29 95.04,39.29 94.8,39.05 94.8,38.29 95.35,37.74 95.35,36.56 96.7,35.22 96.7,34.83 96.62,34.75 96.62,33.01 97.36,32.27 102.09,32.27 104.25,30.11 104.25,28.4 104.07,28.22 104.07,26.31 103.96,26.2 103.66,26.2 103.53,26.32
  LY3 w0.108: 103.53,26.32 v1(103.53,26.67)
  BOTTOM w0.108: 102.9,26.04 v1(103.53,26.67)
SCTRLA_P: length 52
  TOP w0.178: U11.V2 v2(98.66,64.2)
  LY3 w0.102: 99.3,62.86 99.29,62.86 99.29,62.88 99.27,62.91 99.27,63.61 98.67,64.2 v2(98.66,64.2)
  LY3 w0.105: v1(103.53,25.4) 104.06,25.93 104.06,25.94 104.33,26.2 104.33,28.12 104.5,28.29 104.5,30.22 102.2,32.52 97.47,32.52 96.87,33.12 96.87,34.65 96.95,34.72 96.95,35.33 95.61,36.67 95.61,37.85 95.06,38.4 95.06,38.94 95.15,39.04 96.14,39.04 96.47,39.38 96.47,39.76 96.05,40.18 95.32,40.18 95.06,40.44 95.06,51.76 99,55.7 99,58.73 99.57,59.3 99.57,61.72 99.3,61.99 99.3,62.86
  BOTTOM w0.108: J500.6D v1(103.53,25.4)
SCTRLB_N: length 49.3
  TOP w0.178: U11.J2 v2(88.66,64.2)
  LY4 w0.102: 89.29,62.79 89.29,62.81 89.27,62.84 89.27,63.55 89.01,63.8 88.76,63.8 88.66,63.9 v2(88.66,64.2)
  LY4 w0.105: v1(84.48,26.67) 84.48,26.29 84.35,26.17 84.18,26.17 83.98,26.37 83.98,29.59 82.82,30.74 82.82,32.66 82.82,32.66 82.95,32.79 82.95,35.35 81.79,36.51 81.79,37.75 81.92,37.88 82.6,37.88 82.93,38.2 82.93,38.67 82.6,39 81.98,39 81.78,39.2 81.78,39.49 81.98,39.69 82.52,39.69 83.01,40.18 83.01,54.68 83.98,55.65 83.99,55.65 83.99,55.65 87.82,55.65 89.29,57.13 89.29,62.79
  BOTTOM w0.178: v1(84.48,26.67) J500.20E
SCTRLB_P: length 49.3
  TOP w0.178: U11.J1 v2(88.66,63.2)
  LY4 w0.102: v2(88.66,63.2) 88.66,63.51 88.75,63.6 88.93,63.6 89.06,63.46 89.06,62.84 89.04,62.81 89.04,62.79
  LY4 w0.105: v1(84.48,25.4) 84.48,25.75 84.32,25.91 84.07,25.91 83.78,26.2 83.78,26.21 83.72,26.26 83.72,29.48 82.57,30.63 82.57,32.77 82.63,32.82 82.63,32.83 82.69,32.89 82.69,35.25 81.53,36.41 81.53,37.85 81.81,38.13 82.49,38.13 82.67,38.31 82.67,38.57 82.49,38.75 81.88,38.75 81.53,39.1 81.53,39.59 81.88,39.95 82.42,39.95 82.76,40.29 82.76,54.79 83.87,55.91 83.88,55.91 83.89,55.91 87.72,55.91 89.04,57.23 89.04,62.79
  BOTTOM w0.178: J500.20D v1(84.48,25.4)
SDA: length 133.8
  TOP w0.178: J2.117 70.37,121.17 70.78,121.58 v1(70.78,122.09) ; v1(122.94,120.91) 122.94,119.44 122.42,118.92 121.78,118.92 121.49,119.21 J3.117
  LY4 w0.171: J16.2 63.29,99.68 63.29,101.9 62.68,102.51 60.34,102.51 60.32,102.49 59.82,102.49 59.81,102.51 59.54,102.51 58.82,103.23 58.82,107.37 58.21,107.98 57.87,107.98 57.34,108.5 57.34,110.84 55.32,112.86 53.26,112.86 52.76,112.36 52.25,112.36 51.7,112.91 51.7,118.27 51.97,118.54 v1(51.97,119.8)
  BOTTOM w0.178: v1(51.97,119.8) 56.24,119.8 57.1,120.66 61.63,120.66 63.39,122.43 67.68,122.43 68.93,121.18 70.38,121.18 70.78,121.58 v1(70.78,122.09) 70.78,128.56 71.84,129.62 80.74,129.62 81.23,129.13 81.23,128.85 81.58,128.5 82.08,128.5 82.42,128.85 82.42,128.99 83.05,129.62 84.68,129.62 85.24,129.05 85.24,127.74 85.24,127.45 86.01,126.68 86.01,126.68 86.43,126.27 87.22,126.27 88.1,126.27 88.45,126.62 89.28,127.45 89.28,128.59 89.7,129.01 100.81,129.01 100.93,129.14 101.43,129.14 101.56,129.01 107.02,129.01 107.86,128.17 108.45,128.17 108.95,128.17 109.15,128.38 109.78,129.01 110.48,129.01 110.49,129.01 115.62,129.01 116.27,128.36 116.27,127.14 116.17,127.04 116.17,126.68 115.49,126 115.49,123.65 114.66,122.82 114.66,122.33 115.03,121.95 115.03,121.1 115.59,120.54 122.57,120.54 v1(122.94,120.91)
SDA0: length 535.5
  TOP w0.178: v1(183.46,49.67) 183.46,49.67 184.66,50.87 184.66,52.83 179.96,57.53 178.56,57.53 176.53,59.56 176.53,79.63 177.97,81.07 177.97,100.05 177.25,100.77 177.25,105.4 177.71,105.86 178.35,105.86 178.36,105.85 179.53,105.85 179.85,106.17 U5.7 ; U11.B10 v2(81.66,72.2) ; U19.6 178.61,22.14 179.75,23.28 U16.5 182.03,23.28 v1(182.16,23.42) 182.63,22.96 182.63,19.91 180.88,18.16 174.12,18.16 173.68,17.72 173.64,17.72 173.29,17.37 173.29,11.37 175.17,9.49 178.52,9.49 179.2,10.16 183.26,10.16 184.28,9.14 185.29,9.14 186.25,10.1 186.25,10.39 185.67,10.97 U20.22 ; v1(137.08,67.6) 135.52,69.16 135.52,73.82 136.1,74.4 141.52,74.4 141.59,74.46 141.74,74.46 142.28,75 142.28,75.54 142.78,76.03 145.25,76.03 146.05,76.83 146.05,78.74 146.69,79.38 146.69,80.5 147.69,81.5 147.69,85.5 146.91,86.28 142.15,86.28 139.19,89.24 129.73,89.24 126.1,85.62 126.1,82 123.63,79.52 v1(123.63,79.52) ; J54.2 v1(29.84,4.82)
  LY3 w0.102: 101.28,75.66 102.9,75.66 103.27,75.3 103.27,73.04 103.5,72.81 105.13,72.81 105.34,72.59 107.11,72.59 107.44,72.27
  LY3 w0.171: v1(56.24,70.77) 56.19,70.77 56.19,70.72 56.18,70.72 55.3,71.6 55.3,73.55 56.75,75 56.75,75.49 57.95,76.68 57.95,77.18 59.34,78.57 59.71,78.57 60.41,79.28 60.52,79.28 61.45,80.21 61.45,80.72 61.95,81.22 62.35,81.22 64.07,82.94 64.79,82.94 67.36,85.5 68.38,85.5 69.88,87 69.88,87.11 70.44,87.67 70.44,89.44 70.52,89.52 70.52,90.97 71.12,91.57 71.12,94.08 70.33,94.87 69.6,94.87 69.34,94.61 66.42,94.61 65.46,95.58 65.46,99.39 64.45,100.39 J16.3 ; v2(81.66,72.2) 82.16,72.7 86.01,72.7 88.67,70.04 99.02,70.04 100.28,71.3 100.28,74.67 101.28,75.66 ; v1(182.16,23.42) 181.83,23.75 181.83,24.86 185.55,28.57 185.55,36.8 184.05,38.29 183.71,38.29 182.75,39.24 182.75,48.97 183.46,49.67 v1(183.46,49.67) ; v1(123.63,79.52) 123.2,79.1 121.55,79.1 117.34,74.89 116.42,74.89 113.79,72.27 107.44,72.27
  LY4 w0.102: v2(81.66,72.2) 81.6,72.2 81.2,72.59 80.06,72.59 79.76,72.9
  LY4 w0.171: v1(183.46,49.67) 183.46,49.67 184.66,50.87 184.66,57.66 177.55,64.77 175.01,64.77 174.24,65.53 165.23,65.53 164.97,65.27 164.97,65.27 164.47,64.77 161.93,64.77 160.66,66.04 158.24,66.04 157.1,67.18 154.18,67.18 153.67,66.67 150.75,66.67 149.99,65.91 148.34,65.91 147.57,66.67 145.16,66.67 143.76,65.28 140.34,65.28 139.32,66.29 138.39,66.29 v1(137.08,67.6) ; 79.76,72.9 78.01,72.9 77.07,71.95 76.27,71.95 75.87,71.55 74.36,71.55 74.26,71.65 71.13,71.65 70.1,70.63 70.1,69.91 69.54,69.34 67.56,69.34 66.67,70.23 64.9,70.23 63.5,68.83 58.93,68.83 57.02,66.93 56.42,66.93 56.19,66.7 53.89,66.7 53.66,66.93 51.56,66.93 51.35,67.14 50.16,68.33 48.64,68.33 47.5,67.18 47.5,65.02 46.94,64.46 46.11,64.46 46.05,64.52 33.33,64.52 33.33,64.52 v1(29.84,64.52)
  BOTTOM w0.102: v2(81.66,72.2) 81.66,72.26 81.15,72.77 79.88,72.77 79.69,72.96
  BOTTOM w0.178: v1(29.84,64.52) 28.96,63.63 28.96,62.23 33.66,57.53 40.01,57.53 43.05,54.48 47.12,54.48 51.31,50.29 51.31,45.34 50.04,44.07 50.04,26.8 46.23,22.99 43.69,22.99 39.24,18.54 39.24,14.22 v1(29.84,4.82) ; R636.2 v1(137.08,67.6) ; 79.69,72.96 78.7,73.95 77.79,73.95 76.75,73.95 76.75,73.95 76,73.95 69.48,73.95 69.48,73.95 68.74,73.95 65.41,70.61 63.12,70.61 61.98,69.47 57.94,69.47 57.89,69.52 57.38,69.52 56.19,70.72 56.19,70.77 v1(56.24,70.77) ; R561.2 65.27,100.52 J16.3
SDA1: length 379.8
  TOP w0.178: v1(64.94,81.92) 61.67,81.92 60.9,82.69 56.87,82.69 56.86,82.7 56.33,82.7 56.32,82.69 55.11,82.69 54.01,83.79 54.01,87.22 53.89,87.35 53.89,89.04 54.18,89.33 54.18,89.71 55.35,90.88 55.35,91.59 55.06,91.88 55.06,93.67 55.06,94.63 55.75,95.31 56.71,95.31 63.26,95.31 64.45,96.5 J16.1 64.45,96.55 65.65,97.74 65.65,101.2 65.94,101.49 65.94,101.64 66.05,101.75 66.05,102.25 65.94,102.36 65.94,105.64 65.59,105.99 63.24,105.99 63.07,105.81 63.07,105.2 62.51,104.65 61.34,104.65 60.88,105.11 58.81,105.11 58.46,104.75 56.22,104.75 52.62,108.36 52.62,112.29 53.38,113.06 53.38,114.09 v1(52.79,114.67) ; J3.93 115.49,121.09 115.35,121.23 115.35,121.76 116,122.41 116,125.17 115.85,125.32 115.85,126.33 v1(115.32,126.86) ; J55.2 42.54,4.69 v1(42.55,4.7) ; U11.E19 v2(84.66,82.2)
  LY3 w0.171: v1(10.27,92.38) 9.58,92.38 9.02,91.82 9.02,90.81 9.53,90.3 10.54,90.3 11.98,91.74 16.94,91.74 24.37,84.31 24.37,80.69 23.32,79.64 21.85,79.64 19.14,76.92 19.14,67.17 18.52,66.55 18.52,63.46 18.82,63.16 18.82,46.33 23,42.15 23,36.1 17.98,31.07 17.98,28.65 17.98,28.64 17.98,27.85 17.98,27.84 17.98,12.26 17.98,12.25 17.98,12.11 18.26,11.84 18.34,11.84 18.69,11.49 18.69,11.41 21.44,8.66 21.57,8.66 25.51,8.66 27.79,6.38 40.87,6.38 v1(42.55,4.7)
  LY4 w0.102: v2(84.66,82.2) 84.5,82.2 84.11,81.81 83.37,81.81 83.06,82.12 83.06,82.36 82.83,82.59 82.58,82.59 82.55,82.62 80.62,82.62 80.33,82.91
  LY4 w0.171: v1(64.94,81.92) 65.69,81.17 69.55,81.17 70.12,81.74 72.23,81.74 72.52,81.45 73.15,81.45 73.71,82 74.46,82 75.29,82.84 79.69,82.84 79.77,82.91 80.33,82.91 ; v1(52.79,114.67) 60.97,114.67 62.71,116.41 62.71,120.57 67.11,124.97 80.39,124.97 84.32,128.91 86.9,128.91 87.02,129.02 87.51,129.02 87.63,128.91 100.72,128.91 101.18,128.44 v1(101.18,128.29) ; v1(10.27,92.38) 10.27,102.23 12.64,104.6 15.3,104.6 16.6,103.3 19.98,103.3 20.22,103.54 20.69,103.54 27.62,103.54 28.33,102.83 28.63,102.83 28.64,102.82 31.48,102.82 31.63,102.67 31.63,102.66 31.64,102.66 33.96,100.34 35.77,100.34 37.12,98.98 41.03,98.98 41.05,98.96 45.12,98.96 45.96,98.12 45.96,97.66 46.76,96.86 47.73,96.86 49.06,98.2 50.94,98.2 51.52,97.62 52.16,97.62 53.02,98.47 53.02,100.77 54.13,101.88 57.51,101.88 58.04,101.35 58.04,96.39 58.93,95.5 61.09,95.5 61.34,95.25 63.18,95.25 J16.1
  BOTTOM w0.178: v1(101.18,128.29) 101.18,128.36 101.47,128.65 106.88,128.65 107.71,127.82 108.6,127.82 109.09,127.82 109.51,128.23 109.93,128.65 110.63,128.65 110.63,128.66 114.44,128.66 115.32,127.78 v1(115.32,126.86) ; R770.2 v1(42.55,4.7)
SDA2: length 370
  TOP w0.178: v1(34.25,105.54) 34.29,105.54 34.64,105.19 U7.100 ; v1(54.6,7.24) J56.2 ; R546.2 R547.2 85.19,106.18 84.29,107.09 83.26,107.09 83.18,107.17 83.18,107.6 82.28,108.5 82.28,109.86 82.56,110.14 82.56,112.1 83.01,112.54 83.01,115.1 82.38,115.73 82.38,116.02 82.38,116.15 82.38,116.16 82.38,117.99 82.58,118.19 82.58,121.7 78.57,125.71 78.57,127.25 79.31,127.99 v1(81.23,127.99) ; v1(103.13,127.35) 103.13,122.67 104.39,121.41 105.79,121.41 108.71,124.33 111.76,124.33 114.94,127.51 117.73,127.51 127,118.24 127,114.94 126.24,114.17 124.97,114.17 124.08,113.28 124.08,111.12 123.43,110.48 R10.1
  LY3 w0.171: v1(34.25,105.54) 30.73,105.54 27.5,102.3 27.5,98.92 27.71,98.7 27.71,90.68 27.5,90.47 27.5,90.21 26.53,89.25 26.53,87.4 27.15,86.78 27.15,84.43 27.7,83.89 27.7,82.05 27.94,81.8 27.94,79.3 28.19,79.04 28.19,67.9 27.78,67.48 27.34,67.04 27.34,61.75 25.05,59.46 24.43,58.84 24.43,47.9 24.43,47.6 25.06,46.97 25.06,44.25 25.14,44.17 25.14,43.73 25.15,43.73 25.15,43.14 25.15,34.13 23.34,32.33 21.97,32.33 19.8,30.15 19.8,13.62 21.11,12.31 27.44,12.31 28.95,10.8 32.13,10.8 33.53,9.4 37.97,9.4 39.24,8.13 53.71,8.13 v1(54.6,7.24)
  LY4 w0.171: v1(34.25,105.54) 34.25,106.8 34.18,106.87 34.18,109.21 33.15,110.24 25.65,110.24 23.5,112.39 19.05,112.39 18.29,113.16 18.29,118.05 18.47,118.23 18.47,118.98 18.29,119.16 18.29,124.21 19.05,124.97 22.48,124.97 24.26,123.19 32.51,123.19 36.96,127.64 73.41,127.64 75.69,129.92 100.56,129.92 v1(103.13,127.35)
  BOTTOM w0.178: v1(81.23,127.99) 83.17,127.99 85.57,125.59 88.96,125.59 90.72,127.35 v1(103.13,127.35)
SDA2_C: length 2.4
  TOP w0.178: R10.2 120.49,111.55 J3.114
SDA_VMON: length 175.2
  TOP w0.178: v1(176.89,121.63) 177.2,121.32 177.2,113.79 ; 177.52,113.46 177.9,113.08 177.9,112.55 ; 177.2,111.65 177.2,105.98 176.8,105.59 176.8,100.59 177.2,100.2 177.2,96.81 173,92.61 170.69,92.61 164.34,86.26 163.94,86.26 163.61,85.93 163.08,85.93 162.75,86.26 158.01,86.26 156.58,84.83 149.14,84.83 147.22,86.75 142.24,86.75 137.67,91.32 130.48,91.32 126.76,87.59 126.76,87.25 125.99,86.48 125.65,86.48 123.03,83.86 123.03,79.28 123.38,78.93 123.86,78.93 123.87,78.93 124.48,78.93 125.44,79.89 125.44,80.78 126.14,81.48 127.68,81.48 129.4,79.76 131.94,79.76 132.71,78.99 139.21,78.99 139.71,79.49 139.73,79.49 140.08,79.84 140.08,79.86 141.23,81.01 141.95,81.73 142.83,81.73 143.01,81.55 143.22,81.34 143.22,80.69 143.21,80.69 143.21,80.26 142.66,79.7 142.23,79.7 140.09,77.56 134.52,77.56 129.63,72.67 127.52,72.67 125.97,71.13 125.97,68.21 127.19,66.99 v1(139.12,66.99) 139.9,66.99 140.71,66.18 140.71,64.75 140.71,64.75 140.71,64.26 140.71,64.26 140.71,63 139.6,61.9 139.2,61.9 v1(136.87,59.56)
  TOP w0.254: 177.52,113.46 177.2,113.79 ; 177.9,112.55 177.9,112.35 177.2,111.65
  BOTTOM w0.178: U512.7 137.08,59.35 v1(136.87,59.56) ; U501.7 v1(176.89,121.63) ; U510.7 138.13,65.18 R636.1 138.13,66.35 138.45,66.67 138.81,66.67 v1(139.12,66.99)
SENSE_PULSE: length 194.4
  TOP w0.178: U11.G25 v2(86.66,88.2) ; v1(48.04,81.5) 48.04,81.8 49.59,83.35 49.59,86.68 51.05,88.14 51.05,91.57 49.6,93.02 U7.56
  LY3 w0.171: v1(10.76,76.92) 10.76,84.02 8.87,85.9 6.23,85.9 4.53,84.21 4.53,27.53 6.03,26.04 6.03,23.29 5.33,22.59 v1(5.33,22.23)
  LY4 w0.102: 80.03,85.31 80.31,85.59 85.28,85.59 85.5,85.81 85.83,85.81 86.27,86.25 86.27,87.36 86.66,87.76 v2(86.66,88.2)
  LY4 w0.171: 80.03,85.31 76.45,85.31 76.05,85.72 72.29,85.72 72.14,85.56 71.63,85.56 71.47,85.4 71.47,85.17 71.12,84.82 70.35,84.82 69.72,84.19 65.6,84.19 65.19,84.6 64.74,84.6 64.46,84.32 63.12,84.32 62.63,84.81 55.61,84.81 55.47,84.68 53.84,84.68 53.1,85.41 51.95,85.41 51.09,84.56 47.6,84.56 47.17,84.12 47.17,83.09 48.04,82.22 v1(48.04,81.5) 46.85,81.5 46.53,81.18 43.94,81.18 43.06,80.3 43.06,80.29 40.21,77.44 37.39,77.44 36.88,76.94 35.96,76.94 34.77,75.75 34.28,75.75 33.67,76.35 30.93,76.35 30.6,76.68 23.77,76.68 22.44,78.02 22.44,78.48 21.93,78.99 21.34,78.99 20.95,78.61 20.95,77.98 21.84,77.09 21.84,76.71 21.34,76.2 20.83,76.2 20.11,76.92 v1(10.76,76.92)
  BOTTOM w0.178: v1(48.04,81.5) 48.04,81.62 48.84,82.42 49.28,82.42 RN506.1 ; U519.11 3.3,17.4 2.92,17.78 2.92,21.08 4.06,22.23 v1(5.33,22.23)
SENSE_PULSE_BUF: length 77.5
  TOP w0.178: v1(6.22,27.81) 6.21,27.83 J38.12 ; J24.8 v1(26.92,50.8)
  LY3 w0.171: v1(6.22,27.81) 6.22,34.48 7.23,35.49 7.23,42.92 6.64,43.51 5.37,43.51 5.07,43.81 5.07,45.31 6.26,46.5 J23.12
  BOTTOM w0.178: U519.14 11.05,17.4 11.3,17.65 11.3,18.92 9.65,20.58 8.41,20.58 6.24,22.76 6.24,27.8 v1(6.22,27.81) ; v1(26.92,50.8) 30.13,50.8 31.26,49.68 31.26,46.33 29.82,44.9 27.34,44.9 25.82,43.37 14.36,43.37 10.23,47.51 7.25,47.51 J23.12
SENSOR_RST: length 55.4
  TOP w0.178: v1(45.78,96.08) 44.67,94.96 44.67,92.2 45.91,90.96 47.1,90.96 47.5,90.56 47.94,90.56 47.97,90.52 U7.51 ; v1(31.84,87.43) 31.84,89.33 29.12,92.05 25.01,92.05 20.66,96.39 19.32,96.39 18.55,97.16 J11.3
  LY3 w0.171: v1(31.84,87.43) 32.33,86.94 35.25,86.94 37.26,88.95 45.83,88.95 46.4,89.52 47.24,89.52 47.78,90.06 47.78,94.08 v1(45.78,96.08)
  BOTTOM w0.178: RN503.2 45.04,94.38 45.48,94.82 45.48,95.77 v1(45.78,96.08)
SEQ_SYNC: length 9.7
  TOP w0.178: U11.AB9 v2(102.66,71.2)
  BOTTOM w0.102: 107.37,70.73 107.36,70.74 103.12,70.74 v2(102.66,71.2)
  BOTTOM w0.178: R650.2 R649.2 109,68.33 109,68.38 108.06,69.31 108.06,70.04 107.37,70.73
SP_CLK: length 6.7
  TOP w0.178: J40.3 24.21,27.34 24.61,27.75 27.31,27.75 28.76,26.3 R45.2
SP_D0: length 3.3
  TOP w0.178: J40.4 23.54,26.09 25.32,24.32 R41.2
SP_D1: length 8
  TOP w0.178: R46.2 29.29,24.11 v1(28.96,24.43)
  LY4 w0.171: J40.5 23.84,23.87 26.77,23.87 27.01,24.1 27.5,24.1 27.77,23.84 28.48,23.84 28.96,24.33 v1(28.96,24.43)
SP_D2: length 2.7
  TOP w0.178: J40.6 24.84,23.6 R42.2
SP_D3: length 7.9
  TOP w0.178: R47.2 v1(29.29,22.8)
  LY4 w0.171: v1(29.29,22.8) 28.7,23.38 27.98,23.38 27.41,22.81 23.32,22.81 J40.7
SP_D4: length 2.9
  TOP w0.178: J40.8 23.86,22.1 R43.2
SP_D5: length 2.9
  TOP w0.178: J40.9 23.97,20.95 R44.2
SP_D6: length 9.4
  TOP w0.178: R55.2 29.95,20.45 30.06,20.56 v1(30.34,20.56)
  LY4 w0.171: J40.10 23.19,18.92 23.96,18.92 24.01,18.87 24.5,18.87 24.55,18.92 28.29,18.92 29.93,20.56 v1(30.34,20.56)
SP_D7: length 3.6
  TOP w0.178: R54.2 25.32,19.81 24.9,19.38 24.9,19.2 24.52,18.83 24.34,18.83 J40.11
SP_FB: length 20.1
  TOP w0.178: v1(28.68,12.94) 28.68,14.28 29.57,15.17 29.94,15.17 30.54,15.77 30.54,19.58 31.17,20.21 R56.2
  BOTTOM w0.178: v1(28.68,12.94) 28.68,17.06 27.36,18.38 25.15,18.38 J40.12
SP_STAT_IN: length 99.4
  LY3 w0.171: v1(39.5,30.35) 39.5,34.67 39.74,34.91 39.74,36.87 43.86,40.99 43.86,43.33 43.91,43.37 43.91,45.51 45.42,47.02 45.42,50.43 51.41,56.42 51.41,60.68 51.74,61.02 51.74,62.72 54.33,65.31 56.79,67.77 56.79,67.81 57.04,68.07 57.04,69.17 57.18,69.31 57.71,69.88 58.74,70.91 58.74,71.98 59.79,73.04 60.42,73.04 61.01,73.64 61.01,74.41 59.37,76.04 59.37,76.59 59.93,77.15 60.3,77.15 61,77.86 62.19,77.86 62.96,78.63 64.5,78.63 66.55,80.69 66.55,82.23 68.11,83.79 69.24,83.79 v1(70.87,85.42)
  BOTTOM w0.178: v1(70.87,85.42) 71.32,85.87 71.54,85.87 71.65,85.98 73.74,85.98 74.1,85.92 74.16,85.98 R593.2 ; U517.14 26.67,19.55 27.28,18.95 28.85,18.95 29.59,19.68 29.59,21.34 30.1,21.84 30.1,27.69 32.77,30.35 v1(39.5,30.35)
SP_WAVE_CLK: length 106.9
  TOP w0.178: U11.G26 v2(86.66,89.2)
  LY3 w0.102: 80.37,82.59 84.72,82.59 85.06,82.93 85.06,83.62 85.27,83.83 85.27,84.36 85.71,84.81 85.83,84.81 86.06,85.04 86.06,85.36 86.03,85.38 86.03,85.73 86.26,85.95 86.26,88.44 86.66,88.84 v2(86.66,89.2)
  LY3 w0.171: v1(40.26,22.73) 41.1,22.73 44.68,26.31 44.68,30.76 46.63,32.72 46.63,33.23 46.96,33.56 46.96,35.46 47.18,35.67 47.52,35.67 48.37,36.53 49.28,36.53 49.83,37.08 49.83,41.39 50.33,41.88 50.54,41.88 51.1,41.88 51.18,41.96 51.39,41.96 52.15,42.71 52.15,42.93 53.12,43.9 53.12,45.44 53.12,46.88 53.11,46.9 53.11,47.44 54.36,48.68 55.06,48.68 56.31,49.93 56.58,49.93 56.81,50.16 56.81,51.11 58.6,52.91 59.13,52.91 59.48,53.26 59.48,53.75 58.32,54.91 58.32,55.96 58.53,56.16 58.53,56.36 59.01,56.85 59.78,56.85 60.13,57.19 60.13,57.75 59.03,58.85 59.03,60.31 60.35,61.63 60.35,62.07 61.13,62.85 61.13,67.06 61.39,67.32 61.39,67.45 62.36,68.42 62.36,69.99 66.89,74.52 67.49,74.52 68.66,75.7 69.85,75.7 69.99,75.83 70.61,75.83 73.34,78.56 74.18,78.56 74.58,78.96 74.58,79.03 78.15,82.59 80.37,82.59
  BOTTOM w0.178: v1(40.26,22.73) 38.86,22.73 36.19,25.41 34.4,25.41 34.39,25.4 U517.2
SP_WAVE_D0: length 92.4
  LY3 w0.171: v1(33.4,24.75) 33.05,24.41 32.97,24.41 32.46,23.9 32.46,22.85 32.93,22.38 34.67,22.38 35.08,22.78 37.11,22.78 37.38,23.05 38.54,23.05 40.16,24.66 40.79,24.66 42.77,26.65 42.77,31.35 45.57,34.14 45.57,36.48 45.26,36.79 45.26,39.66 46.8,41.2 46.8,42.63 47.15,42.98 48.58,42.98 49.16,43.56 49.67,43.56 50.31,44.2 50.67,44.2 51.37,44.9 51.37,46.16 51.35,46.18 51.35,50.44 50.89,50.9 50.89,51.4 51.06,51.57 51.06,52.26 50.54,52.78 50.54,54.04 52.47,55.97 52.47,57.39 52.82,57.74 53.32,57.74 53.84,58.26 53.84,59.68 55.78,61.62 55.78,63.32 57.74,65.28 57.74,65.67 57.39,66.01 57.39,66.51 57.74,66.86 58.23,66.86 58.67,67.29 58.67,68.08 58.9,68.31 58.93,68.35 58.93,68.36 58.95,68.38 58.95,68.39 58.95,68.5 59.8,69.35 59.8,70.92 59.84,70.96 61.87,72.99 62.08,73.19 62.08,76.05 62.45,76.42 62.45,76.61 63.38,77.54 65.14,77.54 67.57,79.97 69.87,79.97 71.42,81.52 72.25,81.52 v1(72.77,82.04)
  BOTTOM w0.178: v1(72.77,82.04) 72.83,82.11 R596.2 ; U517.3 v1(33.4,24.75)
SP_WAVE_D1: length 88
  LY3 w0.171: v1(36.45,23.88) 37.09,24.52 37.09,25.39 37.44,25.74 37.94,25.74 38.29,25.39 38.71,25.39 39.43,26.1 39.43,29.44 40.09,30.11 40.09,36.72 44.22,40.85 44.22,43.18 44.27,43.23 44.27,45.36 45.78,46.87 45.78,50.28 51.76,56.27 51.76,60.54 52.1,60.87 52.1,62.57 57.14,67.62 57.57,67.62 57.95,68.01 57.95,68.4 58.24,68.68 58.24,68.79 59.09,69.65 59.09,71.84 59.94,72.69 60.56,72.69 61.37,73.49 61.37,74.68 60.92,75.13 60.92,76.55 60.9,76.57 60.9,77.06 61.34,77.5 62.34,77.5 63.11,78.28 64.87,78.28 67.92,81.32 70.21,81.32 71.63,82.74 71.63,83.16 v1(71.63,83.16)
  BOTTOM w0.178: R594.2 73.59,84.01 73.3,83.72 72.16,83.72 71.63,83.19 v1(71.63,83.16) ; v1(36.45,23.88) 35.6,24.72 34.68,24.72 34.06,24.1 U517.4
SP_WAVE_D2: length 93.6
  LY3 w0.171: v1(33.41,23.45) 33.46,23.41 34.7,23.41 34.82,23.53 35.29,23.52 35.52,23.76 35.52,23.96 36.07,24.51 36.07,25.92 35.76,26.23 35.76,27.11 36.39,27.74 37.27,27.74 37.9,27.11 37.9,26.56 38.15,26.31 38.58,26.31 38.58,34.77 39.37,35.56 39.37,37 42.93,40.56 42.93,41.95 43.27,42.3 43.27,43.65 43.56,43.94 43.56,45.65 44.7,46.8 44.7,49.66 45.07,50.02 45.07,50.58 51.05,56.56 51.05,60.83 51.38,61.16 51.38,62.83 51.45,62.94 52.61,64.09 52.61,65.32 52.96,65.67 54.14,65.67 56.33,67.86 56.33,68.97 56.93,69.56 57.55,70.23 57.55,70.23 58.38,71.07 58.38,72.13 59.65,73.4 60.27,73.4 60.64,73.76 60.64,74.26 59.02,75.88 59.02,76.74 59.78,77.51 60.15,77.51 60.86,78.21 62.04,78.21 62.82,78.99 63.56,78.99 66.04,81.48 66.04,82.28 68,84.23 68.84,84.23 70.62,86.02 70.84,86.02 v1(71.29,86.46)
  BOTTOM w0.178: v1(71.29,86.46) 71.42,86.33 73.77,86.33 73.98,86.3 74.02,86.33 74.17,86.33 74.18,86.34 74.18,86.35 74.35,86.53 74.46,86.53 74.73,86.79 R592.2 ; U517.5 v1(33.41,23.45)
SP_WAVE_D3: length 99.6
  LY3 w0.171: v1(69.47,88.77) 69.47,88.27 68.64,87.44 68.64,86.76 68.29,86.41 67.65,86.41 67.55,86.31 67.02,86.31 64.36,83.65 63.12,83.65 60.68,81.2 60.14,81.2 59.11,80.17 59.11,79.35 57.24,77.48 57.24,76.98 56.89,76.64 54.51,76.64 53.95,76.08 53.95,75.2 54.59,74.56 54.59,74.07 54.24,73.72 54.1,73.72 52.58,72.2 49.14,72.2 48.54,71.6 48.54,69.47 45.47,66.4 45.47,63.5 46.35,62.61 46.35,61.34 48.39,59.31 48.39,58.05 47.68,57.35 47.68,57.33 47.12,56.77 45.34,56.77 41.02,52.45 41.02,51.56 41.66,50.93 41.66,50.04 40.37,48.75 40.37,46.25 41.4,45.21 41.4,41.27 39.5,39.37 39.5,37.97 38.73,37.21 38.73,35.94 38.23,35.43 38.23,29.1 37.22,28.09 36.24,28.09 35.41,27.26 35.41,24.61 v1(34.93,24.13)
  BOTTOM w0.178: v1(34.93,24.13) 34.92,24.13 34.01,23.21 34.01,23.2 33.62,22.8 U517.6 ; v1(69.47,88.77) 70.23,89.53 71.42,89.53 71.47,89.58 72.04,89.58 72.08,89.53 73.91,89.53 74.04,89.66 R590.2
SP_WAVE_D5: length 87.3
  LY3 w0.171: v1(33.61,21.5) 34.13,22.02 34.82,22.02 35.23,22.43 37.26,22.43 37.53,22.69 38.7,22.69 40.31,24.31 40.93,24.31 43.31,26.68 43.31,30.86 45.59,33.15 45.59,33.67 45.92,34 45.92,36.63 45.62,36.94 45.62,39.52 49.31,43.21 49.82,43.21 50.45,43.84 50.82,43.84 51.73,44.75 51.73,44.86 51.73,46.3 51.7,46.33 51.7,48.19 53.04,49.53 53.04,50.42 52.44,51.02 52.44,54.94 53.38,55.88 55.76,55.88 56.77,56.89 56.77,63.31 59.38,65.91 59.38,67.78 59.46,67.86 59.66,68.17 59.66,68.2 60.52,69.06 60.52,70.63 60.56,70.67 62.04,72.15 62.79,72.9 62.79,73.1 63.23,73.54 63.23,75.67 64.07,76.51 65.23,76.51 65.93,77.21 67.43,77.21 67.85,77.63 69.2,77.63 v1(71.92,80.35)
  BOTTOM w0.178: U517.8 v1(33.61,21.5) ; R606.2 72.96,80.2 72.9,80.14 72.14,80.14 71.93,80.35 v1(71.92,80.35)
SSI_3D_TOGGLE: length 57.6
  TOP w0.178: v1(8.13,24) 7.2,24 5.8,25.41 4.95,25.41 4.58,25.04 4.58,24.66 4,24.08 J38.9 ; v1(16.38,40.92) 16.66,40.64 J24.15
  LY3 w0.171: J23.14 7.28,43.49 8.66,43.49 9.24,42.91 9.24,25.13 8.13,24.02 v1(8.13,24)
  LY4 w0.171: J23.14 7.27,43.5 9.93,43.5 13.51,39.93 15.39,39.93 v1(16.38,40.92)
  BOTTOM w0.178: U519.17 11.55,15.45 13.12,17.02 13.12,20.17 10.93,22.35 9.78,22.35 v1(8.13,24)
SSI_STB_B: length 77.9
  TOP w0.178: J38.8 3.8,22.83 5.05,21.58 7.12,21.58 v1(8.76,19.94) 10.22,19.94 12.33,17.83 J39.4 ; J24.14 v1(26.92,43.18)
  LY3 w0.171: J23.8 7.24,49.53 9.03,49.53 9.6,48.96 9.6,24.75 8.9,23.87 8.6,23.57 8.6,20.34 8.76,20.17 v1(8.76,19.94)
  LY4 w0.171: J23.8 7.25,49.52 10.6,49.52 10.93,49.19 19.89,49.19 25.9,43.18 v1(26.92,43.18)
  BOTTOM w0.178: v1(8.76,19.94) 8.89,19.81 8.89,18.41 8.64,18.17 8.64,17.37 8.56,17.29 8.56,15.32 9.07,14.8 U519.18
SSI_STB_G: length 85.9
  TOP w0.178: J38.7 3.86,21.58 4.46,20.98 6.69,20.98 8.17,19.51 v1(8.17,18.8) 8.7,18.26 8.79,18.26 10.47,16.58 J39.3 ; J24.12 v1(26.73,45.72)
  LY3 w0.171: J23.6 6.27,52.52 7.25,53.49 8.88,53.49 10.31,52.06 10.31,24.08 9.77,23.54 9.77,20.72 10.21,20.27 10.21,19.54 10.67,19.08 10.67,18.59 10.32,18.24 9.03,18.24 8.47,18.8 v1(8.17,18.8)
  LY4 w0.171: v1(26.73,45.72) 24.11,45.72 20.14,49.69 11.62,49.69 9.79,51.51 7.26,51.51 J23.6
  BOTTOM w0.178: U519.19 8.97,14.15 8.12,15.01 8.12,17.47 8.2,17.55 8.2,18.08 8.19,18.1 8.19,18.27 8.2,18.28 8.2,18.35 8.26,18.41 8.26,18.71 v1(8.17,18.8)
SSI_STB_R: length 87.8
  TOP w0.178: J39.2 10.06,15.33 7.57,17.82 v1(7.56,17.82) 7.52,17.85 7.52,19.18 6.26,20.45 4.12,20.45 4,20.33 J38.6 ; J24.10 v1(26.86,48.26)
  LY3 w0.171: v1(7.56,17.82) 7.62,17.88 7.62,18.5 7.57,18.55 7.57,19.04 7.92,19.39 8.46,19.39 8.53,19.33 9.52,19.33 9.69,19.51 9.69,20.04 9.33,20.39 9.33,23.72 9.82,24.33 9.96,24.46 9.96,50.41 8.87,51.49 5.7,51.49 5.14,52.04 5.14,53.42 6.24,54.52 J23.4
  LY4 w0.171: v1(26.86,48.26) 22.18,48.26 20.39,50.05 12.74,50.05 11.75,51.03 11.74,51.03 9.24,53.53 7.24,53.53 J23.4
  BOTTOM w0.178: v1(7.56,17.82) 7.62,17.75 7.62,14.86 8.02,14.46 8.02,13.95 8.47,13.5 U519.20
SSI_SUBFRAME: length 65.1
  TOP w0.178: J24.9 v1(13.42,48.26) ; v1(6.86,18.67) 6.1,19.42 6.1,19.44 5.71,19.84 4.66,19.84 3.9,19.08 J38.5
  LY3 w0.171: 8.26,36.51 8.26,26.63 7,25.37 7,23.88 7.48,23.39 7.48,19.48 7.23,19.22 7.23,19.2 7.21,19.19 7.21,19.02 v1(6.86,18.67)
  LY4 w0.171: v1(13.42,48.26) 10.49,48.26 9.77,47.54 4.71,47.54 3.46,46.28 3.46,35.12 4.52,34.05 5.79,34.05 8.26,36.51
  BOTTOM w0.178: v1(6.86,18.67) 6.86,17.61 7.07,17.39 7.07,14.78 7.58,14.28 7.58,13.25 7.98,12.85 U519.21
SSP0_CLK: length 173.4
  TOP w0.178: U15.2 165.45,58.58 165.63,58.4 v1(165.63,57.73) ; U2.2 166.47,111.29 167,110.76 167,110.7 v1(166.99,110.7) ; v1(133.16,48.26) 132.02,47.12 130.84,47.12 130.32,47.64 127.32,47.64 126.79,47.12 126.3,47.12 125.03,45.85 119.57,45.85 119.06,45.34 R28.1
  LY3 w0.171: v1(165.63,57.73) 170.03,57.73 170.98,56.78 174.59,56.78 175.04,57.24 175.04,58.97 173.39,60.62 173.39,60.87 173.04,61.22 172.79,61.22 172.13,61.88 172.13,79.71 169.88,81.97 169.88,83.54 167.73,85.68 167.73,90.75 168.89,91.91 168.89,103.28 166.78,105.38 166.78,106.51 166.09,107.21 166.09,109.1 166.67,109.68 166.67,109.86 166.99,110.19 v1(166.99,110.7)
  LY4 w0.171: v1(133.16,48.26) 134.43,49.53 141.26,49.53 146.81,43.98 146.81,39.5 148.97,37.34 162.94,37.34 164.47,38.86 169.8,38.86 171.96,41.02 171.96,43.37 172.61,44.02 173.16,44.02 175.04,45.9 175.04,46.54 175.48,46.99 178.18,46.99 182.13,50.94 182.13,52.18 180.34,53.98 178.69,53.98 177.8,54.86 169.29,54.86 166.42,57.73 v1(165.63,57.73)
SSP0_CLK_DMD: length 75.5
  TOP w0.178: R27.1 118.11,42.91 117.41,42.2 117.41,40.12 117.27,39.98 117.27,38.76 v1(115.99,37.48)
  LY3 w0.171: v1(115.99,37.48) 116.51,36.96 116.51,36.86 117.4,35.98 117.4,35.14 117.08,34.82 117.08,33.86 117.5,33.44 117.5,23.05 118.41,22.14 118.41,21.69 118.06,21.34 118.06,16.12 118.19,15.99 118.19,14.88 117.52,14.21 117.52,14.21 117.39,14.21 117.25,14.06 116.83,13.64 115.52,12.33 110.07,12.33 109.77,12.03 107.47,12.03 106.95,12.55 105.65,12.55 105.13,12.03 91.18,12.03 90.9,12.31 90.9,13.49 92.09,14.68 92.45,14.68 96.73,18.96 98.94,18.96 99.12,19.14 99.12,20.9 v1(98.42,21.59)
  BOTTOM w0.178: v1(98.42,21.59) 97.82,22.2 J500.10B
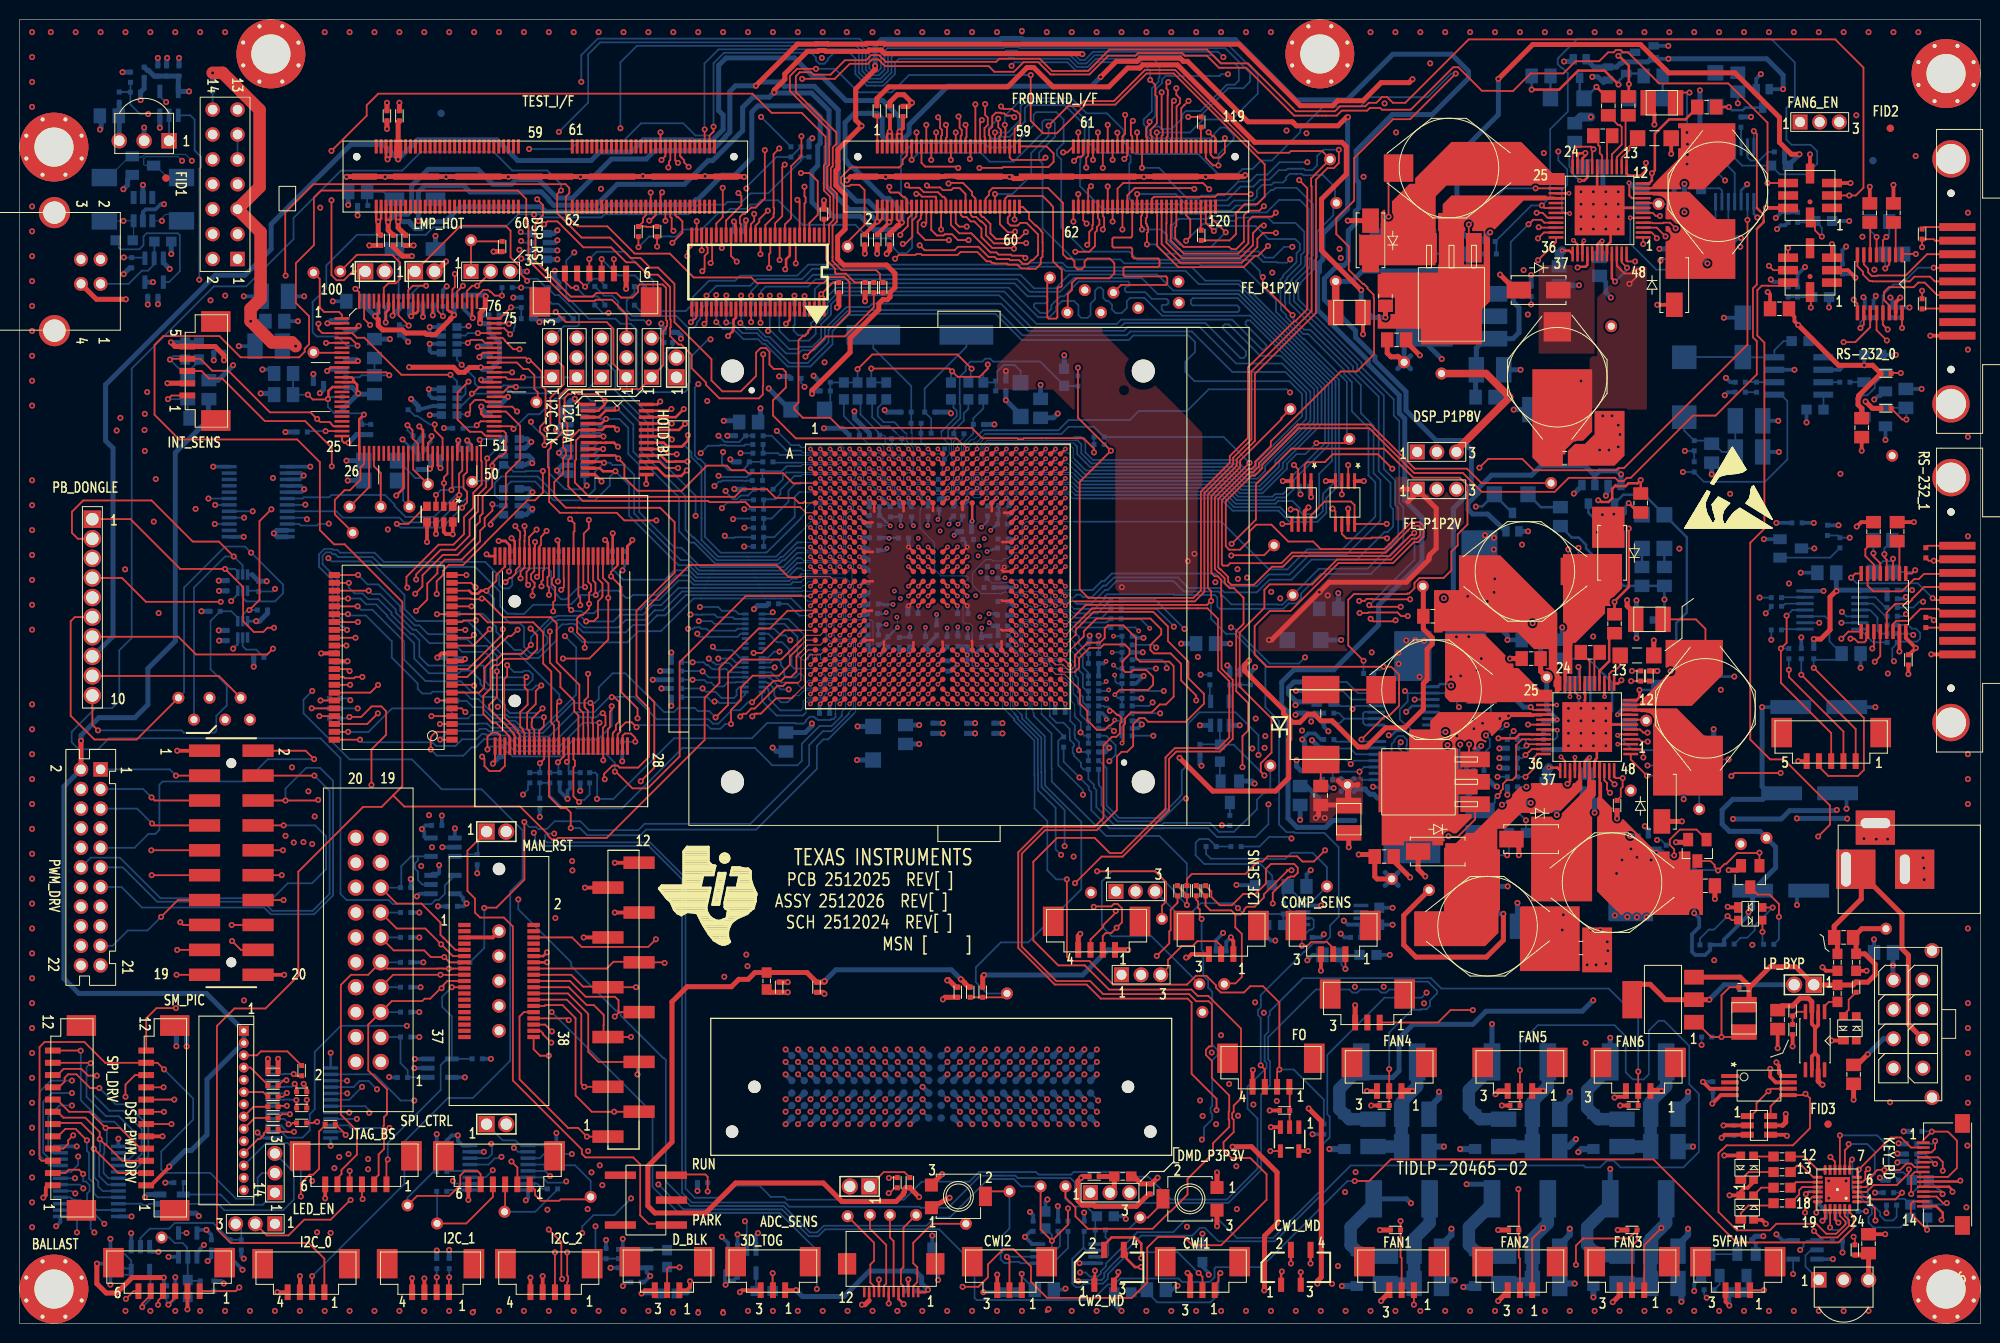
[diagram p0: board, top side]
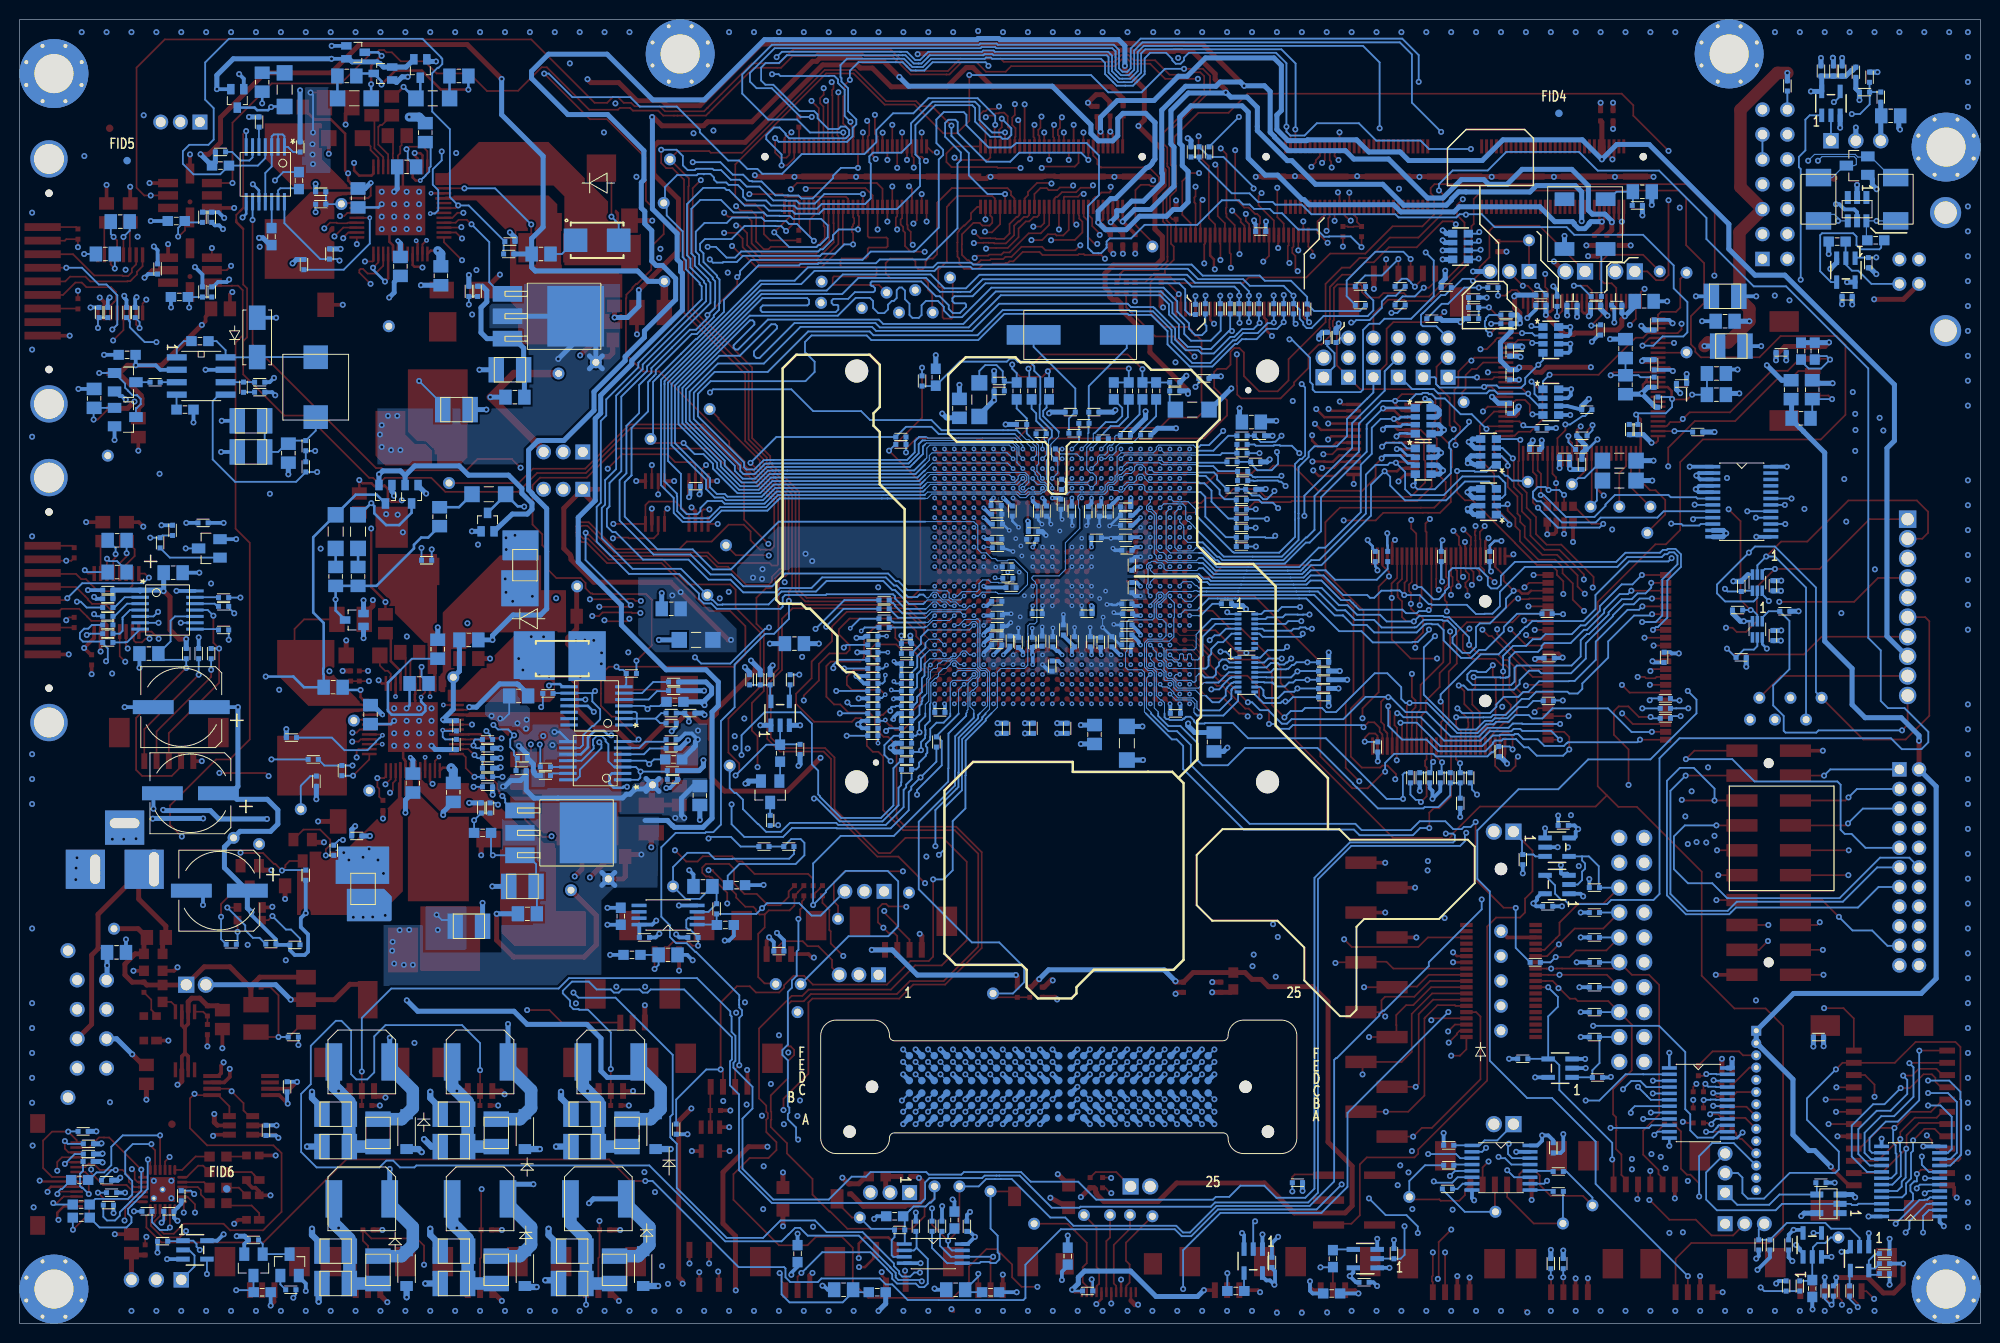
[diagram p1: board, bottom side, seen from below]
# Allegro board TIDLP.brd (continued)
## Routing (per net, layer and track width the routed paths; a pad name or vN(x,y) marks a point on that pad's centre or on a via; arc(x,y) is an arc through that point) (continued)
SSP0_CSZ0: length 39.6
  TOP w0.178: v1(109.9,46.12) 115.84,46.12 116.95,45.01 116.95,43.03 116.52,42.61 TP52.1 ; U11.AC5 v2(103.66,67.2)
  LY3 w0.171: v1(109.9,46.12) 110.42,46.64 110.42,52.24 109.92,52.75 109.68,52.98 109.68,54.23 109.18,54.73 109.18,57.34 108.98,57.54 108.98,57.54 v1(108.06,58.47)
  BOTTOM w0.102: v2(103.66,67.2) 104.11,67.2 104.5,67.59 104.83,67.59 105.06,67.36 105.06,67.25 105.5,66.81 105.78,66.81 106.27,66.32 106.27,66.04 106.5,65.81 106.61,65.81 107.06,65.36 107.06,65.04 107.06,63.29 107.14,63.2 107.14,63.17
  BOTTOM w0.178: R693.2 R692.1 108.23,58.29 v1(108.06,58.47) 108.06,59.29 107.64,59.71 107.64,60 107.6,60.04 107.6,60.54 107.64,60.58 107.64,60.98 107.16,61.46 107.16,62.69 107.14,62.71 107.14,63.17
SSP0_CSZ0_DAD1: length 131.8
  LY3 w0.171: v1(126.37,57.98) 126.37,57.46 126.4,57.43 126.4,56.17 126.37,56.14 126.37,55.51 128.15,53.74 128.15,52.99 130.37,50.76 130.41,50.76 131.09,50.08 135.41,50.08 137.74,47.75 137.74,45.8 138.75,44.8 138.75,44.31 139.32,43.73 140.44,43.73 142.33,41.84 142.33,33.58 v1(143.26,32.64)
  LY4 w0.171: v1(143.26,32.64) 142.27,32.64 138,28.37 121.5,28.37 121,27.88 121,27.38 121.67,26.72 121.67,22.35 121.09,21.78 120.45,21.78 120.04,21.37 120.04,20.74 118.93,19.64 118.93,18.25 117.2,16.52 115.39,16.52 114.98,16.12 110.83,16.12 110.41,16.54 109.58,17.37 102.23,17.37 100.76,17.37 100.19,16.8 98.98,16.8 98.98,16.8 98.69,16.8 98.69,16.8 98.37,16.8 98.16,17.01 97.8,17.37 96.73,17.37 95.91,18.19 v1(95.91,20.32)
  BOTTOM w0.178: R693.1 110.11,57.4 110.87,56.64 110.87,52.83 112.14,51.56 116.2,51.56 118.37,53.73 118.37,53.79 118.54,53.96 118.54,56.38 119.19,57.03 119.19,61.19 120.33,62.33 124.03,62.33 126.36,60 126.36,57.98 v1(126.37,57.98)
  BOTTOM w0.483: J500.12A v1(95.91,20.32)
SSP0_CSZ1: length 33.3
  TOP w0.178: U11.AB6 v2(102.66,68.2)
  LY3 w0.171: v1(108.21,60.29) 107.03,59.1 107.03,54.42 109.56,51.89 109.56,47.54 108.73,46.71 108.73,44.49 TP45.1
  BOTTOM w0.102: 107.62,62.23 107.62,63.12 107.27,63.48 107.27,65.65 107.1,65.82 107.1,66.49 106.79,66.81 106.5,66.81 106.37,66.93 106.37,67.22 106.23,67.36 106.08,67.36 105.85,67.59 105.5,67.59 105.48,67.57 105.14,67.57 104.91,67.8 104.51,67.8 104.06,68.25 104.06,68.36 103.83,68.59 103.5,68.59 103.11,68.2 v2(102.66,68.2)
  BOTTOM w0.178: 108.24,60.29 108.58,59.94 R690.2 R691.1 ; 108.24,60.29 v1(108.21,60.29) ; 108.24,60.29 108.24,61.31 107.62,61.93 107.62,62.23
SSP0_CSZ1_DMD: length 83.5
  LY3 w0.171: v1(111.16,57.35) 111.97,56.54 111.97,55.15 112.17,54.95 112.17,51.26 117.99,45.44 117.99,44.13 118.42,43.7 118.42,39.73 119.86,38.29 120.29,38.29 121.11,37.48 121.11,35.54 121.54,35.11 121.54,34.11 119.61,32.18 119.61,30.75 120.37,29.99 122.8,29.99 123,29.78 123.14,29.64 123.14,27.81 122.36,27.03 122.14,27.03 122.11,27.03 120.68,27.03 119.66,26.01 119.66,23.33 120.07,22.91 120.24,22.91 v1(120.41,22.74)
  LY4 w0.102: 96.72,19.61 96.72,19.85 96.59,19.98 96.59,22.27 v1(97.18,22.86)
  LY4 w0.171: 96.72,19.61 96.72,18.86 97.5,18.08 98.1,18.08 98.67,17.51 98.69,17.51 98.69,17.52 99.89,17.52 100.46,18.08 102.52,18.08 109.87,18.08 111.13,16.83 114.69,16.83 115.09,17.23 116.91,17.23 118.22,18.54 118.22,19.93 119.32,21.04 119.32,21.66 v1(120.41,22.74)
  BOTTOM w0.178: 96.55,23.5 v1(97.18,22.86) ; R690.1 110.83,59.94 111.79,58.98 111.79,57.99 v1(111.16,57.35)
SSP0_CSZ2: length 112.5
  TOP w0.178: U11.AC3 v2(103.66,65.2)
  LY3 w0.171: TP49.1 174.1,55.23 174.85,55.23 175.36,55.74 175.36,55.95 176.16,56.75 176.16,57.76 176.57,58.16 176.57,59.73 173.68,62.62 173.68,64.48 v1(173.53,64.64)
  LY4 w0.171: v1(173.53,64.64) 172.98,65.18 166.63,65.18 165.47,64.02 164.42,64.02 164.23,63.83 162.4,63.83 161.91,63.34 161.42,63.34 160.07,64.69 146.88,64.69 146.57,64.39 142.21,64.39 142.06,64.23 142.05,64.23 141.73,63.91 141.56,63.91 141.55,63.91 141.06,63.91 141.05,63.91 140.59,63.91 139.09,65.41 127.51,65.41 126.91,64.8 126.45,64.8 119.8,58.14 119.8,56.65 120.75,55.7 120.75,53.4 119.96,52.61 109.79,52.61 v1(108.46,53.93)
  BOTTOM w0.102: 104.22,62.23 104.22,64.64 v2(103.66,65.2)
  BOTTOM w0.178: v1(108.46,53.93) 108.46,54.4 105.94,56.92 105.94,59.41 106.36,59.83 R695.2 106.49,59.91 104.22,62.18 104.22,62.23 ; TP49.1 171.32,54.85 170.35,55.83 R667.1
SSP0_CSZ2_PMD1: length 127.1
  TOP w0.178: U15.4 165.2,59.58 165.44,59.35 v1(166.07,59.35)
  LY4 w0.171: v1(166.07,59.35) 175.66,59.35 177.85,57.15 177.85,55.78 178.97,54.66 180.62,54.66 182.82,52.47 182.82,50.66 178.46,46.3 176.87,46.3 175.74,45.17 175.74,44.5 174.72,43.48 173.95,43.48 172.64,42.17 172.64,40.74 170.08,38.18 168.37,38.18 165.93,35.73 148.81,35.73 146.13,38.42 146.13,43.69 142.56,47.26 136.86,47.26 136.83,47.23 132.22,47.23 131.57,47.88 131.57,48.75 v1(127.38,52.95)
  BOTTOM w0.178: v1(127.38,52.95) 127.38,50.93 126.08,49.63 122.12,49.63 121.21,50.54 116.69,50.54 116.65,50.5 111.16,50.5 109.31,52.34 109.31,54.2 109.05,54.47 109.05,54.75 v1(108.1,55.69) 106.49,57.3 R695.1
SSP0_CSZ3: length 42.8
  TOP w0.178: U11.AB4 v2(102.66,66.2)
  BOTTOM w0.102: v2(102.66,66.2) 103.27,65.59 104.83,65.59 105.07,65.35 105.07,62.23
  BOTTOM w0.178: TP42.1 127.57,56.7 127.32,56.45 127.57,56.2 127.57,54.61 127.07,54.11 126.9,54.11 126.22,53.43 126.22,52.46 126.22,52.46 124.71,50.95 124.66,50.95 123.86,50.15 122.34,50.15 121.43,51.06 116.71,51.06 116.5,50.85 111.65,50.85 109.83,52.66 109.83,54.42 109.57,54.68 109.57,54.96 109.02,55.51 R694.2 108.54,56.52 108.25,56.8 108.25,57.2 107.57,57.89 107.57,58.05 107.41,58.2 107.41,58.73 107.57,58.89 107.57,59.09 107.13,59.52 107.13,59.82 107.11,59.83 107.11,60.64 106.47,61.28 105.75,61.28 105.07,61.96 105.07,62.23
SSP0_CSZ3_PMD2: length 141
  TOP w0.178: U2.4 166.53,112.29 166.59,112.23 167.63,112.23 167.68,112.29 168.34,112.29 v1(168.92,111.71)
  LY3 w0.171: v1(137.08,116.97) 142.38,111.67 142.38,102.45 137.99,98.06 137.99,83.9 135.85,81.76 135.85,71.64 137.92,69.57 v1(137.92,68.45)
  LY4 w0.171: v1(118.97,53.54) 118.85,53.66 118.85,57.39 118.91,57.44 118.91,57.94 118.87,57.97 126.13,65.23 126.73,65.23 127.55,66.05 129.13,66.05 129.81,66.72 131.5,66.72 133.02,68.25 136.39,68.25 136.59,68.45 v1(137.92,68.45) ; v1(137.08,116.97) 151.66,116.97 155.9,121.21 165.65,121.21 168.92,117.94 v1(168.92,111.71)
  BOTTOM w0.178: v1(118.97,53.54) 118.69,53.54 116.35,51.21 111.99,51.21 110.35,52.85 110.35,54.64 110.09,54.9 110.09,55.18 110.06,55.21 R694.1
SSP0_CSZ5/SPD6: length 247.1
  TOP w0.178: R57.2 89.27,13.83 88.72,13.28 v1(88.65,13.28) ; U11.J23 v2(88.66,86.2)
  LY3 w0.171: v1(121.97,75.61) 122,75.61 122.68,74.93 122.68,73.53 123.83,72.39 124.08,72.14 124.08,71.32 124.16,71.24 124.16,70.75 123.81,70.4 123.31,70.4 123.02,70.69 122.22,70.69 120.23,72.68 116.75,72.68 115.95,71.88 115.95,71.2 115.96,71.19 115.96,69.84 116.59,69.22 116.59,68.96 116.86,68.68 116.86,68.33 118.75,66.45 118.75,65.53 120.13,64.15 120.26,64.15 121.16,63.25 121.16,58.67 121.65,58.18 121.65,52.73 120.59,51.67 120.59,49.91 121.76,48.74 123.34,48.74 125.73,46.36 125.73,45.25 126.11,44.87 126.11,43.69 129.92,39.88 129.92,36.46 130.85,35.54 130.85,24.92 130.4,24.48 129.92,24 129.92,23.24 127.8,21.12 126.53,21.12 124.84,19.43 124.84,15.49 124.08,14.73 122.17,14.73 119.89,12.45 118.12,12.45 117.37,11.7 117.35,11.69 117.35,11.69 116.67,11.01 116.67,9.86 115.87,9.06 113.28,9.06 111.64,7.42 94.44,7.42 93.95,6.93 81.26,6.93 80.63,7.56 80.63,11.65 81.89,12.9 87.12,12.9 87.5,13.28 v1(88.65,13.28)
  LY4 w0.102: v2(88.66,86.2) 88.68,86.2 89.15,85.72 89.15,83.69 90.42,82.42 95.63,82.42 97.28,80.77 97.28,80.52 98.3,79.5 99.06,79.5 101.09,77.47 101.09,76.83 101.73,76.2 107.19,76.2 107.57,75.82
  LY4 w0.171: v1(34.39,20.85) 35.88,20.85 36.25,21.23 36.25,21.27 36.83,21.84 58.55,21.84 59.82,20.57 62.99,20.57 69.05,14.52 81.93,14.52 83.71,12.74 87.93,12.74 88.48,13.28 v1(88.65,13.28) ; v1(121.97,75.61) 121.76,75.82 107.57,75.82
  BOTTOM w0.178: U517.9 v1(34.39,20.85)
SSP0_RXD: length 265.3
  TOP w0.178: TP54.1 100.32,33.26 R36.1 R35.2 ; U11.AD5 v2(104.66,67.2)
  LY3 w0.171: v1(159.73,28.61) 159.73,32.54 159.66,32.6 159.66,33.31 167.7,41.34 167.7,55.26 v1(166.05,56.91) 165.48,56.91 164.94,57.45 164.94,58.02 164.98,58.05 164.98,58.3 165.28,58.6 166.84,58.6 167.46,59.23 167.46,65.91 168.03,66.47 168.03,66.53 v1(168.4,66.53)
  LY4 w0.102: 98.21,19.61 98.21,19.72 97.97,19.96 97.97,21.78 97.99,21.8 97.99,25.86 v1(97.18,26.67) ; v2(104.66,67.2) 105.15,67.69 107.45,67.69 107.63,67.51
  LY4 w0.171: 107.63,67.51 108.01,67.13 108.01,66.25 109.93,64.34 110.31,63.96 110.31,63.47 110.62,63.16 112.42,63.16 113.76,64.51 115.68,64.51 117.32,62.86 123.15,62.86 125.95,65.66 126.55,65.66 127.37,66.48 128.96,66.48 130.3,67.83 130.3,68.2 131.57,69.47 134.21,69.47 134.55,69.13 135.42,69.13 136.02,69.72 136.68,69.72 136.84,69.56 138.77,69.56 138.93,69.72 140.21,69.72 140.97,68.96 152.53,68.96 153.16,69.6 159,69.6 159.26,69.34 163.32,69.34 164.72,67.94 166.98,67.94 v1(168.4,66.53) ; 98.21,19.61 98.21,19.4 98.8,18.81 110.96,18.81 112.23,17.54 114.39,17.54 114.8,17.95 116.57,17.95 117.51,18.88 117.51,28.27 119.58,30.34 121.76,30.34 123.57,32.15 125.82,32.15 125.92,32.05 126.42,32.05 126.67,32.29 127.16,32.29 127.17,32.28 134.33,32.28 134.84,31.77 139.03,31.77 141.6,34.34 143.76,34.34 144.11,33.99 144.11,28.34 145.78,26.67 157.79,26.67 v1(159.73,28.61)
  BOTTOM w0.102: v2(104.66,67.2) 104.26,66.8 102.41,66.8 102.07,66.45 102.07,65.95 102.27,65.75 102.27,65.04 102.71,64.59 102.83,64.59 103.07,64.35 103.07,62.94 102.67,62.55 102.67,62.23
  BOTTOM w0.178: 102.67,62.23 102.67,61.79 104.57,59.89 104.57,56.36 104.59,56.33 104.59,54.87 108.29,51.17 108.29,44.28 102.87,38.86 100.08,38.86 97.54,36.32 97.54,34.8 98.68,33.66 TP54.1 ; 96.55,26.04 v1(97.18,26.67) ; v1(166.05,56.91) R668.2 168.91,56.91 R666.2
SSP0_TXD: length 182.8
  TOP w0.178: v1(167.89,110.89) 166.99,111.79 U2.3 ; v1(179.63,56.15) 179.62,56.14 174.92,56.14 v1(174.6,55.83) ; v1(127.82,42.83) 127.82,43.93 129.39,45.49 129.56,45.49 129.65,45.59 130,45.59 130.37,45.96 130.37,46.49 130,46.87 127.64,46.87 127.13,46.37 127.13,44.88 126.06,43.81 124.81,43.81 123.66,42.65 122.41,42.65 121.56,43.51 121.56,44.06 R30.1 ; U15.3 v2(163.02,59.08)
  LY3 w0.171: v1(167.89,110.89) 167.89,109.93 167.84,109.88 167.86,109.86 167.86,109.37 167.51,109.02 166.97,109.02 166.78,108.82 166.78,107.49 167.47,106.8 167.47,105.67 169.57,103.56 169.57,91.1 168.54,90.06 168.54,86.22 172.82,81.93 172.82,62.16 173.08,61.9 173.33,61.9 174.08,61.15 174.08,60.9 175.99,58.99 175.99,58.2 175.73,57.94 175.73,56.96 v1(174.6,55.83)
  LY4 w0.171: v1(179.63,56.15) 179.63,55.95 180.56,55.02 180.77,55.02 183.17,52.61 183.17,50.51 179.63,46.96 179.63,46.09 167.71,34.17 161.27,34.17 146.47,34.17 146.19,34.44 146.19,34.85 144.62,36.42 144.21,36.42 142.62,38.01 142.62,45.83 142.15,46.31 138.44,46.31 135.57,43.43 128.42,43.43 v1(127.82,42.83) ; v1(174.6,55.83) 169.47,55.83 166.79,58.51 163.59,58.51 v2(163.02,59.08)
SSP0_TXD_DMD: length 99.1
  TOP w0.178: R29.1 120.02,43.23 120.21,43.04 120.21,42.39 120.38,42.22 120.38,41.44 v1(120.56,41.26)
  LY3 w0.171: v1(98.45,20.32) 97.78,19.65 96.45,19.65 92.17,15.37 91.81,15.37 88.99,12.55 82.15,12.55 81.54,11.94 81.54,9.6 82.98,8.15 92.55,8.15 92.82,7.88 98.61,7.88 100.05,9.32 101.63,9.32 101.79,9.47 103.18,9.47 103.22,9.44 106.67,9.44 108.06,8.04 111.76,8.04 113.13,9.41 115.73,9.41 116.32,10 116.32,11.16 117.21,12.04 117.21,12.04 117.97,12.81 119.39,12.81 120.59,14.01 v1(120.59,18.75)
  BOTTOM w0.178: v1(120.56,41.26) 120.56,38.11 120.74,37.94 120.74,35.47 121.23,34.98 121.23,34.24 121.64,33.82 121.64,28.43 122.19,27.88 122.19,27.38 121.64,26.83 121.64,22.16 121.49,22 121.49,21.51 121.64,21.35 121.64,20.82 120.8,19.98 120.8,18.96 v1(120.59,18.75) ; J500.10A v1(98.45,20.32)
SSP1_CLK: length 120.4
  TOP w0.178: TP34.1 11.94,59.56 7.62,59.56 5.21,61.98 5.21,71.63 5.63,72.05 J20.6
  LY4 w0.171: v1(71.75,88.9) 71.9,88.75 71.9,88.31 71.8,88.2 70.71,88.2 69.33,86.82 69.33,86.46 68.45,85.59 66.18,85.59 64.24,87.53 60.52,87.53 60.17,87.17 58.91,87.17 58.58,87.5 57.53,87.5 57.53,87.5 56.9,88.14 53.47,88.14 52.89,87.56 52.89,87.5 52.54,87.15 52.48,87.15 52.32,87 49.53,87 48.74,86.21 47.78,86.21 46.13,84.55 46.13,83.36 45.38,82.61 45.28,82.61 45.21,82.55 42.29,82.55 38.61,78.87 37.34,78.87 36.45,77.98 32.42,77.98 31.74,78.66 31.24,78.66 30.69,78.11 27.69,78.11 27.18,78.61 23.62,78.61 v1(23.61,78.63)
  BOTTOM w0.178: TP34.1 16.77,64.4 16.77,75.06 20.95,79.25 22.99,79.25 v1(23.61,78.63) 26.86,75.37 26.86,74.47 26.04,73.65 23.13,73.65 22.75,74.03 U507.5 ; R796.1 R789.2 74.24,87.69 74.24,87.53 73.75,87.03 72.29,87.03 71.64,87.69 71.64,88.49 71.75,88.6 v1(71.75,88.9)
SSP1_CSZ0: length 123.4
  TOP w0.178: J20.1 11.3,82.04 16.38,76.96 v1(20.95,76.96) 22.8,75.12 22.8,71.63 23.89,70.54 24.85,70.54 25.29,70.97 v1(25.95,70.97)
  LY3 w0.171: v1(25.95,70.97) 25.95,70.21 25.25,69.51 25.25,64.55 23.36,62.66 22.02,62.66 TP37.1
  LY4 w0.171: v1(71.29,90.55) 70.61,90.55 70.08,90.02 70.01,90.08 68.99,90.08 68.56,89.65 67.77,89.65 67.5,89.92 67.13,89.92 66.78,89.57 66.01,89.57 65.15,90.42 60.71,90.42 59.94,91.19 55.63,91.19 54.74,90.3 52.66,90.3 52.44,90.52 51.91,90.52 51.18,89.79 48.13,89.79 47.54,89.2 47.29,89.2 46.87,88.77 39.73,88.77 35.74,84.78 31.87,84.78 31.58,84.49 28.28,84.49 27.52,85.25 27.52,86.41 27.4,86.53 26.62,87.31 25.16,88.77 18.8,88.77 12.32,82.3 12.32,81.15 15.11,78.36 19.56,78.36 v1(20.95,76.96)
  BOTTOM w0.178: U507.1 22.25,76.69 21.97,76.96 v1(20.95,76.96) ; v1(71.29,90.55) 71.9,89.94 72.18,89.94 72.21,89.92 73.41,89.92 74.04,90.55 R792.2 R794.1
SSP1_DI: length 99.7
  TOP w0.178: v1(20.51,73.61) 12.88,73.61 10.44,76.05 J20.4 ; U11.F22 v2(85.66,85.2)
  LY3 w0.171: TP36.1 20.41,64.86 20.41,67.94 20.94,68.48 20.94,71.2 20.51,71.63 v1(20.51,73.61)
  LY4 w0.102: 80.58,84.29 80.88,84.59 85.06,84.59 v2(85.66,85.2)
  LY4 w0.171: 80.58,84.29 79.69,84.29 79.65,84.34 75.98,84.34 75.83,84.19 74.71,84.19 74.3,83.78 71.59,83.78 71.56,83.76 71.14,83.76 70.36,82.97 62.96,82.97 62.2,83.73 56.16,83.73 55.79,83.36 55.61,83.36 54.98,82.74 52.84,82.74 52.54,82.44 52.13,82.44 51.64,81.95 49.86,81.95 49.12,81.21 49.12,81.13 48.28,80.29 45.49,80.29 44.6,79.4 43.92,79.4 41.1,76.58 38.86,76.58 37.49,75.21 36.91,75.21 35.85,74.15 35.08,74.15 34.65,74.57 27.92,74.57 27.56,74.93 v1(26.05,74.93) 21.84,74.93 v1(20.51,73.61)
  BOTTOM w0.178: U507.4 24.31,74.74 R790.2 25.78,74.66 v1(26.05,74.93)
SSP1_DO: length 109.3
  TOP w0.178: v1(21.84,78.23) 20.32,79.76 17.65,79.76 13.46,83.95 6.48,83.95 5.33,82.8 5.33,80.64 5.94,80.04 J20.2
  LY4 w0.171: v1(21.84,78.23) 21.84,77.6 23.11,76.33 26.67,76.33 28.07,74.93 34.8,74.93 35.43,75.56 37.34,75.56 38.86,77.09 40.77,77.09 43.43,79.76 44.45,79.76 45.34,80.64 48.13,80.64 48.77,81.28 48.77,82.04 47.52,83.29 47.52,83.82 47.9,84.2 52.06,84.2 52.07,84.19 55.49,84.19 55.75,84.45 62.48,84.45 63.12,83.82 69.85,83.82 70.5,84.47 71.27,84.47 71.72,84.92 v1(72.01,84.92)
  BOTTOM w0.178: TP35.1 17.78,75.06 20.95,78.23 v1(21.84,78.23) 22.75,77.33 U507.2 ; R795.1 R791.2 74.93,85.09 74.3,84.45 73.53,84.45 73.15,84.07 72.77,84.07 72.01,84.84 v1(72.01,84.92)
SSP2/LED_DIN: length 162.2
  TOP w0.178: v1(42.54,74.41) 42.54,75.71 43.19,76.36 43.19,76.79 43.77,77.37 45.24,77.37 47.46,79.59 47.46,79.62 51.8,83.96 52.58,83.96 53.37,84.76 v1(53.37,86.95) ; J49.2 50.77,15.9 v1(50.16,16.51) ; TP29.1 46.64,86.33 U7.50 ; U11.K24 v2(89.66,87.2)
  LY3 w0.171: v1(35.54,16.76) 33.75,18.55 32.64,18.55 31.3,19.9 31.3,23.45 27.67,27.07 27.67,27.53 26.91,28.3 26.45,28.3 25.75,29 25.75,30.5 29.01,33.76 29.01,45.19 33.18,49.36 33.18,51.71 33.54,52.06 33.54,52.87 34.65,53.98 36.28,53.98 36.84,54.53 36.84,56.17 38.47,57.8 39.3,58.63 39.3,69.85 41.97,72.51 41.97,72.59 42.54,73.17 v1(42.54,74.41)
  LY4 w0.102: 80.15,86.9 80.24,86.81 83.92,86.81 84.27,87.16 84.27,87.36 84.5,87.59 84.83,87.59 85.06,87.36 85.06,87.25 85.5,86.81 85.83,86.81 86.06,87.04 86.06,87.75 86.26,87.95 86.26,88.35 86.5,88.59 86.83,88.59 87.06,88.36 87.06,87.96 87.42,87.6 87.91,87.6 87.94,87.64 89.23,87.64 v2(89.66,87.2)
  LY4 w0.171: v1(50.16,16.51) 49.52,16.51 49.39,16.39 47,16.39 46.08,17.32 37.3,17.32 36.75,16.76 v1(35.54,16.76) ; 80.15,86.9 77.25,86.9 76.61,87.54 74.97,87.54 74.65,87.86 73.06,87.86 72.71,87.52 71,87.52 70.01,86.53 70.01,85.91 69.01,84.9 65.89,84.9 65.32,85.48 64.61,85.48 64.17,85.03 63.67,85.03 63.01,85.69 60.39,85.69 59.6,86.49 58.18,86.49 57.85,86.82 56.07,86.82 55.23,85.97 54.37,85.97 53.39,86.95 v1(53.37,86.95)
  BOTTOM w0.178: v1(53.37,86.95) 51.63,86.95 51.56,86.89 50.37,86.89 49.67,87.59 RN505.1 48.84,87.07 48.84,86.85 48.47,86.47 48.24,86.47 47.75,85.98 47.12,85.98 TP29.1
SSP2_CLK: length 100.5
  TOP w0.178: U11.K23 v2(89.66,86.2)
  LY3 w0.102: 79.69,79.19 79.96,79.19 80.38,79.6 85.91,79.6 87.03,80.73 87.03,83.04 87.56,83.56 87.93,83.56 88.13,83.77 88.84,83.77 89.09,84.02 89.09,84.38 89.06,84.42 89.06,85.62 89.63,86.2 v2(89.66,86.2)
  LY3 w0.171: v1(56.32,17.27) 56.54,17.06 57.09,17.06 57.26,16.89 60.84,16.89 64.15,20.2 64.15,22.53 71.11,29.49 71.11,29.55 71.23,29.68 71.23,35.03 71.19,35.08 71.19,35.64 71.7,36.15 71.7,38.49 71.94,38.73 71.95,38.73 72.35,39.13 72.35,39.14 72.63,39.42 72.63,40.24 72.83,40.44 72.83,49.89 76.56,53.62 76.56,57.91 76.01,58.46 76.01,59.15 75.14,60.02 75.14,61.48 75.33,61.68 75.33,62.17 74.98,62.52 74.71,62.52 73.41,63.82 73.41,68.71 73.33,68.79 73.33,69.65 72.05,70.94 72.05,73.31 72.61,73.87 73.01,74.28 74,74.28 74.22,74.5 74.75,74.5 75.48,75.23 75.71,75.23 79.67,79.19 79.69,79.19
  BOTTOM w0.178: v1(56.32,17.27) 53.48,17.27 53.06,16.85 U518.3
SSP2_CSZ2/SPD7: length 112.4
  TOP w0.178: U11.J24 v2(88.66,87.2)
  LY3 w0.102: v2(88.66,87.2) 88.37,87.2 87.76,86.59 87.5,86.59 87.27,86.36 87.27,85.96 87.06,85.75 87.06,85.04 86.83,84.81 86.5,84.81 86.26,84.57 86.26,83.95 86.1,83.79 86.1,81.94 85.75,81.59 80.13,81.59 80.01,81.47 79.69,81.47
  LY3 w0.171: v1(37.72,19.94) 40.86,16.8 44.22,16.8 46.32,18.9 46.32,23.03 47.36,24.07 47.36,30.29 48.15,31.09 49.9,31.09 50.27,31.46 50.27,33.97 50.55,34.24 50.55,34.65 52.53,36.63 52.53,38.1 53.24,38.81 53.24,41.83 53.54,42.13 53.54,42.35 54.52,43.32 54.52,46.02 54.52,46.65 55.15,47.29 55.64,47.29 56.89,48.54 57.16,48.54 58.2,49.58 58.2,49.7 58.2,50 58.2,50.34 59.38,51.51 59.71,51.51 60.88,52.68 60.88,54.33 60.68,54.53 60.68,54.93 61,55.25 61.02,55.25 61.75,55.98 61.75,56.78 62.06,57.09 62.06,57.59 61.4,58.25 61.4,60.83 61.84,61.27 61.84,62.03 62.17,62.36 62.17,66.63 62.43,66.89 62.43,67.02 63.4,67.99 63.4,69.56 67.32,73.48 67.92,73.48 68.97,74.53 70.37,74.53 70.63,74.79 71.04,74.79 73.45,77.21 74.41,77.21 78.67,81.47 79.69,81.47
  BOTTOM w0.178: v1(37.72,19.94) 33.81,19.94 33.54,20.2 U517.10
SSP2_CSZ_0: length 113.8
  TOP w0.178: U11.J26 v2(88.66,89.2)
  LY3 w0.102: v2(88.66,89.2) 88.66,88.76 89.06,88.36 89.06,87.04 88.83,86.81 88.26,86.81 88.06,86.6 88.06,86.04 87.83,85.81 87.68,85.81 87.26,85.38 87.26,84.95 87.06,84.75 87.06,84.04 86.3,83.28 86.3,81.28 85.83,80.81 80.5,80.81 80.46,80.85 79.69,80.85
  LY3 w0.171: v1(57.99,17.57) 60.87,20.45 62.23,20.45 63.24,21.47 63.24,23.49 66.8,27.05 67.63,27.05 70.55,29.96 70.55,34.75 70.51,34.79 70.51,35.93 70.55,35.97 71,36.42 71,50.3 74.66,53.97 74.7,54.16 74.7,55.96 74.66,56.15 73.37,57.44 72.12,57.44 71.37,58.19 71.37,61.35 71.86,61.85 71.86,68.07 71.79,68.14 71.79,69.01 70.5,70.3 70.5,73.95 70.98,74.44 71.19,74.44 72.57,75.82 73.23,75.82 74.18,76.77 74.87,76.77 77.72,79.62 77.74,79.62 78.96,80.85 79.69,80.85
  LY4 w0.171: v1(57.99,17.57) 57.99,17.3 56.52,15.83 50.5,15.83 49.69,15.02 44.68,15.02 v1(44.2,14.54)
  BOTTOM w0.178: U518.10 44.49,14.25 v1(44.2,14.54)
SSP2_DO: length 150.2
  TOP w0.178: U11.J25 v2(88.66,88.2)
  LY3 w0.171: v1(41.76,51.84) 45.67,55.75 47.78,55.75 48.87,56.85 48.87,59.84 47.12,61.59 47.12,62.49 47.13,62.5 47.13,62.99 47.12,63 47.12,64.52 47.62,65.02 47.62,66.55 49.75,68.68 49.75,70.43 50.2,70.87 50.2,71.01 50.55,71.36 50.57,71.36 50.98,71.77 52.66,71.77 54.25,73.36 54.61,73.36 56.4,75.15 56.4,75.63 57.59,76.83 57.59,77.33 59.19,78.93 59.56,78.93 60.27,79.64 60.37,79.64 61.09,80.35 61.09,80.86 61.81,81.58 62.21,81.58 63.92,83.29 64.65,83.29 67.31,85.95 68.33,85.95 69,86.62 69,87.02 70.09,88.11 70.09,89.59 70.14,89.64 v1(70.14,94.1) ; v1(55.75,14.48) 54.39,14.48 54.35,14.44 53.28,14.44 51.46,16.26 51.46,20.18 50.2,21.43 49.75,21.43 48.71,22.47 48.71,26.89 50.81,28.99 50.81,33.95 52.95,36.09 52.95,38.01 53.39,38.45 53.67,38.73 53.67,41.51 54.5,42.34 54.5,42.8 54.88,43.18 54.88,46.17 55.64,46.93 55.78,46.93 56.01,47.16 v1(56.36,47.16)
  LY4 w0.102: 86.3,89.59 86.83,89.59 87.06,89.36 87.06,89.17 87.07,89.16 87.07,88.88 87.27,88.67 87.27,88.04 87.5,87.81 87.83,87.81 88.22,88.2 v2(88.66,88.2)
  LY4 w0.171: v1(41.76,51.84) 42.51,51.09 44.75,51.09 46.88,48.96 54.32,48.96 55.99,47.28 55.99,47.16 v1(56.36,47.16) ; v1(70.14,94.1) 69.84,94.4 69.84,97.15 71.95,99.26 73.9,99.26 77.15,96.01 77.46,96.01 79.51,93.96 81.93,93.96 82.44,93.45 82.44,93.45 83.64,92.26 86.3,89.59
  BOTTOM w0.178: U518.6 53.32,14.9 53.87,14.35 55.63,14.35 v1(55.75,14.48)
SUBFRAME: length 173.5
  TOP w0.178: v1(48.22,83.57) 48.22,82.92 47.43,82.13 47.43,81.32 46.97,80.86 46.97,79.79 45.08,77.91 43.38,77.91 42.61,77.15 42.61,76.52 41.57,75.48 41.57,73.83 v1(40.43,72.68) ; U7.64 v1(50.24,97.02) ; U11.D22 v2(83.66,85.2)
  LY3 w0.171: v1(48.22,83.57) 49.78,85.12 49.78,91.49 50.13,91.84 50.89,91.84 51.8,92.74 51.8,95.2 50.24,96.76 v1(50.24,97.02) ; v1(8.64,10.16) 8.64,11.39 13.11,15.86 13.11,23.33 11.74,24.7 11.74,70.02 v1(14.18,72.46)
  LY4 w0.102: 79.69,84.77 80.77,84.77 80.8,84.8 83.17,84.8 83.57,85.2 v2(83.66,85.2)
  LY4 w0.171: v1(14.18,72.46) 14.63,72.01 23.66,72.01 23.88,72.23 24.38,72.23 24.6,72.01 28.96,72.01 32.61,68.36 35.32,68.36 39.64,72.68 v1(40.43,72.68) ; 79.69,84.77 79.58,84.88 75.91,84.88 75.61,84.58 74.04,84.58 73.75,84.29 71.59,84.29 71.41,84.11 70.66,84.11 69.96,83.41 66.65,83.41 66.59,83.46 62.97,83.46 62.34,84.1 55.9,84.1 55.64,83.84 51.77,83.84 50.77,82.84 48.95,82.84 v1(48.22,83.57)
  BOTTOM w0.178: U519.4 5.14,12.85 5.27,12.73 5.3,12.73 5.41,12.62 5.67,12.62 5.71,12.57 6.22,12.57 v1(8.64,10.16) ; RN506.2 48.37,83.42 v1(48.22,83.57)
SW_BOOT: length 2.7
  BOTTOM w0.178: U505.1 183.97,99.49 183.26,100.2 C528.1
SW_COMP: length 3
  BOTTOM w0.178: C544.1 176.05,96.02 C542.1 177.18,96.01 U505.6
SW_EN: length 1.7
  BOTTOM w0.178: U505.3 R573.2
SW_PH: length 12.1
  BOTTOM w0.178: C528.2 179.92,100.2 178.99,99.28 U505.8 175.79,98.55 D501.2 169.82,98.58 L500.1
SW_SS: length 1.5
  BOTTOM w0.178: C541.2 184,94.72 U505.4
SW_VOUT: length 10.7
  BOTTOM w0.178: C543.1 C566.1 173.63,88.9 172.79,89.74 R587.1 172.28,90.06 R575.2 169.8,91.07 L500.2
SW_VSNS: length 52.3
  LY3 w0.171: v1(167.37,108.42) 170,105.79 170,90.92 169.18,90.1 169.18,87.32 v1(169.65,86.85)
  BOTTOM w0.178: U505.5 179.66,94.74 180.31,94.09 180.31,88.13 178.03,85.85 171.8,85.85 170.81,86.84 R588.2 170.81,86.85 v1(169.65,86.85) ; v1(167.37,108.42) 167.37,108.57 R520.1 169.33,108.57 172.99,112.23 U501.14
SWNODE2_CORE: length 9.2
  TOP w0.508: 141.77,110.74 142.76,110.74 Q1.3 138.52,109.73 137.79,109 D1.1
SWNODE_CORE: length 9.8
  TOP w0.178: v1(147.86,59.07) 147.84,59.07 147.84,58.15 Q2.3
  LY3 w0.171: v1(146.98,66.06) 146.98,65.98 146.64,65.63 146.64,64.72 146.21,64.29 146.21,62.45 146.8,61.85 146.8,61.38 146.78,61.36 146.78,60.72 147.19,60.31 147.19,59.73 v1(147.86,59.07)
  vias: v1(145.99,65.97) v1(146.56,70.04) v1(147.82,70.05) v1(148.67,66.65) v1(149.1,67.82)
SWNODE_MOT: length 4
  TOP w0.178: 167.95,61.62 166.99,62.58 U15.10
TCK: length 134.2
  TOP w0.178: U11.N24 v2(92.66,87.2) ; J47.5 32.41,14.82 32.83,15.24 32.83,15.64 34.4,17.21 34.4,19.66 32.76,21.3 32.76,34.53 33.79,35.56 35.55,35.56 36.82,36.83 J28.9 37.47,36.19 42.65,36.19 42.66,36.2 43.19,36.2 43.21,36.19 v1(43.78,36.19) 44.22,36.19 44.23,36.2 J32.15
  LY3 w0.102: v2(92.66,87.2) 92.06,86.59 89.36,86.59 89.06,86.29 89.06,86.04 88.83,85.81 88.71,85.81 88.27,85.36 88.27,84.81 88.09,84.64 88.09,84.02 87.84,83.77 87.36,83.77 86.83,83.24 86.83,80.81 85.83,79.81 79.98,79.81
  LY3 w0.171: v1(72.15,40.72) 72.15,50.23 75.83,53.91 75.87,54.14 75.87,57.62 74.87,58.63 74.83,58.63 74.12,59.33 74.12,62.14 72.73,63.54 72.73,68.43 72.65,68.5 72.65,69.37 71.36,70.65 71.36,73.6 71.92,74.16 72.73,74.96 73.71,74.96 73.94,75.18 74.47,75.18 75.19,75.91 75.42,75.91 79.39,79.88 79.69,79.88 79.76,79.81 79.98,79.81
  LY4 w0.171: v1(43.78,36.19) 46.95,36.19 47.13,36.36 47.24,36.36 47.36,36.48 49.82,36.48 53.31,39.97 69.04,39.97 69.79,40.72 v1(72.15,40.72)
  BOTTOM w0.178: R725.1 J28.9
TDI: length 132.7
  TOP w0.178: J32.19 44.35,34.92 44.35,34.93 43.63,34.93 43.23,34.53 43.23,34.38 v1(43.03,34.19) 43.03,34.28 41.88,33.13 41.31,33.13 41.06,32.88 37.96,32.88 J28.5 35.56,30.48 35.56,25.8 37.47,23.89 37.47,21.34 37.16,21.04 37.16,20.23 37.12,20.19 37.12,19.69 37.16,19.65 37.16,17.78 36.61,17.23 36.61,15.14 36.17,14.69 J47.2 ; U11.N25 v2(92.66,88.2)
  LY3 w0.102: 79.69,80.31 79.99,80.6 85.91,80.6 86.56,81.25 86.56,83.25 87.26,83.95 87.26,84.35 87.71,84.81 87.83,84.81 88.06,85.04 88.06,85.75 88.27,85.96 88.27,86.36 88.51,86.6 88.91,86.6 89.11,86.81 91.98,86.81 92.19,87.01 92.19,87.73 v2(92.66,88.2)
  LY3 w0.171: 79.69,80.31 79.21,80.31 75.24,76.34 74.36,76.34 73.41,75.39 72.65,75.39 70.93,73.68 70.93,70.48 72.22,69.19 72.22,68.32 72.29,68.25 72.29,62.26 73.16,61.39 73.16,60.9 72.86,60.61 72.86,58.91 73.58,58.19 74.69,58.19 75.44,57.44 75.44,56.37 75.17,56.1 75.17,53.91 75.16,53.85 71.67,50.36 71.67,41.09 71.55,40.97 71.55,40.47 71.67,40.36 v1(71.67,39.42)
  LY4 w0.171: v1(43.03,34.19) 43.73,34.89 47.6,34.89 48.51,33.99 54.98,33.99 56.96,35.96 68.27,35.96 71.67,39.36 v1(71.67,39.42)
  BOTTOM w0.178: R728.1 J28.5
TDO1: length 126.3
  TOP w0.178: J47.4 v1(33.66,15.55) ; U11.N23 v2(92.66,86.2)
  LY3 w0.102: v2(92.66,86.2) 92.06,85.59 91.5,85.59 91.06,85.15 91.06,84.04 90.83,83.81 90.4,83.81 89.99,83.4 89.37,83.4 89.08,83.11 88.75,83.11 87.82,82.18 87.82,79.75 85.87,77.81 80.48,77.81 79.69,77.02
  LY3 w0.171: 79.69,77.02 79.07,76.4 75.51,72.84 75.51,71.88 75.16,71.53 74.66,71.53 74.31,71.88 74.31,72.29 74.02,72.58 73.74,72.58 73.6,72.44 73.6,71.58 75.9,69.28 75.9,67.97 75.43,67.5 75.43,64.72 76.95,63.2 76.95,61.62 77.88,60.7 77.88,59.73 78.27,59.34 78.27,53.09 76.76,51.58 76.76,45.1 74.57,42.91 74.57,38.83 73.95,38.22 73.87,38.22 73.53,37.87 73.53,37.37 73.55,37.34 73.55,35.46 72.35,34.26 72.35,29.22 72.27,29.14 72.27,28.95 65.67,22.35 65.67,19.77 61.3,15.4 v1(58.33,15.4)
  LY4 w0.171: v1(33.66,15.55) 35.12,14.1 41.45,14.1 41.85,13.7 43.59,13.7 43.77,13.51 44.62,13.51 44.8,13.7 47.67,13.7 48.1,14.13 51.99,14.13 52.3,14.44 54.35,14.44 55.31,15.4 v1(58.33,15.4)
TDO2: length 110.6
  TOP w0.178: J32.11 44.19,37.47 v1(43,38.66) 41.38,40.28 38.46,40.28 J28.13 ; U11.N22 v2(92.66,85.2)
  LY3 w0.102: v2(92.66,85.2) 92.54,85.2 92.06,84.71 91.62,84.71 91.27,84.36 91.27,83.96 90.91,83.6 90.8,83.6 89.78,82.59 88.84,82.59 88.12,81.87 88.12,79.63 86.08,77.59 81.5,77.59 81.09,77.19 81.09,77.02 80.84,76.77 80.2,76.77 79.69,76.26
  LY3 w0.171: v1(74.12,37.62) 75.05,38.55 75.05,42.72 77.19,44.86 77.19,51.41 78.7,52.91 78.7,59.52 78.31,59.9 78.31,60.88 77.51,61.68 77.51,63.25 76.18,64.59 76.18,67.5 76.34,67.66 76.34,69.83 75.79,70.39 75.79,71.55 76.22,71.98 76.22,72.79 79.69,76.26
  LY4 w0.171: v1(74.12,37.62) 74.12,39.89 72.6,41.41 62.13,41.41 61.11,40.4 51.67,40.4 49.9,38.63 48.29,38.63 47.69,38.03 46.41,38.03 45.77,38.66 v1(43,38.66)
  BOTTOM w0.178: R723.1 J28.13
TILT_X: length 130.7
  TOP w0.178: U3.5 v1(178.29,116.33) 178.29,122.49 174.28,126.49 167.23,126.49 164.06,129.66 163.56,129.66 163.32,129.9 162.83,129.9 162.59,129.66 162.03,129.66 161.12,128.76 158.71,128.76 157.47,127.52 154.13,127.52 152.33,125.72 150.71,125.72 150.69,125.75 149.15,125.75 146.76,128.14 146.23,128.14 141.9,123.81 138.96,123.81 138.78,124 137.73,124 137.72,123.99 137.45,123.72 134.86,123.72 134.36,123.21 133.26,123.21 132.9,123.21 132.43,123.21 129.99,123.21 129.73,123.47 129.4,123.8 128.25,124.95 125.12,128.09 122.7,128.09 122.34,128.09 121.11,129.31 118.87,129.31 118.59,129.59 114.07,129.59 113.8,129.31 111.03,129.31 109.12,127.41 105.45,127.41 105.16,127.41 103.91,128.66 102.4,128.66 101.43,127.69 99.42,127.69 98.85,128.26 88.28,128.26 87.59,128.94 86.95,128.94 86.51,128.5 84.68,128.5 83.15,126.97 v1(79.81,126.97)
  LY3 w0.171: v1(75.63,123.08) 75.63,123.13 79.47,126.97 v1(79.81,126.97)
  BOTTOM w0.178: R528.2 v1(75.63,123.08)
TILT_Y: length 162.6
  TOP w0.178: R529.2 87.76,106.5 87.76,107.06 87.38,107.44 83.85,107.44 83.22,108.06 82.92,108.37 82.92,111.95 83.37,112.4 83.37,115.25 82.74,115.87 82.74,117.84 82.94,118.04 82.94,118.33 82.94,119.95 83.31,120.33 83.31,121.48 79.17,125.62 79.17,127.23 79.57,127.63 80.74,127.63 80.98,127.39 82.72,127.39 84.18,128.86 86.35,128.86 86.66,129.17 86.87,129.38 87.66,129.38 87.74,129.3 88.02,129.01 88.34,128.7 99.62,128.7 99.93,129.01 104.06,129.01 105.31,127.76 108.97,127.76 111.16,129.95 121.11,129.95 122.52,128.54 125.3,128.54 125.56,128.28 128.44,125.4 129.85,123.99 130.18,123.66 132.61,123.66 134.17,123.66 134.68,124.16 137.27,124.16 137.62,124.52 138.38,124.52 138.96,125.1 139.5,125.1 140.08,124.52 141.34,124.52 147.81,130.99 185.2,130.99 188.08,128.11 188.08,115.85 187.29,115.06 v1(186.63,115.06) U3.2
TMS1: length 130.2
  TOP w0.178: v2(93.66,88.2) U11.P25 ; J47.3 34.92,12.75 v1(34.99,12.67)
  LY3 w0.102: v2(93.66,88.2) 93.66,88.1 93.29,87.72 93.29,83.42 92.6,82.74 91.45,82.74 90.7,81.99 90.7,80.23 89.81,79.35 89.81,78.59 88.81,77.58 86.95,77.58 85.66,76.29 82.2,76.29 81.27,75.36 81.27,71.03 81.49,70.81 84.9,70.81 85.26,70.45 85.26,69.54 85.06,69.34 85.06,69.04 84.83,68.81 84.53,68.81 84.26,68.54 84.26,66.95 84.06,66.75 84.06,66.04 83.83,65.81 83.5,65.81 83.06,65.36 83.06,65.04 82.83,64.81 82.34,64.81 82.06,64.52 82.06,64.04 81.83,63.81 81.34,63.81 81.06,63.52 81.06,63.04 80.83,62.81 80.51,62.81 79.94,62.23
  LY3 w0.171: v1(59.44,14.1) 61.31,14.1 66.18,18.97 66.18,21.9 72.72,28.44 72.72,28.98 72.78,29.04 72.78,34.08 76.58,37.88 76.58,42.61 78.14,44.17 78.14,51.02 79.93,52.82 79.93,62.23 79.94,62.23
  LY4 w0.171: v1(34.99,12.67) 38.99,8.67 44.36,8.67 48.95,13.26 56.94,13.26 57.77,14.1 v1(59.44,14.1)
TMS2: length 117.8
  TOP w0.102: U11.P26 v2(93.66,89.2)
  TOP w0.178: J28.7 38.1,35.56 v1(42.93,35.56) 43.5,35.56 43.52,35.55 44.05,35.55 44.06,35.56 J32.17
  LY3 w0.102: v2(93.66,89.2) 93.06,88.59 93.06,83.72 92.46,83.12 90.62,83.12 89.36,81.87 89.36,79.2 88.49,78.33 87.28,78.33 86.06,77.11 86.06,76.98 85.63,76.55 82.08,76.55 81.06,75.54 81.06,70.87 81.33,70.59 84.83,70.59 85.06,70.36 85.06,70.04 84.61,69.59 84.5,69.59 84.06,69.15 84.06,67.04 83.61,66.59 83.5,66.59 83.06,66.15 83.06,66.04 82.61,65.59 82.5,65.59 82.27,65.36 82.27,65.25 81.83,64.81 81.71,64.81 81.06,64.15 81.06,64.04 80.71,63.69 80.29,63.69 80.19,63.59 80.19,63.44 79.69,62.94
  LY3 w0.171: 79.69,62.94 79.5,62.75 79.5,52.99 77.7,51.2 77.7,44.54 75.98,42.82 75.98,38.17 v1(74.24,36.44)
  LY4 w0.171: v1(74.24,36.44) 74.15,36.44 73.17,37.42 73.17,38.84 72,40.02 71.2,40.02 68.79,37.61 56.51,37.61 54.95,36.05 47.42,36.05 46.94,35.56 v1(42.93,35.56)
  BOTTOM w0.178: R727.1 J28.7
TRACECLK: length 80.4
  TOP w0.178: J32.6 56.35,39.37 57.33,38.4 64.12,38.4 v1(64.9,39.18)
  LY3 w0.171: v1(64.9,39.18) 64.81,39.09 64.81,38.21 65.21,37.82 66.27,37.82 66.4,37.94 66.4,39.77 66.11,40.06 65.36,40.06 65.01,40.41 65.01,48.72 65.14,48.85 65.57,48.85 65.7,48.72 65.7,40.99 65.82,40.87 66.27,40.87 66.4,40.99 66.4,50.31 66.27,50.43 65.14,50.43 65.01,50.56 65.01,51.12 65.14,51.24 66.27,51.24 66.4,51.37 66.4,51.88 66.27,52.01 65.18,52.01 65.06,52.13 65.06,52.64 65.18,52.77 66.27,52.77 66.4,52.9 66.4,60 66.4,61.82 65.73,62.49 65.73,63.51 65.02,64.23 64.77,64.48 64.77,64.91 65.35,65.49 65.35,65.71 65.94,66.3 65.94,66.8 65.74,67 65.74,67.02 65.74,68.57 66.75,69.58 68.66,69.58 69.12,70.04 v1(69.12,70.36)
  BOTTOM w0.178: RN507.12 73.54,70.36 73.22,70.04 69.28,70.04 69.12,70.2 v1(69.12,70.36)
TRACECLKR: length 12.9
  TOP w0.178: U11.D7 v2(83.66,69.2)
  BOTTOM w0.102: 79.69,66.8 80.79,66.8 80.79,66.8 82.82,66.8 83.06,67.04 83.06,67.52 83.27,67.74 83.27,68.81 v2(83.66,69.2)
  BOTTOM w0.178: 79.69,66.8 79,66.8 78.73,67.07 78.73,67.67 78.73,68 78.45,68.28 78.45,68.81 77.77,69.49 77.24,69.49 76.37,70.36 RN507.5
TRACEPKT0: length 81.7
  TOP w0.178: J32.30 51.44,31.75 50.99,31.31 50.99,24.89 55.94,19.94 56.97,19.94 v1(57.86,19.05) J33.1
  LY3 w0.171: v1(70.89,63.44) 70.37,62.93 70.37,61.04 70.57,60.84 70.57,36.99 70.53,36.99 70.11,36.58 70.11,36.15 70.07,36.11 70.07,34.61 70.11,34.57 70.11,30.14 67.45,27.48 66.37,27.48 62.81,23.93 62.81,21.65 62.05,20.89 61.23,20.89 61.22,20.9 59.64,20.9 59.51,21.03 59.51,21.76 59.39,21.89 57.99,21.89 57.86,21.76 v1(57.86,19.05)
  BOTTOM w0.178: RN508.9 74.02,64.16 73.48,63.62 73.46,63.62 73.12,63.28 71.39,63.28 71.23,63.44 v1(70.89,63.44) 70.57,63.44 70.13,63.88 R659.2
TRACEPKT0R: length 10.7
  TOP w0.178: U11.C2 v2(82.66,64.2)
  BOTTOM w0.102: 80.13,62.23 80.21,62.32 80.21,62.75 80.13,62.84 80.13,63.22 80.5,63.59 82.06,63.59 v2(82.66,64.2)
  BOTTOM w0.178: 80.13,62.23 79.9,62.01 77.22,62.01 75.72,63.51 RN508.8
TRACEPKT1: length 81.2
  TOP w0.178: J33.2 v1(60.64,21.59) 58.36,21.59 56.71,23.24 56.71,31.11 56.65,31.17 56.65,31.19 55.38,32.46 53.61,32.46 53.53,32.38 J32.28
  LY3 w0.171: v1(69.66,64.77) 69.25,64.36 69.25,36.5 69.21,36.46 69.21,34.25 69.25,34.21 69.25,30.5 67.1,28.35 64.02,28.35 61.88,26.21 58.61,26.21 58.48,26.08 58.48,25.21 58.61,25.08 60.41,25.08 60.74,24.75 60.74,21.69 v1(60.64,21.59)
  BOTTOM w0.178: R658.2 v1(69.66,64.77) 69.99,64.43 70.97,64.43 71.6,63.8 72.87,63.8 73.13,64.06 73.13,64.61 73.44,64.92 RN508.10
TRACEPKT1R: length 11.8
  TOP w0.178: U11.D3 v2(83.66,65.2)
  BOTTOM w0.102: v2(83.66,65.2) 83.66,65.14 83.45,64.93 82.95,64.93 82.83,64.81 82.71,64.81 82.27,64.36 82.27,64.25 81.83,63.81 80.28,63.81 79.91,63.44 79.91,62.75 79.69,62.53
  BOTTOM w0.178: RN508.7 76.06,64.92 76.11,64.87 76.19,64.87 76.37,64.7 76.37,64.62 76.4,64.58 76.4,63.74 77.6,62.53 79.69,62.53
TRACEPKT2: length 80.7
  TOP w0.178: J32.26 55.82,33.02 57.29,31.55 57.29,24.43 v1(57.59,24.13) J33.3
  LY3 w0.171: v1(68.64,65.66) 68.81,65.49 68.81,62.28 68.81,36.68 68.78,36.64 68.78,34.08 68.81,34.04 68.81,30.67 66.92,28.78 63.84,28.78 61.7,26.64 53.66,26.64 53.54,26.51 53.54,24.56 53.66,24.43 57.29,24.43 v1(57.59,24.13)
  BOTTOM w0.178: RN508.11 73.09,65.42 73.05,65.38 72.2,65.38 72.2,65.35 71.82,64.98 70.92,64.98 70.53,65.38 70.1,65.38 69.85,65.63 68.68,65.63 v1(68.64,65.66) R657.2
TRACEPKT2R: length 14.1
  TOP w0.178: U11.E6 v2(84.66,68.2)
  BOTTOM w0.102: 78.99,64.03 79.49,64.03 80.05,64.59 82,64.59 82.27,64.86 82.27,65.36 82.5,65.59 83.17,65.59 83.27,65.69 83.27,66.39 83.59,66.72 83.99,66.72 84.27,66.99 84.27,67.36 84.66,67.76 v2(84.66,68.2)
  BOTTOM w0.178: RN508.6 76.17,65.42 76.26,65.33 76.38,65.33 76.82,64.88 76.82,64.8 76.97,64.65 76.97,64.04 77.65,63.36 78.32,63.36 78.99,64.03
TRACEPKT3: length 80.8
  TOP w0.178: 63.02,26.67 59.04,26.67 58,27.71 58,31.57 55.92,33.66 52.43,33.66 ; 63.02,26.67 J33.4 ; 63.02,26.67 v1(63.02,25.39)
  LY3 w0.171: v1(69.66,66.51) 69.66,66.55 70.26,65.95 70.26,64.23 69.94,63.92 69.94,37.1 69.68,36.84 69.68,36.33 69.64,36.29 69.64,34.43 69.68,34.39 69.68,30.32 67.28,27.91 64.25,27.91 63.81,27.48 63.81,27.41 63.17,26.77 63.05,26.77 61.96,25.68 61.41,25.68 61.28,25.55 61.28,21.45 61.41,21.32 61.86,21.32 61.99,21.45 61.99,24.82 62.11,24.95 62.57,24.95 v1(63.02,25.39)
  BOTTOM w0.178: RN508.12 72.85,65.92 72.83,65.9 70.31,65.9 69.66,66.55 v1(69.66,66.51) 69.62,66.55 R656.2
TRACEPKT3R: length 13
  TOP w0.178: U11.D5 v2(83.66,67.2)
  LY3 w0.102: 79.69,65.8 81.86,65.8 82.27,66.21 82.27,66.36 82.5,66.59 83.06,66.59 v2(83.66,67.2)
  LY3 w0.171: v1(78.45,64.68) 77.71,64.68 77.5,64.89 77.5,65.72 77.91,66.13 79.36,66.13 79.69,65.8
  BOTTOM w0.178: RN508.5 76.4,65.92 76.45,65.86 76.45,65.86 76.5,65.82 76.58,65.82 77.31,65.09 77.31,65.01 77.64,64.68 v1(78.45,64.68)
TRACEPKT4: length 80.8
  TOP w0.178: v1(62.36,29.21) J33.5 59.56,29.65 59.56,30.42 59.58,30.44 59.58,31.45 58.57,32.46 57.85,32.46 56.02,34.29 J32.22
  LY3 w0.171: v1(62.36,29.21) 62.36,28.79 61.31,27.75 55.19,27.75 55.06,27.62 55.06,27.2 55.19,27.07 61.52,27.07 63.14,28.69 63.14,28.91 63.44,29.21 66.74,29.21 68.38,30.85 68.38,33.86 68.35,33.9 68.35,36.82 68.38,36.85 68.38,59.18 68.38,64.92 67.97,65.33 67.97,66.77 v1(68.64,67.44)
  BOTTOM w0.178: RN508.13 72.4,66.42 72.04,66.78 71.78,66.78 71.72,66.72 70.81,66.72 70.75,66.78 70.59,66.78 70.19,67.18 70.03,67.18 69.76,67.44 68.65,67.44 v1(68.64,67.44) R655.2
TRACEPKT4R: length 13.5
  TOP w0.178: U11.E7 v2(84.66,69.2)
  BOTTOM w0.102: 78.99,65.37 79.18,65.37 79.75,64.81 81.83,64.81 82.06,65.04 82.06,65.44 82.42,65.8 82.87,65.8 83.07,65.99 83.07,66.48 83.27,66.68 83.27,67.36 83.5,67.59 83.51,67.59 83.55,67.63 83.84,67.63 84.07,67.86 84.07,68.48 84.38,68.79 84.38,68.92 v2(84.66,69.2)
  BOTTOM w0.178: 78.99,65.37 77.7,65.37 76.66,66.42 RN508.4
TRACEPKT5: length 81.1
  TOP w0.178: J32.20 56.13,34.92 57.74,33.32 60.73,33.32 61.09,32.96 61.09,31.69 ; J33.6 61.15,31.75 61.09,31.69 ; 61.09,31.69 v1(60.71,31.31)
  LY3 w0.171: v1(60.71,31.31) 59.56,30.16 57.8,30.16 57.67,30.04 57.67,29.49 57.8,29.36 60.16,29.36 60.43,29.63 60.43,30.11 61.63,31.31 61.74,31.31 62.04,31.6 62.04,34.77 62.17,34.9 63.36,34.9 63.48,34.77 63.48,30.72 63.93,30.28 66.43,30.28 67.52,31.36 67.52,33.51 67.48,33.54 67.48,37.18 67.52,37.21 67.52,59.54 67.52,63.97 66.89,64.59 66.89,65.68 67.06,65.84 67.06,67.38 68.14,68.47 69.48,68.47 69.59,68.35 69.76,68.35 v1(70.29,67.82)
  BOTTOM w0.178: RN508.14 72.81,66.92 72.37,67.36 71.67,67.36 71.52,67.21 71.01,67.21 70.8,67.42 70.69,67.42 v1(70.29,67.82)
TRACEPKT5R: length 11.7
  TOP w0.178: U11.C4 v2(82.66,66.2)
  LY3 w0.102: 78.99,63.76 80.27,65.03 80.27,65.36 80.5,65.59 82.06,65.59 v2(82.66,66.2)
  LY3 w0.171: 78.99,63.76 78.87,63.63 77.84,63.63 77.01,64.46 v1(77.01,66.92)
  BOTTOM w0.178: RN508.3 v1(77.01,66.92)
TRACEPKT6: length 80.9
  TOP w0.178: J32.18 56.26,35.56 57.47,34.35 59.94,34.35 J33.7 v1(62.87,34.29)
  LY3 w0.171: v1(62.87,34.29) 62.87,30.95 62.5,30.58 61.61,30.58 60.87,29.85 60.87,29.29 60.5,28.92 56.41,28.92 56.28,28.79 56.28,28.34 56.41,28.21 61,28.21 61.61,28.82 61.61,29.62 61.9,29.92 62.87,29.92 62.99,29.79 66.63,29.79 67.95,31.11 67.95,33.69 67.91,33.72 67.91,37 67.95,37.03 67.95,59.36 67.95,64.48 67.46,64.96 67.46,65.63 67.49,65.66 67.49,67.2 68.32,68.03 69.3,68.03 69.7,67.64 69.7,67.57 70.04,67.22 70.11,67.22 70.58,66.75 70.96,66.75 71.23,67.02 71.23,67.78 v1(71.26,67.82)
  BOTTOM w0.178: RN508.15 73.05,67.42 72.65,67.82 v1(71.26,67.82)
TRACEPKT6R: length 10.4
  TOP w0.178: U11.B4 v2(81.66,66.2)
  BOTTOM w0.102: v2(81.66,66.2) 82.05,66.2 82.22,66.03 82.22,65.89 81.92,65.59 80.48,65.59 80.3,65.41 80.14,65.41 80,65.55 80,65.97 79.69,66.28
  BOTTOM w0.178: RN508.2 76.6,67.42 76.92,67.73 77.33,67.73 77.65,67.41 77.65,67.12 77.98,66.8 77.98,66.19 78.28,65.89 79.11,65.89 79.49,66.28 79.69,66.28
TRACEPKT7: length 80.3
  TOP w0.178: v1(65.79,36.77) 65.72,36.83 J33.8 63.12,36.89 60.58,36.89 59.88,36.2 J32.16
  LY3 w0.171: v1(70.71,69.02) 70.62,68.93 68.98,68.93 68.95,68.9 67.97,68.9 66.62,67.56 66.62,66.02 66.38,65.78 66.38,64.48 67.08,63.78 67.08,61.57 67.08,37.39 67.05,37.36 67.05,33.36 67.08,33.33 67.08,31.59 66.37,30.87 64.15,30.87 64.02,31 64.02,31.47 64.2,31.64 65.85,31.64 66.03,31.82 66.03,32.15 65.85,32.33 64.2,32.33 64.02,32.51 64.02,32.84 64.2,33.02 65.85,33.02 66.03,33.19 66.03,33.52 65.85,33.7 64.2,33.7 64.02,33.88 64.02,34.21 64.2,34.39 65.85,34.39 66.03,34.57 66.03,34.9 65.85,35.07 64.2,35.07 64.02,35.25 64.02,36.64 64.15,36.77 v1(65.79,36.77)
  BOTTOM w0.178: v1(70.71,69.02) 71.07,68.67 72.7,68.67 73.45,67.92 RN508.16
TRACEPKT7R: length 12.5
  TOP w0.178: U11.E8 v2(84.66,70.2)
  LY3 w0.171: v1(77.51,68.53) 77.37,68.67 77.37,69.32 77.33,69.37 77.33,70.03 77.91,70.62 78.98,70.62 79.88,69.71 84.17,69.71 v2(84.66,70.2)
  BOTTOM w0.178: RN508.1 76.35,67.92 76.96,68.53 v1(77.51,68.53)
TRACESYNC: length 80.9
  TOP w0.178: J32.32 55.82,31.11 v1(56.01,30.92)
  LY3 w0.171: v1(68.19,70.86) 68.1,70.78 67.12,70.78 66.61,70.27 66.46,70.27 65.05,68.86 65.05,67.31 64.08,66.34 64.08,66.2 63.83,65.95 63.83,64.45 64.34,63.94 64.34,63.09 64.92,62.51 64.92,62.33 65.71,61.54 65.71,61 65.71,53.84 65.33,53.46 64.9,53.46 64.33,52.88 64.33,41.04 64.2,40.91 63.77,40.91 63.64,41.04 63.64,49.97 63.46,50.14 63.13,50.14 62.95,49.97 62.95,40.22 63.08,40.09 64.2,40.09 64.33,39.96 64.33,39.58 64.12,39.38 64.12,39.22 63.96,39.05 63.96,37.6 63.41,37.05 63.41,35.77 63.01,35.37 60.8,35.37 60.25,34.82 60.25,32.37 58.8,30.92 v1(56.01,30.92)
  BOTTOM w0.178: v1(68.19,70.86) 68.72,70.86 68.86,71 69.39,71 69.52,70.86 70.06,70.86 70.26,70.67 73.04,70.67 73.24,70.86 RN507.13
TRACESYNCR: length 10.4
  TOP w0.178: U11.A5 v2(80.66,67.2)
  LY3 w0.171: v2(80.66,67.2) 78.71,67.2 78.13,67.78 78.13,68.65 78.3,68.83 79.15,68.83 79.37,69.05 79.37,69.42 79.1,69.69 v1(78.61,69.69)
  BOTTOM w0.178: v1(78.61,69.69) 78.11,70.19 77.63,70.19 76.96,70.86 RN507.4
TRSTZ: length 127.1
  TOP w0.178: U11.M23 v2(91.66,86.2) ; J32.21 v1(44.08,34.29) ; J47.1 37.41,16.58 v1(37.55,16.72)
  LY3 w0.102: 79.69,78.24 80.26,78.81 85.88,78.81 87.29,80.22 87.29,82.87 87.79,83.36 88.01,83.36 88.21,83.56 88.93,83.56 89.17,83.81 89.83,83.81 90.06,84.04 90.06,84.36 89.83,84.59 89.6,84.59 89.27,84.92 89.27,85.37 89.67,85.78 90.93,85.78 91.36,86.2 v2(91.66,86.2)
  LY3 w0.171: v1(71.88,35.36) 72.38,35.87 72.38,38.2 73.04,38.85 73.04,38.86 73.52,39.34 73.52,49.6 77.25,53.33 77.25,58.33 77.4,58.49 77.4,58.98 77.05,59.33 76.8,59.33 75.83,60.3 75.83,61.2 76.02,61.39 76.02,62.45 75.31,63.16 75.31,63.61 74.1,64.82 74.1,69.86 72.73,71.22 72.73,73.03 73.29,73.59 74.28,73.59 74.5,73.81 75.26,73.81 76.37,74.92 78.21,76.76 79.69,78.24
  LY4 w0.171: v1(44.08,34.29) 44.82,33.55 56.26,33.55 58.06,35.36 v1(71.88,35.36)
  BOTTOM w0.178: v1(37.55,16.72) 37.55,18.41 42.94,23.81 42.94,26.34 43.58,26.97 U516.4 ; v1(44.08,34.29) 43.09,33.3 43.09,32.3 44.08,31.31 U516.4 ; U516.4 44.09,26.99 R733.1
TRSTZ_IN: length 8.5
  BOTTOM w0.178: J28.3 R729.1 38.85,26.54 39.57,25.82 R734.2 39.59,25.1 U516.1
UART0_CTSZ: length 79
  TOP w0.178: v1(190.46,100.27) 189.41,101.32 U6.12 ; v1(140.02,87.19) 138.55,88.66 133.93,88.66 133.13,87.86 131.36,87.86 131.07,87.57 U9.2
  LY4 w0.171: v1(140.02,87.19) 147.11,87.19 148.04,88.13 164.09,88.13 176.91,100.95 183.61,100.95 186.34,103.68 191.19,103.68 192.93,101.94 192.93,101.07 192.13,100.27 v1(190.46,100.27)
UART0_CTSZ_BUF: length 78.3
  TOP w0.178: v1(129.64,83.04) 130.26,83.04 130.42,82.88 U9.6 ; U11.AE2 v2(105.66,64.2)
  LY3 w0.171: v1(127.06,59.91) 127.06,61.23 127.11,61.28 127.11,62.13 127.06,62.17 127.06,64.48 127.62,65.04 127.62,67.97 126.77,68.82 126.77,74.38 126.86,74.48 127.07,74.68 127.07,74.87 127.42,75.22 127.61,75.22 127.82,75.43 127.95,75.56 133.28,75.56 133.77,76.06 133.77,79.58 132.87,80.48 132.12,80.48 129.66,82.94 129.66,83.01 v1(129.64,83.04)
  LY4 w0.102: 107.63,64.03 106.97,64.69 106.16,64.69 v2(105.66,64.2)
  LY4 w0.171: 107.63,64.03 107.7,64.03 109.16,62.57 109.16,62.39 109.06,62.29 109.06,60.91 109.16,60.8 109.16,59.89 109.09,59.82 109.09,56.68 108.9,56.5 108.07,56.5 107.51,55.94 107.51,54.83 107.15,54.47 107.15,52.6 108.72,51.03 121.51,51.03 122.19,51.71 122.19,56.98 125.25,60.04 126.63,60.04 126.76,59.91 v1(127.06,59.91)
UART0_CTSZ_CON: length 14.4
  TOP w0.178: v1(195.24,107.69) 197.65,107.69 J10.7 ; v1(190.54,101.39) 190.06,101.87 U6.13
  BOTTOM w0.178: v1(195.24,107.69) 193.64,107.69 191.93,105.98 191.14,105.98 190.04,104.88 190.04,101.89 190.54,101.39 v1(190.54,101.39)
UART0_DCD_CON: length 3.7
  TOP w0.178: J10.1 194.25,111.84 R12.1
UART0_DSR_CON: length 9.7
  TOP w0.178: R13.2 v1(194.06,105.35) ; v1(194.06,109.79) R12.2 195.24,110.6 195.39,110.45 J10.6
  LY3 w0.171: v1(194.06,105.35) v1(194.06,109.79)
UART0_DTR_CON: length 3.6
  TOP w0.178: R13.1 194.09,103.53 J10.4
UART0_RSTZ_CON: length 10.8
  TOP w0.178: U6.14 190.71,103.85 190.38,104.18 190.38,104.18 190.18,104.38 190.18,105.21 190.67,105.71 193.19,105.71 193.66,106.18 194.32,106.18 195.58,104.91 J10.8
UART0_RTSZ: length 87.5
  TOP w0.178: v1(133.92,83.12) 134.22,82.83 U10.5 ; U11.AD2 v2(104.66,64.2)
  LY3 w0.171: v1(133.92,83.12) 133.34,82.54 130.66,82.54 130.31,82.9 130.31,83.25 129.79,83.77 129.53,83.77 128.81,83.05 128.81,82.39 132.68,78.53 132.68,76.72 132.07,76.12 128,76.12 127.46,75.58 127.27,75.58 126.72,75.02 126.72,74.83 126.24,74.35 126.24,73.28 126.32,73.19 126.32,68.55 127.1,67.78 127.1,65.52 126.51,64.93 126.51,62.11 126.68,61.95 126.68,61.45 126.47,61.24 126.47,59.24 v1(126.99,58.72)
  LY4 w0.102: v2(104.66,64.2) 104.66,64.19 105.15,63.7 107.53,63.7 107.63,63.6
  LY4 w0.171: 107.63,63.6 108.75,62.48 108.7,62.43 108.7,60.76 108.81,60.65 108.81,60.04 108.73,59.96 108.73,57.66 107.15,56.08 107.15,55.01 106.8,54.65 106.8,52.15 109.4,49.55 117.36,49.55 118.41,50.6 121.95,50.6 122.36,50.19 122.91,50.19 123.26,50.54 123.26,51.07 122.71,51.62 122.71,56.88 125.39,59.57 126.14,59.57 v1(126.99,58.72)
UART0_RTSZ_BUF: length 94.1
  TOP w0.178: v1(186.05,100.1) 187.24,100.1 188.76,101.62 U6.11 ; U10.3 v1(134.87,84.57)
  LY3 w0.171: v1(177.48,74.04) 177.48,78.79 176.76,79.51 176.76,82.38 184.81,90.42 184.81,98.86 v1(186.05,100.1)
  LY4 w0.171: v1(134.87,84.57) 136.63,84.57 138.84,82.36 138.84,79.88 139.24,79.49 147.33,79.49 150.72,82.88 156.98,82.88 160.07,79.79 166.15,79.79 167.12,80.77 170.75,80.77 v1(177.48,74.04)
  BOTTOM w0.178: R542.2 188.8,102.3 188.8,102.21 188.76,102.17 188.76,101.62 187.24,100.1 v1(186.05,100.1) ; R617.1 v1(177.48,74.04)
UART0_RXD: length 118
  TOP w0.178: U9.5 v1(128.8,81.56) ; U6.9 187.46,104.03 187.08,104.41 v1(187.08,104.44)
  LY3 w0.171: v1(192.41,72.35) 192.41,72.8 188.45,76.76 188.45,78.77 188.92,79.24 189.14,79.24 190.74,80.84 190.74,86.41 189.88,87.27 187.22,87.27 186.45,88.04 186.45,88.9 186.74,89.18 186.74,93.63 189.36,96.25 189.36,102.29 187.82,103.84 187.68,103.84 v1(187.08,104.44)
  LY4 w0.171: v1(128.8,81.56) 132.36,78 157.47,78 157.54,77.93 165.49,77.93 170.19,73.23 176.84,73.23 177.06,73.01 177.91,73.01 178.13,73.23 181.67,73.23 183.76,75.32 184.59,75.32 186.18,76.92 191.97,76.92 193.64,75.25 193.64,74.2 192.41,72.98 v1(192.41,72.35)
  BOTTOM w0.178: R613.1 192.15,72.14 192.41,72.4 v1(192.41,72.35)
UART0_RXD_BUF: length 78.6
  TOP w0.178: v1(129.98,87.57) 130.42,87.13 U9.3 ; U11.AD1 v2(104.66,63.2)
  LY3 w0.171: v1(125.74,58.65) 125.76,58.65 125.76,61.18 125.48,61.45 125.48,65.09 125.2,65.38 125.2,67.01 125.16,67.01 124.8,67.37 124.8,67.86 125.15,68.21 125.2,68.21 125.2,68.58 125.45,68.84 125.45,70 125.6,70.15 125.6,71.68 125.53,72.19 125.53,72.98 125.52,72.98 125.52,74.75 126,75.22 126,75.31 127.11,76.42 127.11,78.74 126.85,79.01 126.57,79.28 126.57,79.28 125.79,80.06 125.79,80.85 125.94,81 125.94,82.02 129.98,86.06 v1(129.98,87.57)
  LY4 w0.102: 107.63,62.7 107.52,62.81 106.83,62.81 105.5,62.81 105.11,63.2 v2(104.66,63.2)
  LY4 w0.171: 107.63,62.7 107.9,62.43 107.9,60.83 107.46,60.38 107.46,56.89 106.44,55.88 106.44,52 109.33,49.12 119.59,49.12 120.64,50.17 121.77,50.17 122.18,49.76 123.03,49.76 123.63,50.36 123.63,51.21 123.14,51.71 123.14,56 124.48,57.34 124.49,57.34 125.76,58.61 125.76,58.62 125.77,58.62 125.77,58.65 v1(125.74,58.65)
UART0_RXD_CON: length 12.6
  TOP w0.178: U6.8 187.46,107.85 188.03,107.28 188.03,107.01 188.71,106.33 188.98,106.33 189.01,106.3 192.8,106.3 193.28,106.78 194.87,106.78 195.35,106.3 J10.3
UART0_TXD: length 86.6
  TOP w0.178: U11.AB3 v2(102.66,65.2) ; U10.2 v1(135.52,87.56)
  LY3 w0.171: v1(135.52,87.56) 133.11,87.56 131.2,85.64 130.18,85.64 126.3,81.76 126.3,80.85 126.15,80.7 126.15,80.21 126.51,79.85 127.22,79.85 127.22,79.85 127.6,80.23 128.31,80.23 129.11,79.42 129.11,77.92 127.2,76.01 127.2,75.93 127.13,75.93 126.36,75.17 126.36,75.08 125.88,74.6 125.88,73.13 125.89,73.12 125.89,72.2 125.96,71.71 125.96,70 125.89,69.93 125.89,68.38 126.66,67.6 126.66,66.26 126.08,65.67 v1(126.08,61.7)
  LY4 w0.102: 107.63,65.1 107.02,65.71 103.17,65.71 v2(102.66,65.2)
  LY4 w0.171: 107.63,65.1 109.53,63.2 109.53,63.15 109.89,62.79 109.89,61.2 110.55,60.54 110.55,55.72 109.72,54.88 108.07,54.88 107.51,54.33 107.51,53.54 108.65,52.4 108.65,51.72 108.9,51.46 121.33,51.46 121.76,51.89 121.76,57.16 125.49,60.88 125.49,61.11 v1(126.08,61.7)
UART0_TXD_BUF: length 68.4
  TOP w0.178: U6.10 188.11,101.88 v1(187.77,101.54) ; v1(139.49,80.08) 139.32,80.08 139.24,80.16 137.93,80.16 137.86,80.08 135.33,80.08 134.87,80.54 U10.6
  LY4 w0.171: v1(139.49,80.08) 141.98,80.08 142.01,80.05 142.51,80.05 142.54,80.08 144.35,80.08 148.82,84.55 151.13,84.55 153.27,86.7 162.38,86.7 163.1,85.97 163.88,85.97 164.6,86.7 167.95,86.7 169.18,85.47 170.15,85.47 179.8,95.12 182.72,95.12 187.77,100.17 v1(187.77,101.54)
  BOTTOM w0.178: R543.1 187.77,102.16 v1(187.77,101.54)
UART0_TXD_CON: length 12.1
  TOP w0.178: U6.7 188.11,108.04 188.55,107.6 188.55,107.22 188.93,106.85 189.46,106.85 189.51,106.9 192.39,106.9 194.56,109.07 J10.2
UART1_CTSZ: length 118.7
  TOP w0.178: U11.E18 v2(84.66,81.2) ; v1(140.35,71.73) 140.24,71.62 138.07,71.62 v1(137.8,71.88) ; U12.12 189.79,68.06 v1(189.23,67.5)
  LY4 w0.102: v2(84.66,81.2) 84.8,81.2 85.4,80.59 85.83,80.59 85.92,80.5 86.04,80.5 86.89,79.65 86.89,78.75 89.86,75.78 96.75,75.78 98.34,74.2 98.43,74.2 99.82,72.81 107.52,72.81 107.63,72.7
  LY4 w0.171: 107.63,72.7 108.06,72.27 114.03,72.27 114.24,72.48 114.74,72.48 114.95,72.27 117.43,72.27 118.08,71.62 132.55,71.62 133.5,72.57 135.48,72.57 136.2,71.85 137.77,71.85 v1(137.8,71.88) ; v1(189.23,67.5) 189.23,66.91 187.75,65.43 178.46,65.43 174.81,69.08 164.9,69.08 163.35,70.62 161.41,70.62 160.77,71.26 160.21,71.26 159.92,70.97 158.23,70.97 157.6,71.59 156.57,71.59 156.12,72.05 154.11,72.05 153.62,71.56 148.62,71.56 148.49,71.69 147.14,71.69 145.88,71.68 145.76,71.56 140.52,71.56 v1(140.35,71.73)
UART1_CTSZ_CON: length 10.3
  TOP w0.178: J21.7 197.61,75.12 194.26,75.12 193.31,74.16 193.05,73.9 193.05,73.84 192.61,73.41 191.33,73.41 190.44,72.52 U12.13
UART1_DCD_CON: length 3.3
  TOP w0.178: R21.1 194.63,79.33 J21.1
UART1_DSR_CON: length 10.8
  TOP w0.178: v1(195.25,71.73) 194.96,72.02 R22.2 ; R21.2 194.73,77.8 v1(195.25,77.8) 197.52,77.8 J21.6
  LY3 w0.171: v1(195.25,77.8) 195.73,77.32 195.73,73.73 195.25,73.25 195.25,71.73 v1(195.25,71.73)
